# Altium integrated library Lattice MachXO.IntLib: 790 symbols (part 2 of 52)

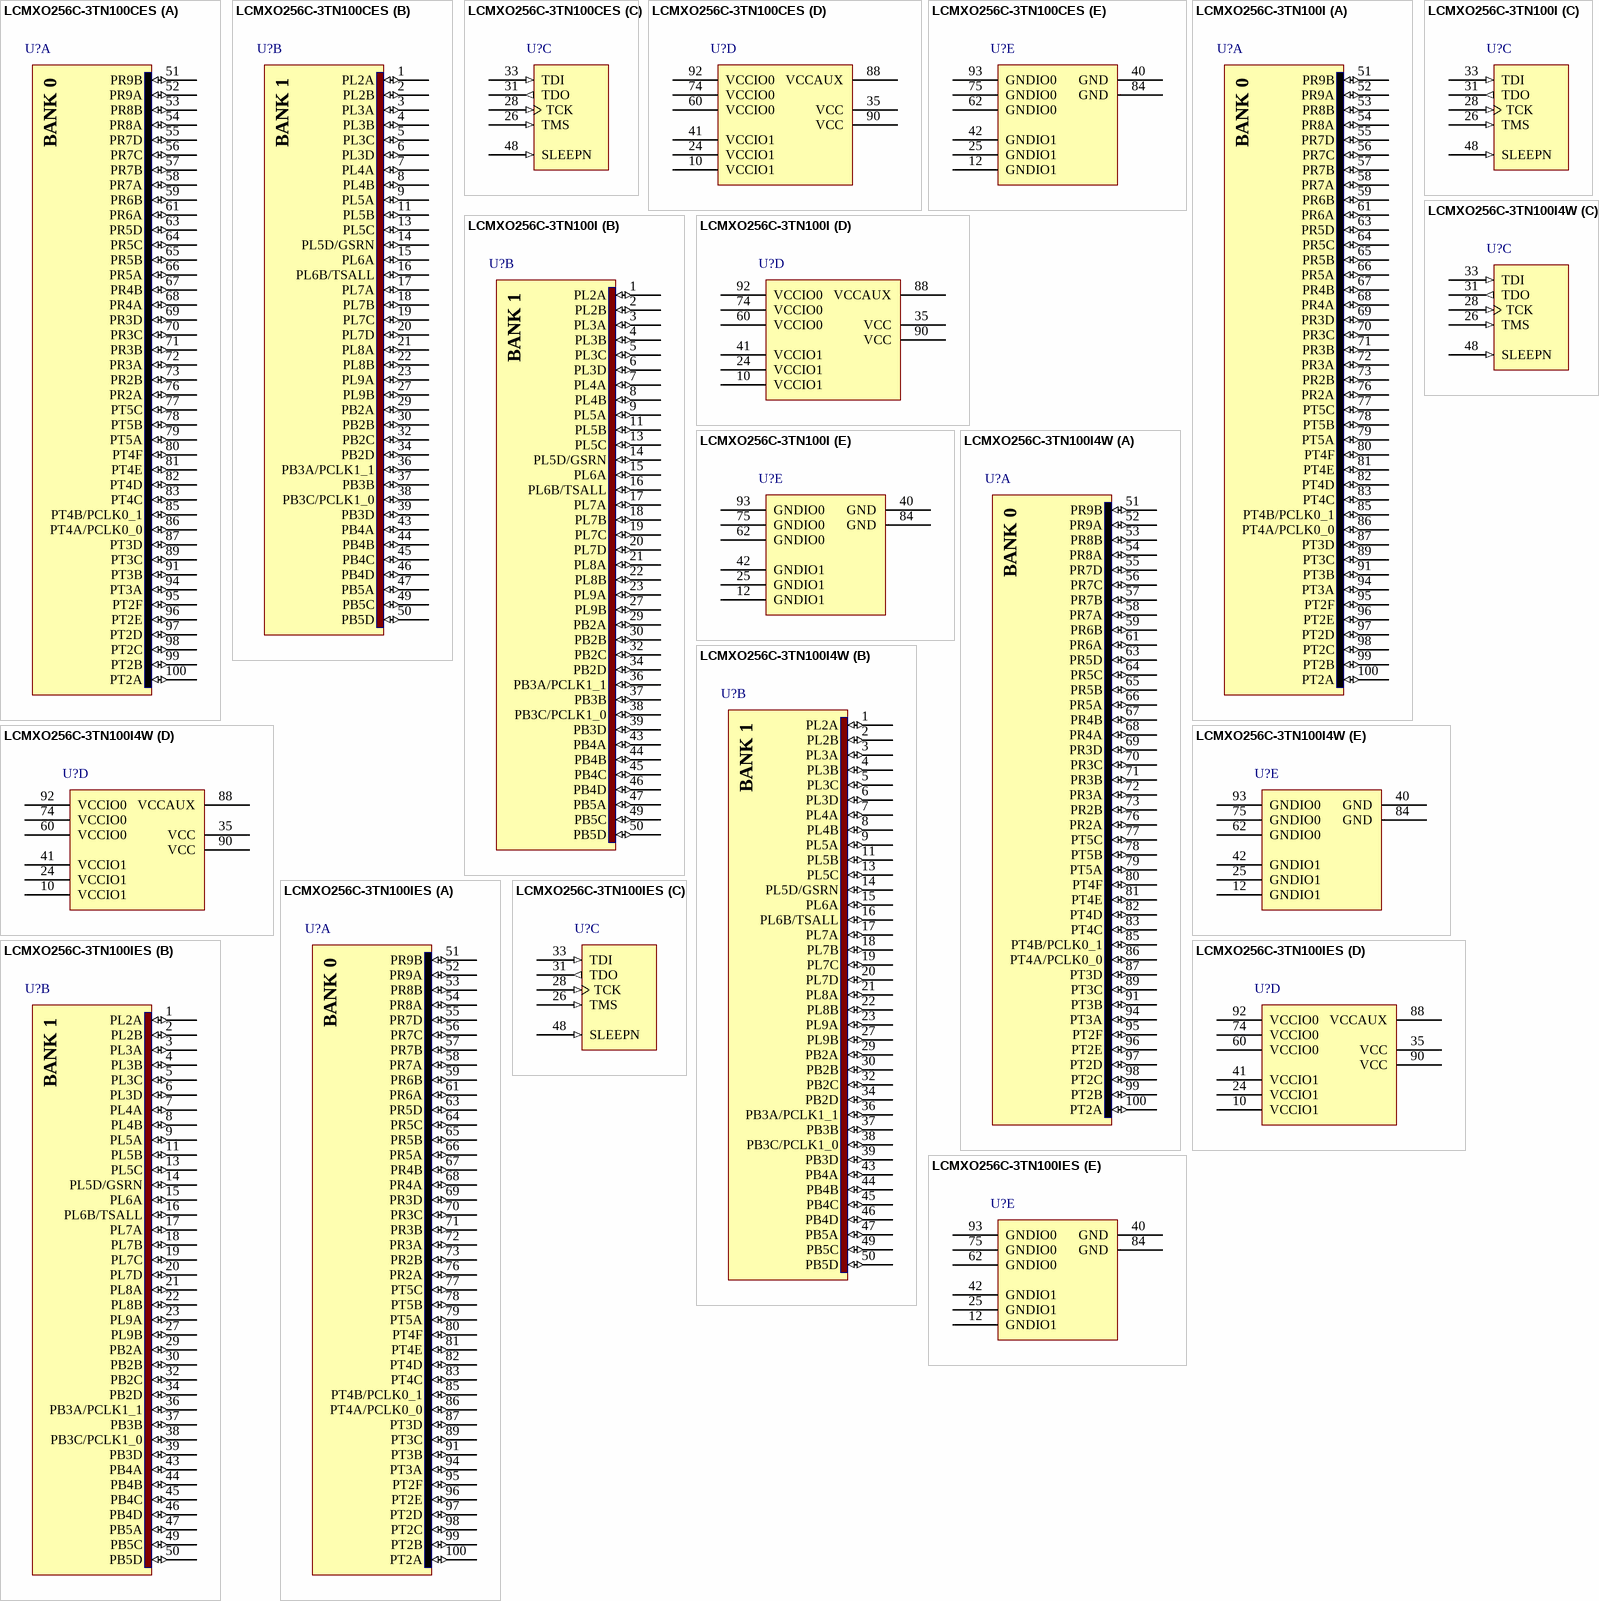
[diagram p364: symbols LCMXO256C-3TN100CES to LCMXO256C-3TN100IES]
## LCMXO256C-3TN100IES
designator U?
MachXO 256 Crossover PLD, 1.8V/2.5V/3.3V, 78 User I/Os, 100-Pins TQFP, Speed Grade-3, Industrial Grade, Pb-Free, Engineering Sample
footprint TQFP100_N (Thin QFP, 100-Leads, Body 14x14mm, Pitch 0.5mm, IPC Medium Density)
footprint TQFP100_L (Thin QFP, 100-Leads, Body 14x14mm, Pitch 0.5mm, IPC High Density)
footprint TQFP100_M (Thin QFP, 100-Leads, Body 14x14mm, Pitch 0.5mm, IPC Low Density)
3D model MachXO256-TQFP100 (100-Pin Thin Quad Flat Pack (TQFP100))
signal-integrity model LCMXO256C_T100 (MachXO)
part A pins: 51 PR9B (io), 52 PR9A (io), 53 PR8B (io), 54 PR8A (io), 55 PR7D (io), 56 PR7C (io), 57 PR7B (io), 58 PR7A (io), 59 PR6B (io), 61 PR6A (io), 63 PR5D (io), 64 PR5C (io), 65 PR5B (io), 66 PR5A (io), 67 PR4B (io), 68 PR4A (io), 69 PR3D (io), 70 PR3C (io), 71 PR3B (io), 72 PR3A (io), 73 PR2B (io), 76 PR2A (io), 77 PT5C (io), 78 PT5B (io), 79 PT5A (io), 80 PT4F (io), 81 PT4E (io), 82 PT4D (io), 83 PT4C (io), 85 PT4B/PCLK0_1 (io), 86 PT4A/PCLK0_0 (io), 87 PT3D (io), 89 PT3C (io), 91 PT3B (io), 94 PT3A (io), 95 PT2F (io), 96 PT2E (io), 97 PT2D (io), 98 PT2C (io), 99 PT2B (io), 100 PT2A (io)
part B pins: 1 PL2A (io), 2 PL2B (io), 3 PL3A (io), 4 PL3B (io), 5 PL3C (io), 6 PL3D (io), 7 PL4A (io), 8 PL4B (io), 9 PL5A (io), 11 PL5B (io), 13 PL5C (io), 14 PL5D/GSRN (io), 15 PL6A (io), 16 PL6B/TSALL (io), 17 PL7A (io), 18 PL7B (io), 19 PL7C (io), 20 PL7D (io), 21 PL8A (io), 22 PL8B (io), 23 PL9A (io), 27 PL9B (io), 29 PB2A (io), 30 PB2B (io), 32 PB2C (io), 34 PB2D (io), 36 PB3A/PCLK1_1 (io), 37 PB3B (io), 38 PB3C/PCLK1_0 (io), 39 PB3D (io), 43 PB4A (io), 44 PB4B (io), 45 PB4C (io), 46 PB4D (io), 47 PB5A (io), 49 PB5C (io), 50 PB5D (io)
part C pins: 26 TMS (in) "Powered by VCCIO1", 28 TCK (in) "Powered by VCCIO1", 31 TDO (out) "Powered by VCCIO1", 33 TDI (in) "Powered by VCCIO1", 48 SLEEPN (in) "Powered by VCCIO1"
part D pins: 10 VCCIO1 (power), 24 VCCIO1 (power), 35 VCC (power), 41 VCCIO1 (power), 60 VCCIO0 (power), 74 VCCIO0 (power), 88 VCCAUX (power), 90 VCC (power), 92 VCCIO0 (power)
part E pins: 12 GNDIO1 (power), 25 GNDIO1 (power), 40 GND (power), 42 GNDIO1 (power), 62 GNDIO0 (power), 75 GNDIO0 (power), 84 GND (power), 93 GNDIO0 (power)


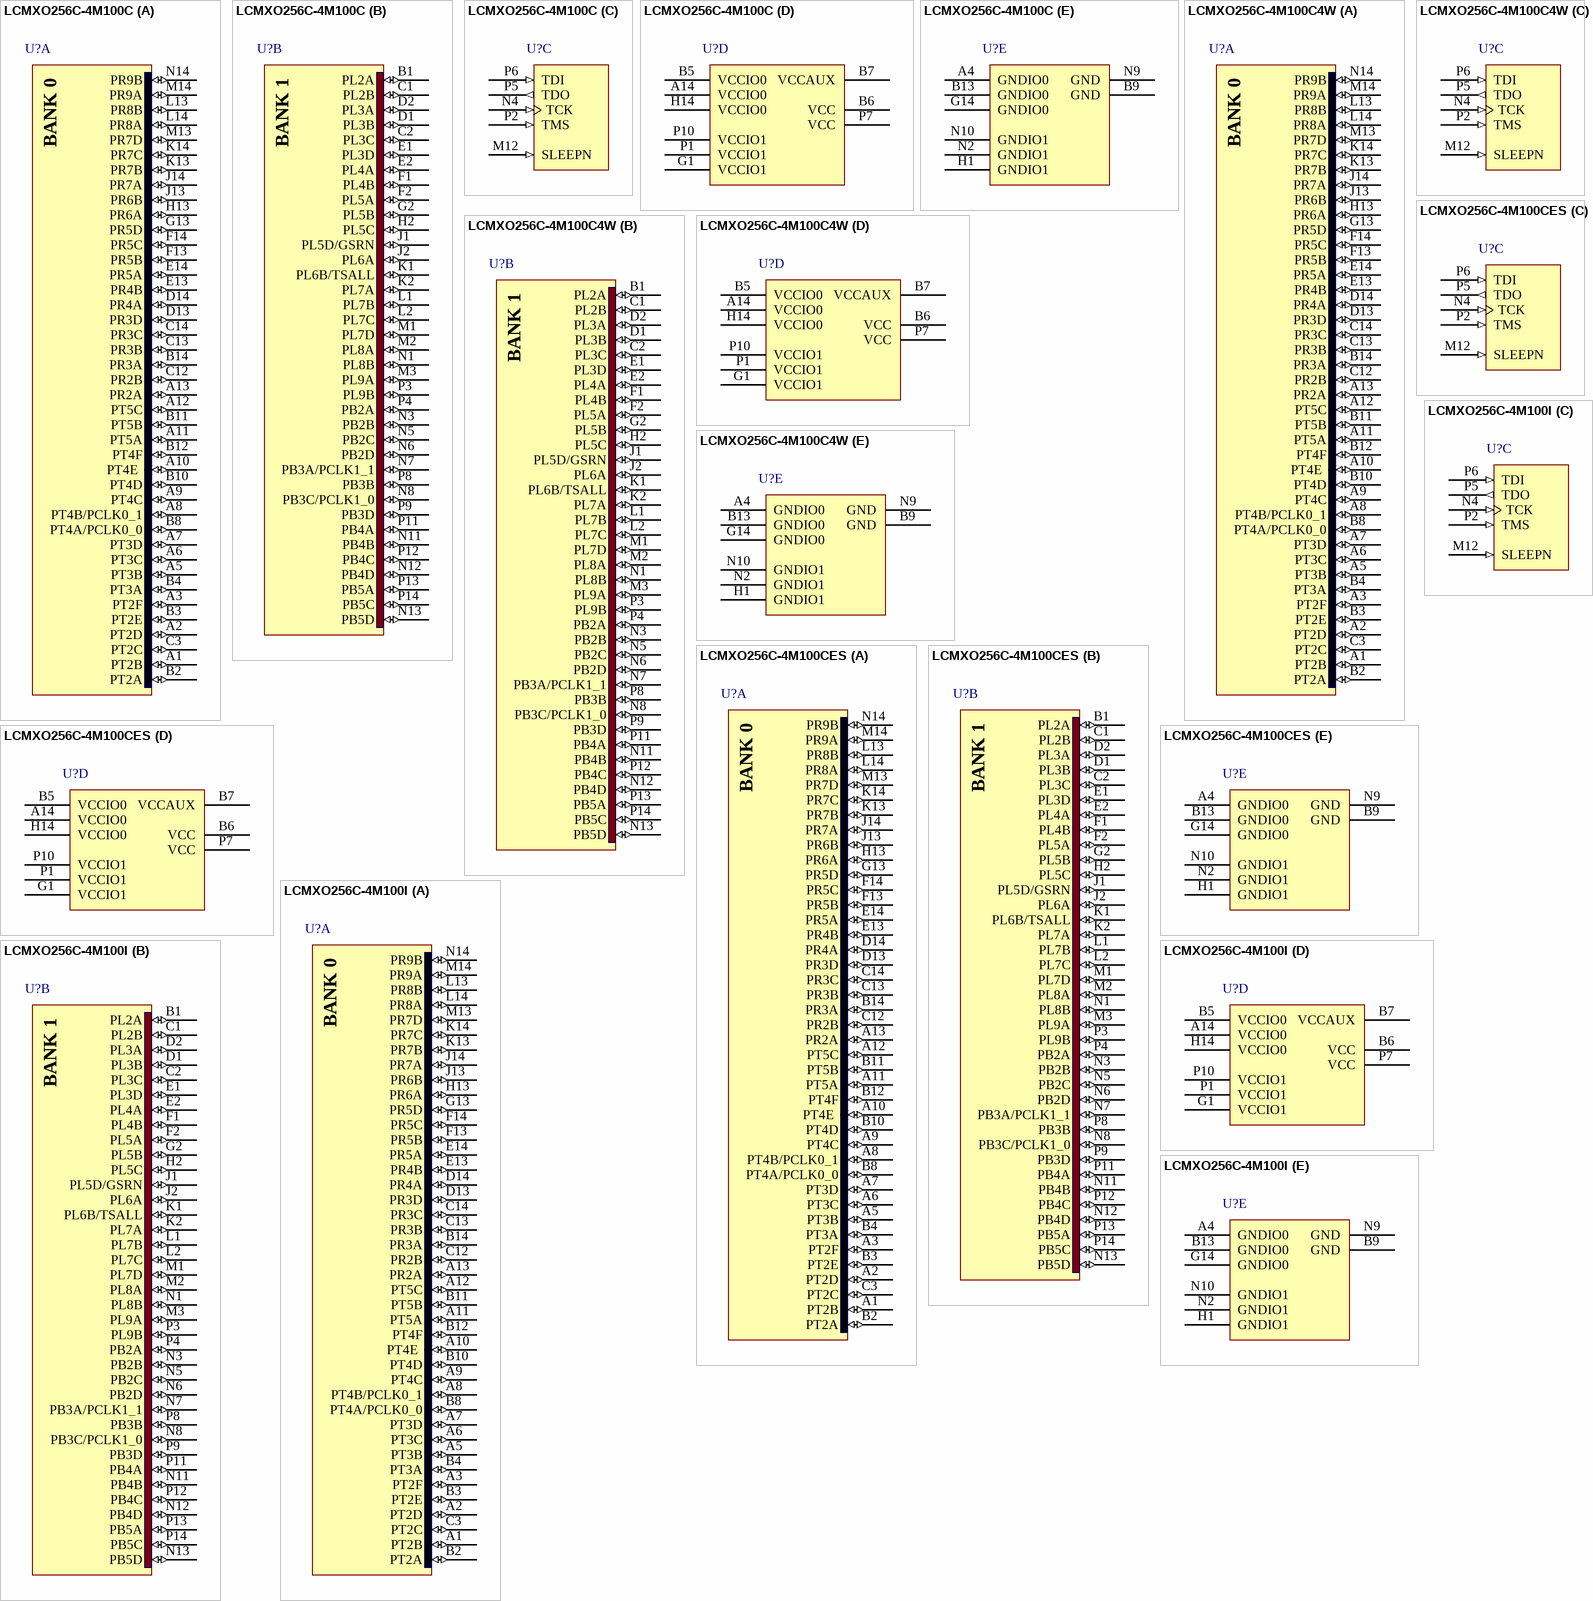
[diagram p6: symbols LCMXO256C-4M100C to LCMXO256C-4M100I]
## LCMXO256C-4M100C
designator U?
MachXO 256 Crossover PLD, 1.8V/2.5V/3.3V, 78 User I/Os, 100-Pins csBGA, Speed Grade-4, Commercial Grade
footprint csBGA100 (BGA, 100-Leads, Body 8x8mm, Pitch 0.5mm)
3D model MachXO256-csBGA100 (100-Ball Chip Scale Ball Grid Array (csBGA100))
signal-integrity model LCMXO256C_M100 (MachXO)
part A pins: A1 PT2B (io), A2 PT2D (io), A3 PT2F (io), A5 PT3B (io), A6 PT3C (io), A7 PT3D (io), A8 PT4B/PCLK0_1 (io), A9 PT4C (io), A10 PT4E (io), A11 PT5A (io), A12 PT5C (io), A13 PR2A (io), B2 PT2A (io), B3 PT2E (io), B4 PT3A (io), B8 PT4A/PCLK0_0 (io), B10 PT4D (io), B11 PT5B (io), B12 PT4F (io), B14 PR3A (io), C3 PT2C (io), C12 PR2B (io), C13 PR3B (io), C14 PR3C (io), D13 PR3D (io), D14 PR4A (io), E13 PR4B (io), E14 PR5A (io), F13 PR5B (io), F14 PR5C (io), G13 PR5D (io), H13 PR6A (io), J13 PR6B (io), J14 PR7A (io), K13 PR7B (io), K14 PR7C (io), L13 PR8B (io), L14 PR8A (io), M13 PR7D (io), M14 PR9A (io), N14 PR9B (io)
part B pins: B1 PL2A (io), C1 PL2B (io), C2 PL3C (io), D1 PL3B (io), D2 PL3A (io), E1 PL3D (io), E2 PL4A (io), F1 PL4B (io), F2 PL5A (io), G2 PL5B (io), H2 PL5C (io), J1 PL5D/GSRN (io), J2 PL6A (io), K1 PL6B/TSALL (io), K2 PL7A (io), L1 PL7B (io), L2 PL7C (io), M1 PL7D (io), M2 PL8A (io), M3 PL9A (io), N1 PL8B (io), N3 PB2B (io), N5 PB2C (io), N6 PB2D (io), N7 PB3A/PCLK1_1 (io), N8 PB3C/PCLK1_0 (io), N11 PB4B (io), N12 PB4D (io), N13 PB5D (io), P3 PL9B (io), P4 PB2A (io), P8 PB3B (io), P9 PB3D (io), P11 PB4A (io), P12 PB4C (io), P13 PB5A (io), P14 PB5C (io)
part C pins: M12 SLEEPN (in) "Powered by VCCIO1", N4 TCK (in) "Powered by VCCIO1", P2 TMS (in) "Powered by VCCIO1", P5 TDO (out) "Powered by VCCIO1", P6 TDI (in) "Powered by VCCIO1"
part D pins: A14 VCCIO0 (power), B5 VCCIO0 (power), B6 VCC (power), B7 VCCAUX (power), G1 VCCIO1 (power), H14 VCCIO0 (power), P1 VCCIO1 (power), P7 VCC (power), P10 VCCIO1 (power)
part E pins: A4 GNDIO0 (power), B9 GND (power), B13 GNDIO0 (power), G14 GNDIO0 (power), H1 GNDIO1 (power), N2 GNDIO1 (power), N9 GND (power), N10 GNDIO1 (power)

## LCMXO256C-4M100C4W
designator U?
MachXO 256 Crossover PLD, 1.8V/2.5V/3.3V, 78 User I/Os, 100-Pins csBGA, Speed Grade-4, Commercial Grade
footprint csBGA100 (BGA, 100-Leads, Body 8x8mm, Pitch 0.5mm)
3D model MachXO256-csBGA100 (100-Ball Chip Scale Ball Grid Array (csBGA100))
signal-integrity model LCMXO256C_M100 (MachXO)
part A pins: A1 PT2B (io), A2 PT2D (io), A3 PT2F (io), A5 PT3B (io), A6 PT3C (io), A7 PT3D (io), A8 PT4B/PCLK0_1 (io), A9 PT4C (io), A10 PT4E (io), A11 PT5A (io), A12 PT5C (io), A13 PR2A (io), B2 PT2A (io), B3 PT2E (io), B4 PT3A (io), B8 PT4A/PCLK0_0 (io), B10 PT4D (io), B11 PT5B (io), B12 PT4F (io), B14 PR3A (io), C3 PT2C (io), C12 PR2B (io), C13 PR3B (io), C14 PR3C (io), D13 PR3D (io), D14 PR4A (io), E13 PR4B (io), E14 PR5A (io), F13 PR5B (io), F14 PR5C (io), G13 PR5D (io), H13 PR6A (io), J13 PR6B (io), J14 PR7A (io), K13 PR7B (io), K14 PR7C (io), L13 PR8B (io), L14 PR8A (io), M13 PR7D (io), M14 PR9A (io), N14 PR9B (io)
part B pins: B1 PL2A (io), C1 PL2B (io), C2 PL3C (io), D1 PL3B (io), D2 PL3A (io), E1 PL3D (io), E2 PL4A (io), F1 PL4B (io), F2 PL5A (io), G2 PL5B (io), H2 PL5C (io), J1 PL5D/GSRN (io), J2 PL6A (io), K1 PL6B/TSALL (io), K2 PL7A (io), L1 PL7B (io), L2 PL7C (io), M1 PL7D (io), M2 PL8A (io), M3 PL9A (io), N1 PL8B (io), N3 PB2B (io), N5 PB2C (io), N6 PB2D (io), N7 PB3A/PCLK1_1 (io), N8 PB3C/PCLK1_0 (io), N11 PB4B (io), N12 PB4D (io), N13 PB5D (io), P3 PL9B (io), P4 PB2A (io), P8 PB3B (io), P9 PB3D (io), P11 PB4A (io), P12 PB4C (io), P13 PB5A (io), P14 PB5C (io)
part C pins: M12 SLEEPN (in) "Powered by VCCIO1", N4 TCK (in) "Powered by VCCIO1", P2 TMS (in) "Powered by VCCIO1", P5 TDO (out) "Powered by VCCIO1", P6 TDI (in) "Powered by VCCIO1"
part D pins: A14 VCCIO0 (power), B5 VCCIO0 (power), B6 VCC (power), B7 VCCAUX (power), G1 VCCIO1 (power), H14 VCCIO0 (power), P1 VCCIO1 (power), P7 VCC (power), P10 VCCIO1 (power)
part E pins: A4 GNDIO0 (power), B9 GND (power), B13 GNDIO0 (power), G14 GNDIO0 (power), H1 GNDIO1 (power), N2 GNDIO1 (power), N9 GND (power), N10 GNDIO1 (power)

## LCMXO256C-4M100CES
designator U?
MachXO 256 Crossover PLD, 1.8V/2.5V/3.3V, 78 User I/Os, 100-Pins csBGA, Speed Grade-4, Commercial Grade, Engineering Sample
footprint csBGA100 (BGA, 100-Leads, Body 8x8mm, Pitch 0.5mm)
3D model MachXO256-csBGA100 (100-Ball Chip Scale Ball Grid Array (csBGA100))
signal-integrity model LCMXO256C_M100 (MachXO)
part A pins: A1 PT2B (io), A2 PT2D (io), A3 PT2F (io), A5 PT3B (io), A6 PT3C (io), A7 PT3D (io), A8 PT4B/PCLK0_1 (io), A9 PT4C (io), A10 PT4E (io), A11 PT5A (io), A12 PT5C (io), A13 PR2A (io), B2 PT2A (io), B3 PT2E (io), B4 PT3A (io), B8 PT4A/PCLK0_0 (io), B10 PT4D (io), B11 PT5B (io), B12 PT4F (io), B14 PR3A (io), C3 PT2C (io), C12 PR2B (io), C13 PR3B (io), C14 PR3C (io), D13 PR3D (io), D14 PR4A (io), E13 PR4B (io), E14 PR5A (io), F13 PR5B (io), F14 PR5C (io), G13 PR5D (io), H13 PR6A (io), J13 PR6B (io), J14 PR7A (io), K13 PR7B (io), K14 PR7C (io), L13 PR8B (io), L14 PR8A (io), M13 PR7D (io), M14 PR9A (io), N14 PR9B (io)
part B pins: B1 PL2A (io), C1 PL2B (io), C2 PL3C (io), D1 PL3B (io), D2 PL3A (io), E1 PL3D (io), E2 PL4A (io), F1 PL4B (io), F2 PL5A (io), G2 PL5B (io), H2 PL5C (io), J1 PL5D/GSRN (io), J2 PL6A (io), K1 PL6B/TSALL (io), K2 PL7A (io), L1 PL7B (io), L2 PL7C (io), M1 PL7D (io), M2 PL8A (io), M3 PL9A (io), N1 PL8B (io), N3 PB2B (io), N5 PB2C (io), N6 PB2D (io), N7 PB3A/PCLK1_1 (io), N8 PB3C/PCLK1_0 (io), N11 PB4B (io), N12 PB4D (io), N13 PB5D (io), P3 PL9B (io), P4 PB2A (io), P8 PB3B (io), P9 PB3D (io), P11 PB4A (io), P12 PB4C (io), P13 PB5A (io), P14 PB5C (io)
part C pins: M12 SLEEPN (in) "Powered by VCCIO1", N4 TCK (in) "Powered by VCCIO1", P2 TMS (in) "Powered by VCCIO1", P5 TDO (out) "Powered by VCCIO1", P6 TDI (in) "Powered by VCCIO1"
part D pins: A14 VCCIO0 (power), B5 VCCIO0 (power), B6 VCC (power), B7 VCCAUX (power), G1 VCCIO1 (power), H14 VCCIO0 (power), P1 VCCIO1 (power), P7 VCC (power), P10 VCCIO1 (power)
part E pins: A4 GNDIO0 (power), B9 GND (power), B13 GNDIO0 (power), G14 GNDIO0 (power), H1 GNDIO1 (power), N2 GNDIO1 (power), N9 GND (power), N10 GNDIO1 (power)

## LCMXO256C-4M100I
designator U?
MachXO 256 Crossover PLD, 1.8V/2.5V/3.3V, 78 User I/Os, 100-Pins csBGA, Speed Grade-4, Industrial Grade
footprint csBGA100 (BGA, 100-Leads, Body 8x8mm, Pitch 0.5mm)
3D model MachXO256-csBGA100 (100-Ball Chip Scale Ball Grid Array (csBGA100))
signal-integrity model LCMXO256C_M100 (MachXO)
part A pins: A1 PT2B (io), A2 PT2D (io), A3 PT2F (io), A5 PT3B (io), A6 PT3C (io), A7 PT3D (io), A8 PT4B/PCLK0_1 (io), A9 PT4C (io), A10 PT4E (io), A11 PT5A (io), A12 PT5C (io), A13 PR2A (io), B2 PT2A (io), B3 PT2E (io), B4 PT3A (io), B8 PT4A/PCLK0_0 (io), B10 PT4D (io), B11 PT5B (io), B12 PT4F (io), B14 PR3A (io), C3 PT2C (io), C12 PR2B (io), C13 PR3B (io), C14 PR3C (io), D13 PR3D (io), D14 PR4A (io), E13 PR4B (io), E14 PR5A (io), F13 PR5B (io), F14 PR5C (io), G13 PR5D (io), H13 PR6A (io), J13 PR6B (io), J14 PR7A (io), K13 PR7B (io), K14 PR7C (io), L13 PR8B (io), L14 PR8A (io), M13 PR7D (io), M14 PR9A (io), N14 PR9B (io)
part B pins: B1 PL2A (io), C1 PL2B (io), C2 PL3C (io), D1 PL3B (io), D2 PL3A (io), E1 PL3D (io), E2 PL4A (io), F1 PL4B (io), F2 PL5A (io), G2 PL5B (io), H2 PL5C (io), J1 PL5D/GSRN (io), J2 PL6A (io), K1 PL6B/TSALL (io), K2 PL7A (io), L1 PL7B (io), L2 PL7C (io), M1 PL7D (io), M2 PL8A (io), M3 PL9A (io), N1 PL8B (io), N3 PB2B (io), N5 PB2C (io), N6 PB2D (io), N7 PB3A/PCLK1_1 (io), N8 PB3C/PCLK1_0 (io), N11 PB4B (io), N12 PB4D (io), N13 PB5D (io), P3 PL9B (io), P4 PB2A (io), P8 PB3B (io), P9 PB3D (io), P11 PB4A (io), P12 PB4C (io), P13 PB5A (io), P14 PB5C (io)
part C pins: M12 SLEEPN (in) "Powered by VCCIO1", N4 TCK (in) "Powered by VCCIO1", P2 TMS (in) "Powered by VCCIO1", P5 TDO (out) "Powered by VCCIO1", P6 TDI (in) "Powered by VCCIO1"
part D pins: A14 VCCIO0 (power), B5 VCCIO0 (power), B6 VCC (power), B7 VCCAUX (power), G1 VCCIO1 (power), H14 VCCIO0 (power), P1 VCCIO1 (power), P7 VCC (power), P10 VCCIO1 (power)
part E pins: A4 GNDIO0 (power), B9 GND (power), B13 GNDIO0 (power), G14 GNDIO0 (power), H1 GNDIO1 (power), N2 GNDIO1 (power), N9 GND (power), N10 GNDIO1 (power)


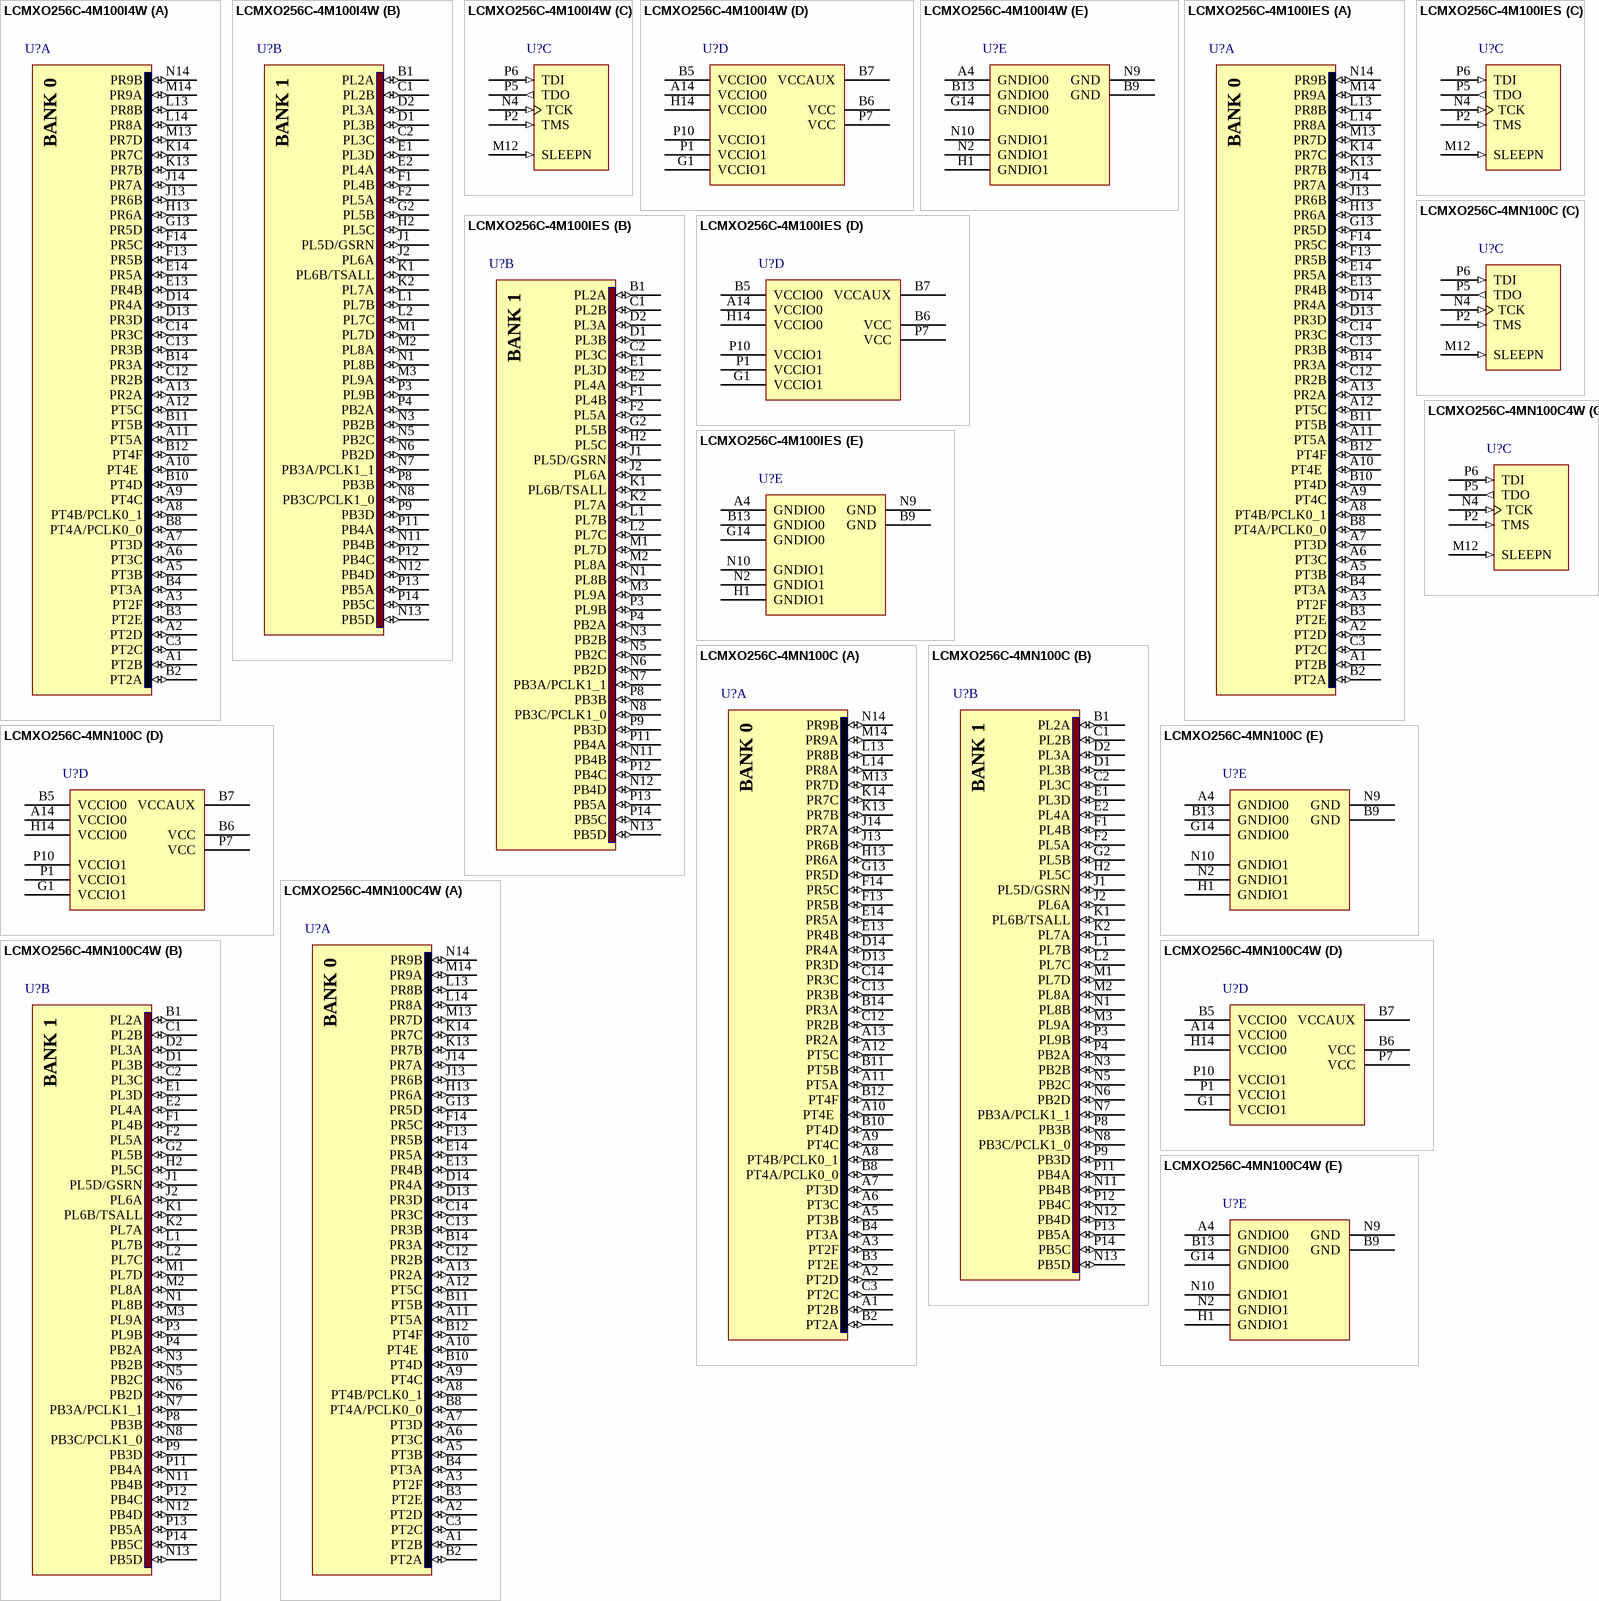
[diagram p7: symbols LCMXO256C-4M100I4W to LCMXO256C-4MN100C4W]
## LCMXO256C-4M100I4W
designator U?
MachXO 256 Crossover PLD, 1.8V/2.5V/3.3V, 78 User I/Os, 100-Pins csBGA, Speed Grade-4, Industrial Grade
footprint csBGA100 (BGA, 100-Leads, Body 8x8mm, Pitch 0.5mm)
3D model MachXO256-csBGA100 (100-Ball Chip Scale Ball Grid Array (csBGA100))
signal-integrity model LCMXO256C_M100 (MachXO)
part A pins: A1 PT2B (io), A2 PT2D (io), A3 PT2F (io), A5 PT3B (io), A6 PT3C (io), A7 PT3D (io), A8 PT4B/PCLK0_1 (io), A9 PT4C (io), A10 PT4E (io), A11 PT5A (io), A12 PT5C (io), A13 PR2A (io), B2 PT2A (io), B3 PT2E (io), B4 PT3A (io), B8 PT4A/PCLK0_0 (io), B10 PT4D (io), B11 PT5B (io), B12 PT4F (io), B14 PR3A (io), C3 PT2C (io), C12 PR2B (io), C13 PR3B (io), C14 PR3C (io), D13 PR3D (io), D14 PR4A (io), E13 PR4B (io), E14 PR5A (io), F13 PR5B (io), F14 PR5C (io), G13 PR5D (io), H13 PR6A (io), J13 PR6B (io), J14 PR7A (io), K13 PR7B (io), K14 PR7C (io), L13 PR8B (io), L14 PR8A (io), M13 PR7D (io), M14 PR9A (io), N14 PR9B (io)
part B pins: B1 PL2A (io), C1 PL2B (io), C2 PL3C (io), D1 PL3B (io), D2 PL3A (io), E1 PL3D (io), E2 PL4A (io), F1 PL4B (io), F2 PL5A (io), G2 PL5B (io), H2 PL5C (io), J1 PL5D/GSRN (io), J2 PL6A (io), K1 PL6B/TSALL (io), K2 PL7A (io), L1 PL7B (io), L2 PL7C (io), M1 PL7D (io), M2 PL8A (io), M3 PL9A (io), N1 PL8B (io), N3 PB2B (io), N5 PB2C (io), N6 PB2D (io), N7 PB3A/PCLK1_1 (io), N8 PB3C/PCLK1_0 (io), N11 PB4B (io), N12 PB4D (io), N13 PB5D (io), P3 PL9B (io), P4 PB2A (io), P8 PB3B (io), P9 PB3D (io), P11 PB4A (io), P12 PB4C (io), P13 PB5A (io), P14 PB5C (io)
part C pins: M12 SLEEPN (in) "Powered by VCCIO1", N4 TCK (in) "Powered by VCCIO1", P2 TMS (in) "Powered by VCCIO1", P5 TDO (out) "Powered by VCCIO1", P6 TDI (in) "Powered by VCCIO1"
part D pins: A14 VCCIO0 (power), B5 VCCIO0 (power), B6 VCC (power), B7 VCCAUX (power), G1 VCCIO1 (power), H14 VCCIO0 (power), P1 VCCIO1 (power), P7 VCC (power), P10 VCCIO1 (power)
part E pins: A4 GNDIO0 (power), B9 GND (power), B13 GNDIO0 (power), G14 GNDIO0 (power), H1 GNDIO1 (power), N2 GNDIO1 (power), N9 GND (power), N10 GNDIO1 (power)

## LCMXO256C-4M100IES
designator U?
MachXO 256 Crossover PLD, 1.8V/2.5V/3.3V, 78 User I/Os, 100-Pins csBGA, Speed Grade-4, Industrial Grade, Engineering Sample
footprint csBGA100 (BGA, 100-Leads, Body 8x8mm, Pitch 0.5mm)
3D model MachXO256-csBGA100 (100-Ball Chip Scale Ball Grid Array (csBGA100))
signal-integrity model LCMXO256C_M100 (MachXO)
part A pins: A1 PT2B (io), A2 PT2D (io), A3 PT2F (io), A5 PT3B (io), A6 PT3C (io), A7 PT3D (io), A8 PT4B/PCLK0_1 (io), A9 PT4C (io), A10 PT4E (io), A11 PT5A (io), A12 PT5C (io), A13 PR2A (io), B2 PT2A (io), B3 PT2E (io), B4 PT3A (io), B8 PT4A/PCLK0_0 (io), B10 PT4D (io), B11 PT5B (io), B12 PT4F (io), B14 PR3A (io), C3 PT2C (io), C12 PR2B (io), C13 PR3B (io), C14 PR3C (io), D13 PR3D (io), D14 PR4A (io), E13 PR4B (io), E14 PR5A (io), F13 PR5B (io), F14 PR5C (io), G13 PR5D (io), H13 PR6A (io), J13 PR6B (io), J14 PR7A (io), K13 PR7B (io), K14 PR7C (io), L13 PR8B (io), L14 PR8A (io), M13 PR7D (io), M14 PR9A (io), N14 PR9B (io)
part B pins: B1 PL2A (io), C1 PL2B (io), C2 PL3C (io), D1 PL3B (io), D2 PL3A (io), E1 PL3D (io), E2 PL4A (io), F1 PL4B (io), F2 PL5A (io), G2 PL5B (io), H2 PL5C (io), J1 PL5D/GSRN (io), J2 PL6A (io), K1 PL6B/TSALL (io), K2 PL7A (io), L1 PL7B (io), L2 PL7C (io), M1 PL7D (io), M2 PL8A (io), M3 PL9A (io), N1 PL8B (io), N3 PB2B (io), N5 PB2C (io), N6 PB2D (io), N7 PB3A/PCLK1_1 (io), N8 PB3C/PCLK1_0 (io), N11 PB4B (io), N12 PB4D (io), N13 PB5D (io), P3 PL9B (io), P4 PB2A (io), P8 PB3B (io), P9 PB3D (io), P11 PB4A (io), P12 PB4C (io), P13 PB5A (io), P14 PB5C (io)
part C pins: M12 SLEEPN (in) "Powered by VCCIO1", N4 TCK (in) "Powered by VCCIO1", P2 TMS (in) "Powered by VCCIO1", P5 TDO (out) "Powered by VCCIO1", P6 TDI (in) "Powered by VCCIO1"
part D pins: A14 VCCIO0 (power), B5 VCCIO0 (power), B6 VCC (power), B7 VCCAUX (power), G1 VCCIO1 (power), H14 VCCIO0 (power), P1 VCCIO1 (power), P7 VCC (power), P10 VCCIO1 (power)
part E pins: A4 GNDIO0 (power), B9 GND (power), B13 GNDIO0 (power), G14 GNDIO0 (power), H1 GNDIO1 (power), N2 GNDIO1 (power), N9 GND (power), N10 GNDIO1 (power)

## LCMXO256C-4MN100C
designator U?
MachXO 256 Crossover PLD, 1.8V/2.5V/3.3V, 78 User I/Os, 100-Pins csBGA, Speed Grade-4, Commercial Grade, Pb-Free
footprint csBGA100 (BGA, 100-Leads, Body 8x8mm, Pitch 0.5mm)
3D model MachXO256-csBGA100 (100-Ball Chip Scale Ball Grid Array (csBGA100))
signal-integrity model LCMXO256C_M100 (MachXO)
part A pins: A1 PT2B (io), A2 PT2D (io), A3 PT2F (io), A5 PT3B (io), A6 PT3C (io), A7 PT3D (io), A8 PT4B/PCLK0_1 (io), A9 PT4C (io), A10 PT4E (io), A11 PT5A (io), A12 PT5C (io), A13 PR2A (io), B2 PT2A (io), B3 PT2E (io), B4 PT3A (io), B8 PT4A/PCLK0_0 (io), B10 PT4D (io), B11 PT5B (io), B12 PT4F (io), B14 PR3A (io), C3 PT2C (io), C12 PR2B (io), C13 PR3B (io), C14 PR3C (io), D13 PR3D (io), D14 PR4A (io), E13 PR4B (io), E14 PR5A (io), F13 PR5B (io), F14 PR5C (io), G13 PR5D (io), H13 PR6A (io), J13 PR6B (io), J14 PR7A (io), K13 PR7B (io), K14 PR7C (io), L13 PR8B (io), L14 PR8A (io), M13 PR7D (io), M14 PR9A (io), N14 PR9B (io)
part B pins: B1 PL2A (io), C1 PL2B (io), C2 PL3C (io), D1 PL3B (io), D2 PL3A (io), E1 PL3D (io), E2 PL4A (io), F1 PL4B (io), F2 PL5A (io), G2 PL5B (io), H2 PL5C (io), J1 PL5D/GSRN (io), J2 PL6A (io), K1 PL6B/TSALL (io), K2 PL7A (io), L1 PL7B (io), L2 PL7C (io), M1 PL7D (io), M2 PL8A (io), M3 PL9A (io), N1 PL8B (io), N3 PB2B (io), N5 PB2C (io), N6 PB2D (io), N7 PB3A/PCLK1_1 (io), N8 PB3C/PCLK1_0 (io), N11 PB4B (io), N12 PB4D (io), N13 PB5D (io), P3 PL9B (io), P4 PB2A (io), P8 PB3B (io), P9 PB3D (io), P11 PB4A (io), P12 PB4C (io), P13 PB5A (io), P14 PB5C (io)
part C pins: M12 SLEEPN (in) "Powered by VCCIO1", N4 TCK (in) "Powered by VCCIO1", P2 TMS (in) "Powered by VCCIO1", P5 TDO (out) "Powered by VCCIO1", P6 TDI (in) "Powered by VCCIO1"
part D pins: A14 VCCIO0 (power), B5 VCCIO0 (power), B6 VCC (power), B7 VCCAUX (power), G1 VCCIO1 (power), H14 VCCIO0 (power), P1 VCCIO1 (power), P7 VCC (power), P10 VCCIO1 (power)
part E pins: A4 GNDIO0 (power), B9 GND (power), B13 GNDIO0 (power), G14 GNDIO0 (power), H1 GNDIO1 (power), N2 GNDIO1 (power), N9 GND (power), N10 GNDIO1 (power)

## LCMXO256C-4MN100C4W
designator U?
MachXO 256 Crossover PLD, 1.8V/2.5V/3.3V, 78 User I/Os, 100-Pins csBGA, Speed Grade-4, Commercial Grade, Pb-Free
footprint csBGA100 (BGA, 100-Leads, Body 8x8mm, Pitch 0.5mm)
3D model MachXO256-csBGA100 (100-Ball Chip Scale Ball Grid Array (csBGA100))
signal-integrity model LCMXO256C_M100 (MachXO)
part A pins: A1 PT2B (io), A2 PT2D (io), A3 PT2F (io), A5 PT3B (io), A6 PT3C (io), A7 PT3D (io), A8 PT4B/PCLK0_1 (io), A9 PT4C (io), A10 PT4E (io), A11 PT5A (io), A12 PT5C (io), A13 PR2A (io), B2 PT2A (io), B3 PT2E (io), B4 PT3A (io), B8 PT4A/PCLK0_0 (io), B10 PT4D (io), B11 PT5B (io), B12 PT4F (io), B14 PR3A (io), C3 PT2C (io), C12 PR2B (io), C13 PR3B (io), C14 PR3C (io), D13 PR3D (io), D14 PR4A (io), E13 PR4B (io), E14 PR5A (io), F13 PR5B (io), F14 PR5C (io), G13 PR5D (io), H13 PR6A (io), J13 PR6B (io), J14 PR7A (io), K13 PR7B (io), K14 PR7C (io), L13 PR8B (io), L14 PR8A (io), M13 PR7D (io), M14 PR9A (io), N14 PR9B (io)
part B pins: B1 PL2A (io), C1 PL2B (io), C2 PL3C (io), D1 PL3B (io), D2 PL3A (io), E1 PL3D (io), E2 PL4A (io), F1 PL4B (io), F2 PL5A (io), G2 PL5B (io), H2 PL5C (io), J1 PL5D/GSRN (io), J2 PL6A (io), K1 PL6B/TSALL (io), K2 PL7A (io), L1 PL7B (io), L2 PL7C (io), M1 PL7D (io), M2 PL8A (io), M3 PL9A (io), N1 PL8B (io), N3 PB2B (io), N5 PB2C (io), N6 PB2D (io), N7 PB3A/PCLK1_1 (io), N8 PB3C/PCLK1_0 (io), N11 PB4B (io), N12 PB4D (io), N13 PB5D (io), P3 PL9B (io), P4 PB2A (io), P8 PB3B (io), P9 PB3D (io), P11 PB4A (io), P12 PB4C (io), P13 PB5A (io), P14 PB5C (io)
part C pins: M12 SLEEPN (in) "Powered by VCCIO1", N4 TCK (in) "Powered by VCCIO1", P2 TMS (in) "Powered by VCCIO1", P5 TDO (out) "Powered by VCCIO1", P6 TDI (in) "Powered by VCCIO1"
part D pins: A14 VCCIO0 (power), B5 VCCIO0 (power), B6 VCC (power), B7 VCCAUX (power), G1 VCCIO1 (power), H14 VCCIO0 (power), P1 VCCIO1 (power), P7 VCC (power), P10 VCCIO1 (power)
part E pins: A4 GNDIO0 (power), B9 GND (power), B13 GNDIO0 (power), G14 GNDIO0 (power), H1 GNDIO1 (power), N2 GNDIO1 (power), N9 GND (power), N10 GNDIO1 (power)


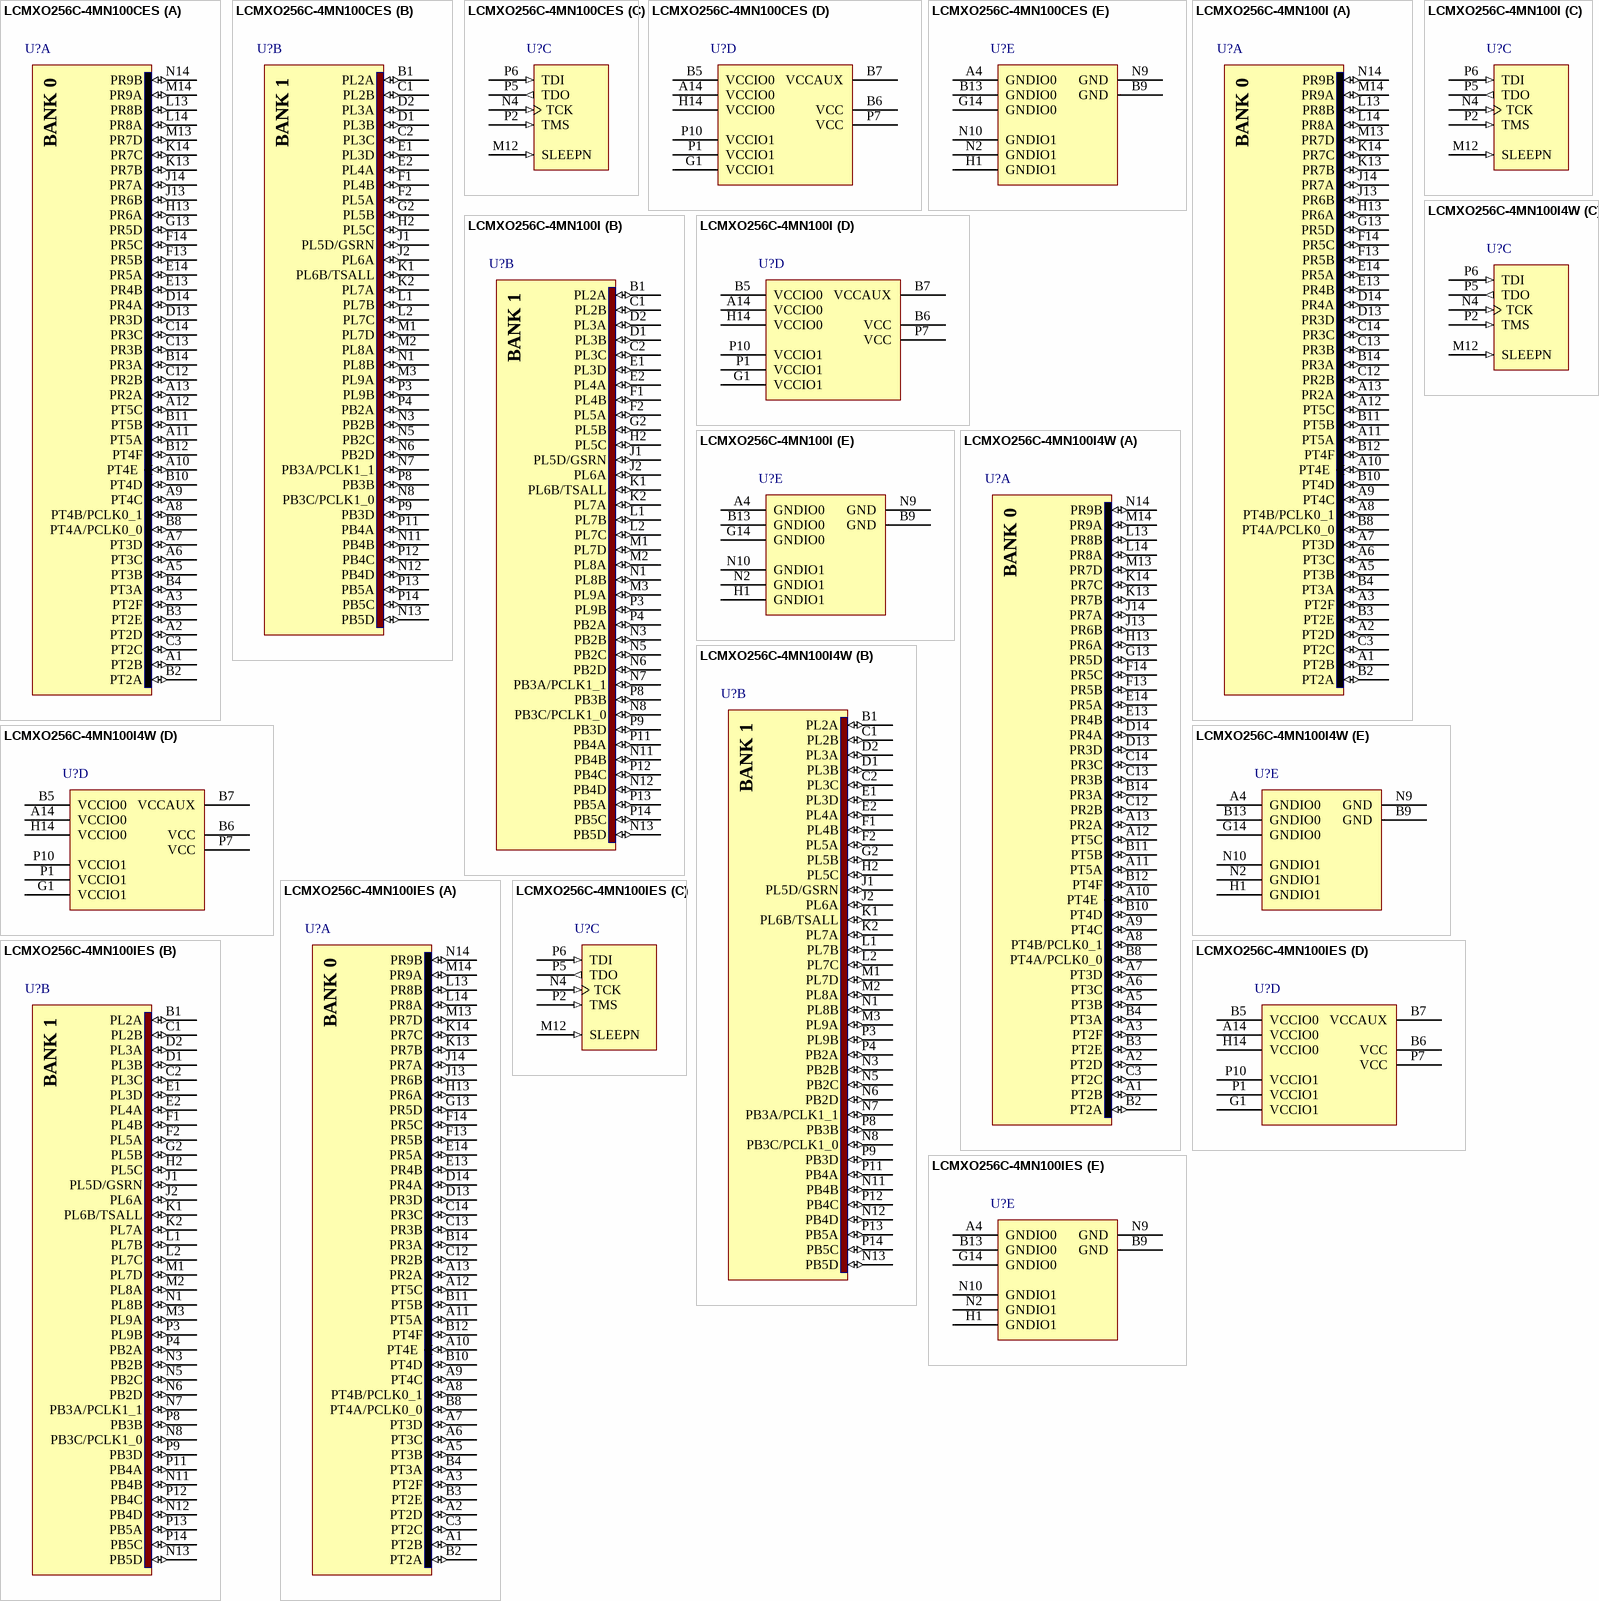
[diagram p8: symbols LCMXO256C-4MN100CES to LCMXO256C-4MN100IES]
## LCMXO256C-4MN100CES
designator U?
MachXO 256 Crossover PLD, 1.8V/2.5V/3.3V, 78 User I/Os, 100-Pins csBGA, Speed Grade-4, Commercial Grade, Pb-Free, Engineering Sample
footprint csBGA100 (BGA, 100-Leads, Body 8x8mm, Pitch 0.5mm)
3D model MachXO256-csBGA100 (100-Ball Chip Scale Ball Grid Array (csBGA100))
signal-integrity model LCMXO256C_M100 (MachXO)
part A pins: A1 PT2B (io), A2 PT2D (io), A3 PT2F (io), A5 PT3B (io), A6 PT3C (io), A7 PT3D (io), A8 PT4B/PCLK0_1 (io), A9 PT4C (io), A10 PT4E (io), A11 PT5A (io), A12 PT5C (io), A13 PR2A (io), B2 PT2A (io), B3 PT2E (io), B4 PT3A (io), B8 PT4A/PCLK0_0 (io), B10 PT4D (io), B11 PT5B (io), B12 PT4F (io), B14 PR3A (io), C3 PT2C (io), C12 PR2B (io), C13 PR3B (io), C14 PR3C (io), D13 PR3D (io), D14 PR4A (io), E13 PR4B (io), E14 PR5A (io), F13 PR5B (io), F14 PR5C (io), G13 PR5D (io), H13 PR6A (io), J13 PR6B (io), J14 PR7A (io), K13 PR7B (io), K14 PR7C (io), L13 PR8B (io), L14 PR8A (io), M13 PR7D (io), M14 PR9A (io), N14 PR9B (io)
part B pins: B1 PL2A (io), C1 PL2B (io), C2 PL3C (io), D1 PL3B (io), D2 PL3A (io), E1 PL3D (io), E2 PL4A (io), F1 PL4B (io), F2 PL5A (io), G2 PL5B (io), H2 PL5C (io), J1 PL5D/GSRN (io), J2 PL6A (io), K1 PL6B/TSALL (io), K2 PL7A (io), L1 PL7B (io), L2 PL7C (io), M1 PL7D (io), M2 PL8A (io), M3 PL9A (io), N1 PL8B (io), N3 PB2B (io), N5 PB2C (io), N6 PB2D (io), N7 PB3A/PCLK1_1 (io), N8 PB3C/PCLK1_0 (io), N11 PB4B (io), N12 PB4D (io), N13 PB5D (io), P3 PL9B (io), P4 PB2A (io), P8 PB3B (io), P9 PB3D (io), P11 PB4A (io), P12 PB4C (io), P13 PB5A (io), P14 PB5C (io)
part C pins: M12 SLEEPN (in) "Powered by VCCIO1", N4 TCK (in) "Powered by VCCIO1", P2 TMS (in) "Powered by VCCIO1", P5 TDO (out) "Powered by VCCIO1", P6 TDI (in) "Powered by VCCIO1"
part D pins: A14 VCCIO0 (power), B5 VCCIO0 (power), B6 VCC (power), B7 VCCAUX (power), G1 VCCIO1 (power), H14 VCCIO0 (power), P1 VCCIO1 (power), P7 VCC (power), P10 VCCIO1 (power)
part E pins: A4 GNDIO0 (power), B9 GND (power), B13 GNDIO0 (power), G14 GNDIO0 (power), H1 GNDIO1 (power), N2 GNDIO1 (power), N9 GND (power), N10 GNDIO1 (power)

## LCMXO256C-4MN100I
designator U?
MachXO 256 Crossover PLD, 1.8V/2.5V/3.3V, 78 User I/Os, 100-Pins csBGA, Speed Grade-4, Industrial Grade, Pb-Free
footprint csBGA100 (BGA, 100-Leads, Body 8x8mm, Pitch 0.5mm)
3D model MachXO256-csBGA100 (100-Ball Chip Scale Ball Grid Array (csBGA100))
signal-integrity model LCMXO256C_M100 (MachXO)
part A pins: A1 PT2B (io), A2 PT2D (io), A3 PT2F (io), A5 PT3B (io), A6 PT3C (io), A7 PT3D (io), A8 PT4B/PCLK0_1 (io), A9 PT4C (io), A10 PT4E (io), A11 PT5A (io), A12 PT5C (io), A13 PR2A (io), B2 PT2A (io), B3 PT2E (io), B4 PT3A (io), B8 PT4A/PCLK0_0 (io), B10 PT4D (io), B11 PT5B (io), B12 PT4F (io), B14 PR3A (io), C3 PT2C (io), C12 PR2B (io), C13 PR3B (io), C14 PR3C (io), D13 PR3D (io), D14 PR4A (io), E13 PR4B (io), E14 PR5A (io), F13 PR5B (io), F14 PR5C (io), G13 PR5D (io), H13 PR6A (io), J13 PR6B (io), J14 PR7A (io), K13 PR7B (io), K14 PR7C (io), L13 PR8B (io), L14 PR8A (io), M13 PR7D (io), M14 PR9A (io), N14 PR9B (io)
part B pins: B1 PL2A (io), C1 PL2B (io), C2 PL3C (io), D1 PL3B (io), D2 PL3A (io), E1 PL3D (io), E2 PL4A (io), F1 PL4B (io), F2 PL5A (io), G2 PL5B (io), H2 PL5C (io), J1 PL5D/GSRN (io), J2 PL6A (io), K1 PL6B/TSALL (io), K2 PL7A (io), L1 PL7B (io), L2 PL7C (io), M1 PL7D (io), M2 PL8A (io), M3 PL9A (io), N1 PL8B (io), N3 PB2B (io), N5 PB2C (io), N6 PB2D (io), N7 PB3A/PCLK1_1 (io), N8 PB3C/PCLK1_0 (io), N11 PB4B (io), N12 PB4D (io), N13 PB5D (io), P3 PL9B (io), P4 PB2A (io), P8 PB3B (io), P9 PB3D (io), P11 PB4A (io), P12 PB4C (io), P13 PB5A (io), P14 PB5C (io)
part C pins: M12 SLEEPN (in) "Powered by VCCIO1", N4 TCK (in) "Powered by VCCIO1", P2 TMS (in) "Powered by VCCIO1", P5 TDO (out) "Powered by VCCIO1", P6 TDI (in) "Powered by VCCIO1"
part D pins: A14 VCCIO0 (power), B5 VCCIO0 (power), B6 VCC (power), B7 VCCAUX (power), G1 VCCIO1 (power), H14 VCCIO0 (power), P1 VCCIO1 (power), P7 VCC (power), P10 VCCIO1 (power)
part E pins: A4 GNDIO0 (power), B9 GND (power), B13 GNDIO0 (power), G14 GNDIO0 (power), H1 GNDIO1 (power), N2 GNDIO1 (power), N9 GND (power), N10 GNDIO1 (power)

## LCMXO256C-4MN100I4W
designator U?
MachXO 256 Crossover PLD, 1.8V/2.5V/3.3V, 78 User I/Os, 100-Pins csBGA, Speed Grade-4, Industrial Grade, Pb-Free
footprint csBGA100 (BGA, 100-Leads, Body 8x8mm, Pitch 0.5mm)
3D model MachXO256-csBGA100 (100-Ball Chip Scale Ball Grid Array (csBGA100))
signal-integrity model LCMXO256C_M100 (MachXO)
part A pins: A1 PT2B (io), A2 PT2D (io), A3 PT2F (io), A5 PT3B (io), A6 PT3C (io), A7 PT3D (io), A8 PT4B/PCLK0_1 (io), A9 PT4C (io), A10 PT4E (io), A11 PT5A (io), A12 PT5C (io), A13 PR2A (io), B2 PT2A (io), B3 PT2E (io), B4 PT3A (io), B8 PT4A/PCLK0_0 (io), B10 PT4D (io), B11 PT5B (io), B12 PT4F (io), B14 PR3A (io), C3 PT2C (io), C12 PR2B (io), C13 PR3B (io), C14 PR3C (io), D13 PR3D (io), D14 PR4A (io), E13 PR4B (io), E14 PR5A (io), F13 PR5B (io), F14 PR5C (io), G13 PR5D (io), H13 PR6A (io), J13 PR6B (io), J14 PR7A (io), K13 PR7B (io), K14 PR7C (io), L13 PR8B (io), L14 PR8A (io), M13 PR7D (io), M14 PR9A (io), N14 PR9B (io)
part B pins: B1 PL2A (io), C1 PL2B (io), C2 PL3C (io), D1 PL3B (io), D2 PL3A (io), E1 PL3D (io), E2 PL4A (io), F1 PL4B (io), F2 PL5A (io), G2 PL5B (io), H2 PL5C (io), J1 PL5D/GSRN (io), J2 PL6A (io), K1 PL6B/TSALL (io), K2 PL7A (io), L1 PL7B (io), L2 PL7C (io), M1 PL7D (io), M2 PL8A (io), M3 PL9A (io), N1 PL8B (io), N3 PB2B (io), N5 PB2C (io), N6 PB2D (io), N7 PB3A/PCLK1_1 (io), N8 PB3C/PCLK1_0 (io), N11 PB4B (io), N12 PB4D (io), N13 PB5D (io), P3 PL9B (io), P4 PB2A (io), P8 PB3B (io), P9 PB3D (io), P11 PB4A (io), P12 PB4C (io), P13 PB5A (io), P14 PB5C (io)
part C pins: M12 SLEEPN (in) "Powered by VCCIO1", N4 TCK (in) "Powered by VCCIO1", P2 TMS (in) "Powered by VCCIO1", P5 TDO (out) "Powered by VCCIO1", P6 TDI (in) "Powered by VCCIO1"
part D pins: A14 VCCIO0 (power), B5 VCCIO0 (power), B6 VCC (power), B7 VCCAUX (power), G1 VCCIO1 (power), H14 VCCIO0 (power), P1 VCCIO1 (power), P7 VCC (power), P10 VCCIO1 (power)
part E pins: A4 GNDIO0 (power), B9 GND (power), B13 GNDIO0 (power), G14 GNDIO0 (power), H1 GNDIO1 (power), N2 GNDIO1 (power), N9 GND (power), N10 GNDIO1 (power)

## LCMXO256C-4MN100IES
designator U?
MachXO 256 Crossover PLD, 1.8V/2.5V/3.3V, 78 User I/Os, 100-Pins csBGA, Speed Grade-4, Industrial Grade, Pb-Free, Engineering Sample
footprint csBGA100 (BGA, 100-Leads, Body 8x8mm, Pitch 0.5mm)
3D model MachXO256-csBGA100 (100-Ball Chip Scale Ball Grid Array (csBGA100))
signal-integrity model LCMXO256C_M100 (MachXO)
part A pins: A1 PT2B (io), A2 PT2D (io), A3 PT2F (io), A5 PT3B (io), A6 PT3C (io), A7 PT3D (io), A8 PT4B/PCLK0_1 (io), A9 PT4C (io), A10 PT4E (io), A11 PT5A (io), A12 PT5C (io), A13 PR2A (io), B2 PT2A (io), B3 PT2E (io), B4 PT3A (io), B8 PT4A/PCLK0_0 (io), B10 PT4D (io), B11 PT5B (io), B12 PT4F (io), B14 PR3A (io), C3 PT2C (io), C12 PR2B (io), C13 PR3B (io), C14 PR3C (io), D13 PR3D (io), D14 PR4A (io), E13 PR4B (io), E14 PR5A (io), F13 PR5B (io), F14 PR5C (io), G13 PR5D (io), H13 PR6A (io), J13 PR6B (io), J14 PR7A (io), K13 PR7B (io), K14 PR7C (io), L13 PR8B (io), L14 PR8A (io), M13 PR7D (io), M14 PR9A (io), N14 PR9B (io)
part B pins: B1 PL2A (io), C1 PL2B (io), C2 PL3C (io), D1 PL3B (io), D2 PL3A (io), E1 PL3D (io), E2 PL4A (io), F1 PL4B (io), F2 PL5A (io), G2 PL5B (io), H2 PL5C (io), J1 PL5D/GSRN (io), J2 PL6A (io), K1 PL6B/TSALL (io), K2 PL7A (io), L1 PL7B (io), L2 PL7C (io), M1 PL7D (io), M2 PL8A (io), M3 PL9A (io), N1 PL8B (io), N3 PB2B (io), N5 PB2C (io), N6 PB2D (io), N7 PB3A/PCLK1_1 (io), N8 PB3C/PCLK1_0 (io), N11 PB4B (io), N12 PB4D (io), N13 PB5D (io), P3 PL9B (io), P4 PB2A (io), P8 PB3B (io), P9 PB3D (io), P11 PB4A (io), P12 PB4C (io), P13 PB5A (io), P14 PB5C (io)
part C pins: M12 SLEEPN (in) "Powered by VCCIO1", N4 TCK (in) "Powered by VCCIO1", P2 TMS (in) "Powered by VCCIO1", P5 TDO (out) "Powered by VCCIO1", P6 TDI (in) "Powered by VCCIO1"
part D pins: A14 VCCIO0 (power), B5 VCCIO0 (power), B6 VCC (power), B7 VCCAUX (power), G1 VCCIO1 (power), H14 VCCIO0 (power), P1 VCCIO1 (power), P7 VCC (power), P10 VCCIO1 (power)
part E pins: A4 GNDIO0 (power), B9 GND (power), B13 GNDIO0 (power), G14 GNDIO0 (power), H1 GNDIO1 (power), N2 GNDIO1 (power), N9 GND (power), N10 GNDIO1 (power)


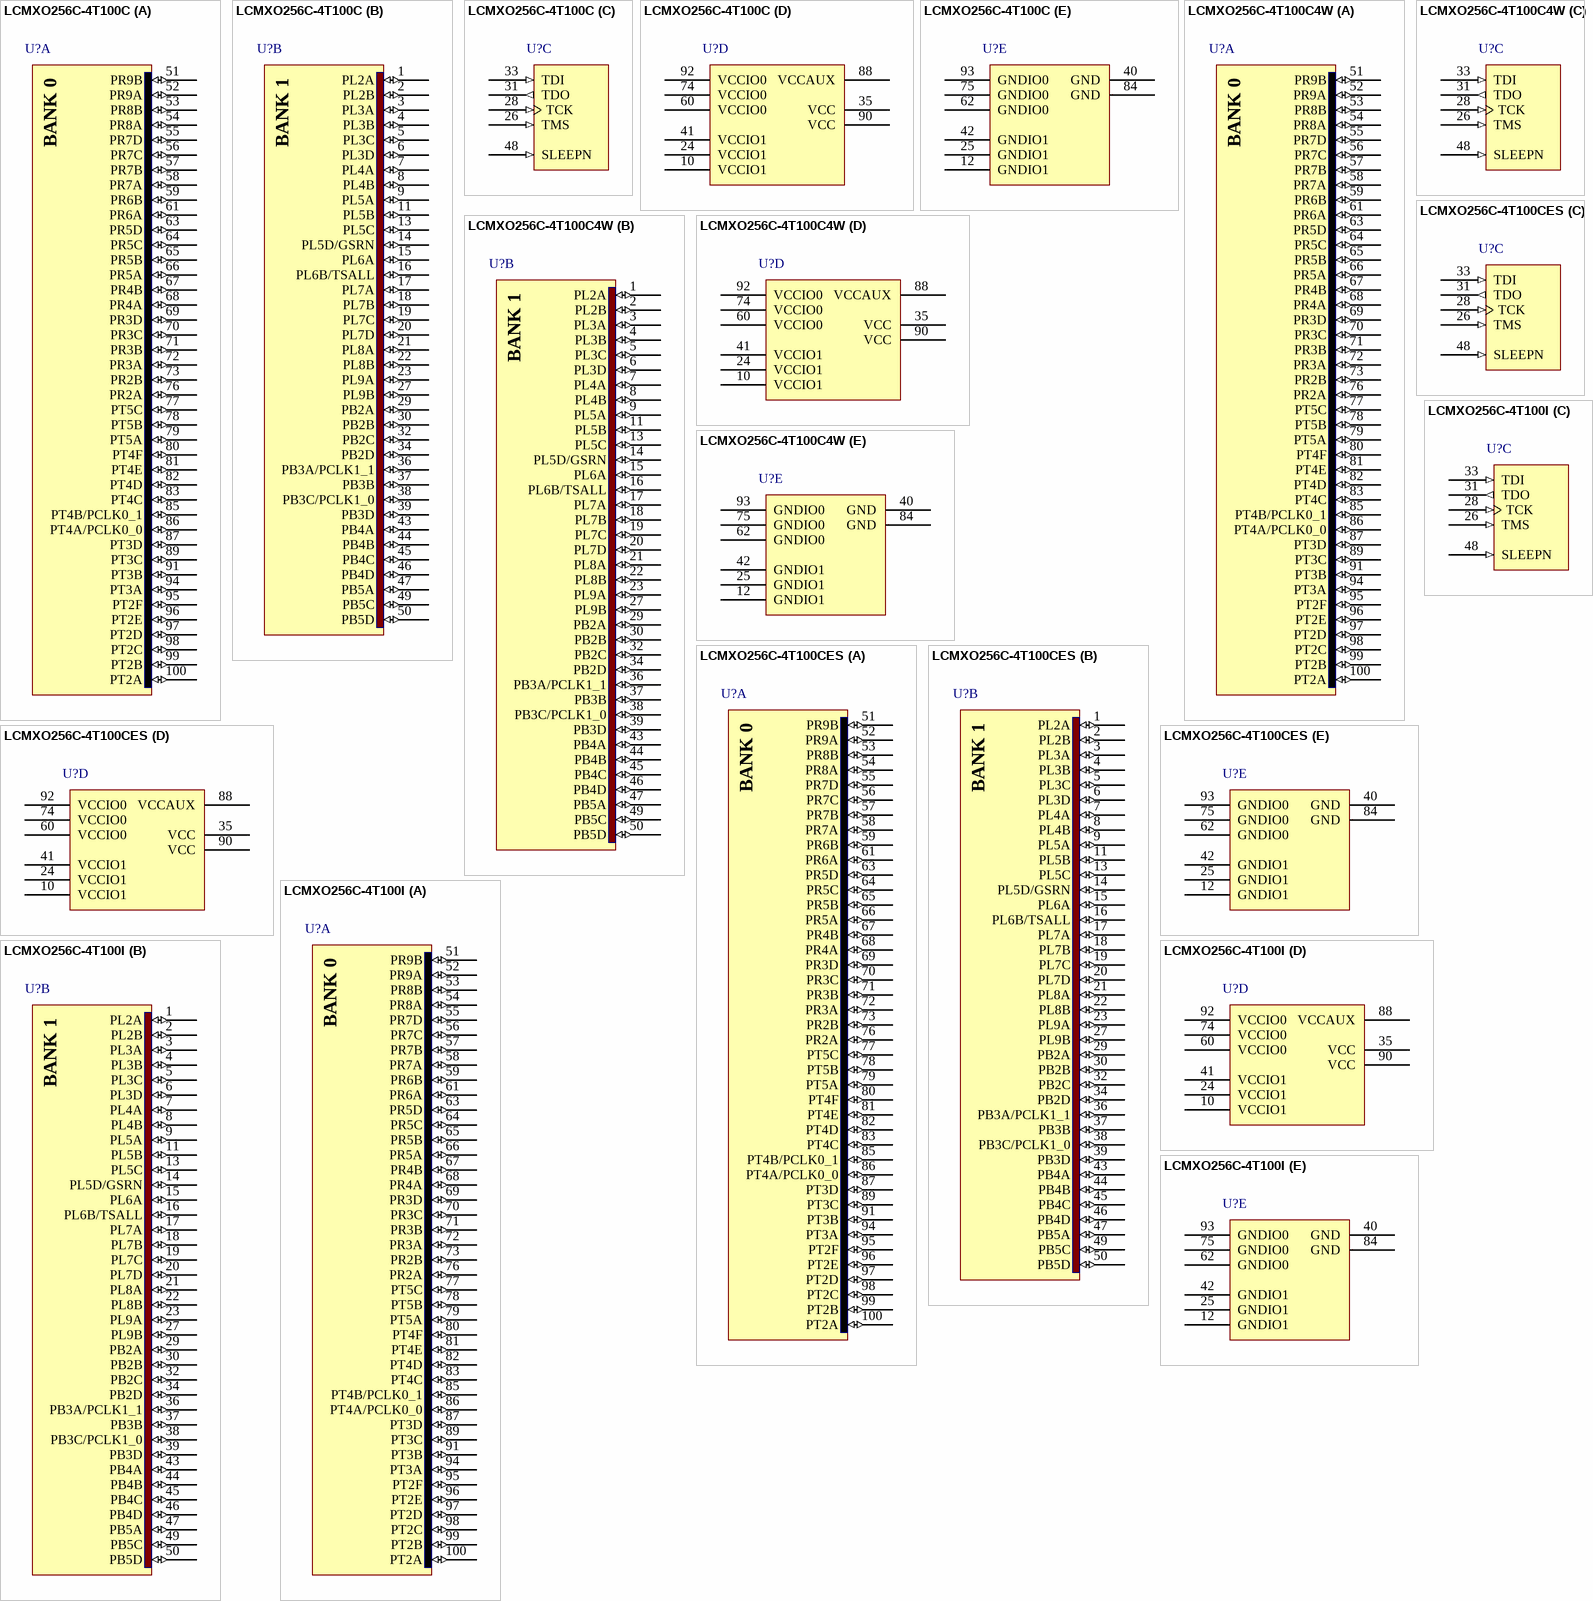
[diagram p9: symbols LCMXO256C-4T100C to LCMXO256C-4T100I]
## LCMXO256C-4T100C
designator U?
MachXO 256 Crossover PLD, 1.8V/2.5V/3.3V, 78 User I/Os, 100-Pins TQFP, Speed Grade-4, Commercial Grade
footprint TQFP100_N (Thin QFP, 100-Leads, Body 14x14mm, Pitch 0.5mm, IPC Medium Density)
footprint TQFP100_L (Thin QFP, 100-Leads, Body 14x14mm, Pitch 0.5mm, IPC High Density)
footprint TQFP100_M (Thin QFP, 100-Leads, Body 14x14mm, Pitch 0.5mm, IPC Low Density)
3D model MachXO256-TQFP100 (100-Pin Thin Quad Flat Pack (TQFP100))
signal-integrity model LCMXO256C_T100 (MachXO)
part A pins: 51 PR9B (io), 52 PR9A (io), 53 PR8B (io), 54 PR8A (io), 55 PR7D (io), 56 PR7C (io), 57 PR7B (io), 58 PR7A (io), 59 PR6B (io), 61 PR6A (io), 63 PR5D (io), 64 PR5C (io), 65 PR5B (io), 66 PR5A (io), 67 PR4B (io), 68 PR4A (io), 69 PR3D (io), 70 PR3C (io), 71 PR3B (io), 72 PR3A (io), 73 PR2B (io), 76 PR2A (io), 77 PT5C (io), 78 PT5B (io), 79 PT5A (io), 80 PT4F (io), 81 PT4E (io), 82 PT4D (io), 83 PT4C (io), 85 PT4B/PCLK0_1 (io), 86 PT4A/PCLK0_0 (io), 87 PT3D (io), 89 PT3C (io), 91 PT3B (io), 94 PT3A (io), 95 PT2F (io), 96 PT2E (io), 97 PT2D (io), 98 PT2C (io), 99 PT2B (io), 100 PT2A (io)
part B pins: 1 PL2A (io), 2 PL2B (io), 3 PL3A (io), 4 PL3B (io), 5 PL3C (io), 6 PL3D (io), 7 PL4A (io), 8 PL4B (io), 9 PL5A (io), 11 PL5B (io), 13 PL5C (io), 14 PL5D/GSRN (io), 15 PL6A (io), 16 PL6B/TSALL (io), 17 PL7A (io), 18 PL7B (io), 19 PL7C (io), 20 PL7D (io), 21 PL8A (io), 22 PL8B (io), 23 PL9A (io), 27 PL9B (io), 29 PB2A (io), 30 PB2B (io), 32 PB2C (io), 34 PB2D (io), 36 PB3A/PCLK1_1 (io), 37 PB3B (io), 38 PB3C/PCLK1_0 (io), 39 PB3D (io), 43 PB4A (io), 44 PB4B (io), 45 PB4C (io), 46 PB4D (io), 47 PB5A (io), 49 PB5C (io), 50 PB5D (io)
part C pins: 26 TMS (in) "Powered by VCCIO1", 28 TCK (in) "Powered by VCCIO1", 31 TDO (out) "Powered by VCCIO1", 33 TDI (in) "Powered by VCCIO1", 48 SLEEPN (in) "Powered by VCCIO1"
part D pins: 10 VCCIO1 (power), 24 VCCIO1 (power), 35 VCC (power), 41 VCCIO1 (power), 60 VCCIO0 (power), 74 VCCIO0 (power), 88 VCCAUX (power), 90 VCC (power), 92 VCCIO0 (power)
part E pins: 12 GNDIO1 (power), 25 GNDIO1 (power), 40 GND (power), 42 GNDIO1 (power), 62 GNDIO0 (power), 75 GNDIO0 (power), 84 GND (power), 93 GNDIO0 (power)

## LCMXO256C-4T100C4W
designator U?
MachXO 256 Crossover PLD, 1.8V/2.5V/3.3V, 78 User I/Os, 100-Pins TQFP, Speed Grade-4, Commercial Grade
footprint TQFP100_N (Thin QFP, 100-Leads, Body 14x14mm, Pitch 0.5mm, IPC Medium Density)
footprint TQFP100_L (Thin QFP, 100-Leads, Body 14x14mm, Pitch 0.5mm, IPC High Density)
footprint TQFP100_M (Thin QFP, 100-Leads, Body 14x14mm, Pitch 0.5mm, IPC Low Density)
3D model MachXO256-TQFP100 (100-Pin Thin Quad Flat Pack (TQFP100))
signal-integrity model LCMXO256C_T100 (MachXO)
part A pins: 51 PR9B (io), 52 PR9A (io), 53 PR8B (io), 54 PR8A (io), 55 PR7D (io), 56 PR7C (io), 57 PR7B (io), 58 PR7A (io), 59 PR6B (io), 61 PR6A (io), 63 PR5D (io), 64 PR5C (io), 65 PR5B (io), 66 PR5A (io), 67 PR4B (io), 68 PR4A (io), 69 PR3D (io), 70 PR3C (io), 71 PR3B (io), 72 PR3A (io), 73 PR2B (io), 76 PR2A (io), 77 PT5C (io), 78 PT5B (io), 79 PT5A (io), 80 PT4F (io), 81 PT4E (io), 82 PT4D (io), 83 PT4C (io), 85 PT4B/PCLK0_1 (io), 86 PT4A/PCLK0_0 (io), 87 PT3D (io), 89 PT3C (io), 91 PT3B (io), 94 PT3A (io), 95 PT2F (io), 96 PT2E (io), 97 PT2D (io), 98 PT2C (io), 99 PT2B (io), 100 PT2A (io)
part B pins: 1 PL2A (io), 2 PL2B (io), 3 PL3A (io), 4 PL3B (io), 5 PL3C (io), 6 PL3D (io), 7 PL4A (io), 8 PL4B (io), 9 PL5A (io), 11 PL5B (io), 13 PL5C (io), 14 PL5D/GSRN (io), 15 PL6A (io), 16 PL6B/TSALL (io), 17 PL7A (io), 18 PL7B (io), 19 PL7C (io), 20 PL7D (io), 21 PL8A (io), 22 PL8B (io), 23 PL9A (io), 27 PL9B (io), 29 PB2A (io), 30 PB2B (io), 32 PB2C (io), 34 PB2D (io), 36 PB3A/PCLK1_1 (io), 37 PB3B (io), 38 PB3C/PCLK1_0 (io), 39 PB3D (io), 43 PB4A (io), 44 PB4B (io), 45 PB4C (io), 46 PB4D (io), 47 PB5A (io), 49 PB5C (io), 50 PB5D (io)
part C pins: 26 TMS (in) "Powered by VCCIO1", 28 TCK (in) "Powered by VCCIO1", 31 TDO (out) "Powered by VCCIO1", 33 TDI (in) "Powered by VCCIO1", 48 SLEEPN (in) "Powered by VCCIO1"
part D pins: 10 VCCIO1 (power), 24 VCCIO1 (power), 35 VCC (power), 41 VCCIO1 (power), 60 VCCIO0 (power), 74 VCCIO0 (power), 88 VCCAUX (power), 90 VCC (power), 92 VCCIO0 (power)
part E pins: 12 GNDIO1 (power), 25 GNDIO1 (power), 40 GND (power), 42 GNDIO1 (power), 62 GNDIO0 (power), 75 GNDIO0 (power), 84 GND (power), 93 GNDIO0 (power)

## LCMXO256C-4T100CES
designator U?
MachXO 256 Crossover PLD, 1.8V/2.5V/3.3V, 78 User I/Os, 100-Pins TQFP, Speed Grade-4, Commercial Grade, Engineering Sample
footprint TQFP100_N (Thin QFP, 100-Leads, Body 14x14mm, Pitch 0.5mm, IPC Medium Density)
footprint TQFP100_L (Thin QFP, 100-Leads, Body 14x14mm, Pitch 0.5mm, IPC High Density)
footprint TQFP100_M (Thin QFP, 100-Leads, Body 14x14mm, Pitch 0.5mm, IPC Low Density)
3D model MachXO256-TQFP100 (100-Pin Thin Quad Flat Pack (TQFP100))
signal-integrity model LCMXO256C_T100 (MachXO)
part A pins: 51 PR9B (io), 52 PR9A (io), 53 PR8B (io), 54 PR8A (io), 55 PR7D (io), 56 PR7C (io), 57 PR7B (io), 58 PR7A (io), 59 PR6B (io), 61 PR6A (io), 63 PR5D (io), 64 PR5C (io), 65 PR5B (io), 66 PR5A (io), 67 PR4B (io), 68 PR4A (io), 69 PR3D (io), 70 PR3C (io), 71 PR3B (io), 72 PR3A (io), 73 PR2B (io), 76 PR2A (io), 77 PT5C (io), 78 PT5B (io), 79 PT5A (io), 80 PT4F (io), 81 PT4E (io), 82 PT4D (io), 83 PT4C (io), 85 PT4B/PCLK0_1 (io), 86 PT4A/PCLK0_0 (io), 87 PT3D (io), 89 PT3C (io), 91 PT3B (io), 94 PT3A (io), 95 PT2F (io), 96 PT2E (io), 97 PT2D (io), 98 PT2C (io), 99 PT2B (io), 100 PT2A (io)
part B pins: 1 PL2A (io), 2 PL2B (io), 3 PL3A (io), 4 PL3B (io), 5 PL3C (io), 6 PL3D (io), 7 PL4A (io), 8 PL4B (io), 9 PL5A (io), 11 PL5B (io), 13 PL5C (io), 14 PL5D/GSRN (io), 15 PL6A (io), 16 PL6B/TSALL (io), 17 PL7A (io), 18 PL7B (io), 19 PL7C (io), 20 PL7D (io), 21 PL8A (io), 22 PL8B (io), 23 PL9A (io), 27 PL9B (io), 29 PB2A (io), 30 PB2B (io), 32 PB2C (io), 34 PB2D (io), 36 PB3A/PCLK1_1 (io), 37 PB3B (io), 38 PB3C/PCLK1_0 (io), 39 PB3D (io), 43 PB4A (io), 44 PB4B (io), 45 PB4C (io), 46 PB4D (io), 47 PB5A (io), 49 PB5C (io), 50 PB5D (io)
part C pins: 26 TMS (in) "Powered by VCCIO1", 28 TCK (in) "Powered by VCCIO1", 31 TDO (out) "Powered by VCCIO1", 33 TDI (in) "Powered by VCCIO1", 48 SLEEPN (in) "Powered by VCCIO1"
part D pins: 10 VCCIO1 (power), 24 VCCIO1 (power), 35 VCC (power), 41 VCCIO1 (power), 60 VCCIO0 (power), 74 VCCIO0 (power), 88 VCCAUX (power), 90 VCC (power), 92 VCCIO0 (power)
part E pins: 12 GNDIO1 (power), 25 GNDIO1 (power), 40 GND (power), 42 GNDIO1 (power), 62 GNDIO0 (power), 75 GNDIO0 (power), 84 GND (power), 93 GNDIO0 (power)

## LCMXO256C-4T100I
designator U?
MachXO 256 Crossover PLD, 1.8V/2.5V/3.3V, 78 User I/Os, 100-Pins TQFP, Speed Grade-4, Industrial Grade
footprint TQFP100_N (Thin QFP, 100-Leads, Body 14x14mm, Pitch 0.5mm, IPC Medium Density)
footprint TQFP100_L (Thin QFP, 100-Leads, Body 14x14mm, Pitch 0.5mm, IPC High Density)
footprint TQFP100_M (Thin QFP, 100-Leads, Body 14x14mm, Pitch 0.5mm, IPC Low Density)
3D model MachXO256-TQFP100 (100-Pin Thin Quad Flat Pack (TQFP100))
signal-integrity model LCMXO256C_T100 (MachXO)
part A pins: 51 PR9B (io), 52 PR9A (io), 53 PR8B (io), 54 PR8A (io), 55 PR7D (io), 56 PR7C (io), 57 PR7B (io), 58 PR7A (io), 59 PR6B (io), 61 PR6A (io), 63 PR5D (io), 64 PR5C (io), 65 PR5B (io), 66 PR5A (io), 67 PR4B (io), 68 PR4A (io), 69 PR3D (io), 70 PR3C (io), 71 PR3B (io), 72 PR3A (io), 73 PR2B (io), 76 PR2A (io), 77 PT5C (io), 78 PT5B (io), 79 PT5A (io), 80 PT4F (io), 81 PT4E (io), 82 PT4D (io), 83 PT4C (io), 85 PT4B/PCLK0_1 (io), 86 PT4A/PCLK0_0 (io), 87 PT3D (io), 89 PT3C (io), 91 PT3B (io), 94 PT3A (io), 95 PT2F (io), 96 PT2E (io), 97 PT2D (io), 98 PT2C (io), 99 PT2B (io), 100 PT2A (io)
part B pins: 1 PL2A (io), 2 PL2B (io), 3 PL3A (io), 4 PL3B (io), 5 PL3C (io), 6 PL3D (io), 7 PL4A (io), 8 PL4B (io), 9 PL5A (io), 11 PL5B (io), 13 PL5C (io), 14 PL5D/GSRN (io), 15 PL6A (io), 16 PL6B/TSALL (io), 17 PL7A (io), 18 PL7B (io), 19 PL7C (io), 20 PL7D (io), 21 PL8A (io), 22 PL8B (io), 23 PL9A (io), 27 PL9B (io), 29 PB2A (io), 30 PB2B (io), 32 PB2C (io), 34 PB2D (io), 36 PB3A/PCLK1_1 (io), 37 PB3B (io), 38 PB3C/PCLK1_0 (io), 39 PB3D (io), 43 PB4A (io), 44 PB4B (io), 45 PB4C (io), 46 PB4D (io), 47 PB5A (io), 49 PB5C (io), 50 PB5D (io)
part C pins: 26 TMS (in) "Powered by VCCIO1", 28 TCK (in) "Powered by VCCIO1", 31 TDO (out) "Powered by VCCIO1", 33 TDI (in) "Powered by VCCIO1", 48 SLEEPN (in) "Powered by VCCIO1"
part D pins: 10 VCCIO1 (power), 24 VCCIO1 (power), 35 VCC (power), 41 VCCIO1 (power), 60 VCCIO0 (power), 74 VCCIO0 (power), 88 VCCAUX (power), 90 VCC (power), 92 VCCIO0 (power)
part E pins: 12 GNDIO1 (power), 25 GNDIO1 (power), 40 GND (power), 42 GNDIO1 (power), 62 GNDIO0 (power), 75 GNDIO0 (power), 84 GND (power), 93 GNDIO0 (power)


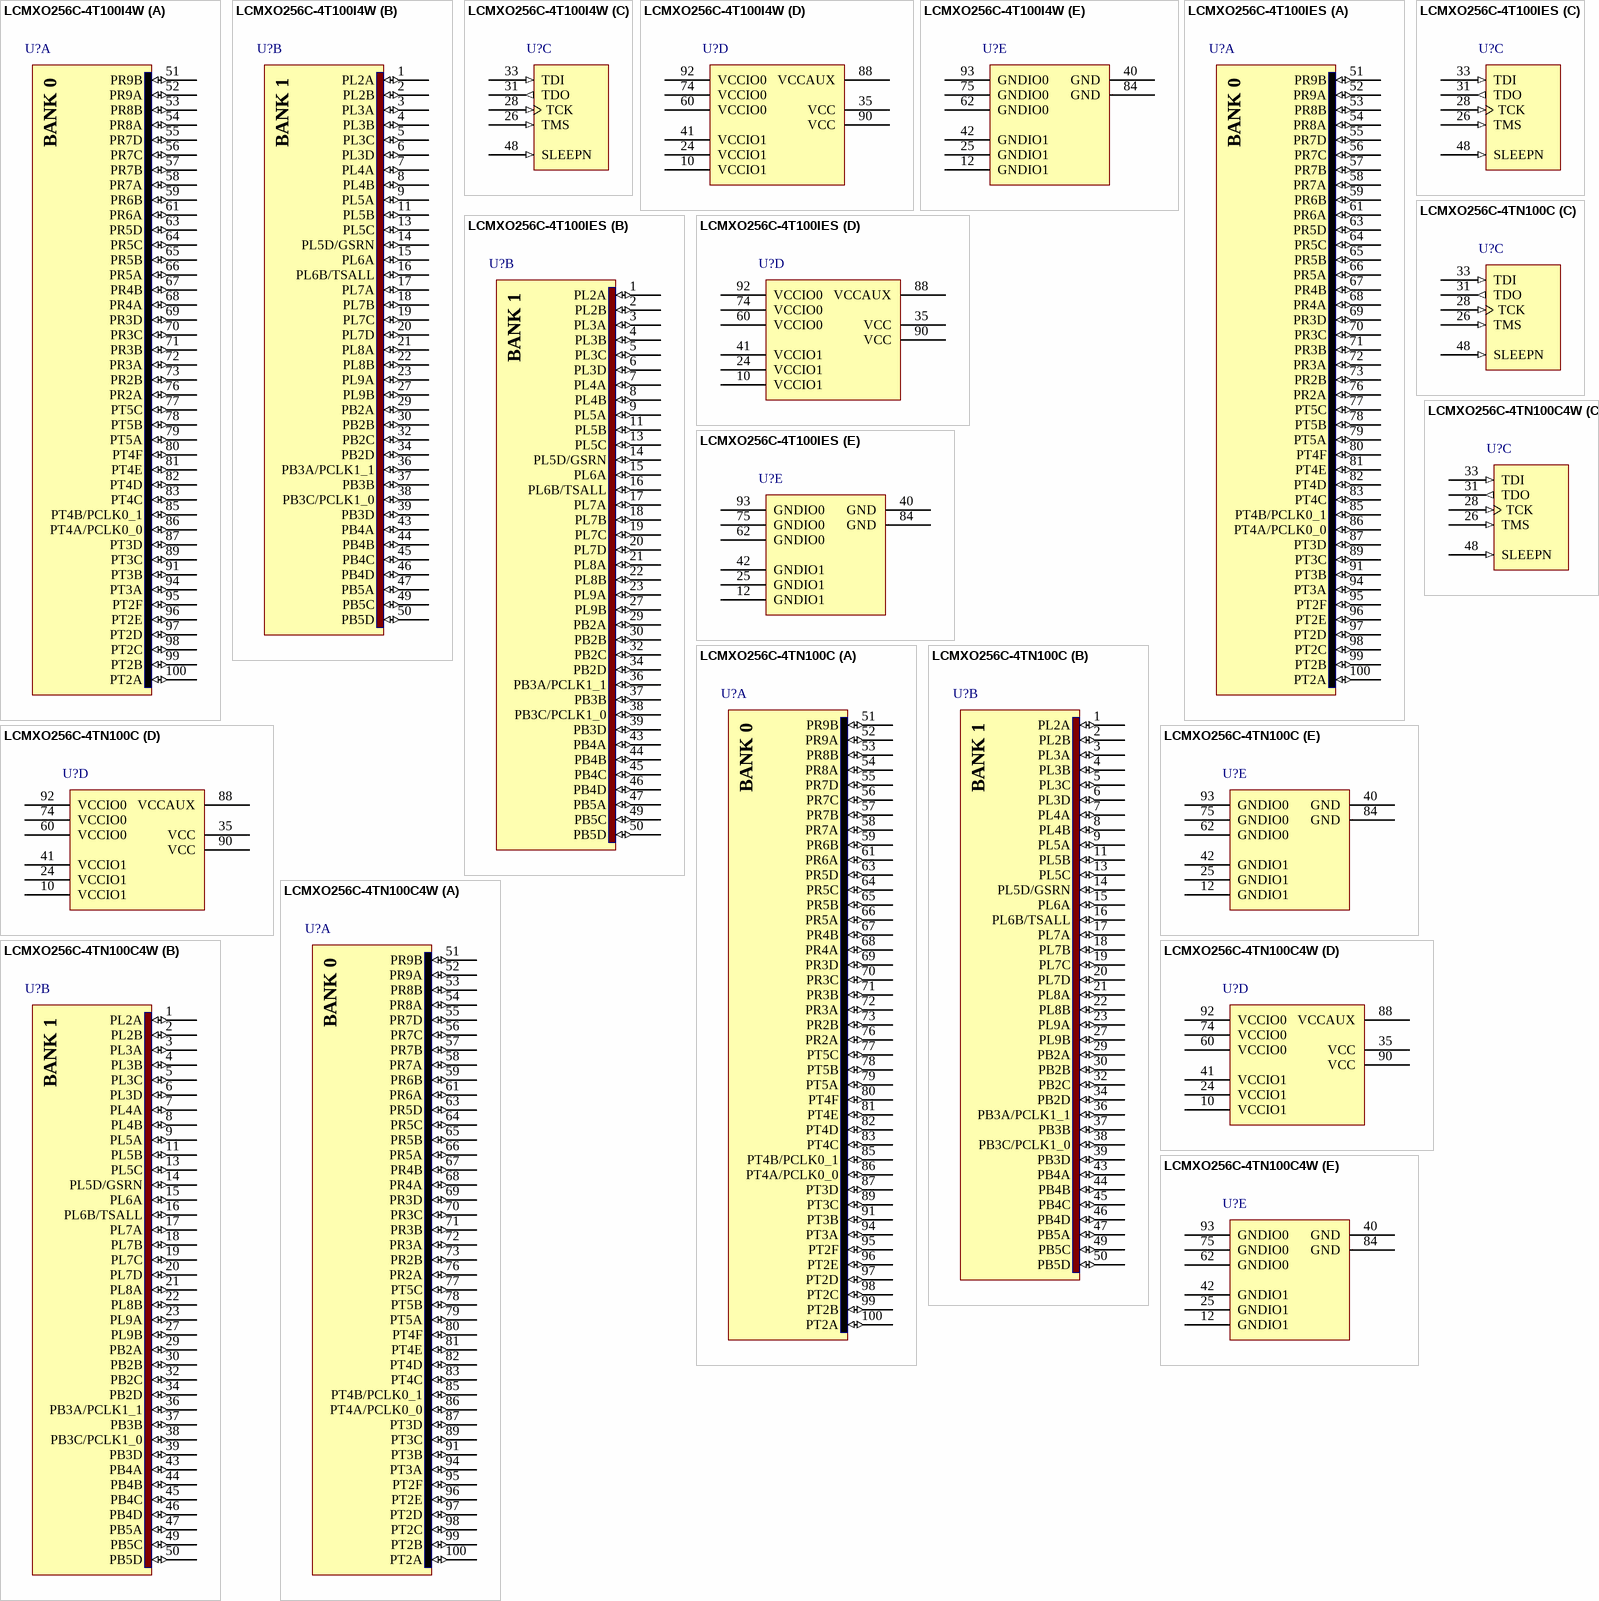
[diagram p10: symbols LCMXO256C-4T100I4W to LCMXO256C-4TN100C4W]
## LCMXO256C-4T100I4W
designator U?
MachXO 256 Crossover PLD, 1.8V/2.5V/3.3V, 78 User I/Os, 100-Pins TQFP, Speed Grade-4, Industrial Grade
footprint TQFP100_N (Thin QFP, 100-Leads, Body 14x14mm, Pitch 0.5mm, IPC Medium Density)
footprint TQFP100_L (Thin QFP, 100-Leads, Body 14x14mm, Pitch 0.5mm, IPC High Density)
footprint TQFP100_M (Thin QFP, 100-Leads, Body 14x14mm, Pitch 0.5mm, IPC Low Density)
3D model MachXO256-TQFP100 (100-Pin Thin Quad Flat Pack (TQFP100))
signal-integrity model LCMXO256C_T100 (MachXO)
part A pins: 51 PR9B (io), 52 PR9A (io), 53 PR8B (io), 54 PR8A (io), 55 PR7D (io), 56 PR7C (io), 57 PR7B (io), 58 PR7A (io), 59 PR6B (io), 61 PR6A (io), 63 PR5D (io), 64 PR5C (io), 65 PR5B (io), 66 PR5A (io), 67 PR4B (io), 68 PR4A (io), 69 PR3D (io), 70 PR3C (io), 71 PR3B (io), 72 PR3A (io), 73 PR2B (io), 76 PR2A (io), 77 PT5C (io), 78 PT5B (io), 79 PT5A (io), 80 PT4F (io), 81 PT4E (io), 82 PT4D (io), 83 PT4C (io), 85 PT4B/PCLK0_1 (io), 86 PT4A/PCLK0_0 (io), 87 PT3D (io), 89 PT3C (io), 91 PT3B (io), 94 PT3A (io), 95 PT2F (io), 96 PT2E (io), 97 PT2D (io), 98 PT2C (io), 99 PT2B (io), 100 PT2A (io)
part B pins: 1 PL2A (io), 2 PL2B (io), 3 PL3A (io), 4 PL3B (io), 5 PL3C (io), 6 PL3D (io), 7 PL4A (io), 8 PL4B (io), 9 PL5A (io), 11 PL5B (io), 13 PL5C (io), 14 PL5D/GSRN (io), 15 PL6A (io), 16 PL6B/TSALL (io), 17 PL7A (io), 18 PL7B (io), 19 PL7C (io), 20 PL7D (io), 21 PL8A (io), 22 PL8B (io), 23 PL9A (io), 27 PL9B (io), 29 PB2A (io), 30 PB2B (io), 32 PB2C (io), 34 PB2D (io), 36 PB3A/PCLK1_1 (io), 37 PB3B (io), 38 PB3C/PCLK1_0 (io), 39 PB3D (io), 43 PB4A (io), 44 PB4B (io), 45 PB4C (io), 46 PB4D (io), 47 PB5A (io), 49 PB5C (io), 50 PB5D (io)
part C pins: 26 TMS (in) "Powered by VCCIO1", 28 TCK (in) "Powered by VCCIO1", 31 TDO (out) "Powered by VCCIO1", 33 TDI (in) "Powered by VCCIO1", 48 SLEEPN (in) "Powered by VCCIO1"
part D pins: 10 VCCIO1 (power), 24 VCCIO1 (power), 35 VCC (power), 41 VCCIO1 (power), 60 VCCIO0 (power), 74 VCCIO0 (power), 88 VCCAUX (power), 90 VCC (power), 92 VCCIO0 (power)
part E pins: 12 GNDIO1 (power), 25 GNDIO1 (power), 40 GND (power), 42 GNDIO1 (power), 62 GNDIO0 (power), 75 GNDIO0 (power), 84 GND (power), 93 GNDIO0 (power)

## LCMXO256C-4T100IES
designator U?
MachXO 256 Crossover PLD, 1.8V/2.5V/3.3V, 78 User I/Os, 100-Pins TQFP, Speed Grade-4, Industrial Grade, Engineering Sample
footprint TQFP100_N (Thin QFP, 100-Leads, Body 14x14mm, Pitch 0.5mm, IPC Medium Density)
footprint TQFP100_L (Thin QFP, 100-Leads, Body 14x14mm, Pitch 0.5mm, IPC High Density)
footprint TQFP100_M (Thin QFP, 100-Leads, Body 14x14mm, Pitch 0.5mm, IPC Low Density)
3D model MachXO256-TQFP100 (100-Pin Thin Quad Flat Pack (TQFP100))
signal-integrity model LCMXO256C_T100 (MachXO)
part A pins: 51 PR9B (io), 52 PR9A (io), 53 PR8B (io), 54 PR8A (io), 55 PR7D (io), 56 PR7C (io), 57 PR7B (io), 58 PR7A (io), 59 PR6B (io), 61 PR6A (io), 63 PR5D (io), 64 PR5C (io), 65 PR5B (io), 66 PR5A (io), 67 PR4B (io), 68 PR4A (io), 69 PR3D (io), 70 PR3C (io), 71 PR3B (io), 72 PR3A (io), 73 PR2B (io), 76 PR2A (io), 77 PT5C (io), 78 PT5B (io), 79 PT5A (io), 80 PT4F (io), 81 PT4E (io), 82 PT4D (io), 83 PT4C (io), 85 PT4B/PCLK0_1 (io), 86 PT4A/PCLK0_0 (io), 87 PT3D (io), 89 PT3C (io), 91 PT3B (io), 94 PT3A (io), 95 PT2F (io), 96 PT2E (io), 97 PT2D (io), 98 PT2C (io), 99 PT2B (io), 100 PT2A (io)
part B pins: 1 PL2A (io), 2 PL2B (io), 3 PL3A (io), 4 PL3B (io), 5 PL3C (io), 6 PL3D (io), 7 PL4A (io), 8 PL4B (io), 9 PL5A (io), 11 PL5B (io), 13 PL5C (io), 14 PL5D/GSRN (io), 15 PL6A (io), 16 PL6B/TSALL (io), 17 PL7A (io), 18 PL7B (io), 19 PL7C (io), 20 PL7D (io), 21 PL8A (io), 22 PL8B (io), 23 PL9A (io), 27 PL9B (io), 29 PB2A (io), 30 PB2B (io), 32 PB2C (io), 34 PB2D (io), 36 PB3A/PCLK1_1 (io), 37 PB3B (io), 38 PB3C/PCLK1_0 (io), 39 PB3D (io), 43 PB4A (io), 44 PB4B (io), 45 PB4C (io), 46 PB4D (io), 47 PB5A (io), 49 PB5C (io), 50 PB5D (io)
part C pins: 26 TMS (in) "Powered by VCCIO1", 28 TCK (in) "Powered by VCCIO1", 31 TDO (out) "Powered by VCCIO1", 33 TDI (in) "Powered by VCCIO1", 48 SLEEPN (in) "Powered by VCCIO1"
part D pins: 10 VCCIO1 (power), 24 VCCIO1 (power), 35 VCC (power), 41 VCCIO1 (power), 60 VCCIO0 (power), 74 VCCIO0 (power), 88 VCCAUX (power), 90 VCC (power), 92 VCCIO0 (power)
part E pins: 12 GNDIO1 (power), 25 GNDIO1 (power), 40 GND (power), 42 GNDIO1 (power), 62 GNDIO0 (power), 75 GNDIO0 (power), 84 GND (power), 93 GNDIO0 (power)

## LCMXO256C-4TN100C
designator U?
MachXO 256 Crossover PLD, 1.8V/2.5V/3.3V, 78 User I/Os, 100-Pins TQFP, Speed Grade-4, Commercial Grade, Pb-Free
footprint TQFP100_N (Thin QFP, 100-Leads, Body 14x14mm, Pitch 0.5mm, IPC Medium Density)
footprint TQFP100_L (Thin QFP, 100-Leads, Body 14x14mm, Pitch 0.5mm, IPC High Density)
footprint TQFP100_M (Thin QFP, 100-Leads, Body 14x14mm, Pitch 0.5mm, IPC Low Density)
3D model MachXO256-TQFP100 (100-Pin Thin Quad Flat Pack (TQFP100))
signal-integrity model LCMXO256C_T100 (MachXO)
part A pins: 51 PR9B (io), 52 PR9A (io), 53 PR8B (io), 54 PR8A (io), 55 PR7D (io), 56 PR7C (io), 57 PR7B (io), 58 PR7A (io), 59 PR6B (io), 61 PR6A (io), 63 PR5D (io), 64 PR5C (io), 65 PR5B (io), 66 PR5A (io), 67 PR4B (io), 68 PR4A (io), 69 PR3D (io), 70 PR3C (io), 71 PR3B (io), 72 PR3A (io), 73 PR2B (io), 76 PR2A (io), 77 PT5C (io), 78 PT5B (io), 79 PT5A (io), 80 PT4F (io), 81 PT4E (io), 82 PT4D (io), 83 PT4C (io), 85 PT4B/PCLK0_1 (io), 86 PT4A/PCLK0_0 (io), 87 PT3D (io), 89 PT3C (io), 91 PT3B (io), 94 PT3A (io), 95 PT2F (io), 96 PT2E (io), 97 PT2D (io), 98 PT2C (io), 99 PT2B (io), 100 PT2A (io)
part B pins: 1 PL2A (io), 2 PL2B (io), 3 PL3A (io), 4 PL3B (io), 5 PL3C (io), 6 PL3D (io), 7 PL4A (io), 8 PL4B (io), 9 PL5A (io), 11 PL5B (io), 13 PL5C (io), 14 PL5D/GSRN (io), 15 PL6A (io), 16 PL6B/TSALL (io), 17 PL7A (io), 18 PL7B (io), 19 PL7C (io), 20 PL7D (io), 21 PL8A (io), 22 PL8B (io), 23 PL9A (io), 27 PL9B (io), 29 PB2A (io), 30 PB2B (io), 32 PB2C (io), 34 PB2D (io), 36 PB3A/PCLK1_1 (io), 37 PB3B (io), 38 PB3C/PCLK1_0 (io), 39 PB3D (io), 43 PB4A (io), 44 PB4B (io), 45 PB4C (io), 46 PB4D (io), 47 PB5A (io), 49 PB5C (io), 50 PB5D (io)
part C pins: 26 TMS (in) "Powered by VCCIO1", 28 TCK (in) "Powered by VCCIO1", 31 TDO (out) "Powered by VCCIO1", 33 TDI (in) "Powered by VCCIO1", 48 SLEEPN (in) "Powered by VCCIO1"
part D pins: 10 VCCIO1 (power), 24 VCCIO1 (power), 35 VCC (power), 41 VCCIO1 (power), 60 VCCIO0 (power), 74 VCCIO0 (power), 88 VCCAUX (power), 90 VCC (power), 92 VCCIO0 (power)
part E pins: 12 GNDIO1 (power), 25 GNDIO1 (power), 40 GND (power), 42 GNDIO1 (power), 62 GNDIO0 (power), 75 GNDIO0 (power), 84 GND (power), 93 GNDIO0 (power)

## LCMXO256C-4TN100C4W
designator U?
MachXO 256 Crossover PLD, 1.8V/2.5V/3.3V, 78 User I/Os, 100-Pins TQFP, Speed Grade-4, Commercial Grade, Pb-Free
footprint TQFP100_N (Thin QFP, 100-Leads, Body 14x14mm, Pitch 0.5mm, IPC Medium Density)
footprint TQFP100_L (Thin QFP, 100-Leads, Body 14x14mm, Pitch 0.5mm, IPC High Density)
footprint TQFP100_M (Thin QFP, 100-Leads, Body 14x14mm, Pitch 0.5mm, IPC Low Density)
3D model MachXO256-TQFP100 (100-Pin Thin Quad Flat Pack (TQFP100))
signal-integrity model LCMXO256C_T100 (MachXO)
part A pins: 51 PR9B (io), 52 PR9A (io), 53 PR8B (io), 54 PR8A (io), 55 PR7D (io), 56 PR7C (io), 57 PR7B (io), 58 PR7A (io), 59 PR6B (io), 61 PR6A (io), 63 PR5D (io), 64 PR5C (io), 65 PR5B (io), 66 PR5A (io), 67 PR4B (io), 68 PR4A (io), 69 PR3D (io), 70 PR3C (io), 71 PR3B (io), 72 PR3A (io), 73 PR2B (io), 76 PR2A (io), 77 PT5C (io), 78 PT5B (io), 79 PT5A (io), 80 PT4F (io), 81 PT4E (io), 82 PT4D (io), 83 PT4C (io), 85 PT4B/PCLK0_1 (io), 86 PT4A/PCLK0_0 (io), 87 PT3D (io), 89 PT3C (io), 91 PT3B (io), 94 PT3A (io), 95 PT2F (io), 96 PT2E (io), 97 PT2D (io), 98 PT2C (io), 99 PT2B (io), 100 PT2A (io)
part B pins: 1 PL2A (io), 2 PL2B (io), 3 PL3A (io), 4 PL3B (io), 5 PL3C (io), 6 PL3D (io), 7 PL4A (io), 8 PL4B (io), 9 PL5A (io), 11 PL5B (io), 13 PL5C (io), 14 PL5D/GSRN (io), 15 PL6A (io), 16 PL6B/TSALL (io), 17 PL7A (io), 18 PL7B (io), 19 PL7C (io), 20 PL7D (io), 21 PL8A (io), 22 PL8B (io), 23 PL9A (io), 27 PL9B (io), 29 PB2A (io), 30 PB2B (io), 32 PB2C (io), 34 PB2D (io), 36 PB3A/PCLK1_1 (io), 37 PB3B (io), 38 PB3C/PCLK1_0 (io), 39 PB3D (io), 43 PB4A (io), 44 PB4B (io), 45 PB4C (io), 46 PB4D (io), 47 PB5A (io), 49 PB5C (io), 50 PB5D (io)
part C pins: 26 TMS (in) "Powered by VCCIO1", 28 TCK (in) "Powered by VCCIO1", 31 TDO (out) "Powered by VCCIO1", 33 TDI (in) "Powered by VCCIO1", 48 SLEEPN (in) "Powered by VCCIO1"
part D pins: 10 VCCIO1 (power), 24 VCCIO1 (power), 35 VCC (power), 41 VCCIO1 (power), 60 VCCIO0 (power), 74 VCCIO0 (power), 88 VCCAUX (power), 90 VCC (power), 92 VCCIO0 (power)
part E pins: 12 GNDIO1 (power), 25 GNDIO1 (power), 40 GND (power), 42 GNDIO1 (power), 62 GNDIO0 (power), 75 GNDIO0 (power), 84 GND (power), 93 GNDIO0 (power)


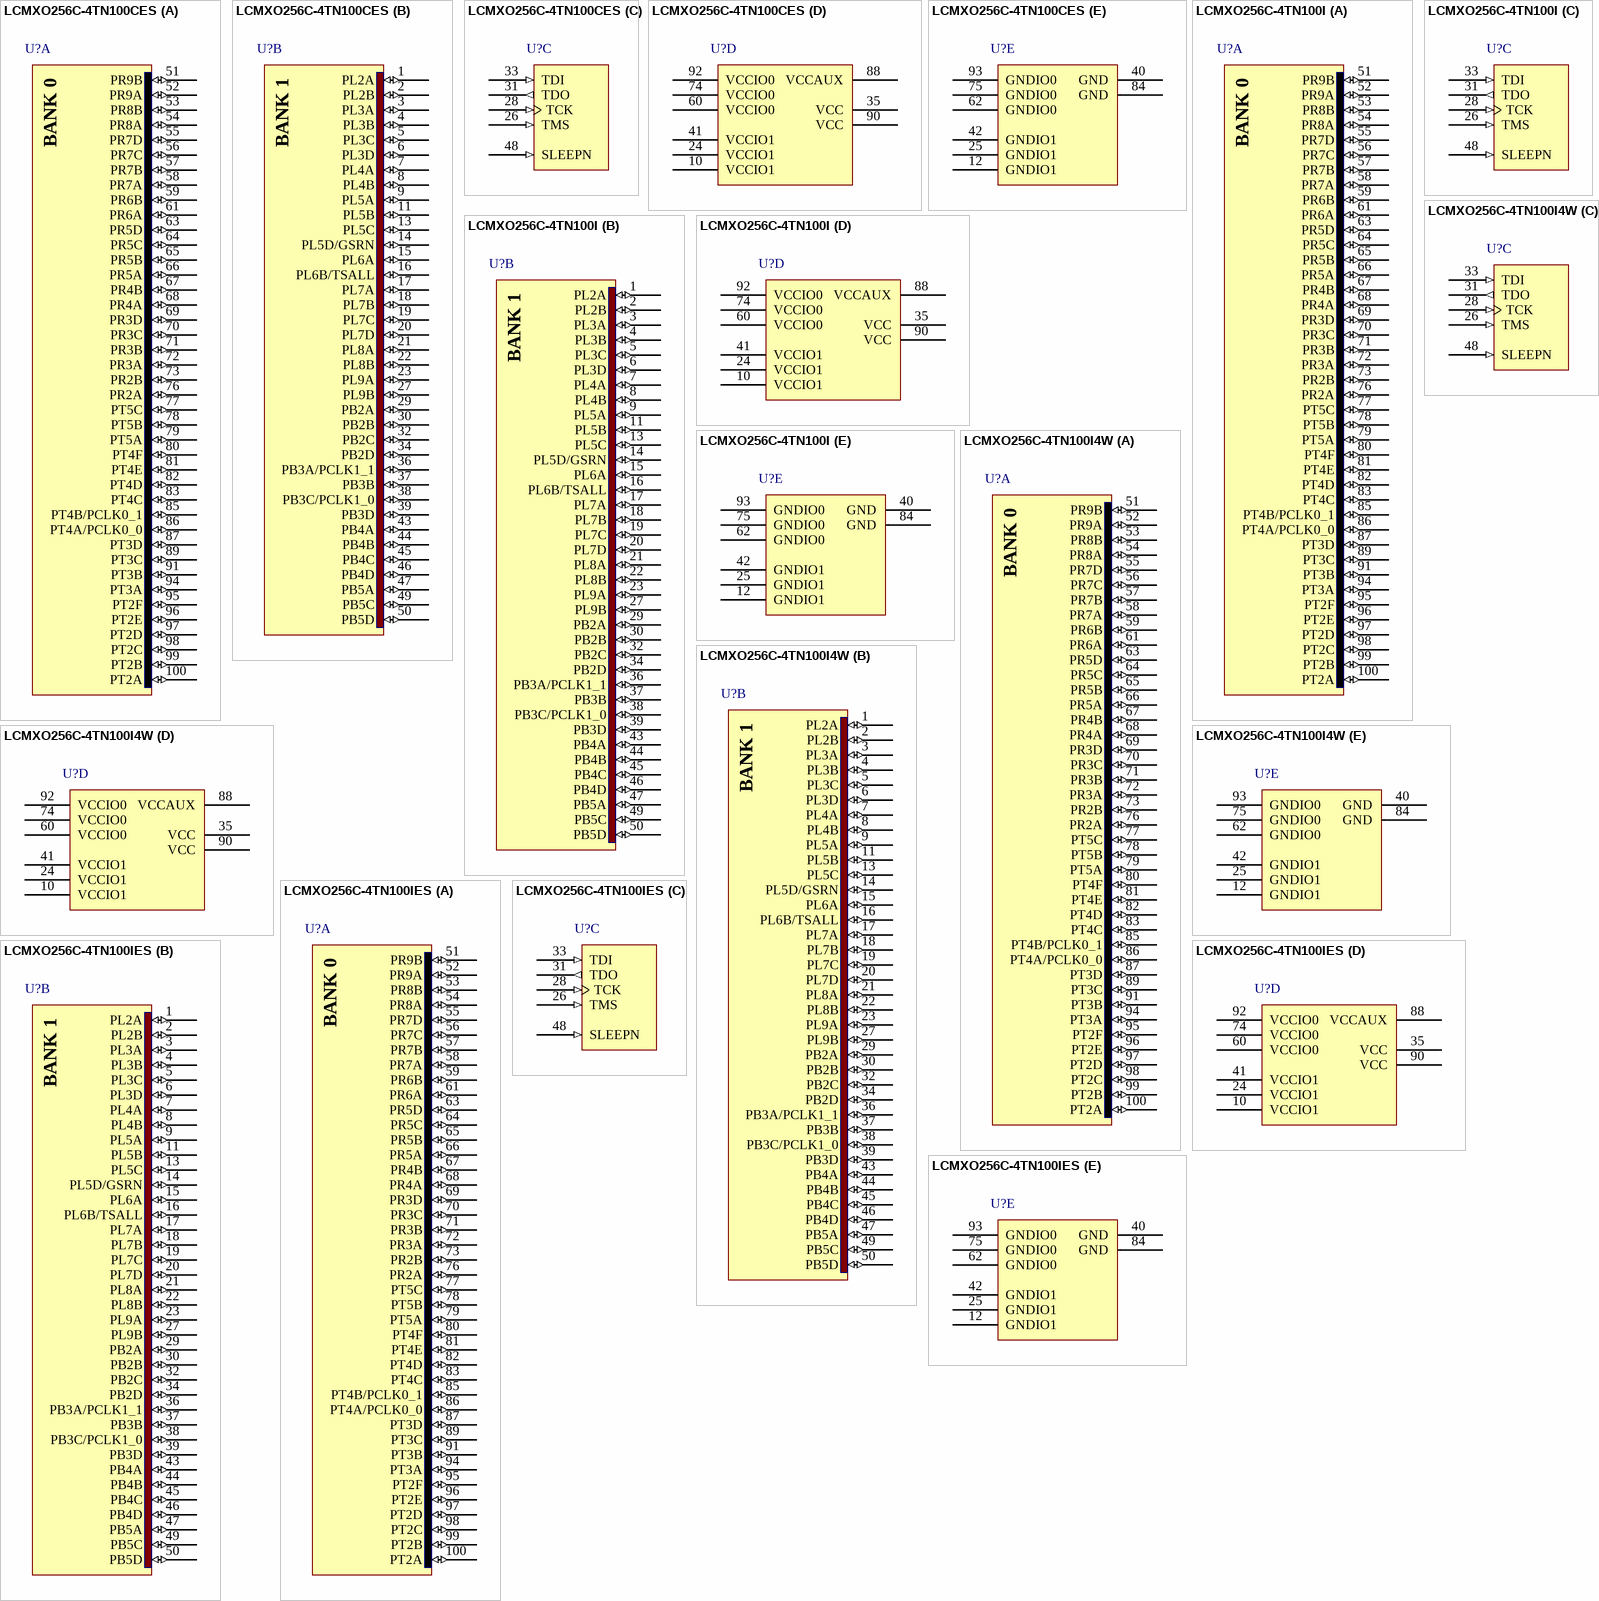
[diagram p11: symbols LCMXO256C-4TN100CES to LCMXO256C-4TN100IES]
## LCMXO256C-4TN100CES
designator U?
MachXO 256 Crossover PLD, 1.8V/2.5V/3.3V, 78 User I/Os, 100-Pins TQFP, Speed Grade-4, Commercial Grade, Pb-Free, Engineering Sample
footprint TQFP100_N (Thin QFP, 100-Leads, Body 14x14mm, Pitch 0.5mm, IPC Medium Density)
footprint TQFP100_L (Thin QFP, 100-Leads, Body 14x14mm, Pitch 0.5mm, IPC High Density)
footprint TQFP100_M (Thin QFP, 100-Leads, Body 14x14mm, Pitch 0.5mm, IPC Low Density)
3D model MachXO256-TQFP100 (100-Pin Thin Quad Flat Pack (TQFP100))
signal-integrity model LCMXO256C_T100 (MachXO)
part A pins: 51 PR9B (io), 52 PR9A (io), 53 PR8B (io), 54 PR8A (io), 55 PR7D (io), 56 PR7C (io), 57 PR7B (io), 58 PR7A (io), 59 PR6B (io), 61 PR6A (io), 63 PR5D (io), 64 PR5C (io), 65 PR5B (io), 66 PR5A (io), 67 PR4B (io), 68 PR4A (io), 69 PR3D (io), 70 PR3C (io), 71 PR3B (io), 72 PR3A (io), 73 PR2B (io), 76 PR2A (io), 77 PT5C (io), 78 PT5B (io), 79 PT5A (io), 80 PT4F (io), 81 PT4E (io), 82 PT4D (io), 83 PT4C (io), 85 PT4B/PCLK0_1 (io), 86 PT4A/PCLK0_0 (io), 87 PT3D (io), 89 PT3C (io), 91 PT3B (io), 94 PT3A (io), 95 PT2F (io), 96 PT2E (io), 97 PT2D (io), 98 PT2C (io), 99 PT2B (io), 100 PT2A (io)
part B pins: 1 PL2A (io), 2 PL2B (io), 3 PL3A (io), 4 PL3B (io), 5 PL3C (io), 6 PL3D (io), 7 PL4A (io), 8 PL4B (io), 9 PL5A (io), 11 PL5B (io), 13 PL5C (io), 14 PL5D/GSRN (io), 15 PL6A (io), 16 PL6B/TSALL (io), 17 PL7A (io), 18 PL7B (io), 19 PL7C (io), 20 PL7D (io), 21 PL8A (io), 22 PL8B (io), 23 PL9A (io), 27 PL9B (io), 29 PB2A (io), 30 PB2B (io), 32 PB2C (io), 34 PB2D (io), 36 PB3A/PCLK1_1 (io), 37 PB3B (io), 38 PB3C/PCLK1_0 (io), 39 PB3D (io), 43 PB4A (io), 44 PB4B (io), 45 PB4C (io), 46 PB4D (io), 47 PB5A (io), 49 PB5C (io), 50 PB5D (io)
part C pins: 26 TMS (in) "Powered by VCCIO1", 28 TCK (in) "Powered by VCCIO1", 31 TDO (out) "Powered by VCCIO1", 33 TDI (in) "Powered by VCCIO1", 48 SLEEPN (in) "Powered by VCCIO1"
part D pins: 10 VCCIO1 (power), 24 VCCIO1 (power), 35 VCC (power), 41 VCCIO1 (power), 60 VCCIO0 (power), 74 VCCIO0 (power), 88 VCCAUX (power), 90 VCC (power), 92 VCCIO0 (power)
part E pins: 12 GNDIO1 (power), 25 GNDIO1 (power), 40 GND (power), 42 GNDIO1 (power), 62 GNDIO0 (power), 75 GNDIO0 (power), 84 GND (power), 93 GNDIO0 (power)

## LCMXO256C-4TN100I
designator U?
MachXO 256 Crossover PLD, 1.8V/2.5V/3.3V, 78 User I/Os, 100-Pins TQFP, Speed Grade-4, Industrial Grade, Pb-Free
footprint TQFP100_N (Thin QFP, 100-Leads, Body 14x14mm, Pitch 0.5mm, IPC Medium Density)
footprint TQFP100_L (Thin QFP, 100-Leads, Body 14x14mm, Pitch 0.5mm, IPC High Density)
footprint TQFP100_M (Thin QFP, 100-Leads, Body 14x14mm, Pitch 0.5mm, IPC Low Density)
3D model MachXO256-TQFP100 (100-Pin Thin Quad Flat Pack (TQFP100))
signal-integrity model LCMXO256C_T100 (MachXO)
part A pins: 51 PR9B (io), 52 PR9A (io), 53 PR8B (io), 54 PR8A (io), 55 PR7D (io), 56 PR7C (io), 57 PR7B (io), 58 PR7A (io), 59 PR6B (io), 61 PR6A (io), 63 PR5D (io), 64 PR5C (io), 65 PR5B (io), 66 PR5A (io), 67 PR4B (io), 68 PR4A (io), 69 PR3D (io), 70 PR3C (io), 71 PR3B (io), 72 PR3A (io), 73 PR2B (io), 76 PR2A (io), 77 PT5C (io), 78 PT5B (io), 79 PT5A (io), 80 PT4F (io), 81 PT4E (io), 82 PT4D (io), 83 PT4C (io), 85 PT4B/PCLK0_1 (io), 86 PT4A/PCLK0_0 (io), 87 PT3D (io), 89 PT3C (io), 91 PT3B (io), 94 PT3A (io), 95 PT2F (io), 96 PT2E (io), 97 PT2D (io), 98 PT2C (io), 99 PT2B (io), 100 PT2A (io)
part B pins: 1 PL2A (io), 2 PL2B (io), 3 PL3A (io), 4 PL3B (io), 5 PL3C (io), 6 PL3D (io), 7 PL4A (io), 8 PL4B (io), 9 PL5A (io), 11 PL5B (io), 13 PL5C (io), 14 PL5D/GSRN (io), 15 PL6A (io), 16 PL6B/TSALL (io), 17 PL7A (io), 18 PL7B (io), 19 PL7C (io), 20 PL7D (io), 21 PL8A (io), 22 PL8B (io), 23 PL9A (io), 27 PL9B (io), 29 PB2A (io), 30 PB2B (io), 32 PB2C (io), 34 PB2D (io), 36 PB3A/PCLK1_1 (io), 37 PB3B (io), 38 PB3C/PCLK1_0 (io), 39 PB3D (io), 43 PB4A (io), 44 PB4B (io), 45 PB4C (io), 46 PB4D (io), 47 PB5A (io), 49 PB5C (io), 50 PB5D (io)
part C pins: 26 TMS (in) "Powered by VCCIO1", 28 TCK (in) "Powered by VCCIO1", 31 TDO (out) "Powered by VCCIO1", 33 TDI (in) "Powered by VCCIO1", 48 SLEEPN (in) "Powered by VCCIO1"
part D pins: 10 VCCIO1 (power), 24 VCCIO1 (power), 35 VCC (power), 41 VCCIO1 (power), 60 VCCIO0 (power), 74 VCCIO0 (power), 88 VCCAUX (power), 90 VCC (power), 92 VCCIO0 (power)
part E pins: 12 GNDIO1 (power), 25 GNDIO1 (power), 40 GND (power), 42 GNDIO1 (power), 62 GNDIO0 (power), 75 GNDIO0 (power), 84 GND (power), 93 GNDIO0 (power)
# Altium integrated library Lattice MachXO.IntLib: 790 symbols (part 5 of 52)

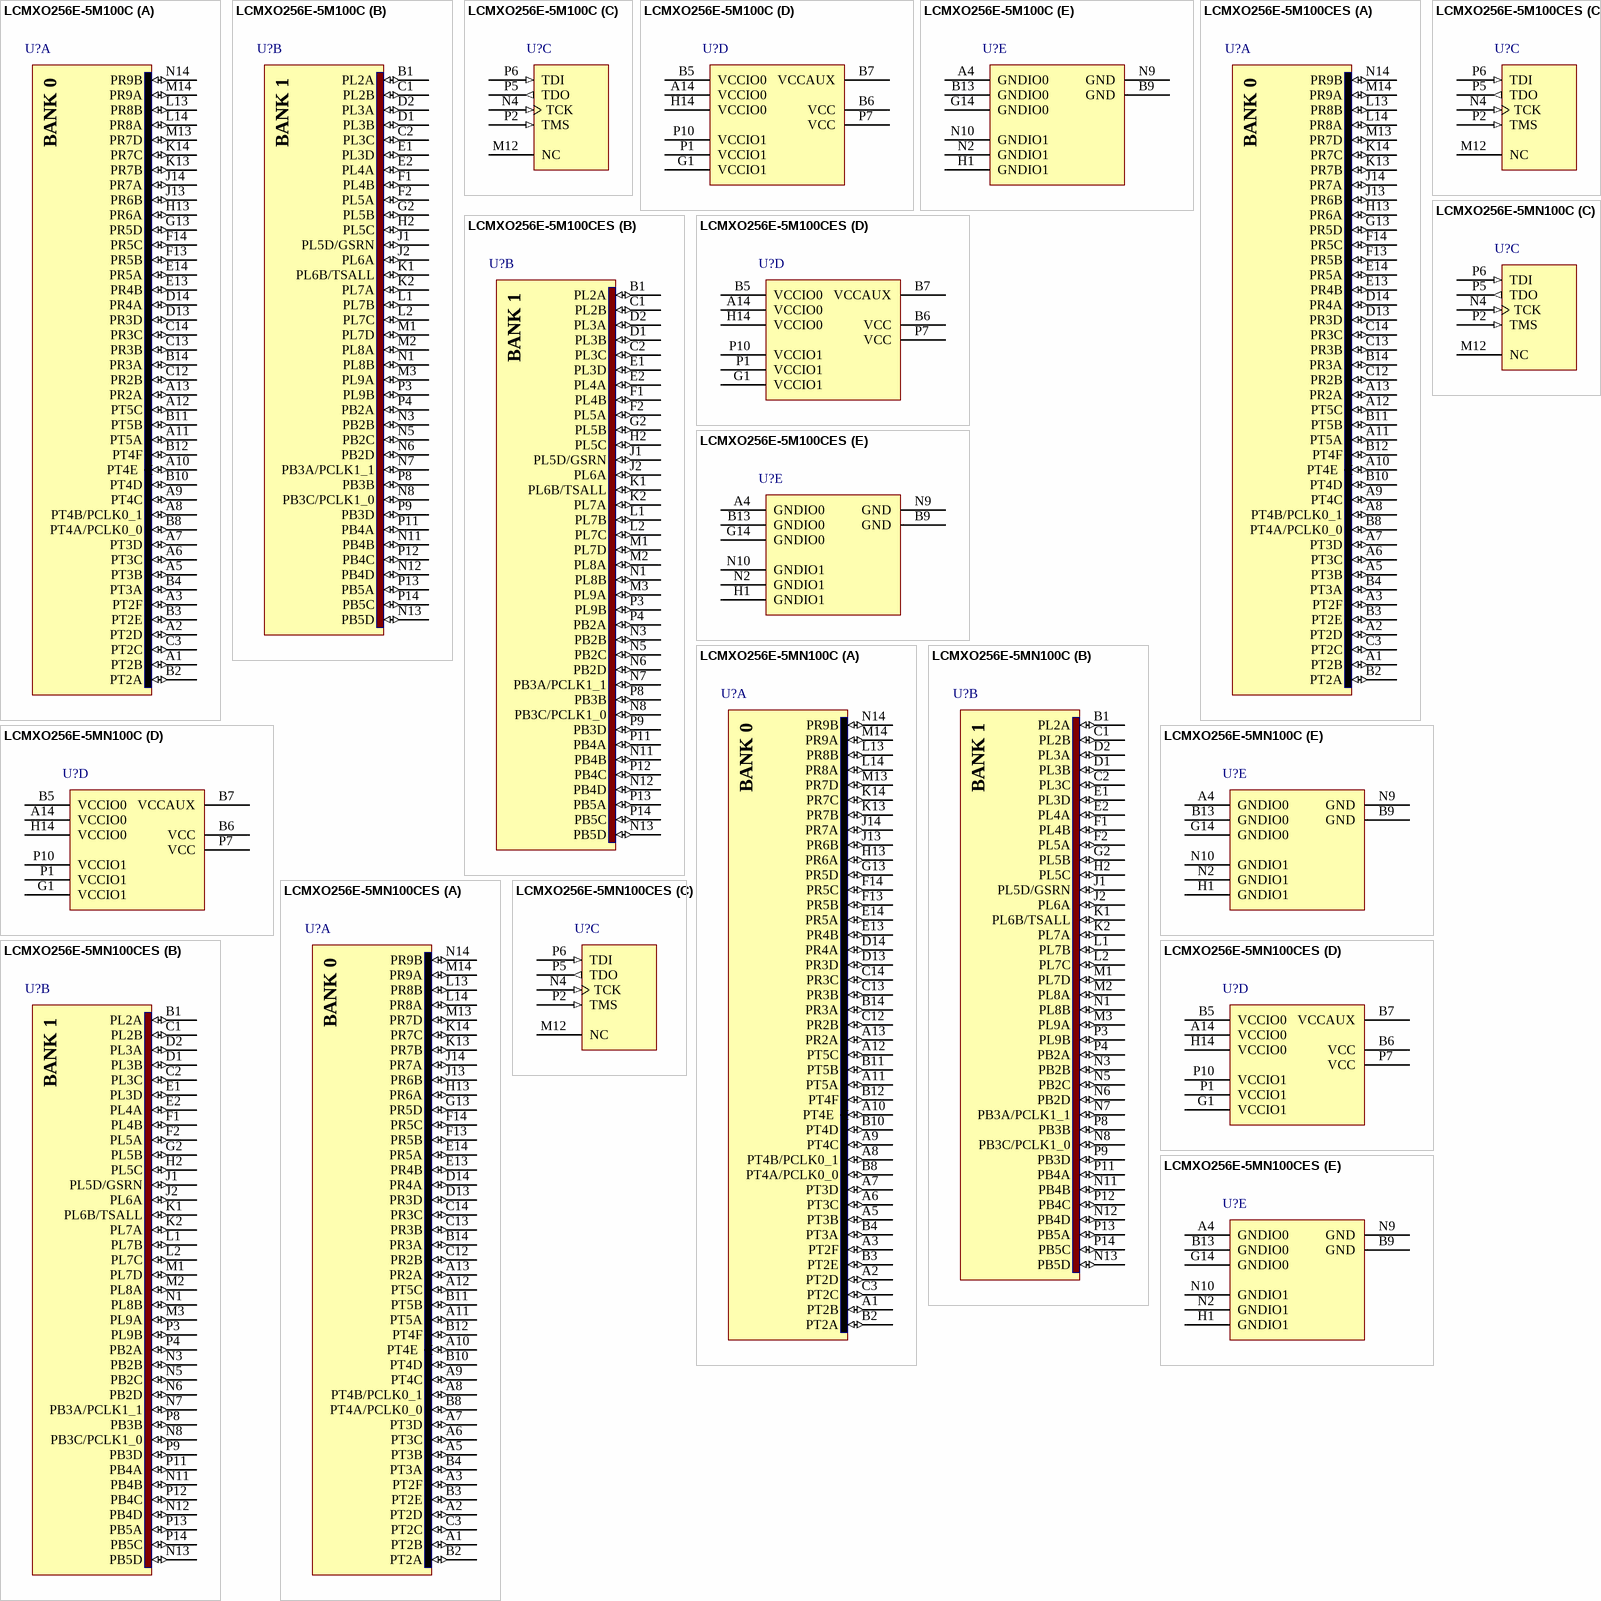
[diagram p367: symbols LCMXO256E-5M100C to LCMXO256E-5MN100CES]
## LCMXO256E-5M100C
designator U?
MachXO 256 Crossover PLD, 1.2V, 78 User I/Os, 100-Pins csBGA, Speed Grade-5, Commercial Grade
footprint csBGA100 (BGA, 100-Leads, Body 8x8mm, Pitch 0.5mm)
3D model MachXO256-csBGA100 (100-Ball Chip Scale Ball Grid Array (csBGA100))
signal-integrity model LCMXO256E_M100 (MachXO)
part A pins: A1 PT2B (io), A2 PT2D (io), A3 PT2F (io), A5 PT3B (io), A6 PT3C (io), A7 PT3D (io), A8 PT4B/PCLK0_1 (io), A9 PT4C (io), A10 PT4E (io), A11 PT5A (io), A12 PT5C (io), A13 PR2A (io), B2 PT2A (io), B3 PT2E (io), B4 PT3A (io), B8 PT4A/PCLK0_0 (io), B10 PT4D (io), B11 PT5B (io), B12 PT4F (io), B14 PR3A (io), C3 PT2C (io), C12 PR2B (io), C13 PR3B (io), C14 PR3C (io), D13 PR3D (io), D14 PR4A (io), E13 PR4B (io), E14 PR5A (io), F13 PR5B (io), F14 PR5C (io), G13 PR5D (io), H13 PR6A (io), J13 PR6B (io), J14 PR7A (io), K13 PR7B (io), K14 PR7C (io), L13 PR8B (io), L14 PR8A (io), M13 PR7D (io), M14 PR9A (io), N14 PR9B (io)
part B pins: B1 PL2A (io), C1 PL2B (io), C2 PL3C (io), D1 PL3B (io), D2 PL3A (io), E1 PL3D (io), E2 PL4A (io), F1 PL4B (io), F2 PL5A (io), G2 PL5B (io), H2 PL5C (io), J1 PL5D/GSRN (io), J2 PL6A (io), K1 PL6B/TSALL (io), K2 PL7A (io), L1 PL7B (io), L2 PL7C (io), M1 PL7D (io), M2 PL8A (io), M3 PL9A (io), N1 PL8B (io), N3 PB2B (io), N5 PB2C (io), N6 PB2D (io), N7 PB3A/PCLK1_1 (io), N8 PB3C/PCLK1_0 (io), N11 PB4B (io), N12 PB4D (io), N13 PB5D (io), P3 PL9B (io), P4 PB2A (io), P8 PB3B (io), P9 PB3D (io), P11 PB4A (io), P12 PB4C (io), P13 PB5A (io), P14 PB5C (io)
part C pins: M12 NC, N4 TCK (in) "Powered by VCCIO1", P2 TMS (in) "Powered by VCCIO1", P5 TDO (out) "Powered by VCCIO1", P6 TDI (in) "Powered by VCCIO1"
part D pins: A14 VCCIO0 (power), B5 VCCIO0 (power), B6 VCC (power), B7 VCCAUX (power), G1 VCCIO1 (power), H14 VCCIO0 (power), P1 VCCIO1 (power), P7 VCC (power), P10 VCCIO1 (power)
part E pins: A4 GNDIO0 (power), B9 GND (power), B13 GNDIO0 (power), G14 GNDIO0 (power), H1 GNDIO1 (power), N2 GNDIO1 (power), N9 GND (power), N10 GNDIO1 (power)

## LCMXO256E-5M100CES
designator U?
MachXO 256 Crossover PLD, 1.2V, 78 User I/Os, 100-Pins csBGA, Speed Grade-5, Commercial Grade, Engineering Sample
footprint csBGA100 (BGA, 100-Leads, Body 8x8mm, Pitch 0.5mm)
3D model MachXO256-csBGA100 (100-Ball Chip Scale Ball Grid Array (csBGA100))
signal-integrity model LCMXO256E_M100 (MachXO)
part A pins: A1 PT2B (io), A2 PT2D (io), A3 PT2F (io), A5 PT3B (io), A6 PT3C (io), A7 PT3D (io), A8 PT4B/PCLK0_1 (io), A9 PT4C (io), A10 PT4E (io), A11 PT5A (io), A12 PT5C (io), A13 PR2A (io), B2 PT2A (io), B3 PT2E (io), B4 PT3A (io), B8 PT4A/PCLK0_0 (io), B10 PT4D (io), B11 PT5B (io), B12 PT4F (io), B14 PR3A (io), C3 PT2C (io), C12 PR2B (io), C13 PR3B (io), C14 PR3C (io), D13 PR3D (io), D14 PR4A (io), E13 PR4B (io), E14 PR5A (io), F13 PR5B (io), F14 PR5C (io), G13 PR5D (io), H13 PR6A (io), J13 PR6B (io), J14 PR7A (io), K13 PR7B (io), K14 PR7C (io), L13 PR8B (io), L14 PR8A (io), M13 PR7D (io), M14 PR9A (io), N14 PR9B (io)
part B pins: B1 PL2A (io), C1 PL2B (io), C2 PL3C (io), D1 PL3B (io), D2 PL3A (io), E1 PL3D (io), E2 PL4A (io), F1 PL4B (io), F2 PL5A (io), G2 PL5B (io), H2 PL5C (io), J1 PL5D/GSRN (io), J2 PL6A (io), K1 PL6B/TSALL (io), K2 PL7A (io), L1 PL7B (io), L2 PL7C (io), M1 PL7D (io), M2 PL8A (io), M3 PL9A (io), N1 PL8B (io), N3 PB2B (io), N5 PB2C (io), N6 PB2D (io), N7 PB3A/PCLK1_1 (io), N8 PB3C/PCLK1_0 (io), N11 PB4B (io), N12 PB4D (io), N13 PB5D (io), P3 PL9B (io), P4 PB2A (io), P8 PB3B (io), P9 PB3D (io), P11 PB4A (io), P12 PB4C (io), P13 PB5A (io), P14 PB5C (io)
part C pins: M12 NC, N4 TCK (in) "Powered by VCCIO1", P2 TMS (in) "Powered by VCCIO1", P5 TDO (out) "Powered by VCCIO1", P6 TDI (in) "Powered by VCCIO1"
part D pins: A14 VCCIO0 (power), B5 VCCIO0 (power), B6 VCC (power), B7 VCCAUX (power), G1 VCCIO1 (power), H14 VCCIO0 (power), P1 VCCIO1 (power), P7 VCC (power), P10 VCCIO1 (power)
part E pins: A4 GNDIO0 (power), B9 GND (power), B13 GNDIO0 (power), G14 GNDIO0 (power), H1 GNDIO1 (power), N2 GNDIO1 (power), N9 GND (power), N10 GNDIO1 (power)

## LCMXO256E-5MN100C
designator U?
MachXO 256 Crossover PLD, 1.2V, 78 User I/Os, 100-Pins csBGA, Speed Grade-5, Commercial Grade, Pb-Free
footprint csBGA100 (BGA, 100-Leads, Body 8x8mm, Pitch 0.5mm)
3D model MachXO256-csBGA100 (100-Ball Chip Scale Ball Grid Array (csBGA100))
signal-integrity model LCMXO256E_M100 (MachXO)
part A pins: A1 PT2B (io), A2 PT2D (io), A3 PT2F (io), A5 PT3B (io), A6 PT3C (io), A7 PT3D (io), A8 PT4B/PCLK0_1 (io), A9 PT4C (io), A10 PT4E (io), A11 PT5A (io), A12 PT5C (io), A13 PR2A (io), B2 PT2A (io), B3 PT2E (io), B4 PT3A (io), B8 PT4A/PCLK0_0 (io), B10 PT4D (io), B11 PT5B (io), B12 PT4F (io), B14 PR3A (io), C3 PT2C (io), C12 PR2B (io), C13 PR3B (io), C14 PR3C (io), D13 PR3D (io), D14 PR4A (io), E13 PR4B (io), E14 PR5A (io), F13 PR5B (io), F14 PR5C (io), G13 PR5D (io), H13 PR6A (io), J13 PR6B (io), J14 PR7A (io), K13 PR7B (io), K14 PR7C (io), L13 PR8B (io), L14 PR8A (io), M13 PR7D (io), M14 PR9A (io), N14 PR9B (io)
part B pins: B1 PL2A (io), C1 PL2B (io), C2 PL3C (io), D1 PL3B (io), D2 PL3A (io), E1 PL3D (io), E2 PL4A (io), F1 PL4B (io), F2 PL5A (io), G2 PL5B (io), H2 PL5C (io), J1 PL5D/GSRN (io), J2 PL6A (io), K1 PL6B/TSALL (io), K2 PL7A (io), L1 PL7B (io), L2 PL7C (io), M1 PL7D (io), M2 PL8A (io), M3 PL9A (io), N1 PL8B (io), N3 PB2B (io), N5 PB2C (io), N6 PB2D (io), N7 PB3A/PCLK1_1 (io), N8 PB3C/PCLK1_0 (io), N11 PB4B (io), N12 PB4D (io), N13 PB5D (io), P3 PL9B (io), P4 PB2A (io), P8 PB3B (io), P9 PB3D (io), P11 PB4A (io), P12 PB4C (io), P13 PB5A (io), P14 PB5C (io)
part C pins: M12 NC, N4 TCK (in) "Powered by VCCIO1", P2 TMS (in) "Powered by VCCIO1", P5 TDO (out) "Powered by VCCIO1", P6 TDI (in) "Powered by VCCIO1"
part D pins: A14 VCCIO0 (power), B5 VCCIO0 (power), B6 VCC (power), B7 VCCAUX (power), G1 VCCIO1 (power), H14 VCCIO0 (power), P1 VCCIO1 (power), P7 VCC (power), P10 VCCIO1 (power)
part E pins: A4 GNDIO0 (power), B9 GND (power), B13 GNDIO0 (power), G14 GNDIO0 (power), H1 GNDIO1 (power), N2 GNDIO1 (power), N9 GND (power), N10 GNDIO1 (power)

## LCMXO256E-5MN100CES
designator U?
MachXO 256 Crossover PLD, 1.2V, 78 User I/Os, 100-Pins csBGA, Speed Grade-5, Commercial Grade, Pb-Free, Engineering Sample
footprint csBGA100 (BGA, 100-Leads, Body 8x8mm, Pitch 0.5mm)
3D model MachXO256-csBGA100 (100-Ball Chip Scale Ball Grid Array (csBGA100))
signal-integrity model LCMXO256E_M100 (MachXO)
part A pins: A1 PT2B (io), A2 PT2D (io), A3 PT2F (io), A5 PT3B (io), A6 PT3C (io), A7 PT3D (io), A8 PT4B/PCLK0_1 (io), A9 PT4C (io), A10 PT4E (io), A11 PT5A (io), A12 PT5C (io), A13 PR2A (io), B2 PT2A (io), B3 PT2E (io), B4 PT3A (io), B8 PT4A/PCLK0_0 (io), B10 PT4D (io), B11 PT5B (io), B12 PT4F (io), B14 PR3A (io), C3 PT2C (io), C12 PR2B (io), C13 PR3B (io), C14 PR3C (io), D13 PR3D (io), D14 PR4A (io), E13 PR4B (io), E14 PR5A (io), F13 PR5B (io), F14 PR5C (io), G13 PR5D (io), H13 PR6A (io), J13 PR6B (io), J14 PR7A (io), K13 PR7B (io), K14 PR7C (io), L13 PR8B (io), L14 PR8A (io), M13 PR7D (io), M14 PR9A (io), N14 PR9B (io)
part B pins: B1 PL2A (io), C1 PL2B (io), C2 PL3C (io), D1 PL3B (io), D2 PL3A (io), E1 PL3D (io), E2 PL4A (io), F1 PL4B (io), F2 PL5A (io), G2 PL5B (io), H2 PL5C (io), J1 PL5D/GSRN (io), J2 PL6A (io), K1 PL6B/TSALL (io), K2 PL7A (io), L1 PL7B (io), L2 PL7C (io), M1 PL7D (io), M2 PL8A (io), M3 PL9A (io), N1 PL8B (io), N3 PB2B (io), N5 PB2C (io), N6 PB2D (io), N7 PB3A/PCLK1_1 (io), N8 PB3C/PCLK1_0 (io), N11 PB4B (io), N12 PB4D (io), N13 PB5D (io), P3 PL9B (io), P4 PB2A (io), P8 PB3B (io), P9 PB3D (io), P11 PB4A (io), P12 PB4C (io), P13 PB5A (io), P14 PB5C (io)
part C pins: M12 NC, N4 TCK (in) "Powered by VCCIO1", P2 TMS (in) "Powered by VCCIO1", P5 TDO (out) "Powered by VCCIO1", P6 TDI (in) "Powered by VCCIO1"
part D pins: A14 VCCIO0 (power), B5 VCCIO0 (power), B6 VCC (power), B7 VCCAUX (power), G1 VCCIO1 (power), H14 VCCIO0 (power), P1 VCCIO1 (power), P7 VCC (power), P10 VCCIO1 (power)
part E pins: A4 GNDIO0 (power), B9 GND (power), B13 GNDIO0 (power), G14 GNDIO0 (power), H1 GNDIO1 (power), N2 GNDIO1 (power), N9 GND (power), N10 GNDIO1 (power)


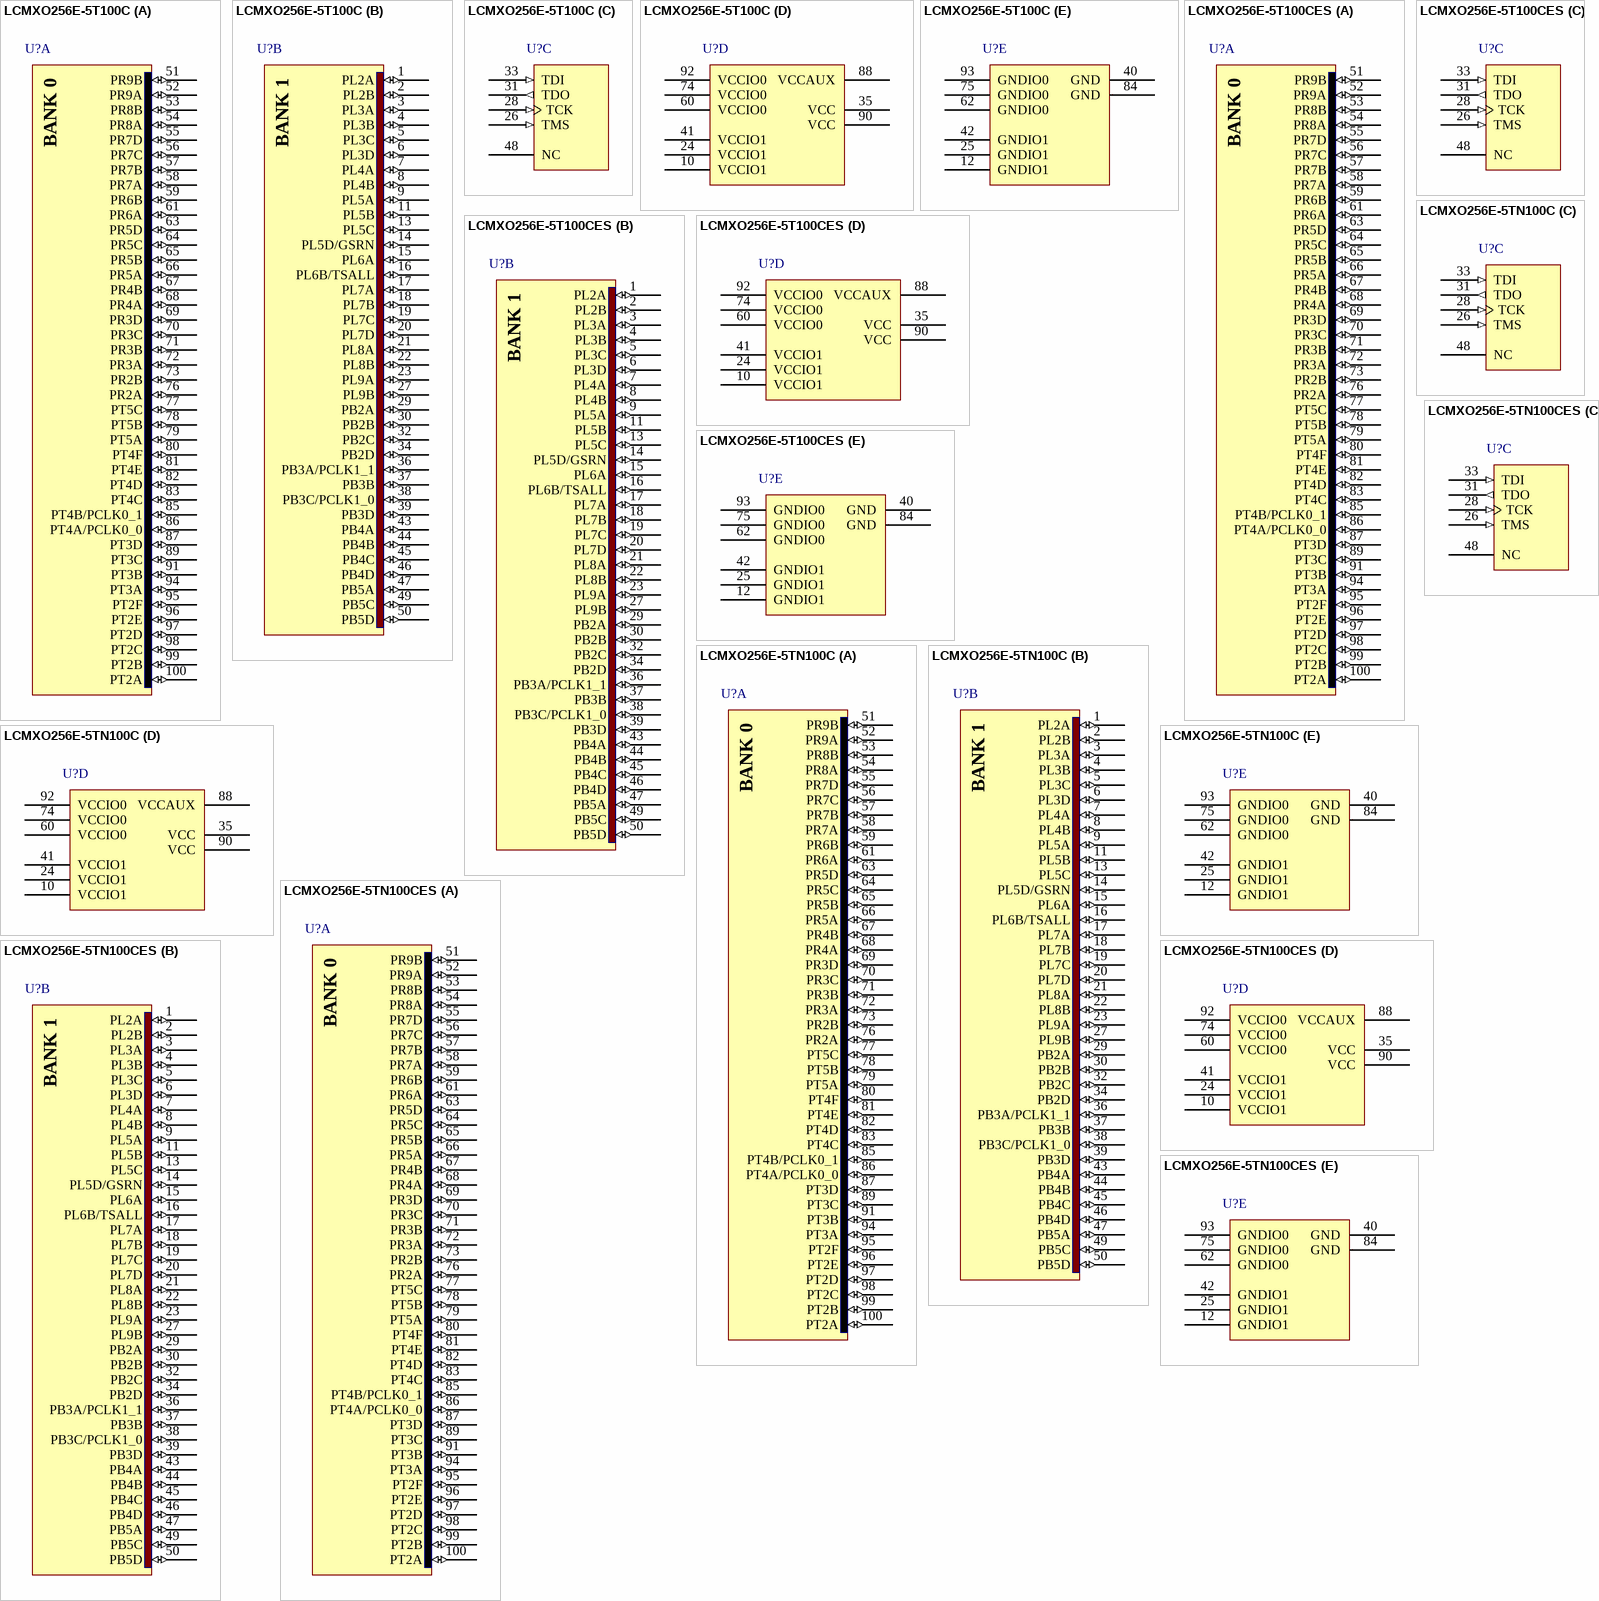
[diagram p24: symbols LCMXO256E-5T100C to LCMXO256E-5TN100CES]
## LCMXO256E-5T100C
designator U?
MachXO 256 Crossover PLD, 1.2V, 78 User I/Os, 100-Pins TQFP, Speed Grade-5, Commercial Grade
footprint TQFP100_N (Thin QFP, 100-Leads, Body 14x14mm, Pitch 0.5mm, IPC Medium Density)
footprint TQFP100_L (Thin QFP, 100-Leads, Body 14x14mm, Pitch 0.5mm, IPC High Density)
footprint TQFP100_M (Thin QFP, 100-Leads, Body 14x14mm, Pitch 0.5mm, IPC Low Density)
3D model MachXO256-TQFP100 (100-Pin Thin Quad Flat Pack (TQFP100))
signal-integrity model LCMXO256E_T100 (MachXO)
part A pins: 51 PR9B (io), 52 PR9A (io), 53 PR8B (io), 54 PR8A (io), 55 PR7D (io), 56 PR7C (io), 57 PR7B (io), 58 PR7A (io), 59 PR6B (io), 61 PR6A (io), 63 PR5D (io), 64 PR5C (io), 65 PR5B (io), 66 PR5A (io), 67 PR4B (io), 68 PR4A (io), 69 PR3D (io), 70 PR3C (io), 71 PR3B (io), 72 PR3A (io), 73 PR2B (io), 76 PR2A (io), 77 PT5C (io), 78 PT5B (io), 79 PT5A (io), 80 PT4F (io), 81 PT4E (io), 82 PT4D (io), 83 PT4C (io), 85 PT4B/PCLK0_1 (io), 86 PT4A/PCLK0_0 (io), 87 PT3D (io), 89 PT3C (io), 91 PT3B (io), 94 PT3A (io), 95 PT2F (io), 96 PT2E (io), 97 PT2D (io), 98 PT2C (io), 99 PT2B (io), 100 PT2A (io)
part B pins: 1 PL2A (io), 2 PL2B (io), 3 PL3A (io), 4 PL3B (io), 5 PL3C (io), 6 PL3D (io), 7 PL4A (io), 8 PL4B (io), 9 PL5A (io), 11 PL5B (io), 13 PL5C (io), 14 PL5D/GSRN (io), 15 PL6A (io), 16 PL6B/TSALL (io), 17 PL7A (io), 18 PL7B (io), 19 PL7C (io), 20 PL7D (io), 21 PL8A (io), 22 PL8B (io), 23 PL9A (io), 27 PL9B (io), 29 PB2A (io), 30 PB2B (io), 32 PB2C (io), 34 PB2D (io), 36 PB3A/PCLK1_1 (io), 37 PB3B (io), 38 PB3C/PCLK1_0 (io), 39 PB3D (io), 43 PB4A (io), 44 PB4B (io), 45 PB4C (io), 46 PB4D (io), 47 PB5A (io), 49 PB5C (io), 50 PB5D (io)
part C pins: 26 TMS (in) "Powered by VCCIO1", 28 TCK (in) "Powered by VCCIO1", 31 TDO (out) "Powered by VCCIO1", 33 TDI (in) "Powered by VCCIO1", 48 NC
part D pins: 10 VCCIO1 (power), 24 VCCIO1 (power), 35 VCC (power), 41 VCCIO1 (power), 60 VCCIO0 (power), 74 VCCIO0 (power), 88 VCCAUX (power), 90 VCC (power), 92 VCCIO0 (power)
part E pins: 12 GNDIO1 (power), 25 GNDIO1 (power), 40 GND (power), 42 GNDIO1 (power), 62 GNDIO0 (power), 75 GNDIO0 (power), 84 GND (power), 93 GNDIO0 (power)

## LCMXO256E-5T100CES
designator U?
MachXO 256 Crossover PLD, 1.2V, 78 User I/Os, 100-Pins TQFP, Speed Grade-5, Commercial Grade, Engineering Sample
footprint TQFP100_N (Thin QFP, 100-Leads, Body 14x14mm, Pitch 0.5mm, IPC Medium Density)
footprint TQFP100_L (Thin QFP, 100-Leads, Body 14x14mm, Pitch 0.5mm, IPC High Density)
footprint TQFP100_M (Thin QFP, 100-Leads, Body 14x14mm, Pitch 0.5mm, IPC Low Density)
3D model MachXO256-TQFP100 (100-Pin Thin Quad Flat Pack (TQFP100))
signal-integrity model LCMXO256E_T100 (MachXO)
part A pins: 51 PR9B (io), 52 PR9A (io), 53 PR8B (io), 54 PR8A (io), 55 PR7D (io), 56 PR7C (io), 57 PR7B (io), 58 PR7A (io), 59 PR6B (io), 61 PR6A (io), 63 PR5D (io), 64 PR5C (io), 65 PR5B (io), 66 PR5A (io), 67 PR4B (io), 68 PR4A (io), 69 PR3D (io), 70 PR3C (io), 71 PR3B (io), 72 PR3A (io), 73 PR2B (io), 76 PR2A (io), 77 PT5C (io), 78 PT5B (io), 79 PT5A (io), 80 PT4F (io), 81 PT4E (io), 82 PT4D (io), 83 PT4C (io), 85 PT4B/PCLK0_1 (io), 86 PT4A/PCLK0_0 (io), 87 PT3D (io), 89 PT3C (io), 91 PT3B (io), 94 PT3A (io), 95 PT2F (io), 96 PT2E (io), 97 PT2D (io), 98 PT2C (io), 99 PT2B (io), 100 PT2A (io)
part B pins: 1 PL2A (io), 2 PL2B (io), 3 PL3A (io), 4 PL3B (io), 5 PL3C (io), 6 PL3D (io), 7 PL4A (io), 8 PL4B (io), 9 PL5A (io), 11 PL5B (io), 13 PL5C (io), 14 PL5D/GSRN (io), 15 PL6A (io), 16 PL6B/TSALL (io), 17 PL7A (io), 18 PL7B (io), 19 PL7C (io), 20 PL7D (io), 21 PL8A (io), 22 PL8B (io), 23 PL9A (io), 27 PL9B (io), 29 PB2A (io), 30 PB2B (io), 32 PB2C (io), 34 PB2D (io), 36 PB3A/PCLK1_1 (io), 37 PB3B (io), 38 PB3C/PCLK1_0 (io), 39 PB3D (io), 43 PB4A (io), 44 PB4B (io), 45 PB4C (io), 46 PB4D (io), 47 PB5A (io), 49 PB5C (io), 50 PB5D (io)
part C pins: 26 TMS (in) "Powered by VCCIO1", 28 TCK (in) "Powered by VCCIO1", 31 TDO (out) "Powered by VCCIO1", 33 TDI (in) "Powered by VCCIO1", 48 NC
part D pins: 10 VCCIO1 (power), 24 VCCIO1 (power), 35 VCC (power), 41 VCCIO1 (power), 60 VCCIO0 (power), 74 VCCIO0 (power), 88 VCCAUX (power), 90 VCC (power), 92 VCCIO0 (power)
part E pins: 12 GNDIO1 (power), 25 GNDIO1 (power), 40 GND (power), 42 GNDIO1 (power), 62 GNDIO0 (power), 75 GNDIO0 (power), 84 GND (power), 93 GNDIO0 (power)

## LCMXO256E-5TN100C
designator U?
MachXO 256 Crossover PLD, 1.2V, 78 User I/Os, 100-Pins TQFP, Speed Grade-5, Commercial Grade, Pb-Free
footprint TQFP100_N (Thin QFP, 100-Leads, Body 14x14mm, Pitch 0.5mm, IPC Medium Density)
footprint TQFP100_L (Thin QFP, 100-Leads, Body 14x14mm, Pitch 0.5mm, IPC High Density)
footprint TQFP100_M (Thin QFP, 100-Leads, Body 14x14mm, Pitch 0.5mm, IPC Low Density)
3D model MachXO256-TQFP100 (100-Pin Thin Quad Flat Pack (TQFP100))
signal-integrity model LCMXO256E_T100 (MachXO)
part A pins: 51 PR9B (io), 52 PR9A (io), 53 PR8B (io), 54 PR8A (io), 55 PR7D (io), 56 PR7C (io), 57 PR7B (io), 58 PR7A (io), 59 PR6B (io), 61 PR6A (io), 63 PR5D (io), 64 PR5C (io), 65 PR5B (io), 66 PR5A (io), 67 PR4B (io), 68 PR4A (io), 69 PR3D (io), 70 PR3C (io), 71 PR3B (io), 72 PR3A (io), 73 PR2B (io), 76 PR2A (io), 77 PT5C (io), 78 PT5B (io), 79 PT5A (io), 80 PT4F (io), 81 PT4E (io), 82 PT4D (io), 83 PT4C (io), 85 PT4B/PCLK0_1 (io), 86 PT4A/PCLK0_0 (io), 87 PT3D (io), 89 PT3C (io), 91 PT3B (io), 94 PT3A (io), 95 PT2F (io), 96 PT2E (io), 97 PT2D (io), 98 PT2C (io), 99 PT2B (io), 100 PT2A (io)
part B pins: 1 PL2A (io), 2 PL2B (io), 3 PL3A (io), 4 PL3B (io), 5 PL3C (io), 6 PL3D (io), 7 PL4A (io), 8 PL4B (io), 9 PL5A (io), 11 PL5B (io), 13 PL5C (io), 14 PL5D/GSRN (io), 15 PL6A (io), 16 PL6B/TSALL (io), 17 PL7A (io), 18 PL7B (io), 19 PL7C (io), 20 PL7D (io), 21 PL8A (io), 22 PL8B (io), 23 PL9A (io), 27 PL9B (io), 29 PB2A (io), 30 PB2B (io), 32 PB2C (io), 34 PB2D (io), 36 PB3A/PCLK1_1 (io), 37 PB3B (io), 38 PB3C/PCLK1_0 (io), 39 PB3D (io), 43 PB4A (io), 44 PB4B (io), 45 PB4C (io), 46 PB4D (io), 47 PB5A (io), 49 PB5C (io), 50 PB5D (io)
part C pins: 26 TMS (in) "Powered by VCCIO1", 28 TCK (in) "Powered by VCCIO1", 31 TDO (out) "Powered by VCCIO1", 33 TDI (in) "Powered by VCCIO1", 48 NC
part D pins: 10 VCCIO1 (power), 24 VCCIO1 (power), 35 VCC (power), 41 VCCIO1 (power), 60 VCCIO0 (power), 74 VCCIO0 (power), 88 VCCAUX (power), 90 VCC (power), 92 VCCIO0 (power)
part E pins: 12 GNDIO1 (power), 25 GNDIO1 (power), 40 GND (power), 42 GNDIO1 (power), 62 GNDIO0 (power), 75 GNDIO0 (power), 84 GND (power), 93 GNDIO0 (power)

## LCMXO256E-5TN100CES
designator U?
MachXO 256 Crossover PLD, 1.2V, 78 User I/Os, 100-Pins TQFP, Speed Grade-5, Commercial Grade, Pb-Free, Engineering Sample
footprint TQFP100_N (Thin QFP, 100-Leads, Body 14x14mm, Pitch 0.5mm, IPC Medium Density)
footprint TQFP100_L (Thin QFP, 100-Leads, Body 14x14mm, Pitch 0.5mm, IPC High Density)
footprint TQFP100_M (Thin QFP, 100-Leads, Body 14x14mm, Pitch 0.5mm, IPC Low Density)
3D model MachXO256-TQFP100 (100-Pin Thin Quad Flat Pack (TQFP100))
signal-integrity model LCMXO256E_T100 (MachXO)
part A pins: 51 PR9B (io), 52 PR9A (io), 53 PR8B (io), 54 PR8A (io), 55 PR7D (io), 56 PR7C (io), 57 PR7B (io), 58 PR7A (io), 59 PR6B (io), 61 PR6A (io), 63 PR5D (io), 64 PR5C (io), 65 PR5B (io), 66 PR5A (io), 67 PR4B (io), 68 PR4A (io), 69 PR3D (io), 70 PR3C (io), 71 PR3B (io), 72 PR3A (io), 73 PR2B (io), 76 PR2A (io), 77 PT5C (io), 78 PT5B (io), 79 PT5A (io), 80 PT4F (io), 81 PT4E (io), 82 PT4D (io), 83 PT4C (io), 85 PT4B/PCLK0_1 (io), 86 PT4A/PCLK0_0 (io), 87 PT3D (io), 89 PT3C (io), 91 PT3B (io), 94 PT3A (io), 95 PT2F (io), 96 PT2E (io), 97 PT2D (io), 98 PT2C (io), 99 PT2B (io), 100 PT2A (io)
part B pins: 1 PL2A (io), 2 PL2B (io), 3 PL3A (io), 4 PL3B (io), 5 PL3C (io), 6 PL3D (io), 7 PL4A (io), 8 PL4B (io), 9 PL5A (io), 11 PL5B (io), 13 PL5C (io), 14 PL5D/GSRN (io), 15 PL6A (io), 16 PL6B/TSALL (io), 17 PL7A (io), 18 PL7B (io), 19 PL7C (io), 20 PL7D (io), 21 PL8A (io), 22 PL8B (io), 23 PL9A (io), 27 PL9B (io), 29 PB2A (io), 30 PB2B (io), 32 PB2C (io), 34 PB2D (io), 36 PB3A/PCLK1_1 (io), 37 PB3B (io), 38 PB3C/PCLK1_0 (io), 39 PB3D (io), 43 PB4A (io), 44 PB4B (io), 45 PB4C (io), 46 PB4D (io), 47 PB5A (io), 49 PB5C (io), 50 PB5D (io)
part C pins: 26 TMS (in) "Powered by VCCIO1", 28 TCK (in) "Powered by VCCIO1", 31 TDO (out) "Powered by VCCIO1", 33 TDI (in) "Powered by VCCIO1", 48 NC
part D pins: 10 VCCIO1 (power), 24 VCCIO1 (power), 35 VCC (power), 41 VCCIO1 (power), 60 VCCIO0 (power), 74 VCCIO0 (power), 88 VCCAUX (power), 90 VCC (power), 92 VCCIO0 (power)
part E pins: 12 GNDIO1 (power), 25 GNDIO1 (power), 40 GND (power), 42 GNDIO1 (power), 62 GNDIO0 (power), 75 GNDIO0 (power), 84 GND (power), 93 GNDIO0 (power)


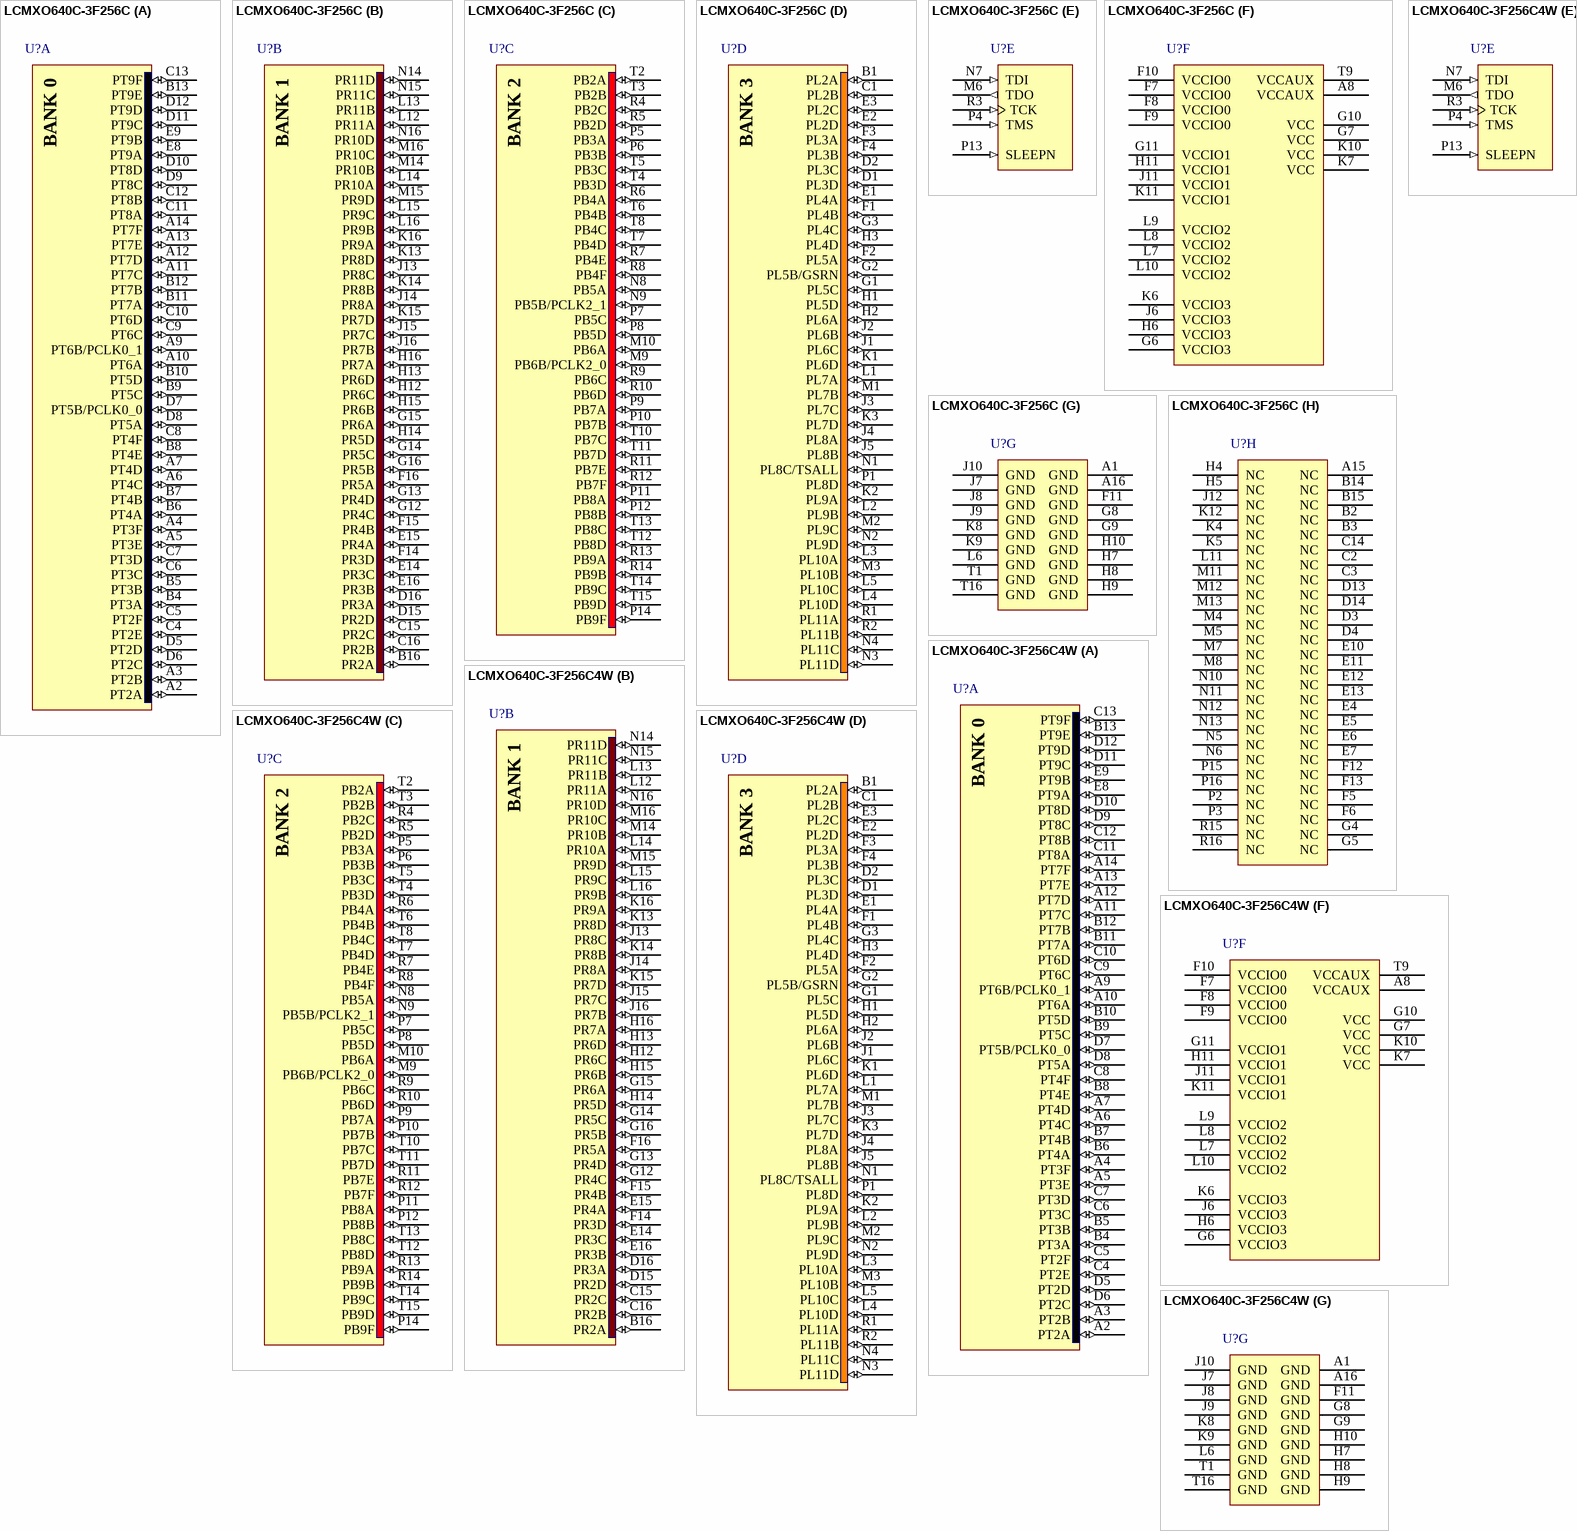
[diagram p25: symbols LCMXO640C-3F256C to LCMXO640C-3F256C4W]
## LCMXO640C-3F256C
designator U?
MachXO 640 Crossover PLD, 1.8V/2.5V/3.3V, 159 User I/Os, 256-Pins fpBGA, Speed Grade-3, Commercial Grade; ComponentAvailability: Not recommended for new designs. Use ftBGA package device.
footprint fpBGA256 (BGA, 256-Leads, Body 17x17mm, Pitch 1mm)
3D model MachXO640-fpBGA256 (256-Ball Fine Pitch Ball Grid Array (fpBGA256))
signal-integrity model LCMXO640C_F256 (MachXO)
part A pins: A2 PT2A (io), A3 PT2B (io), A4 PT3F (io), A5 PT3E (io), A6 PT4C (io), A7 PT4D (io), A9 PT6B/PCLK0_1 (io), A10 PT6A (io), A11 PT7C (io), A12 PT7D (io), A13 PT7E (io), A14 PT7F (io), B4 PT3A (io), B5 PT3B (io), B6 PT4A (io), B7 PT4B (io), B8 PT4E (io), B9 PT5C (io), B10 PT5D (io), B11 PT7A (io), B12 PT7B (io), B13 PT9E (io), C4 PT2E (io), C5 PT2F (io), C6 PT3C (io), C7 PT3D (io), C8 PT4F (io), C9 PT6C (io), C10 PT6D (io), C11 PT8A (io), C12 PT8B (io), C13 PT9F (io), D5 PT2D (io), D6 PT2C (io), D7 PT5B/PCLK0_0 (io), D8 PT5A (io), D9 PT8C (io), D10 PT8D (io), D11 PT9C (io), D12 PT9D (io), E8 PT9A (io), E9 PT9B (io)
part B pins: B16 PR2A (io), C15 PR2C (io), C16 PR2B (io), D15 PR2D (io), D16 PR3A (io), E14 PR3C (io), E15 PR4A (io), E16 PR3B (io), F14 PR3D (io), F15 PR4B (io), F16 PR5A (io), G12 PR4C (io), G13 PR4D (io), G14 PR5C (io), G15 PR6A (io), G16 PR5B (io), H12 PR6C (io), H13 PR6D (io), H14 PR5D (io), H15 PR6B (io), H16 PR7A (io), J13 PR8C (io), J14 PR8A (io), J15 PR7C (io), J16 PR7B (io), K13 PR8D (io), K14 PR8B (io), K15 PR7D (io), K16 PR9A (io), L12 PR11A (io), L13 PR11B (io), L14 PR10A (io), L15 PR9C (io), L16 PR9B (io), M14 PR10B (io), M15 PR9D (io), M16 PR10C (io), N14 PR11D (io), N15 PR11C (io), N16 PR10D (io)
part C pins: M9 PB6B/PCLK2_0 (io), M10 PB6A (io), N8 PB5A (io), N9 PB5B/PCLK2_1 (io), P5 PB3A (io), P6 PB3B (io), P7 PB5C (io), P8 PB5D (io), P9 PB7A (io), P10 PB7B (io), P11 PB8A (io), P12 PB8B (io), P14 PB9F (io), R4 PB2C (io), R5 PB2D (io), R6 PB4A (io), R7 PB4E (io), R8 PB4F (io), R9 PB6C (io), R10 PB6D (io), R11 PB7E (io), R12 PB7F (io), R13 PB9A (io), R14 PB9B (io), T2 PB2A (io), T3 PB2B (io), T4 PB3D (io), T5 PB3C (io), T6 PB4B (io), T7 PB4D (io), T8 PB4C (io), T10 PB7C (io), T11 PB7D (io), T12 PB8D (io), T13 PB8C (io), T14 PB9C (io), T15 PB9D (io)
part D pins: B1 PL2A (io), C1 PL2B (io), D1 PL3D (io), D2 PL3C (io), E1 PL4A (io), E2 PL2D (io), E3 PL2C (io), F1 PL4B (io), F2 PL5A (io), F3 PL3A (io), F4 PL3B (io), G1 PL5C (io), G2 PL5B/GSRN (io), G3 PL4C (io), H1 PL5D (io), H2 PL6A (io), H3 PL4D (io), J1 PL6C (io), J2 PL6B (io), J3 PL7C (io), J4 PL8A (io), J5 PL8B (io), K1 PL6D (io), K2 PL9A (io), K3 PL7D (io), L1 PL7A (io), L2 PL9B (io), L3 PL10A (io), L4 PL10D (io), L5 PL10C (io), M1 PL7B (io), M2 PL9C (io), M3 PL10B (io), N1 PL8C/TSALL (io), N2 PL9D (io), N3 PL11D (io), N4 PL11C (io), P1 PL8D (io), R1 PL11A (io), R2 PL11B (io)
part E pins: M6 TDO (out) "Powered by VCCIO2", N7 TDI (in) "Powered by VCCIO2", P4 TMS (in) "Powered by VCCIO2", P13 SLEEPN (in) "Powered by VCCIO2", R3 TCK (in) "Powered by VCCIO2"
part F pins: A8 VCCAUX (power), F7 VCCIO0 (power), F8 VCCIO0 (power), F9 VCCIO0 (power), F10 VCCIO0 (power), G6 VCCIO3 (power), G7 VCC (power), G10 VCC (power), G11 VCCIO1 (power), H6 VCCIO3 (power), H11 VCCIO1 (power), J6 VCCIO3 (power), J11 VCCIO1 (power), K6 VCCIO3 (power), K7 VCC (power), K10 VCC (power), K11 VCCIO1 (power), L7 VCCIO2 (power), L8 VCCIO2 (power), L9 VCCIO2 (power), L10 VCCIO2 (power), T9 VCCAUX (power)
part G pins: A1 GND (power), A16 GND (power), F11 GND (power), G8 GND (power), G9 GND (power), H7 GND (power), H8 GND (power), H9 GND (power), H10 GND (power), J7 GND (power), J8 GND (power), J9 GND (power), J10 GND (power), K8 GND (power), K9 GND (power), L6 GND (power), T1 GND (power), T16 GND (power)
part H pins: A15 NC, B2 NC, B3 NC, B14 NC, B15 NC, C2 NC, C3 NC, C14 NC, D3 NC, D4 NC, D13 NC, D14 NC, E4 NC, E5 NC, E6 NC, E7 NC, E10 NC, E11 NC, E12 NC, E13 NC, F5 NC, F6 NC, F12 NC, F13 NC, G4 NC, G5 NC, H4 NC, H5 NC, J12 NC, K4 NC, K5 NC, K12 NC, L11 NC, M4 NC, M5 NC, M7 NC, M8 NC, M11 NC, M12 NC, M13 NC, N5 NC, N6 NC, N10 NC, N11 NC, N12 NC, N13 NC, P2 NC, P3 NC, P15 NC, P16 NC, R15 NC, R16 NC


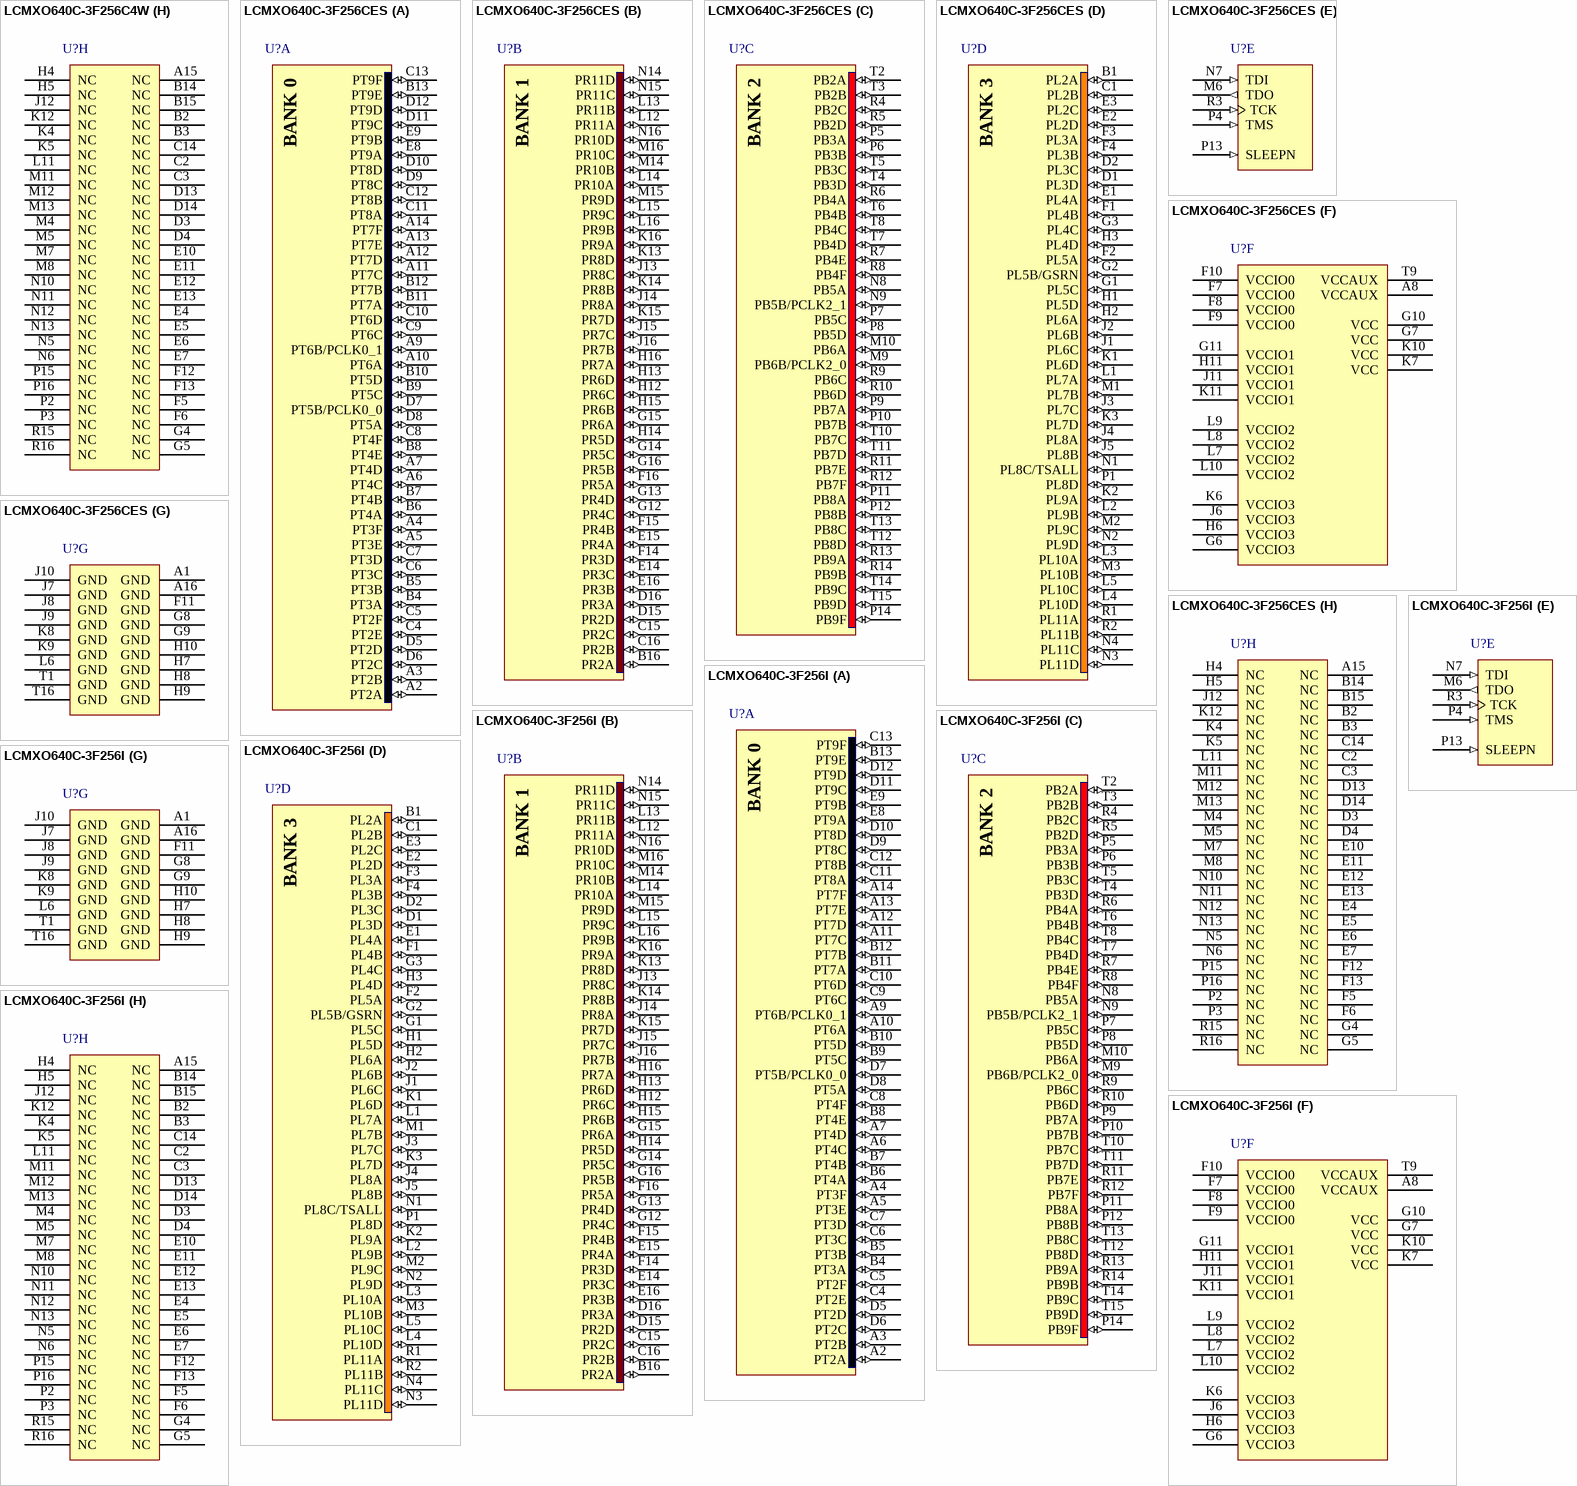
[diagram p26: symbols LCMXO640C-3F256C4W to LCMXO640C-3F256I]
## LCMXO640C-3F256C4W
designator U?
MachXO 640 Crossover PLD, 1.8V/2.5V/3.3V, 159 User I/Os, 256-Pins fpBGA, Speed Grade-3, Commercial Grade; ComponentAvailability: Not recommended for new designs. Use ftBGA package device.
footprint fpBGA256 (BGA, 256-Leads, Body 17x17mm, Pitch 1mm)
3D model MachXO640-fpBGA256 (256-Ball Fine Pitch Ball Grid Array (fpBGA256))
signal-integrity model LCMXO640C_F256 (MachXO)
part A pins: A2 PT2A (io), A3 PT2B (io), A4 PT3F (io), A5 PT3E (io), A6 PT4C (io), A7 PT4D (io), A9 PT6B/PCLK0_1 (io), A10 PT6A (io), A11 PT7C (io), A12 PT7D (io), A13 PT7E (io), A14 PT7F (io), B4 PT3A (io), B5 PT3B (io), B6 PT4A (io), B7 PT4B (io), B8 PT4E (io), B9 PT5C (io), B10 PT5D (io), B11 PT7A (io), B12 PT7B (io), B13 PT9E (io), C4 PT2E (io), C5 PT2F (io), C6 PT3C (io), C7 PT3D (io), C8 PT4F (io), C9 PT6C (io), C10 PT6D (io), C11 PT8A (io), C12 PT8B (io), C13 PT9F (io), D5 PT2D (io), D6 PT2C (io), D7 PT5B/PCLK0_0 (io), D8 PT5A (io), D9 PT8C (io), D10 PT8D (io), D11 PT9C (io), D12 PT9D (io), E8 PT9A (io), E9 PT9B (io)
part B pins: B16 PR2A (io), C15 PR2C (io), C16 PR2B (io), D15 PR2D (io), D16 PR3A (io), E14 PR3C (io), E15 PR4A (io), E16 PR3B (io), F14 PR3D (io), F15 PR4B (io), F16 PR5A (io), G12 PR4C (io), G13 PR4D (io), G14 PR5C (io), G15 PR6A (io), G16 PR5B (io), H12 PR6C (io), H13 PR6D (io), H14 PR5D (io), H15 PR6B (io), H16 PR7A (io), J13 PR8C (io), J14 PR8A (io), J15 PR7C (io), J16 PR7B (io), K13 PR8D (io), K14 PR8B (io), K15 PR7D (io), K16 PR9A (io), L12 PR11A (io), L13 PR11B (io), L14 PR10A (io), L15 PR9C (io), L16 PR9B (io), M14 PR10B (io), M15 PR9D (io), M16 PR10C (io), N14 PR11D (io), N15 PR11C (io), N16 PR10D (io)
part C pins: M9 PB6B/PCLK2_0 (io), M10 PB6A (io), N8 PB5A (io), N9 PB5B/PCLK2_1 (io), P5 PB3A (io), P6 PB3B (io), P7 PB5C (io), P8 PB5D (io), P9 PB7A (io), P10 PB7B (io), P11 PB8A (io), P12 PB8B (io), P14 PB9F (io), R4 PB2C (io), R5 PB2D (io), R6 PB4A (io), R7 PB4E (io), R8 PB4F (io), R9 PB6C (io), R10 PB6D (io), R11 PB7E (io), R12 PB7F (io), R13 PB9A (io), R14 PB9B (io), T2 PB2A (io), T3 PB2B (io), T4 PB3D (io), T5 PB3C (io), T6 PB4B (io), T7 PB4D (io), T8 PB4C (io), T10 PB7C (io), T11 PB7D (io), T12 PB8D (io), T13 PB8C (io), T14 PB9C (io), T15 PB9D (io)
part D pins: B1 PL2A (io), C1 PL2B (io), D1 PL3D (io), D2 PL3C (io), E1 PL4A (io), E2 PL2D (io), E3 PL2C (io), F1 PL4B (io), F2 PL5A (io), F3 PL3A (io), F4 PL3B (io), G1 PL5C (io), G2 PL5B/GSRN (io), G3 PL4C (io), H1 PL5D (io), H2 PL6A (io), H3 PL4D (io), J1 PL6C (io), J2 PL6B (io), J3 PL7C (io), J4 PL8A (io), J5 PL8B (io), K1 PL6D (io), K2 PL9A (io), K3 PL7D (io), L1 PL7A (io), L2 PL9B (io), L3 PL10A (io), L4 PL10D (io), L5 PL10C (io), M1 PL7B (io), M2 PL9C (io), M3 PL10B (io), N1 PL8C/TSALL (io), N2 PL9D (io), N3 PL11D (io), N4 PL11C (io), P1 PL8D (io), R1 PL11A (io), R2 PL11B (io)
part E pins: M6 TDO (out) "Powered by VCCIO2", N7 TDI (in) "Powered by VCCIO2", P4 TMS (in) "Powered by VCCIO2", P13 SLEEPN (in) "Powered by VCCIO2", R3 TCK (in) "Powered by VCCIO2"
part F pins: A8 VCCAUX (power), F7 VCCIO0 (power), F8 VCCIO0 (power), F9 VCCIO0 (power), F10 VCCIO0 (power), G6 VCCIO3 (power), G7 VCC (power), G10 VCC (power), G11 VCCIO1 (power), H6 VCCIO3 (power), H11 VCCIO1 (power), J6 VCCIO3 (power), J11 VCCIO1 (power), K6 VCCIO3 (power), K7 VCC (power), K10 VCC (power), K11 VCCIO1 (power), L7 VCCIO2 (power), L8 VCCIO2 (power), L9 VCCIO2 (power), L10 VCCIO2 (power), T9 VCCAUX (power)
part G pins: A1 GND (power), A16 GND (power), F11 GND (power), G8 GND (power), G9 GND (power), H7 GND (power), H8 GND (power), H9 GND (power), H10 GND (power), J7 GND (power), J8 GND (power), J9 GND (power), J10 GND (power), K8 GND (power), K9 GND (power), L6 GND (power), T1 GND (power), T16 GND (power)
part H pins: A15 NC, B2 NC, B3 NC, B14 NC, B15 NC, C2 NC, C3 NC, C14 NC, D3 NC, D4 NC, D13 NC, D14 NC, E4 NC, E5 NC, E6 NC, E7 NC, E10 NC, E11 NC, E12 NC, E13 NC, F5 NC, F6 NC, F12 NC, F13 NC, G4 NC, G5 NC, H4 NC, H5 NC, J12 NC, K4 NC, K5 NC, K12 NC, L11 NC, M4 NC, M5 NC, M7 NC, M8 NC, M11 NC, M12 NC, M13 NC, N5 NC, N6 NC, N10 NC, N11 NC, N12 NC, N13 NC, P2 NC, P3 NC, P15 NC, P16 NC, R15 NC, R16 NC

## LCMXO640C-3F256CES
designator U?
MachXO 640 Crossover PLD, 1.8V/2.5V/3.3V, 159 User I/Os, 256-Pins fpBGA, Speed Grade-3, Commercial Grade, Engineering Sample; ComponentAvailability: Not recommended for new designs. Use ftBGA package device.
footprint fpBGA256 (BGA, 256-Leads, Body 17x17mm, Pitch 1mm)
3D model MachXO640-fpBGA256 (256-Ball Fine Pitch Ball Grid Array (fpBGA256))
signal-integrity model LCMXO640C_F256 (MachXO)
part A pins: A2 PT2A (io), A3 PT2B (io), A4 PT3F (io), A5 PT3E (io), A6 PT4C (io), A7 PT4D (io), A9 PT6B/PCLK0_1 (io), A10 PT6A (io), A11 PT7C (io), A12 PT7D (io), A13 PT7E (io), A14 PT7F (io), B4 PT3A (io), B5 PT3B (io), B6 PT4A (io), B7 PT4B (io), B8 PT4E (io), B9 PT5C (io), B10 PT5D (io), B11 PT7A (io), B12 PT7B (io), B13 PT9E (io), C4 PT2E (io), C5 PT2F (io), C6 PT3C (io), C7 PT3D (io), C8 PT4F (io), C9 PT6C (io), C10 PT6D (io), C11 PT8A (io), C12 PT8B (io), C13 PT9F (io), D5 PT2D (io), D6 PT2C (io), D7 PT5B/PCLK0_0 (io), D8 PT5A (io), D9 PT8C (io), D10 PT8D (io), D11 PT9C (io), D12 PT9D (io), E8 PT9A (io), E9 PT9B (io)
part B pins: B16 PR2A (io), C15 PR2C (io), C16 PR2B (io), D15 PR2D (io), D16 PR3A (io), E14 PR3C (io), E15 PR4A (io), E16 PR3B (io), F14 PR3D (io), F15 PR4B (io), F16 PR5A (io), G12 PR4C (io), G13 PR4D (io), G14 PR5C (io), G15 PR6A (io), G16 PR5B (io), H12 PR6C (io), H13 PR6D (io), H14 PR5D (io), H15 PR6B (io), H16 PR7A (io), J13 PR8C (io), J14 PR8A (io), J15 PR7C (io), J16 PR7B (io), K13 PR8D (io), K14 PR8B (io), K15 PR7D (io), K16 PR9A (io), L12 PR11A (io), L13 PR11B (io), L14 PR10A (io), L15 PR9C (io), L16 PR9B (io), M14 PR10B (io), M15 PR9D (io), M16 PR10C (io), N14 PR11D (io), N15 PR11C (io), N16 PR10D (io)
part C pins: M9 PB6B/PCLK2_0 (io), M10 PB6A (io), N8 PB5A (io), N9 PB5B/PCLK2_1 (io), P5 PB3A (io), P6 PB3B (io), P7 PB5C (io), P8 PB5D (io), P9 PB7A (io), P10 PB7B (io), P11 PB8A (io), P12 PB8B (io), P14 PB9F (io), R4 PB2C (io), R5 PB2D (io), R6 PB4A (io), R7 PB4E (io), R8 PB4F (io), R9 PB6C (io), R10 PB6D (io), R11 PB7E (io), R12 PB7F (io), R13 PB9A (io), R14 PB9B (io), T2 PB2A (io), T3 PB2B (io), T4 PB3D (io), T5 PB3C (io), T6 PB4B (io), T7 PB4D (io), T8 PB4C (io), T10 PB7C (io), T11 PB7D (io), T12 PB8D (io), T13 PB8C (io), T14 PB9C (io), T15 PB9D (io)
part D pins: B1 PL2A (io), C1 PL2B (io), D1 PL3D (io), D2 PL3C (io), E1 PL4A (io), E2 PL2D (io), E3 PL2C (io), F1 PL4B (io), F2 PL5A (io), F3 PL3A (io), F4 PL3B (io), G1 PL5C (io), G2 PL5B/GSRN (io), G3 PL4C (io), H1 PL5D (io), H2 PL6A (io), H3 PL4D (io), J1 PL6C (io), J2 PL6B (io), J3 PL7C (io), J4 PL8A (io), J5 PL8B (io), K1 PL6D (io), K2 PL9A (io), K3 PL7D (io), L1 PL7A (io), L2 PL9B (io), L3 PL10A (io), L4 PL10D (io), L5 PL10C (io), M1 PL7B (io), M2 PL9C (io), M3 PL10B (io), N1 PL8C/TSALL (io), N2 PL9D (io), N3 PL11D (io), N4 PL11C (io), P1 PL8D (io), R1 PL11A (io), R2 PL11B (io)
part E pins: M6 TDO (out) "Powered by VCCIO2", N7 TDI (in) "Powered by VCCIO2", P4 TMS (in) "Powered by VCCIO2", P13 SLEEPN (in) "Powered by VCCIO2", R3 TCK (in) "Powered by VCCIO2"
part F pins: A8 VCCAUX (power), F7 VCCIO0 (power), F8 VCCIO0 (power), F9 VCCIO0 (power), F10 VCCIO0 (power), G6 VCCIO3 (power), G7 VCC (power), G10 VCC (power), G11 VCCIO1 (power), H6 VCCIO3 (power), H11 VCCIO1 (power), J6 VCCIO3 (power), J11 VCCIO1 (power), K6 VCCIO3 (power), K7 VCC (power), K10 VCC (power), K11 VCCIO1 (power), L7 VCCIO2 (power), L8 VCCIO2 (power), L9 VCCIO2 (power), L10 VCCIO2 (power), T9 VCCAUX (power)
part G pins: A1 GND (power), A16 GND (power), F11 GND (power), G8 GND (power), G9 GND (power), H7 GND (power), H8 GND (power), H9 GND (power), H10 GND (power), J7 GND (power), J8 GND (power), J9 GND (power), J10 GND (power), K8 GND (power), K9 GND (power), L6 GND (power), T1 GND (power), T16 GND (power)
part H pins: A15 NC, B2 NC, B3 NC, B14 NC, B15 NC, C2 NC, C3 NC, C14 NC, D3 NC, D4 NC, D13 NC, D14 NC, E4 NC, E5 NC, E6 NC, E7 NC, E10 NC, E11 NC, E12 NC, E13 NC, F5 NC, F6 NC, F12 NC, F13 NC, G4 NC, G5 NC, H4 NC, H5 NC, J12 NC, K4 NC, K5 NC, K12 NC, L11 NC, M4 NC, M5 NC, M7 NC, M8 NC, M11 NC, M12 NC, M13 NC, N5 NC, N6 NC, N10 NC, N11 NC, N12 NC, N13 NC, P2 NC, P3 NC, P15 NC, P16 NC, R15 NC, R16 NC

## LCMXO640C-3F256I
designator U?
MachXO 640 Crossover PLD, 1.8V/2.5V/3.3V, 159 User I/Os, 256-Pins fpBGA, Speed Grade-3, Industrial Grade; ComponentAvailability: Not recommended for new designs. Use ftBGA package device.
footprint fpBGA256 (BGA, 256-Leads, Body 17x17mm, Pitch 1mm)
3D model MachXO640-fpBGA256 (256-Ball Fine Pitch Ball Grid Array (fpBGA256))
signal-integrity model LCMXO640C_F256 (MachXO)
part A pins: A2 PT2A (io), A3 PT2B (io), A4 PT3F (io), A5 PT3E (io), A6 PT4C (io), A7 PT4D (io), A9 PT6B/PCLK0_1 (io), A10 PT6A (io), A11 PT7C (io), A12 PT7D (io), A13 PT7E (io), A14 PT7F (io), B4 PT3A (io), B5 PT3B (io), B6 PT4A (io), B7 PT4B (io), B8 PT4E (io), B9 PT5C (io), B10 PT5D (io), B11 PT7A (io), B12 PT7B (io), B13 PT9E (io), C4 PT2E (io), C5 PT2F (io), C6 PT3C (io), C7 PT3D (io), C8 PT4F (io), C9 PT6C (io), C10 PT6D (io), C11 PT8A (io), C12 PT8B (io), C13 PT9F (io), D5 PT2D (io), D6 PT2C (io), D7 PT5B/PCLK0_0 (io), D8 PT5A (io), D9 PT8C (io), D10 PT8D (io), D11 PT9C (io), D12 PT9D (io), E8 PT9A (io), E9 PT9B (io)
part B pins: B16 PR2A (io), C15 PR2C (io), C16 PR2B (io), D15 PR2D (io), D16 PR3A (io), E14 PR3C (io), E15 PR4A (io), E16 PR3B (io), F14 PR3D (io), F15 PR4B (io), F16 PR5A (io), G12 PR4C (io), G13 PR4D (io), G14 PR5C (io), G15 PR6A (io), G16 PR5B (io), H12 PR6C (io), H13 PR6D (io), H14 PR5D (io), H15 PR6B (io), H16 PR7A (io), J13 PR8C (io), J14 PR8A (io), J15 PR7C (io), J16 PR7B (io), K13 PR8D (io), K14 PR8B (io), K15 PR7D (io), K16 PR9A (io), L12 PR11A (io), L13 PR11B (io), L14 PR10A (io), L15 PR9C (io), L16 PR9B (io), M14 PR10B (io), M15 PR9D (io), M16 PR10C (io), N14 PR11D (io), N15 PR11C (io), N16 PR10D (io)
part C pins: M9 PB6B/PCLK2_0 (io), M10 PB6A (io), N8 PB5A (io), N9 PB5B/PCLK2_1 (io), P5 PB3A (io), P6 PB3B (io), P7 PB5C (io), P8 PB5D (io), P9 PB7A (io), P10 PB7B (io), P11 PB8A (io), P12 PB8B (io), P14 PB9F (io), R4 PB2C (io), R5 PB2D (io), R6 PB4A (io), R7 PB4E (io), R8 PB4F (io), R9 PB6C (io), R10 PB6D (io), R11 PB7E (io), R12 PB7F (io), R13 PB9A (io), R14 PB9B (io), T2 PB2A (io), T3 PB2B (io), T4 PB3D (io), T5 PB3C (io), T6 PB4B (io), T7 PB4D (io), T8 PB4C (io), T10 PB7C (io), T11 PB7D (io), T12 PB8D (io), T13 PB8C (io), T14 PB9C (io), T15 PB9D (io)
part D pins: B1 PL2A (io), C1 PL2B (io), D1 PL3D (io), D2 PL3C (io), E1 PL4A (io), E2 PL2D (io), E3 PL2C (io), F1 PL4B (io), F2 PL5A (io), F3 PL3A (io), F4 PL3B (io), G1 PL5C (io), G2 PL5B/GSRN (io), G3 PL4C (io), H1 PL5D (io), H2 PL6A (io), H3 PL4D (io), J1 PL6C (io), J2 PL6B (io), J3 PL7C (io), J4 PL8A (io), J5 PL8B (io), K1 PL6D (io), K2 PL9A (io), K3 PL7D (io), L1 PL7A (io), L2 PL9B (io), L3 PL10A (io), L4 PL10D (io), L5 PL10C (io), M1 PL7B (io), M2 PL9C (io), M3 PL10B (io), N1 PL8C/TSALL (io), N2 PL9D (io), N3 PL11D (io), N4 PL11C (io), P1 PL8D (io), R1 PL11A (io), R2 PL11B (io)
part E pins: M6 TDO (out) "Powered by VCCIO2", N7 TDI (in) "Powered by VCCIO2", P4 TMS (in) "Powered by VCCIO2", P13 SLEEPN (in) "Powered by VCCIO2", R3 TCK (in) "Powered by VCCIO2"
part F pins: A8 VCCAUX (power), F7 VCCIO0 (power), F8 VCCIO0 (power), F9 VCCIO0 (power), F10 VCCIO0 (power), G6 VCCIO3 (power), G7 VCC (power), G10 VCC (power), G11 VCCIO1 (power), H6 VCCIO3 (power), H11 VCCIO1 (power), J6 VCCIO3 (power), J11 VCCIO1 (power), K6 VCCIO3 (power), K7 VCC (power), K10 VCC (power), K11 VCCIO1 (power), L7 VCCIO2 (power), L8 VCCIO2 (power), L9 VCCIO2 (power), L10 VCCIO2 (power), T9 VCCAUX (power)
part G pins: A1 GND (power), A16 GND (power), F11 GND (power), G8 GND (power), G9 GND (power), H7 GND (power), H8 GND (power), H9 GND (power), H10 GND (power), J7 GND (power), J8 GND (power), J9 GND (power), J10 GND (power), K8 GND (power), K9 GND (power), L6 GND (power), T1 GND (power), T16 GND (power)
part H pins: A15 NC, B2 NC, B3 NC, B14 NC, B15 NC, C2 NC, C3 NC, C14 NC, D3 NC, D4 NC, D13 NC, D14 NC, E4 NC, E5 NC, E6 NC, E7 NC, E10 NC, E11 NC, E12 NC, E13 NC, F5 NC, F6 NC, F12 NC, F13 NC, G4 NC, G5 NC, H4 NC, H5 NC, J12 NC, K4 NC, K5 NC, K12 NC, L11 NC, M4 NC, M5 NC, M7 NC, M8 NC, M11 NC, M12 NC, M13 NC, N5 NC, N6 NC, N10 NC, N11 NC, N12 NC, N13 NC, P2 NC, P3 NC, P15 NC, P16 NC, R15 NC, R16 NC


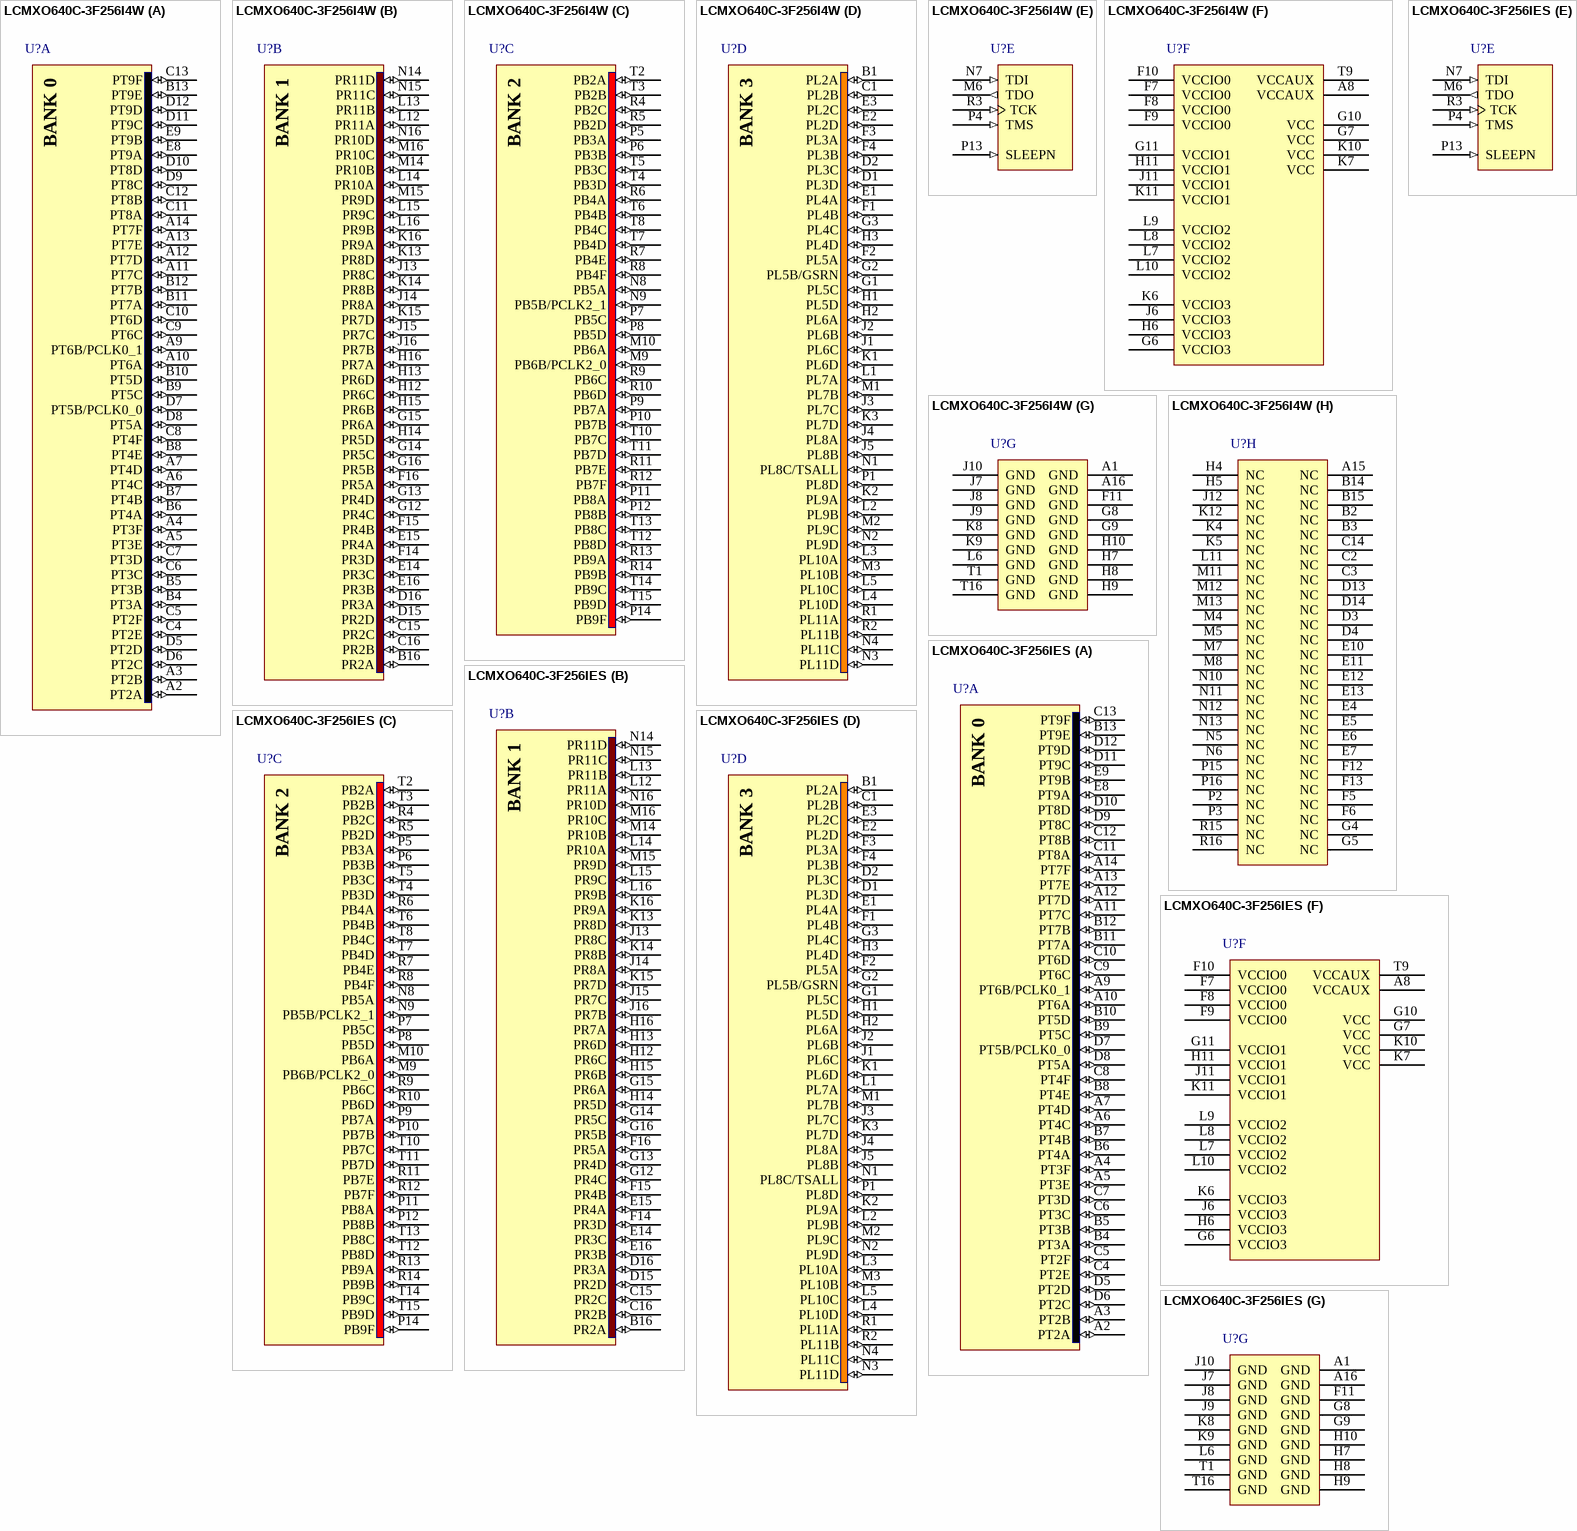
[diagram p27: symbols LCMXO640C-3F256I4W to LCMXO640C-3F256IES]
## LCMXO640C-3F256I4W
designator U?
MachXO 640 Crossover PLD, 1.8V/2.5V/3.3V, 159 User I/Os, 256-Pins fpBGA, Speed Grade-3, Industrial Grade; ComponentAvailability: Not recommended for new designs. Use ftBGA package device.
footprint fpBGA256 (BGA, 256-Leads, Body 17x17mm, Pitch 1mm)
3D model MachXO640-fpBGA256 (256-Ball Fine Pitch Ball Grid Array (fpBGA256))
signal-integrity model LCMXO640C_F256 (MachXO)
part A pins: A2 PT2A (io), A3 PT2B (io), A4 PT3F (io), A5 PT3E (io), A6 PT4C (io), A7 PT4D (io), A9 PT6B/PCLK0_1 (io), A10 PT6A (io), A11 PT7C (io), A12 PT7D (io), A13 PT7E (io), A14 PT7F (io), B4 PT3A (io), B5 PT3B (io), B6 PT4A (io), B7 PT4B (io), B8 PT4E (io), B9 PT5C (io), B10 PT5D (io), B11 PT7A (io), B12 PT7B (io), B13 PT9E (io), C4 PT2E (io), C5 PT2F (io), C6 PT3C (io), C7 PT3D (io), C8 PT4F (io), C9 PT6C (io), C10 PT6D (io), C11 PT8A (io), C12 PT8B (io), C13 PT9F (io), D5 PT2D (io), D6 PT2C (io), D7 PT5B/PCLK0_0 (io), D8 PT5A (io), D9 PT8C (io), D10 PT8D (io), D11 PT9C (io), D12 PT9D (io), E8 PT9A (io), E9 PT9B (io)
part B pins: B16 PR2A (io), C15 PR2C (io), C16 PR2B (io), D15 PR2D (io), D16 PR3A (io), E14 PR3C (io), E15 PR4A (io), E16 PR3B (io), F14 PR3D (io), F15 PR4B (io), F16 PR5A (io), G12 PR4C (io), G13 PR4D (io), G14 PR5C (io), G15 PR6A (io), G16 PR5B (io), H12 PR6C (io), H13 PR6D (io), H14 PR5D (io), H15 PR6B (io), H16 PR7A (io), J13 PR8C (io), J14 PR8A (io), J15 PR7C (io), J16 PR7B (io), K13 PR8D (io), K14 PR8B (io), K15 PR7D (io), K16 PR9A (io), L12 PR11A (io), L13 PR11B (io), L14 PR10A (io), L15 PR9C (io), L16 PR9B (io), M14 PR10B (io), M15 PR9D (io), M16 PR10C (io), N14 PR11D (io), N15 PR11C (io), N16 PR10D (io)
part C pins: M9 PB6B/PCLK2_0 (io), M10 PB6A (io), N8 PB5A (io), N9 PB5B/PCLK2_1 (io), P5 PB3A (io), P6 PB3B (io), P7 PB5C (io), P8 PB5D (io), P9 PB7A (io), P10 PB7B (io), P11 PB8A (io), P12 PB8B (io), P14 PB9F (io), R4 PB2C (io), R5 PB2D (io), R6 PB4A (io), R7 PB4E (io), R8 PB4F (io), R9 PB6C (io), R10 PB6D (io), R11 PB7E (io), R12 PB7F (io), R13 PB9A (io), R14 PB9B (io), T2 PB2A (io), T3 PB2B (io), T4 PB3D (io), T5 PB3C (io), T6 PB4B (io), T7 PB4D (io), T8 PB4C (io), T10 PB7C (io), T11 PB7D (io), T12 PB8D (io), T13 PB8C (io), T14 PB9C (io), T15 PB9D (io)
part D pins: B1 PL2A (io), C1 PL2B (io), D1 PL3D (io), D2 PL3C (io), E1 PL4A (io), E2 PL2D (io), E3 PL2C (io), F1 PL4B (io), F2 PL5A (io), F3 PL3A (io), F4 PL3B (io), G1 PL5C (io), G2 PL5B/GSRN (io), G3 PL4C (io), H1 PL5D (io), H2 PL6A (io), H3 PL4D (io), J1 PL6C (io), J2 PL6B (io), J3 PL7C (io), J4 PL8A (io), J5 PL8B (io), K1 PL6D (io), K2 PL9A (io), K3 PL7D (io), L1 PL7A (io), L2 PL9B (io), L3 PL10A (io), L4 PL10D (io), L5 PL10C (io), M1 PL7B (io), M2 PL9C (io), M3 PL10B (io), N1 PL8C/TSALL (io), N2 PL9D (io), N3 PL11D (io), N4 PL11C (io), P1 PL8D (io), R1 PL11A (io), R2 PL11B (io)
part E pins: M6 TDO (out) "Powered by VCCIO2", N7 TDI (in) "Powered by VCCIO2", P4 TMS (in) "Powered by VCCIO2", P13 SLEEPN (in) "Powered by VCCIO2", R3 TCK (in) "Powered by VCCIO2"
part F pins: A8 VCCAUX (power), F7 VCCIO0 (power), F8 VCCIO0 (power), F9 VCCIO0 (power), F10 VCCIO0 (power), G6 VCCIO3 (power), G7 VCC (power), G10 VCC (power), G11 VCCIO1 (power), H6 VCCIO3 (power), H11 VCCIO1 (power), J6 VCCIO3 (power), J11 VCCIO1 (power), K6 VCCIO3 (power), K7 VCC (power), K10 VCC (power), K11 VCCIO1 (power), L7 VCCIO2 (power), L8 VCCIO2 (power), L9 VCCIO2 (power), L10 VCCIO2 (power), T9 VCCAUX (power)
part G pins: A1 GND (power), A16 GND (power), F11 GND (power), G8 GND (power), G9 GND (power), H7 GND (power), H8 GND (power), H9 GND (power), H10 GND (power), J7 GND (power), J8 GND (power), J9 GND (power), J10 GND (power), K8 GND (power), K9 GND (power), L6 GND (power), T1 GND (power), T16 GND (power)
part H pins: A15 NC, B2 NC, B3 NC, B14 NC, B15 NC, C2 NC, C3 NC, C14 NC, D3 NC, D4 NC, D13 NC, D14 NC, E4 NC, E5 NC, E6 NC, E7 NC, E10 NC, E11 NC, E12 NC, E13 NC, F5 NC, F6 NC, F12 NC, F13 NC, G4 NC, G5 NC, H4 NC, H5 NC, J12 NC, K4 NC, K5 NC, K12 NC, L11 NC, M4 NC, M5 NC, M7 NC, M8 NC, M11 NC, M12 NC, M13 NC, N5 NC, N6 NC, N10 NC, N11 NC, N12 NC, N13 NC, P2 NC, P3 NC, P15 NC, P16 NC, R15 NC, R16 NC


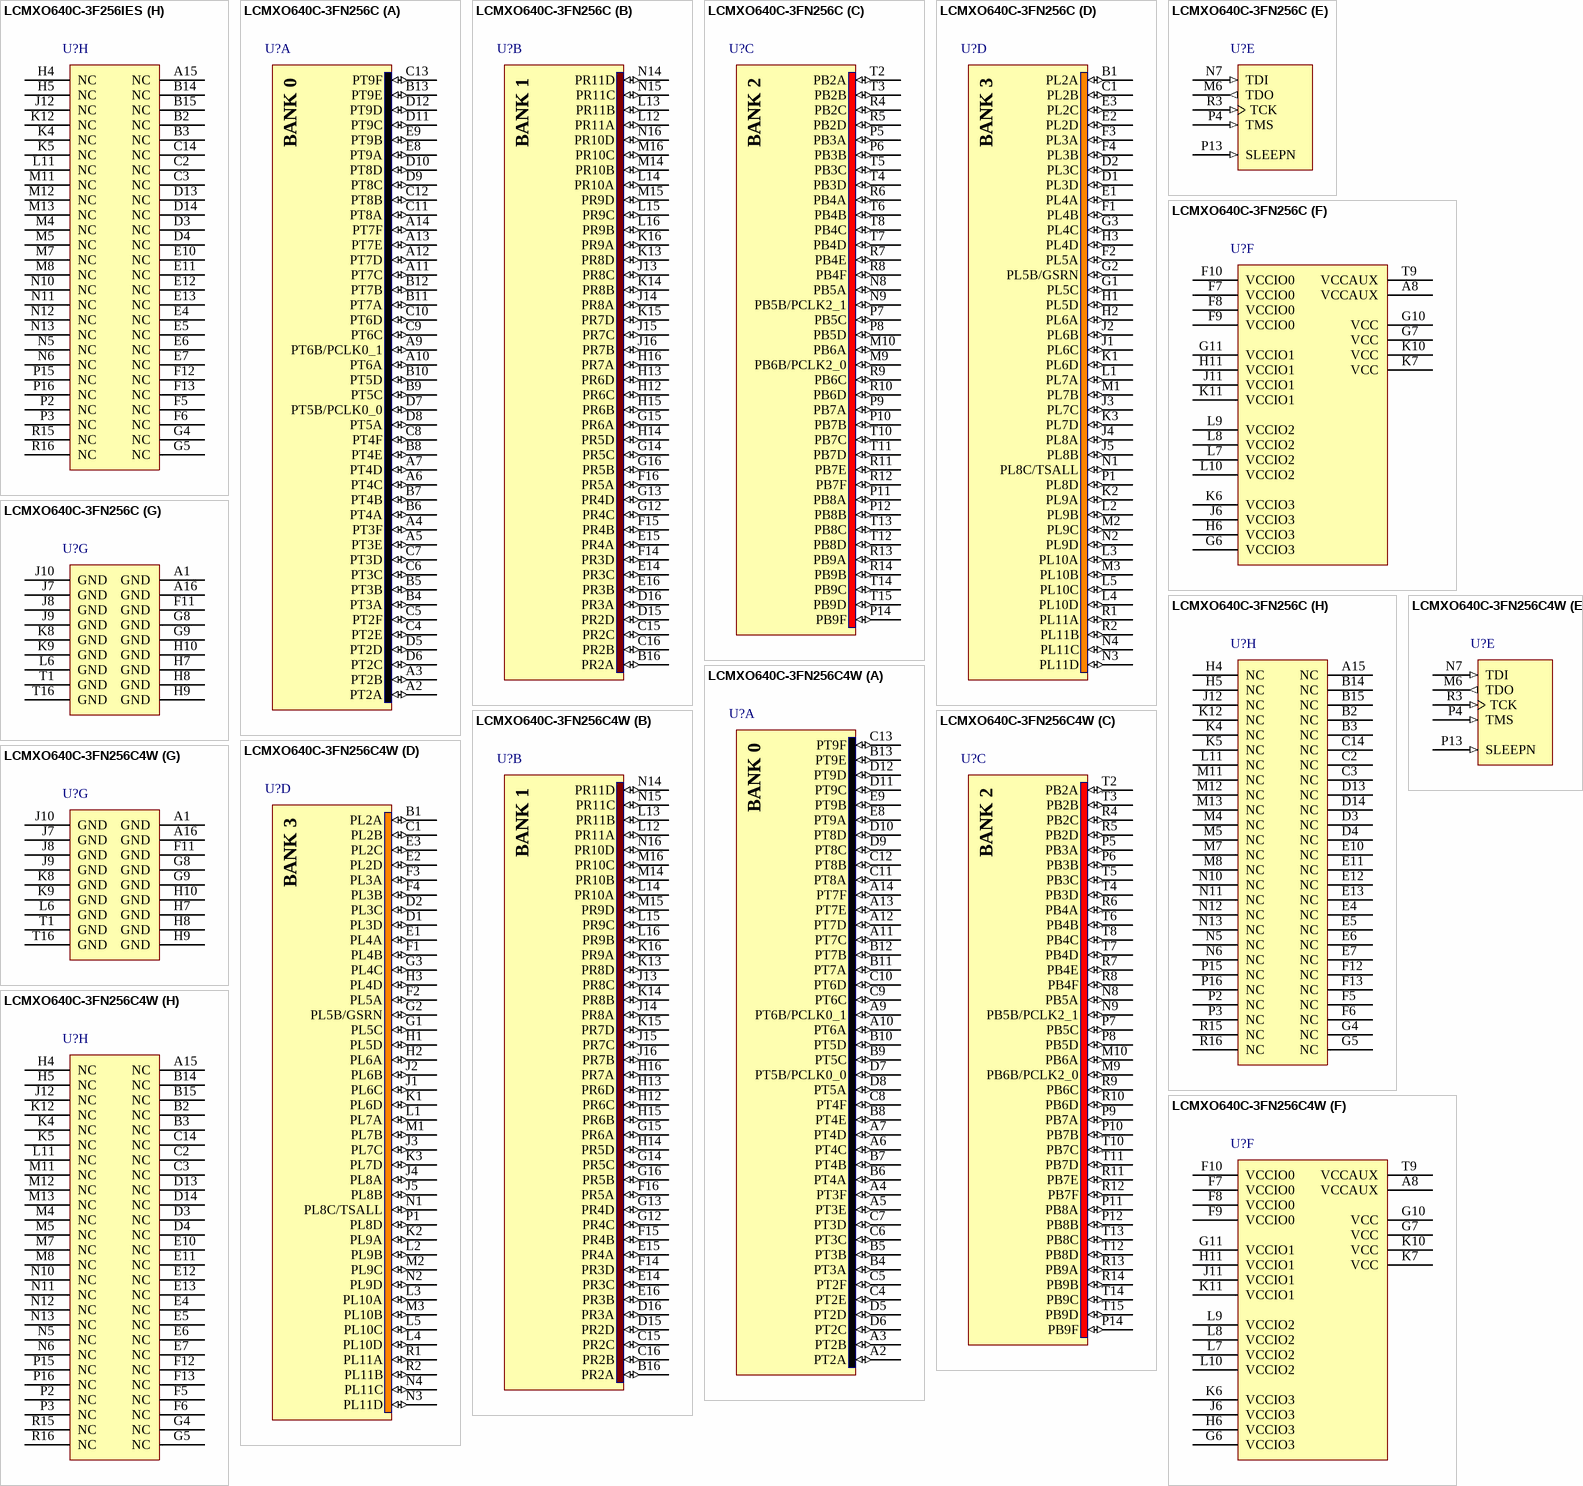
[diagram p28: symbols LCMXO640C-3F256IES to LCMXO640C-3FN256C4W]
## LCMXO640C-3F256IES
designator U?
MachXO 640 Crossover PLD, 1.8V/2.5V/3.3V, 159 User I/Os, 256-Pins fpBGA, Speed Grade-3, Industrial Grade, Engineering Sample; ComponentAvailability: Not recommended for new designs. Use ftBGA package device.
footprint fpBGA256 (BGA, 256-Leads, Body 17x17mm, Pitch 1mm)
3D model MachXO640-fpBGA256 (256-Ball Fine Pitch Ball Grid Array (fpBGA256))
signal-integrity model LCMXO640C_F256 (MachXO)
part A pins: A2 PT2A (io), A3 PT2B (io), A4 PT3F (io), A5 PT3E (io), A6 PT4C (io), A7 PT4D (io), A9 PT6B/PCLK0_1 (io), A10 PT6A (io), A11 PT7C (io), A12 PT7D (io), A13 PT7E (io), A14 PT7F (io), B4 PT3A (io), B5 PT3B (io), B6 PT4A (io), B7 PT4B (io), B8 PT4E (io), B9 PT5C (io), B10 PT5D (io), B11 PT7A (io), B12 PT7B (io), B13 PT9E (io), C4 PT2E (io), C5 PT2F (io), C6 PT3C (io), C7 PT3D (io), C8 PT4F (io), C9 PT6C (io), C10 PT6D (io), C11 PT8A (io), C12 PT8B (io), C13 PT9F (io), D5 PT2D (io), D6 PT2C (io), D7 PT5B/PCLK0_0 (io), D8 PT5A (io), D9 PT8C (io), D10 PT8D (io), D11 PT9C (io), D12 PT9D (io), E8 PT9A (io), E9 PT9B (io)
part B pins: B16 PR2A (io), C15 PR2C (io), C16 PR2B (io), D15 PR2D (io), D16 PR3A (io), E14 PR3C (io), E15 PR4A (io), E16 PR3B (io), F14 PR3D (io), F15 PR4B (io), F16 PR5A (io), G12 PR4C (io), G13 PR4D (io), G14 PR5C (io), G15 PR6A (io), G16 PR5B (io), H12 PR6C (io), H13 PR6D (io), H14 PR5D (io), H15 PR6B (io), H16 PR7A (io), J13 PR8C (io), J14 PR8A (io), J15 PR7C (io), J16 PR7B (io), K13 PR8D (io), K14 PR8B (io), K15 PR7D (io), K16 PR9A (io), L12 PR11A (io), L13 PR11B (io), L14 PR10A (io), L15 PR9C (io), L16 PR9B (io), M14 PR10B (io), M15 PR9D (io), M16 PR10C (io), N14 PR11D (io), N15 PR11C (io), N16 PR10D (io)
part C pins: M9 PB6B/PCLK2_0 (io), M10 PB6A (io), N8 PB5A (io), N9 PB5B/PCLK2_1 (io), P5 PB3A (io), P6 PB3B (io), P7 PB5C (io), P8 PB5D (io), P9 PB7A (io), P10 PB7B (io), P11 PB8A (io), P12 PB8B (io), P14 PB9F (io), R4 PB2C (io), R5 PB2D (io), R6 PB4A (io), R7 PB4E (io), R8 PB4F (io), R9 PB6C (io), R10 PB6D (io), R11 PB7E (io), R12 PB7F (io), R13 PB9A (io), R14 PB9B (io), T2 PB2A (io), T3 PB2B (io), T4 PB3D (io), T5 PB3C (io), T6 PB4B (io), T7 PB4D (io), T8 PB4C (io), T10 PB7C (io), T11 PB7D (io), T12 PB8D (io), T13 PB8C (io), T14 PB9C (io), T15 PB9D (io)
part D pins: B1 PL2A (io), C1 PL2B (io), D1 PL3D (io), D2 PL3C (io), E1 PL4A (io), E2 PL2D (io), E3 PL2C (io), F1 PL4B (io), F2 PL5A (io), F3 PL3A (io), F4 PL3B (io), G1 PL5C (io), G2 PL5B/GSRN (io), G3 PL4C (io), H1 PL5D (io), H2 PL6A (io), H3 PL4D (io), J1 PL6C (io), J2 PL6B (io), J3 PL7C (io), J4 PL8A (io), J5 PL8B (io), K1 PL6D (io), K2 PL9A (io), K3 PL7D (io), L1 PL7A (io), L2 PL9B (io), L3 PL10A (io), L4 PL10D (io), L5 PL10C (io), M1 PL7B (io), M2 PL9C (io), M3 PL10B (io), N1 PL8C/TSALL (io), N2 PL9D (io), N3 PL11D (io), N4 PL11C (io), P1 PL8D (io), R1 PL11A (io), R2 PL11B (io)
part E pins: M6 TDO (out) "Powered by VCCIO2", N7 TDI (in) "Powered by VCCIO2", P4 TMS (in) "Powered by VCCIO2", P13 SLEEPN (in) "Powered by VCCIO2", R3 TCK (in) "Powered by VCCIO2"
part F pins: A8 VCCAUX (power), F7 VCCIO0 (power), F8 VCCIO0 (power), F9 VCCIO0 (power), F10 VCCIO0 (power), G6 VCCIO3 (power), G7 VCC (power), G10 VCC (power), G11 VCCIO1 (power), H6 VCCIO3 (power), H11 VCCIO1 (power), J6 VCCIO3 (power), J11 VCCIO1 (power), K6 VCCIO3 (power), K7 VCC (power), K10 VCC (power), K11 VCCIO1 (power), L7 VCCIO2 (power), L8 VCCIO2 (power), L9 VCCIO2 (power), L10 VCCIO2 (power), T9 VCCAUX (power)
part G pins: A1 GND (power), A16 GND (power), F11 GND (power), G8 GND (power), G9 GND (power), H7 GND (power), H8 GND (power), H9 GND (power), H10 GND (power), J7 GND (power), J8 GND (power), J9 GND (power), J10 GND (power), K8 GND (power), K9 GND (power), L6 GND (power), T1 GND (power), T16 GND (power)
part H pins: A15 NC, B2 NC, B3 NC, B14 NC, B15 NC, C2 NC, C3 NC, C14 NC, D3 NC, D4 NC, D13 NC, D14 NC, E4 NC, E5 NC, E6 NC, E7 NC, E10 NC, E11 NC, E12 NC, E13 NC, F5 NC, F6 NC, F12 NC, F13 NC, G4 NC, G5 NC, H4 NC, H5 NC, J12 NC, K4 NC, K5 NC, K12 NC, L11 NC, M4 NC, M5 NC, M7 NC, M8 NC, M11 NC, M12 NC, M13 NC, N5 NC, N6 NC, N10 NC, N11 NC, N12 NC, N13 NC, P2 NC, P3 NC, P15 NC, P16 NC, R15 NC, R16 NC

## LCMXO640C-3FN256C
designator U?
MachXO 640 Crossover PLD, 1.8V/2.5V/3.3V, 159 User I/Os, 256-Pins fpBGA, Speed Grade-3, Commercial Grade, Pb-Free; ComponentAvailability: Not recommended for new designs. Use ftBGA package device.
footprint fpBGA256 (BGA, 256-Leads, Body 17x17mm, Pitch 1mm)
3D model MachXO640-fpBGA256 (256-Ball Fine Pitch Ball Grid Array (fpBGA256))
signal-integrity model LCMXO640C_F256 (MachXO)
part A pins: A2 PT2A (io), A3 PT2B (io), A4 PT3F (io), A5 PT3E (io), A6 PT4C (io), A7 PT4D (io), A9 PT6B/PCLK0_1 (io), A10 PT6A (io), A11 PT7C (io), A12 PT7D (io), A13 PT7E (io), A14 PT7F (io), B4 PT3A (io), B5 PT3B (io), B6 PT4A (io), B7 PT4B (io), B8 PT4E (io), B9 PT5C (io), B10 PT5D (io), B11 PT7A (io), B12 PT7B (io), B13 PT9E (io), C4 PT2E (io), C5 PT2F (io), C6 PT3C (io), C7 PT3D (io), C8 PT4F (io), C9 PT6C (io), C10 PT6D (io), C11 PT8A (io), C12 PT8B (io), C13 PT9F (io), D5 PT2D (io), D6 PT2C (io), D7 PT5B/PCLK0_0 (io), D8 PT5A (io), D9 PT8C (io), D10 PT8D (io), D11 PT9C (io), D12 PT9D (io), E8 PT9A (io), E9 PT9B (io)
part B pins: B16 PR2A (io), C15 PR2C (io), C16 PR2B (io), D15 PR2D (io), D16 PR3A (io), E14 PR3C (io), E15 PR4A (io), E16 PR3B (io), F14 PR3D (io), F15 PR4B (io), F16 PR5A (io), G12 PR4C (io), G13 PR4D (io), G14 PR5C (io), G15 PR6A (io), G16 PR5B (io), H12 PR6C (io), H13 PR6D (io), H14 PR5D (io), H15 PR6B (io), H16 PR7A (io), J13 PR8C (io), J14 PR8A (io), J15 PR7C (io), J16 PR7B (io), K13 PR8D (io), K14 PR8B (io), K15 PR7D (io), K16 PR9A (io), L12 PR11A (io), L13 PR11B (io), L14 PR10A (io), L15 PR9C (io), L16 PR9B (io), M14 PR10B (io), M15 PR9D (io), M16 PR10C (io), N14 PR11D (io), N15 PR11C (io), N16 PR10D (io)
part C pins: M9 PB6B/PCLK2_0 (io), M10 PB6A (io), N8 PB5A (io), N9 PB5B/PCLK2_1 (io), P5 PB3A (io), P6 PB3B (io), P7 PB5C (io), P8 PB5D (io), P9 PB7A (io), P10 PB7B (io), P11 PB8A (io), P12 PB8B (io), P14 PB9F (io), R4 PB2C (io), R5 PB2D (io), R6 PB4A (io), R7 PB4E (io), R8 PB4F (io), R9 PB6C (io), R10 PB6D (io), R11 PB7E (io), R12 PB7F (io), R13 PB9A (io), R14 PB9B (io), T2 PB2A (io), T3 PB2B (io), T4 PB3D (io), T5 PB3C (io), T6 PB4B (io), T7 PB4D (io), T8 PB4C (io), T10 PB7C (io), T11 PB7D (io), T12 PB8D (io), T13 PB8C (io), T14 PB9C (io), T15 PB9D (io)
part D pins: B1 PL2A (io), C1 PL2B (io), D1 PL3D (io), D2 PL3C (io), E1 PL4A (io), E2 PL2D (io), E3 PL2C (io), F1 PL4B (io), F2 PL5A (io), F3 PL3A (io), F4 PL3B (io), G1 PL5C (io), G2 PL5B/GSRN (io), G3 PL4C (io), H1 PL5D (io), H2 PL6A (io), H3 PL4D (io), J1 PL6C (io), J2 PL6B (io), J3 PL7C (io), J4 PL8A (io), J5 PL8B (io), K1 PL6D (io), K2 PL9A (io), K3 PL7D (io), L1 PL7A (io), L2 PL9B (io), L3 PL10A (io), L4 PL10D (io), L5 PL10C (io), M1 PL7B (io), M2 PL9C (io), M3 PL10B (io), N1 PL8C/TSALL (io), N2 PL9D (io), N3 PL11D (io), N4 PL11C (io), P1 PL8D (io), R1 PL11A (io), R2 PL11B (io)
part E pins: M6 TDO (out) "Powered by VCCIO2", N7 TDI (in) "Powered by VCCIO2", P4 TMS (in) "Powered by VCCIO2", P13 SLEEPN (in) "Powered by VCCIO2", R3 TCK (in) "Powered by VCCIO2"
part F pins: A8 VCCAUX (power), F7 VCCIO0 (power), F8 VCCIO0 (power), F9 VCCIO0 (power), F10 VCCIO0 (power), G6 VCCIO3 (power), G7 VCC (power), G10 VCC (power), G11 VCCIO1 (power), H6 VCCIO3 (power), H11 VCCIO1 (power), J6 VCCIO3 (power), J11 VCCIO1 (power), K6 VCCIO3 (power), K7 VCC (power), K10 VCC (power), K11 VCCIO1 (power), L7 VCCIO2 (power), L8 VCCIO2 (power), L9 VCCIO2 (power), L10 VCCIO2 (power), T9 VCCAUX (power)
part G pins: A1 GND (power), A16 GND (power), F11 GND (power), G8 GND (power), G9 GND (power), H7 GND (power), H8 GND (power), H9 GND (power), H10 GND (power), J7 GND (power), J8 GND (power), J9 GND (power), J10 GND (power), K8 GND (power), K9 GND (power), L6 GND (power), T1 GND (power), T16 GND (power)
part H pins: A15 NC, B2 NC, B3 NC, B14 NC, B15 NC, C2 NC, C3 NC, C14 NC, D3 NC, D4 NC, D13 NC, D14 NC, E4 NC, E5 NC, E6 NC, E7 NC, E10 NC, E11 NC, E12 NC, E13 NC, F5 NC, F6 NC, F12 NC, F13 NC, G4 NC, G5 NC, H4 NC, H5 NC, J12 NC, K4 NC, K5 NC, K12 NC, L11 NC, M4 NC, M5 NC, M7 NC, M8 NC, M11 NC, M12 NC, M13 NC, N5 NC, N6 NC, N10 NC, N11 NC, N12 NC, N13 NC, P2 NC, P3 NC, P15 NC, P16 NC, R15 NC, R16 NC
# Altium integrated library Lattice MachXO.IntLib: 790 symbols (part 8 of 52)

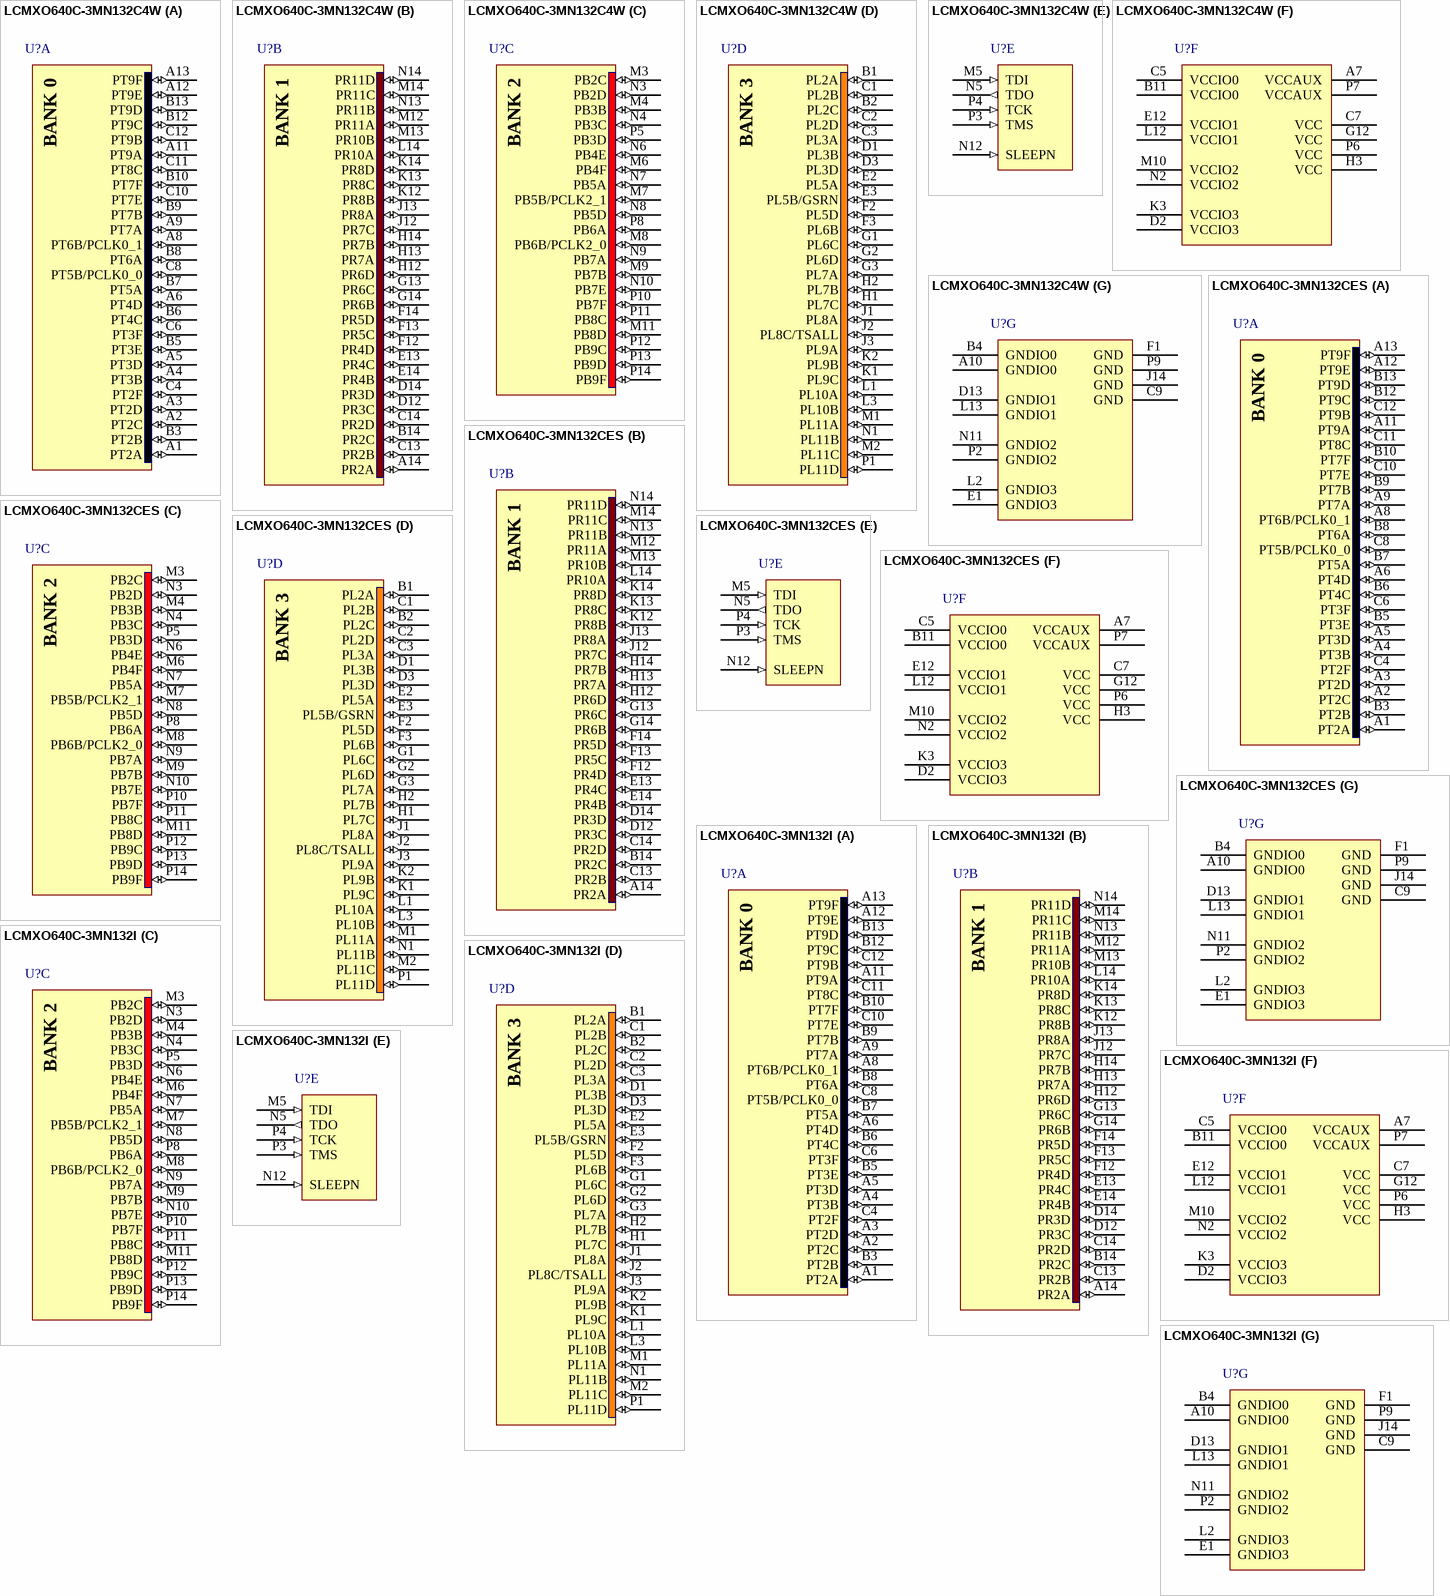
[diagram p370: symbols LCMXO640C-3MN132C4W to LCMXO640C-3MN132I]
## LCMXO640C-3MN132C4W
designator U?
MachXO 640 Crossover PLD, 1.8V/2.5V/3.3V, 101 User I/Os, 132-Pins csBGA, Speed Grade-3, Commercial Grade, Pb-Free
footprint csBGA132 (BGA, 132-Leads, Body 8x8mm, Pitch 0.5mm)
3D model MachXO640-csBGA132 (132-Ball Chip Scale Ball Grid Array (csBGA132))
signal-integrity model LCMXO640C_M132 (MachXO)
part A pins: A1 PT2A (io), A2 PT2C (io), A3 PT2D (io), A4 PT3B (io), A5 PT3D (io), A6 PT4D (io), A8 PT6B/PCLK0_1 (io), A9 PT7A (io), A11 PT9A (io), A12 PT9E (io), A13 PT9F (io), B3 PT2B (io), B5 PT3E (io), B6 PT4C (io), B7 PT5A (io), B8 PT6A (io), B9 PT7B (io), B10 PT7F (io), B12 PT9C (io), B13 PT9D (io), C4 PT2F (io), C6 PT3F (io), C8 PT5B/PCLK0_0 (io), C10 PT7E (io), C11 PT8C (io), C12 PT9B (io)
part B pins: A14 PR2A (io), B14 PR2C (io), C13 PR2B (io), C14 PR2D (io), D12 PR3C (io), D14 PR3D (io), E13 PR4C (io), E14 PR4B (io), F12 PR4D (io), F13 PR5C (io), F14 PR5D (io), G13 PR6C (io), G14 PR6B (io), H12 PR6D (io), H13 PR7A (io), H14 PR7B (io), J12 PR7C (io), J13 PR8A (io), K12 PR8B (io), K13 PR8C (io), K14 PR8D (io), L14 PR10A (io), M12 PR11A (io), M13 PR10B (io), M14 PR11C (io), N13 PR11B (io), N14 PR11D (io)
part C pins: M3 PB2C (io), M4 PB3B (io), M6 PB4F (io), M7 PB5B/PCLK2_1 (io), M8 PB6B/PCLK2_0 (io), M9 PB7B (io), M11 PB8D (io), N3 PB2D (io), N4 PB3C (io), N6 PB4E (io), N7 PB5A (io), N8 PB5D (io), N9 PB7A (io), N10 PB7E (io), P5 PB3D (io), P8 PB6A (io), P10 PB7F (io), P11 PB8C (io), P12 PB9C (io), P13 PB9D (io), P14 PB9F (io)
part D pins: B1 PL2A (io), B2 PL2C (io), C1 PL2B (io), C2 PL2D (io), C3 PL3A (io), D1 PL3B (io), D3 PL3D (io), E2 PL5A (io), E3 PL5B/GSRN (io), F2 PL5D (io), F3 PL6B (io), G1 PL6C (io), G2 PL6D (io), G3 PL7A (io), H1 PL7C (io), H2 PL7B (io), J1 PL8A (io), J2 PL8C/TSALL (io), J3 PL9A (io), K1 PL9C (io), K2 PL9B (io), L1 PL10A (io), L3 PL10B (io), M1 PL11A (io), M2 PL11C (io), N1 PL11B (io), P1 PL11D (io)
part E pins: M5 TDI (in) "Powered by VCCIO2", N5 TDO (out) "Powered by VCCIO2", N12 SLEEPN (in) "Powered by VCCIO2", P3 TMS (in) "Powered by VCCIO2", P4 TCK (in) "Powered by VCCIO2"
part F pins: A7 VCCAUX (power), B11 VCCIO0 (power), C5 VCCIO0 (power), C7 VCC (power), D2 VCCIO3 (power), E12 VCCIO1 (power), G12 VCC (power), H3 VCC (power), K3 VCCIO3 (power), L12 VCCIO1 (power), M10 VCCIO2 (power), N2 VCCIO2 (power), P6 VCC (power), P7 VCCAUX (power)
part G pins: A10 GNDIO0 (power), B4 GNDIO0 (power), C9 GND (power), D13 GNDIO1 (power), E1 GNDIO3 (power), F1 GND (power), J14 GND (power), L2 GNDIO3 (power), L13 GNDIO1 (power), N11 GNDIO2 (power), P2 GNDIO2 (power), P9 GND (power)

## LCMXO640C-3MN132CES
designator U?
MachXO 640 Crossover PLD, 1.8V/2.5V/3.3V, 101 User I/Os, 132-Pins csBGA, Speed Grade-3, Commercial Grade, Pb-Free, Engineering Sample
footprint csBGA132 (BGA, 132-Leads, Body 8x8mm, Pitch 0.5mm)
3D model MachXO640-csBGA132 (132-Ball Chip Scale Ball Grid Array (csBGA132))
signal-integrity model LCMXO640C_M132 (MachXO)
part A pins: A1 PT2A (io), A2 PT2C (io), A3 PT2D (io), A4 PT3B (io), A5 PT3D (io), A6 PT4D (io), A8 PT6B/PCLK0_1 (io), A9 PT7A (io), A11 PT9A (io), A12 PT9E (io), A13 PT9F (io), B3 PT2B (io), B5 PT3E (io), B6 PT4C (io), B7 PT5A (io), B8 PT6A (io), B9 PT7B (io), B10 PT7F (io), B12 PT9C (io), B13 PT9D (io), C4 PT2F (io), C6 PT3F (io), C8 PT5B/PCLK0_0 (io), C10 PT7E (io), C11 PT8C (io), C12 PT9B (io)
part B pins: A14 PR2A (io), B14 PR2C (io), C13 PR2B (io), C14 PR2D (io), D12 PR3C (io), D14 PR3D (io), E13 PR4C (io), E14 PR4B (io), F12 PR4D (io), F13 PR5C (io), F14 PR5D (io), G13 PR6C (io), G14 PR6B (io), H12 PR6D (io), H13 PR7A (io), H14 PR7B (io), J12 PR7C (io), J13 PR8A (io), K12 PR8B (io), K13 PR8C (io), K14 PR8D (io), L14 PR10A (io), M12 PR11A (io), M13 PR10B (io), M14 PR11C (io), N13 PR11B (io), N14 PR11D (io)
part C pins: M3 PB2C (io), M4 PB3B (io), M6 PB4F (io), M7 PB5B/PCLK2_1 (io), M8 PB6B/PCLK2_0 (io), M9 PB7B (io), M11 PB8D (io), N3 PB2D (io), N4 PB3C (io), N6 PB4E (io), N7 PB5A (io), N8 PB5D (io), N9 PB7A (io), N10 PB7E (io), P5 PB3D (io), P8 PB6A (io), P10 PB7F (io), P11 PB8C (io), P12 PB9C (io), P13 PB9D (io), P14 PB9F (io)
part D pins: B1 PL2A (io), B2 PL2C (io), C1 PL2B (io), C2 PL2D (io), C3 PL3A (io), D1 PL3B (io), D3 PL3D (io), E2 PL5A (io), E3 PL5B/GSRN (io), F2 PL5D (io), F3 PL6B (io), G1 PL6C (io), G2 PL6D (io), G3 PL7A (io), H1 PL7C (io), H2 PL7B (io), J1 PL8A (io), J2 PL8C/TSALL (io), J3 PL9A (io), K1 PL9C (io), K2 PL9B (io), L1 PL10A (io), L3 PL10B (io), M1 PL11A (io), M2 PL11C (io), N1 PL11B (io), P1 PL11D (io)
part E pins: M5 TDI (in) "Powered by VCCIO2", N5 TDO (out) "Powered by VCCIO2", N12 SLEEPN (in) "Powered by VCCIO2", P3 TMS (in) "Powered by VCCIO2", P4 TCK (in) "Powered by VCCIO2"
part F pins: A7 VCCAUX (power), B11 VCCIO0 (power), C5 VCCIO0 (power), C7 VCC (power), D2 VCCIO3 (power), E12 VCCIO1 (power), G12 VCC (power), H3 VCC (power), K3 VCCIO3 (power), L12 VCCIO1 (power), M10 VCCIO2 (power), N2 VCCIO2 (power), P6 VCC (power), P7 VCCAUX (power)
part G pins: A10 GNDIO0 (power), B4 GNDIO0 (power), C9 GND (power), D13 GNDIO1 (power), E1 GNDIO3 (power), F1 GND (power), J14 GND (power), L2 GNDIO3 (power), L13 GNDIO1 (power), N11 GNDIO2 (power), P2 GNDIO2 (power), P9 GND (power)

## LCMXO640C-3MN132I
designator U?
MachXO 640 Crossover PLD, 1.8V/2.5V/3.3V, 101 User I/Os, 132-Pins csBGA, Speed Grade-3, Industrial Grade, Pb-Free
footprint csBGA132 (BGA, 132-Leads, Body 8x8mm, Pitch 0.5mm)
3D model MachXO640-csBGA132 (132-Ball Chip Scale Ball Grid Array (csBGA132))
signal-integrity model LCMXO640C_M132 (MachXO)
part A pins: A1 PT2A (io), A2 PT2C (io), A3 PT2D (io), A4 PT3B (io), A5 PT3D (io), A6 PT4D (io), A8 PT6B/PCLK0_1 (io), A9 PT7A (io), A11 PT9A (io), A12 PT9E (io), A13 PT9F (io), B3 PT2B (io), B5 PT3E (io), B6 PT4C (io), B7 PT5A (io), B8 PT6A (io), B9 PT7B (io), B10 PT7F (io), B12 PT9C (io), B13 PT9D (io), C4 PT2F (io), C6 PT3F (io), C8 PT5B/PCLK0_0 (io), C10 PT7E (io), C11 PT8C (io), C12 PT9B (io)
part B pins: A14 PR2A (io), B14 PR2C (io), C13 PR2B (io), C14 PR2D (io), D12 PR3C (io), D14 PR3D (io), E13 PR4C (io), E14 PR4B (io), F12 PR4D (io), F13 PR5C (io), F14 PR5D (io), G13 PR6C (io), G14 PR6B (io), H12 PR6D (io), H13 PR7A (io), H14 PR7B (io), J12 PR7C (io), J13 PR8A (io), K12 PR8B (io), K13 PR8C (io), K14 PR8D (io), L14 PR10A (io), M12 PR11A (io), M13 PR10B (io), M14 PR11C (io), N13 PR11B (io), N14 PR11D (io)
part C pins: M3 PB2C (io), M4 PB3B (io), M6 PB4F (io), M7 PB5B/PCLK2_1 (io), M8 PB6B/PCLK2_0 (io), M9 PB7B (io), M11 PB8D (io), N3 PB2D (io), N4 PB3C (io), N6 PB4E (io), N7 PB5A (io), N8 PB5D (io), N9 PB7A (io), N10 PB7E (io), P5 PB3D (io), P8 PB6A (io), P10 PB7F (io), P11 PB8C (io), P12 PB9C (io), P13 PB9D (io), P14 PB9F (io)
part D pins: B1 PL2A (io), B2 PL2C (io), C1 PL2B (io), C2 PL2D (io), C3 PL3A (io), D1 PL3B (io), D3 PL3D (io), E2 PL5A (io), E3 PL5B/GSRN (io), F2 PL5D (io), F3 PL6B (io), G1 PL6C (io), G2 PL6D (io), G3 PL7A (io), H1 PL7C (io), H2 PL7B (io), J1 PL8A (io), J2 PL8C/TSALL (io), J3 PL9A (io), K1 PL9C (io), K2 PL9B (io), L1 PL10A (io), L3 PL10B (io), M1 PL11A (io), M2 PL11C (io), N1 PL11B (io), P1 PL11D (io)
part E pins: M5 TDI (in) "Powered by VCCIO2", N5 TDO (out) "Powered by VCCIO2", N12 SLEEPN (in) "Powered by VCCIO2", P3 TMS (in) "Powered by VCCIO2", P4 TCK (in) "Powered by VCCIO2"
part F pins: A7 VCCAUX (power), B11 VCCIO0 (power), C5 VCCIO0 (power), C7 VCC (power), D2 VCCIO3 (power), E12 VCCIO1 (power), G12 VCC (power), H3 VCC (power), K3 VCCIO3 (power), L12 VCCIO1 (power), M10 VCCIO2 (power), N2 VCCIO2 (power), P6 VCC (power), P7 VCCAUX (power)
part G pins: A10 GNDIO0 (power), B4 GNDIO0 (power), C9 GND (power), D13 GNDIO1 (power), E1 GNDIO3 (power), F1 GND (power), J14 GND (power), L2 GNDIO3 (power), L13 GNDIO1 (power), N11 GNDIO2 (power), P2 GNDIO2 (power), P9 GND (power)


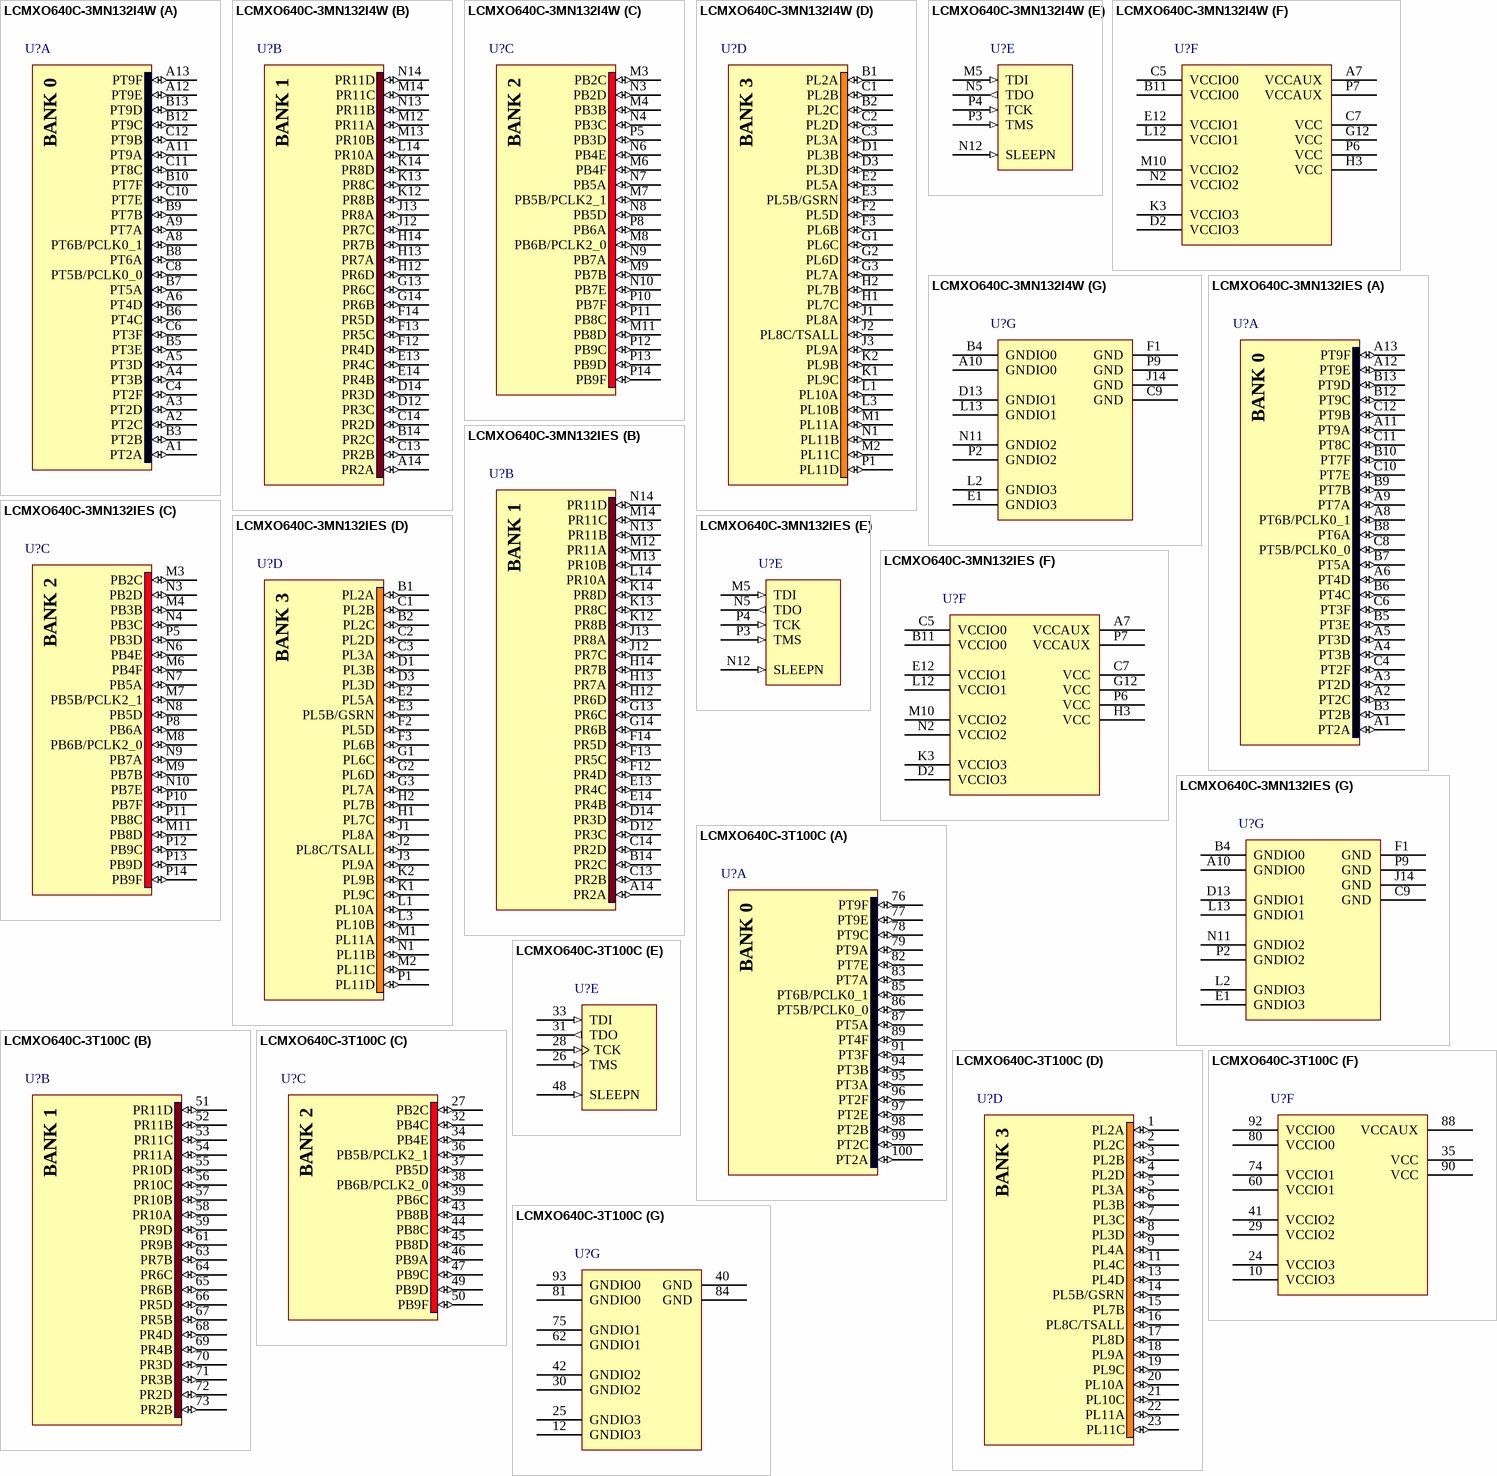
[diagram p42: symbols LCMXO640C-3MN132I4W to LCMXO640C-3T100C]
## LCMXO640C-3MN132I4W
designator U?
MachXO 640 Crossover PLD, 1.8V/2.5V/3.3V, 101 User I/Os, 132-Pins csBGA, Speed Grade-3, Industrial Grade, Pb-Free
footprint csBGA132 (BGA, 132-Leads, Body 8x8mm, Pitch 0.5mm)
3D model MachXO640-csBGA132 (132-Ball Chip Scale Ball Grid Array (csBGA132))
signal-integrity model LCMXO640C_M132 (MachXO)
part A pins: A1 PT2A (io), A2 PT2C (io), A3 PT2D (io), A4 PT3B (io), A5 PT3D (io), A6 PT4D (io), A8 PT6B/PCLK0_1 (io), A9 PT7A (io), A11 PT9A (io), A12 PT9E (io), A13 PT9F (io), B3 PT2B (io), B5 PT3E (io), B6 PT4C (io), B7 PT5A (io), B8 PT6A (io), B9 PT7B (io), B10 PT7F (io), B12 PT9C (io), B13 PT9D (io), C4 PT2F (io), C6 PT3F (io), C8 PT5B/PCLK0_0 (io), C10 PT7E (io), C11 PT8C (io), C12 PT9B (io)
part B pins: A14 PR2A (io), B14 PR2C (io), C13 PR2B (io), C14 PR2D (io), D12 PR3C (io), D14 PR3D (io), E13 PR4C (io), E14 PR4B (io), F12 PR4D (io), F13 PR5C (io), F14 PR5D (io), G13 PR6C (io), G14 PR6B (io), H12 PR6D (io), H13 PR7A (io), H14 PR7B (io), J12 PR7C (io), J13 PR8A (io), K12 PR8B (io), K13 PR8C (io), K14 PR8D (io), L14 PR10A (io), M12 PR11A (io), M13 PR10B (io), M14 PR11C (io), N13 PR11B (io), N14 PR11D (io)
part C pins: M3 PB2C (io), M4 PB3B (io), M6 PB4F (io), M7 PB5B/PCLK2_1 (io), M8 PB6B/PCLK2_0 (io), M9 PB7B (io), M11 PB8D (io), N3 PB2D (io), N4 PB3C (io), N6 PB4E (io), N7 PB5A (io), N8 PB5D (io), N9 PB7A (io), N10 PB7E (io), P5 PB3D (io), P8 PB6A (io), P10 PB7F (io), P11 PB8C (io), P12 PB9C (io), P13 PB9D (io), P14 PB9F (io)
part D pins: B1 PL2A (io), B2 PL2C (io), C1 PL2B (io), C2 PL2D (io), C3 PL3A (io), D1 PL3B (io), D3 PL3D (io), E2 PL5A (io), E3 PL5B/GSRN (io), F2 PL5D (io), F3 PL6B (io), G1 PL6C (io), G2 PL6D (io), G3 PL7A (io), H1 PL7C (io), H2 PL7B (io), J1 PL8A (io), J2 PL8C/TSALL (io), J3 PL9A (io), K1 PL9C (io), K2 PL9B (io), L1 PL10A (io), L3 PL10B (io), M1 PL11A (io), M2 PL11C (io), N1 PL11B (io), P1 PL11D (io)
part E pins: M5 TDI (in) "Powered by VCCIO2", N5 TDO (out) "Powered by VCCIO2", N12 SLEEPN (in) "Powered by VCCIO2", P3 TMS (in) "Powered by VCCIO2", P4 TCK (in) "Powered by VCCIO2"
part F pins: A7 VCCAUX (power), B11 VCCIO0 (power), C5 VCCIO0 (power), C7 VCC (power), D2 VCCIO3 (power), E12 VCCIO1 (power), G12 VCC (power), H3 VCC (power), K3 VCCIO3 (power), L12 VCCIO1 (power), M10 VCCIO2 (power), N2 VCCIO2 (power), P6 VCC (power), P7 VCCAUX (power)
part G pins: A10 GNDIO0 (power), B4 GNDIO0 (power), C9 GND (power), D13 GNDIO1 (power), E1 GNDIO3 (power), F1 GND (power), J14 GND (power), L2 GNDIO3 (power), L13 GNDIO1 (power), N11 GNDIO2 (power), P2 GNDIO2 (power), P9 GND (power)

## LCMXO640C-3MN132IES
designator U?
MachXO 640 Crossover PLD, 1.8V/2.5V/3.3V, 101 User I/Os, 132-Pins csBGA, Speed Grade-3, Industrial Grade, Pb-Free, Engineering Sample
footprint csBGA132 (BGA, 132-Leads, Body 8x8mm, Pitch 0.5mm)
3D model MachXO640-csBGA132 (132-Ball Chip Scale Ball Grid Array (csBGA132))
signal-integrity model LCMXO640C_M132 (MachXO)
part A pins: A1 PT2A (io), A2 PT2C (io), A3 PT2D (io), A4 PT3B (io), A5 PT3D (io), A6 PT4D (io), A8 PT6B/PCLK0_1 (io), A9 PT7A (io), A11 PT9A (io), A12 PT9E (io), A13 PT9F (io), B3 PT2B (io), B5 PT3E (io), B6 PT4C (io), B7 PT5A (io), B8 PT6A (io), B9 PT7B (io), B10 PT7F (io), B12 PT9C (io), B13 PT9D (io), C4 PT2F (io), C6 PT3F (io), C8 PT5B/PCLK0_0 (io), C10 PT7E (io), C11 PT8C (io), C12 PT9B (io)
part B pins: A14 PR2A (io), B14 PR2C (io), C13 PR2B (io), C14 PR2D (io), D12 PR3C (io), D14 PR3D (io), E13 PR4C (io), E14 PR4B (io), F12 PR4D (io), F13 PR5C (io), F14 PR5D (io), G13 PR6C (io), G14 PR6B (io), H12 PR6D (io), H13 PR7A (io), H14 PR7B (io), J12 PR7C (io), J13 PR8A (io), K12 PR8B (io), K13 PR8C (io), K14 PR8D (io), L14 PR10A (io), M12 PR11A (io), M13 PR10B (io), M14 PR11C (io), N13 PR11B (io), N14 PR11D (io)
part C pins: M3 PB2C (io), M4 PB3B (io), M6 PB4F (io), M7 PB5B/PCLK2_1 (io), M8 PB6B/PCLK2_0 (io), M9 PB7B (io), M11 PB8D (io), N3 PB2D (io), N4 PB3C (io), N6 PB4E (io), N7 PB5A (io), N8 PB5D (io), N9 PB7A (io), N10 PB7E (io), P5 PB3D (io), P8 PB6A (io), P10 PB7F (io), P11 PB8C (io), P12 PB9C (io), P13 PB9D (io), P14 PB9F (io)
part D pins: B1 PL2A (io), B2 PL2C (io), C1 PL2B (io), C2 PL2D (io), C3 PL3A (io), D1 PL3B (io), D3 PL3D (io), E2 PL5A (io), E3 PL5B/GSRN (io), F2 PL5D (io), F3 PL6B (io), G1 PL6C (io), G2 PL6D (io), G3 PL7A (io), H1 PL7C (io), H2 PL7B (io), J1 PL8A (io), J2 PL8C/TSALL (io), J3 PL9A (io), K1 PL9C (io), K2 PL9B (io), L1 PL10A (io), L3 PL10B (io), M1 PL11A (io), M2 PL11C (io), N1 PL11B (io), P1 PL11D (io)
part E pins: M5 TDI (in) "Powered by VCCIO2", N5 TDO (out) "Powered by VCCIO2", N12 SLEEPN (in) "Powered by VCCIO2", P3 TMS (in) "Powered by VCCIO2", P4 TCK (in) "Powered by VCCIO2"
part F pins: A7 VCCAUX (power), B11 VCCIO0 (power), C5 VCCIO0 (power), C7 VCC (power), D2 VCCIO3 (power), E12 VCCIO1 (power), G12 VCC (power), H3 VCC (power), K3 VCCIO3 (power), L12 VCCIO1 (power), M10 VCCIO2 (power), N2 VCCIO2 (power), P6 VCC (power), P7 VCCAUX (power)
part G pins: A10 GNDIO0 (power), B4 GNDIO0 (power), C9 GND (power), D13 GNDIO1 (power), E1 GNDIO3 (power), F1 GND (power), J14 GND (power), L2 GNDIO3 (power), L13 GNDIO1 (power), N11 GNDIO2 (power), P2 GNDIO2 (power), P9 GND (power)

## LCMXO640C-3T100C
designator U?
MachXO 640 Crossover PLD, 1.8V/2.5V/3.3V, 74 User I/Os, 100-Pins TQFP, Speed Grade-3, Commercial Grade
footprint TQFP100_N (Thin QFP, 100-Leads, Body 14x14mm, Pitch 0.5mm, IPC Medium Density)
footprint TQFP100_L (Thin QFP, 100-Leads, Body 14x14mm, Pitch 0.5mm, IPC High Density)
footprint TQFP100_M (Thin QFP, 100-Leads, Body 14x14mm, Pitch 0.5mm, IPC Low Density)
3D model MachXO640-TQFP100 (100-Pin Thin Quad Flat Pack (TQFP100))
signal-integrity model LCMXO640C_T100 (MachXO)
part A pins: 76 PT9F (io), 77 PT9E (io), 78 PT9C (io), 79 PT9A (io), 82 PT7E (io), 83 PT7A (io), 85 PT6B/PCLK0_1 (io), 86 PT5B/PCLK0_0 (io), 87 PT5A (io), 89 PT4F (io), 91 PT3F (io), 94 PT3B (io), 95 PT3A (io), 96 PT2F (io), 97 PT2E (io), 98 PT2B (io), 99 PT2C (io), 100 PT2A (io)
part B pins: 51 PR11D (io), 52 PR11B (io), 53 PR11C (io), 54 PR11A (io), 55 PR10D (io), 56 PR10C (io), 57 PR10B (io), 58 PR10A (io), 59 PR9D (io), 61 PR9B (io), 63 PR7B (io), 64 PR6C (io), 65 PR6B (io), 66 PR5D (io), 67 PR5B (io), 68 PR4D (io), 69 PR4B (io), 70 PR3D (io), 71 PR3B (io), 72 PR2D (io), 73 PR2B (io)
part C pins: 27 PB2C (io), 32 PB4C (io), 34 PB4E (io), 36 PB5B/PCLK2_1 (io), 37 PB5D (io), 38 PB6B/PCLK2_0 (io), 39 PB6C (io), 43 PB8B (io), 44 PB8C (io), 45 PB8D (io), 46 PB9A (io), 47 PB9C (io), 49 PB9D (io), 50 PB9F (io)
part D pins: 1 PL2A (io), 2 PL2C (io), 3 PL2B (io), 4 PL2D (io), 5 PL3A (io), 6 PL3B (io), 7 PL3C (io), 8 PL3D (io), 9 PL4A (io), 11 PL4C (io), 13 PL4D (io), 14 PL5B/GSRN (io), 15 PL7B (io), 16 PL8C/TSALL (io), 17 PL8D (io), 18 PL9A (io), 19 PL9C (io), 20 PL10A (io), 21 PL10C (io), 22 PL11A (io), 23 PL11C (io)
part E pins: 26 TMS (in) "Powered by VCCIO2", 28 TCK (in) "Powered by VCCIO2", 31 TDO (out) "Powered by VCCIO2", 33 TDI (in) "Powered by VCCIO2", 48 SLEEPN (in) "Powered by VCCIO2"
part F pins: 10 VCCIO3 (power), 24 VCCIO3 (power), 29 VCCIO2 (power), 35 VCC (power), 41 VCCIO2 (power), 60 VCCIO1 (power), 74 VCCIO1 (power), 80 VCCIO0 (power), 88 VCCAUX (power), 90 VCC (power), 92 VCCIO0 (power)
part G pins: 12 GNDIO3 (power), 25 GNDIO3 (power), 30 GNDIO2 (power), 40 GND (power), 42 GNDIO2 (power), 62 GNDIO1 (power), 75 GNDIO1 (power), 81 GNDIO0 (power), 84 GND (power), 93 GNDIO0 (power)


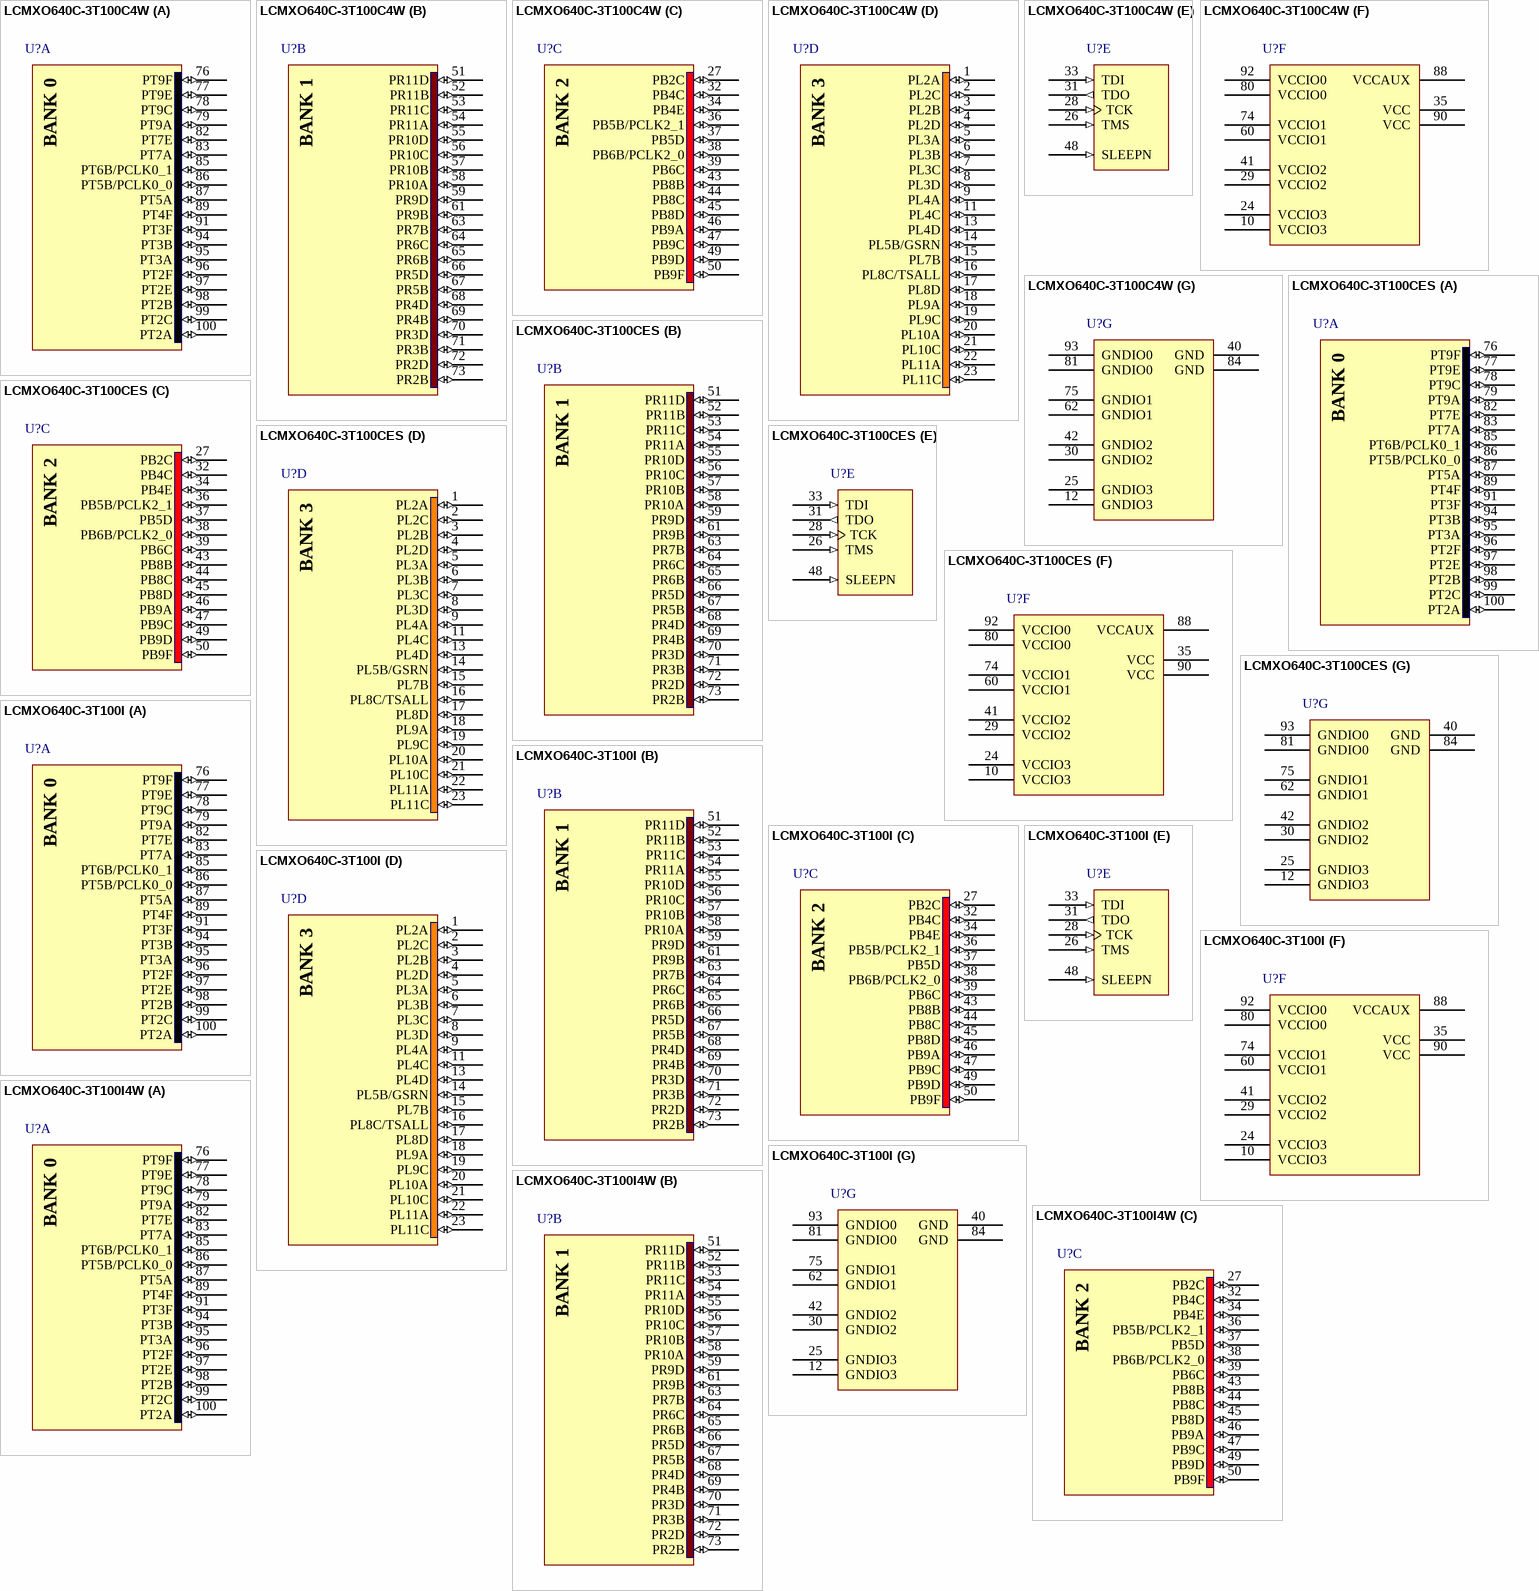
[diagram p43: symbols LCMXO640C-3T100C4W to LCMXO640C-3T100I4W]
## LCMXO640C-3T100C4W
designator U?
MachXO 640 Crossover PLD, 1.8V/2.5V/3.3V, 74 User I/Os, 100-Pins TQFP, Speed Grade-3, Commercial Grade
footprint TQFP100_N (Thin QFP, 100-Leads, Body 14x14mm, Pitch 0.5mm, IPC Medium Density)
footprint TQFP100_L (Thin QFP, 100-Leads, Body 14x14mm, Pitch 0.5mm, IPC High Density)
footprint TQFP100_M (Thin QFP, 100-Leads, Body 14x14mm, Pitch 0.5mm, IPC Low Density)
3D model MachXO640-TQFP100 (100-Pin Thin Quad Flat Pack (TQFP100))
signal-integrity model LCMXO640C_T100 (MachXO)
part A pins: 76 PT9F (io), 77 PT9E (io), 78 PT9C (io), 79 PT9A (io), 82 PT7E (io), 83 PT7A (io), 85 PT6B/PCLK0_1 (io), 86 PT5B/PCLK0_0 (io), 87 PT5A (io), 89 PT4F (io), 91 PT3F (io), 94 PT3B (io), 95 PT3A (io), 96 PT2F (io), 97 PT2E (io), 98 PT2B (io), 99 PT2C (io), 100 PT2A (io)
part B pins: 51 PR11D (io), 52 PR11B (io), 53 PR11C (io), 54 PR11A (io), 55 PR10D (io), 56 PR10C (io), 57 PR10B (io), 58 PR10A (io), 59 PR9D (io), 61 PR9B (io), 63 PR7B (io), 64 PR6C (io), 65 PR6B (io), 66 PR5D (io), 67 PR5B (io), 68 PR4D (io), 69 PR4B (io), 70 PR3D (io), 71 PR3B (io), 72 PR2D (io), 73 PR2B (io)
part C pins: 27 PB2C (io), 32 PB4C (io), 34 PB4E (io), 36 PB5B/PCLK2_1 (io), 37 PB5D (io), 38 PB6B/PCLK2_0 (io), 39 PB6C (io), 43 PB8B (io), 44 PB8C (io), 45 PB8D (io), 46 PB9A (io), 47 PB9C (io), 49 PB9D (io), 50 PB9F (io)
part D pins: 1 PL2A (io), 2 PL2C (io), 3 PL2B (io), 4 PL2D (io), 5 PL3A (io), 6 PL3B (io), 7 PL3C (io), 8 PL3D (io), 9 PL4A (io), 11 PL4C (io), 13 PL4D (io), 14 PL5B/GSRN (io), 15 PL7B (io), 16 PL8C/TSALL (io), 17 PL8D (io), 18 PL9A (io), 19 PL9C (io), 20 PL10A (io), 21 PL10C (io), 22 PL11A (io), 23 PL11C (io)
part E pins: 26 TMS (in) "Powered by VCCIO2", 28 TCK (in) "Powered by VCCIO2", 31 TDO (out) "Powered by VCCIO2", 33 TDI (in) "Powered by VCCIO2", 48 SLEEPN (in) "Powered by VCCIO2"
part F pins: 10 VCCIO3 (power), 24 VCCIO3 (power), 29 VCCIO2 (power), 35 VCC (power), 41 VCCIO2 (power), 60 VCCIO1 (power), 74 VCCIO1 (power), 80 VCCIO0 (power), 88 VCCAUX (power), 90 VCC (power), 92 VCCIO0 (power)
part G pins: 12 GNDIO3 (power), 25 GNDIO3 (power), 30 GNDIO2 (power), 40 GND (power), 42 GNDIO2 (power), 62 GNDIO1 (power), 75 GNDIO1 (power), 81 GNDIO0 (power), 84 GND (power), 93 GNDIO0 (power)

## LCMXO640C-3T100CES
designator U?
MachXO 640 Crossover PLD, 1.8V/2.5V/3.3V, 74 User I/Os, 100-Pins TQFP, Speed Grade-3, Commercial Grade, Engineering Sample
footprint TQFP100_N (Thin QFP, 100-Leads, Body 14x14mm, Pitch 0.5mm, IPC Medium Density)
footprint TQFP100_L (Thin QFP, 100-Leads, Body 14x14mm, Pitch 0.5mm, IPC High Density)
footprint TQFP100_M (Thin QFP, 100-Leads, Body 14x14mm, Pitch 0.5mm, IPC Low Density)
3D model MachXO640-TQFP100 (100-Pin Thin Quad Flat Pack (TQFP100))
signal-integrity model LCMXO640C_T100 (MachXO)
part A pins: 76 PT9F (io), 77 PT9E (io), 78 PT9C (io), 79 PT9A (io), 82 PT7E (io), 83 PT7A (io), 85 PT6B/PCLK0_1 (io), 86 PT5B/PCLK0_0 (io), 87 PT5A (io), 89 PT4F (io), 91 PT3F (io), 94 PT3B (io), 95 PT3A (io), 96 PT2F (io), 97 PT2E (io), 98 PT2B (io), 99 PT2C (io), 100 PT2A (io)
part B pins: 51 PR11D (io), 52 PR11B (io), 53 PR11C (io), 54 PR11A (io), 55 PR10D (io), 56 PR10C (io), 57 PR10B (io), 58 PR10A (io), 59 PR9D (io), 61 PR9B (io), 63 PR7B (io), 64 PR6C (io), 65 PR6B (io), 66 PR5D (io), 67 PR5B (io), 68 PR4D (io), 69 PR4B (io), 70 PR3D (io), 71 PR3B (io), 72 PR2D (io), 73 PR2B (io)
part C pins: 27 PB2C (io), 32 PB4C (io), 34 PB4E (io), 36 PB5B/PCLK2_1 (io), 37 PB5D (io), 38 PB6B/PCLK2_0 (io), 39 PB6C (io), 43 PB8B (io), 44 PB8C (io), 45 PB8D (io), 46 PB9A (io), 47 PB9C (io), 49 PB9D (io), 50 PB9F (io)
part D pins: 1 PL2A (io), 2 PL2C (io), 3 PL2B (io), 4 PL2D (io), 5 PL3A (io), 6 PL3B (io), 7 PL3C (io), 8 PL3D (io), 9 PL4A (io), 11 PL4C (io), 13 PL4D (io), 14 PL5B/GSRN (io), 15 PL7B (io), 16 PL8C/TSALL (io), 17 PL8D (io), 18 PL9A (io), 19 PL9C (io), 20 PL10A (io), 21 PL10C (io), 22 PL11A (io), 23 PL11C (io)
part E pins: 26 TMS (in) "Powered by VCCIO2", 28 TCK (in) "Powered by VCCIO2", 31 TDO (out) "Powered by VCCIO2", 33 TDI (in) "Powered by VCCIO2", 48 SLEEPN (in) "Powered by VCCIO2"
part F pins: 10 VCCIO3 (power), 24 VCCIO3 (power), 29 VCCIO2 (power), 35 VCC (power), 41 VCCIO2 (power), 60 VCCIO1 (power), 74 VCCIO1 (power), 80 VCCIO0 (power), 88 VCCAUX (power), 90 VCC (power), 92 VCCIO0 (power)
part G pins: 12 GNDIO3 (power), 25 GNDIO3 (power), 30 GNDIO2 (power), 40 GND (power), 42 GNDIO2 (power), 62 GNDIO1 (power), 75 GNDIO1 (power), 81 GNDIO0 (power), 84 GND (power), 93 GNDIO0 (power)

## LCMXO640C-3T100I
designator U?
MachXO 640 Crossover PLD, 1.8V/2.5V/3.3V, 74 User I/Os, 100-Pins TQFP, Speed Grade-3, Industrial Grade
footprint TQFP100_N (Thin QFP, 100-Leads, Body 14x14mm, Pitch 0.5mm, IPC Medium Density)
footprint TQFP100_L (Thin QFP, 100-Leads, Body 14x14mm, Pitch 0.5mm, IPC High Density)
footprint TQFP100_M (Thin QFP, 100-Leads, Body 14x14mm, Pitch 0.5mm, IPC Low Density)
3D model MachXO640-TQFP100 (100-Pin Thin Quad Flat Pack (TQFP100))
signal-integrity model LCMXO640C_T100 (MachXO)
part A pins: 76 PT9F (io), 77 PT9E (io), 78 PT9C (io), 79 PT9A (io), 82 PT7E (io), 83 PT7A (io), 85 PT6B/PCLK0_1 (io), 86 PT5B/PCLK0_0 (io), 87 PT5A (io), 89 PT4F (io), 91 PT3F (io), 94 PT3B (io), 95 PT3A (io), 96 PT2F (io), 97 PT2E (io), 98 PT2B (io), 99 PT2C (io), 100 PT2A (io)
part B pins: 51 PR11D (io), 52 PR11B (io), 53 PR11C (io), 54 PR11A (io), 55 PR10D (io), 56 PR10C (io), 57 PR10B (io), 58 PR10A (io), 59 PR9D (io), 61 PR9B (io), 63 PR7B (io), 64 PR6C (io), 65 PR6B (io), 66 PR5D (io), 67 PR5B (io), 68 PR4D (io), 69 PR4B (io), 70 PR3D (io), 71 PR3B (io), 72 PR2D (io), 73 PR2B (io)
part C pins: 27 PB2C (io), 32 PB4C (io), 34 PB4E (io), 36 PB5B/PCLK2_1 (io), 37 PB5D (io), 38 PB6B/PCLK2_0 (io), 39 PB6C (io), 43 PB8B (io), 44 PB8C (io), 45 PB8D (io), 46 PB9A (io), 47 PB9C (io), 49 PB9D (io), 50 PB9F (io)
part D pins: 1 PL2A (io), 2 PL2C (io), 3 PL2B (io), 4 PL2D (io), 5 PL3A (io), 6 PL3B (io), 7 PL3C (io), 8 PL3D (io), 9 PL4A (io), 11 PL4C (io), 13 PL4D (io), 14 PL5B/GSRN (io), 15 PL7B (io), 16 PL8C/TSALL (io), 17 PL8D (io), 18 PL9A (io), 19 PL9C (io), 20 PL10A (io), 21 PL10C (io), 22 PL11A (io), 23 PL11C (io)
part E pins: 26 TMS (in) "Powered by VCCIO2", 28 TCK (in) "Powered by VCCIO2", 31 TDO (out) "Powered by VCCIO2", 33 TDI (in) "Powered by VCCIO2", 48 SLEEPN (in) "Powered by VCCIO2"
part F pins: 10 VCCIO3 (power), 24 VCCIO3 (power), 29 VCCIO2 (power), 35 VCC (power), 41 VCCIO2 (power), 60 VCCIO1 (power), 74 VCCIO1 (power), 80 VCCIO0 (power), 88 VCCAUX (power), 90 VCC (power), 92 VCCIO0 (power)
part G pins: 12 GNDIO3 (power), 25 GNDIO3 (power), 30 GNDIO2 (power), 40 GND (power), 42 GNDIO2 (power), 62 GNDIO1 (power), 75 GNDIO1 (power), 81 GNDIO0 (power), 84 GND (power), 93 GNDIO0 (power)


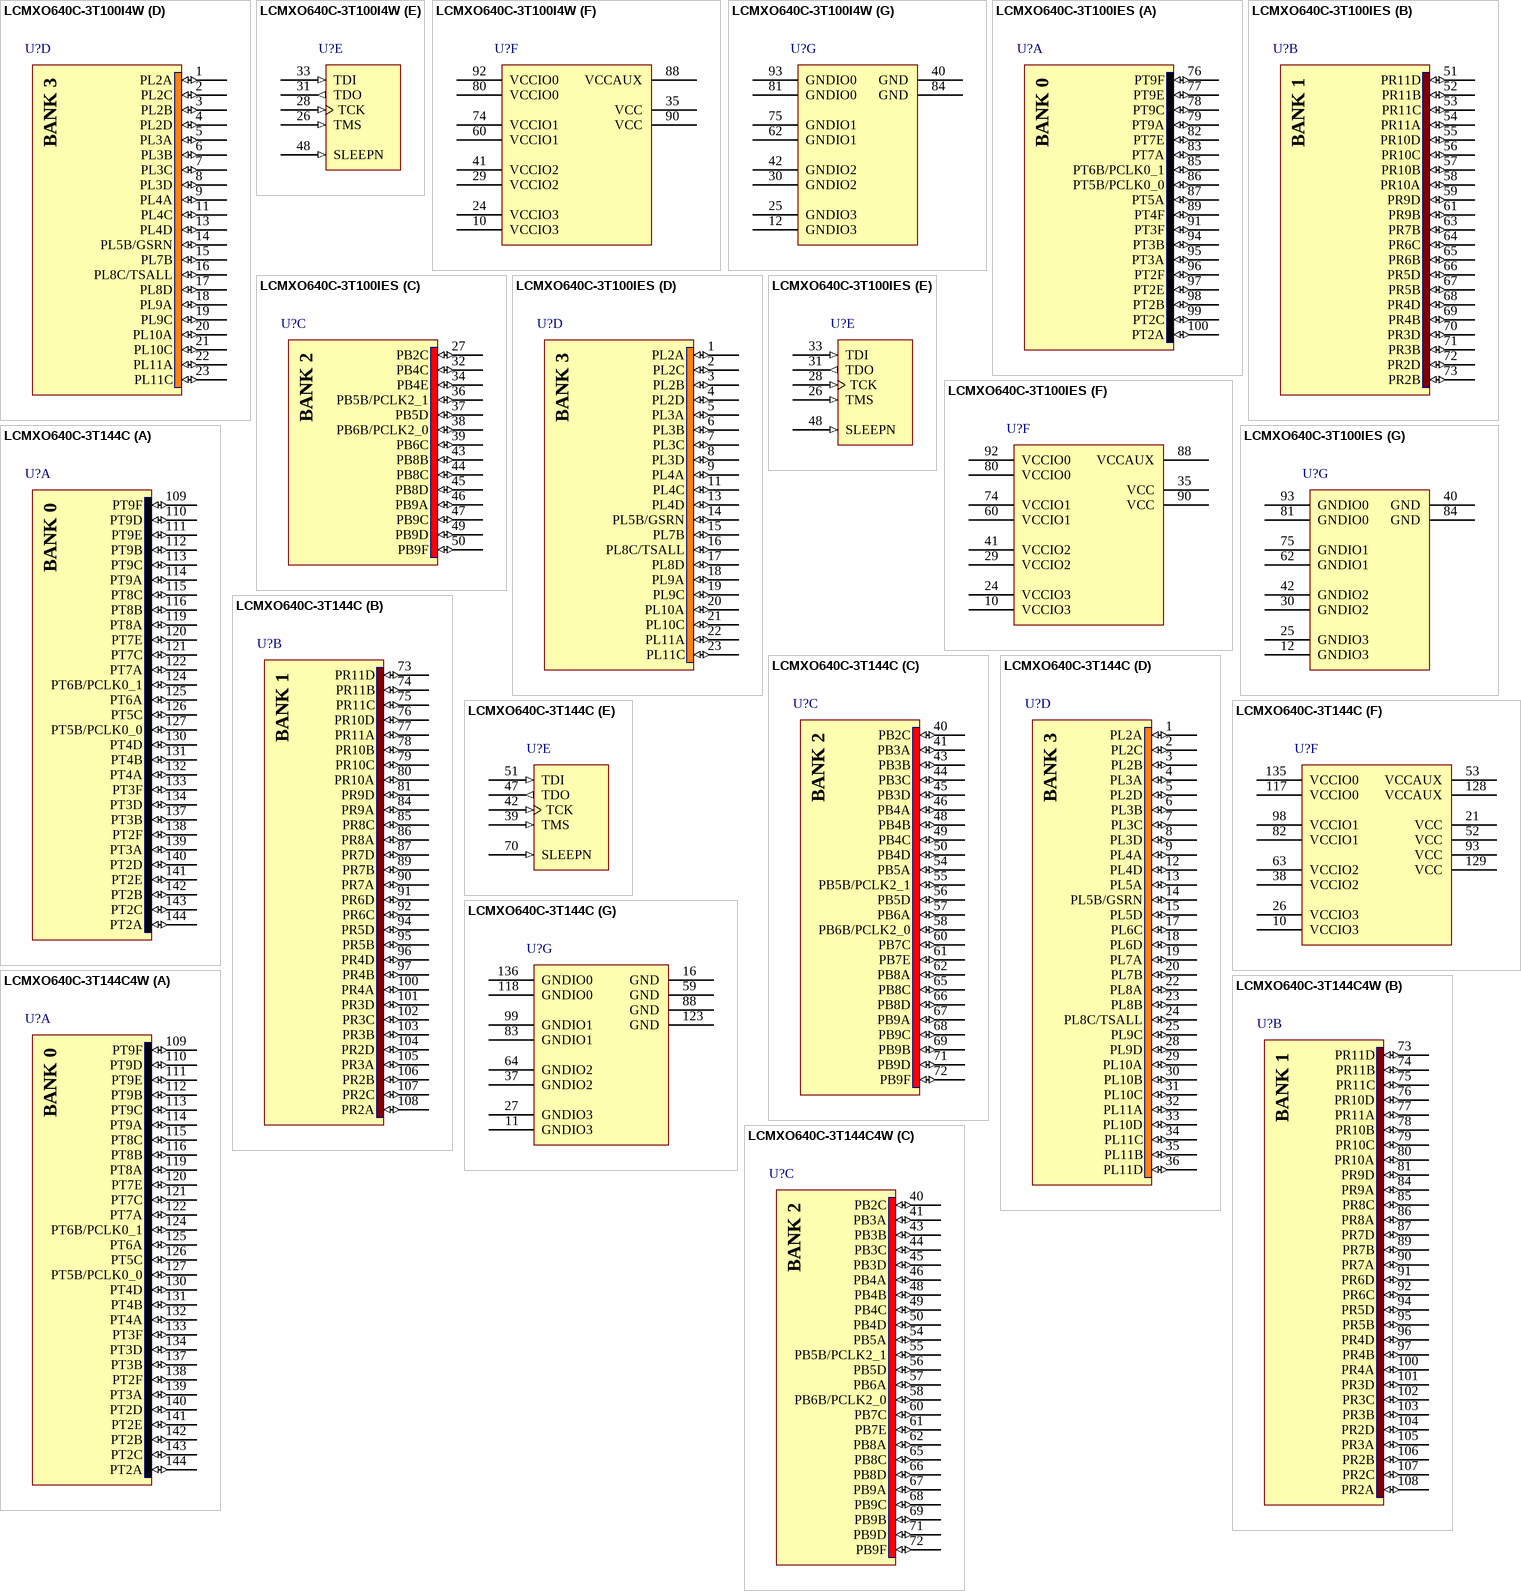
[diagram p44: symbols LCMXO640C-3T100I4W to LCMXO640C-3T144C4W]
## LCMXO640C-3T100I4W
designator U?
MachXO 640 Crossover PLD, 1.8V/2.5V/3.3V, 74 User I/Os, 100-Pins TQFP, Speed Grade-3, Industrial Grade
footprint TQFP100_N (Thin QFP, 100-Leads, Body 14x14mm, Pitch 0.5mm, IPC Medium Density)
footprint TQFP100_L (Thin QFP, 100-Leads, Body 14x14mm, Pitch 0.5mm, IPC High Density)
footprint TQFP100_M (Thin QFP, 100-Leads, Body 14x14mm, Pitch 0.5mm, IPC Low Density)
3D model MachXO640-TQFP100 (100-Pin Thin Quad Flat Pack (TQFP100))
signal-integrity model LCMXO640C_T100 (MachXO)
part A pins: 76 PT9F (io), 77 PT9E (io), 78 PT9C (io), 79 PT9A (io), 82 PT7E (io), 83 PT7A (io), 85 PT6B/PCLK0_1 (io), 86 PT5B/PCLK0_0 (io), 87 PT5A (io), 89 PT4F (io), 91 PT3F (io), 94 PT3B (io), 95 PT3A (io), 96 PT2F (io), 97 PT2E (io), 98 PT2B (io), 99 PT2C (io), 100 PT2A (io)
part B pins: 51 PR11D (io), 52 PR11B (io), 53 PR11C (io), 54 PR11A (io), 55 PR10D (io), 56 PR10C (io), 57 PR10B (io), 58 PR10A (io), 59 PR9D (io), 61 PR9B (io), 63 PR7B (io), 64 PR6C (io), 65 PR6B (io), 66 PR5D (io), 67 PR5B (io), 68 PR4D (io), 69 PR4B (io), 70 PR3D (io), 71 PR3B (io), 72 PR2D (io), 73 PR2B (io)
part C pins: 27 PB2C (io), 32 PB4C (io), 34 PB4E (io), 36 PB5B/PCLK2_1 (io), 37 PB5D (io), 38 PB6B/PCLK2_0 (io), 39 PB6C (io), 43 PB8B (io), 44 PB8C (io), 45 PB8D (io), 46 PB9A (io), 47 PB9C (io), 49 PB9D (io), 50 PB9F (io)
part D pins: 1 PL2A (io), 2 PL2C (io), 3 PL2B (io), 4 PL2D (io), 5 PL3A (io), 6 PL3B (io), 7 PL3C (io), 8 PL3D (io), 9 PL4A (io), 11 PL4C (io), 13 PL4D (io), 14 PL5B/GSRN (io), 15 PL7B (io), 16 PL8C/TSALL (io), 17 PL8D (io), 18 PL9A (io), 19 PL9C (io), 20 PL10A (io), 21 PL10C (io), 22 PL11A (io), 23 PL11C (io)
part E pins: 26 TMS (in) "Powered by VCCIO2", 28 TCK (in) "Powered by VCCIO2", 31 TDO (out) "Powered by VCCIO2", 33 TDI (in) "Powered by VCCIO2", 48 SLEEPN (in) "Powered by VCCIO2"
part F pins: 10 VCCIO3 (power), 24 VCCIO3 (power), 29 VCCIO2 (power), 35 VCC (power), 41 VCCIO2 (power), 60 VCCIO1 (power), 74 VCCIO1 (power), 80 VCCIO0 (power), 88 VCCAUX (power), 90 VCC (power), 92 VCCIO0 (power)
part G pins: 12 GNDIO3 (power), 25 GNDIO3 (power), 30 GNDIO2 (power), 40 GND (power), 42 GNDIO2 (power), 62 GNDIO1 (power), 75 GNDIO1 (power), 81 GNDIO0 (power), 84 GND (power), 93 GNDIO0 (power)

## LCMXO640C-3T100IES
designator U?
MachXO 640 Crossover PLD, 1.8V/2.5V/3.3V, 74 User I/Os, 100-Pins TQFP, Speed Grade-3, Industrial Grade, Engineering Sample
footprint TQFP100_N (Thin QFP, 100-Leads, Body 14x14mm, Pitch 0.5mm, IPC Medium Density)
footprint TQFP100_L (Thin QFP, 100-Leads, Body 14x14mm, Pitch 0.5mm, IPC High Density)
footprint TQFP100_M (Thin QFP, 100-Leads, Body 14x14mm, Pitch 0.5mm, IPC Low Density)
3D model MachXO640-TQFP100 (100-Pin Thin Quad Flat Pack (TQFP100))
signal-integrity model LCMXO640C_T100 (MachXO)
part A pins: 76 PT9F (io), 77 PT9E (io), 78 PT9C (io), 79 PT9A (io), 82 PT7E (io), 83 PT7A (io), 85 PT6B/PCLK0_1 (io), 86 PT5B/PCLK0_0 (io), 87 PT5A (io), 89 PT4F (io), 91 PT3F (io), 94 PT3B (io), 95 PT3A (io), 96 PT2F (io), 97 PT2E (io), 98 PT2B (io), 99 PT2C (io), 100 PT2A (io)
part B pins: 51 PR11D (io), 52 PR11B (io), 53 PR11C (io), 54 PR11A (io), 55 PR10D (io), 56 PR10C (io), 57 PR10B (io), 58 PR10A (io), 59 PR9D (io), 61 PR9B (io), 63 PR7B (io), 64 PR6C (io), 65 PR6B (io), 66 PR5D (io), 67 PR5B (io), 68 PR4D (io), 69 PR4B (io), 70 PR3D (io), 71 PR3B (io), 72 PR2D (io), 73 PR2B (io)
part C pins: 27 PB2C (io), 32 PB4C (io), 34 PB4E (io), 36 PB5B/PCLK2_1 (io), 37 PB5D (io), 38 PB6B/PCLK2_0 (io), 39 PB6C (io), 43 PB8B (io), 44 PB8C (io), 45 PB8D (io), 46 PB9A (io), 47 PB9C (io), 49 PB9D (io), 50 PB9F (io)
part D pins: 1 PL2A (io), 2 PL2C (io), 3 PL2B (io), 4 PL2D (io), 5 PL3A (io), 6 PL3B (io), 7 PL3C (io), 8 PL3D (io), 9 PL4A (io), 11 PL4C (io), 13 PL4D (io), 14 PL5B/GSRN (io), 15 PL7B (io), 16 PL8C/TSALL (io), 17 PL8D (io), 18 PL9A (io), 19 PL9C (io), 20 PL10A (io), 21 PL10C (io), 22 PL11A (io), 23 PL11C (io)
part E pins: 26 TMS (in) "Powered by VCCIO2", 28 TCK (in) "Powered by VCCIO2", 31 TDO (out) "Powered by VCCIO2", 33 TDI (in) "Powered by VCCIO2", 48 SLEEPN (in) "Powered by VCCIO2"
part F pins: 10 VCCIO3 (power), 24 VCCIO3 (power), 29 VCCIO2 (power), 35 VCC (power), 41 VCCIO2 (power), 60 VCCIO1 (power), 74 VCCIO1 (power), 80 VCCIO0 (power), 88 VCCAUX (power), 90 VCC (power), 92 VCCIO0 (power)
part G pins: 12 GNDIO3 (power), 25 GNDIO3 (power), 30 GNDIO2 (power), 40 GND (power), 42 GNDIO2 (power), 62 GNDIO1 (power), 75 GNDIO1 (power), 81 GNDIO0 (power), 84 GND (power), 93 GNDIO0 (power)

## LCMXO640C-3T144C
designator U?
MachXO 640 Crossover PLD, 1.8V/2.5V/3.3V, 113 User I/Os, 144-Pins TQFP, Speed Grade-3, Commercial Grade
footprint TQFP144_N (Thin QFP, 144-Leads, Body 20x20mm, Pitch 0.5mm, IPC Medium Density)
footprint TQFP144_L (Thin QFP, 144-Leads, Body 20x20mm, Pitch 0.5mm, IPC High Density)
footprint TQFP144_M (Thin QFP, 144-Leads, Body 20x20mm, Pitch 0.5mm, IPC Low Density)
3D model MachXO640-TQFP144 (144-Pin Thin Quad Flat Pack (TQFP144))
signal-integrity model LCMXO640C_T144 (MachXO)
part A pins: 109 PT9F (io), 110 PT9D (io), 111 PT9E (io), 112 PT9B (io), 113 PT9C (io), 114 PT9A (io), 115 PT8C (io), 116 PT8B (io), 119 PT8A (io), 120 PT7E (io), 121 PT7C (io), 122 PT7A (io), 124 PT6B/PCLK0_1 (io), 125 PT6A (io), 126 PT5C (io), 127 PT5B/PCLK0_0 (io), 130 PT4D (io), 131 PT4B (io), 132 PT4A (io), 133 PT3F (io), 134 PT3D (io), 137 PT3B (io), 138 PT2F (io), 139 PT3A (io), 140 PT2D (io), 141 PT2E (io), 142 PT2B (io), 143 PT2C (io), 144 PT2A (io)
part B pins: 73 PR11D (io), 74 PR11B (io), 75 PR11C (io), 76 PR10D (io), 77 PR11A (io), 78 PR10B (io), 79 PR10C (io), 80 PR10A (io), 81 PR9D (io), 84 PR9A (io), 85 PR8C (io), 86 PR8A (io), 87 PR7D (io), 89 PR7B (io), 90 PR7A (io), 91 PR6D (io), 92 PR6C (io), 94 PR5D (io), 95 PR5B (io), 96 PR4D (io), 97 PR4B (io), 100 PR4A (io), 101 PR3D (io), 102 PR3C (io), 103 PR3B (io), 104 PR2D (io), 105 PR3A (io), 106 PR2B (io), 107 PR2C (io), 108 PR2A (io)
part C pins: 40 PB2C (io), 41 PB3A (io), 43 PB3B (io), 44 PB3C (io), 45 PB3D (io), 46 PB4A (io), 48 PB4B (io), 49 PB4C (io), 50 PB4D (io), 54 PB5A (io), 55 PB5B/PCLK2_1 (io), 56 PB5D (io), 57 PB6A (io), 58 PB6B/PCLK2_0 (io), 60 PB7C (io), 61 PB7E (io), 62 PB8A (io), 65 PB8C (io), 66 PB8D (io), 67 PB9A (io), 68 PB9C (io), 69 PB9B (io), 71 PB9D (io), 72 PB9F (io)
part D pins: 1 PL2A (io), 2 PL2C (io), 3 PL2B (io), 4 PL3A (io), 5 PL2D (io), 6 PL3B (io), 7 PL3C (io), 8 PL3D (io), 9 PL4A (io), 12 PL4D (io), 13 PL5A (io), 14 PL5B/GSRN (io), 15 PL5D (io), 17 PL6C (io), 18 PL6D (io), 19 PL7A (io), 20 PL7B (io), 22 PL8A (io), 23 PL8B (io), 24 PL8C/TSALL (io), 25 PL9C (io), 28 PL9D (io), 29 PL10A (io), 30 PL10B (io), 31 PL10C (io), 32 PL11A (io), 33 PL10D (io), 34 PL11C (io), 35 PL11B (io), 36 PL11D (io)
part E pins: 39 TMS (in) "Powered by VCCIO2", 42 TCK (in) "Powered by VCCIO2", 47 TDO (out) "Powered by VCCIO2", 51 TDI (in) "Powered by VCCIO2", 70 SLEEPN (in) "Powered by VCCIO2"
part F pins: 10 VCCIO3 (power), 21 VCC (power), 26 VCCIO3 (power), 38 VCCIO2 (power), 52 VCC (power), 53 VCCAUX (power), 63 VCCIO2 (power), 82 VCCIO1 (power), 93 VCC (power), 98 VCCIO1 (power), 117 VCCIO0 (power), 128 VCCAUX (power), 129 VCC (power), 135 VCCIO0 (power)
part G pins: 11 GNDIO3 (power), 16 GND (power), 27 GNDIO3 (power), 37 GNDIO2 (power), 59 GND (power), 64 GNDIO2 (power), 83 GNDIO1 (power), 88 GND (power), 99 GNDIO1 (power), 118 GNDIO0 (power), 123 GND (power), 136 GNDIO0 (power)


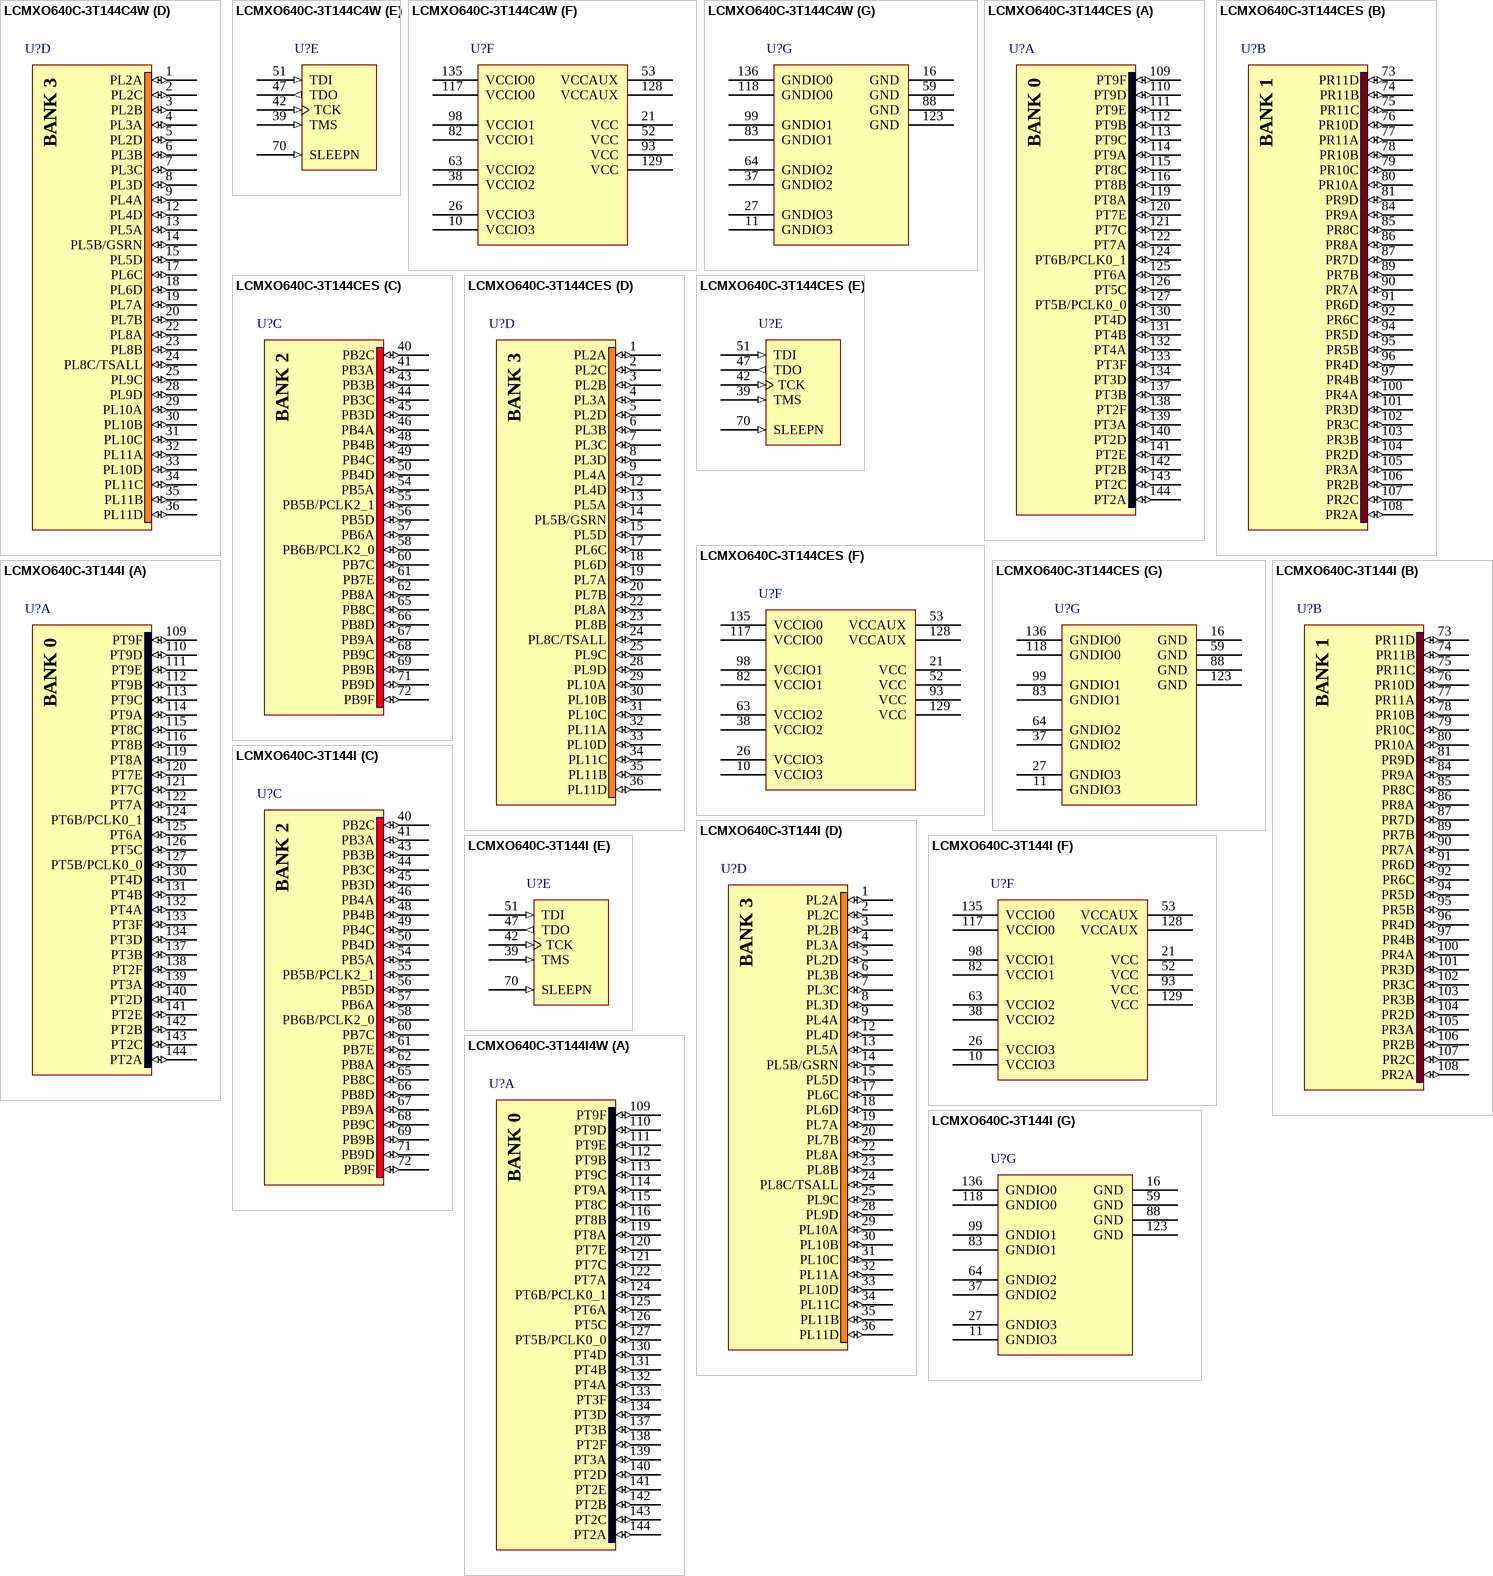
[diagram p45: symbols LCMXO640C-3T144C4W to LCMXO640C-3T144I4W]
## LCMXO640C-3T144C4W
designator U?
MachXO 640 Crossover PLD, 1.8V/2.5V/3.3V, 113 User I/Os, 144-Pins TQFP, Speed Grade-3, Commercial Grade
footprint TQFP144_N (Thin QFP, 144-Leads, Body 20x20mm, Pitch 0.5mm, IPC Medium Density)
footprint TQFP144_L (Thin QFP, 144-Leads, Body 20x20mm, Pitch 0.5mm, IPC High Density)
footprint TQFP144_M (Thin QFP, 144-Leads, Body 20x20mm, Pitch 0.5mm, IPC Low Density)
3D model MachXO640-TQFP144 (144-Pin Thin Quad Flat Pack (TQFP144))
signal-integrity model LCMXO640C_T144 (MachXO)
part A pins: 109 PT9F (io), 110 PT9D (io), 111 PT9E (io), 112 PT9B (io), 113 PT9C (io), 114 PT9A (io), 115 PT8C (io), 116 PT8B (io), 119 PT8A (io), 120 PT7E (io), 121 PT7C (io), 122 PT7A (io), 124 PT6B/PCLK0_1 (io), 125 PT6A (io), 126 PT5C (io), 127 PT5B/PCLK0_0 (io), 130 PT4D (io), 131 PT4B (io), 132 PT4A (io), 133 PT3F (io), 134 PT3D (io), 137 PT3B (io), 138 PT2F (io), 139 PT3A (io), 140 PT2D (io), 141 PT2E (io), 142 PT2B (io), 143 PT2C (io), 144 PT2A (io)
part B pins: 73 PR11D (io), 74 PR11B (io), 75 PR11C (io), 76 PR10D (io), 77 PR11A (io), 78 PR10B (io), 79 PR10C (io), 80 PR10A (io), 81 PR9D (io), 84 PR9A (io), 85 PR8C (io), 86 PR8A (io), 87 PR7D (io), 89 PR7B (io), 90 PR7A (io), 91 PR6D (io), 92 PR6C (io), 94 PR5D (io), 95 PR5B (io), 96 PR4D (io), 97 PR4B (io), 100 PR4A (io), 101 PR3D (io), 102 PR3C (io), 103 PR3B (io), 104 PR2D (io), 105 PR3A (io), 106 PR2B (io), 107 PR2C (io), 108 PR2A (io)
part C pins: 40 PB2C (io), 41 PB3A (io), 43 PB3B (io), 44 PB3C (io), 45 PB3D (io), 46 PB4A (io), 48 PB4B (io), 49 PB4C (io), 50 PB4D (io), 54 PB5A (io), 55 PB5B/PCLK2_1 (io), 56 PB5D (io), 57 PB6A (io), 58 PB6B/PCLK2_0 (io), 60 PB7C (io), 61 PB7E (io), 62 PB8A (io), 65 PB8C (io), 66 PB8D (io), 67 PB9A (io), 68 PB9C (io), 69 PB9B (io), 71 PB9D (io), 72 PB9F (io)
part D pins: 1 PL2A (io), 2 PL2C (io), 3 PL2B (io), 4 PL3A (io), 5 PL2D (io), 6 PL3B (io), 7 PL3C (io), 8 PL3D (io), 9 PL4A (io), 12 PL4D (io), 13 PL5A (io), 14 PL5B/GSRN (io), 15 PL5D (io), 17 PL6C (io), 18 PL6D (io), 19 PL7A (io), 20 PL7B (io), 22 PL8A (io), 23 PL8B (io), 24 PL8C/TSALL (io), 25 PL9C (io), 28 PL9D (io), 29 PL10A (io), 30 PL10B (io), 31 PL10C (io), 32 PL11A (io), 33 PL10D (io), 34 PL11C (io), 35 PL11B (io), 36 PL11D (io)
part E pins: 39 TMS (in) "Powered by VCCIO2", 42 TCK (in) "Powered by VCCIO2", 47 TDO (out) "Powered by VCCIO2", 51 TDI (in) "Powered by VCCIO2", 70 SLEEPN (in) "Powered by VCCIO2"
part F pins: 10 VCCIO3 (power), 21 VCC (power), 26 VCCIO3 (power), 38 VCCIO2 (power), 52 VCC (power), 53 VCCAUX (power), 63 VCCIO2 (power), 82 VCCIO1 (power), 93 VCC (power), 98 VCCIO1 (power), 117 VCCIO0 (power), 128 VCCAUX (power), 129 VCC (power), 135 VCCIO0 (power)
part G pins: 11 GNDIO3 (power), 16 GND (power), 27 GNDIO3 (power), 37 GNDIO2 (power), 59 GND (power), 64 GNDIO2 (power), 83 GNDIO1 (power), 88 GND (power), 99 GNDIO1 (power), 118 GNDIO0 (power), 123 GND (power), 136 GNDIO0 (power)

## LCMXO640C-3T144CES
designator U?
MachXO 640 Crossover PLD, 1.8V/2.5V/3.3V, 113 User I/Os, 144-Pins TQFP, Speed Grade-3, Commercial Grade, Engineering Sample
footprint TQFP144_N (Thin QFP, 144-Leads, Body 20x20mm, Pitch 0.5mm, IPC Medium Density)
footprint TQFP144_L (Thin QFP, 144-Leads, Body 20x20mm, Pitch 0.5mm, IPC High Density)
footprint TQFP144_M (Thin QFP, 144-Leads, Body 20x20mm, Pitch 0.5mm, IPC Low Density)
3D model MachXO640-TQFP144 (144-Pin Thin Quad Flat Pack (TQFP144))
signal-integrity model LCMXO640C_T144 (MachXO)
part A pins: 109 PT9F (io), 110 PT9D (io), 111 PT9E (io), 112 PT9B (io), 113 PT9C (io), 114 PT9A (io), 115 PT8C (io), 116 PT8B (io), 119 PT8A (io), 120 PT7E (io), 121 PT7C (io), 122 PT7A (io), 124 PT6B/PCLK0_1 (io), 125 PT6A (io), 126 PT5C (io), 127 PT5B/PCLK0_0 (io), 130 PT4D (io), 131 PT4B (io), 132 PT4A (io), 133 PT3F (io), 134 PT3D (io), 137 PT3B (io), 138 PT2F (io), 139 PT3A (io), 140 PT2D (io), 141 PT2E (io), 142 PT2B (io), 143 PT2C (io), 144 PT2A (io)
part B pins: 73 PR11D (io), 74 PR11B (io), 75 PR11C (io), 76 PR10D (io), 77 PR11A (io), 78 PR10B (io), 79 PR10C (io), 80 PR10A (io), 81 PR9D (io), 84 PR9A (io), 85 PR8C (io), 86 PR8A (io), 87 PR7D (io), 89 PR7B (io), 90 PR7A (io), 91 PR6D (io), 92 PR6C (io), 94 PR5D (io), 95 PR5B (io), 96 PR4D (io), 97 PR4B (io), 100 PR4A (io), 101 PR3D (io), 102 PR3C (io), 103 PR3B (io), 104 PR2D (io), 105 PR3A (io), 106 PR2B (io), 107 PR2C (io), 108 PR2A (io)
part C pins: 40 PB2C (io), 41 PB3A (io), 43 PB3B (io), 44 PB3C (io), 45 PB3D (io), 46 PB4A (io), 48 PB4B (io), 49 PB4C (io), 50 PB4D (io), 54 PB5A (io), 55 PB5B/PCLK2_1 (io), 56 PB5D (io), 57 PB6A (io), 58 PB6B/PCLK2_0 (io), 60 PB7C (io), 61 PB7E (io), 62 PB8A (io), 65 PB8C (io), 66 PB8D (io), 67 PB9A (io), 68 PB9C (io), 69 PB9B (io), 71 PB9D (io), 72 PB9F (io)
part D pins: 1 PL2A (io), 2 PL2C (io), 3 PL2B (io), 4 PL3A (io), 5 PL2D (io), 6 PL3B (io), 7 PL3C (io), 8 PL3D (io), 9 PL4A (io), 12 PL4D (io), 13 PL5A (io), 14 PL5B/GSRN (io), 15 PL5D (io), 17 PL6C (io), 18 PL6D (io), 19 PL7A (io), 20 PL7B (io), 22 PL8A (io), 23 PL8B (io), 24 PL8C/TSALL (io), 25 PL9C (io), 28 PL9D (io), 29 PL10A (io), 30 PL10B (io), 31 PL10C (io), 32 PL11A (io), 33 PL10D (io), 34 PL11C (io), 35 PL11B (io), 36 PL11D (io)
part E pins: 39 TMS (in) "Powered by VCCIO2", 42 TCK (in) "Powered by VCCIO2", 47 TDO (out) "Powered by VCCIO2", 51 TDI (in) "Powered by VCCIO2", 70 SLEEPN (in) "Powered by VCCIO2"
part F pins: 10 VCCIO3 (power), 21 VCC (power), 26 VCCIO3 (power), 38 VCCIO2 (power), 52 VCC (power), 53 VCCAUX (power), 63 VCCIO2 (power), 82 VCCIO1 (power), 93 VCC (power), 98 VCCIO1 (power), 117 VCCIO0 (power), 128 VCCAUX (power), 129 VCC (power), 135 VCCIO0 (power)
part G pins: 11 GNDIO3 (power), 16 GND (power), 27 GNDIO3 (power), 37 GNDIO2 (power), 59 GND (power), 64 GNDIO2 (power), 83 GNDIO1 (power), 88 GND (power), 99 GNDIO1 (power), 118 GNDIO0 (power), 123 GND (power), 136 GNDIO0 (power)

## LCMXO640C-3T144I
designator U?
MachXO 640 Crossover PLD, 1.8V/2.5V/3.3V, 113 User I/Os, 144-Pins TQFP, Speed Grade-3, Industrial Grade
footprint TQFP144_N (Thin QFP, 144-Leads, Body 20x20mm, Pitch 0.5mm, IPC Medium Density)
footprint TQFP144_L (Thin QFP, 144-Leads, Body 20x20mm, Pitch 0.5mm, IPC High Density)
footprint TQFP144_M (Thin QFP, 144-Leads, Body 20x20mm, Pitch 0.5mm, IPC Low Density)
3D model MachXO640-TQFP144 (144-Pin Thin Quad Flat Pack (TQFP144))
signal-integrity model LCMXO640C_T144 (MachXO)
part A pins: 109 PT9F (io), 110 PT9D (io), 111 PT9E (io), 112 PT9B (io), 113 PT9C (io), 114 PT9A (io), 115 PT8C (io), 116 PT8B (io), 119 PT8A (io), 120 PT7E (io), 121 PT7C (io), 122 PT7A (io), 124 PT6B/PCLK0_1 (io), 125 PT6A (io), 126 PT5C (io), 127 PT5B/PCLK0_0 (io), 130 PT4D (io), 131 PT4B (io), 132 PT4A (io), 133 PT3F (io), 134 PT3D (io), 137 PT3B (io), 138 PT2F (io), 139 PT3A (io), 140 PT2D (io), 141 PT2E (io), 142 PT2B (io), 143 PT2C (io), 144 PT2A (io)
part B pins: 73 PR11D (io), 74 PR11B (io), 75 PR11C (io), 76 PR10D (io), 77 PR11A (io), 78 PR10B (io), 79 PR10C (io), 80 PR10A (io), 81 PR9D (io), 84 PR9A (io), 85 PR8C (io), 86 PR8A (io), 87 PR7D (io), 89 PR7B (io), 90 PR7A (io), 91 PR6D (io), 92 PR6C (io), 94 PR5D (io), 95 PR5B (io), 96 PR4D (io), 97 PR4B (io), 100 PR4A (io), 101 PR3D (io), 102 PR3C (io), 103 PR3B (io), 104 PR2D (io), 105 PR3A (io), 106 PR2B (io), 107 PR2C (io), 108 PR2A (io)
part C pins: 40 PB2C (io), 41 PB3A (io), 43 PB3B (io), 44 PB3C (io), 45 PB3D (io), 46 PB4A (io), 48 PB4B (io), 49 PB4C (io), 50 PB4D (io), 54 PB5A (io), 55 PB5B/PCLK2_1 (io), 56 PB5D (io), 57 PB6A (io), 58 PB6B/PCLK2_0 (io), 60 PB7C (io), 61 PB7E (io), 62 PB8A (io), 65 PB8C (io), 66 PB8D (io), 67 PB9A (io), 68 PB9C (io), 69 PB9B (io), 71 PB9D (io), 72 PB9F (io)
part D pins: 1 PL2A (io), 2 PL2C (io), 3 PL2B (io), 4 PL3A (io), 5 PL2D (io), 6 PL3B (io), 7 PL3C (io), 8 PL3D (io), 9 PL4A (io), 12 PL4D (io), 13 PL5A (io), 14 PL5B/GSRN (io), 15 PL5D (io), 17 PL6C (io), 18 PL6D (io), 19 PL7A (io), 20 PL7B (io), 22 PL8A (io), 23 PL8B (io), 24 PL8C/TSALL (io), 25 PL9C (io), 28 PL9D (io), 29 PL10A (io), 30 PL10B (io), 31 PL10C (io), 32 PL11A (io), 33 PL10D (io), 34 PL11C (io), 35 PL11B (io), 36 PL11D (io)
part E pins: 39 TMS (in) "Powered by VCCIO2", 42 TCK (in) "Powered by VCCIO2", 47 TDO (out) "Powered by VCCIO2", 51 TDI (in) "Powered by VCCIO2", 70 SLEEPN (in) "Powered by VCCIO2"
part F pins: 10 VCCIO3 (power), 21 VCC (power), 26 VCCIO3 (power), 38 VCCIO2 (power), 52 VCC (power), 53 VCCAUX (power), 63 VCCIO2 (power), 82 VCCIO1 (power), 93 VCC (power), 98 VCCIO1 (power), 117 VCCIO0 (power), 128 VCCAUX (power), 129 VCC (power), 135 VCCIO0 (power)
part G pins: 11 GNDIO3 (power), 16 GND (power), 27 GNDIO3 (power), 37 GNDIO2 (power), 59 GND (power), 64 GNDIO2 (power), 83 GNDIO1 (power), 88 GND (power), 99 GNDIO1 (power), 118 GNDIO0 (power), 123 GND (power), 136 GNDIO0 (power)


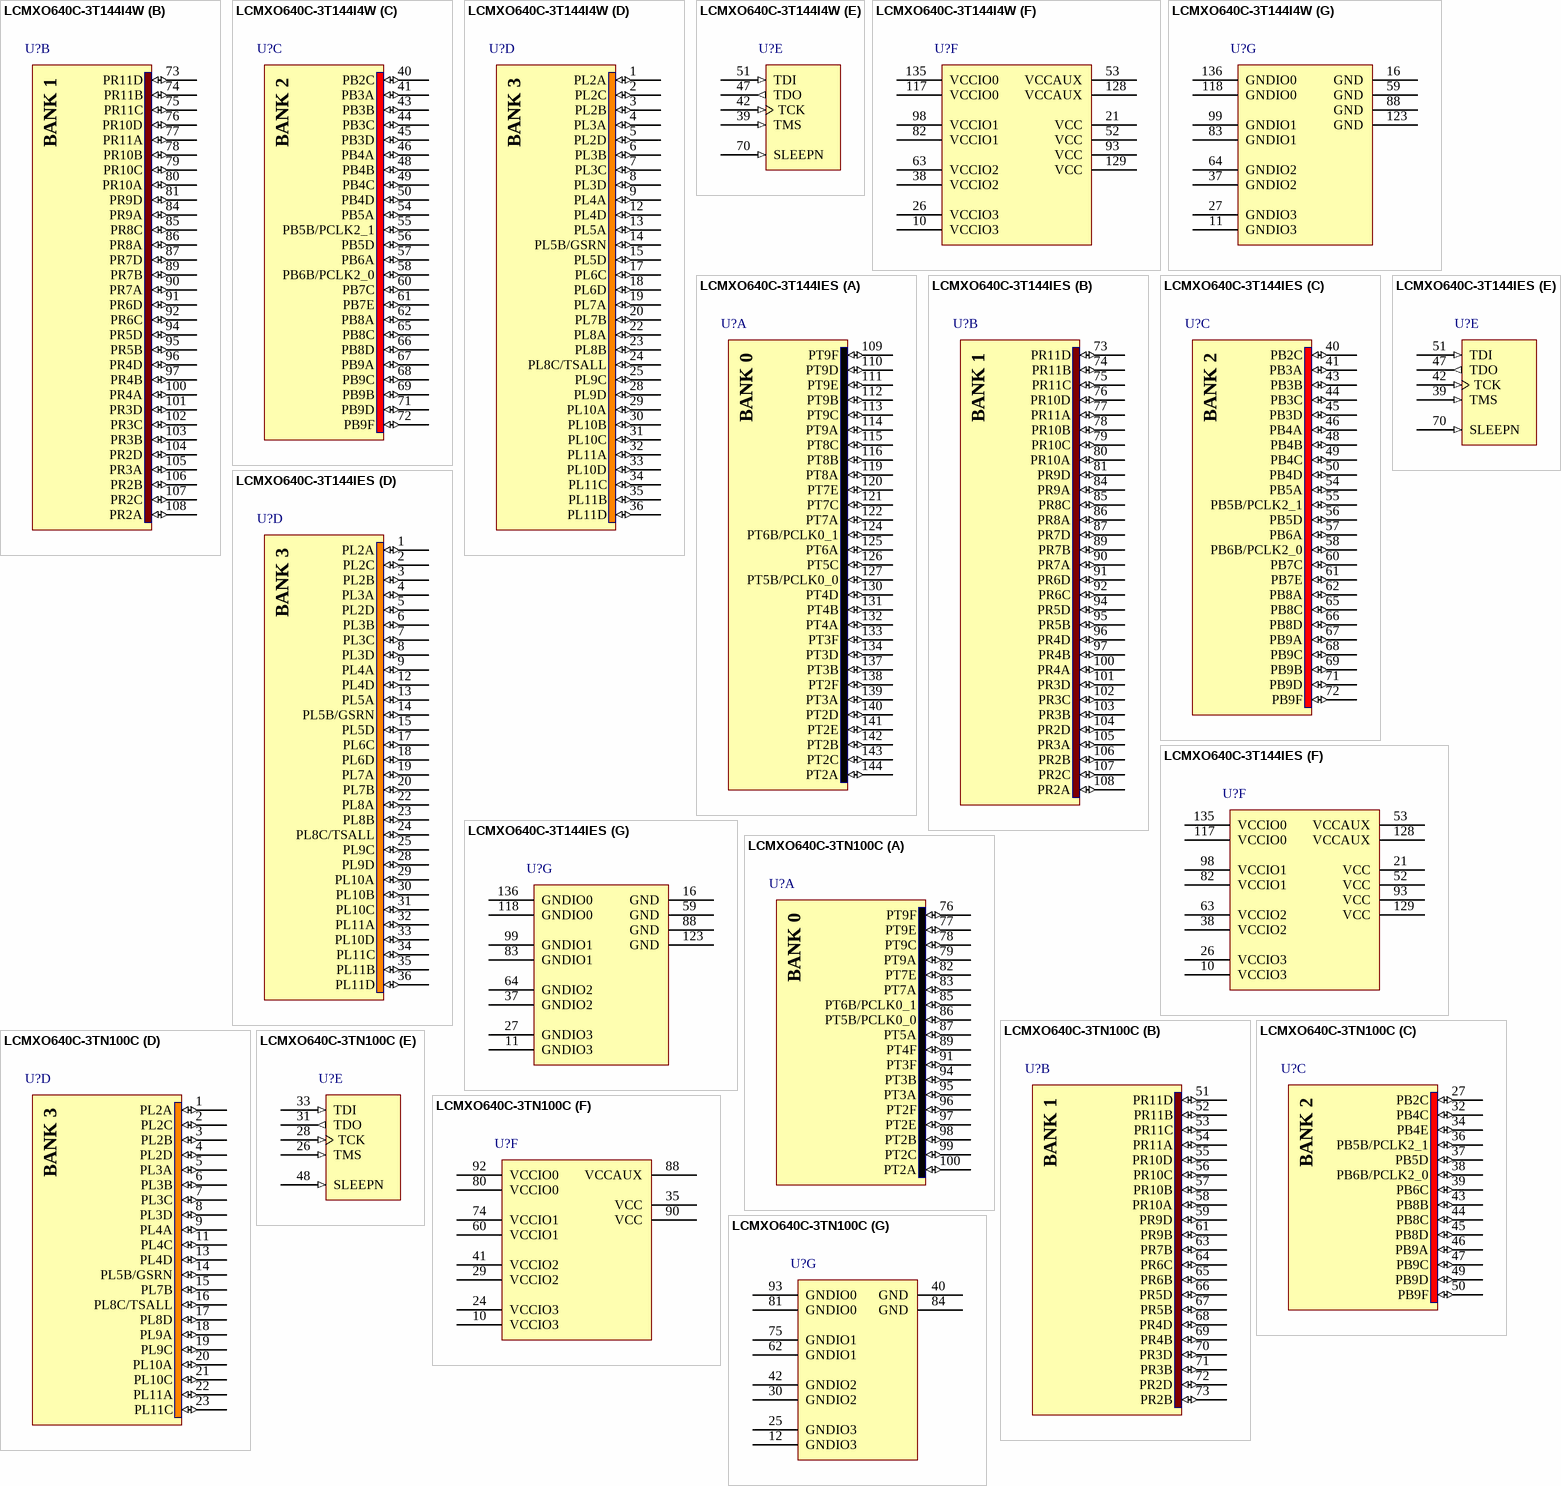
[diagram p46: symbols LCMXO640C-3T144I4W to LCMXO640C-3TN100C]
## LCMXO640C-3T144I4W
designator U?
MachXO 640 Crossover PLD, 1.8V/2.5V/3.3V, 113 User I/Os, 144-Pins TQFP, Speed Grade-3, Industrial Grade
footprint TQFP144_N (Thin QFP, 144-Leads, Body 20x20mm, Pitch 0.5mm, IPC Medium Density)
footprint TQFP144_L (Thin QFP, 144-Leads, Body 20x20mm, Pitch 0.5mm, IPC High Density)
footprint TQFP144_M (Thin QFP, 144-Leads, Body 20x20mm, Pitch 0.5mm, IPC Low Density)
3D model MachXO640-TQFP144 (144-Pin Thin Quad Flat Pack (TQFP144))
signal-integrity model LCMXO640C_T144 (MachXO)
part A pins: 109 PT9F (io), 110 PT9D (io), 111 PT9E (io), 112 PT9B (io), 113 PT9C (io), 114 PT9A (io), 115 PT8C (io), 116 PT8B (io), 119 PT8A (io), 120 PT7E (io), 121 PT7C (io), 122 PT7A (io), 124 PT6B/PCLK0_1 (io), 125 PT6A (io), 126 PT5C (io), 127 PT5B/PCLK0_0 (io), 130 PT4D (io), 131 PT4B (io), 132 PT4A (io), 133 PT3F (io), 134 PT3D (io), 137 PT3B (io), 138 PT2F (io), 139 PT3A (io), 140 PT2D (io), 141 PT2E (io), 142 PT2B (io), 143 PT2C (io), 144 PT2A (io)
part B pins: 73 PR11D (io), 74 PR11B (io), 75 PR11C (io), 76 PR10D (io), 77 PR11A (io), 78 PR10B (io), 79 PR10C (io), 80 PR10A (io), 81 PR9D (io), 84 PR9A (io), 85 PR8C (io), 86 PR8A (io), 87 PR7D (io), 89 PR7B (io), 90 PR7A (io), 91 PR6D (io), 92 PR6C (io), 94 PR5D (io), 95 PR5B (io), 96 PR4D (io), 97 PR4B (io), 100 PR4A (io), 101 PR3D (io), 102 PR3C (io), 103 PR3B (io), 104 PR2D (io), 105 PR3A (io), 106 PR2B (io), 107 PR2C (io), 108 PR2A (io)
part C pins: 40 PB2C (io), 41 PB3A (io), 43 PB3B (io), 44 PB3C (io), 45 PB3D (io), 46 PB4A (io), 48 PB4B (io), 49 PB4C (io), 50 PB4D (io), 54 PB5A (io), 55 PB5B/PCLK2_1 (io), 56 PB5D (io), 57 PB6A (io), 58 PB6B/PCLK2_0 (io), 60 PB7C (io), 61 PB7E (io), 62 PB8A (io), 65 PB8C (io), 66 PB8D (io), 67 PB9A (io), 68 PB9C (io), 69 PB9B (io), 71 PB9D (io), 72 PB9F (io)
part D pins: 1 PL2A (io), 2 PL2C (io), 3 PL2B (io), 4 PL3A (io), 5 PL2D (io), 6 PL3B (io), 7 PL3C (io), 8 PL3D (io), 9 PL4A (io), 12 PL4D (io), 13 PL5A (io), 14 PL5B/GSRN (io), 15 PL5D (io), 17 PL6C (io), 18 PL6D (io), 19 PL7A (io), 20 PL7B (io), 22 PL8A (io), 23 PL8B (io), 24 PL8C/TSALL (io), 25 PL9C (io), 28 PL9D (io), 29 PL10A (io), 30 PL10B (io), 31 PL10C (io), 32 PL11A (io), 33 PL10D (io), 34 PL11C (io), 35 PL11B (io), 36 PL11D (io)
part E pins: 39 TMS (in) "Powered by VCCIO2", 42 TCK (in) "Powered by VCCIO2", 47 TDO (out) "Powered by VCCIO2", 51 TDI (in) "Powered by VCCIO2", 70 SLEEPN (in) "Powered by VCCIO2"
part F pins: 10 VCCIO3 (power), 21 VCC (power), 26 VCCIO3 (power), 38 VCCIO2 (power), 52 VCC (power), 53 VCCAUX (power), 63 VCCIO2 (power), 82 VCCIO1 (power), 93 VCC (power), 98 VCCIO1 (power), 117 VCCIO0 (power), 128 VCCAUX (power), 129 VCC (power), 135 VCCIO0 (power)
part G pins: 11 GNDIO3 (power), 16 GND (power), 27 GNDIO3 (power), 37 GNDIO2 (power), 59 GND (power), 64 GNDIO2 (power), 83 GNDIO1 (power), 88 GND (power), 99 GNDIO1 (power), 118 GNDIO0 (power), 123 GND (power), 136 GNDIO0 (power)

## LCMXO640C-3T144IES
designator U?
MachXO 640 Crossover PLD, 1.8V/2.5V/3.3V, 113 User I/Os, 144-Pins TQFP, Speed Grade-3, Industrial Grade, Engineering Sample
footprint TQFP144_N (Thin QFP, 144-Leads, Body 20x20mm, Pitch 0.5mm, IPC Medium Density)
footprint TQFP144_L (Thin QFP, 144-Leads, Body 20x20mm, Pitch 0.5mm, IPC High Density)
footprint TQFP144_M (Thin QFP, 144-Leads, Body 20x20mm, Pitch 0.5mm, IPC Low Density)
3D model MachXO640-TQFP144 (144-Pin Thin Quad Flat Pack (TQFP144))
signal-integrity model LCMXO640C_T144 (MachXO)
part A pins: 109 PT9F (io), 110 PT9D (io), 111 PT9E (io), 112 PT9B (io), 113 PT9C (io), 114 PT9A (io), 115 PT8C (io), 116 PT8B (io), 119 PT8A (io), 120 PT7E (io), 121 PT7C (io), 122 PT7A (io), 124 PT6B/PCLK0_1 (io), 125 PT6A (io), 126 PT5C (io), 127 PT5B/PCLK0_0 (io), 130 PT4D (io), 131 PT4B (io), 132 PT4A (io), 133 PT3F (io), 134 PT3D (io), 137 PT3B (io), 138 PT2F (io), 139 PT3A (io), 140 PT2D (io), 141 PT2E (io), 142 PT2B (io), 143 PT2C (io), 144 PT2A (io)
part B pins: 73 PR11D (io), 74 PR11B (io), 75 PR11C (io), 76 PR10D (io), 77 PR11A (io), 78 PR10B (io), 79 PR10C (io), 80 PR10A (io), 81 PR9D (io), 84 PR9A (io), 85 PR8C (io), 86 PR8A (io), 87 PR7D (io), 89 PR7B (io), 90 PR7A (io), 91 PR6D (io), 92 PR6C (io), 94 PR5D (io), 95 PR5B (io), 96 PR4D (io), 97 PR4B (io), 100 PR4A (io), 101 PR3D (io), 102 PR3C (io), 103 PR3B (io), 104 PR2D (io), 105 PR3A (io), 106 PR2B (io), 107 PR2C (io), 108 PR2A (io)
part C pins: 40 PB2C (io), 41 PB3A (io), 43 PB3B (io), 44 PB3C (io), 45 PB3D (io), 46 PB4A (io), 48 PB4B (io), 49 PB4C (io), 50 PB4D (io), 54 PB5A (io), 55 PB5B/PCLK2_1 (io), 56 PB5D (io), 57 PB6A (io), 58 PB6B/PCLK2_0 (io), 60 PB7C (io), 61 PB7E (io), 62 PB8A (io), 65 PB8C (io), 66 PB8D (io), 67 PB9A (io), 68 PB9C (io), 69 PB9B (io), 71 PB9D (io), 72 PB9F (io)
part D pins: 1 PL2A (io), 2 PL2C (io), 3 PL2B (io), 4 PL3A (io), 5 PL2D (io), 6 PL3B (io), 7 PL3C (io), 8 PL3D (io), 9 PL4A (io), 12 PL4D (io), 13 PL5A (io), 14 PL5B/GSRN (io), 15 PL5D (io), 17 PL6C (io), 18 PL6D (io), 19 PL7A (io), 20 PL7B (io), 22 PL8A (io), 23 PL8B (io), 24 PL8C/TSALL (io), 25 PL9C (io), 28 PL9D (io), 29 PL10A (io), 30 PL10B (io), 31 PL10C (io), 32 PL11A (io), 33 PL10D (io), 34 PL11C (io), 35 PL11B (io), 36 PL11D (io)
part E pins: 39 TMS (in) "Powered by VCCIO2", 42 TCK (in) "Powered by VCCIO2", 47 TDO (out) "Powered by VCCIO2", 51 TDI (in) "Powered by VCCIO2", 70 SLEEPN (in) "Powered by VCCIO2"
part F pins: 10 VCCIO3 (power), 21 VCC (power), 26 VCCIO3 (power), 38 VCCIO2 (power), 52 VCC (power), 53 VCCAUX (power), 63 VCCIO2 (power), 82 VCCIO1 (power), 93 VCC (power), 98 VCCIO1 (power), 117 VCCIO0 (power), 128 VCCAUX (power), 129 VCC (power), 135 VCCIO0 (power)
part G pins: 11 GNDIO3 (power), 16 GND (power), 27 GNDIO3 (power), 37 GNDIO2 (power), 59 GND (power), 64 GNDIO2 (power), 83 GNDIO1 (power), 88 GND (power), 99 GNDIO1 (power), 118 GNDIO0 (power), 123 GND (power), 136 GNDIO0 (power)

## LCMXO640C-3TN100C
designator U?
MachXO 640 Crossover PLD, 1.8V/2.5V/3.3V, 74 User I/Os, 100-Pins TQFP, Speed Grade-3, Commercial Grade, Pb-Free
footprint TQFP100_N (Thin QFP, 100-Leads, Body 14x14mm, Pitch 0.5mm, IPC Medium Density)
footprint TQFP100_L (Thin QFP, 100-Leads, Body 14x14mm, Pitch 0.5mm, IPC High Density)
footprint TQFP100_M (Thin QFP, 100-Leads, Body 14x14mm, Pitch 0.5mm, IPC Low Density)
3D model MachXO640-TQFP100 (100-Pin Thin Quad Flat Pack (TQFP100))
signal-integrity model LCMXO640C_T100 (MachXO)
part A pins: 76 PT9F (io), 77 PT9E (io), 78 PT9C (io), 79 PT9A (io), 82 PT7E (io), 83 PT7A (io), 85 PT6B/PCLK0_1 (io), 86 PT5B/PCLK0_0 (io), 87 PT5A (io), 89 PT4F (io), 91 PT3F (io), 94 PT3B (io), 95 PT3A (io), 96 PT2F (io), 97 PT2E (io), 98 PT2B (io), 99 PT2C (io), 100 PT2A (io)
part B pins: 51 PR11D (io), 52 PR11B (io), 53 PR11C (io), 54 PR11A (io), 55 PR10D (io), 56 PR10C (io), 57 PR10B (io), 58 PR10A (io), 59 PR9D (io), 61 PR9B (io), 63 PR7B (io), 64 PR6C (io), 65 PR6B (io), 66 PR5D (io), 67 PR5B (io), 68 PR4D (io), 69 PR4B (io), 70 PR3D (io), 71 PR3B (io), 72 PR2D (io), 73 PR2B (io)
part C pins: 27 PB2C (io), 32 PB4C (io), 34 PB4E (io), 36 PB5B/PCLK2_1 (io), 37 PB5D (io), 38 PB6B/PCLK2_0 (io), 39 PB6C (io), 43 PB8B (io), 44 PB8C (io), 45 PB8D (io), 46 PB9A (io), 47 PB9C (io), 49 PB9D (io), 50 PB9F (io)
part D pins: 1 PL2A (io), 2 PL2C (io), 3 PL2B (io), 4 PL2D (io), 5 PL3A (io), 6 PL3B (io), 7 PL3C (io), 8 PL3D (io), 9 PL4A (io), 11 PL4C (io), 13 PL4D (io), 14 PL5B/GSRN (io), 15 PL7B (io), 16 PL8C/TSALL (io), 17 PL8D (io), 18 PL9A (io), 19 PL9C (io), 20 PL10A (io), 21 PL10C (io), 22 PL11A (io), 23 PL11C (io)
part E pins: 26 TMS (in) "Powered by VCCIO2", 28 TCK (in) "Powered by VCCIO2", 31 TDO (out) "Powered by VCCIO2", 33 TDI (in) "Powered by VCCIO2", 48 SLEEPN (in) "Powered by VCCIO2"
part F pins: 10 VCCIO3 (power), 24 VCCIO3 (power), 29 VCCIO2 (power), 35 VCC (power), 41 VCCIO2 (power), 60 VCCIO1 (power), 74 VCCIO1 (power), 80 VCCIO0 (power), 88 VCCAUX (power), 90 VCC (power), 92 VCCIO0 (power)
part G pins: 12 GNDIO3 (power), 25 GNDIO3 (power), 30 GNDIO2 (power), 40 GND (power), 42 GNDIO2 (power), 62 GNDIO1 (power), 75 GNDIO1 (power), 81 GNDIO0 (power), 84 GND (power), 93 GNDIO0 (power)


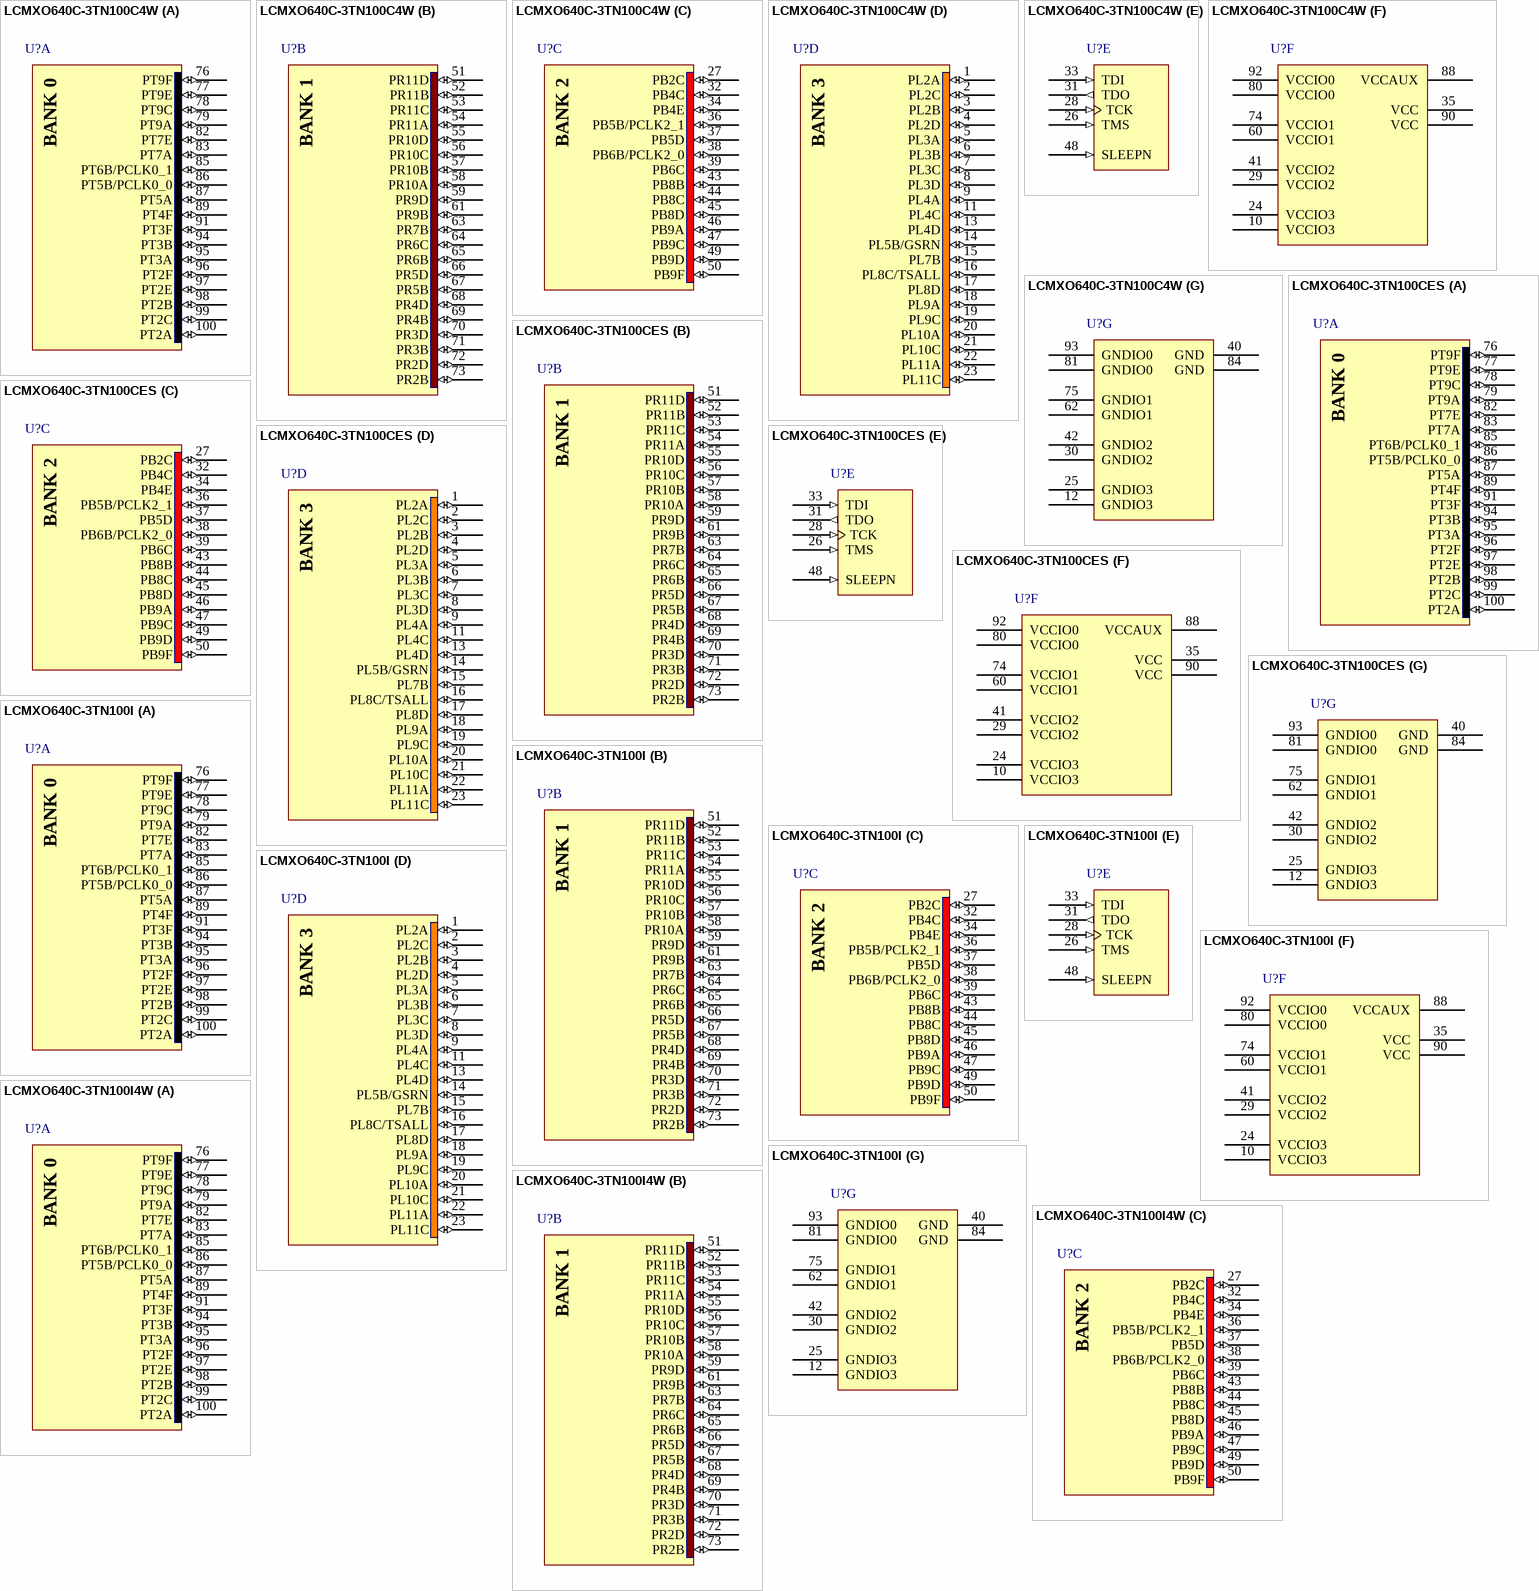
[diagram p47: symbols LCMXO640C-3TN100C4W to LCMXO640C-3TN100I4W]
## LCMXO640C-3TN100C4W
designator U?
MachXO 640 Crossover PLD, 1.8V/2.5V/3.3V, 74 User I/Os, 100-Pins TQFP, Speed Grade-3, Commercial Grade, Pb-Free
footprint TQFP100_N (Thin QFP, 100-Leads, Body 14x14mm, Pitch 0.5mm, IPC Medium Density)
footprint TQFP100_L (Thin QFP, 100-Leads, Body 14x14mm, Pitch 0.5mm, IPC High Density)
footprint TQFP100_M (Thin QFP, 100-Leads, Body 14x14mm, Pitch 0.5mm, IPC Low Density)
3D model MachXO640-TQFP100 (100-Pin Thin Quad Flat Pack (TQFP100))
signal-integrity model LCMXO640C_T100 (MachXO)
part A pins: 76 PT9F (io), 77 PT9E (io), 78 PT9C (io), 79 PT9A (io), 82 PT7E (io), 83 PT7A (io), 85 PT6B/PCLK0_1 (io), 86 PT5B/PCLK0_0 (io), 87 PT5A (io), 89 PT4F (io), 91 PT3F (io), 94 PT3B (io), 95 PT3A (io), 96 PT2F (io), 97 PT2E (io), 98 PT2B (io), 99 PT2C (io), 100 PT2A (io)
part B pins: 51 PR11D (io), 52 PR11B (io), 53 PR11C (io), 54 PR11A (io), 55 PR10D (io), 56 PR10C (io), 57 PR10B (io), 58 PR10A (io), 59 PR9D (io), 61 PR9B (io), 63 PR7B (io), 64 PR6C (io), 65 PR6B (io), 66 PR5D (io), 67 PR5B (io), 68 PR4D (io), 69 PR4B (io), 70 PR3D (io), 71 PR3B (io), 72 PR2D (io), 73 PR2B (io)
part C pins: 27 PB2C (io), 32 PB4C (io), 34 PB4E (io), 36 PB5B/PCLK2_1 (io), 37 PB5D (io), 38 PB6B/PCLK2_0 (io), 39 PB6C (io), 43 PB8B (io), 44 PB8C (io), 45 PB8D (io), 46 PB9A (io), 47 PB9C (io), 49 PB9D (io), 50 PB9F (io)
part D pins: 1 PL2A (io), 2 PL2C (io), 3 PL2B (io), 4 PL2D (io), 5 PL3A (io), 6 PL3B (io), 7 PL3C (io), 8 PL3D (io), 9 PL4A (io), 11 PL4C (io), 13 PL4D (io), 14 PL5B/GSRN (io), 15 PL7B (io), 16 PL8C/TSALL (io), 17 PL8D (io), 18 PL9A (io), 19 PL9C (io), 20 PL10A (io), 21 PL10C (io), 22 PL11A (io), 23 PL11C (io)
part E pins: 26 TMS (in) "Powered by VCCIO2", 28 TCK (in) "Powered by VCCIO2", 31 TDO (out) "Powered by VCCIO2", 33 TDI (in) "Powered by VCCIO2", 48 SLEEPN (in) "Powered by VCCIO2"
part F pins: 10 VCCIO3 (power), 24 VCCIO3 (power), 29 VCCIO2 (power), 35 VCC (power), 41 VCCIO2 (power), 60 VCCIO1 (power), 74 VCCIO1 (power), 80 VCCIO0 (power), 88 VCCAUX (power), 90 VCC (power), 92 VCCIO0 (power)
part G pins: 12 GNDIO3 (power), 25 GNDIO3 (power), 30 GNDIO2 (power), 40 GND (power), 42 GNDIO2 (power), 62 GNDIO1 (power), 75 GNDIO1 (power), 81 GNDIO0 (power), 84 GND (power), 93 GNDIO0 (power)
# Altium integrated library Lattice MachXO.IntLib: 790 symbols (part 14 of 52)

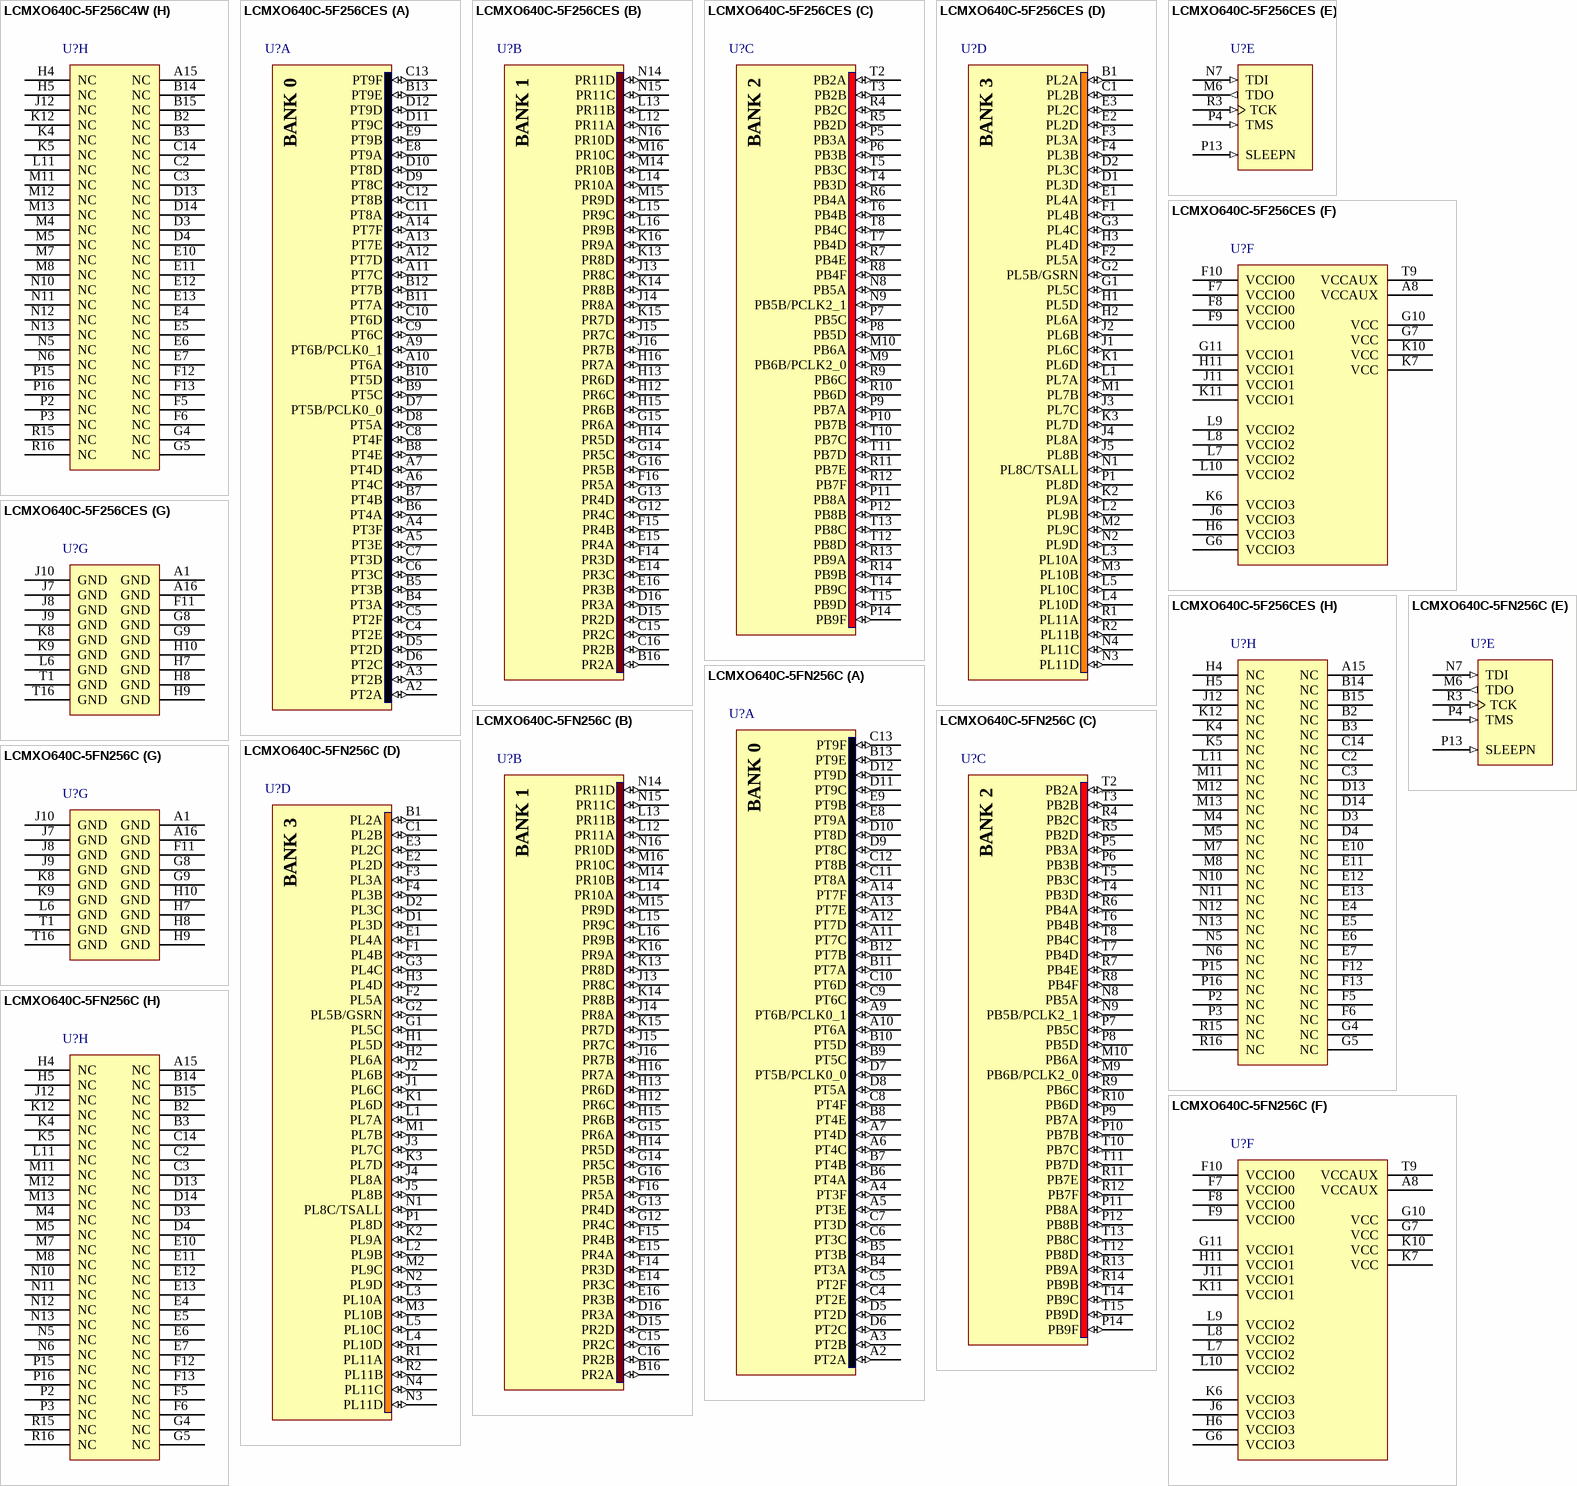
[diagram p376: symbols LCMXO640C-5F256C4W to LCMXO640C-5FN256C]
## LCMXO640C-5FN256C
designator U?
MachXO 640 Crossover PLD, 1.8V/2.5V/3.3V, 159 User I/Os, 256-Pins fpBGA, Speed Grade-5, Commercial Grade, Pb-Free; ComponentAvailability: Not recommended for new designs. Use ftBGA package device.
footprint fpBGA256 (BGA, 256-Leads, Body 17x17mm, Pitch 1mm)
3D model MachXO640-fpBGA256 (256-Ball Fine Pitch Ball Grid Array (fpBGA256))
signal-integrity model LCMXO640C_F256 (MachXO)
part A pins: A2 PT2A (io), A3 PT2B (io), A4 PT3F (io), A5 PT3E (io), A6 PT4C (io), A7 PT4D (io), A9 PT6B/PCLK0_1 (io), A10 PT6A (io), A11 PT7C (io), A12 PT7D (io), A13 PT7E (io), A14 PT7F (io), B4 PT3A (io), B5 PT3B (io), B6 PT4A (io), B7 PT4B (io), B8 PT4E (io), B9 PT5C (io), B10 PT5D (io), B11 PT7A (io), B12 PT7B (io), B13 PT9E (io), C4 PT2E (io), C5 PT2F (io), C6 PT3C (io), C7 PT3D (io), C8 PT4F (io), C9 PT6C (io), C10 PT6D (io), C11 PT8A (io), C12 PT8B (io), C13 PT9F (io), D5 PT2D (io), D6 PT2C (io), D7 PT5B/PCLK0_0 (io), D8 PT5A (io), D9 PT8C (io), D10 PT8D (io), D11 PT9C (io), D12 PT9D (io), E8 PT9A (io), E9 PT9B (io)
part B pins: B16 PR2A (io), C15 PR2C (io), C16 PR2B (io), D15 PR2D (io), D16 PR3A (io), E14 PR3C (io), E15 PR4A (io), E16 PR3B (io), F14 PR3D (io), F15 PR4B (io), F16 PR5A (io), G12 PR4C (io), G13 PR4D (io), G14 PR5C (io), G15 PR6A (io), G16 PR5B (io), H12 PR6C (io), H13 PR6D (io), H14 PR5D (io), H15 PR6B (io), H16 PR7A (io), J13 PR8C (io), J14 PR8A (io), J15 PR7C (io), J16 PR7B (io), K13 PR8D (io), K14 PR8B (io), K15 PR7D (io), K16 PR9A (io), L12 PR11A (io), L13 PR11B (io), L14 PR10A (io), L15 PR9C (io), L16 PR9B (io), M14 PR10B (io), M15 PR9D (io), M16 PR10C (io), N14 PR11D (io), N15 PR11C (io), N16 PR10D (io)
part C pins: M9 PB6B/PCLK2_0 (io), M10 PB6A (io), N8 PB5A (io), N9 PB5B/PCLK2_1 (io), P5 PB3A (io), P6 PB3B (io), P7 PB5C (io), P8 PB5D (io), P9 PB7A (io), P10 PB7B (io), P11 PB8A (io), P12 PB8B (io), P14 PB9F (io), R4 PB2C (io), R5 PB2D (io), R6 PB4A (io), R7 PB4E (io), R8 PB4F (io), R9 PB6C (io), R10 PB6D (io), R11 PB7E (io), R12 PB7F (io), R13 PB9A (io), R14 PB9B (io), T2 PB2A (io), T3 PB2B (io), T4 PB3D (io), T5 PB3C (io), T6 PB4B (io), T7 PB4D (io), T8 PB4C (io), T10 PB7C (io), T11 PB7D (io), T12 PB8D (io), T13 PB8C (io), T14 PB9C (io), T15 PB9D (io)
part D pins: B1 PL2A (io), C1 PL2B (io), D1 PL3D (io), D2 PL3C (io), E1 PL4A (io), E2 PL2D (io), E3 PL2C (io), F1 PL4B (io), F2 PL5A (io), F3 PL3A (io), F4 PL3B (io), G1 PL5C (io), G2 PL5B/GSRN (io), G3 PL4C (io), H1 PL5D (io), H2 PL6A (io), H3 PL4D (io), J1 PL6C (io), J2 PL6B (io), J3 PL7C (io), J4 PL8A (io), J5 PL8B (io), K1 PL6D (io), K2 PL9A (io), K3 PL7D (io), L1 PL7A (io), L2 PL9B (io), L3 PL10A (io), L4 PL10D (io), L5 PL10C (io), M1 PL7B (io), M2 PL9C (io), M3 PL10B (io), N1 PL8C/TSALL (io), N2 PL9D (io), N3 PL11D (io), N4 PL11C (io), P1 PL8D (io), R1 PL11A (io), R2 PL11B (io)
part E pins: M6 TDO (out) "Powered by VCCIO2", N7 TDI (in) "Powered by VCCIO2", P4 TMS (in) "Powered by VCCIO2", P13 SLEEPN (in) "Powered by VCCIO2", R3 TCK (in) "Powered by VCCIO2"
part F pins: A8 VCCAUX (power), F7 VCCIO0 (power), F8 VCCIO0 (power), F9 VCCIO0 (power), F10 VCCIO0 (power), G6 VCCIO3 (power), G7 VCC (power), G10 VCC (power), G11 VCCIO1 (power), H6 VCCIO3 (power), H11 VCCIO1 (power), J6 VCCIO3 (power), J11 VCCIO1 (power), K6 VCCIO3 (power), K7 VCC (power), K10 VCC (power), K11 VCCIO1 (power), L7 VCCIO2 (power), L8 VCCIO2 (power), L9 VCCIO2 (power), L10 VCCIO2 (power), T9 VCCAUX (power)
part G pins: A1 GND (power), A16 GND (power), F11 GND (power), G8 GND (power), G9 GND (power), H7 GND (power), H8 GND (power), H9 GND (power), H10 GND (power), J7 GND (power), J8 GND (power), J9 GND (power), J10 GND (power), K8 GND (power), K9 GND (power), L6 GND (power), T1 GND (power), T16 GND (power)
part H pins: A15 NC, B2 NC, B3 NC, B14 NC, B15 NC, C2 NC, C3 NC, C14 NC, D3 NC, D4 NC, D13 NC, D14 NC, E4 NC, E5 NC, E6 NC, E7 NC, E10 NC, E11 NC, E12 NC, E13 NC, F5 NC, F6 NC, F12 NC, F13 NC, G4 NC, G5 NC, H4 NC, H5 NC, J12 NC, K4 NC, K5 NC, K12 NC, L11 NC, M4 NC, M5 NC, M7 NC, M8 NC, M11 NC, M12 NC, M13 NC, N5 NC, N6 NC, N10 NC, N11 NC, N12 NC, N13 NC, P2 NC, P3 NC, P15 NC, P16 NC, R15 NC, R16 NC


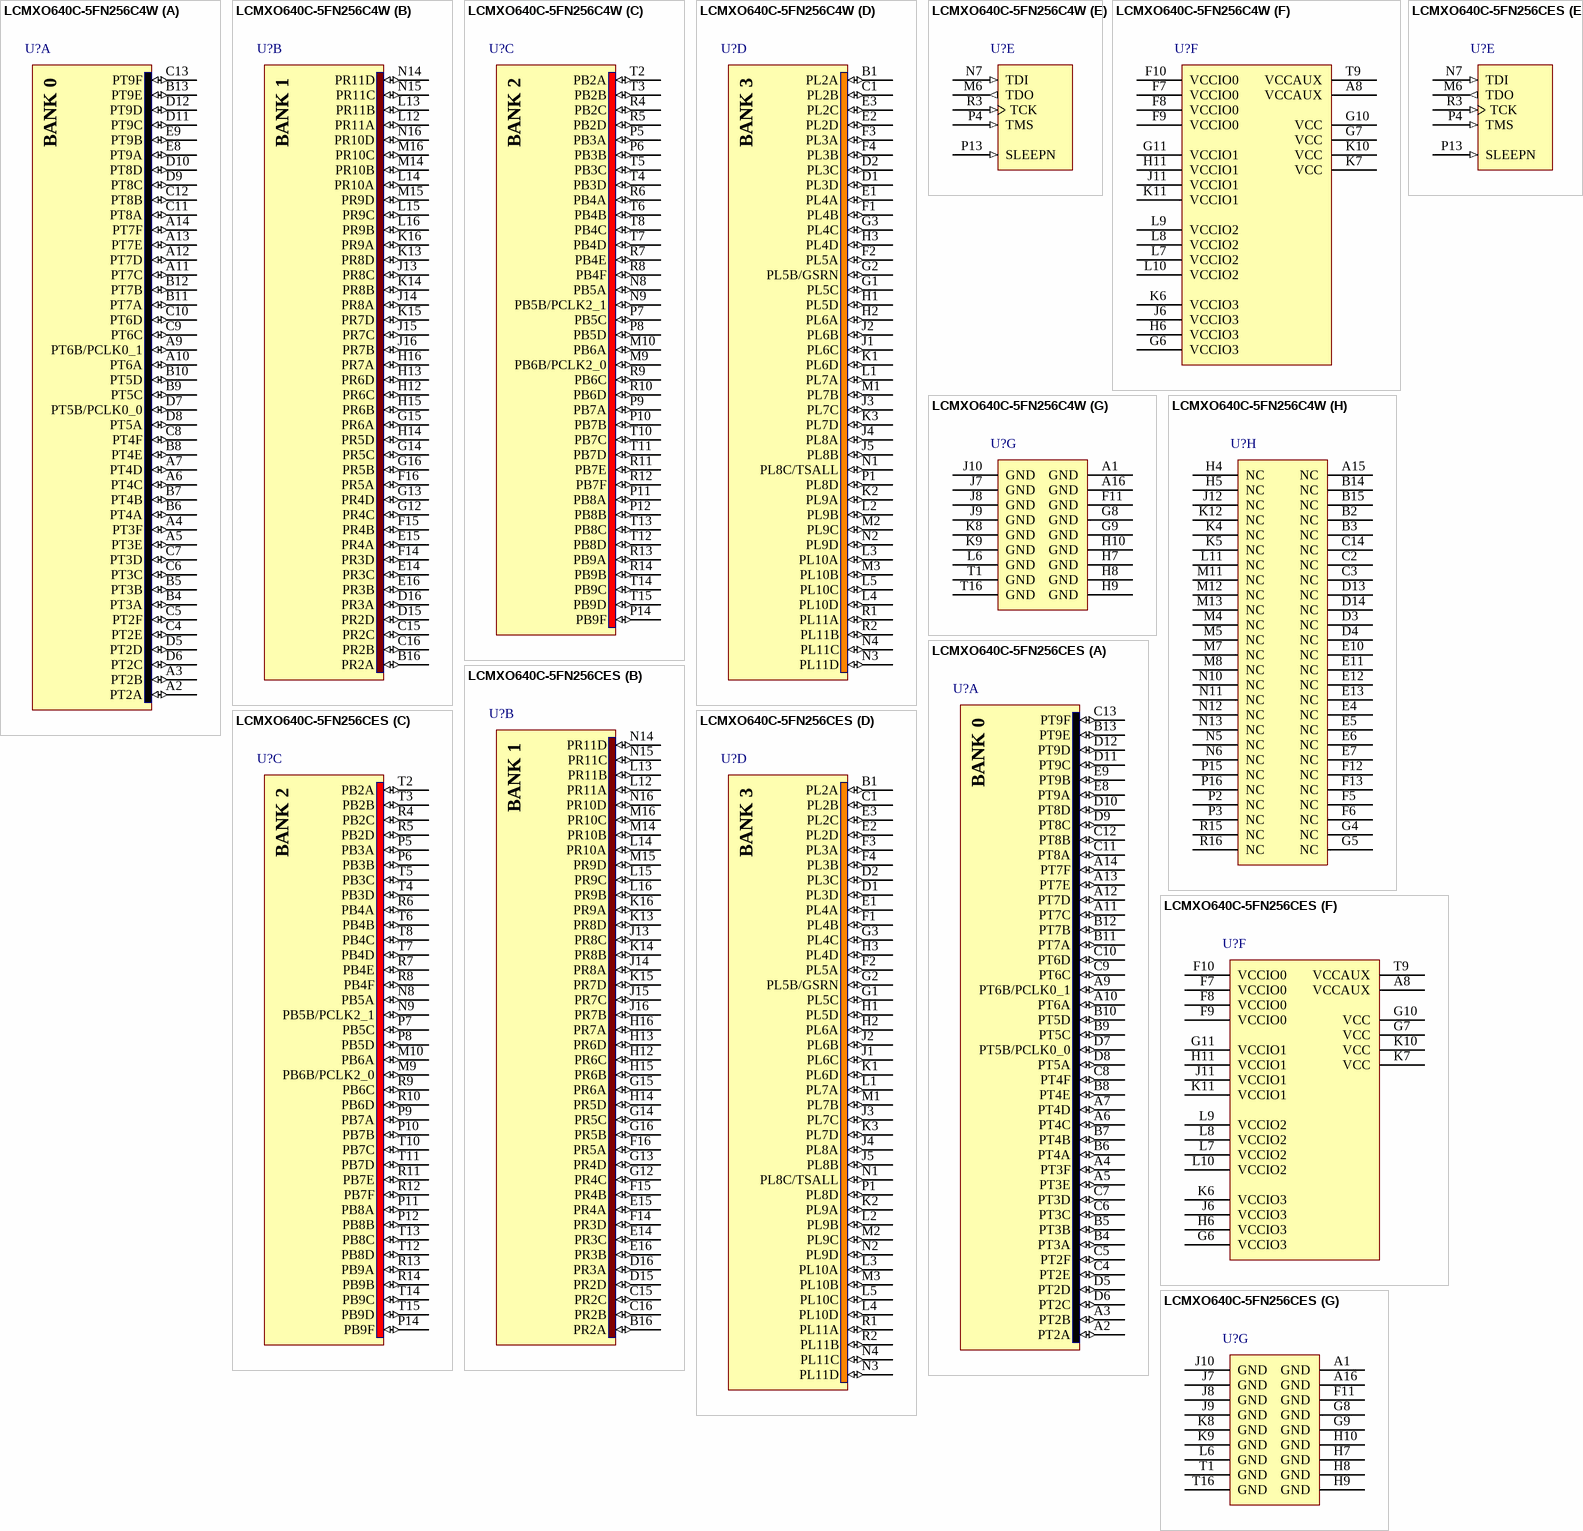
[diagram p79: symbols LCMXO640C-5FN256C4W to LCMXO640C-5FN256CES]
## LCMXO640C-5FN256C4W
designator U?
MachXO 640 Crossover PLD, 1.8V/2.5V/3.3V, 159 User I/Os, 256-Pins fpBGA, Speed Grade-5, Commercial Grade, Pb-Free; ComponentAvailability: Not recommended for new designs. Use ftBGA package device.
footprint fpBGA256 (BGA, 256-Leads, Body 17x17mm, Pitch 1mm)
3D model MachXO640-fpBGA256 (256-Ball Fine Pitch Ball Grid Array (fpBGA256))
signal-integrity model LCMXO640C_F256 (MachXO)
part A pins: A2 PT2A (io), A3 PT2B (io), A4 PT3F (io), A5 PT3E (io), A6 PT4C (io), A7 PT4D (io), A9 PT6B/PCLK0_1 (io), A10 PT6A (io), A11 PT7C (io), A12 PT7D (io), A13 PT7E (io), A14 PT7F (io), B4 PT3A (io), B5 PT3B (io), B6 PT4A (io), B7 PT4B (io), B8 PT4E (io), B9 PT5C (io), B10 PT5D (io), B11 PT7A (io), B12 PT7B (io), B13 PT9E (io), C4 PT2E (io), C5 PT2F (io), C6 PT3C (io), C7 PT3D (io), C8 PT4F (io), C9 PT6C (io), C10 PT6D (io), C11 PT8A (io), C12 PT8B (io), C13 PT9F (io), D5 PT2D (io), D6 PT2C (io), D7 PT5B/PCLK0_0 (io), D8 PT5A (io), D9 PT8C (io), D10 PT8D (io), D11 PT9C (io), D12 PT9D (io), E8 PT9A (io), E9 PT9B (io)
part B pins: B16 PR2A (io), C15 PR2C (io), C16 PR2B (io), D15 PR2D (io), D16 PR3A (io), E14 PR3C (io), E15 PR4A (io), E16 PR3B (io), F14 PR3D (io), F15 PR4B (io), F16 PR5A (io), G12 PR4C (io), G13 PR4D (io), G14 PR5C (io), G15 PR6A (io), G16 PR5B (io), H12 PR6C (io), H13 PR6D (io), H14 PR5D (io), H15 PR6B (io), H16 PR7A (io), J13 PR8C (io), J14 PR8A (io), J15 PR7C (io), J16 PR7B (io), K13 PR8D (io), K14 PR8B (io), K15 PR7D (io), K16 PR9A (io), L12 PR11A (io), L13 PR11B (io), L14 PR10A (io), L15 PR9C (io), L16 PR9B (io), M14 PR10B (io), M15 PR9D (io), M16 PR10C (io), N14 PR11D (io), N15 PR11C (io), N16 PR10D (io)
part C pins: M9 PB6B/PCLK2_0 (io), M10 PB6A (io), N8 PB5A (io), N9 PB5B/PCLK2_1 (io), P5 PB3A (io), P6 PB3B (io), P7 PB5C (io), P8 PB5D (io), P9 PB7A (io), P10 PB7B (io), P11 PB8A (io), P12 PB8B (io), P14 PB9F (io), R4 PB2C (io), R5 PB2D (io), R6 PB4A (io), R7 PB4E (io), R8 PB4F (io), R9 PB6C (io), R10 PB6D (io), R11 PB7E (io), R12 PB7F (io), R13 PB9A (io), R14 PB9B (io), T2 PB2A (io), T3 PB2B (io), T4 PB3D (io), T5 PB3C (io), T6 PB4B (io), T7 PB4D (io), T8 PB4C (io), T10 PB7C (io), T11 PB7D (io), T12 PB8D (io), T13 PB8C (io), T14 PB9C (io), T15 PB9D (io)
part D pins: B1 PL2A (io), C1 PL2B (io), D1 PL3D (io), D2 PL3C (io), E1 PL4A (io), E2 PL2D (io), E3 PL2C (io), F1 PL4B (io), F2 PL5A (io), F3 PL3A (io), F4 PL3B (io), G1 PL5C (io), G2 PL5B/GSRN (io), G3 PL4C (io), H1 PL5D (io), H2 PL6A (io), H3 PL4D (io), J1 PL6C (io), J2 PL6B (io), J3 PL7C (io), J4 PL8A (io), J5 PL8B (io), K1 PL6D (io), K2 PL9A (io), K3 PL7D (io), L1 PL7A (io), L2 PL9B (io), L3 PL10A (io), L4 PL10D (io), L5 PL10C (io), M1 PL7B (io), M2 PL9C (io), M3 PL10B (io), N1 PL8C/TSALL (io), N2 PL9D (io), N3 PL11D (io), N4 PL11C (io), P1 PL8D (io), R1 PL11A (io), R2 PL11B (io)
part E pins: M6 TDO (out) "Powered by VCCIO2", N7 TDI (in) "Powered by VCCIO2", P4 TMS (in) "Powered by VCCIO2", P13 SLEEPN (in) "Powered by VCCIO2", R3 TCK (in) "Powered by VCCIO2"
part F pins: A8 VCCAUX (power), F7 VCCIO0 (power), F8 VCCIO0 (power), F9 VCCIO0 (power), F10 VCCIO0 (power), G6 VCCIO3 (power), G7 VCC (power), G10 VCC (power), G11 VCCIO1 (power), H6 VCCIO3 (power), H11 VCCIO1 (power), J6 VCCIO3 (power), J11 VCCIO1 (power), K6 VCCIO3 (power), K7 VCC (power), K10 VCC (power), K11 VCCIO1 (power), L7 VCCIO2 (power), L8 VCCIO2 (power), L9 VCCIO2 (power), L10 VCCIO2 (power), T9 VCCAUX (power)
part G pins: A1 GND (power), A16 GND (power), F11 GND (power), G8 GND (power), G9 GND (power), H7 GND (power), H8 GND (power), H9 GND (power), H10 GND (power), J7 GND (power), J8 GND (power), J9 GND (power), J10 GND (power), K8 GND (power), K9 GND (power), L6 GND (power), T1 GND (power), T16 GND (power)
part H pins: A15 NC, B2 NC, B3 NC, B14 NC, B15 NC, C2 NC, C3 NC, C14 NC, D3 NC, D4 NC, D13 NC, D14 NC, E4 NC, E5 NC, E6 NC, E7 NC, E10 NC, E11 NC, E12 NC, E13 NC, F5 NC, F6 NC, F12 NC, F13 NC, G4 NC, G5 NC, H4 NC, H5 NC, J12 NC, K4 NC, K5 NC, K12 NC, L11 NC, M4 NC, M5 NC, M7 NC, M8 NC, M11 NC, M12 NC, M13 NC, N5 NC, N6 NC, N10 NC, N11 NC, N12 NC, N13 NC, P2 NC, P3 NC, P15 NC, P16 NC, R15 NC, R16 NC


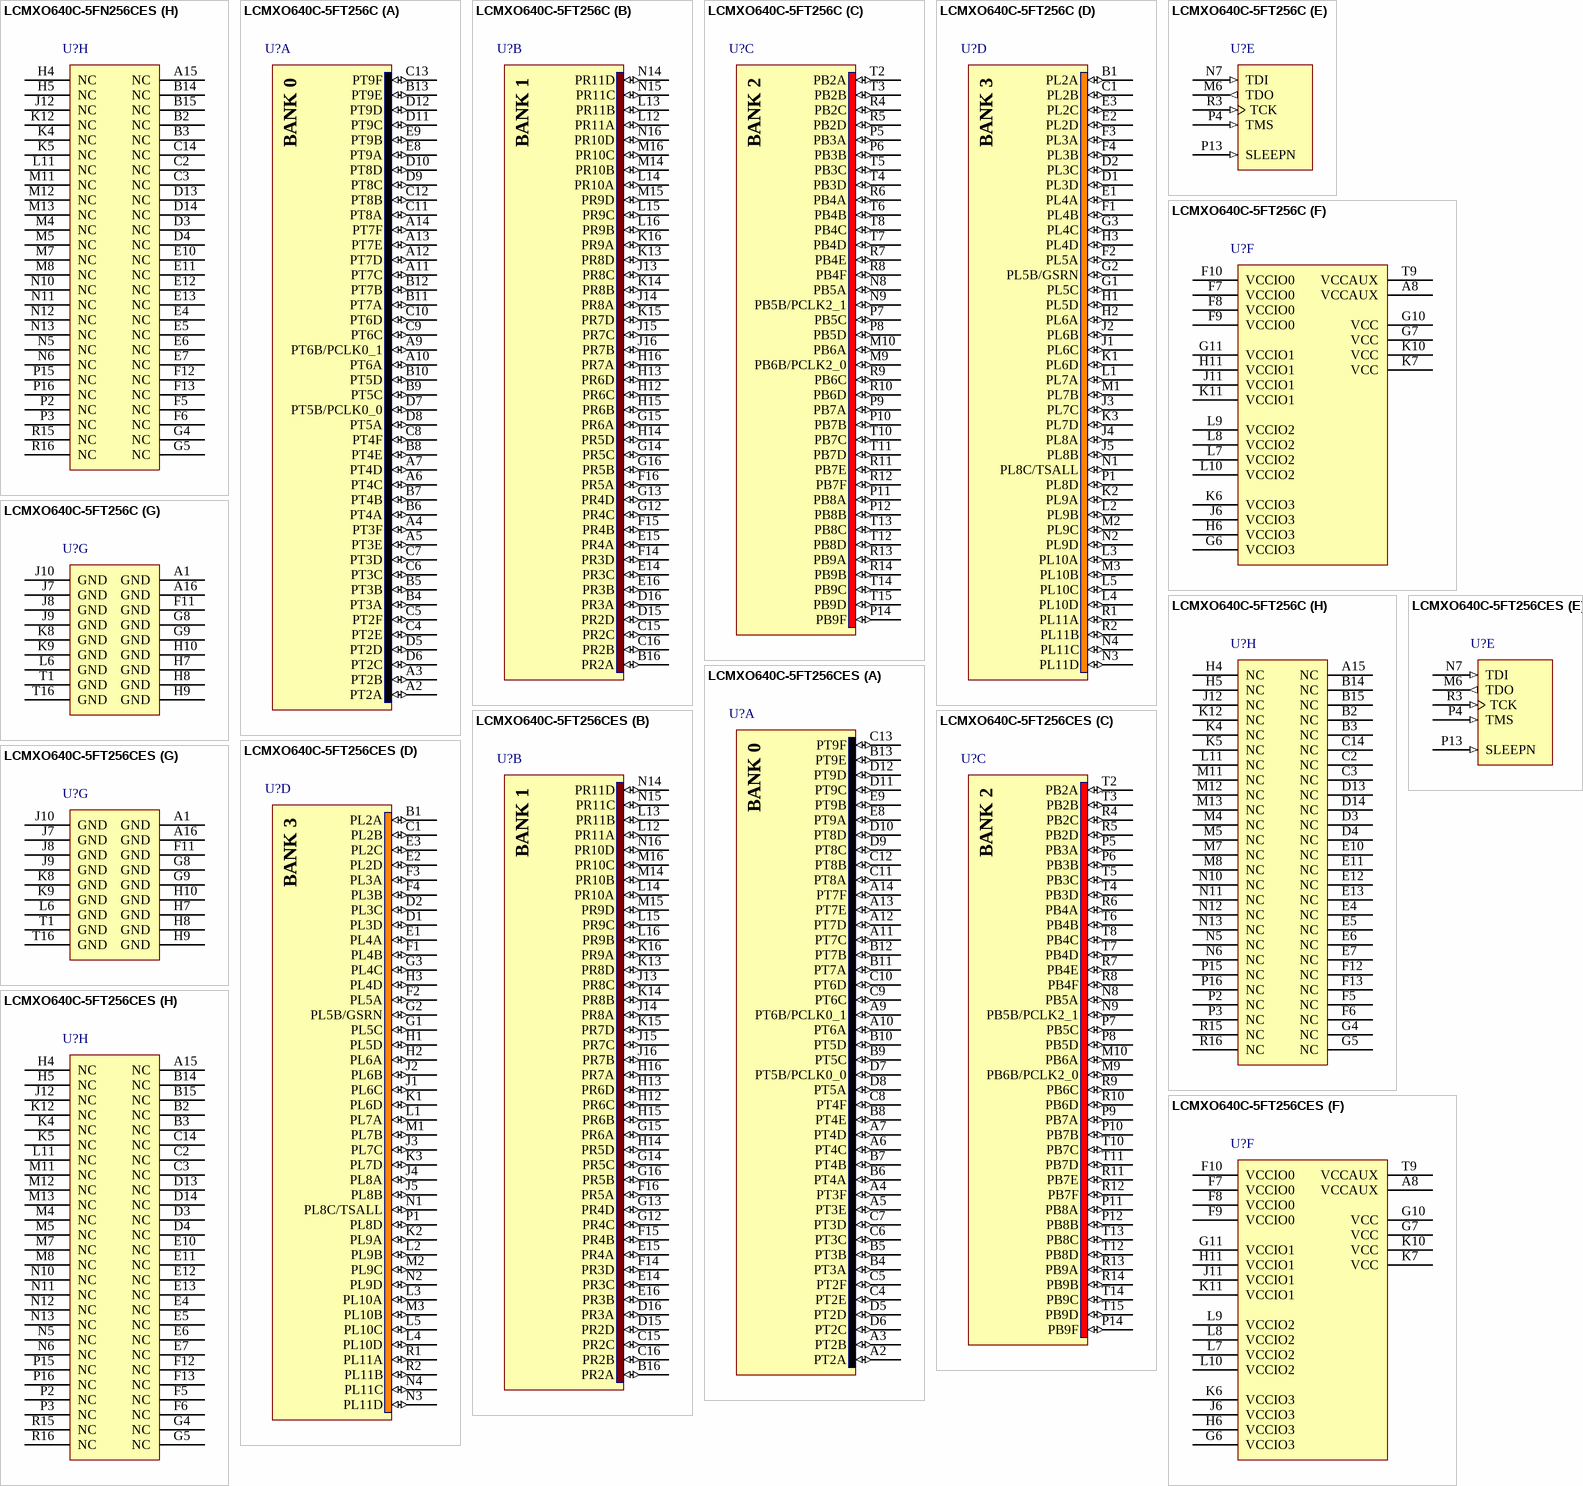
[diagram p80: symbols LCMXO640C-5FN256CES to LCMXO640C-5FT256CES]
## LCMXO640C-5FN256CES
designator U?
MachXO 640 Crossover PLD, 1.8V/2.5V/3.3V, 159 User I/Os, 256-Pins fpBGA, Speed Grade-5, Commercial Grade, Pb-Free, Engineering Sample; ComponentAvailability: Not recommended for new designs. Use ftBGA package device.
footprint fpBGA256 (BGA, 256-Leads, Body 17x17mm, Pitch 1mm)
3D model MachXO640-fpBGA256 (256-Ball Fine Pitch Ball Grid Array (fpBGA256))
signal-integrity model LCMXO640C_F256 (MachXO)
part A pins: A2 PT2A (io), A3 PT2B (io), A4 PT3F (io), A5 PT3E (io), A6 PT4C (io), A7 PT4D (io), A9 PT6B/PCLK0_1 (io), A10 PT6A (io), A11 PT7C (io), A12 PT7D (io), A13 PT7E (io), A14 PT7F (io), B4 PT3A (io), B5 PT3B (io), B6 PT4A (io), B7 PT4B (io), B8 PT4E (io), B9 PT5C (io), B10 PT5D (io), B11 PT7A (io), B12 PT7B (io), B13 PT9E (io), C4 PT2E (io), C5 PT2F (io), C6 PT3C (io), C7 PT3D (io), C8 PT4F (io), C9 PT6C (io), C10 PT6D (io), C11 PT8A (io), C12 PT8B (io), C13 PT9F (io), D5 PT2D (io), D6 PT2C (io), D7 PT5B/PCLK0_0 (io), D8 PT5A (io), D9 PT8C (io), D10 PT8D (io), D11 PT9C (io), D12 PT9D (io), E8 PT9A (io), E9 PT9B (io)
part B pins: B16 PR2A (io), C15 PR2C (io), C16 PR2B (io), D15 PR2D (io), D16 PR3A (io), E14 PR3C (io), E15 PR4A (io), E16 PR3B (io), F14 PR3D (io), F15 PR4B (io), F16 PR5A (io), G12 PR4C (io), G13 PR4D (io), G14 PR5C (io), G15 PR6A (io), G16 PR5B (io), H12 PR6C (io), H13 PR6D (io), H14 PR5D (io), H15 PR6B (io), H16 PR7A (io), J13 PR8C (io), J14 PR8A (io), J15 PR7C (io), J16 PR7B (io), K13 PR8D (io), K14 PR8B (io), K15 PR7D (io), K16 PR9A (io), L12 PR11A (io), L13 PR11B (io), L14 PR10A (io), L15 PR9C (io), L16 PR9B (io), M14 PR10B (io), M15 PR9D (io), M16 PR10C (io), N14 PR11D (io), N15 PR11C (io), N16 PR10D (io)
part C pins: M9 PB6B/PCLK2_0 (io), M10 PB6A (io), N8 PB5A (io), N9 PB5B/PCLK2_1 (io), P5 PB3A (io), P6 PB3B (io), P7 PB5C (io), P8 PB5D (io), P9 PB7A (io), P10 PB7B (io), P11 PB8A (io), P12 PB8B (io), P14 PB9F (io), R4 PB2C (io), R5 PB2D (io), R6 PB4A (io), R7 PB4E (io), R8 PB4F (io), R9 PB6C (io), R10 PB6D (io), R11 PB7E (io), R12 PB7F (io), R13 PB9A (io), R14 PB9B (io), T2 PB2A (io), T3 PB2B (io), T4 PB3D (io), T5 PB3C (io), T6 PB4B (io), T7 PB4D (io), T8 PB4C (io), T10 PB7C (io), T11 PB7D (io), T12 PB8D (io), T13 PB8C (io), T14 PB9C (io), T15 PB9D (io)
part D pins: B1 PL2A (io), C1 PL2B (io), D1 PL3D (io), D2 PL3C (io), E1 PL4A (io), E2 PL2D (io), E3 PL2C (io), F1 PL4B (io), F2 PL5A (io), F3 PL3A (io), F4 PL3B (io), G1 PL5C (io), G2 PL5B/GSRN (io), G3 PL4C (io), H1 PL5D (io), H2 PL6A (io), H3 PL4D (io), J1 PL6C (io), J2 PL6B (io), J3 PL7C (io), J4 PL8A (io), J5 PL8B (io), K1 PL6D (io), K2 PL9A (io), K3 PL7D (io), L1 PL7A (io), L2 PL9B (io), L3 PL10A (io), L4 PL10D (io), L5 PL10C (io), M1 PL7B (io), M2 PL9C (io), M3 PL10B (io), N1 PL8C/TSALL (io), N2 PL9D (io), N3 PL11D (io), N4 PL11C (io), P1 PL8D (io), R1 PL11A (io), R2 PL11B (io)
part E pins: M6 TDO (out) "Powered by VCCIO2", N7 TDI (in) "Powered by VCCIO2", P4 TMS (in) "Powered by VCCIO2", P13 SLEEPN (in) "Powered by VCCIO2", R3 TCK (in) "Powered by VCCIO2"
part F pins: A8 VCCAUX (power), F7 VCCIO0 (power), F8 VCCIO0 (power), F9 VCCIO0 (power), F10 VCCIO0 (power), G6 VCCIO3 (power), G7 VCC (power), G10 VCC (power), G11 VCCIO1 (power), H6 VCCIO3 (power), H11 VCCIO1 (power), J6 VCCIO3 (power), J11 VCCIO1 (power), K6 VCCIO3 (power), K7 VCC (power), K10 VCC (power), K11 VCCIO1 (power), L7 VCCIO2 (power), L8 VCCIO2 (power), L9 VCCIO2 (power), L10 VCCIO2 (power), T9 VCCAUX (power)
part G pins: A1 GND (power), A16 GND (power), F11 GND (power), G8 GND (power), G9 GND (power), H7 GND (power), H8 GND (power), H9 GND (power), H10 GND (power), J7 GND (power), J8 GND (power), J9 GND (power), J10 GND (power), K8 GND (power), K9 GND (power), L6 GND (power), T1 GND (power), T16 GND (power)
part H pins: A15 NC, B2 NC, B3 NC, B14 NC, B15 NC, C2 NC, C3 NC, C14 NC, D3 NC, D4 NC, D13 NC, D14 NC, E4 NC, E5 NC, E6 NC, E7 NC, E10 NC, E11 NC, E12 NC, E13 NC, F5 NC, F6 NC, F12 NC, F13 NC, G4 NC, G5 NC, H4 NC, H5 NC, J12 NC, K4 NC, K5 NC, K12 NC, L11 NC, M4 NC, M5 NC, M7 NC, M8 NC, M11 NC, M12 NC, M13 NC, N5 NC, N6 NC, N10 NC, N11 NC, N12 NC, N13 NC, P2 NC, P3 NC, P15 NC, P16 NC, R15 NC, R16 NC

## LCMXO640C-5FT256C
designator U?
MachXO 640 Crossover PLD, 1.8V/2.5V/3.3V, 159 User I/Os, 256-Pins ftBGA, Speed Grade-5, Commercial Grade
footprint ftBGA256 (BGA, 256-Leads, Body 17x17mm, Pitch 1mm)
3D model MachXO640-ftBGA256 (256-Ball Fine Thin Ball Grid Array (ftBGA256))
signal-integrity model LCMXO640C_FT256 (MachXO)
part A pins: A2 PT2A (io), A3 PT2B (io), A4 PT3F (io), A5 PT3E (io), A6 PT4C (io), A7 PT4D (io), A9 PT6B/PCLK0_1 (io), A10 PT6A (io), A11 PT7C (io), A12 PT7D (io), A13 PT7E (io), A14 PT7F (io), B4 PT3A (io), B5 PT3B (io), B6 PT4A (io), B7 PT4B (io), B8 PT4E (io), B9 PT5C (io), B10 PT5D (io), B11 PT7A (io), B12 PT7B (io), B13 PT9E (io), C4 PT2E (io), C5 PT2F (io), C6 PT3C (io), C7 PT3D (io), C8 PT4F (io), C9 PT6C (io), C10 PT6D (io), C11 PT8A (io), C12 PT8B (io), C13 PT9F (io), D5 PT2D (io), D6 PT2C (io), D7 PT5B/PCLK0_0 (io), D8 PT5A (io), D9 PT8C (io), D10 PT8D (io), D11 PT9C (io), D12 PT9D (io), E8 PT9A (io), E9 PT9B (io)
part B pins: B16 PR2A (io), C15 PR2C (io), C16 PR2B (io), D15 PR2D (io), D16 PR3A (io), E14 PR3C (io), E15 PR4A (io), E16 PR3B (io), F14 PR3D (io), F15 PR4B (io), F16 PR5A (io), G12 PR4C (io), G13 PR4D (io), G14 PR5C (io), G15 PR6A (io), G16 PR5B (io), H12 PR6C (io), H13 PR6D (io), H14 PR5D (io), H15 PR6B (io), H16 PR7A (io), J13 PR8C (io), J14 PR8A (io), J15 PR7C (io), J16 PR7B (io), K13 PR8D (io), K14 PR8B (io), K15 PR7D (io), K16 PR9A (io), L12 PR11A (io), L13 PR11B (io), L14 PR10A (io), L15 PR9C (io), L16 PR9B (io), M14 PR10B (io), M15 PR9D (io), M16 PR10C (io), N14 PR11D (io), N15 PR11C (io), N16 PR10D (io)
part C pins: M9 PB6B/PCLK2_0 (io), M10 PB6A (io), N8 PB5A (io), N9 PB5B/PCLK2_1 (io), P5 PB3A (io), P6 PB3B (io), P7 PB5C (io), P8 PB5D (io), P9 PB7A (io), P10 PB7B (io), P11 PB8A (io), P12 PB8B (io), P14 PB9F (io), R4 PB2C (io), R5 PB2D (io), R6 PB4A (io), R7 PB4E (io), R8 PB4F (io), R9 PB6C (io), R10 PB6D (io), R11 PB7E (io), R12 PB7F (io), R13 PB9A (io), R14 PB9B (io), T2 PB2A (io), T3 PB2B (io), T4 PB3D (io), T5 PB3C (io), T6 PB4B (io), T7 PB4D (io), T8 PB4C (io), T10 PB7C (io), T11 PB7D (io), T12 PB8D (io), T13 PB8C (io), T14 PB9C (io), T15 PB9D (io)
part D pins: B1 PL2A (io), C1 PL2B (io), D1 PL3D (io), D2 PL3C (io), E1 PL4A (io), E2 PL2D (io), E3 PL2C (io), F1 PL4B (io), F2 PL5A (io), F3 PL3A (io), F4 PL3B (io), G1 PL5C (io), G2 PL5B/GSRN (io), G3 PL4C (io), H1 PL5D (io), H2 PL6A (io), H3 PL4D (io), J1 PL6C (io), J2 PL6B (io), J3 PL7C (io), J4 PL8A (io), J5 PL8B (io), K1 PL6D (io), K2 PL9A (io), K3 PL7D (io), L1 PL7A (io), L2 PL9B (io), L3 PL10A (io), L4 PL10D (io), L5 PL10C (io), M1 PL7B (io), M2 PL9C (io), M3 PL10B (io), N1 PL8C/TSALL (io), N2 PL9D (io), N3 PL11D (io), N4 PL11C (io), P1 PL8D (io), R1 PL11A (io), R2 PL11B (io)
part E pins: M6 TDO (out) "Powered by VCCIO2", N7 TDI (in) "Powered by VCCIO2", P4 TMS (in) "Powered by VCCIO2", P13 SLEEPN (in) "Powered by VCCIO2", R3 TCK (in) "Powered by VCCIO2"
part F pins: A8 VCCAUX (power), F7 VCCIO0 (power), F8 VCCIO0 (power), F9 VCCIO0 (power), F10 VCCIO0 (power), G6 VCCIO3 (power), G7 VCC (power), G10 VCC (power), G11 VCCIO1 (power), H6 VCCIO3 (power), H11 VCCIO1 (power), J6 VCCIO3 (power), J11 VCCIO1 (power), K6 VCCIO3 (power), K7 VCC (power), K10 VCC (power), K11 VCCIO1 (power), L7 VCCIO2 (power), L8 VCCIO2 (power), L9 VCCIO2 (power), L10 VCCIO2 (power), T9 VCCAUX (power)
part G pins: A1 GND (power), A16 GND (power), F11 GND (power), G8 GND (power), G9 GND (power), H7 GND (power), H8 GND (power), H9 GND (power), H10 GND (power), J7 GND (power), J8 GND (power), J9 GND (power), J10 GND (power), K8 GND (power), K9 GND (power), L6 GND (power), T1 GND (power), T16 GND (power)
part H pins: A15 NC, B2 NC, B3 NC, B14 NC, B15 NC, C2 NC, C3 NC, C14 NC, D3 NC, D4 NC, D13 NC, D14 NC, E4 NC, E5 NC, E6 NC, E7 NC, E10 NC, E11 NC, E12 NC, E13 NC, F5 NC, F6 NC, F12 NC, F13 NC, G4 NC, G5 NC, H4 NC, H5 NC, J12 NC, K4 NC, K5 NC, K12 NC, L11 NC, M4 NC, M5 NC, M7 NC, M8 NC, M11 NC, M12 NC, M13 NC, N5 NC, N6 NC, N10 NC, N11 NC, N12 NC, N13 NC, P2 NC, P3 NC, P15 NC, P16 NC, R15 NC, R16 NC

## LCMXO640C-5FT256CES
designator U?
MachXO 640 Crossover PLD, 1.8V/2.5V/3.3V, 159 User I/Os, 256-Pins ftBGA, Speed Grade-5, Commercial Grade, Engineering Sample
footprint ftBGA256 (BGA, 256-Leads, Body 17x17mm, Pitch 1mm)
3D model MachXO640-ftBGA256 (256-Ball Fine Thin Ball Grid Array (ftBGA256))
signal-integrity model LCMXO640C_FT256 (MachXO)
part A pins: A2 PT2A (io), A3 PT2B (io), A4 PT3F (io), A5 PT3E (io), A6 PT4C (io), A7 PT4D (io), A9 PT6B/PCLK0_1 (io), A10 PT6A (io), A11 PT7C (io), A12 PT7D (io), A13 PT7E (io), A14 PT7F (io), B4 PT3A (io), B5 PT3B (io), B6 PT4A (io), B7 PT4B (io), B8 PT4E (io), B9 PT5C (io), B10 PT5D (io), B11 PT7A (io), B12 PT7B (io), B13 PT9E (io), C4 PT2E (io), C5 PT2F (io), C6 PT3C (io), C7 PT3D (io), C8 PT4F (io), C9 PT6C (io), C10 PT6D (io), C11 PT8A (io), C12 PT8B (io), C13 PT9F (io), D5 PT2D (io), D6 PT2C (io), D7 PT5B/PCLK0_0 (io), D8 PT5A (io), D9 PT8C (io), D10 PT8D (io), D11 PT9C (io), D12 PT9D (io), E8 PT9A (io), E9 PT9B (io)
part B pins: B16 PR2A (io), C15 PR2C (io), C16 PR2B (io), D15 PR2D (io), D16 PR3A (io), E14 PR3C (io), E15 PR4A (io), E16 PR3B (io), F14 PR3D (io), F15 PR4B (io), F16 PR5A (io), G12 PR4C (io), G13 PR4D (io), G14 PR5C (io), G15 PR6A (io), G16 PR5B (io), H12 PR6C (io), H13 PR6D (io), H14 PR5D (io), H15 PR6B (io), H16 PR7A (io), J13 PR8C (io), J14 PR8A (io), J15 PR7C (io), J16 PR7B (io), K13 PR8D (io), K14 PR8B (io), K15 PR7D (io), K16 PR9A (io), L12 PR11A (io), L13 PR11B (io), L14 PR10A (io), L15 PR9C (io), L16 PR9B (io), M14 PR10B (io), M15 PR9D (io), M16 PR10C (io), N14 PR11D (io), N15 PR11C (io), N16 PR10D (io)
part C pins: M9 PB6B/PCLK2_0 (io), M10 PB6A (io), N8 PB5A (io), N9 PB5B/PCLK2_1 (io), P5 PB3A (io), P6 PB3B (io), P7 PB5C (io), P8 PB5D (io), P9 PB7A (io), P10 PB7B (io), P11 PB8A (io), P12 PB8B (io), P14 PB9F (io), R4 PB2C (io), R5 PB2D (io), R6 PB4A (io), R7 PB4E (io), R8 PB4F (io), R9 PB6C (io), R10 PB6D (io), R11 PB7E (io), R12 PB7F (io), R13 PB9A (io), R14 PB9B (io), T2 PB2A (io), T3 PB2B (io), T4 PB3D (io), T5 PB3C (io), T6 PB4B (io), T7 PB4D (io), T8 PB4C (io), T10 PB7C (io), T11 PB7D (io), T12 PB8D (io), T13 PB8C (io), T14 PB9C (io), T15 PB9D (io)
part D pins: B1 PL2A (io), C1 PL2B (io), D1 PL3D (io), D2 PL3C (io), E1 PL4A (io), E2 PL2D (io), E3 PL2C (io), F1 PL4B (io), F2 PL5A (io), F3 PL3A (io), F4 PL3B (io), G1 PL5C (io), G2 PL5B/GSRN (io), G3 PL4C (io), H1 PL5D (io), H2 PL6A (io), H3 PL4D (io), J1 PL6C (io), J2 PL6B (io), J3 PL7C (io), J4 PL8A (io), J5 PL8B (io), K1 PL6D (io), K2 PL9A (io), K3 PL7D (io), L1 PL7A (io), L2 PL9B (io), L3 PL10A (io), L4 PL10D (io), L5 PL10C (io), M1 PL7B (io), M2 PL9C (io), M3 PL10B (io), N1 PL8C/TSALL (io), N2 PL9D (io), N3 PL11D (io), N4 PL11C (io), P1 PL8D (io), R1 PL11A (io), R2 PL11B (io)
part E pins: M6 TDO (out) "Powered by VCCIO2", N7 TDI (in) "Powered by VCCIO2", P4 TMS (in) "Powered by VCCIO2", P13 SLEEPN (in) "Powered by VCCIO2", R3 TCK (in) "Powered by VCCIO2"
part F pins: A8 VCCAUX (power), F7 VCCIO0 (power), F8 VCCIO0 (power), F9 VCCIO0 (power), F10 VCCIO0 (power), G6 VCCIO3 (power), G7 VCC (power), G10 VCC (power), G11 VCCIO1 (power), H6 VCCIO3 (power), H11 VCCIO1 (power), J6 VCCIO3 (power), J11 VCCIO1 (power), K6 VCCIO3 (power), K7 VCC (power), K10 VCC (power), K11 VCCIO1 (power), L7 VCCIO2 (power), L8 VCCIO2 (power), L9 VCCIO2 (power), L10 VCCIO2 (power), T9 VCCAUX (power)
part G pins: A1 GND (power), A16 GND (power), F11 GND (power), G8 GND (power), G9 GND (power), H7 GND (power), H8 GND (power), H9 GND (power), H10 GND (power), J7 GND (power), J8 GND (power), J9 GND (power), J10 GND (power), K8 GND (power), K9 GND (power), L6 GND (power), T1 GND (power), T16 GND (power)
part H pins: A15 NC, B2 NC, B3 NC, B14 NC, B15 NC, C2 NC, C3 NC, C14 NC, D3 NC, D4 NC, D13 NC, D14 NC, E4 NC, E5 NC, E6 NC, E7 NC, E10 NC, E11 NC, E12 NC, E13 NC, F5 NC, F6 NC, F12 NC, F13 NC, G4 NC, G5 NC, H4 NC, H5 NC, J12 NC, K4 NC, K5 NC, K12 NC, L11 NC, M4 NC, M5 NC, M7 NC, M8 NC, M11 NC, M12 NC, M13 NC, N5 NC, N6 NC, N10 NC, N11 NC, N12 NC, N13 NC, P2 NC, P3 NC, P15 NC, P16 NC, R15 NC, R16 NC


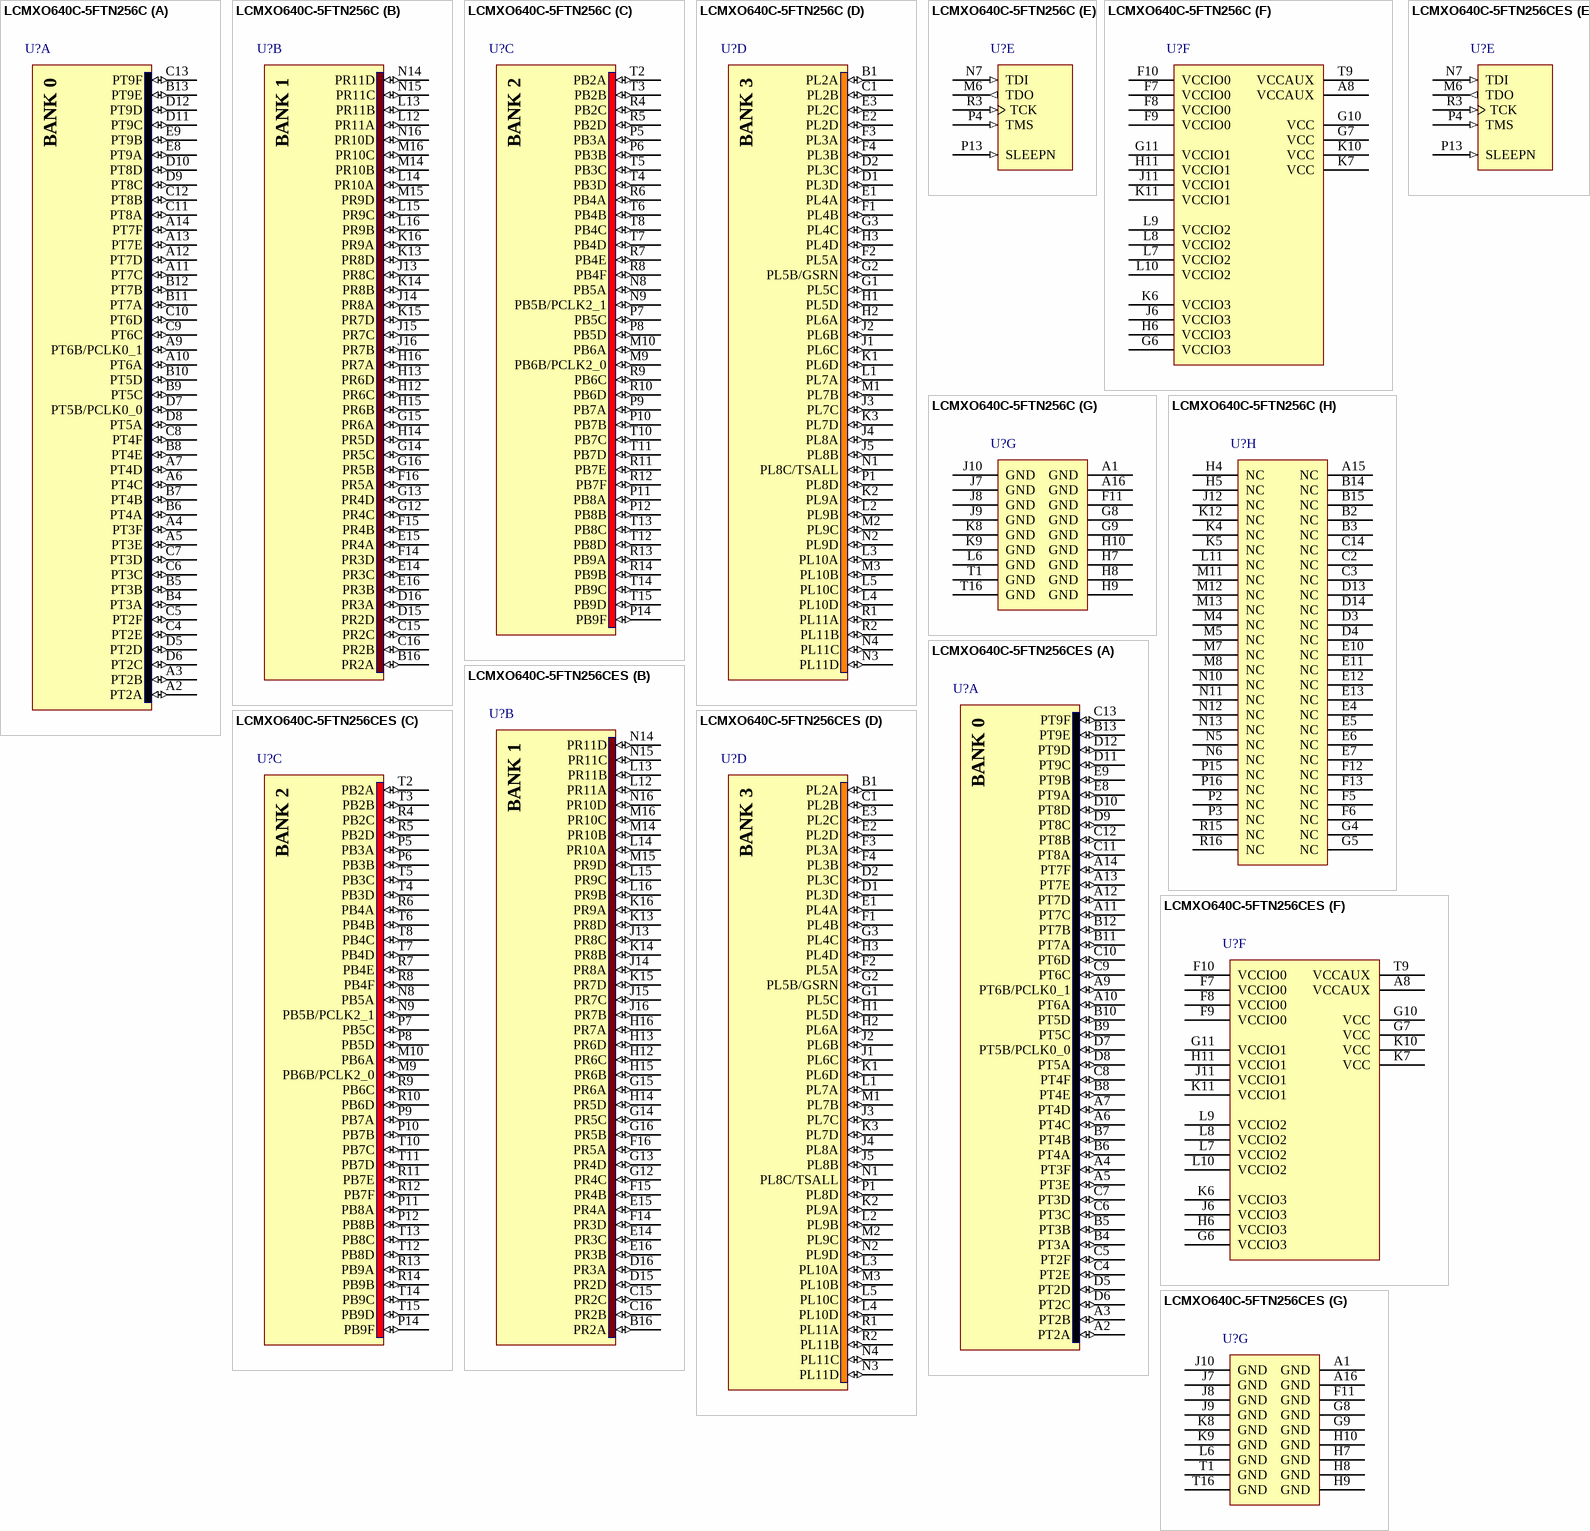
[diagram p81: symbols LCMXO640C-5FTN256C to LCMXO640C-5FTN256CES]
## LCMXO640C-5FTN256C
designator U?
MachXO 640 Crossover PLD, 1.8V/2.5V/3.3V, 159 User I/Os, 256-Pins ftBGA, Speed Grade-5, Commercial Grade, Pb-Free
footprint ftBGA256 (BGA, 256-Leads, Body 17x17mm, Pitch 1mm)
3D model MachXO640-ftBGA256 (256-Ball Fine Thin Ball Grid Array (ftBGA256))
signal-integrity model LCMXO640C_FT256 (MachXO)
part A pins: A2 PT2A (io), A3 PT2B (io), A4 PT3F (io), A5 PT3E (io), A6 PT4C (io), A7 PT4D (io), A9 PT6B/PCLK0_1 (io), A10 PT6A (io), A11 PT7C (io), A12 PT7D (io), A13 PT7E (io), A14 PT7F (io), B4 PT3A (io), B5 PT3B (io), B6 PT4A (io), B7 PT4B (io), B8 PT4E (io), B9 PT5C (io), B10 PT5D (io), B11 PT7A (io), B12 PT7B (io), B13 PT9E (io), C4 PT2E (io), C5 PT2F (io), C6 PT3C (io), C7 PT3D (io), C8 PT4F (io), C9 PT6C (io), C10 PT6D (io), C11 PT8A (io), C12 PT8B (io), C13 PT9F (io), D5 PT2D (io), D6 PT2C (io), D7 PT5B/PCLK0_0 (io), D8 PT5A (io), D9 PT8C (io), D10 PT8D (io), D11 PT9C (io), D12 PT9D (io), E8 PT9A (io), E9 PT9B (io)
part B pins: B16 PR2A (io), C15 PR2C (io), C16 PR2B (io), D15 PR2D (io), D16 PR3A (io), E14 PR3C (io), E15 PR4A (io), E16 PR3B (io), F14 PR3D (io), F15 PR4B (io), F16 PR5A (io), G12 PR4C (io), G13 PR4D (io), G14 PR5C (io), G15 PR6A (io), G16 PR5B (io), H12 PR6C (io), H13 PR6D (io), H14 PR5D (io), H15 PR6B (io), H16 PR7A (io), J13 PR8C (io), J14 PR8A (io), J15 PR7C (io), J16 PR7B (io), K13 PR8D (io), K14 PR8B (io), K15 PR7D (io), K16 PR9A (io), L12 PR11A (io), L13 PR11B (io), L14 PR10A (io), L15 PR9C (io), L16 PR9B (io), M14 PR10B (io), M15 PR9D (io), M16 PR10C (io), N14 PR11D (io), N15 PR11C (io), N16 PR10D (io)
part C pins: M9 PB6B/PCLK2_0 (io), M10 PB6A (io), N8 PB5A (io), N9 PB5B/PCLK2_1 (io), P5 PB3A (io), P6 PB3B (io), P7 PB5C (io), P8 PB5D (io), P9 PB7A (io), P10 PB7B (io), P11 PB8A (io), P12 PB8B (io), P14 PB9F (io), R4 PB2C (io), R5 PB2D (io), R6 PB4A (io), R7 PB4E (io), R8 PB4F (io), R9 PB6C (io), R10 PB6D (io), R11 PB7E (io), R12 PB7F (io), R13 PB9A (io), R14 PB9B (io), T2 PB2A (io), T3 PB2B (io), T4 PB3D (io), T5 PB3C (io), T6 PB4B (io), T7 PB4D (io), T8 PB4C (io), T10 PB7C (io), T11 PB7D (io), T12 PB8D (io), T13 PB8C (io), T14 PB9C (io), T15 PB9D (io)
part D pins: B1 PL2A (io), C1 PL2B (io), D1 PL3D (io), D2 PL3C (io), E1 PL4A (io), E2 PL2D (io), E3 PL2C (io), F1 PL4B (io), F2 PL5A (io), F3 PL3A (io), F4 PL3B (io), G1 PL5C (io), G2 PL5B/GSRN (io), G3 PL4C (io), H1 PL5D (io), H2 PL6A (io), H3 PL4D (io), J1 PL6C (io), J2 PL6B (io), J3 PL7C (io), J4 PL8A (io), J5 PL8B (io), K1 PL6D (io), K2 PL9A (io), K3 PL7D (io), L1 PL7A (io), L2 PL9B (io), L3 PL10A (io), L4 PL10D (io), L5 PL10C (io), M1 PL7B (io), M2 PL9C (io), M3 PL10B (io), N1 PL8C/TSALL (io), N2 PL9D (io), N3 PL11D (io), N4 PL11C (io), P1 PL8D (io), R1 PL11A (io), R2 PL11B (io)
part E pins: M6 TDO (out) "Powered by VCCIO2", N7 TDI (in) "Powered by VCCIO2", P4 TMS (in) "Powered by VCCIO2", P13 SLEEPN (in) "Powered by VCCIO2", R3 TCK (in) "Powered by VCCIO2"
part F pins: A8 VCCAUX (power), F7 VCCIO0 (power), F8 VCCIO0 (power), F9 VCCIO0 (power), F10 VCCIO0 (power), G6 VCCIO3 (power), G7 VCC (power), G10 VCC (power), G11 VCCIO1 (power), H6 VCCIO3 (power), H11 VCCIO1 (power), J6 VCCIO3 (power), J11 VCCIO1 (power), K6 VCCIO3 (power), K7 VCC (power), K10 VCC (power), K11 VCCIO1 (power), L7 VCCIO2 (power), L8 VCCIO2 (power), L9 VCCIO2 (power), L10 VCCIO2 (power), T9 VCCAUX (power)
part G pins: A1 GND (power), A16 GND (power), F11 GND (power), G8 GND (power), G9 GND (power), H7 GND (power), H8 GND (power), H9 GND (power), H10 GND (power), J7 GND (power), J8 GND (power), J9 GND (power), J10 GND (power), K8 GND (power), K9 GND (power), L6 GND (power), T1 GND (power), T16 GND (power)
part H pins: A15 NC, B2 NC, B3 NC, B14 NC, B15 NC, C2 NC, C3 NC, C14 NC, D3 NC, D4 NC, D13 NC, D14 NC, E4 NC, E5 NC, E6 NC, E7 NC, E10 NC, E11 NC, E12 NC, E13 NC, F5 NC, F6 NC, F12 NC, F13 NC, G4 NC, G5 NC, H4 NC, H5 NC, J12 NC, K4 NC, K5 NC, K12 NC, L11 NC, M4 NC, M5 NC, M7 NC, M8 NC, M11 NC, M12 NC, M13 NC, N5 NC, N6 NC, N10 NC, N11 NC, N12 NC, N13 NC, P2 NC, P3 NC, P15 NC, P16 NC, R15 NC, R16 NC


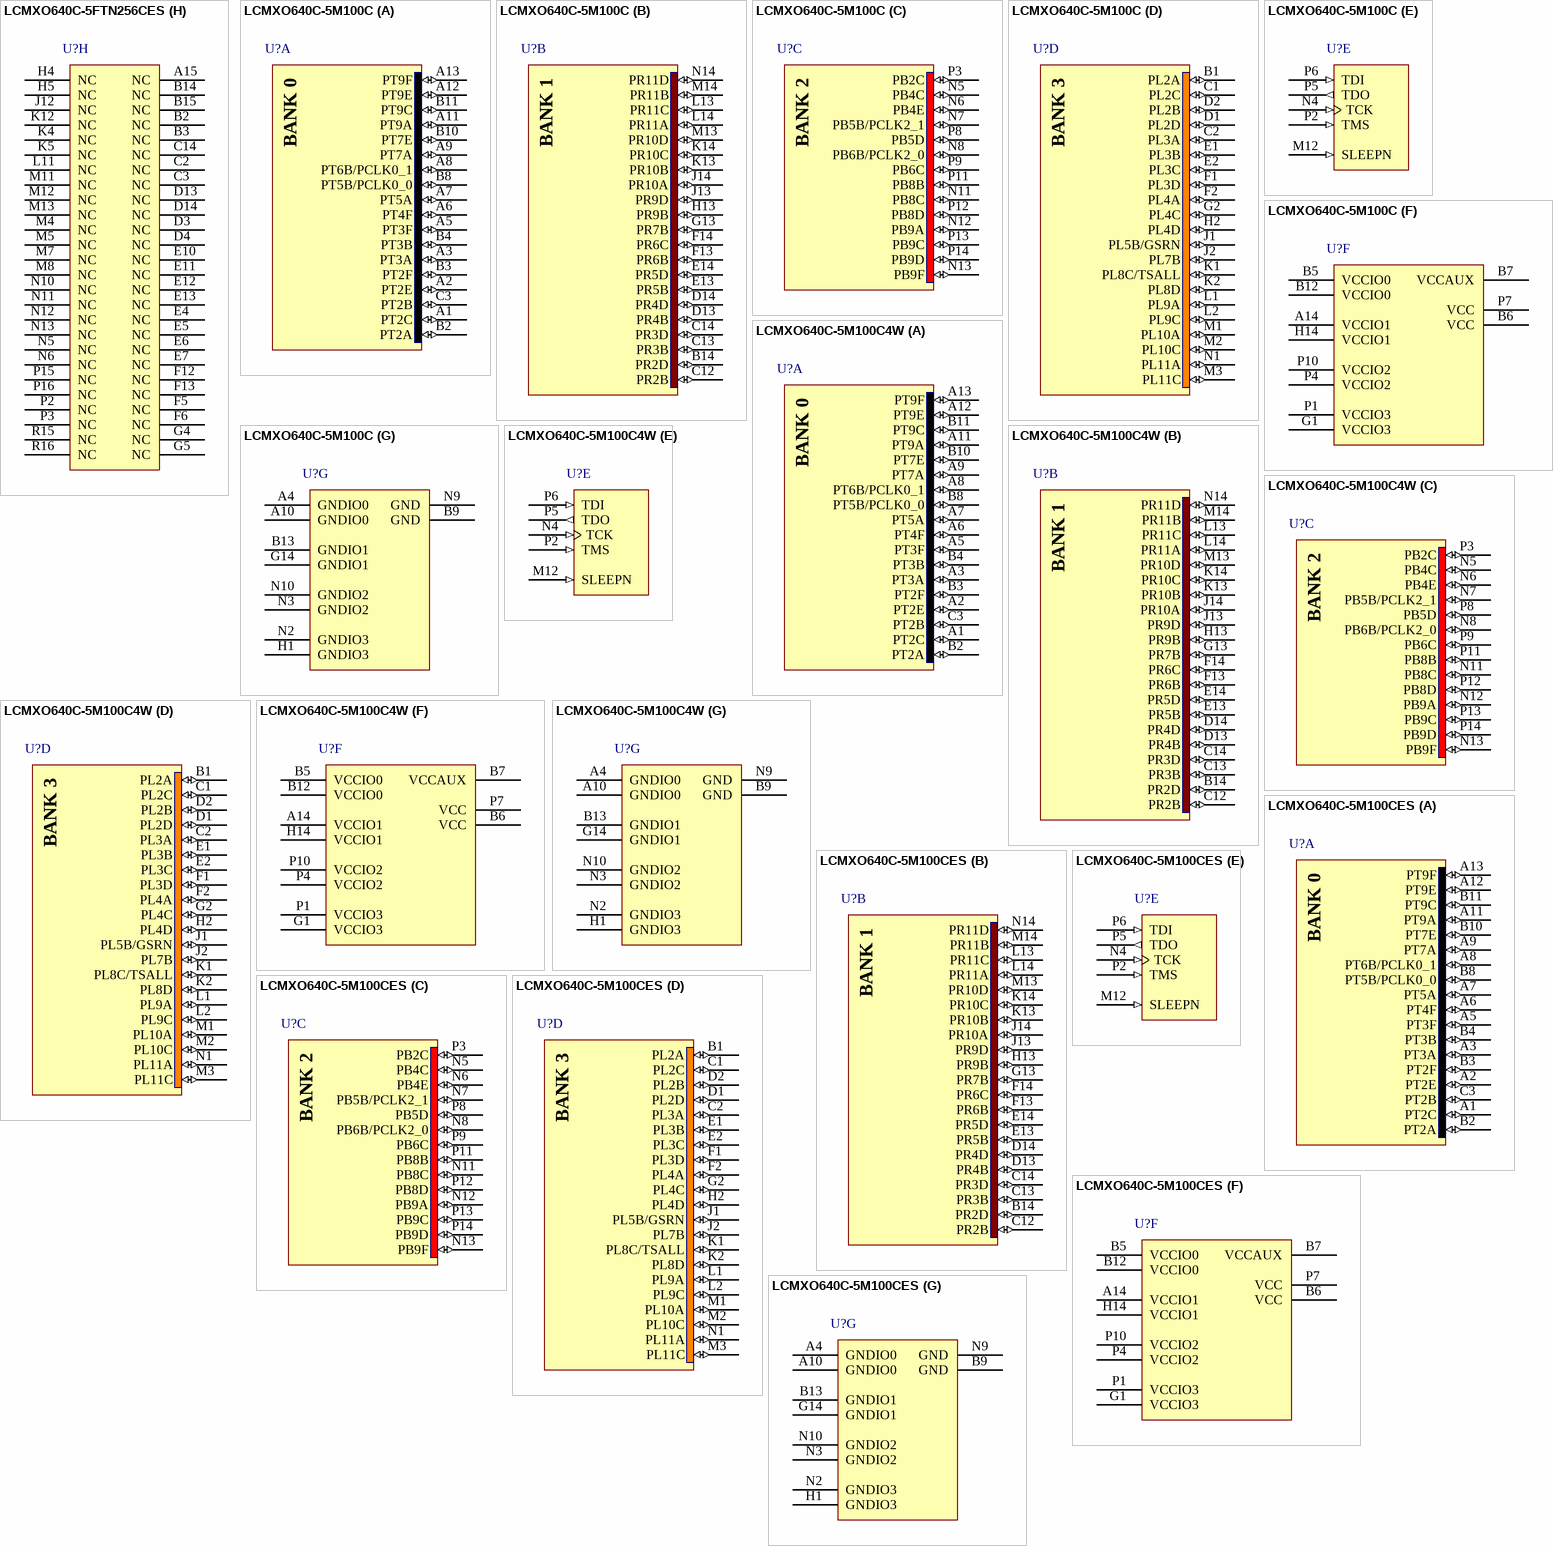
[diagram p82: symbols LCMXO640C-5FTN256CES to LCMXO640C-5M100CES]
## LCMXO640C-5FTN256CES
designator U?
MachXO 640 Crossover PLD, 1.8V/2.5V/3.3V, 159 User I/Os, 256-Pins ftBGA, Speed Grade-5, Commercial Grade, Pb-Free, Engineering Sample
footprint ftBGA256 (BGA, 256-Leads, Body 17x17mm, Pitch 1mm)
3D model MachXO640-ftBGA256 (256-Ball Fine Thin Ball Grid Array (ftBGA256))
signal-integrity model LCMXO640C_FT256 (MachXO)
part A pins: A2 PT2A (io), A3 PT2B (io), A4 PT3F (io), A5 PT3E (io), A6 PT4C (io), A7 PT4D (io), A9 PT6B/PCLK0_1 (io), A10 PT6A (io), A11 PT7C (io), A12 PT7D (io), A13 PT7E (io), A14 PT7F (io), B4 PT3A (io), B5 PT3B (io), B6 PT4A (io), B7 PT4B (io), B8 PT4E (io), B9 PT5C (io), B10 PT5D (io), B11 PT7A (io), B12 PT7B (io), B13 PT9E (io), C4 PT2E (io), C5 PT2F (io), C6 PT3C (io), C7 PT3D (io), C8 PT4F (io), C9 PT6C (io), C10 PT6D (io), C11 PT8A (io), C12 PT8B (io), C13 PT9F (io), D5 PT2D (io), D6 PT2C (io), D7 PT5B/PCLK0_0 (io), D8 PT5A (io), D9 PT8C (io), D10 PT8D (io), D11 PT9C (io), D12 PT9D (io), E8 PT9A (io), E9 PT9B (io)
part B pins: B16 PR2A (io), C15 PR2C (io), C16 PR2B (io), D15 PR2D (io), D16 PR3A (io), E14 PR3C (io), E15 PR4A (io), E16 PR3B (io), F14 PR3D (io), F15 PR4B (io), F16 PR5A (io), G12 PR4C (io), G13 PR4D (io), G14 PR5C (io), G15 PR6A (io), G16 PR5B (io), H12 PR6C (io), H13 PR6D (io), H14 PR5D (io), H15 PR6B (io), H16 PR7A (io), J13 PR8C (io), J14 PR8A (io), J15 PR7C (io), J16 PR7B (io), K13 PR8D (io), K14 PR8B (io), K15 PR7D (io), K16 PR9A (io), L12 PR11A (io), L13 PR11B (io), L14 PR10A (io), L15 PR9C (io), L16 PR9B (io), M14 PR10B (io), M15 PR9D (io), M16 PR10C (io), N14 PR11D (io), N15 PR11C (io), N16 PR10D (io)
part C pins: M9 PB6B/PCLK2_0 (io), M10 PB6A (io), N8 PB5A (io), N9 PB5B/PCLK2_1 (io), P5 PB3A (io), P6 PB3B (io), P7 PB5C (io), P8 PB5D (io), P9 PB7A (io), P10 PB7B (io), P11 PB8A (io), P12 PB8B (io), P14 PB9F (io), R4 PB2C (io), R5 PB2D (io), R6 PB4A (io), R7 PB4E (io), R8 PB4F (io), R9 PB6C (io), R10 PB6D (io), R11 PB7E (io), R12 PB7F (io), R13 PB9A (io), R14 PB9B (io), T2 PB2A (io), T3 PB2B (io), T4 PB3D (io), T5 PB3C (io), T6 PB4B (io), T7 PB4D (io), T8 PB4C (io), T10 PB7C (io), T11 PB7D (io), T12 PB8D (io), T13 PB8C (io), T14 PB9C (io), T15 PB9D (io)
part D pins: B1 PL2A (io), C1 PL2B (io), D1 PL3D (io), D2 PL3C (io), E1 PL4A (io), E2 PL2D (io), E3 PL2C (io), F1 PL4B (io), F2 PL5A (io), F3 PL3A (io), F4 PL3B (io), G1 PL5C (io), G2 PL5B/GSRN (io), G3 PL4C (io), H1 PL5D (io), H2 PL6A (io), H3 PL4D (io), J1 PL6C (io), J2 PL6B (io), J3 PL7C (io), J4 PL8A (io), J5 PL8B (io), K1 PL6D (io), K2 PL9A (io), K3 PL7D (io), L1 PL7A (io), L2 PL9B (io), L3 PL10A (io), L4 PL10D (io), L5 PL10C (io), M1 PL7B (io), M2 PL9C (io), M3 PL10B (io), N1 PL8C/TSALL (io), N2 PL9D (io), N3 PL11D (io), N4 PL11C (io), P1 PL8D (io), R1 PL11A (io), R2 PL11B (io)
part E pins: M6 TDO (out) "Powered by VCCIO2", N7 TDI (in) "Powered by VCCIO2", P4 TMS (in) "Powered by VCCIO2", P13 SLEEPN (in) "Powered by VCCIO2", R3 TCK (in) "Powered by VCCIO2"
part F pins: A8 VCCAUX (power), F7 VCCIO0 (power), F8 VCCIO0 (power), F9 VCCIO0 (power), F10 VCCIO0 (power), G6 VCCIO3 (power), G7 VCC (power), G10 VCC (power), G11 VCCIO1 (power), H6 VCCIO3 (power), H11 VCCIO1 (power), J6 VCCIO3 (power), J11 VCCIO1 (power), K6 VCCIO3 (power), K7 VCC (power), K10 VCC (power), K11 VCCIO1 (power), L7 VCCIO2 (power), L8 VCCIO2 (power), L9 VCCIO2 (power), L10 VCCIO2 (power), T9 VCCAUX (power)
part G pins: A1 GND (power), A16 GND (power), F11 GND (power), G8 GND (power), G9 GND (power), H7 GND (power), H8 GND (power), H9 GND (power), H10 GND (power), J7 GND (power), J8 GND (power), J9 GND (power), J10 GND (power), K8 GND (power), K9 GND (power), L6 GND (power), T1 GND (power), T16 GND (power)
part H pins: A15 NC, B2 NC, B3 NC, B14 NC, B15 NC, C2 NC, C3 NC, C14 NC, D3 NC, D4 NC, D13 NC, D14 NC, E4 NC, E5 NC, E6 NC, E7 NC, E10 NC, E11 NC, E12 NC, E13 NC, F5 NC, F6 NC, F12 NC, F13 NC, G4 NC, G5 NC, H4 NC, H5 NC, J12 NC, K4 NC, K5 NC, K12 NC, L11 NC, M4 NC, M5 NC, M7 NC, M8 NC, M11 NC, M12 NC, M13 NC, N5 NC, N6 NC, N10 NC, N11 NC, N12 NC, N13 NC, P2 NC, P3 NC, P15 NC, P16 NC, R15 NC, R16 NC

## LCMXO640C-5M100C
designator U?
MachXO 640 Crossover PLD, 1.8V/2.5V/3.3V, 74 User I/Os, 100-Pins csBGA, Speed Grade-5, Commercial Grade
footprint csBGA100 (BGA, 100-Leads, Body 8x8mm, Pitch 0.5mm)
3D model MachXO640-csBGA100 (100-Ball Chip Scale Ball Grid Array (csBGA100))
signal-integrity model LCMXO640C_M100 (MachXO)
part A pins: A1 PT2C (io), A2 PT2E (io), A3 PT3A (io), A5 PT3F (io), A6 PT4F (io), A7 PT5A (io), A8 PT6B/PCLK0_1 (io), A9 PT7A (io), A11 PT9A (io), A12 PT9E (io), A13 PT9F (io), B2 PT2A (io), B3 PT2F (io), B4 PT3B (io), B8 PT5B/PCLK0_0 (io), B10 PT7E (io), B11 PT9C (io), C3 PT2B (io)
part B pins: B14 PR2D (io), C12 PR2B (io), C13 PR3B (io), C14 PR3D (io), D13 PR4B (io), D14 PR4D (io), E13 PR5B (io), E14 PR5D (io), F13 PR6B (io), F14 PR6C (io), G13 PR7B (io), H13 PR9B (io), J13 PR9D (io), J14 PR10A (io), K13 PR10B (io), K14 PR10C (io), L13 PR11C (io), L14 PR11A (io), M13 PR10D (io), M14 PR11B (io), N14 PR11D (io)
part C pins: N5 PB4C (io), N6 PB4E (io), N7 PB5B/PCLK2_1 (io), N8 PB6B/PCLK2_0 (io), N11 PB8C (io), N12 PB9A (io), N13 PB9F (io), P3 PB2C (io), P8 PB5D (io), P9 PB6C (io), P11 PB8B (io), P12 PB8D (io), P13 PB9C (io), P14 PB9D (io)
part D pins: B1 PL2A (io), C1 PL2C (io), C2 PL3A (io), D1 PL2D (io), D2 PL2B (io), E1 PL3B (io), E2 PL3C (io), F1 PL3D (io), F2 PL4A (io), G2 PL4C (io), H2 PL4D (io), J1 PL5B/GSRN (io), J2 PL7B (io), K1 PL8C/TSALL (io), K2 PL8D (io), L1 PL9A (io), L2 PL9C (io), M1 PL10A (io), M2 PL10C (io), M3 PL11C (io), N1 PL11A (io)
part E pins: M12 SLEEPN (in) "Powered by VCCIO2", N4 TCK (in) "Powered by VCCIO2", P2 TMS (in) "Powered by VCCIO2", P5 TDO (out) "Powered by VCCIO2", P6 TDI (in) "Powered by VCCIO2"
part F pins: A14 VCCIO1 (power), B5 VCCIO0 (power), B6 VCC (power), B7 VCCAUX (power), B12 VCCIO0 (power), G1 VCCIO3 (power), H14 VCCIO1 (power), P1 VCCIO3 (power), P4 VCCIO2 (power), P7 VCC (power), P10 VCCIO2 (power)
part G pins: A4 GNDIO0 (power), A10 GNDIO0 (power), B9 GND (power), B13 GNDIO1 (power), G14 GNDIO1 (power), H1 GNDIO3 (power), N2 GNDIO3 (power), N3 GNDIO2 (power), N9 GND (power), N10 GNDIO2 (power)

## LCMXO640C-5M100C4W
designator U?
MachXO 640 Crossover PLD, 1.8V/2.5V/3.3V, 74 User I/Os, 100-Pins csBGA, Speed Grade-5, Commercial Grade
footprint csBGA100 (BGA, 100-Leads, Body 8x8mm, Pitch 0.5mm)
3D model MachXO640-csBGA100 (100-Ball Chip Scale Ball Grid Array (csBGA100))
signal-integrity model LCMXO640C_M100 (MachXO)
part A pins: A1 PT2C (io), A2 PT2E (io), A3 PT3A (io), A5 PT3F (io), A6 PT4F (io), A7 PT5A (io), A8 PT6B/PCLK0_1 (io), A9 PT7A (io), A11 PT9A (io), A12 PT9E (io), A13 PT9F (io), B2 PT2A (io), B3 PT2F (io), B4 PT3B (io), B8 PT5B/PCLK0_0 (io), B10 PT7E (io), B11 PT9C (io), C3 PT2B (io)
part B pins: B14 PR2D (io), C12 PR2B (io), C13 PR3B (io), C14 PR3D (io), D13 PR4B (io), D14 PR4D (io), E13 PR5B (io), E14 PR5D (io), F13 PR6B (io), F14 PR6C (io), G13 PR7B (io), H13 PR9B (io), J13 PR9D (io), J14 PR10A (io), K13 PR10B (io), K14 PR10C (io), L13 PR11C (io), L14 PR11A (io), M13 PR10D (io), M14 PR11B (io), N14 PR11D (io)
part C pins: N5 PB4C (io), N6 PB4E (io), N7 PB5B/PCLK2_1 (io), N8 PB6B/PCLK2_0 (io), N11 PB8C (io), N12 PB9A (io), N13 PB9F (io), P3 PB2C (io), P8 PB5D (io), P9 PB6C (io), P11 PB8B (io), P12 PB8D (io), P13 PB9C (io), P14 PB9D (io)
part D pins: B1 PL2A (io), C1 PL2C (io), C2 PL3A (io), D1 PL2D (io), D2 PL2B (io), E1 PL3B (io), E2 PL3C (io), F1 PL3D (io), F2 PL4A (io), G2 PL4C (io), H2 PL4D (io), J1 PL5B/GSRN (io), J2 PL7B (io), K1 PL8C/TSALL (io), K2 PL8D (io), L1 PL9A (io), L2 PL9C (io), M1 PL10A (io), M2 PL10C (io), M3 PL11C (io), N1 PL11A (io)
part E pins: M12 SLEEPN (in) "Powered by VCCIO2", N4 TCK (in) "Powered by VCCIO2", P2 TMS (in) "Powered by VCCIO2", P5 TDO (out) "Powered by VCCIO2", P6 TDI (in) "Powered by VCCIO2"
part F pins: A14 VCCIO1 (power), B5 VCCIO0 (power), B6 VCC (power), B7 VCCAUX (power), B12 VCCIO0 (power), G1 VCCIO3 (power), H14 VCCIO1 (power), P1 VCCIO3 (power), P4 VCCIO2 (power), P7 VCC (power), P10 VCCIO2 (power)
part G pins: A4 GNDIO0 (power), A10 GNDIO0 (power), B9 GND (power), B13 GNDIO1 (power), G14 GNDIO1 (power), H1 GNDIO3 (power), N2 GNDIO3 (power), N3 GNDIO2 (power), N9 GND (power), N10 GNDIO2 (power)

## LCMXO640C-5M100CES
designator U?
MachXO 640 Crossover PLD, 1.8V/2.5V/3.3V, 74 User I/Os, 100-Pins csBGA, Speed Grade-5, Commercial Grade, Engineering Sample
footprint csBGA100 (BGA, 100-Leads, Body 8x8mm, Pitch 0.5mm)
3D model MachXO640-csBGA100 (100-Ball Chip Scale Ball Grid Array (csBGA100))
signal-integrity model LCMXO640C_M100 (MachXO)
part A pins: A1 PT2C (io), A2 PT2E (io), A3 PT3A (io), A5 PT3F (io), A6 PT4F (io), A7 PT5A (io), A8 PT6B/PCLK0_1 (io), A9 PT7A (io), A11 PT9A (io), A12 PT9E (io), A13 PT9F (io), B2 PT2A (io), B3 PT2F (io), B4 PT3B (io), B8 PT5B/PCLK0_0 (io), B10 PT7E (io), B11 PT9C (io), C3 PT2B (io)
part B pins: B14 PR2D (io), C12 PR2B (io), C13 PR3B (io), C14 PR3D (io), D13 PR4B (io), D14 PR4D (io), E13 PR5B (io), E14 PR5D (io), F13 PR6B (io), F14 PR6C (io), G13 PR7B (io), H13 PR9B (io), J13 PR9D (io), J14 PR10A (io), K13 PR10B (io), K14 PR10C (io), L13 PR11C (io), L14 PR11A (io), M13 PR10D (io), M14 PR11B (io), N14 PR11D (io)
part C pins: N5 PB4C (io), N6 PB4E (io), N7 PB5B/PCLK2_1 (io), N8 PB6B/PCLK2_0 (io), N11 PB8C (io), N12 PB9A (io), N13 PB9F (io), P3 PB2C (io), P8 PB5D (io), P9 PB6C (io), P11 PB8B (io), P12 PB8D (io), P13 PB9C (io), P14 PB9D (io)
part D pins: B1 PL2A (io), C1 PL2C (io), C2 PL3A (io), D1 PL2D (io), D2 PL2B (io), E1 PL3B (io), E2 PL3C (io), F1 PL3D (io), F2 PL4A (io), G2 PL4C (io), H2 PL4D (io), J1 PL5B/GSRN (io), J2 PL7B (io), K1 PL8C/TSALL (io), K2 PL8D (io), L1 PL9A (io), L2 PL9C (io), M1 PL10A (io), M2 PL10C (io), M3 PL11C (io), N1 PL11A (io)
part E pins: M12 SLEEPN (in) "Powered by VCCIO2", N4 TCK (in) "Powered by VCCIO2", P2 TMS (in) "Powered by VCCIO2", P5 TDO (out) "Powered by VCCIO2", P6 TDI (in) "Powered by VCCIO2"
part F pins: A14 VCCIO1 (power), B5 VCCIO0 (power), B6 VCC (power), B7 VCCAUX (power), B12 VCCIO0 (power), G1 VCCIO3 (power), H14 VCCIO1 (power), P1 VCCIO3 (power), P4 VCCIO2 (power), P7 VCC (power), P10 VCCIO2 (power)
part G pins: A4 GNDIO0 (power), A10 GNDIO0 (power), B9 GND (power), B13 GNDIO1 (power), G14 GNDIO1 (power), H1 GNDIO3 (power), N2 GNDIO3 (power), N3 GNDIO2 (power), N9 GND (power), N10 GNDIO2 (power)


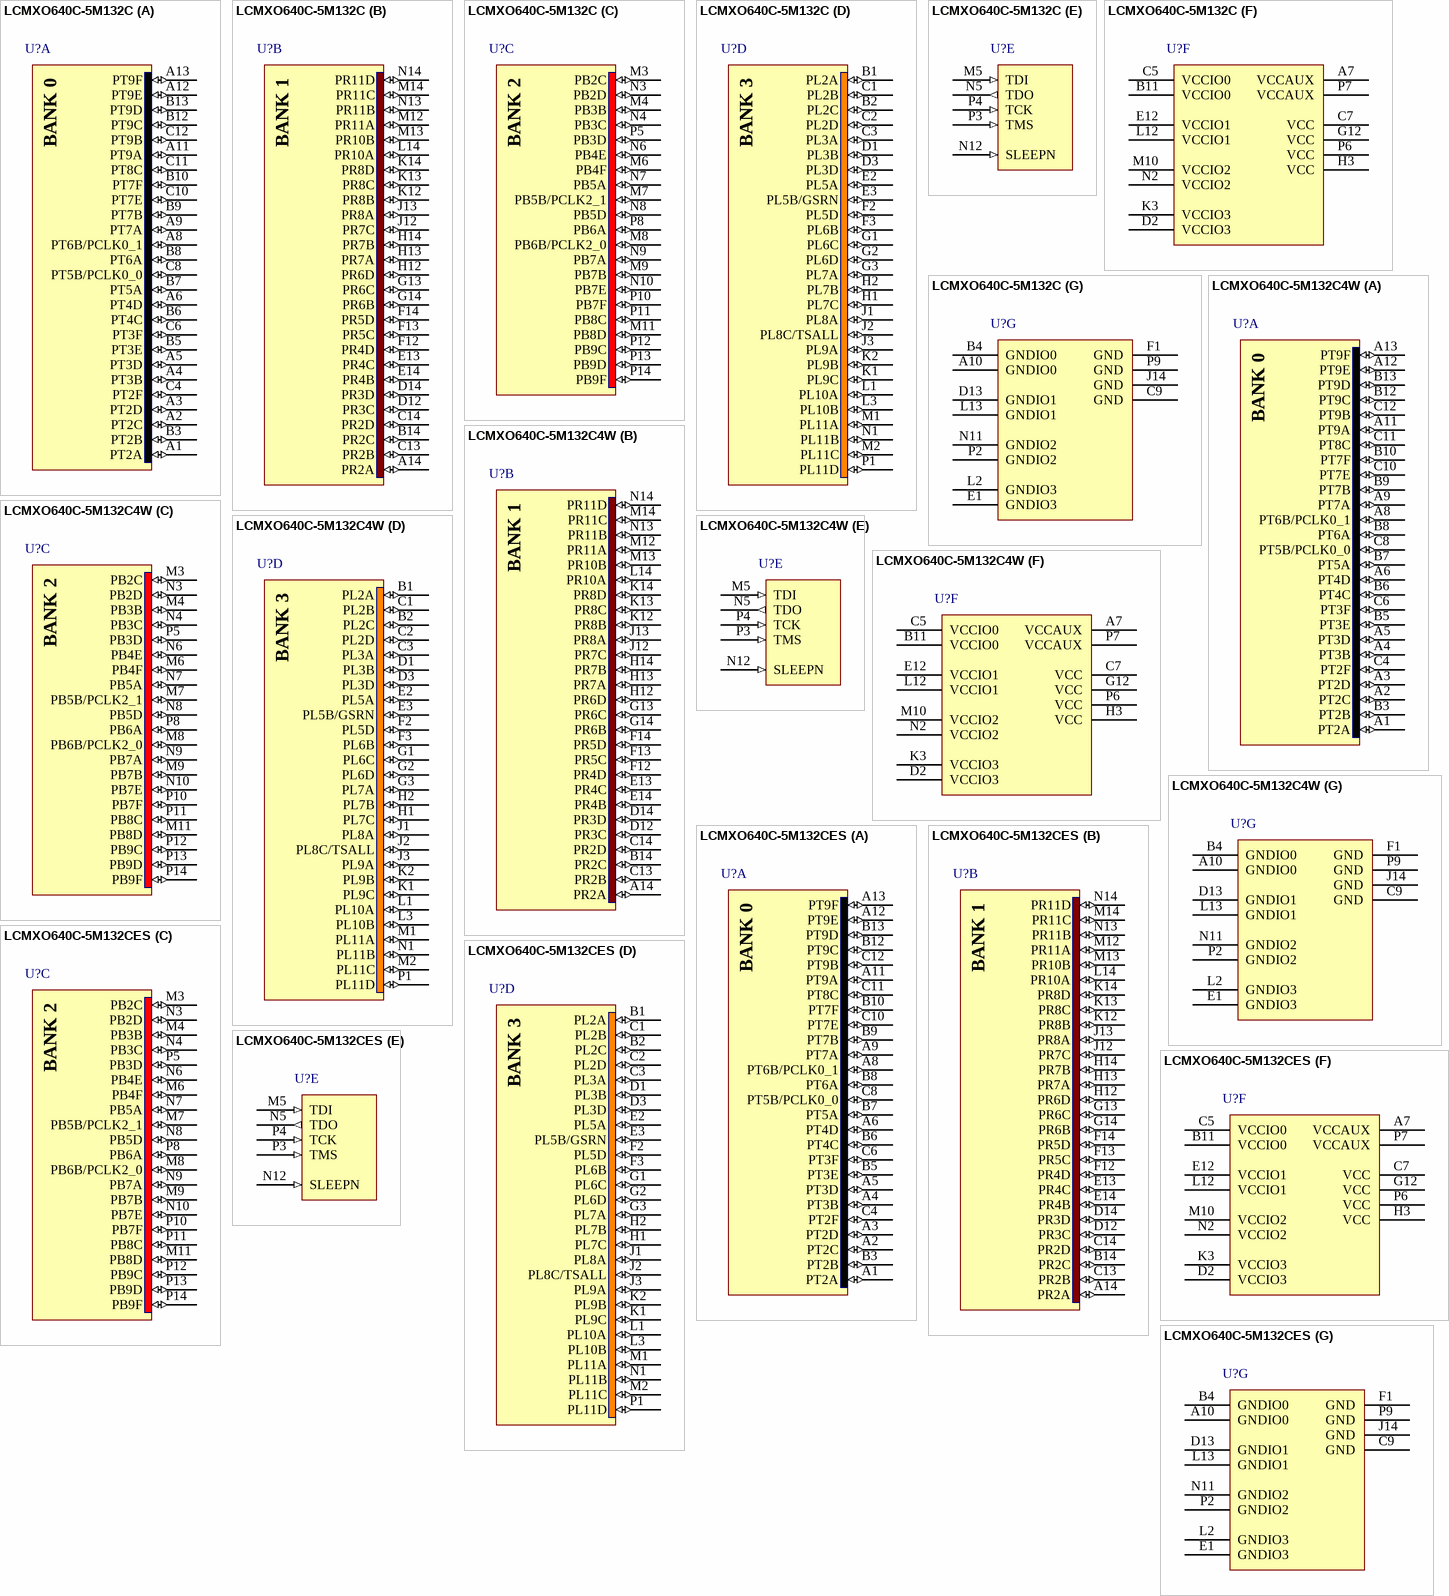
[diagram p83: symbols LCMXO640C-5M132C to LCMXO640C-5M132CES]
## LCMXO640C-5M132C
designator U?
MachXO 640 Crossover PLD, 1.8V/2.5V/3.3V, 101 User I/Os, 132-Pins csBGA, Speed Grade-5, Commercial Grade
footprint csBGA132 (BGA, 132-Leads, Body 8x8mm, Pitch 0.5mm)
3D model MachXO640-csBGA132 (132-Ball Chip Scale Ball Grid Array (csBGA132))
signal-integrity model LCMXO640C_M132 (MachXO)
part A pins: A1 PT2A (io), A2 PT2C (io), A3 PT2D (io), A4 PT3B (io), A5 PT3D (io), A6 PT4D (io), A8 PT6B/PCLK0_1 (io), A9 PT7A (io), A11 PT9A (io), A12 PT9E (io), A13 PT9F (io), B3 PT2B (io), B5 PT3E (io), B6 PT4C (io), B7 PT5A (io), B8 PT6A (io), B9 PT7B (io), B10 PT7F (io), B12 PT9C (io), B13 PT9D (io), C4 PT2F (io), C6 PT3F (io), C8 PT5B/PCLK0_0 (io), C10 PT7E (io), C11 PT8C (io), C12 PT9B (io)
part B pins: A14 PR2A (io), B14 PR2C (io), C13 PR2B (io), C14 PR2D (io), D12 PR3C (io), D14 PR3D (io), E13 PR4C (io), E14 PR4B (io), F12 PR4D (io), F13 PR5C (io), F14 PR5D (io), G13 PR6C (io), G14 PR6B (io), H12 PR6D (io), H13 PR7A (io), H14 PR7B (io), J12 PR7C (io), J13 PR8A (io), K12 PR8B (io), K13 PR8C (io), K14 PR8D (io), L14 PR10A (io), M12 PR11A (io), M13 PR10B (io), M14 PR11C (io), N13 PR11B (io), N14 PR11D (io)
part C pins: M3 PB2C (io), M4 PB3B (io), M6 PB4F (io), M7 PB5B/PCLK2_1 (io), M8 PB6B/PCLK2_0 (io), M9 PB7B (io), M11 PB8D (io), N3 PB2D (io), N4 PB3C (io), N6 PB4E (io), N7 PB5A (io), N8 PB5D (io), N9 PB7A (io), N10 PB7E (io), P5 PB3D (io), P8 PB6A (io), P10 PB7F (io), P11 PB8C (io), P12 PB9C (io), P13 PB9D (io), P14 PB9F (io)
part D pins: B1 PL2A (io), B2 PL2C (io), C1 PL2B (io), C2 PL2D (io), C3 PL3A (io), D1 PL3B (io), D3 PL3D (io), E2 PL5A (io), E3 PL5B/GSRN (io), F2 PL5D (io), F3 PL6B (io), G1 PL6C (io), G2 PL6D (io), G3 PL7A (io), H1 PL7C (io), H2 PL7B (io), J1 PL8A (io), J2 PL8C/TSALL (io), J3 PL9A (io), K1 PL9C (io), K2 PL9B (io), L1 PL10A (io), L3 PL10B (io), M1 PL11A (io), M2 PL11C (io), N1 PL11B (io), P1 PL11D (io)
part E pins: M5 TDI (in) "Powered by VCCIO2", N5 TDO (out) "Powered by VCCIO2", N12 SLEEPN (in) "Powered by VCCIO2", P3 TMS (in) "Powered by VCCIO2", P4 TCK (in) "Powered by VCCIO2"
part F pins: A7 VCCAUX (power), B11 VCCIO0 (power), C5 VCCIO0 (power), C7 VCC (power), D2 VCCIO3 (power), E12 VCCIO1 (power), G12 VCC (power), H3 VCC (power), K3 VCCIO3 (power), L12 VCCIO1 (power), M10 VCCIO2 (power), N2 VCCIO2 (power), P6 VCC (power), P7 VCCAUX (power)
part G pins: A10 GNDIO0 (power), B4 GNDIO0 (power), C9 GND (power), D13 GNDIO1 (power), E1 GNDIO3 (power), F1 GND (power), J14 GND (power), L2 GNDIO3 (power), L13 GNDIO1 (power), N11 GNDIO2 (power), P2 GNDIO2 (power), P9 GND (power)

## LCMXO640C-5M132C4W
designator U?
MachXO 640 Crossover PLD, 1.8V/2.5V/3.3V, 101 User I/Os, 132-Pins csBGA, Speed Grade-5, Commercial Grade
footprint csBGA132 (BGA, 132-Leads, Body 8x8mm, Pitch 0.5mm)
3D model MachXO640-csBGA132 (132-Ball Chip Scale Ball Grid Array (csBGA132))
signal-integrity model LCMXO640C_M132 (MachXO)
part A pins: A1 PT2A (io), A2 PT2C (io), A3 PT2D (io), A4 PT3B (io), A5 PT3D (io), A6 PT4D (io), A8 PT6B/PCLK0_1 (io), A9 PT7A (io), A11 PT9A (io), A12 PT9E (io), A13 PT9F (io), B3 PT2B (io), B5 PT3E (io), B6 PT4C (io), B7 PT5A (io), B8 PT6A (io), B9 PT7B (io), B10 PT7F (io), B12 PT9C (io), B13 PT9D (io), C4 PT2F (io), C6 PT3F (io), C8 PT5B/PCLK0_0 (io), C10 PT7E (io), C11 PT8C (io), C12 PT9B (io)
part B pins: A14 PR2A (io), B14 PR2C (io), C13 PR2B (io), C14 PR2D (io), D12 PR3C (io), D14 PR3D (io), E13 PR4C (io), E14 PR4B (io), F12 PR4D (io), F13 PR5C (io), F14 PR5D (io), G13 PR6C (io), G14 PR6B (io), H12 PR6D (io), H13 PR7A (io), H14 PR7B (io), J12 PR7C (io), J13 PR8A (io), K12 PR8B (io), K13 PR8C (io), K14 PR8D (io), L14 PR10A (io), M12 PR11A (io), M13 PR10B (io), M14 PR11C (io), N13 PR11B (io), N14 PR11D (io)
part C pins: M3 PB2C (io), M4 PB3B (io), M6 PB4F (io), M7 PB5B/PCLK2_1 (io), M8 PB6B/PCLK2_0 (io), M9 PB7B (io), M11 PB8D (io), N3 PB2D (io), N4 PB3C (io), N6 PB4E (io), N7 PB5A (io), N8 PB5D (io), N9 PB7A (io), N10 PB7E (io), P5 PB3D (io), P8 PB6A (io), P10 PB7F (io), P11 PB8C (io), P12 PB9C (io), P13 PB9D (io), P14 PB9F (io)
part D pins: B1 PL2A (io), B2 PL2C (io), C1 PL2B (io), C2 PL2D (io), C3 PL3A (io), D1 PL3B (io), D3 PL3D (io), E2 PL5A (io), E3 PL5B/GSRN (io), F2 PL5D (io), F3 PL6B (io), G1 PL6C (io), G2 PL6D (io), G3 PL7A (io), H1 PL7C (io), H2 PL7B (io), J1 PL8A (io), J2 PL8C/TSALL (io), J3 PL9A (io), K1 PL9C (io), K2 PL9B (io), L1 PL10A (io), L3 PL10B (io), M1 PL11A (io), M2 PL11C (io), N1 PL11B (io), P1 PL11D (io)
part E pins: M5 TDI (in) "Powered by VCCIO2", N5 TDO (out) "Powered by VCCIO2", N12 SLEEPN (in) "Powered by VCCIO2", P3 TMS (in) "Powered by VCCIO2", P4 TCK (in) "Powered by VCCIO2"
part F pins: A7 VCCAUX (power), B11 VCCIO0 (power), C5 VCCIO0 (power), C7 VCC (power), D2 VCCIO3 (power), E12 VCCIO1 (power), G12 VCC (power), H3 VCC (power), K3 VCCIO3 (power), L12 VCCIO1 (power), M10 VCCIO2 (power), N2 VCCIO2 (power), P6 VCC (power), P7 VCCAUX (power)
part G pins: A10 GNDIO0 (power), B4 GNDIO0 (power), C9 GND (power), D13 GNDIO1 (power), E1 GNDIO3 (power), F1 GND (power), J14 GND (power), L2 GNDIO3 (power), L13 GNDIO1 (power), N11 GNDIO2 (power), P2 GNDIO2 (power), P9 GND (power)

## LCMXO640C-5M132CES
designator U?
MachXO 640 Crossover PLD, 1.8V/2.5V/3.3V, 101 User I/Os, 132-Pins csBGA, Speed Grade-5, Commercial Grade, Engineering Sample
footprint csBGA132 (BGA, 132-Leads, Body 8x8mm, Pitch 0.5mm)
3D model MachXO640-csBGA132 (132-Ball Chip Scale Ball Grid Array (csBGA132))
signal-integrity model LCMXO640C_M132 (MachXO)
part A pins: A1 PT2A (io), A2 PT2C (io), A3 PT2D (io), A4 PT3B (io), A5 PT3D (io), A6 PT4D (io), A8 PT6B/PCLK0_1 (io), A9 PT7A (io), A11 PT9A (io), A12 PT9E (io), A13 PT9F (io), B3 PT2B (io), B5 PT3E (io), B6 PT4C (io), B7 PT5A (io), B8 PT6A (io), B9 PT7B (io), B10 PT7F (io), B12 PT9C (io), B13 PT9D (io), C4 PT2F (io), C6 PT3F (io), C8 PT5B/PCLK0_0 (io), C10 PT7E (io), C11 PT8C (io), C12 PT9B (io)
part B pins: A14 PR2A (io), B14 PR2C (io), C13 PR2B (io), C14 PR2D (io), D12 PR3C (io), D14 PR3D (io), E13 PR4C (io), E14 PR4B (io), F12 PR4D (io), F13 PR5C (io), F14 PR5D (io), G13 PR6C (io), G14 PR6B (io), H12 PR6D (io), H13 PR7A (io), H14 PR7B (io), J12 PR7C (io), J13 PR8A (io), K12 PR8B (io), K13 PR8C (io), K14 PR8D (io), L14 PR10A (io), M12 PR11A (io), M13 PR10B (io), M14 PR11C (io), N13 PR11B (io), N14 PR11D (io)
part C pins: M3 PB2C (io), M4 PB3B (io), M6 PB4F (io), M7 PB5B/PCLK2_1 (io), M8 PB6B/PCLK2_0 (io), M9 PB7B (io), M11 PB8D (io), N3 PB2D (io), N4 PB3C (io), N6 PB4E (io), N7 PB5A (io), N8 PB5D (io), N9 PB7A (io), N10 PB7E (io), P5 PB3D (io), P8 PB6A (io), P10 PB7F (io), P11 PB8C (io), P12 PB9C (io), P13 PB9D (io), P14 PB9F (io)
part D pins: B1 PL2A (io), B2 PL2C (io), C1 PL2B (io), C2 PL2D (io), C3 PL3A (io), D1 PL3B (io), D3 PL3D (io), E2 PL5A (io), E3 PL5B/GSRN (io), F2 PL5D (io), F3 PL6B (io), G1 PL6C (io), G2 PL6D (io), G3 PL7A (io), H1 PL7C (io), H2 PL7B (io), J1 PL8A (io), J2 PL8C/TSALL (io), J3 PL9A (io), K1 PL9C (io), K2 PL9B (io), L1 PL10A (io), L3 PL10B (io), M1 PL11A (io), M2 PL11C (io), N1 PL11B (io), P1 PL11D (io)
part E pins: M5 TDI (in) "Powered by VCCIO2", N5 TDO (out) "Powered by VCCIO2", N12 SLEEPN (in) "Powered by VCCIO2", P3 TMS (in) "Powered by VCCIO2", P4 TCK (in) "Powered by VCCIO2"
part F pins: A7 VCCAUX (power), B11 VCCIO0 (power), C5 VCCIO0 (power), C7 VCC (power), D2 VCCIO3 (power), E12 VCCIO1 (power), G12 VCC (power), H3 VCC (power), K3 VCCIO3 (power), L12 VCCIO1 (power), M10 VCCIO2 (power), N2 VCCIO2 (power), P6 VCC (power), P7 VCCAUX (power)
part G pins: A10 GNDIO0 (power), B4 GNDIO0 (power), C9 GND (power), D13 GNDIO1 (power), E1 GNDIO3 (power), F1 GND (power), J14 GND (power), L2 GNDIO3 (power), L13 GNDIO1 (power), N11 GNDIO2 (power), P2 GNDIO2 (power), P9 GND (power)


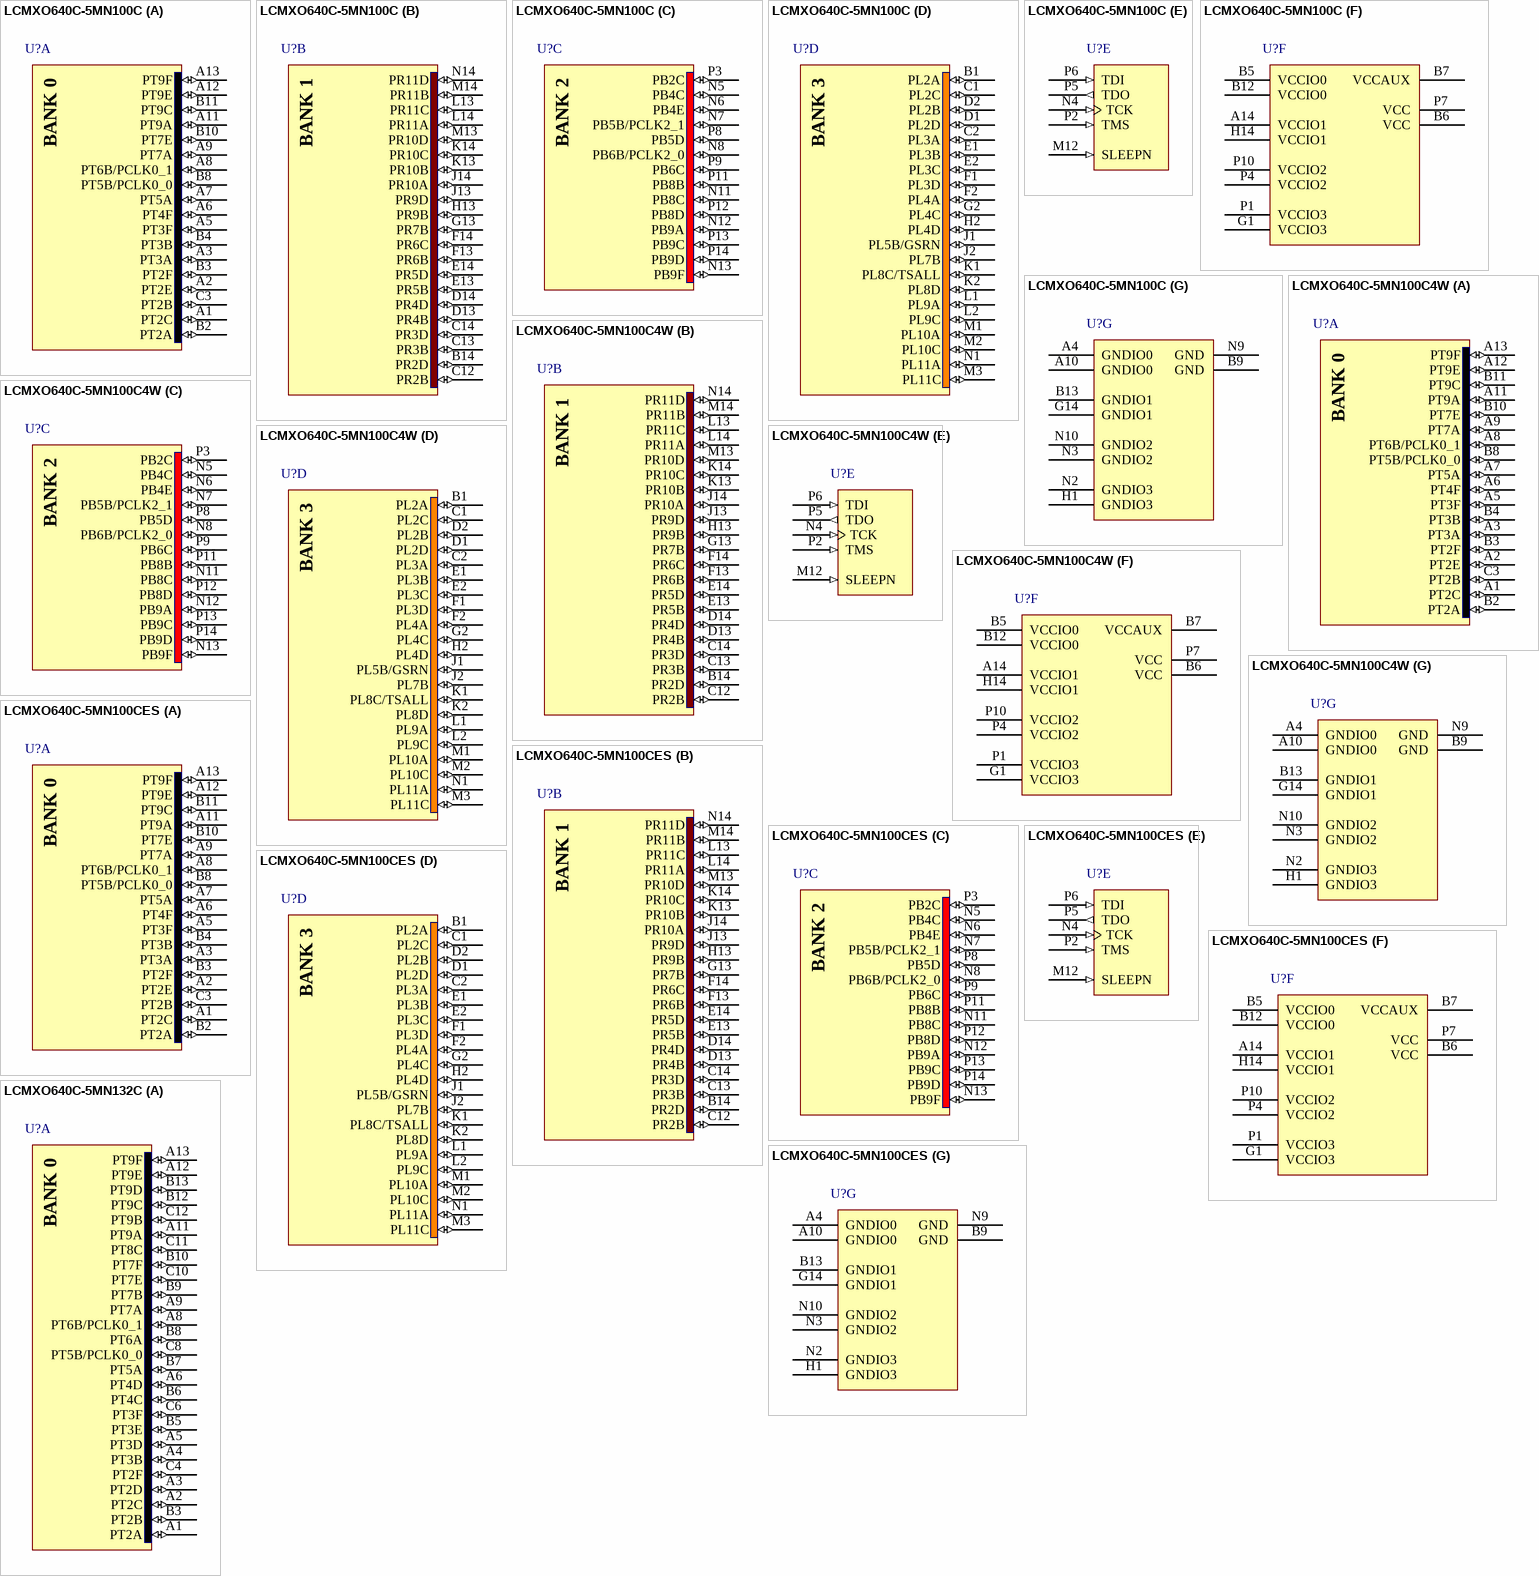
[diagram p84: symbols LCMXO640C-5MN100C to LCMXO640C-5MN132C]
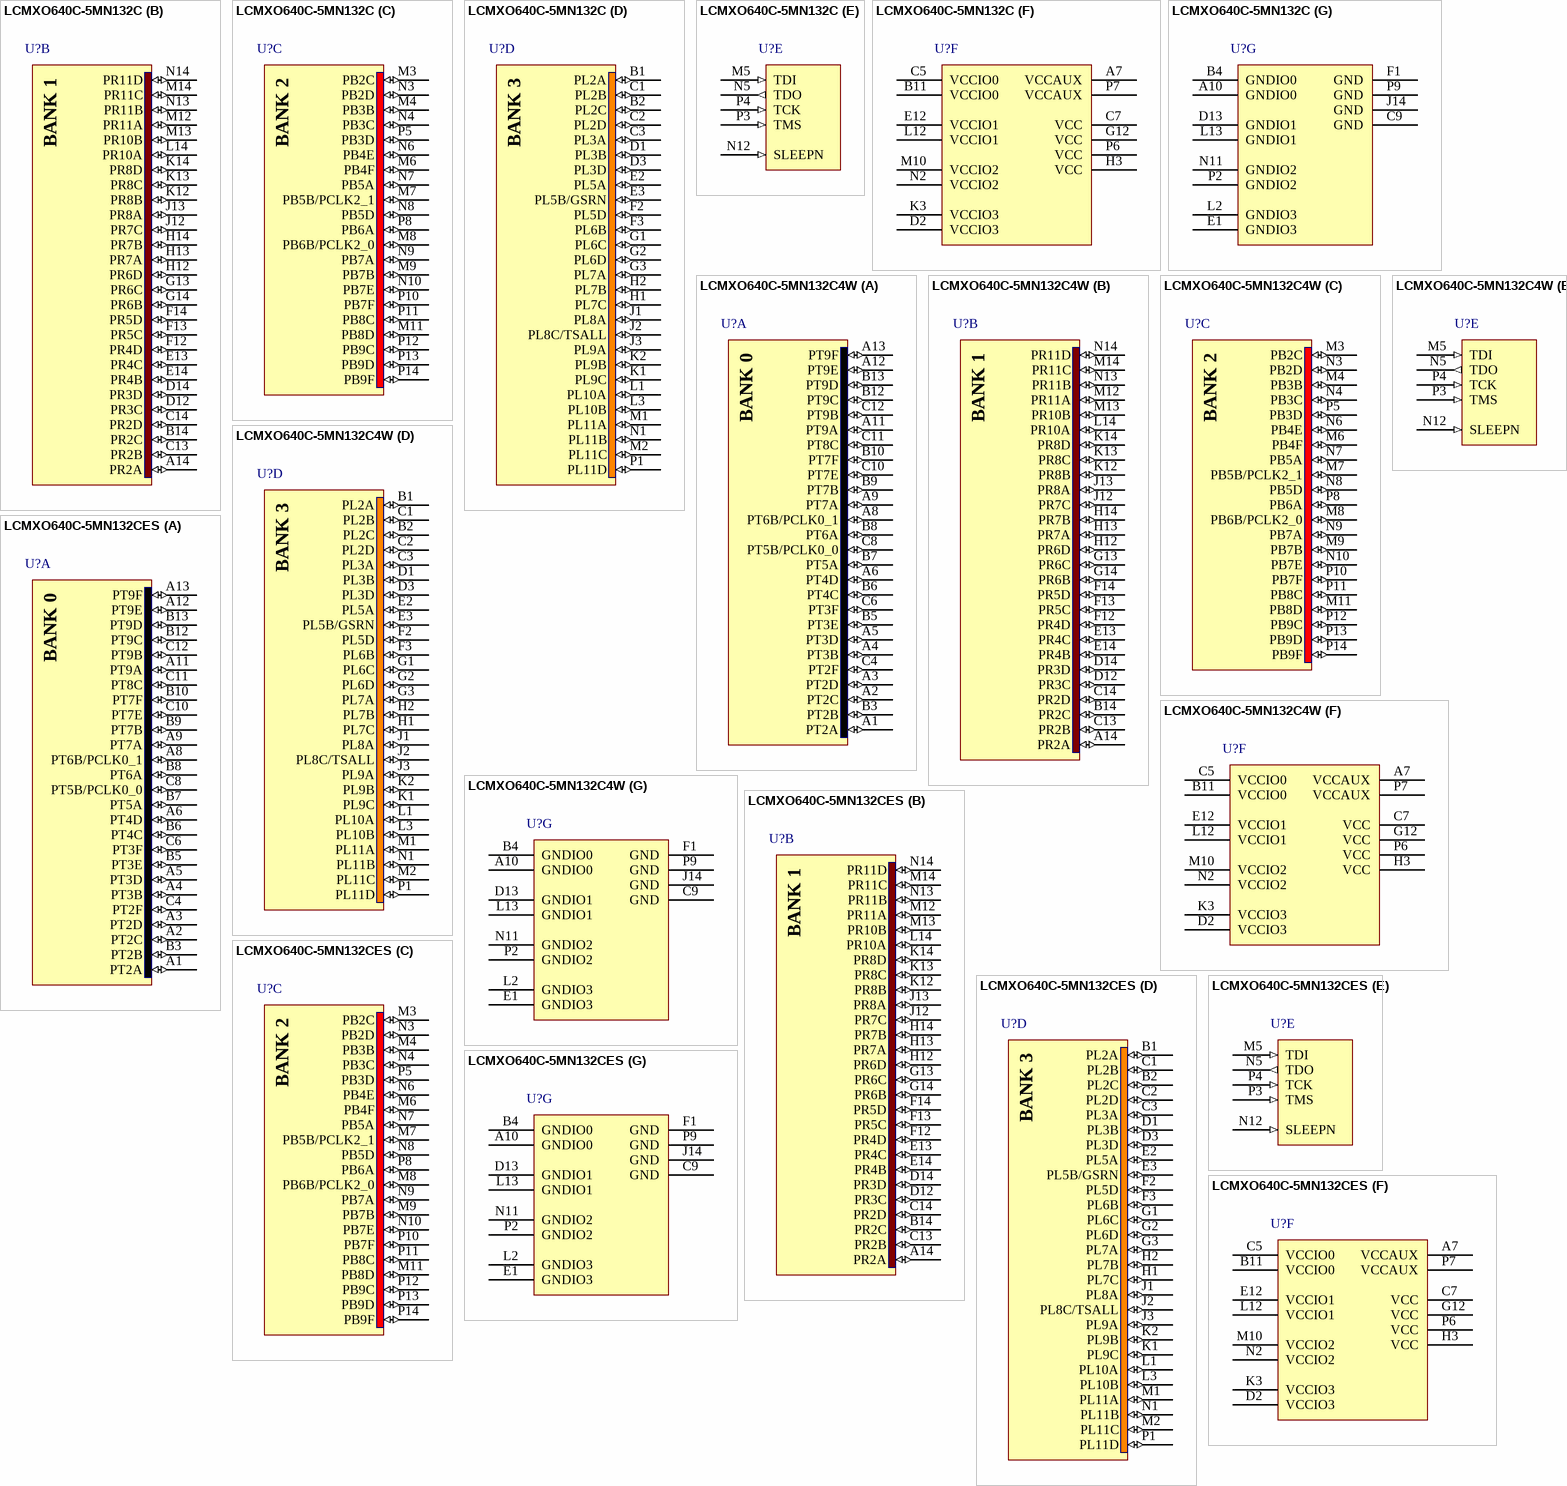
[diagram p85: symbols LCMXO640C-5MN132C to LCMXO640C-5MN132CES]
## LCMXO640C-5MN100C
designator U?
MachXO 640 Crossover PLD, 1.8V/2.5V/3.3V, 74 User I/Os, 100-Pins csBGA, Speed Grade-5, Commercial Grade, Pb-Free
footprint csBGA100 (BGA, 100-Leads, Body 8x8mm, Pitch 0.5mm)
3D model MachXO640-csBGA100 (100-Ball Chip Scale Ball Grid Array (csBGA100))
signal-integrity model LCMXO640C_M100 (MachXO)
part A pins: A1 PT2C (io), A2 PT2E (io), A3 PT3A (io), A5 PT3F (io), A6 PT4F (io), A7 PT5A (io), A8 PT6B/PCLK0_1 (io), A9 PT7A (io), A11 PT9A (io), A12 PT9E (io), A13 PT9F (io), B2 PT2A (io), B3 PT2F (io), B4 PT3B (io), B8 PT5B/PCLK0_0 (io), B10 PT7E (io), B11 PT9C (io), C3 PT2B (io)
part B pins: B14 PR2D (io), C12 PR2B (io), C13 PR3B (io), C14 PR3D (io), D13 PR4B (io), D14 PR4D (io), E13 PR5B (io), E14 PR5D (io), F13 PR6B (io), F14 PR6C (io), G13 PR7B (io), H13 PR9B (io), J13 PR9D (io), J14 PR10A (io), K13 PR10B (io), K14 PR10C (io), L13 PR11C (io), L14 PR11A (io), M13 PR10D (io), M14 PR11B (io), N14 PR11D (io)
part C pins: N5 PB4C (io), N6 PB4E (io), N7 PB5B/PCLK2_1 (io), N8 PB6B/PCLK2_0 (io), N11 PB8C (io), N12 PB9A (io), N13 PB9F (io), P3 PB2C (io), P8 PB5D (io), P9 PB6C (io), P11 PB8B (io), P12 PB8D (io), P13 PB9C (io), P14 PB9D (io)
part D pins: B1 PL2A (io), C1 PL2C (io), C2 PL3A (io), D1 PL2D (io), D2 PL2B (io), E1 PL3B (io), E2 PL3C (io), F1 PL3D (io), F2 PL4A (io), G2 PL4C (io), H2 PL4D (io), J1 PL5B/GSRN (io), J2 PL7B (io), K1 PL8C/TSALL (io), K2 PL8D (io), L1 PL9A (io), L2 PL9C (io), M1 PL10A (io), M2 PL10C (io), M3 PL11C (io), N1 PL11A (io)
part E pins: M12 SLEEPN (in) "Powered by VCCIO2", N4 TCK (in) "Powered by VCCIO2", P2 TMS (in) "Powered by VCCIO2", P5 TDO (out) "Powered by VCCIO2", P6 TDI (in) "Powered by VCCIO2"
part F pins: A14 VCCIO1 (power), B5 VCCIO0 (power), B6 VCC (power), B7 VCCAUX (power), B12 VCCIO0 (power), G1 VCCIO3 (power), H14 VCCIO1 (power), P1 VCCIO3 (power), P4 VCCIO2 (power), P7 VCC (power), P10 VCCIO2 (power)
part G pins: A4 GNDIO0 (power), A10 GNDIO0 (power), B9 GND (power), B13 GNDIO1 (power), G14 GNDIO1 (power), H1 GNDIO3 (power), N2 GNDIO3 (power), N3 GNDIO2 (power), N9 GND (power), N10 GNDIO2 (power)

## LCMXO640C-5MN100C4W
designator U?
MachXO 640 Crossover PLD, 1.8V/2.5V/3.3V, 74 User I/Os, 100-Pins csBGA, Speed Grade-5, Commercial Grade, Pb-Free
footprint csBGA100 (BGA, 100-Leads, Body 8x8mm, Pitch 0.5mm)
3D model MachXO640-csBGA100 (100-Ball Chip Scale Ball Grid Array (csBGA100))
signal-integrity model LCMXO640C_M100 (MachXO)
part A pins: A1 PT2C (io), A2 PT2E (io), A3 PT3A (io), A5 PT3F (io), A6 PT4F (io), A7 PT5A (io), A8 PT6B/PCLK0_1 (io), A9 PT7A (io), A11 PT9A (io), A12 PT9E (io), A13 PT9F (io), B2 PT2A (io), B3 PT2F (io), B4 PT3B (io), B8 PT5B/PCLK0_0 (io), B10 PT7E (io), B11 PT9C (io), C3 PT2B (io)
part B pins: B14 PR2D (io), C12 PR2B (io), C13 PR3B (io), C14 PR3D (io), D13 PR4B (io), D14 PR4D (io), E13 PR5B (io), E14 PR5D (io), F13 PR6B (io), F14 PR6C (io), G13 PR7B (io), H13 PR9B (io), J13 PR9D (io), J14 PR10A (io), K13 PR10B (io), K14 PR10C (io), L13 PR11C (io), L14 PR11A (io), M13 PR10D (io), M14 PR11B (io), N14 PR11D (io)
part C pins: N5 PB4C (io), N6 PB4E (io), N7 PB5B/PCLK2_1 (io), N8 PB6B/PCLK2_0 (io), N11 PB8C (io), N12 PB9A (io), N13 PB9F (io), P3 PB2C (io), P8 PB5D (io), P9 PB6C (io), P11 PB8B (io), P12 PB8D (io), P13 PB9C (io), P14 PB9D (io)
part D pins: B1 PL2A (io), C1 PL2C (io), C2 PL3A (io), D1 PL2D (io), D2 PL2B (io), E1 PL3B (io), E2 PL3C (io), F1 PL3D (io), F2 PL4A (io), G2 PL4C (io), H2 PL4D (io), J1 PL5B/GSRN (io), J2 PL7B (io), K1 PL8C/TSALL (io), K2 PL8D (io), L1 PL9A (io), L2 PL9C (io), M1 PL10A (io), M2 PL10C (io), M3 PL11C (io), N1 PL11A (io)
part E pins: M12 SLEEPN (in) "Powered by VCCIO2", N4 TCK (in) "Powered by VCCIO2", P2 TMS (in) "Powered by VCCIO2", P5 TDO (out) "Powered by VCCIO2", P6 TDI (in) "Powered by VCCIO2"
part F pins: A14 VCCIO1 (power), B5 VCCIO0 (power), B6 VCC (power), B7 VCCAUX (power), B12 VCCIO0 (power), G1 VCCIO3 (power), H14 VCCIO1 (power), P1 VCCIO3 (power), P4 VCCIO2 (power), P7 VCC (power), P10 VCCIO2 (power)
part G pins: A4 GNDIO0 (power), A10 GNDIO0 (power), B9 GND (power), B13 GNDIO1 (power), G14 GNDIO1 (power), H1 GNDIO3 (power), N2 GNDIO3 (power), N3 GNDIO2 (power), N9 GND (power), N10 GNDIO2 (power)

## LCMXO640C-5MN100CES
designator U?
MachXO 640 Crossover PLD, 1.8V/2.5V/3.3V, 74 User I/Os, 100-Pins csBGA, Speed Grade-5, Commercial Grade, Pb-Free, Engineering Sample
footprint csBGA100 (BGA, 100-Leads, Body 8x8mm, Pitch 0.5mm)
3D model MachXO640-csBGA100 (100-Ball Chip Scale Ball Grid Array (csBGA100))
signal-integrity model LCMXO640C_M100 (MachXO)
part A pins: A1 PT2C (io), A2 PT2E (io), A3 PT3A (io), A5 PT3F (io), A6 PT4F (io), A7 PT5A (io), A8 PT6B/PCLK0_1 (io), A9 PT7A (io), A11 PT9A (io), A12 PT9E (io), A13 PT9F (io), B2 PT2A (io), B3 PT2F (io), B4 PT3B (io), B8 PT5B/PCLK0_0 (io), B10 PT7E (io), B11 PT9C (io), C3 PT2B (io)
part B pins: B14 PR2D (io), C12 PR2B (io), C13 PR3B (io), C14 PR3D (io), D13 PR4B (io), D14 PR4D (io), E13 PR5B (io), E14 PR5D (io), F13 PR6B (io), F14 PR6C (io), G13 PR7B (io), H13 PR9B (io), J13 PR9D (io), J14 PR10A (io), K13 PR10B (io), K14 PR10C (io), L13 PR11C (io), L14 PR11A (io), M13 PR10D (io), M14 PR11B (io), N14 PR11D (io)
part C pins: N5 PB4C (io), N6 PB4E (io), N7 PB5B/PCLK2_1 (io), N8 PB6B/PCLK2_0 (io), N11 PB8C (io), N12 PB9A (io), N13 PB9F (io), P3 PB2C (io), P8 PB5D (io), P9 PB6C (io), P11 PB8B (io), P12 PB8D (io), P13 PB9C (io), P14 PB9D (io)
part D pins: B1 PL2A (io), C1 PL2C (io), C2 PL3A (io), D1 PL2D (io), D2 PL2B (io), E1 PL3B (io), E2 PL3C (io), F1 PL3D (io), F2 PL4A (io), G2 PL4C (io), H2 PL4D (io), J1 PL5B/GSRN (io), J2 PL7B (io), K1 PL8C/TSALL (io), K2 PL8D (io), L1 PL9A (io), L2 PL9C (io), M1 PL10A (io), M2 PL10C (io), M3 PL11C (io), N1 PL11A (io)
part E pins: M12 SLEEPN (in) "Powered by VCCIO2", N4 TCK (in) "Powered by VCCIO2", P2 TMS (in) "Powered by VCCIO2", P5 TDO (out) "Powered by VCCIO2", P6 TDI (in) "Powered by VCCIO2"
part F pins: A14 VCCIO1 (power), B5 VCCIO0 (power), B6 VCC (power), B7 VCCAUX (power), B12 VCCIO0 (power), G1 VCCIO3 (power), H14 VCCIO1 (power), P1 VCCIO3 (power), P4 VCCIO2 (power), P7 VCC (power), P10 VCCIO2 (power)
part G pins: A4 GNDIO0 (power), A10 GNDIO0 (power), B9 GND (power), B13 GNDIO1 (power), G14 GNDIO1 (power), H1 GNDIO3 (power), N2 GNDIO3 (power), N3 GNDIO2 (power), N9 GND (power), N10 GNDIO2 (power)

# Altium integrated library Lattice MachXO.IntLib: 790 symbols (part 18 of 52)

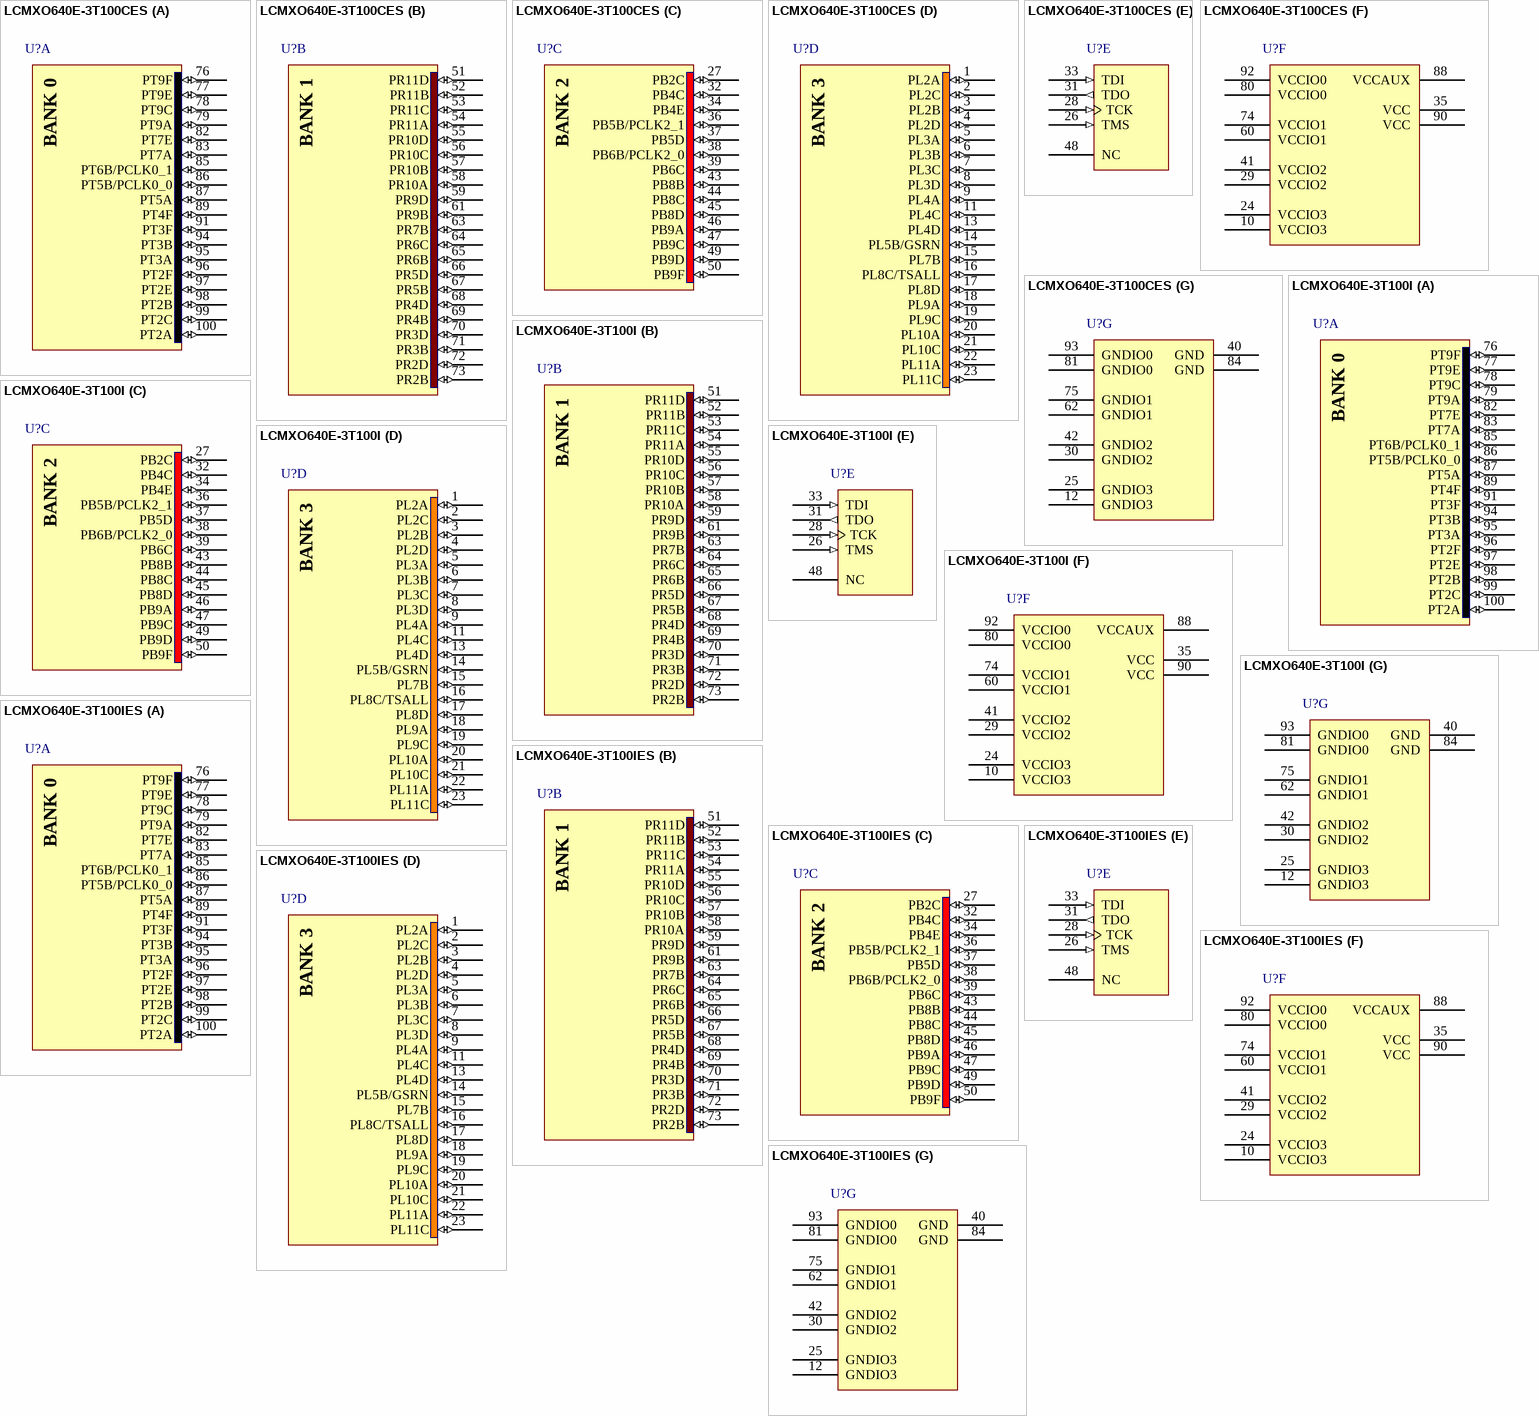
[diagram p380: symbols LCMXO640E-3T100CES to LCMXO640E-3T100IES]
## LCMXO640E-3T100I
designator U?
MachXO 640 Crossover PLD, 1.2V, 74 User I/Os, 100-Pins TQFP, Speed Grade-3, Industrial Grade
footprint TQFP100_N (Thin QFP, 100-Leads, Body 14x14mm, Pitch 0.5mm, IPC Medium Density)
footprint TQFP100_L (Thin QFP, 100-Leads, Body 14x14mm, Pitch 0.5mm, IPC High Density)
footprint TQFP100_M (Thin QFP, 100-Leads, Body 14x14mm, Pitch 0.5mm, IPC Low Density)
3D model MachXO640-TQFP100 (100-Pin Thin Quad Flat Pack (TQFP100))
signal-integrity model LCMXO640E_T100 (MachXO)
part A pins: 76 PT9F (io), 77 PT9E (io), 78 PT9C (io), 79 PT9A (io), 82 PT7E (io), 83 PT7A (io), 85 PT6B/PCLK0_1 (io), 86 PT5B/PCLK0_0 (io), 87 PT5A (io), 89 PT4F (io), 91 PT3F (io), 94 PT3B (io), 95 PT3A (io), 96 PT2F (io), 97 PT2E (io), 98 PT2B (io), 99 PT2C (io), 100 PT2A (io)
part B pins: 51 PR11D (io), 52 PR11B (io), 53 PR11C (io), 54 PR11A (io), 55 PR10D (io), 56 PR10C (io), 57 PR10B (io), 58 PR10A (io), 59 PR9D (io), 61 PR9B (io), 63 PR7B (io), 64 PR6C (io), 65 PR6B (io), 66 PR5D (io), 67 PR5B (io), 68 PR4D (io), 69 PR4B (io), 70 PR3D (io), 71 PR3B (io), 72 PR2D (io), 73 PR2B (io)
part C pins: 27 PB2C (io), 32 PB4C (io), 34 PB4E (io), 36 PB5B/PCLK2_1 (io), 37 PB5D (io), 38 PB6B/PCLK2_0 (io), 39 PB6C (io), 43 PB8B (io), 44 PB8C (io), 45 PB8D (io), 46 PB9A (io), 47 PB9C (io), 49 PB9D (io), 50 PB9F (io)
part D pins: 1 PL2A (io), 2 PL2C (io), 3 PL2B (io), 4 PL2D (io), 5 PL3A (io), 6 PL3B (io), 7 PL3C (io), 8 PL3D (io), 9 PL4A (io), 11 PL4C (io), 13 PL4D (io), 14 PL5B/GSRN (io), 15 PL7B (io), 16 PL8C/TSALL (io), 17 PL8D (io), 18 PL9A (io), 19 PL9C (io), 20 PL10A (io), 21 PL10C (io), 22 PL11A (io), 23 PL11C (io)
part E pins: 26 TMS (in) "Powered by VCCIO2", 28 TCK (in) "Powered by VCCIO2", 31 TDO (out) "Powered by VCCIO2", 33 TDI (in) "Powered by VCCIO2", 48 NC
part F pins: 10 VCCIO3 (power), 24 VCCIO3 (power), 29 VCCIO2 (power), 35 VCC (power), 41 VCCIO2 (power), 60 VCCIO1 (power), 74 VCCIO1 (power), 80 VCCIO0 (power), 88 VCCAUX (power), 90 VCC (power), 92 VCCIO0 (power)
part G pins: 12 GNDIO3 (power), 25 GNDIO3 (power), 30 GNDIO2 (power), 40 GND (power), 42 GNDIO2 (power), 62 GNDIO1 (power), 75 GNDIO1 (power), 81 GNDIO0 (power), 84 GND (power), 93 GNDIO0 (power)

## LCMXO640E-3T100IES
designator U?
MachXO 640 Crossover PLD, 1.2V, 74 User I/Os, 100-Pins TQFP, Speed Grade-3, Industrial Grade, Engineering Sample
footprint TQFP100_N (Thin QFP, 100-Leads, Body 14x14mm, Pitch 0.5mm, IPC Medium Density)
footprint TQFP100_L (Thin QFP, 100-Leads, Body 14x14mm, Pitch 0.5mm, IPC High Density)
footprint TQFP100_M (Thin QFP, 100-Leads, Body 14x14mm, Pitch 0.5mm, IPC Low Density)
3D model MachXO640-TQFP100 (100-Pin Thin Quad Flat Pack (TQFP100))
signal-integrity model LCMXO640E_T100 (MachXO)
part A pins: 76 PT9F (io), 77 PT9E (io), 78 PT9C (io), 79 PT9A (io), 82 PT7E (io), 83 PT7A (io), 85 PT6B/PCLK0_1 (io), 86 PT5B/PCLK0_0 (io), 87 PT5A (io), 89 PT4F (io), 91 PT3F (io), 94 PT3B (io), 95 PT3A (io), 96 PT2F (io), 97 PT2E (io), 98 PT2B (io), 99 PT2C (io), 100 PT2A (io)
part B pins: 51 PR11D (io), 52 PR11B (io), 53 PR11C (io), 54 PR11A (io), 55 PR10D (io), 56 PR10C (io), 57 PR10B (io), 58 PR10A (io), 59 PR9D (io), 61 PR9B (io), 63 PR7B (io), 64 PR6C (io), 65 PR6B (io), 66 PR5D (io), 67 PR5B (io), 68 PR4D (io), 69 PR4B (io), 70 PR3D (io), 71 PR3B (io), 72 PR2D (io), 73 PR2B (io)
part C pins: 27 PB2C (io), 32 PB4C (io), 34 PB4E (io), 36 PB5B/PCLK2_1 (io), 37 PB5D (io), 38 PB6B/PCLK2_0 (io), 39 PB6C (io), 43 PB8B (io), 44 PB8C (io), 45 PB8D (io), 46 PB9A (io), 47 PB9C (io), 49 PB9D (io), 50 PB9F (io)
part D pins: 1 PL2A (io), 2 PL2C (io), 3 PL2B (io), 4 PL2D (io), 5 PL3A (io), 6 PL3B (io), 7 PL3C (io), 8 PL3D (io), 9 PL4A (io), 11 PL4C (io), 13 PL4D (io), 14 PL5B/GSRN (io), 15 PL7B (io), 16 PL8C/TSALL (io), 17 PL8D (io), 18 PL9A (io), 19 PL9C (io), 20 PL10A (io), 21 PL10C (io), 22 PL11A (io), 23 PL11C (io)
part E pins: 26 TMS (in) "Powered by VCCIO2", 28 TCK (in) "Powered by VCCIO2", 31 TDO (out) "Powered by VCCIO2", 33 TDI (in) "Powered by VCCIO2", 48 NC
part F pins: 10 VCCIO3 (power), 24 VCCIO3 (power), 29 VCCIO2 (power), 35 VCC (power), 41 VCCIO2 (power), 60 VCCIO1 (power), 74 VCCIO1 (power), 80 VCCIO0 (power), 88 VCCAUX (power), 90 VCC (power), 92 VCCIO0 (power)
part G pins: 12 GNDIO3 (power), 25 GNDIO3 (power), 30 GNDIO2 (power), 40 GND (power), 42 GNDIO2 (power), 62 GNDIO1 (power), 75 GNDIO1 (power), 81 GNDIO0 (power), 84 GND (power), 93 GNDIO0 (power)


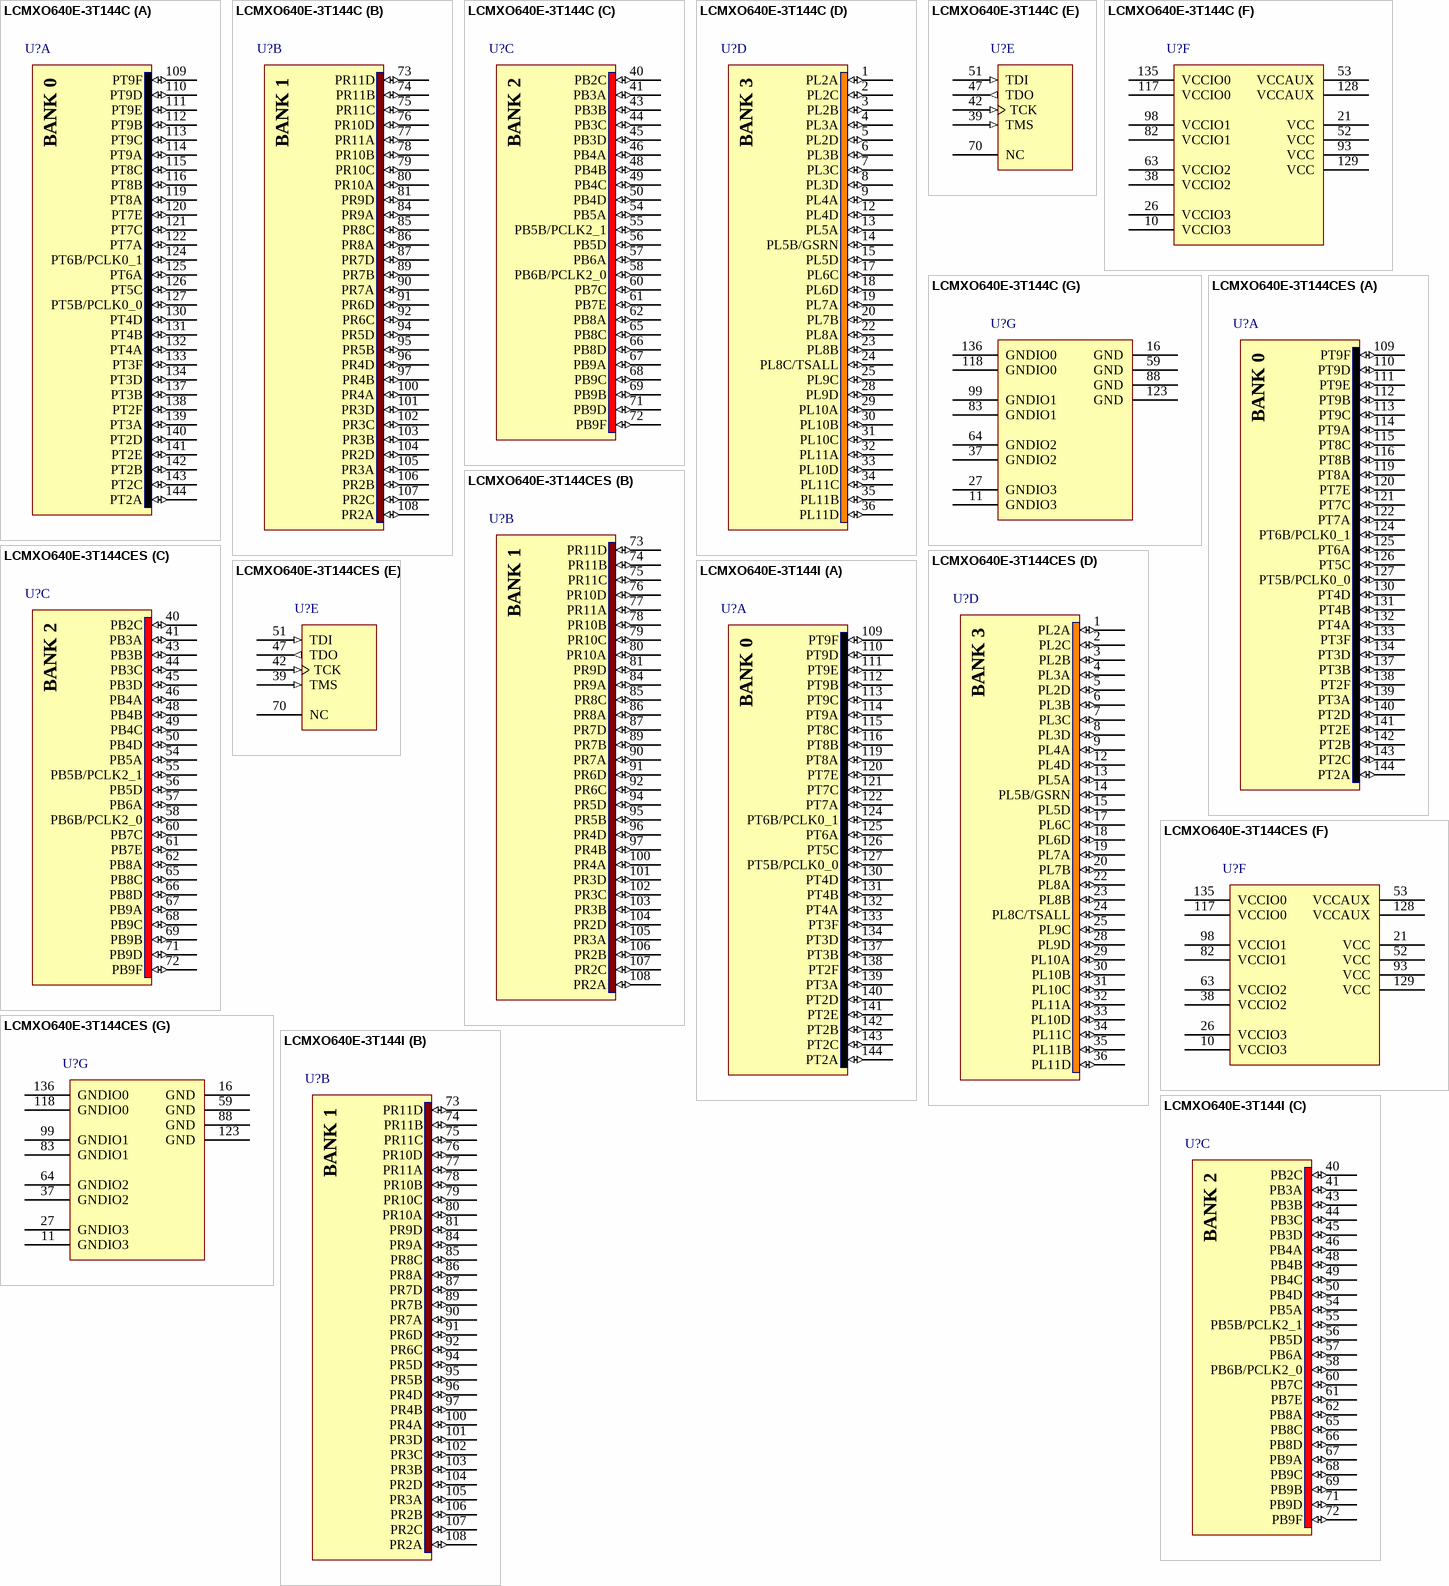
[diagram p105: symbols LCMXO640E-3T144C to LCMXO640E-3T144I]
## LCMXO640E-3T144C
designator U?
MachXO 640 Crossover PLD, 1.2V, 113 User I/Os, 144-Pins TQFP, Speed Grade-3, Commercial Grade
footprint TQFP144_N (Thin QFP, 144-Leads, Body 20x20mm, Pitch 0.5mm, IPC Medium Density)
footprint TQFP144_L (Thin QFP, 144-Leads, Body 20x20mm, Pitch 0.5mm, IPC High Density)
footprint TQFP144_M (Thin QFP, 144-Leads, Body 20x20mm, Pitch 0.5mm, IPC Low Density)
3D model MachXO640-TQFP144 (144-Pin Thin Quad Flat Pack (TQFP144))
signal-integrity model LCMXO640E_T144 (MachXO)
part A pins: 109 PT9F (io), 110 PT9D (io), 111 PT9E (io), 112 PT9B (io), 113 PT9C (io), 114 PT9A (io), 115 PT8C (io), 116 PT8B (io), 119 PT8A (io), 120 PT7E (io), 121 PT7C (io), 122 PT7A (io), 124 PT6B/PCLK0_1 (io), 125 PT6A (io), 126 PT5C (io), 127 PT5B/PCLK0_0 (io), 130 PT4D (io), 131 PT4B (io), 132 PT4A (io), 133 PT3F (io), 134 PT3D (io), 137 PT3B (io), 138 PT2F (io), 139 PT3A (io), 140 PT2D (io), 141 PT2E (io), 142 PT2B (io), 143 PT2C (io), 144 PT2A (io)
part B pins: 73 PR11D (io), 74 PR11B (io), 75 PR11C (io), 76 PR10D (io), 77 PR11A (io), 78 PR10B (io), 79 PR10C (io), 80 PR10A (io), 81 PR9D (io), 84 PR9A (io), 85 PR8C (io), 86 PR8A (io), 87 PR7D (io), 89 PR7B (io), 90 PR7A (io), 91 PR6D (io), 92 PR6C (io), 94 PR5D (io), 95 PR5B (io), 96 PR4D (io), 97 PR4B (io), 100 PR4A (io), 101 PR3D (io), 102 PR3C (io), 103 PR3B (io), 104 PR2D (io), 105 PR3A (io), 106 PR2B (io), 107 PR2C (io), 108 PR2A (io)
part C pins: 40 PB2C (io), 41 PB3A (io), 43 PB3B (io), 44 PB3C (io), 45 PB3D (io), 46 PB4A (io), 48 PB4B (io), 49 PB4C (io), 50 PB4D (io), 54 PB5A (io), 55 PB5B/PCLK2_1 (io), 56 PB5D (io), 57 PB6A (io), 58 PB6B/PCLK2_0 (io), 60 PB7C (io), 61 PB7E (io), 62 PB8A (io), 65 PB8C (io), 66 PB8D (io), 67 PB9A (io), 68 PB9C (io), 69 PB9B (io), 71 PB9D (io), 72 PB9F (io)
part D pins: 1 PL2A (io), 2 PL2C (io), 3 PL2B (io), 4 PL3A (io), 5 PL2D (io), 6 PL3B (io), 7 PL3C (io), 8 PL3D (io), 9 PL4A (io), 12 PL4D (io), 13 PL5A (io), 14 PL5B/GSRN (io), 15 PL5D (io), 17 PL6C (io), 18 PL6D (io), 19 PL7A (io), 20 PL7B (io), 22 PL8A (io), 23 PL8B (io), 24 PL8C/TSALL (io), 25 PL9C (io), 28 PL9D (io), 29 PL10A (io), 30 PL10B (io), 31 PL10C (io), 32 PL11A (io), 33 PL10D (io), 34 PL11C (io), 35 PL11B (io), 36 PL11D (io)
part E pins: 39 TMS (in) "Powered by VCCIO2", 42 TCK (in) "Powered by VCCIO2", 47 TDO (out) "Powered by VCCIO2", 51 TDI (in) "Powered by VCCIO2", 70 NC
part F pins: 10 VCCIO3 (power), 21 VCC (power), 26 VCCIO3 (power), 38 VCCIO2 (power), 52 VCC (power), 53 VCCAUX (power), 63 VCCIO2 (power), 82 VCCIO1 (power), 93 VCC (power), 98 VCCIO1 (power), 117 VCCIO0 (power), 128 VCCAUX (power), 129 VCC (power), 135 VCCIO0 (power)
part G pins: 11 GNDIO3 (power), 16 GND (power), 27 GNDIO3 (power), 37 GNDIO2 (power), 59 GND (power), 64 GNDIO2 (power), 83 GNDIO1 (power), 88 GND (power), 99 GNDIO1 (power), 118 GNDIO0 (power), 123 GND (power), 136 GNDIO0 (power)

## LCMXO640E-3T144CES
designator U?
MachXO 640 Crossover PLD, 1.2V, 113 User I/Os, 144-Pins TQFP, Speed Grade-3, Commercial Grade, Engineering Sample
footprint TQFP144_N (Thin QFP, 144-Leads, Body 20x20mm, Pitch 0.5mm, IPC Medium Density)
footprint TQFP144_L (Thin QFP, 144-Leads, Body 20x20mm, Pitch 0.5mm, IPC High Density)
footprint TQFP144_M (Thin QFP, 144-Leads, Body 20x20mm, Pitch 0.5mm, IPC Low Density)
3D model MachXO640-TQFP144 (144-Pin Thin Quad Flat Pack (TQFP144))
signal-integrity model LCMXO640E_T144 (MachXO)
part A pins: 109 PT9F (io), 110 PT9D (io), 111 PT9E (io), 112 PT9B (io), 113 PT9C (io), 114 PT9A (io), 115 PT8C (io), 116 PT8B (io), 119 PT8A (io), 120 PT7E (io), 121 PT7C (io), 122 PT7A (io), 124 PT6B/PCLK0_1 (io), 125 PT6A (io), 126 PT5C (io), 127 PT5B/PCLK0_0 (io), 130 PT4D (io), 131 PT4B (io), 132 PT4A (io), 133 PT3F (io), 134 PT3D (io), 137 PT3B (io), 138 PT2F (io), 139 PT3A (io), 140 PT2D (io), 141 PT2E (io), 142 PT2B (io), 143 PT2C (io), 144 PT2A (io)
part B pins: 73 PR11D (io), 74 PR11B (io), 75 PR11C (io), 76 PR10D (io), 77 PR11A (io), 78 PR10B (io), 79 PR10C (io), 80 PR10A (io), 81 PR9D (io), 84 PR9A (io), 85 PR8C (io), 86 PR8A (io), 87 PR7D (io), 89 PR7B (io), 90 PR7A (io), 91 PR6D (io), 92 PR6C (io), 94 PR5D (io), 95 PR5B (io), 96 PR4D (io), 97 PR4B (io), 100 PR4A (io), 101 PR3D (io), 102 PR3C (io), 103 PR3B (io), 104 PR2D (io), 105 PR3A (io), 106 PR2B (io), 107 PR2C (io), 108 PR2A (io)
part C pins: 40 PB2C (io), 41 PB3A (io), 43 PB3B (io), 44 PB3C (io), 45 PB3D (io), 46 PB4A (io), 48 PB4B (io), 49 PB4C (io), 50 PB4D (io), 54 PB5A (io), 55 PB5B/PCLK2_1 (io), 56 PB5D (io), 57 PB6A (io), 58 PB6B/PCLK2_0 (io), 60 PB7C (io), 61 PB7E (io), 62 PB8A (io), 65 PB8C (io), 66 PB8D (io), 67 PB9A (io), 68 PB9C (io), 69 PB9B (io), 71 PB9D (io), 72 PB9F (io)
part D pins: 1 PL2A (io), 2 PL2C (io), 3 PL2B (io), 4 PL3A (io), 5 PL2D (io), 6 PL3B (io), 7 PL3C (io), 8 PL3D (io), 9 PL4A (io), 12 PL4D (io), 13 PL5A (io), 14 PL5B/GSRN (io), 15 PL5D (io), 17 PL6C (io), 18 PL6D (io), 19 PL7A (io), 20 PL7B (io), 22 PL8A (io), 23 PL8B (io), 24 PL8C/TSALL (io), 25 PL9C (io), 28 PL9D (io), 29 PL10A (io), 30 PL10B (io), 31 PL10C (io), 32 PL11A (io), 33 PL10D (io), 34 PL11C (io), 35 PL11B (io), 36 PL11D (io)
part E pins: 39 TMS (in) "Powered by VCCIO2", 42 TCK (in) "Powered by VCCIO2", 47 TDO (out) "Powered by VCCIO2", 51 TDI (in) "Powered by VCCIO2", 70 NC
part F pins: 10 VCCIO3 (power), 21 VCC (power), 26 VCCIO3 (power), 38 VCCIO2 (power), 52 VCC (power), 53 VCCAUX (power), 63 VCCIO2 (power), 82 VCCIO1 (power), 93 VCC (power), 98 VCCIO1 (power), 117 VCCIO0 (power), 128 VCCAUX (power), 129 VCC (power), 135 VCCIO0 (power)
part G pins: 11 GNDIO3 (power), 16 GND (power), 27 GNDIO3 (power), 37 GNDIO2 (power), 59 GND (power), 64 GNDIO2 (power), 83 GNDIO1 (power), 88 GND (power), 99 GNDIO1 (power), 118 GNDIO0 (power), 123 GND (power), 136 GNDIO0 (power)


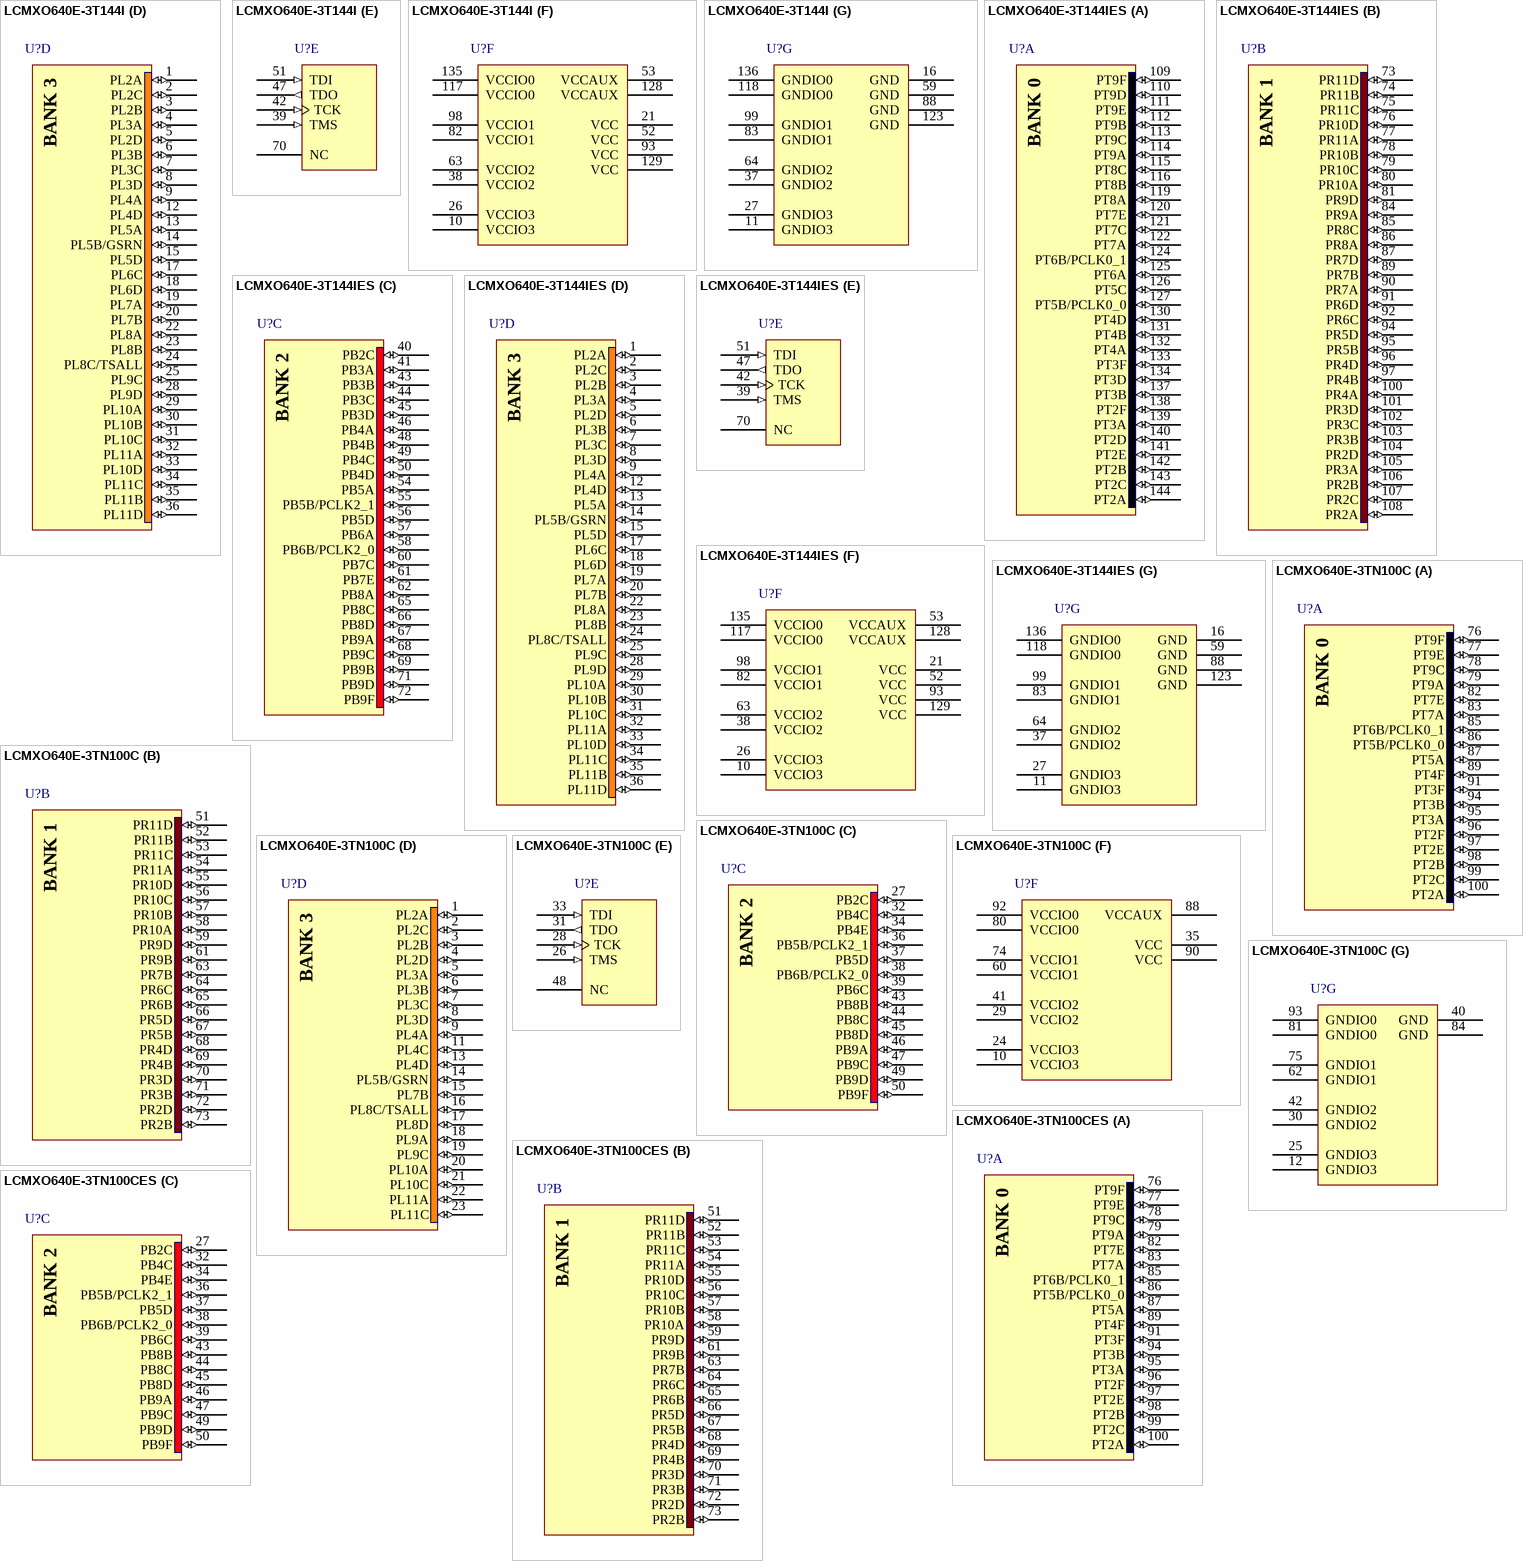
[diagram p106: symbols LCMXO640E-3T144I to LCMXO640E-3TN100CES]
## LCMXO640E-3T144I
designator U?
MachXO 640 Crossover PLD, 1.2V, 113 User I/Os, 144-Pins TQFP, Speed Grade-3, Industrial Grade
footprint TQFP144_N (Thin QFP, 144-Leads, Body 20x20mm, Pitch 0.5mm, IPC Medium Density)
footprint TQFP144_L (Thin QFP, 144-Leads, Body 20x20mm, Pitch 0.5mm, IPC High Density)
footprint TQFP144_M (Thin QFP, 144-Leads, Body 20x20mm, Pitch 0.5mm, IPC Low Density)
3D model MachXO640-TQFP144 (144-Pin Thin Quad Flat Pack (TQFP144))
signal-integrity model LCMXO640E_T144 (MachXO)
part A pins: 109 PT9F (io), 110 PT9D (io), 111 PT9E (io), 112 PT9B (io), 113 PT9C (io), 114 PT9A (io), 115 PT8C (io), 116 PT8B (io), 119 PT8A (io), 120 PT7E (io), 121 PT7C (io), 122 PT7A (io), 124 PT6B/PCLK0_1 (io), 125 PT6A (io), 126 PT5C (io), 127 PT5B/PCLK0_0 (io), 130 PT4D (io), 131 PT4B (io), 132 PT4A (io), 133 PT3F (io), 134 PT3D (io), 137 PT3B (io), 138 PT2F (io), 139 PT3A (io), 140 PT2D (io), 141 PT2E (io), 142 PT2B (io), 143 PT2C (io), 144 PT2A (io)
part B pins: 73 PR11D (io), 74 PR11B (io), 75 PR11C (io), 76 PR10D (io), 77 PR11A (io), 78 PR10B (io), 79 PR10C (io), 80 PR10A (io), 81 PR9D (io), 84 PR9A (io), 85 PR8C (io), 86 PR8A (io), 87 PR7D (io), 89 PR7B (io), 90 PR7A (io), 91 PR6D (io), 92 PR6C (io), 94 PR5D (io), 95 PR5B (io), 96 PR4D (io), 97 PR4B (io), 100 PR4A (io), 101 PR3D (io), 102 PR3C (io), 103 PR3B (io), 104 PR2D (io), 105 PR3A (io), 106 PR2B (io), 107 PR2C (io), 108 PR2A (io)
part C pins: 40 PB2C (io), 41 PB3A (io), 43 PB3B (io), 44 PB3C (io), 45 PB3D (io), 46 PB4A (io), 48 PB4B (io), 49 PB4C (io), 50 PB4D (io), 54 PB5A (io), 55 PB5B/PCLK2_1 (io), 56 PB5D (io), 57 PB6A (io), 58 PB6B/PCLK2_0 (io), 60 PB7C (io), 61 PB7E (io), 62 PB8A (io), 65 PB8C (io), 66 PB8D (io), 67 PB9A (io), 68 PB9C (io), 69 PB9B (io), 71 PB9D (io), 72 PB9F (io)
part D pins: 1 PL2A (io), 2 PL2C (io), 3 PL2B (io), 4 PL3A (io), 5 PL2D (io), 6 PL3B (io), 7 PL3C (io), 8 PL3D (io), 9 PL4A (io), 12 PL4D (io), 13 PL5A (io), 14 PL5B/GSRN (io), 15 PL5D (io), 17 PL6C (io), 18 PL6D (io), 19 PL7A (io), 20 PL7B (io), 22 PL8A (io), 23 PL8B (io), 24 PL8C/TSALL (io), 25 PL9C (io), 28 PL9D (io), 29 PL10A (io), 30 PL10B (io), 31 PL10C (io), 32 PL11A (io), 33 PL10D (io), 34 PL11C (io), 35 PL11B (io), 36 PL11D (io)
part E pins: 39 TMS (in) "Powered by VCCIO2", 42 TCK (in) "Powered by VCCIO2", 47 TDO (out) "Powered by VCCIO2", 51 TDI (in) "Powered by VCCIO2", 70 NC
part F pins: 10 VCCIO3 (power), 21 VCC (power), 26 VCCIO3 (power), 38 VCCIO2 (power), 52 VCC (power), 53 VCCAUX (power), 63 VCCIO2 (power), 82 VCCIO1 (power), 93 VCC (power), 98 VCCIO1 (power), 117 VCCIO0 (power), 128 VCCAUX (power), 129 VCC (power), 135 VCCIO0 (power)
part G pins: 11 GNDIO3 (power), 16 GND (power), 27 GNDIO3 (power), 37 GNDIO2 (power), 59 GND (power), 64 GNDIO2 (power), 83 GNDIO1 (power), 88 GND (power), 99 GNDIO1 (power), 118 GNDIO0 (power), 123 GND (power), 136 GNDIO0 (power)

## LCMXO640E-3T144IES
designator U?
MachXO 640 Crossover PLD, 1.2V, 113 User I/Os, 144-Pins TQFP, Speed Grade-3, Industrial Grade, Engineering Sample
footprint TQFP144_N (Thin QFP, 144-Leads, Body 20x20mm, Pitch 0.5mm, IPC Medium Density)
footprint TQFP144_L (Thin QFP, 144-Leads, Body 20x20mm, Pitch 0.5mm, IPC High Density)
footprint TQFP144_M (Thin QFP, 144-Leads, Body 20x20mm, Pitch 0.5mm, IPC Low Density)
3D model MachXO640-TQFP144 (144-Pin Thin Quad Flat Pack (TQFP144))
signal-integrity model LCMXO640E_T144 (MachXO)
part A pins: 109 PT9F (io), 110 PT9D (io), 111 PT9E (io), 112 PT9B (io), 113 PT9C (io), 114 PT9A (io), 115 PT8C (io), 116 PT8B (io), 119 PT8A (io), 120 PT7E (io), 121 PT7C (io), 122 PT7A (io), 124 PT6B/PCLK0_1 (io), 125 PT6A (io), 126 PT5C (io), 127 PT5B/PCLK0_0 (io), 130 PT4D (io), 131 PT4B (io), 132 PT4A (io), 133 PT3F (io), 134 PT3D (io), 137 PT3B (io), 138 PT2F (io), 139 PT3A (io), 140 PT2D (io), 141 PT2E (io), 142 PT2B (io), 143 PT2C (io), 144 PT2A (io)
part B pins: 73 PR11D (io), 74 PR11B (io), 75 PR11C (io), 76 PR10D (io), 77 PR11A (io), 78 PR10B (io), 79 PR10C (io), 80 PR10A (io), 81 PR9D (io), 84 PR9A (io), 85 PR8C (io), 86 PR8A (io), 87 PR7D (io), 89 PR7B (io), 90 PR7A (io), 91 PR6D (io), 92 PR6C (io), 94 PR5D (io), 95 PR5B (io), 96 PR4D (io), 97 PR4B (io), 100 PR4A (io), 101 PR3D (io), 102 PR3C (io), 103 PR3B (io), 104 PR2D (io), 105 PR3A (io), 106 PR2B (io), 107 PR2C (io), 108 PR2A (io)
part C pins: 40 PB2C (io), 41 PB3A (io), 43 PB3B (io), 44 PB3C (io), 45 PB3D (io), 46 PB4A (io), 48 PB4B (io), 49 PB4C (io), 50 PB4D (io), 54 PB5A (io), 55 PB5B/PCLK2_1 (io), 56 PB5D (io), 57 PB6A (io), 58 PB6B/PCLK2_0 (io), 60 PB7C (io), 61 PB7E (io), 62 PB8A (io), 65 PB8C (io), 66 PB8D (io), 67 PB9A (io), 68 PB9C (io), 69 PB9B (io), 71 PB9D (io), 72 PB9F (io)
part D pins: 1 PL2A (io), 2 PL2C (io), 3 PL2B (io), 4 PL3A (io), 5 PL2D (io), 6 PL3B (io), 7 PL3C (io), 8 PL3D (io), 9 PL4A (io), 12 PL4D (io), 13 PL5A (io), 14 PL5B/GSRN (io), 15 PL5D (io), 17 PL6C (io), 18 PL6D (io), 19 PL7A (io), 20 PL7B (io), 22 PL8A (io), 23 PL8B (io), 24 PL8C/TSALL (io), 25 PL9C (io), 28 PL9D (io), 29 PL10A (io), 30 PL10B (io), 31 PL10C (io), 32 PL11A (io), 33 PL10D (io), 34 PL11C (io), 35 PL11B (io), 36 PL11D (io)
part E pins: 39 TMS (in) "Powered by VCCIO2", 42 TCK (in) "Powered by VCCIO2", 47 TDO (out) "Powered by VCCIO2", 51 TDI (in) "Powered by VCCIO2", 70 NC
part F pins: 10 VCCIO3 (power), 21 VCC (power), 26 VCCIO3 (power), 38 VCCIO2 (power), 52 VCC (power), 53 VCCAUX (power), 63 VCCIO2 (power), 82 VCCIO1 (power), 93 VCC (power), 98 VCCIO1 (power), 117 VCCIO0 (power), 128 VCCAUX (power), 129 VCC (power), 135 VCCIO0 (power)
part G pins: 11 GNDIO3 (power), 16 GND (power), 27 GNDIO3 (power), 37 GNDIO2 (power), 59 GND (power), 64 GNDIO2 (power), 83 GNDIO1 (power), 88 GND (power), 99 GNDIO1 (power), 118 GNDIO0 (power), 123 GND (power), 136 GNDIO0 (power)

## LCMXO640E-3TN100C
designator U?
MachXO 640 Crossover PLD, 1.2V, 74 User I/Os, 100-Pins TQFP, Speed Grade-3, Commercial Grade, Pb-Free
footprint TQFP100_N (Thin QFP, 100-Leads, Body 14x14mm, Pitch 0.5mm, IPC Medium Density)
footprint TQFP100_L (Thin QFP, 100-Leads, Body 14x14mm, Pitch 0.5mm, IPC High Density)
footprint TQFP100_M (Thin QFP, 100-Leads, Body 14x14mm, Pitch 0.5mm, IPC Low Density)
3D model MachXO640-TQFP100 (100-Pin Thin Quad Flat Pack (TQFP100))
signal-integrity model LCMXO640E_T100 (MachXO)
part A pins: 76 PT9F (io), 77 PT9E (io), 78 PT9C (io), 79 PT9A (io), 82 PT7E (io), 83 PT7A (io), 85 PT6B/PCLK0_1 (io), 86 PT5B/PCLK0_0 (io), 87 PT5A (io), 89 PT4F (io), 91 PT3F (io), 94 PT3B (io), 95 PT3A (io), 96 PT2F (io), 97 PT2E (io), 98 PT2B (io), 99 PT2C (io), 100 PT2A (io)
part B pins: 51 PR11D (io), 52 PR11B (io), 53 PR11C (io), 54 PR11A (io), 55 PR10D (io), 56 PR10C (io), 57 PR10B (io), 58 PR10A (io), 59 PR9D (io), 61 PR9B (io), 63 PR7B (io), 64 PR6C (io), 65 PR6B (io), 66 PR5D (io), 67 PR5B (io), 68 PR4D (io), 69 PR4B (io), 70 PR3D (io), 71 PR3B (io), 72 PR2D (io), 73 PR2B (io)
part C pins: 27 PB2C (io), 32 PB4C (io), 34 PB4E (io), 36 PB5B/PCLK2_1 (io), 37 PB5D (io), 38 PB6B/PCLK2_0 (io), 39 PB6C (io), 43 PB8B (io), 44 PB8C (io), 45 PB8D (io), 46 PB9A (io), 47 PB9C (io), 49 PB9D (io), 50 PB9F (io)
part D pins: 1 PL2A (io), 2 PL2C (io), 3 PL2B (io), 4 PL2D (io), 5 PL3A (io), 6 PL3B (io), 7 PL3C (io), 8 PL3D (io), 9 PL4A (io), 11 PL4C (io), 13 PL4D (io), 14 PL5B/GSRN (io), 15 PL7B (io), 16 PL8C/TSALL (io), 17 PL8D (io), 18 PL9A (io), 19 PL9C (io), 20 PL10A (io), 21 PL10C (io), 22 PL11A (io), 23 PL11C (io)
part E pins: 26 TMS (in) "Powered by VCCIO2", 28 TCK (in) "Powered by VCCIO2", 31 TDO (out) "Powered by VCCIO2", 33 TDI (in) "Powered by VCCIO2", 48 NC
part F pins: 10 VCCIO3 (power), 24 VCCIO3 (power), 29 VCCIO2 (power), 35 VCC (power), 41 VCCIO2 (power), 60 VCCIO1 (power), 74 VCCIO1 (power), 80 VCCIO0 (power), 88 VCCAUX (power), 90 VCC (power), 92 VCCIO0 (power)
part G pins: 12 GNDIO3 (power), 25 GNDIO3 (power), 30 GNDIO2 (power), 40 GND (power), 42 GNDIO2 (power), 62 GNDIO1 (power), 75 GNDIO1 (power), 81 GNDIO0 (power), 84 GND (power), 93 GNDIO0 (power)


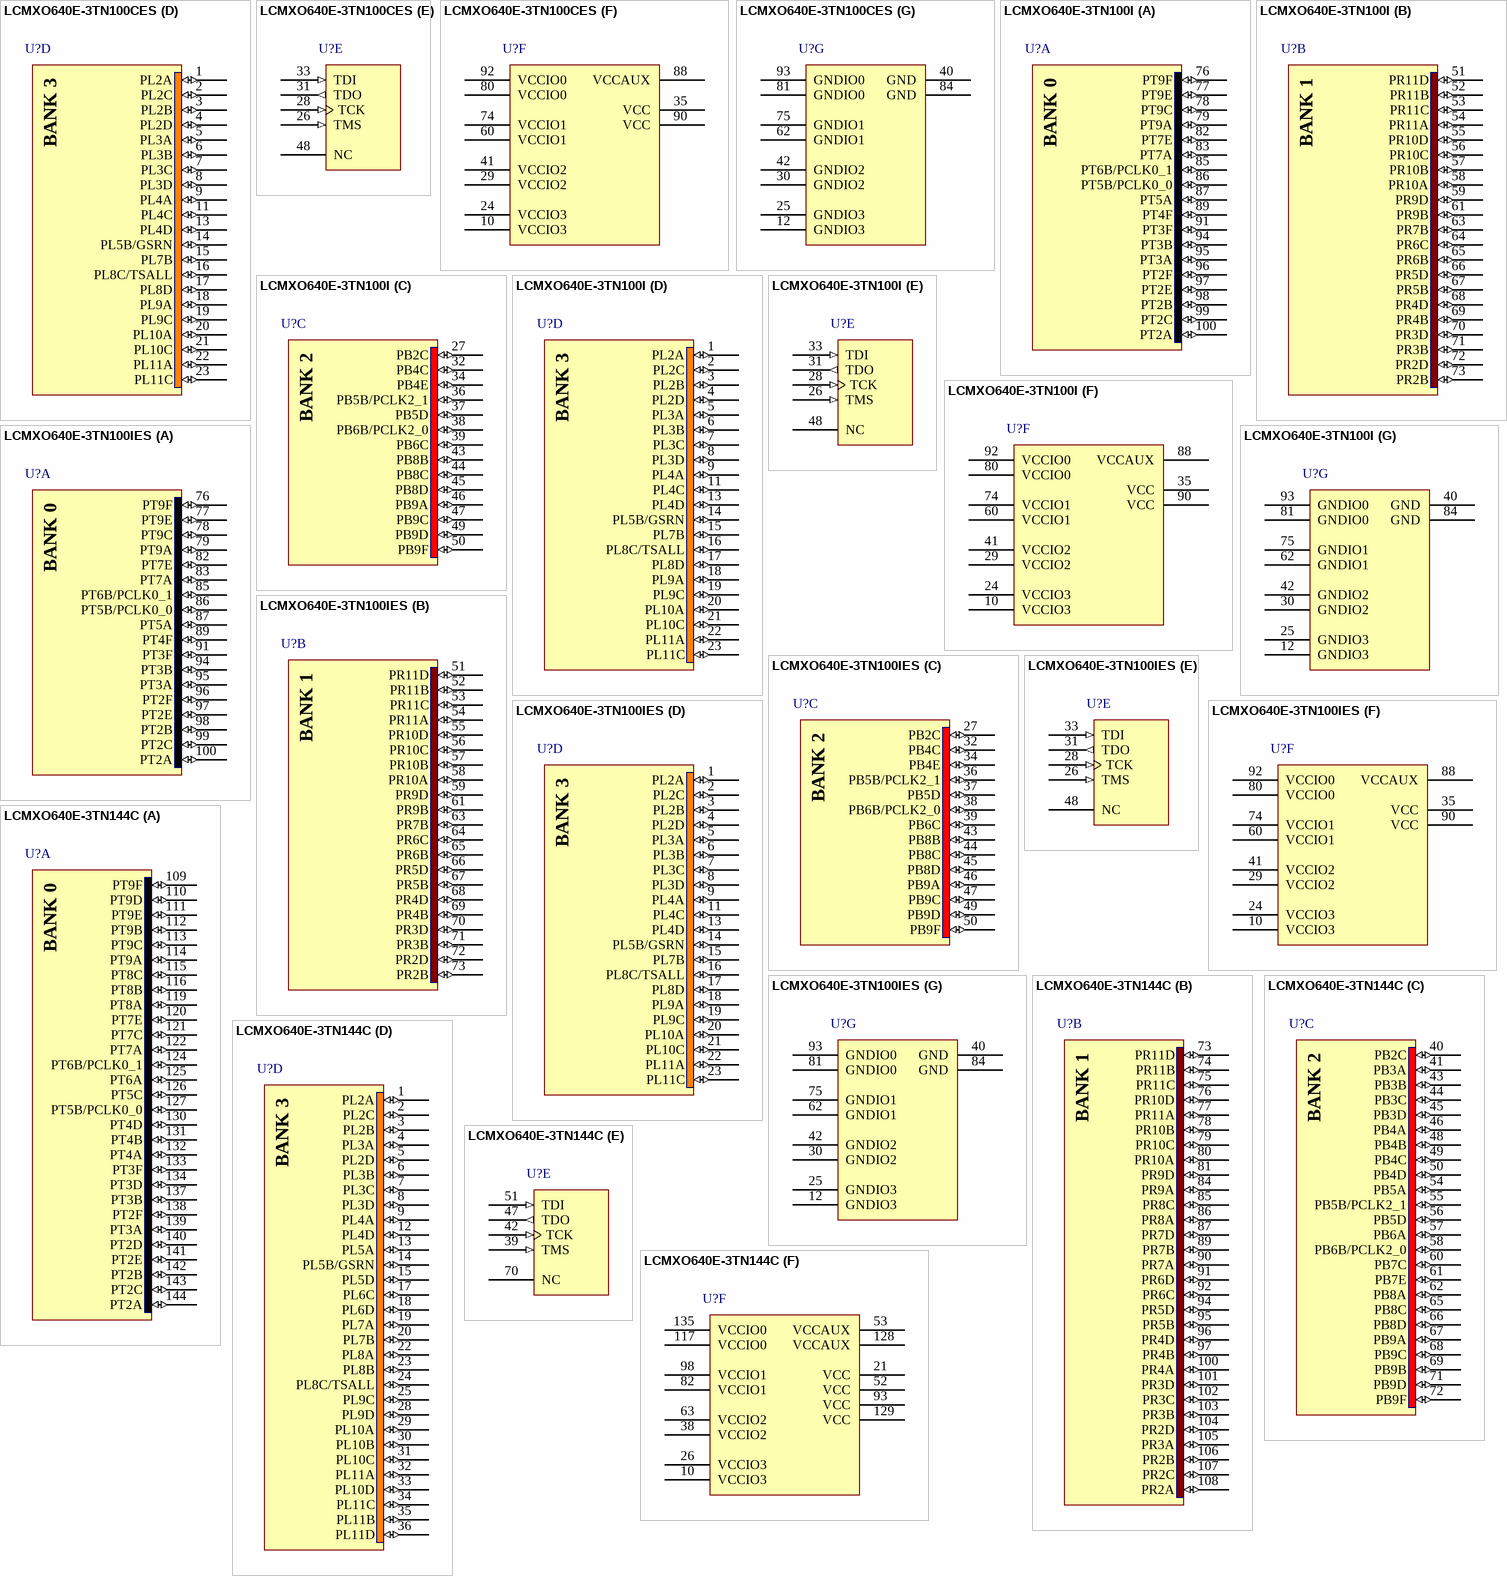
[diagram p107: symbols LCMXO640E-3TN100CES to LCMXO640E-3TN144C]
## LCMXO640E-3TN100CES
designator U?
MachXO 640 Crossover PLD, 1.2V, 74 User I/Os, 100-Pins TQFP, Speed Grade-3, Commercial Grade, Pb-Free, Engineering Sample
footprint TQFP100_N (Thin QFP, 100-Leads, Body 14x14mm, Pitch 0.5mm, IPC Medium Density)
footprint TQFP100_L (Thin QFP, 100-Leads, Body 14x14mm, Pitch 0.5mm, IPC High Density)
footprint TQFP100_M (Thin QFP, 100-Leads, Body 14x14mm, Pitch 0.5mm, IPC Low Density)
3D model MachXO640-TQFP100 (100-Pin Thin Quad Flat Pack (TQFP100))
signal-integrity model LCMXO640E_T100 (MachXO)
part A pins: 76 PT9F (io), 77 PT9E (io), 78 PT9C (io), 79 PT9A (io), 82 PT7E (io), 83 PT7A (io), 85 PT6B/PCLK0_1 (io), 86 PT5B/PCLK0_0 (io), 87 PT5A (io), 89 PT4F (io), 91 PT3F (io), 94 PT3B (io), 95 PT3A (io), 96 PT2F (io), 97 PT2E (io), 98 PT2B (io), 99 PT2C (io), 100 PT2A (io)
part B pins: 51 PR11D (io), 52 PR11B (io), 53 PR11C (io), 54 PR11A (io), 55 PR10D (io), 56 PR10C (io), 57 PR10B (io), 58 PR10A (io), 59 PR9D (io), 61 PR9B (io), 63 PR7B (io), 64 PR6C (io), 65 PR6B (io), 66 PR5D (io), 67 PR5B (io), 68 PR4D (io), 69 PR4B (io), 70 PR3D (io), 71 PR3B (io), 72 PR2D (io), 73 PR2B (io)
part C pins: 27 PB2C (io), 32 PB4C (io), 34 PB4E (io), 36 PB5B/PCLK2_1 (io), 37 PB5D (io), 38 PB6B/PCLK2_0 (io), 39 PB6C (io), 43 PB8B (io), 44 PB8C (io), 45 PB8D (io), 46 PB9A (io), 47 PB9C (io), 49 PB9D (io), 50 PB9F (io)
part D pins: 1 PL2A (io), 2 PL2C (io), 3 PL2B (io), 4 PL2D (io), 5 PL3A (io), 6 PL3B (io), 7 PL3C (io), 8 PL3D (io), 9 PL4A (io), 11 PL4C (io), 13 PL4D (io), 14 PL5B/GSRN (io), 15 PL7B (io), 16 PL8C/TSALL (io), 17 PL8D (io), 18 PL9A (io), 19 PL9C (io), 20 PL10A (io), 21 PL10C (io), 22 PL11A (io), 23 PL11C (io)
part E pins: 26 TMS (in) "Powered by VCCIO2", 28 TCK (in) "Powered by VCCIO2", 31 TDO (out) "Powered by VCCIO2", 33 TDI (in) "Powered by VCCIO2", 48 NC
part F pins: 10 VCCIO3 (power), 24 VCCIO3 (power), 29 VCCIO2 (power), 35 VCC (power), 41 VCCIO2 (power), 60 VCCIO1 (power), 74 VCCIO1 (power), 80 VCCIO0 (power), 88 VCCAUX (power), 90 VCC (power), 92 VCCIO0 (power)
part G pins: 12 GNDIO3 (power), 25 GNDIO3 (power), 30 GNDIO2 (power), 40 GND (power), 42 GNDIO2 (power), 62 GNDIO1 (power), 75 GNDIO1 (power), 81 GNDIO0 (power), 84 GND (power), 93 GNDIO0 (power)

## LCMXO640E-3TN100I
designator U?
MachXO 640 Crossover PLD, 1.2V, 74 User I/Os, 100-Pins TQFP, Speed Grade-3, Industrial Grade, Pb-Free
footprint TQFP100_N (Thin QFP, 100-Leads, Body 14x14mm, Pitch 0.5mm, IPC Medium Density)
footprint TQFP100_L (Thin QFP, 100-Leads, Body 14x14mm, Pitch 0.5mm, IPC High Density)
footprint TQFP100_M (Thin QFP, 100-Leads, Body 14x14mm, Pitch 0.5mm, IPC Low Density)
3D model MachXO640-TQFP100 (100-Pin Thin Quad Flat Pack (TQFP100))
signal-integrity model LCMXO640E_T100 (MachXO)
part A pins: 76 PT9F (io), 77 PT9E (io), 78 PT9C (io), 79 PT9A (io), 82 PT7E (io), 83 PT7A (io), 85 PT6B/PCLK0_1 (io), 86 PT5B/PCLK0_0 (io), 87 PT5A (io), 89 PT4F (io), 91 PT3F (io), 94 PT3B (io), 95 PT3A (io), 96 PT2F (io), 97 PT2E (io), 98 PT2B (io), 99 PT2C (io), 100 PT2A (io)
part B pins: 51 PR11D (io), 52 PR11B (io), 53 PR11C (io), 54 PR11A (io), 55 PR10D (io), 56 PR10C (io), 57 PR10B (io), 58 PR10A (io), 59 PR9D (io), 61 PR9B (io), 63 PR7B (io), 64 PR6C (io), 65 PR6B (io), 66 PR5D (io), 67 PR5B (io), 68 PR4D (io), 69 PR4B (io), 70 PR3D (io), 71 PR3B (io), 72 PR2D (io), 73 PR2B (io)
part C pins: 27 PB2C (io), 32 PB4C (io), 34 PB4E (io), 36 PB5B/PCLK2_1 (io), 37 PB5D (io), 38 PB6B/PCLK2_0 (io), 39 PB6C (io), 43 PB8B (io), 44 PB8C (io), 45 PB8D (io), 46 PB9A (io), 47 PB9C (io), 49 PB9D (io), 50 PB9F (io)
part D pins: 1 PL2A (io), 2 PL2C (io), 3 PL2B (io), 4 PL2D (io), 5 PL3A (io), 6 PL3B (io), 7 PL3C (io), 8 PL3D (io), 9 PL4A (io), 11 PL4C (io), 13 PL4D (io), 14 PL5B/GSRN (io), 15 PL7B (io), 16 PL8C/TSALL (io), 17 PL8D (io), 18 PL9A (io), 19 PL9C (io), 20 PL10A (io), 21 PL10C (io), 22 PL11A (io), 23 PL11C (io)
part E pins: 26 TMS (in) "Powered by VCCIO2", 28 TCK (in) "Powered by VCCIO2", 31 TDO (out) "Powered by VCCIO2", 33 TDI (in) "Powered by VCCIO2", 48 NC
part F pins: 10 VCCIO3 (power), 24 VCCIO3 (power), 29 VCCIO2 (power), 35 VCC (power), 41 VCCIO2 (power), 60 VCCIO1 (power), 74 VCCIO1 (power), 80 VCCIO0 (power), 88 VCCAUX (power), 90 VCC (power), 92 VCCIO0 (power)
part G pins: 12 GNDIO3 (power), 25 GNDIO3 (power), 30 GNDIO2 (power), 40 GND (power), 42 GNDIO2 (power), 62 GNDIO1 (power), 75 GNDIO1 (power), 81 GNDIO0 (power), 84 GND (power), 93 GNDIO0 (power)

## LCMXO640E-3TN100IES
designator U?
MachXO 640 Crossover PLD, 1.2V, 74 User I/Os, 100-Pins TQFP, Speed Grade-3, Industrial Grade, Pb-Free, Engineering Sample
footprint TQFP100_N (Thin QFP, 100-Leads, Body 14x14mm, Pitch 0.5mm, IPC Medium Density)
footprint TQFP100_L (Thin QFP, 100-Leads, Body 14x14mm, Pitch 0.5mm, IPC High Density)
footprint TQFP100_M (Thin QFP, 100-Leads, Body 14x14mm, Pitch 0.5mm, IPC Low Density)
3D model MachXO640-TQFP100 (100-Pin Thin Quad Flat Pack (TQFP100))
signal-integrity model LCMXO640E_T100 (MachXO)
part A pins: 76 PT9F (io), 77 PT9E (io), 78 PT9C (io), 79 PT9A (io), 82 PT7E (io), 83 PT7A (io), 85 PT6B/PCLK0_1 (io), 86 PT5B/PCLK0_0 (io), 87 PT5A (io), 89 PT4F (io), 91 PT3F (io), 94 PT3B (io), 95 PT3A (io), 96 PT2F (io), 97 PT2E (io), 98 PT2B (io), 99 PT2C (io), 100 PT2A (io)
part B pins: 51 PR11D (io), 52 PR11B (io), 53 PR11C (io), 54 PR11A (io), 55 PR10D (io), 56 PR10C (io), 57 PR10B (io), 58 PR10A (io), 59 PR9D (io), 61 PR9B (io), 63 PR7B (io), 64 PR6C (io), 65 PR6B (io), 66 PR5D (io), 67 PR5B (io), 68 PR4D (io), 69 PR4B (io), 70 PR3D (io), 71 PR3B (io), 72 PR2D (io), 73 PR2B (io)
part C pins: 27 PB2C (io), 32 PB4C (io), 34 PB4E (io), 36 PB5B/PCLK2_1 (io), 37 PB5D (io), 38 PB6B/PCLK2_0 (io), 39 PB6C (io), 43 PB8B (io), 44 PB8C (io), 45 PB8D (io), 46 PB9A (io), 47 PB9C (io), 49 PB9D (io), 50 PB9F (io)
part D pins: 1 PL2A (io), 2 PL2C (io), 3 PL2B (io), 4 PL2D (io), 5 PL3A (io), 6 PL3B (io), 7 PL3C (io), 8 PL3D (io), 9 PL4A (io), 11 PL4C (io), 13 PL4D (io), 14 PL5B/GSRN (io), 15 PL7B (io), 16 PL8C/TSALL (io), 17 PL8D (io), 18 PL9A (io), 19 PL9C (io), 20 PL10A (io), 21 PL10C (io), 22 PL11A (io), 23 PL11C (io)
part E pins: 26 TMS (in) "Powered by VCCIO2", 28 TCK (in) "Powered by VCCIO2", 31 TDO (out) "Powered by VCCIO2", 33 TDI (in) "Powered by VCCIO2", 48 NC
part F pins: 10 VCCIO3 (power), 24 VCCIO3 (power), 29 VCCIO2 (power), 35 VCC (power), 41 VCCIO2 (power), 60 VCCIO1 (power), 74 VCCIO1 (power), 80 VCCIO0 (power), 88 VCCAUX (power), 90 VCC (power), 92 VCCIO0 (power)
part G pins: 12 GNDIO3 (power), 25 GNDIO3 (power), 30 GNDIO2 (power), 40 GND (power), 42 GNDIO2 (power), 62 GNDIO1 (power), 75 GNDIO1 (power), 81 GNDIO0 (power), 84 GND (power), 93 GNDIO0 (power)


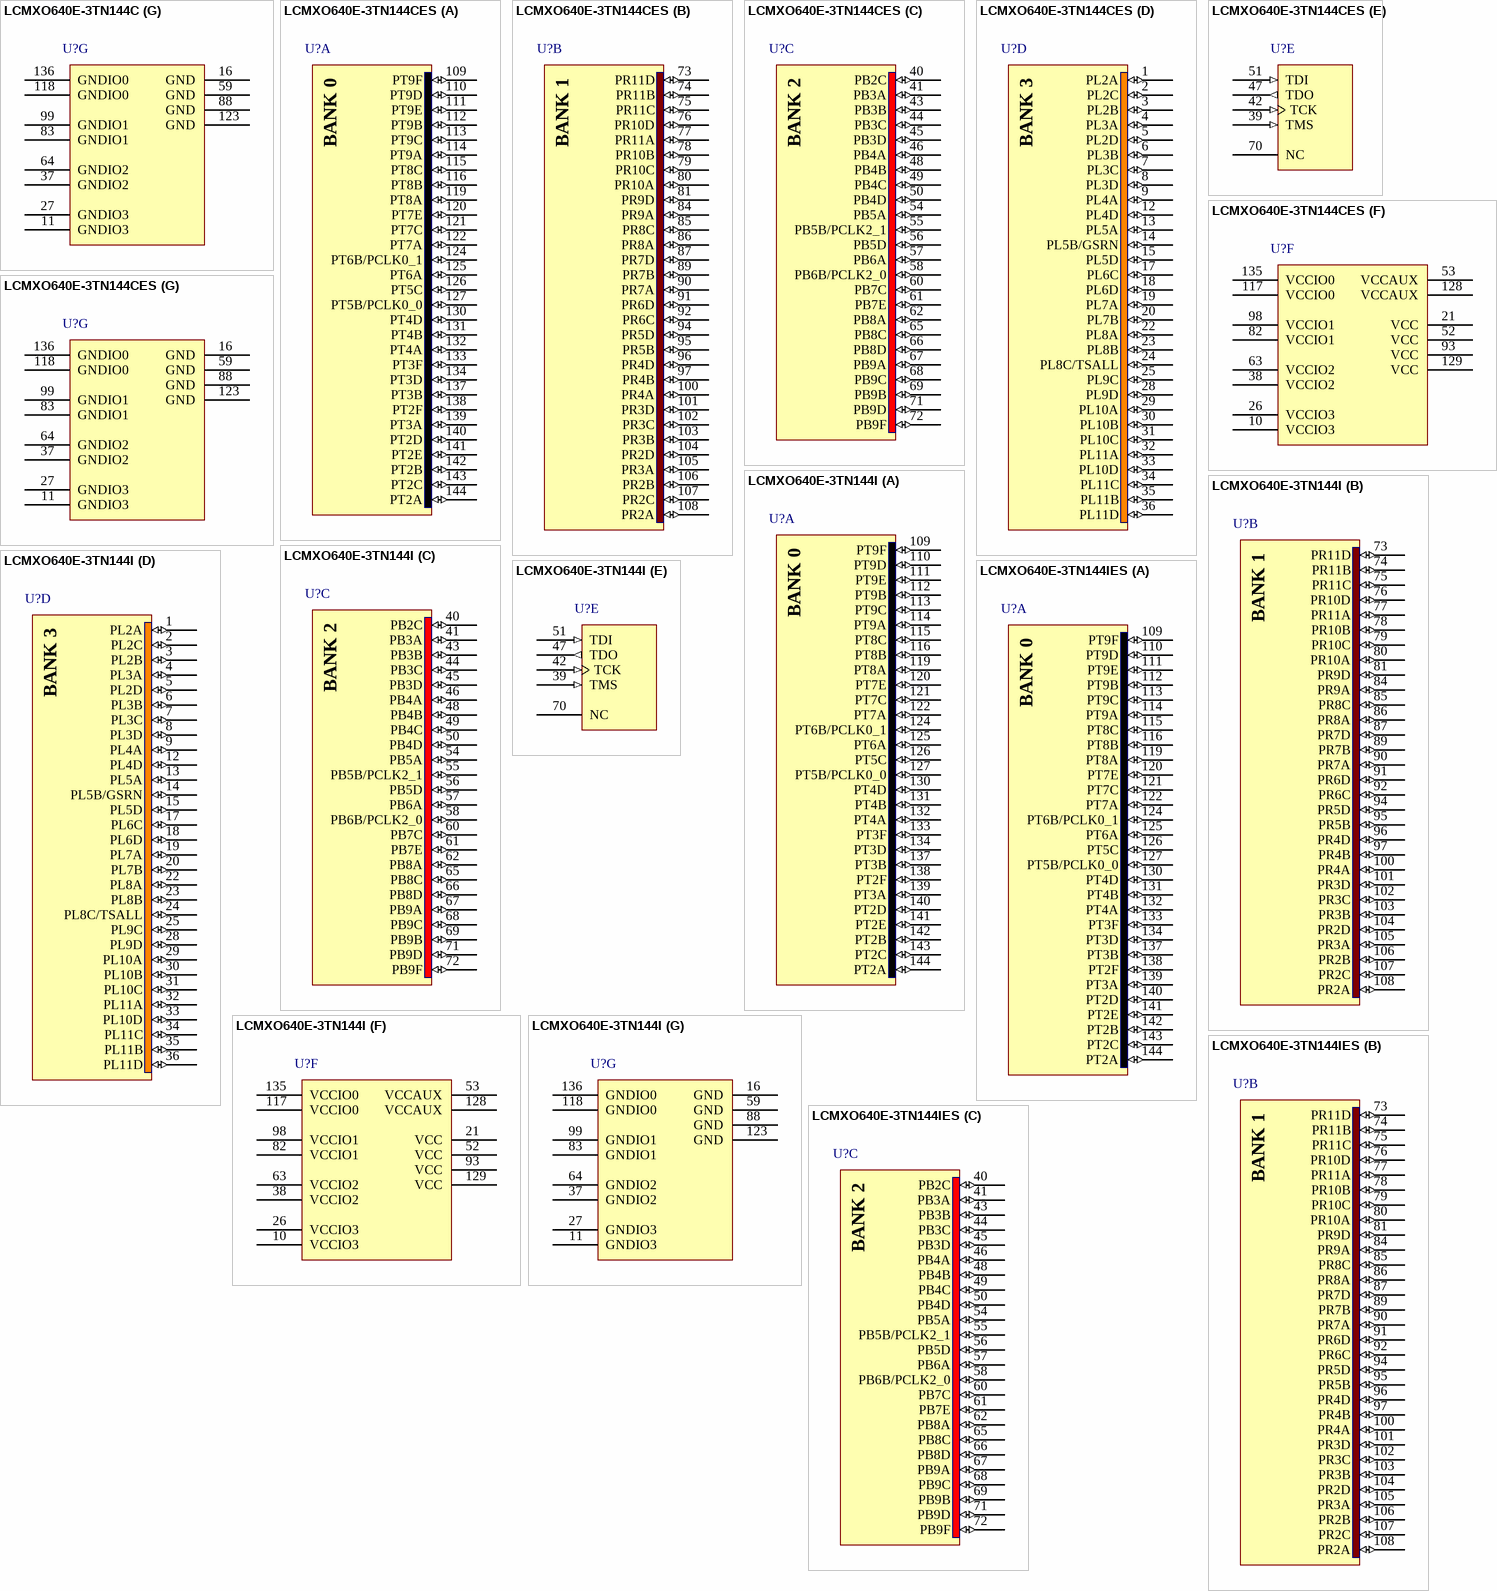
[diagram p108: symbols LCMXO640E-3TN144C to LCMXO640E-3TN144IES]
## LCMXO640E-3TN144C
designator U?
MachXO 640 Crossover PLD, 1.2V, 113 User I/Os, 144-Pins TQFP, Speed Grade-3, Commercial Grade, Pb-Free
footprint TQFP144_N (Thin QFP, 144-Leads, Body 20x20mm, Pitch 0.5mm, IPC Medium Density)
footprint TQFP144_L (Thin QFP, 144-Leads, Body 20x20mm, Pitch 0.5mm, IPC High Density)
footprint TQFP144_M (Thin QFP, 144-Leads, Body 20x20mm, Pitch 0.5mm, IPC Low Density)
3D model MachXO640-TQFP144 (144-Pin Thin Quad Flat Pack (TQFP144))
signal-integrity model LCMXO640E_T144 (MachXO)
part A pins: 109 PT9F (io), 110 PT9D (io), 111 PT9E (io), 112 PT9B (io), 113 PT9C (io), 114 PT9A (io), 115 PT8C (io), 116 PT8B (io), 119 PT8A (io), 120 PT7E (io), 121 PT7C (io), 122 PT7A (io), 124 PT6B/PCLK0_1 (io), 125 PT6A (io), 126 PT5C (io), 127 PT5B/PCLK0_0 (io), 130 PT4D (io), 131 PT4B (io), 132 PT4A (io), 133 PT3F (io), 134 PT3D (io), 137 PT3B (io), 138 PT2F (io), 139 PT3A (io), 140 PT2D (io), 141 PT2E (io), 142 PT2B (io), 143 PT2C (io), 144 PT2A (io)
part B pins: 73 PR11D (io), 74 PR11B (io), 75 PR11C (io), 76 PR10D (io), 77 PR11A (io), 78 PR10B (io), 79 PR10C (io), 80 PR10A (io), 81 PR9D (io), 84 PR9A (io), 85 PR8C (io), 86 PR8A (io), 87 PR7D (io), 89 PR7B (io), 90 PR7A (io), 91 PR6D (io), 92 PR6C (io), 94 PR5D (io), 95 PR5B (io), 96 PR4D (io), 97 PR4B (io), 100 PR4A (io), 101 PR3D (io), 102 PR3C (io), 103 PR3B (io), 104 PR2D (io), 105 PR3A (io), 106 PR2B (io), 107 PR2C (io), 108 PR2A (io)
part C pins: 40 PB2C (io), 41 PB3A (io), 43 PB3B (io), 44 PB3C (io), 45 PB3D (io), 46 PB4A (io), 48 PB4B (io), 49 PB4C (io), 50 PB4D (io), 54 PB5A (io), 55 PB5B/PCLK2_1 (io), 56 PB5D (io), 57 PB6A (io), 58 PB6B/PCLK2_0 (io), 60 PB7C (io), 61 PB7E (io), 62 PB8A (io), 65 PB8C (io), 66 PB8D (io), 67 PB9A (io), 68 PB9C (io), 69 PB9B (io), 71 PB9D (io), 72 PB9F (io)
part D pins: 1 PL2A (io), 2 PL2C (io), 3 PL2B (io), 4 PL3A (io), 5 PL2D (io), 6 PL3B (io), 7 PL3C (io), 8 PL3D (io), 9 PL4A (io), 12 PL4D (io), 13 PL5A (io), 14 PL5B/GSRN (io), 15 PL5D (io), 17 PL6C (io), 18 PL6D (io), 19 PL7A (io), 20 PL7B (io), 22 PL8A (io), 23 PL8B (io), 24 PL8C/TSALL (io), 25 PL9C (io), 28 PL9D (io), 29 PL10A (io), 30 PL10B (io), 31 PL10C (io), 32 PL11A (io), 33 PL10D (io), 34 PL11C (io), 35 PL11B (io), 36 PL11D (io)
part E pins: 39 TMS (in) "Powered by VCCIO2", 42 TCK (in) "Powered by VCCIO2", 47 TDO (out) "Powered by VCCIO2", 51 TDI (in) "Powered by VCCIO2", 70 NC
part F pins: 10 VCCIO3 (power), 21 VCC (power), 26 VCCIO3 (power), 38 VCCIO2 (power), 52 VCC (power), 53 VCCAUX (power), 63 VCCIO2 (power), 82 VCCIO1 (power), 93 VCC (power), 98 VCCIO1 (power), 117 VCCIO0 (power), 128 VCCAUX (power), 129 VCC (power), 135 VCCIO0 (power)
part G pins: 11 GNDIO3 (power), 16 GND (power), 27 GNDIO3 (power), 37 GNDIO2 (power), 59 GND (power), 64 GNDIO2 (power), 83 GNDIO1 (power), 88 GND (power), 99 GNDIO1 (power), 118 GNDIO0 (power), 123 GND (power), 136 GNDIO0 (power)

## LCMXO640E-3TN144CES
designator U?
MachXO 640 Crossover PLD, 1.2V, 113 User I/Os, 144-Pins TQFP, Speed Grade-3, Commercial Grade, Pb-Free, Engineering Sample
footprint TQFP144_N (Thin QFP, 144-Leads, Body 20x20mm, Pitch 0.5mm, IPC Medium Density)
footprint TQFP144_L (Thin QFP, 144-Leads, Body 20x20mm, Pitch 0.5mm, IPC High Density)
footprint TQFP144_M (Thin QFP, 144-Leads, Body 20x20mm, Pitch 0.5mm, IPC Low Density)
3D model MachXO640-TQFP144 (144-Pin Thin Quad Flat Pack (TQFP144))
signal-integrity model LCMXO640E_T144 (MachXO)
part A pins: 109 PT9F (io), 110 PT9D (io), 111 PT9E (io), 112 PT9B (io), 113 PT9C (io), 114 PT9A (io), 115 PT8C (io), 116 PT8B (io), 119 PT8A (io), 120 PT7E (io), 121 PT7C (io), 122 PT7A (io), 124 PT6B/PCLK0_1 (io), 125 PT6A (io), 126 PT5C (io), 127 PT5B/PCLK0_0 (io), 130 PT4D (io), 131 PT4B (io), 132 PT4A (io), 133 PT3F (io), 134 PT3D (io), 137 PT3B (io), 138 PT2F (io), 139 PT3A (io), 140 PT2D (io), 141 PT2E (io), 142 PT2B (io), 143 PT2C (io), 144 PT2A (io)
part B pins: 73 PR11D (io), 74 PR11B (io), 75 PR11C (io), 76 PR10D (io), 77 PR11A (io), 78 PR10B (io), 79 PR10C (io), 80 PR10A (io), 81 PR9D (io), 84 PR9A (io), 85 PR8C (io), 86 PR8A (io), 87 PR7D (io), 89 PR7B (io), 90 PR7A (io), 91 PR6D (io), 92 PR6C (io), 94 PR5D (io), 95 PR5B (io), 96 PR4D (io), 97 PR4B (io), 100 PR4A (io), 101 PR3D (io), 102 PR3C (io), 103 PR3B (io), 104 PR2D (io), 105 PR3A (io), 106 PR2B (io), 107 PR2C (io), 108 PR2A (io)
part C pins: 40 PB2C (io), 41 PB3A (io), 43 PB3B (io), 44 PB3C (io), 45 PB3D (io), 46 PB4A (io), 48 PB4B (io), 49 PB4C (io), 50 PB4D (io), 54 PB5A (io), 55 PB5B/PCLK2_1 (io), 56 PB5D (io), 57 PB6A (io), 58 PB6B/PCLK2_0 (io), 60 PB7C (io), 61 PB7E (io), 62 PB8A (io), 65 PB8C (io), 66 PB8D (io), 67 PB9A (io), 68 PB9C (io), 69 PB9B (io), 71 PB9D (io), 72 PB9F (io)
part D pins: 1 PL2A (io), 2 PL2C (io), 3 PL2B (io), 4 PL3A (io), 5 PL2D (io), 6 PL3B (io), 7 PL3C (io), 8 PL3D (io), 9 PL4A (io), 12 PL4D (io), 13 PL5A (io), 14 PL5B/GSRN (io), 15 PL5D (io), 17 PL6C (io), 18 PL6D (io), 19 PL7A (io), 20 PL7B (io), 22 PL8A (io), 23 PL8B (io), 24 PL8C/TSALL (io), 25 PL9C (io), 28 PL9D (io), 29 PL10A (io), 30 PL10B (io), 31 PL10C (io), 32 PL11A (io), 33 PL10D (io), 34 PL11C (io), 35 PL11B (io), 36 PL11D (io)
part E pins: 39 TMS (in) "Powered by VCCIO2", 42 TCK (in) "Powered by VCCIO2", 47 TDO (out) "Powered by VCCIO2", 51 TDI (in) "Powered by VCCIO2", 70 NC
part F pins: 10 VCCIO3 (power), 21 VCC (power), 26 VCCIO3 (power), 38 VCCIO2 (power), 52 VCC (power), 53 VCCAUX (power), 63 VCCIO2 (power), 82 VCCIO1 (power), 93 VCC (power), 98 VCCIO1 (power), 117 VCCIO0 (power), 128 VCCAUX (power), 129 VCC (power), 135 VCCIO0 (power)
part G pins: 11 GNDIO3 (power), 16 GND (power), 27 GNDIO3 (power), 37 GNDIO2 (power), 59 GND (power), 64 GNDIO2 (power), 83 GNDIO1 (power), 88 GND (power), 99 GNDIO1 (power), 118 GNDIO0 (power), 123 GND (power), 136 GNDIO0 (power)

## LCMXO640E-3TN144I
designator U?
MachXO 640 Crossover PLD, 1.2V, 113 User I/Os, 144-Pins TQFP, Speed Grade-3, Industrial Grade, Pb-Free
footprint TQFP144_N (Thin QFP, 144-Leads, Body 20x20mm, Pitch 0.5mm, IPC Medium Density)
footprint TQFP144_L (Thin QFP, 144-Leads, Body 20x20mm, Pitch 0.5mm, IPC High Density)
footprint TQFP144_M (Thin QFP, 144-Leads, Body 20x20mm, Pitch 0.5mm, IPC Low Density)
3D model MachXO640-TQFP144 (144-Pin Thin Quad Flat Pack (TQFP144))
signal-integrity model LCMXO640E_T144 (MachXO)
part A pins: 109 PT9F (io), 110 PT9D (io), 111 PT9E (io), 112 PT9B (io), 113 PT9C (io), 114 PT9A (io), 115 PT8C (io), 116 PT8B (io), 119 PT8A (io), 120 PT7E (io), 121 PT7C (io), 122 PT7A (io), 124 PT6B/PCLK0_1 (io), 125 PT6A (io), 126 PT5C (io), 127 PT5B/PCLK0_0 (io), 130 PT4D (io), 131 PT4B (io), 132 PT4A (io), 133 PT3F (io), 134 PT3D (io), 137 PT3B (io), 138 PT2F (io), 139 PT3A (io), 140 PT2D (io), 141 PT2E (io), 142 PT2B (io), 143 PT2C (io), 144 PT2A (io)
part B pins: 73 PR11D (io), 74 PR11B (io), 75 PR11C (io), 76 PR10D (io), 77 PR11A (io), 78 PR10B (io), 79 PR10C (io), 80 PR10A (io), 81 PR9D (io), 84 PR9A (io), 85 PR8C (io), 86 PR8A (io), 87 PR7D (io), 89 PR7B (io), 90 PR7A (io), 91 PR6D (io), 92 PR6C (io), 94 PR5D (io), 95 PR5B (io), 96 PR4D (io), 97 PR4B (io), 100 PR4A (io), 101 PR3D (io), 102 PR3C (io), 103 PR3B (io), 104 PR2D (io), 105 PR3A (io), 106 PR2B (io), 107 PR2C (io), 108 PR2A (io)
part C pins: 40 PB2C (io), 41 PB3A (io), 43 PB3B (io), 44 PB3C (io), 45 PB3D (io), 46 PB4A (io), 48 PB4B (io), 49 PB4C (io), 50 PB4D (io), 54 PB5A (io), 55 PB5B/PCLK2_1 (io), 56 PB5D (io), 57 PB6A (io), 58 PB6B/PCLK2_0 (io), 60 PB7C (io), 61 PB7E (io), 62 PB8A (io), 65 PB8C (io), 66 PB8D (io), 67 PB9A (io), 68 PB9C (io), 69 PB9B (io), 71 PB9D (io), 72 PB9F (io)
part D pins: 1 PL2A (io), 2 PL2C (io), 3 PL2B (io), 4 PL3A (io), 5 PL2D (io), 6 PL3B (io), 7 PL3C (io), 8 PL3D (io), 9 PL4A (io), 12 PL4D (io), 13 PL5A (io), 14 PL5B/GSRN (io), 15 PL5D (io), 17 PL6C (io), 18 PL6D (io), 19 PL7A (io), 20 PL7B (io), 22 PL8A (io), 23 PL8B (io), 24 PL8C/TSALL (io), 25 PL9C (io), 28 PL9D (io), 29 PL10A (io), 30 PL10B (io), 31 PL10C (io), 32 PL11A (io), 33 PL10D (io), 34 PL11C (io), 35 PL11B (io), 36 PL11D (io)
part E pins: 39 TMS (in) "Powered by VCCIO2", 42 TCK (in) "Powered by VCCIO2", 47 TDO (out) "Powered by VCCIO2", 51 TDI (in) "Powered by VCCIO2", 70 NC
part F pins: 10 VCCIO3 (power), 21 VCC (power), 26 VCCIO3 (power), 38 VCCIO2 (power), 52 VCC (power), 53 VCCAUX (power), 63 VCCIO2 (power), 82 VCCIO1 (power), 93 VCC (power), 98 VCCIO1 (power), 117 VCCIO0 (power), 128 VCCAUX (power), 129 VCC (power), 135 VCCIO0 (power)
part G pins: 11 GNDIO3 (power), 16 GND (power), 27 GNDIO3 (power), 37 GNDIO2 (power), 59 GND (power), 64 GNDIO2 (power), 83 GNDIO1 (power), 88 GND (power), 99 GNDIO1 (power), 118 GNDIO0 (power), 123 GND (power), 136 GNDIO0 (power)


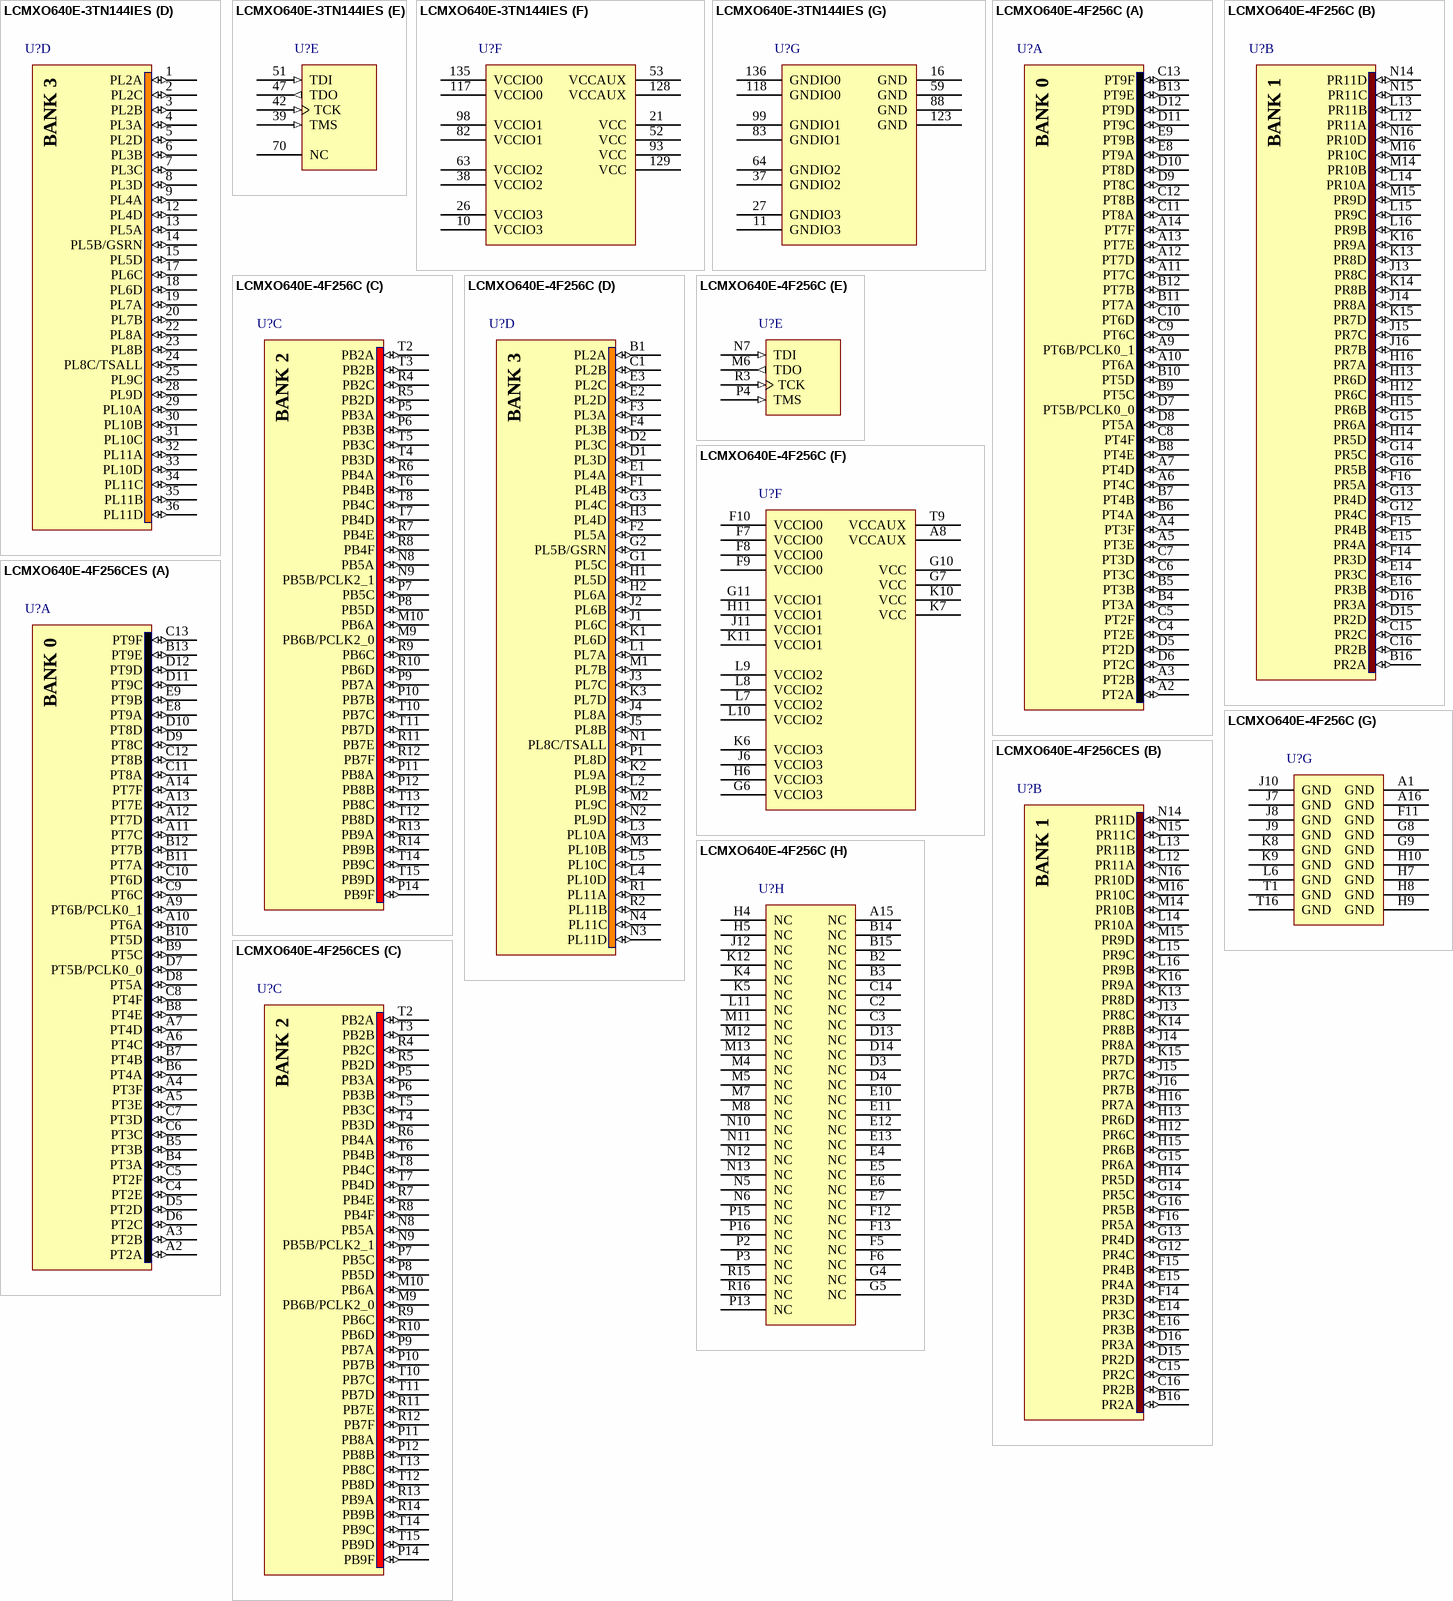
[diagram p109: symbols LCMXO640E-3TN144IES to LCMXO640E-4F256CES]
## LCMXO640E-3TN144IES
designator U?
MachXO 640 Crossover PLD, 1.2V, 113 User I/Os, 144-Pins TQFP, Speed Grade-3, Industrial Grade, Pb-Free, Engineering Sample
footprint TQFP144_N (Thin QFP, 144-Leads, Body 20x20mm, Pitch 0.5mm, IPC Medium Density)
footprint TQFP144_L (Thin QFP, 144-Leads, Body 20x20mm, Pitch 0.5mm, IPC High Density)
footprint TQFP144_M (Thin QFP, 144-Leads, Body 20x20mm, Pitch 0.5mm, IPC Low Density)
3D model MachXO640-TQFP144 (144-Pin Thin Quad Flat Pack (TQFP144))
signal-integrity model LCMXO640E_T144 (MachXO)
part A pins: 109 PT9F (io), 110 PT9D (io), 111 PT9E (io), 112 PT9B (io), 113 PT9C (io), 114 PT9A (io), 115 PT8C (io), 116 PT8B (io), 119 PT8A (io), 120 PT7E (io), 121 PT7C (io), 122 PT7A (io), 124 PT6B/PCLK0_1 (io), 125 PT6A (io), 126 PT5C (io), 127 PT5B/PCLK0_0 (io), 130 PT4D (io), 131 PT4B (io), 132 PT4A (io), 133 PT3F (io), 134 PT3D (io), 137 PT3B (io), 138 PT2F (io), 139 PT3A (io), 140 PT2D (io), 141 PT2E (io), 142 PT2B (io), 143 PT2C (io), 144 PT2A (io)
part B pins: 73 PR11D (io), 74 PR11B (io), 75 PR11C (io), 76 PR10D (io), 77 PR11A (io), 78 PR10B (io), 79 PR10C (io), 80 PR10A (io), 81 PR9D (io), 84 PR9A (io), 85 PR8C (io), 86 PR8A (io), 87 PR7D (io), 89 PR7B (io), 90 PR7A (io), 91 PR6D (io), 92 PR6C (io), 94 PR5D (io), 95 PR5B (io), 96 PR4D (io), 97 PR4B (io), 100 PR4A (io), 101 PR3D (io), 102 PR3C (io), 103 PR3B (io), 104 PR2D (io), 105 PR3A (io), 106 PR2B (io), 107 PR2C (io), 108 PR2A (io)
part C pins: 40 PB2C (io), 41 PB3A (io), 43 PB3B (io), 44 PB3C (io), 45 PB3D (io), 46 PB4A (io), 48 PB4B (io), 49 PB4C (io), 50 PB4D (io), 54 PB5A (io), 55 PB5B/PCLK2_1 (io), 56 PB5D (io), 57 PB6A (io), 58 PB6B/PCLK2_0 (io), 60 PB7C (io), 61 PB7E (io), 62 PB8A (io), 65 PB8C (io), 66 PB8D (io), 67 PB9A (io), 68 PB9C (io), 69 PB9B (io), 71 PB9D (io), 72 PB9F (io)
part D pins: 1 PL2A (io), 2 PL2C (io), 3 PL2B (io), 4 PL3A (io), 5 PL2D (io), 6 PL3B (io), 7 PL3C (io), 8 PL3D (io), 9 PL4A (io), 12 PL4D (io), 13 PL5A (io), 14 PL5B/GSRN (io), 15 PL5D (io), 17 PL6C (io), 18 PL6D (io), 19 PL7A (io), 20 PL7B (io), 22 PL8A (io), 23 PL8B (io), 24 PL8C/TSALL (io), 25 PL9C (io), 28 PL9D (io), 29 PL10A (io), 30 PL10B (io), 31 PL10C (io), 32 PL11A (io), 33 PL10D (io), 34 PL11C (io), 35 PL11B (io), 36 PL11D (io)
part E pins: 39 TMS (in) "Powered by VCCIO2", 42 TCK (in) "Powered by VCCIO2", 47 TDO (out) "Powered by VCCIO2", 51 TDI (in) "Powered by VCCIO2", 70 NC
part F pins: 10 VCCIO3 (power), 21 VCC (power), 26 VCCIO3 (power), 38 VCCIO2 (power), 52 VCC (power), 53 VCCAUX (power), 63 VCCIO2 (power), 82 VCCIO1 (power), 93 VCC (power), 98 VCCIO1 (power), 117 VCCIO0 (power), 128 VCCAUX (power), 129 VCC (power), 135 VCCIO0 (power)
part G pins: 11 GNDIO3 (power), 16 GND (power), 27 GNDIO3 (power), 37 GNDIO2 (power), 59 GND (power), 64 GNDIO2 (power), 83 GNDIO1 (power), 88 GND (power), 99 GNDIO1 (power), 118 GNDIO0 (power), 123 GND (power), 136 GNDIO0 (power)

## LCMXO640E-4F256C
designator U?
MachXO 640 Crossover PLD, 1.2V, 159 User I/Os, 256-Pins fpBGA, Speed Grade-4, Commercial Grade; ComponentAvailability: Not recommended for new designs. Use ftBGA package device.
footprint fpBGA256 (BGA, 256-Leads, Body 17x17mm, Pitch 1mm)
3D model MachXO640-fpBGA256 (256-Ball Fine Pitch Ball Grid Array (fpBGA256))
signal-integrity model LCMXO640E_F256 (MachXO)
part A pins: A2 PT2A (io), A3 PT2B (io), A4 PT3F (io), A5 PT3E (io), A6 PT4C (io), A7 PT4D (io), A9 PT6B/PCLK0_1 (io), A10 PT6A (io), A11 PT7C (io), A12 PT7D (io), A13 PT7E (io), A14 PT7F (io), B4 PT3A (io), B5 PT3B (io), B6 PT4A (io), B7 PT4B (io), B8 PT4E (io), B9 PT5C (io), B10 PT5D (io), B11 PT7A (io), B12 PT7B (io), B13 PT9E (io), C4 PT2E (io), C5 PT2F (io), C6 PT3C (io), C7 PT3D (io), C8 PT4F (io), C9 PT6C (io), C10 PT6D (io), C11 PT8A (io), C12 PT8B (io), C13 PT9F (io), D5 PT2D (io), D6 PT2C (io), D7 PT5B/PCLK0_0 (io), D8 PT5A (io), D9 PT8C (io), D10 PT8D (io), D11 PT9C (io), D12 PT9D (io), E8 PT9A (io), E9 PT9B (io)
part B pins: B16 PR2A (io), C15 PR2C (io), C16 PR2B (io), D15 PR2D (io), D16 PR3A (io), E14 PR3C (io), E15 PR4A (io), E16 PR3B (io), F14 PR3D (io), F15 PR4B (io), F16 PR5A (io), G12 PR4C (io), G13 PR4D (io), G14 PR5C (io), G15 PR6A (io), G16 PR5B (io), H12 PR6C (io), H13 PR6D (io), H14 PR5D (io), H15 PR6B (io), H16 PR7A (io), J13 PR8C (io), J14 PR8A (io), J15 PR7C (io), J16 PR7B (io), K13 PR8D (io), K14 PR8B (io), K15 PR7D (io), K16 PR9A (io), L12 PR11A (io), L13 PR11B (io), L14 PR10A (io), L15 PR9C (io), L16 PR9B (io), M14 PR10B (io), M15 PR9D (io), M16 PR10C (io), N14 PR11D (io), N15 PR11C (io), N16 PR10D (io)
part C pins: M9 PB6B/PCLK2_0 (io), M10 PB6A (io), N8 PB5A (io), N9 PB5B/PCLK2_1 (io), P5 PB3A (io), P6 PB3B (io), P7 PB5C (io), P8 PB5D (io), P9 PB7A (io), P10 PB7B (io), P11 PB8A (io), P12 PB8B (io), P14 PB9F (io), R4 PB2C (io), R5 PB2D (io), R6 PB4A (io), R7 PB4E (io), R8 PB4F (io), R9 PB6C (io), R10 PB6D (io), R11 PB7E (io), R12 PB7F (io), R13 PB9A (io), R14 PB9B (io), T2 PB2A (io), T3 PB2B (io), T4 PB3D (io), T5 PB3C (io), T6 PB4B (io), T7 PB4D (io), T8 PB4C (io), T10 PB7C (io), T11 PB7D (io), T12 PB8D (io), T13 PB8C (io), T14 PB9C (io), T15 PB9D (io)
part D pins: B1 PL2A (io), C1 PL2B (io), D1 PL3D (io), D2 PL3C (io), E1 PL4A (io), E2 PL2D (io), E3 PL2C (io), F1 PL4B (io), F2 PL5A (io), F3 PL3A (io), F4 PL3B (io), G1 PL5C (io), G2 PL5B/GSRN (io), G3 PL4C (io), H1 PL5D (io), H2 PL6A (io), H3 PL4D (io), J1 PL6C (io), J2 PL6B (io), J3 PL7C (io), J4 PL8A (io), J5 PL8B (io), K1 PL6D (io), K2 PL9A (io), K3 PL7D (io), L1 PL7A (io), L2 PL9B (io), L3 PL10A (io), L4 PL10D (io), L5 PL10C (io), M1 PL7B (io), M2 PL9C (io), M3 PL10B (io), N1 PL8C/TSALL (io), N2 PL9D (io), N3 PL11D (io), N4 PL11C (io), P1 PL8D (io), R1 PL11A (io), R2 PL11B (io)
part E pins: M6 TDO (out) "Powered by VCCIO2", N7 TDI (in) "Powered by VCCIO2", P4 TMS (in) "Powered by VCCIO2", R3 TCK (in) "Powered by VCCIO2"
part F pins: A8 VCCAUX (power), F7 VCCIO0 (power), F8 VCCIO0 (power), F9 VCCIO0 (power), F10 VCCIO0 (power), G6 VCCIO3 (power), G7 VCC (power), G10 VCC (power), G11 VCCIO1 (power), H6 VCCIO3 (power), H11 VCCIO1 (power), J6 VCCIO3 (power), J11 VCCIO1 (power), K6 VCCIO3 (power), K7 VCC (power), K10 VCC (power), K11 VCCIO1 (power), L7 VCCIO2 (power), L8 VCCIO2 (power), L9 VCCIO2 (power), L10 VCCIO2 (power), T9 VCCAUX (power)
part G pins: A1 GND (power), A16 GND (power), F11 GND (power), G8 GND (power), G9 GND (power), H7 GND (power), H8 GND (power), H9 GND (power), H10 GND (power), J7 GND (power), J8 GND (power), J9 GND (power), J10 GND (power), K8 GND (power), K9 GND (power), L6 GND (power), T1 GND (power), T16 GND (power)
part H pins: A15 NC, B2 NC, B3 NC, B14 NC, B15 NC, C2 NC, C3 NC, C14 NC, D3 NC, D4 NC, D13 NC, D14 NC, E4 NC, E5 NC, E6 NC, E7 NC, E10 NC, E11 NC, E12 NC, E13 NC, F5 NC, F6 NC, F12 NC, F13 NC, G4 NC, G5 NC, H4 NC, H5 NC, J12 NC, K4 NC, K5 NC, K12 NC, L11 NC, M4 NC, M5 NC, M7 NC, M8 NC, M11 NC, M12 NC, M13 NC, N5 NC, N6 NC, N10 NC, N11 NC, N12 NC, N13 NC, P2 NC, P3 NC, P13 NC, P15 NC, P16 NC, R15 NC, R16 NC


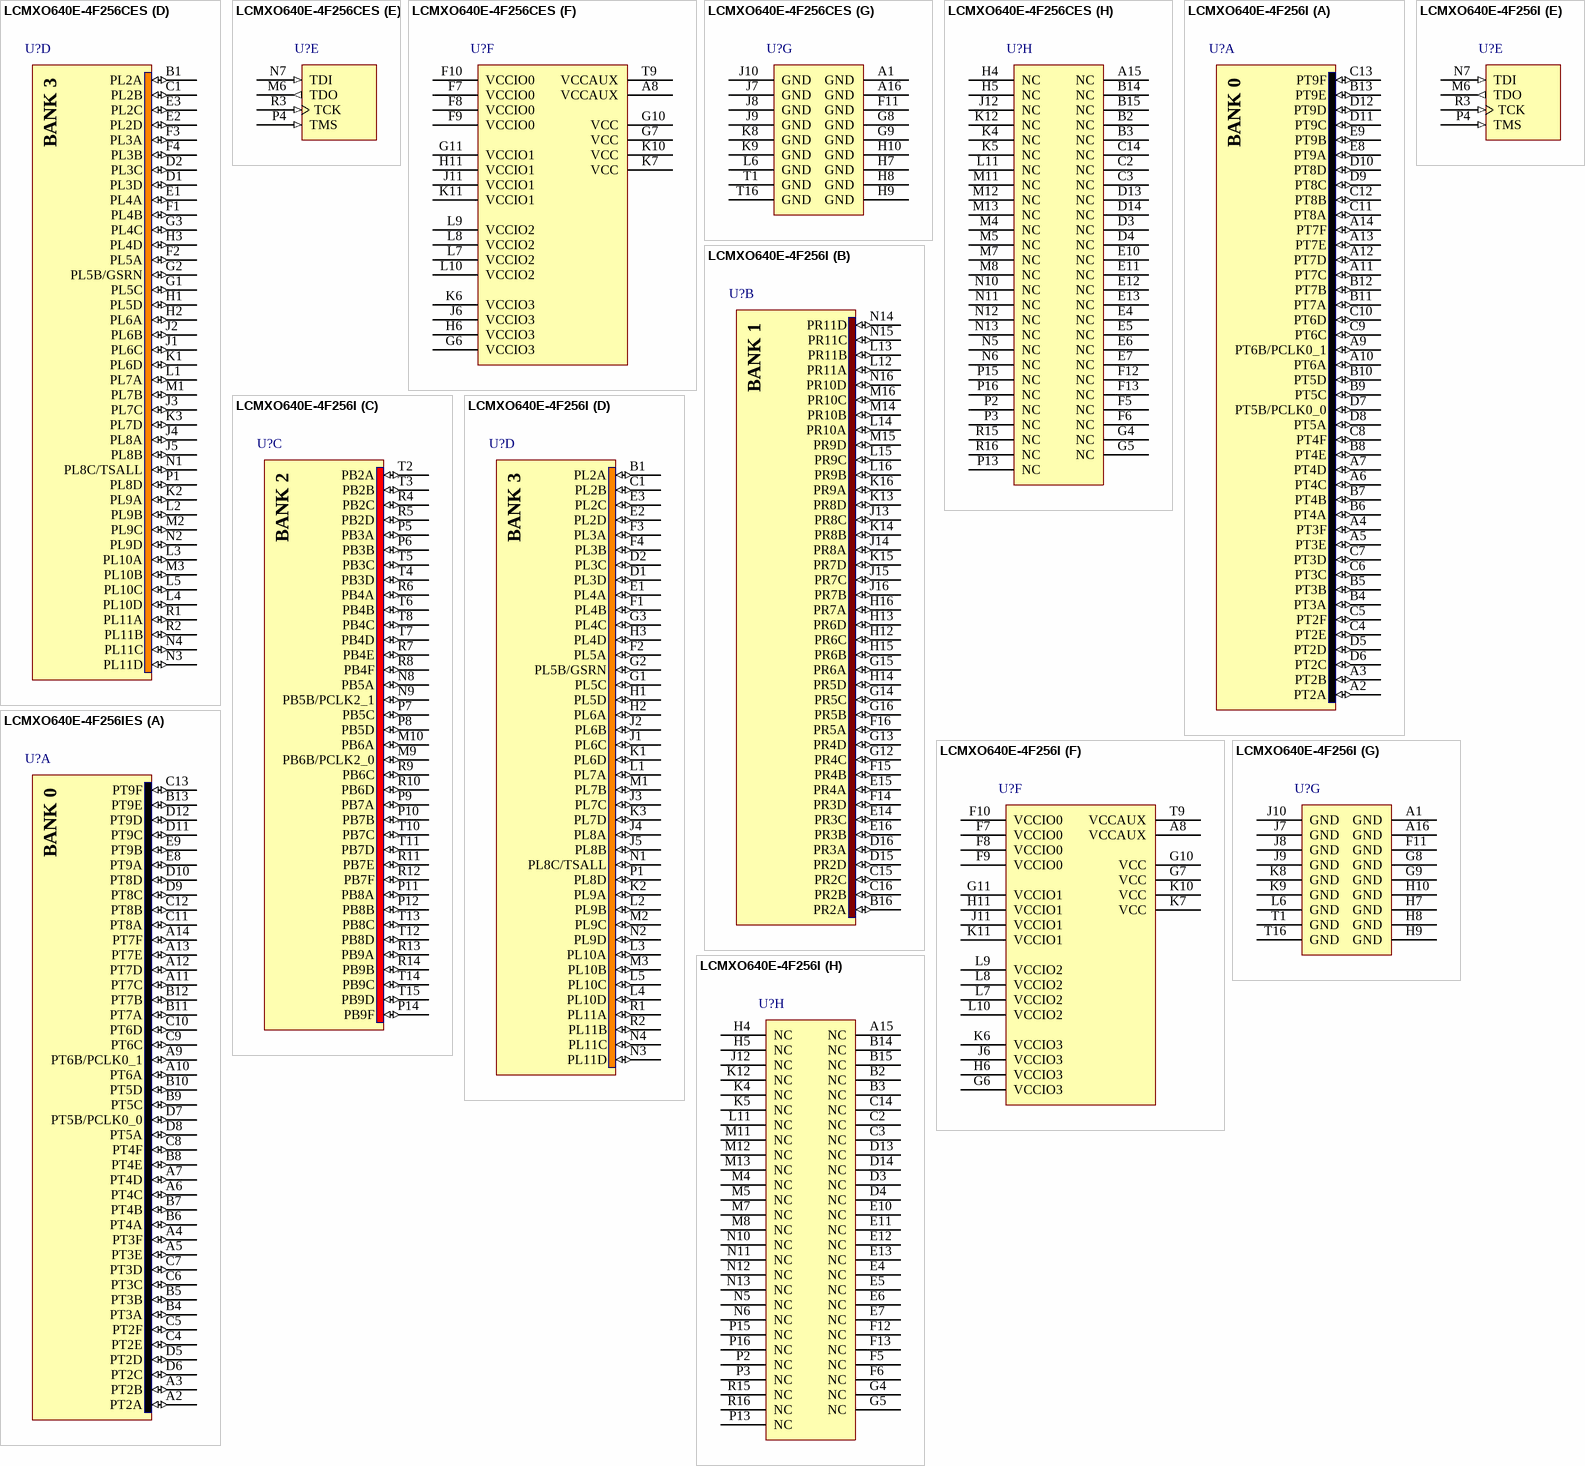
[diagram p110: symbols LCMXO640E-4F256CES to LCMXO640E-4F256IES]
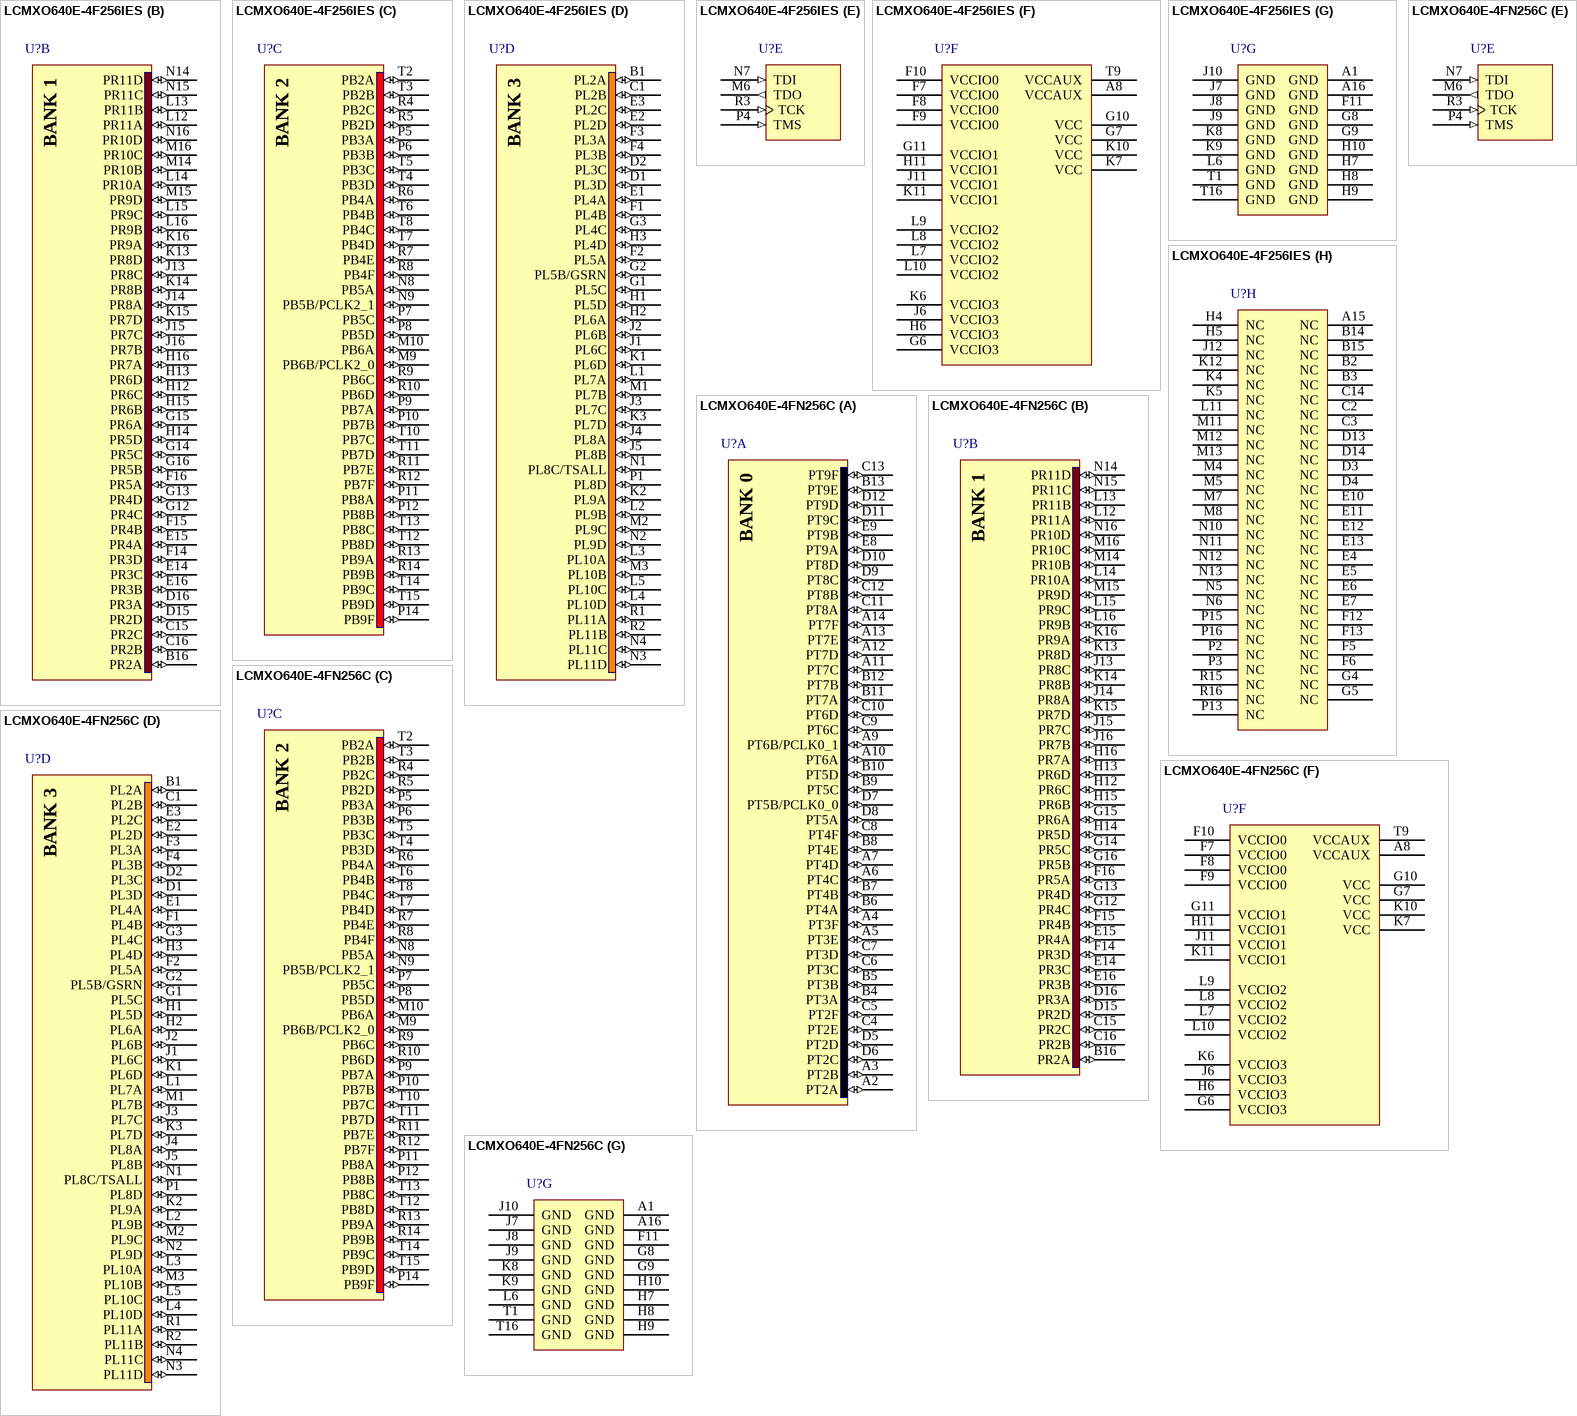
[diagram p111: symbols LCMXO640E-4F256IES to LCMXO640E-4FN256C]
## LCMXO640E-4F256CES
designator U?
MachXO 640 Crossover PLD, 1.2V, 159 User I/Os, 256-Pins fpBGA, Speed Grade-4, Commercial Grade, Engineering Sample; ComponentAvailability: Not recommended for new designs. Use ftBGA package device.
footprint fpBGA256 (BGA, 256-Leads, Body 17x17mm, Pitch 1mm)
3D model MachXO640-fpBGA256 (256-Ball Fine Pitch Ball Grid Array (fpBGA256))
signal-integrity model LCMXO640E_F256 (MachXO)
part A pins: A2 PT2A (io), A3 PT2B (io), A4 PT3F (io), A5 PT3E (io), A6 PT4C (io), A7 PT4D (io), A9 PT6B/PCLK0_1 (io), A10 PT6A (io), A11 PT7C (io), A12 PT7D (io), A13 PT7E (io), A14 PT7F (io), B4 PT3A (io), B5 PT3B (io), B6 PT4A (io), B7 PT4B (io), B8 PT4E (io), B9 PT5C (io), B10 PT5D (io), B11 PT7A (io), B12 PT7B (io), B13 PT9E (io), C4 PT2E (io), C5 PT2F (io), C6 PT3C (io), C7 PT3D (io), C8 PT4F (io), C9 PT6C (io), C10 PT6D (io), C11 PT8A (io), C12 PT8B (io), C13 PT9F (io), D5 PT2D (io), D6 PT2C (io), D7 PT5B/PCLK0_0 (io), D8 PT5A (io), D9 PT8C (io), D10 PT8D (io), D11 PT9C (io), D12 PT9D (io), E8 PT9A (io), E9 PT9B (io)
part B pins: B16 PR2A (io), C15 PR2C (io), C16 PR2B (io), D15 PR2D (io), D16 PR3A (io), E14 PR3C (io), E15 PR4A (io), E16 PR3B (io), F14 PR3D (io), F15 PR4B (io), F16 PR5A (io), G12 PR4C (io), G13 PR4D (io), G14 PR5C (io), G15 PR6A (io), G16 PR5B (io), H12 PR6C (io), H13 PR6D (io), H14 PR5D (io), H15 PR6B (io), H16 PR7A (io), J13 PR8C (io), J14 PR8A (io), J15 PR7C (io), J16 PR7B (io), K13 PR8D (io), K14 PR8B (io), K15 PR7D (io), K16 PR9A (io), L12 PR11A (io), L13 PR11B (io), L14 PR10A (io), L15 PR9C (io), L16 PR9B (io), M14 PR10B (io), M15 PR9D (io), M16 PR10C (io), N14 PR11D (io), N15 PR11C (io), N16 PR10D (io)
part C pins: M9 PB6B/PCLK2_0 (io), M10 PB6A (io), N8 PB5A (io), N9 PB5B/PCLK2_1 (io), P5 PB3A (io), P6 PB3B (io), P7 PB5C (io), P8 PB5D (io), P9 PB7A (io), P10 PB7B (io), P11 PB8A (io), P12 PB8B (io), P14 PB9F (io), R4 PB2C (io), R5 PB2D (io), R6 PB4A (io), R7 PB4E (io), R8 PB4F (io), R9 PB6C (io), R10 PB6D (io), R11 PB7E (io), R12 PB7F (io), R13 PB9A (io), R14 PB9B (io), T2 PB2A (io), T3 PB2B (io), T4 PB3D (io), T5 PB3C (io), T6 PB4B (io), T7 PB4D (io), T8 PB4C (io), T10 PB7C (io), T11 PB7D (io), T12 PB8D (io), T13 PB8C (io), T14 PB9C (io), T15 PB9D (io)
part D pins: B1 PL2A (io), C1 PL2B (io), D1 PL3D (io), D2 PL3C (io), E1 PL4A (io), E2 PL2D (io), E3 PL2C (io), F1 PL4B (io), F2 PL5A (io), F3 PL3A (io), F4 PL3B (io), G1 PL5C (io), G2 PL5B/GSRN (io), G3 PL4C (io), H1 PL5D (io), H2 PL6A (io), H3 PL4D (io), J1 PL6C (io), J2 PL6B (io), J3 PL7C (io), J4 PL8A (io), J5 PL8B (io), K1 PL6D (io), K2 PL9A (io), K3 PL7D (io), L1 PL7A (io), L2 PL9B (io), L3 PL10A (io), L4 PL10D (io), L5 PL10C (io), M1 PL7B (io), M2 PL9C (io), M3 PL10B (io), N1 PL8C/TSALL (io), N2 PL9D (io), N3 PL11D (io), N4 PL11C (io), P1 PL8D (io), R1 PL11A (io), R2 PL11B (io)
part E pins: M6 TDO (out) "Powered by VCCIO2", N7 TDI (in) "Powered by VCCIO2", P4 TMS (in) "Powered by VCCIO2", R3 TCK (in) "Powered by VCCIO2"
part F pins: A8 VCCAUX (power), F7 VCCIO0 (power), F8 VCCIO0 (power), F9 VCCIO0 (power), F10 VCCIO0 (power), G6 VCCIO3 (power), G7 VCC (power), G10 VCC (power), G11 VCCIO1 (power), H6 VCCIO3 (power), H11 VCCIO1 (power), J6 VCCIO3 (power), J11 VCCIO1 (power), K6 VCCIO3 (power), K7 VCC (power), K10 VCC (power), K11 VCCIO1 (power), L7 VCCIO2 (power), L8 VCCIO2 (power), L9 VCCIO2 (power), L10 VCCIO2 (power), T9 VCCAUX (power)
part G pins: A1 GND (power), A16 GND (power), F11 GND (power), G8 GND (power), G9 GND (power), H7 GND (power), H8 GND (power), H9 GND (power), H10 GND (power), J7 GND (power), J8 GND (power), J9 GND (power), J10 GND (power), K8 GND (power), K9 GND (power), L6 GND (power), T1 GND (power), T16 GND (power)
part H pins: A15 NC, B2 NC, B3 NC, B14 NC, B15 NC, C2 NC, C3 NC, C14 NC, D3 NC, D4 NC, D13 NC, D14 NC, E4 NC, E5 NC, E6 NC, E7 NC, E10 NC, E11 NC, E12 NC, E13 NC, F5 NC, F6 NC, F12 NC, F13 NC, G4 NC, G5 NC, H4 NC, H5 NC, J12 NC, K4 NC, K5 NC, K12 NC, L11 NC, M4 NC, M5 NC, M7 NC, M8 NC, M11 NC, M12 NC, M13 NC, N5 NC, N6 NC, N10 NC, N11 NC, N12 NC, N13 NC, P2 NC, P3 NC, P13 NC, P15 NC, P16 NC, R15 NC, R16 NC

## LCMXO640E-4F256I
designator U?
MachXO 640 Crossover PLD, 1.2V, 159 User I/Os, 256-Pins fpBGA, Speed Grade-4, Industrial Grade; ComponentAvailability: Not recommended for new designs. Use ftBGA package device.
footprint fpBGA256 (BGA, 256-Leads, Body 17x17mm, Pitch 1mm)
3D model MachXO640-fpBGA256 (256-Ball Fine Pitch Ball Grid Array (fpBGA256))
signal-integrity model LCMXO640E_F256 (MachXO)
part A pins: A2 PT2A (io), A3 PT2B (io), A4 PT3F (io), A5 PT3E (io), A6 PT4C (io), A7 PT4D (io), A9 PT6B/PCLK0_1 (io), A10 PT6A (io), A11 PT7C (io), A12 PT7D (io), A13 PT7E (io), A14 PT7F (io), B4 PT3A (io), B5 PT3B (io), B6 PT4A (io), B7 PT4B (io), B8 PT4E (io), B9 PT5C (io), B10 PT5D (io), B11 PT7A (io), B12 PT7B (io), B13 PT9E (io), C4 PT2E (io), C5 PT2F (io), C6 PT3C (io), C7 PT3D (io), C8 PT4F (io), C9 PT6C (io), C10 PT6D (io), C11 PT8A (io), C12 PT8B (io), C13 PT9F (io), D5 PT2D (io), D6 PT2C (io), D7 PT5B/PCLK0_0 (io), D8 PT5A (io), D9 PT8C (io), D10 PT8D (io), D11 PT9C (io), D12 PT9D (io), E8 PT9A (io), E9 PT9B (io)
part B pins: B16 PR2A (io), C15 PR2C (io), C16 PR2B (io), D15 PR2D (io), D16 PR3A (io), E14 PR3C (io), E15 PR4A (io), E16 PR3B (io), F14 PR3D (io), F15 PR4B (io), F16 PR5A (io), G12 PR4C (io), G13 PR4D (io), G14 PR5C (io), G15 PR6A (io), G16 PR5B (io), H12 PR6C (io), H13 PR6D (io), H14 PR5D (io), H15 PR6B (io), H16 PR7A (io), J13 PR8C (io), J14 PR8A (io), J15 PR7C (io), J16 PR7B (io), K13 PR8D (io), K14 PR8B (io), K15 PR7D (io), K16 PR9A (io), L12 PR11A (io), L13 PR11B (io), L14 PR10A (io), L15 PR9C (io), L16 PR9B (io), M14 PR10B (io), M15 PR9D (io), M16 PR10C (io), N14 PR11D (io), N15 PR11C (io), N16 PR10D (io)
part C pins: M9 PB6B/PCLK2_0 (io), M10 PB6A (io), N8 PB5A (io), N9 PB5B/PCLK2_1 (io), P5 PB3A (io), P6 PB3B (io), P7 PB5C (io), P8 PB5D (io), P9 PB7A (io), P10 PB7B (io), P11 PB8A (io), P12 PB8B (io), P14 PB9F (io), R4 PB2C (io), R5 PB2D (io), R6 PB4A (io), R7 PB4E (io), R8 PB4F (io), R9 PB6C (io), R10 PB6D (io), R11 PB7E (io), R12 PB7F (io), R13 PB9A (io), R14 PB9B (io), T2 PB2A (io), T3 PB2B (io), T4 PB3D (io), T5 PB3C (io), T6 PB4B (io), T7 PB4D (io), T8 PB4C (io), T10 PB7C (io), T11 PB7D (io), T12 PB8D (io), T13 PB8C (io), T14 PB9C (io), T15 PB9D (io)
part D pins: B1 PL2A (io), C1 PL2B (io), D1 PL3D (io), D2 PL3C (io), E1 PL4A (io), E2 PL2D (io), E3 PL2C (io), F1 PL4B (io), F2 PL5A (io), F3 PL3A (io), F4 PL3B (io), G1 PL5C (io), G2 PL5B/GSRN (io), G3 PL4C (io), H1 PL5D (io), H2 PL6A (io), H3 PL4D (io), J1 PL6C (io), J2 PL6B (io), J3 PL7C (io), J4 PL8A (io), J5 PL8B (io), K1 PL6D (io), K2 PL9A (io), K3 PL7D (io), L1 PL7A (io), L2 PL9B (io), L3 PL10A (io), L4 PL10D (io), L5 PL10C (io), M1 PL7B (io), M2 PL9C (io), M3 PL10B (io), N1 PL8C/TSALL (io), N2 PL9D (io), N3 PL11D (io), N4 PL11C (io), P1 PL8D (io), R1 PL11A (io), R2 PL11B (io)
part E pins: M6 TDO (out) "Powered by VCCIO2", N7 TDI (in) "Powered by VCCIO2", P4 TMS (in) "Powered by VCCIO2", R3 TCK (in) "Powered by VCCIO2"
part F pins: A8 VCCAUX (power), F7 VCCIO0 (power), F8 VCCIO0 (power), F9 VCCIO0 (power), F10 VCCIO0 (power), G6 VCCIO3 (power), G7 VCC (power), G10 VCC (power), G11 VCCIO1 (power), H6 VCCIO3 (power), H11 VCCIO1 (power), J6 VCCIO3 (power), J11 VCCIO1 (power), K6 VCCIO3 (power), K7 VCC (power), K10 VCC (power), K11 VCCIO1 (power), L7 VCCIO2 (power), L8 VCCIO2 (power), L9 VCCIO2 (power), L10 VCCIO2 (power), T9 VCCAUX (power)
part G pins: A1 GND (power), A16 GND (power), F11 GND (power), G8 GND (power), G9 GND (power), H7 GND (power), H8 GND (power), H9 GND (power), H10 GND (power), J7 GND (power), J8 GND (power), J9 GND (power), J10 GND (power), K8 GND (power), K9 GND (power), L6 GND (power), T1 GND (power), T16 GND (power)
part H pins: A15 NC, B2 NC, B3 NC, B14 NC, B15 NC, C2 NC, C3 NC, C14 NC, D3 NC, D4 NC, D13 NC, D14 NC, E4 NC, E5 NC, E6 NC, E7 NC, E10 NC, E11 NC, E12 NC, E13 NC, F5 NC, F6 NC, F12 NC, F13 NC, G4 NC, G5 NC, H4 NC, H5 NC, J12 NC, K4 NC, K5 NC, K12 NC, L11 NC, M4 NC, M5 NC, M7 NC, M8 NC, M11 NC, M12 NC, M13 NC, N5 NC, N6 NC, N10 NC, N11 NC, N12 NC, N13 NC, P2 NC, P3 NC, P13 NC, P15 NC, P16 NC, R15 NC, R16 NC

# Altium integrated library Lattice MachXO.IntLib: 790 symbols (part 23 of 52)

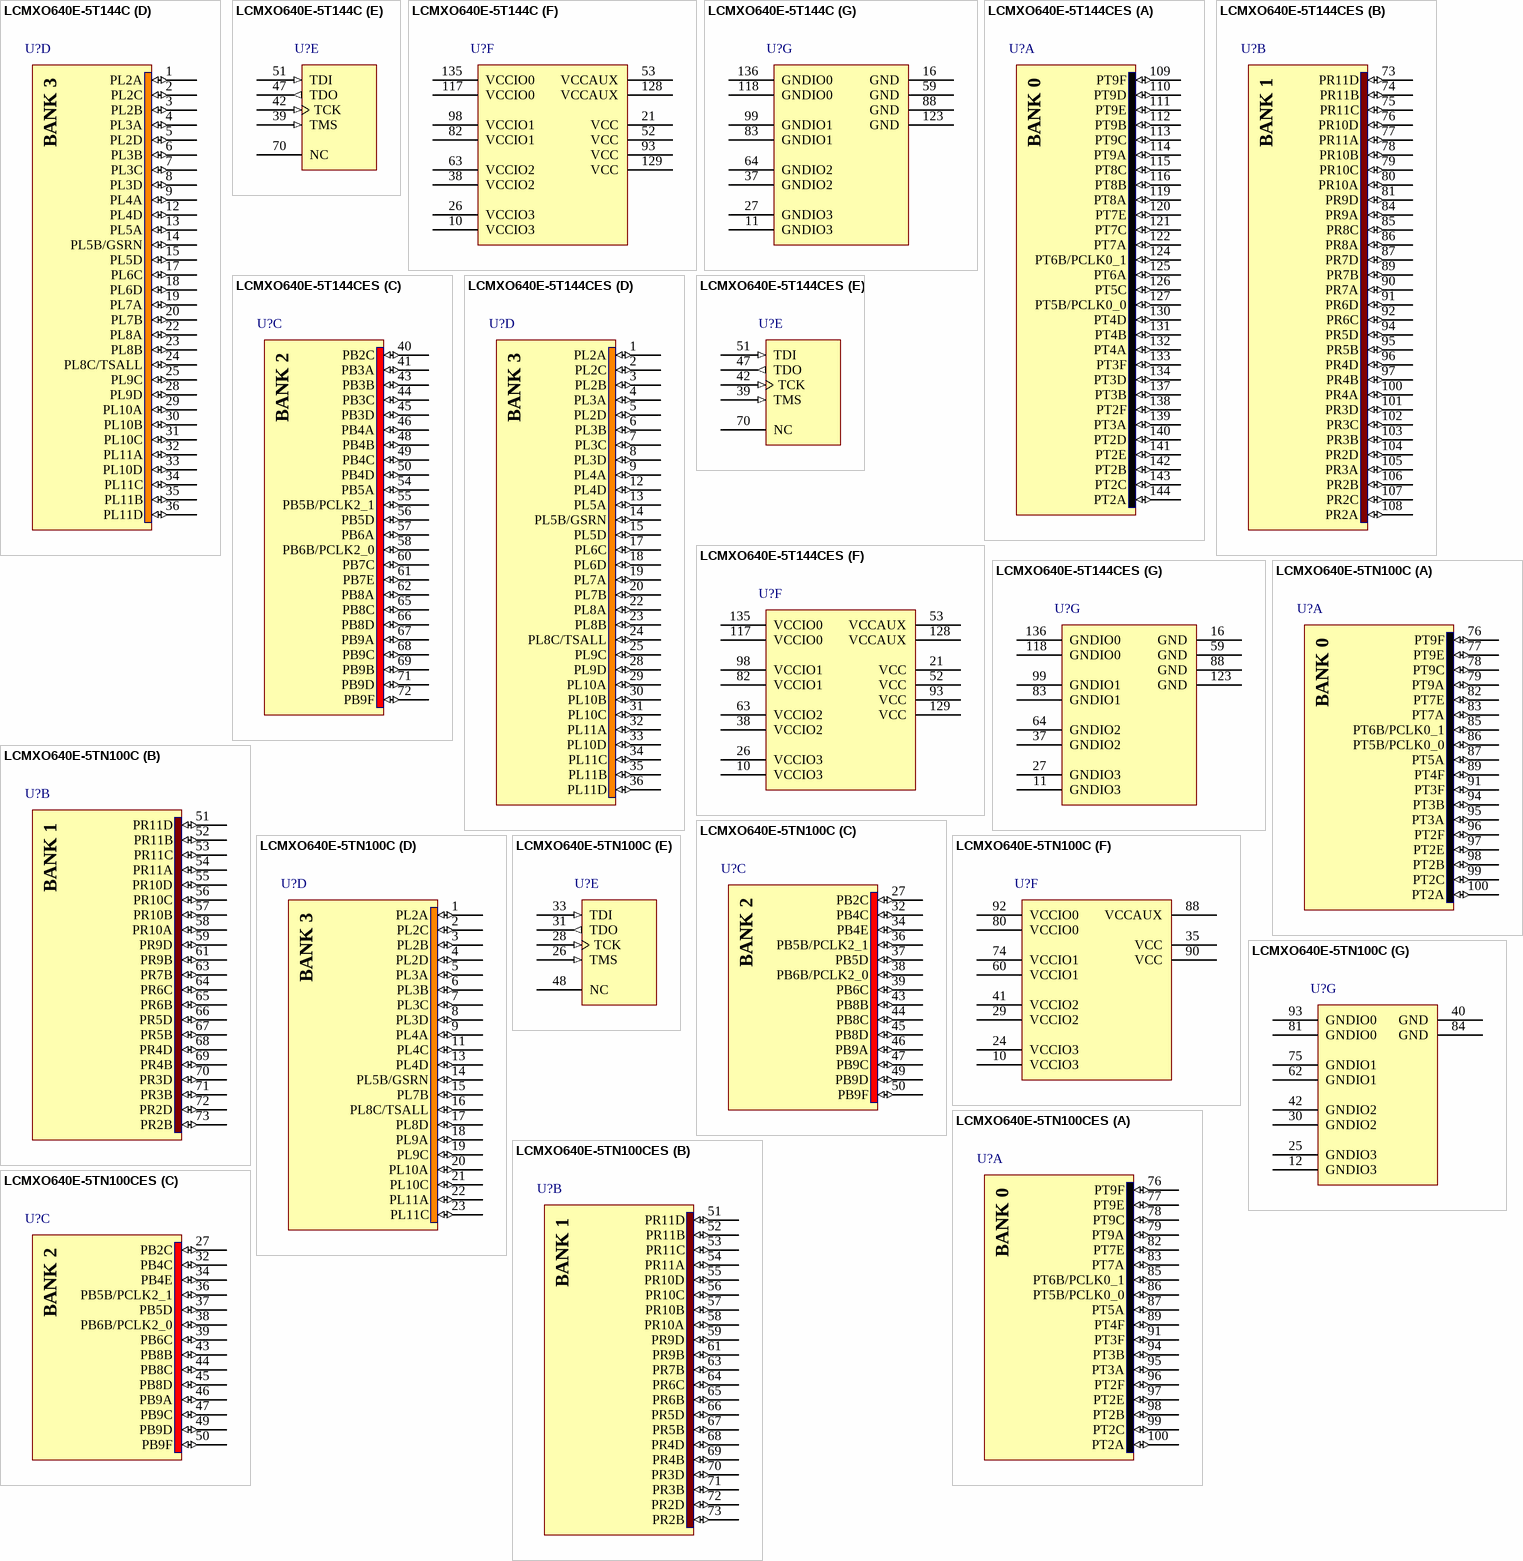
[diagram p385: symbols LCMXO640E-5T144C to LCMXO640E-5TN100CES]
## LCMXO640E-5TN100C
designator U?
MachXO 640 Crossover PLD, 1.2V, 74 User I/Os, 100-Pins TQFP, Speed Grade-5, Commercial Grade, Pb-Free
footprint TQFP100_N (Thin QFP, 100-Leads, Body 14x14mm, Pitch 0.5mm, IPC Medium Density)
footprint TQFP100_L (Thin QFP, 100-Leads, Body 14x14mm, Pitch 0.5mm, IPC High Density)
footprint TQFP100_M (Thin QFP, 100-Leads, Body 14x14mm, Pitch 0.5mm, IPC Low Density)
3D model MachXO640-TQFP100 (100-Pin Thin Quad Flat Pack (TQFP100))
signal-integrity model LCMXO640E_T100 (MachXO)
part A pins: 76 PT9F (io), 77 PT9E (io), 78 PT9C (io), 79 PT9A (io), 82 PT7E (io), 83 PT7A (io), 85 PT6B/PCLK0_1 (io), 86 PT5B/PCLK0_0 (io), 87 PT5A (io), 89 PT4F (io), 91 PT3F (io), 94 PT3B (io), 95 PT3A (io), 96 PT2F (io), 97 PT2E (io), 98 PT2B (io), 99 PT2C (io), 100 PT2A (io)
part B pins: 51 PR11D (io), 52 PR11B (io), 53 PR11C (io), 54 PR11A (io), 55 PR10D (io), 56 PR10C (io), 57 PR10B (io), 58 PR10A (io), 59 PR9D (io), 61 PR9B (io), 63 PR7B (io), 64 PR6C (io), 65 PR6B (io), 66 PR5D (io), 67 PR5B (io), 68 PR4D (io), 69 PR4B (io), 70 PR3D (io), 71 PR3B (io), 72 PR2D (io), 73 PR2B (io)
part C pins: 27 PB2C (io), 32 PB4C (io), 34 PB4E (io), 36 PB5B/PCLK2_1 (io), 37 PB5D (io), 38 PB6B/PCLK2_0 (io), 39 PB6C (io), 43 PB8B (io), 44 PB8C (io), 45 PB8D (io), 46 PB9A (io), 47 PB9C (io), 49 PB9D (io), 50 PB9F (io)
part D pins: 1 PL2A (io), 2 PL2C (io), 3 PL2B (io), 4 PL2D (io), 5 PL3A (io), 6 PL3B (io), 7 PL3C (io), 8 PL3D (io), 9 PL4A (io), 11 PL4C (io), 13 PL4D (io), 14 PL5B/GSRN (io), 15 PL7B (io), 16 PL8C/TSALL (io), 17 PL8D (io), 18 PL9A (io), 19 PL9C (io), 20 PL10A (io), 21 PL10C (io), 22 PL11A (io), 23 PL11C (io)
part E pins: 26 TMS (in) "Powered by VCCIO2", 28 TCK (in) "Powered by VCCIO2", 31 TDO (out) "Powered by VCCIO2", 33 TDI (in) "Powered by VCCIO2", 48 NC
part F pins: 10 VCCIO3 (power), 24 VCCIO3 (power), 29 VCCIO2 (power), 35 VCC (power), 41 VCCIO2 (power), 60 VCCIO1 (power), 74 VCCIO1 (power), 80 VCCIO0 (power), 88 VCCAUX (power), 90 VCC (power), 92 VCCIO0 (power)
part G pins: 12 GNDIO3 (power), 25 GNDIO3 (power), 30 GNDIO2 (power), 40 GND (power), 42 GNDIO2 (power), 62 GNDIO1 (power), 75 GNDIO1 (power), 81 GNDIO0 (power), 84 GND (power), 93 GNDIO0 (power)


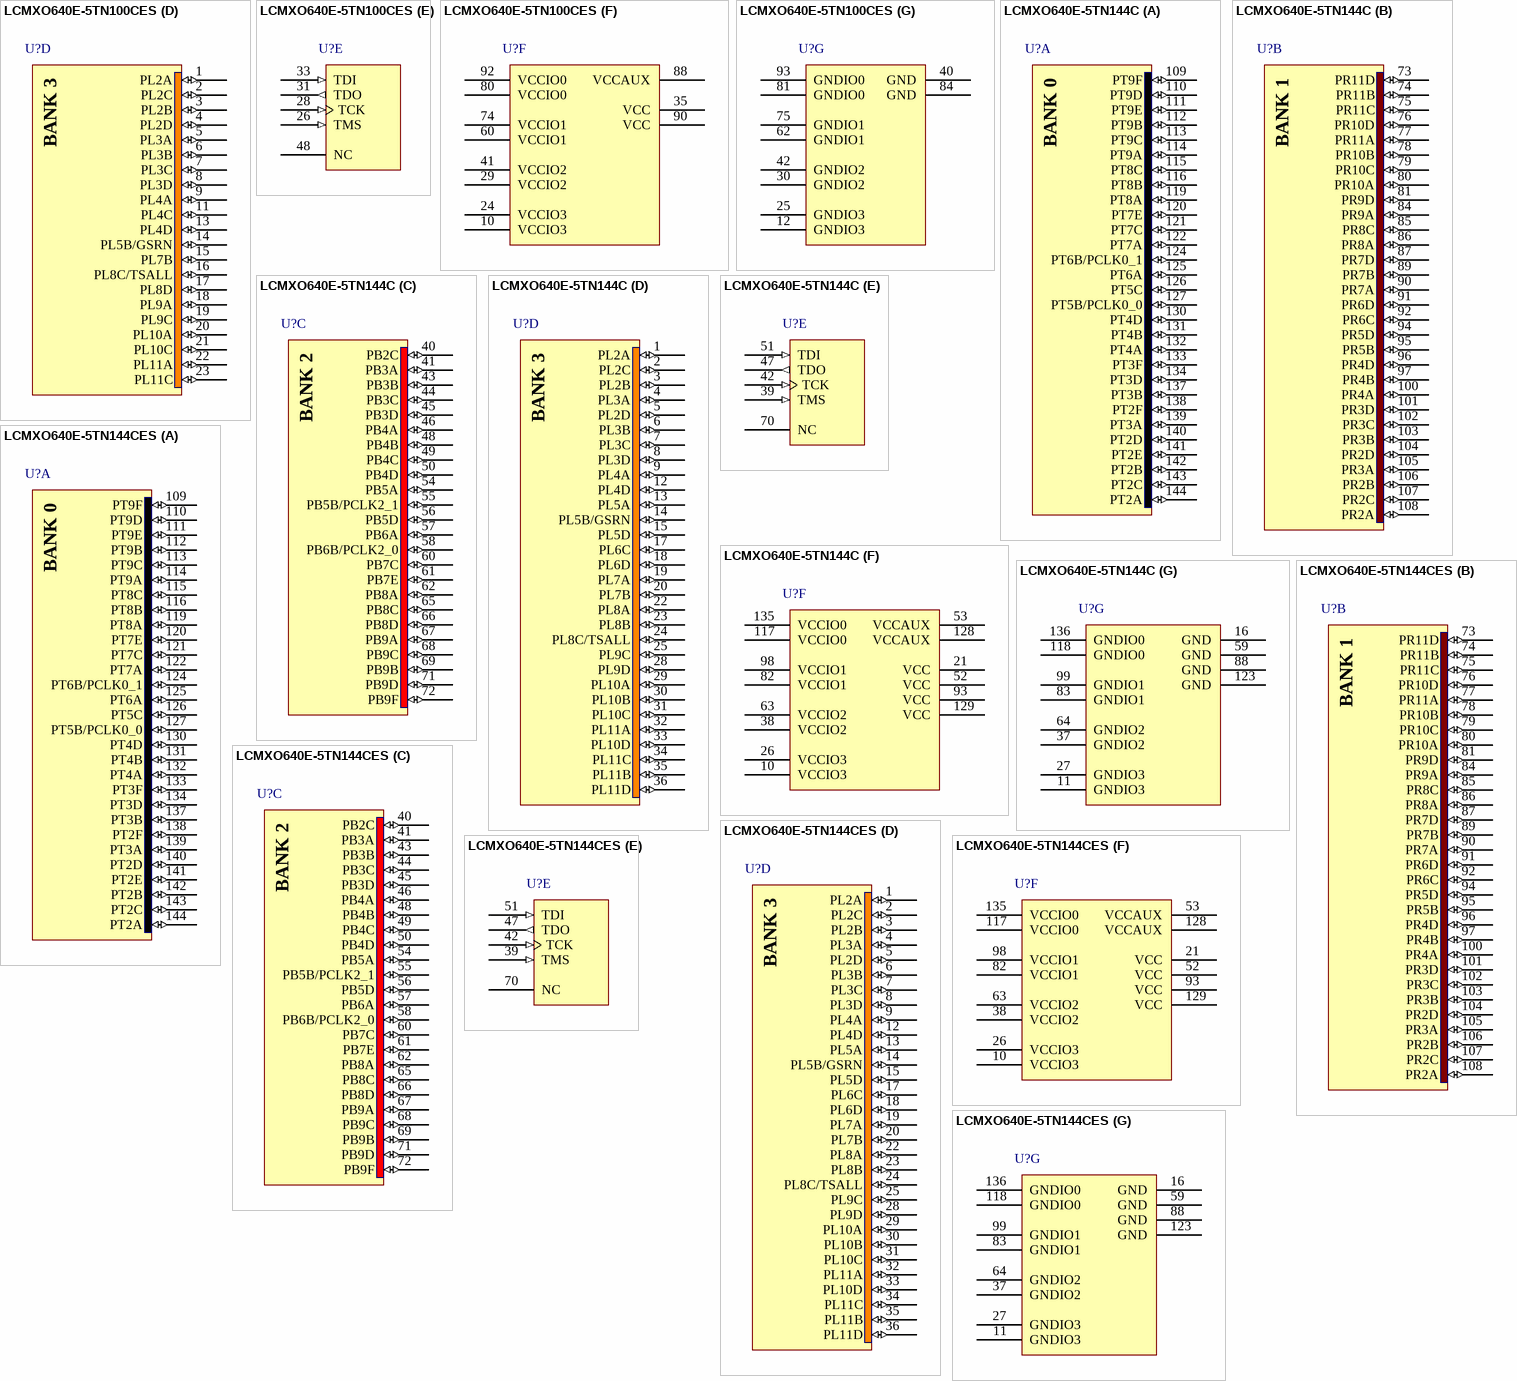
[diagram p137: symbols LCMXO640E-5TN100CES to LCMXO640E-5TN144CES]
## LCMXO640E-5TN100CES
designator U?
MachXO 640 Crossover PLD, 1.2V, 74 User I/Os, 100-Pins TQFP, Speed Grade-5, Commercial Grade, Pb-Free, Engineering Sample
footprint TQFP100_N (Thin QFP, 100-Leads, Body 14x14mm, Pitch 0.5mm, IPC Medium Density)
footprint TQFP100_L (Thin QFP, 100-Leads, Body 14x14mm, Pitch 0.5mm, IPC High Density)
footprint TQFP100_M (Thin QFP, 100-Leads, Body 14x14mm, Pitch 0.5mm, IPC Low Density)
3D model MachXO640-TQFP100 (100-Pin Thin Quad Flat Pack (TQFP100))
signal-integrity model LCMXO640E_T100 (MachXO)
part A pins: 76 PT9F (io), 77 PT9E (io), 78 PT9C (io), 79 PT9A (io), 82 PT7E (io), 83 PT7A (io), 85 PT6B/PCLK0_1 (io), 86 PT5B/PCLK0_0 (io), 87 PT5A (io), 89 PT4F (io), 91 PT3F (io), 94 PT3B (io), 95 PT3A (io), 96 PT2F (io), 97 PT2E (io), 98 PT2B (io), 99 PT2C (io), 100 PT2A (io)
part B pins: 51 PR11D (io), 52 PR11B (io), 53 PR11C (io), 54 PR11A (io), 55 PR10D (io), 56 PR10C (io), 57 PR10B (io), 58 PR10A (io), 59 PR9D (io), 61 PR9B (io), 63 PR7B (io), 64 PR6C (io), 65 PR6B (io), 66 PR5D (io), 67 PR5B (io), 68 PR4D (io), 69 PR4B (io), 70 PR3D (io), 71 PR3B (io), 72 PR2D (io), 73 PR2B (io)
part C pins: 27 PB2C (io), 32 PB4C (io), 34 PB4E (io), 36 PB5B/PCLK2_1 (io), 37 PB5D (io), 38 PB6B/PCLK2_0 (io), 39 PB6C (io), 43 PB8B (io), 44 PB8C (io), 45 PB8D (io), 46 PB9A (io), 47 PB9C (io), 49 PB9D (io), 50 PB9F (io)
part D pins: 1 PL2A (io), 2 PL2C (io), 3 PL2B (io), 4 PL2D (io), 5 PL3A (io), 6 PL3B (io), 7 PL3C (io), 8 PL3D (io), 9 PL4A (io), 11 PL4C (io), 13 PL4D (io), 14 PL5B/GSRN (io), 15 PL7B (io), 16 PL8C/TSALL (io), 17 PL8D (io), 18 PL9A (io), 19 PL9C (io), 20 PL10A (io), 21 PL10C (io), 22 PL11A (io), 23 PL11C (io)
part E pins: 26 TMS (in) "Powered by VCCIO2", 28 TCK (in) "Powered by VCCIO2", 31 TDO (out) "Powered by VCCIO2", 33 TDI (in) "Powered by VCCIO2", 48 NC
part F pins: 10 VCCIO3 (power), 24 VCCIO3 (power), 29 VCCIO2 (power), 35 VCC (power), 41 VCCIO2 (power), 60 VCCIO1 (power), 74 VCCIO1 (power), 80 VCCIO0 (power), 88 VCCAUX (power), 90 VCC (power), 92 VCCIO0 (power)
part G pins: 12 GNDIO3 (power), 25 GNDIO3 (power), 30 GNDIO2 (power), 40 GND (power), 42 GNDIO2 (power), 62 GNDIO1 (power), 75 GNDIO1 (power), 81 GNDIO0 (power), 84 GND (power), 93 GNDIO0 (power)

## LCMXO640E-5TN144C
designator U?
MachXO 640 Crossover PLD, 1.2V, 113 User I/Os, 144-Pins TQFP, Speed Grade-5, Commercial Grade, Pb-Free
footprint TQFP144_N (Thin QFP, 144-Leads, Body 20x20mm, Pitch 0.5mm, IPC Medium Density)
footprint TQFP144_L (Thin QFP, 144-Leads, Body 20x20mm, Pitch 0.5mm, IPC High Density)
footprint TQFP144_M (Thin QFP, 144-Leads, Body 20x20mm, Pitch 0.5mm, IPC Low Density)
3D model MachXO640-TQFP144 (144-Pin Thin Quad Flat Pack (TQFP144))
signal-integrity model LCMXO640E_T144 (MachXO)
part A pins: 109 PT9F (io), 110 PT9D (io), 111 PT9E (io), 112 PT9B (io), 113 PT9C (io), 114 PT9A (io), 115 PT8C (io), 116 PT8B (io), 119 PT8A (io), 120 PT7E (io), 121 PT7C (io), 122 PT7A (io), 124 PT6B/PCLK0_1 (io), 125 PT6A (io), 126 PT5C (io), 127 PT5B/PCLK0_0 (io), 130 PT4D (io), 131 PT4B (io), 132 PT4A (io), 133 PT3F (io), 134 PT3D (io), 137 PT3B (io), 138 PT2F (io), 139 PT3A (io), 140 PT2D (io), 141 PT2E (io), 142 PT2B (io), 143 PT2C (io), 144 PT2A (io)
part B pins: 73 PR11D (io), 74 PR11B (io), 75 PR11C (io), 76 PR10D (io), 77 PR11A (io), 78 PR10B (io), 79 PR10C (io), 80 PR10A (io), 81 PR9D (io), 84 PR9A (io), 85 PR8C (io), 86 PR8A (io), 87 PR7D (io), 89 PR7B (io), 90 PR7A (io), 91 PR6D (io), 92 PR6C (io), 94 PR5D (io), 95 PR5B (io), 96 PR4D (io), 97 PR4B (io), 100 PR4A (io), 101 PR3D (io), 102 PR3C (io), 103 PR3B (io), 104 PR2D (io), 105 PR3A (io), 106 PR2B (io), 107 PR2C (io), 108 PR2A (io)
part C pins: 40 PB2C (io), 41 PB3A (io), 43 PB3B (io), 44 PB3C (io), 45 PB3D (io), 46 PB4A (io), 48 PB4B (io), 49 PB4C (io), 50 PB4D (io), 54 PB5A (io), 55 PB5B/PCLK2_1 (io), 56 PB5D (io), 57 PB6A (io), 58 PB6B/PCLK2_0 (io), 60 PB7C (io), 61 PB7E (io), 62 PB8A (io), 65 PB8C (io), 66 PB8D (io), 67 PB9A (io), 68 PB9C (io), 69 PB9B (io), 71 PB9D (io), 72 PB9F (io)
part D pins: 1 PL2A (io), 2 PL2C (io), 3 PL2B (io), 4 PL3A (io), 5 PL2D (io), 6 PL3B (io), 7 PL3C (io), 8 PL3D (io), 9 PL4A (io), 12 PL4D (io), 13 PL5A (io), 14 PL5B/GSRN (io), 15 PL5D (io), 17 PL6C (io), 18 PL6D (io), 19 PL7A (io), 20 PL7B (io), 22 PL8A (io), 23 PL8B (io), 24 PL8C/TSALL (io), 25 PL9C (io), 28 PL9D (io), 29 PL10A (io), 30 PL10B (io), 31 PL10C (io), 32 PL11A (io), 33 PL10D (io), 34 PL11C (io), 35 PL11B (io), 36 PL11D (io)
part E pins: 39 TMS (in) "Powered by VCCIO2", 42 TCK (in) "Powered by VCCIO2", 47 TDO (out) "Powered by VCCIO2", 51 TDI (in) "Powered by VCCIO2", 70 NC
part F pins: 10 VCCIO3 (power), 21 VCC (power), 26 VCCIO3 (power), 38 VCCIO2 (power), 52 VCC (power), 53 VCCAUX (power), 63 VCCIO2 (power), 82 VCCIO1 (power), 93 VCC (power), 98 VCCIO1 (power), 117 VCCIO0 (power), 128 VCCAUX (power), 129 VCC (power), 135 VCCIO0 (power)
part G pins: 11 GNDIO3 (power), 16 GND (power), 27 GNDIO3 (power), 37 GNDIO2 (power), 59 GND (power), 64 GNDIO2 (power), 83 GNDIO1 (power), 88 GND (power), 99 GNDIO1 (power), 118 GNDIO0 (power), 123 GND (power), 136 GNDIO0 (power)

## LCMXO640E-5TN144CES
designator U?
MachXO 640 Crossover PLD, 1.2V, 113 User I/Os, 144-Pins TQFP, Speed Grade-5, Commercial Grade, Pb-Free, Engineering Sample
footprint TQFP144_N (Thin QFP, 144-Leads, Body 20x20mm, Pitch 0.5mm, IPC Medium Density)
footprint TQFP144_L (Thin QFP, 144-Leads, Body 20x20mm, Pitch 0.5mm, IPC High Density)
footprint TQFP144_M (Thin QFP, 144-Leads, Body 20x20mm, Pitch 0.5mm, IPC Low Density)
3D model MachXO640-TQFP144 (144-Pin Thin Quad Flat Pack (TQFP144))
signal-integrity model LCMXO640E_T144 (MachXO)
part A pins: 109 PT9F (io), 110 PT9D (io), 111 PT9E (io), 112 PT9B (io), 113 PT9C (io), 114 PT9A (io), 115 PT8C (io), 116 PT8B (io), 119 PT8A (io), 120 PT7E (io), 121 PT7C (io), 122 PT7A (io), 124 PT6B/PCLK0_1 (io), 125 PT6A (io), 126 PT5C (io), 127 PT5B/PCLK0_0 (io), 130 PT4D (io), 131 PT4B (io), 132 PT4A (io), 133 PT3F (io), 134 PT3D (io), 137 PT3B (io), 138 PT2F (io), 139 PT3A (io), 140 PT2D (io), 141 PT2E (io), 142 PT2B (io), 143 PT2C (io), 144 PT2A (io)
part B pins: 73 PR11D (io), 74 PR11B (io), 75 PR11C (io), 76 PR10D (io), 77 PR11A (io), 78 PR10B (io), 79 PR10C (io), 80 PR10A (io), 81 PR9D (io), 84 PR9A (io), 85 PR8C (io), 86 PR8A (io), 87 PR7D (io), 89 PR7B (io), 90 PR7A (io), 91 PR6D (io), 92 PR6C (io), 94 PR5D (io), 95 PR5B (io), 96 PR4D (io), 97 PR4B (io), 100 PR4A (io), 101 PR3D (io), 102 PR3C (io), 103 PR3B (io), 104 PR2D (io), 105 PR3A (io), 106 PR2B (io), 107 PR2C (io), 108 PR2A (io)
part C pins: 40 PB2C (io), 41 PB3A (io), 43 PB3B (io), 44 PB3C (io), 45 PB3D (io), 46 PB4A (io), 48 PB4B (io), 49 PB4C (io), 50 PB4D (io), 54 PB5A (io), 55 PB5B/PCLK2_1 (io), 56 PB5D (io), 57 PB6A (io), 58 PB6B/PCLK2_0 (io), 60 PB7C (io), 61 PB7E (io), 62 PB8A (io), 65 PB8C (io), 66 PB8D (io), 67 PB9A (io), 68 PB9C (io), 69 PB9B (io), 71 PB9D (io), 72 PB9F (io)
part D pins: 1 PL2A (io), 2 PL2C (io), 3 PL2B (io), 4 PL3A (io), 5 PL2D (io), 6 PL3B (io), 7 PL3C (io), 8 PL3D (io), 9 PL4A (io), 12 PL4D (io), 13 PL5A (io), 14 PL5B/GSRN (io), 15 PL5D (io), 17 PL6C (io), 18 PL6D (io), 19 PL7A (io), 20 PL7B (io), 22 PL8A (io), 23 PL8B (io), 24 PL8C/TSALL (io), 25 PL9C (io), 28 PL9D (io), 29 PL10A (io), 30 PL10B (io), 31 PL10C (io), 32 PL11A (io), 33 PL10D (io), 34 PL11C (io), 35 PL11B (io), 36 PL11D (io)
part E pins: 39 TMS (in) "Powered by VCCIO2", 42 TCK (in) "Powered by VCCIO2", 47 TDO (out) "Powered by VCCIO2", 51 TDI (in) "Powered by VCCIO2", 70 NC
part F pins: 10 VCCIO3 (power), 21 VCC (power), 26 VCCIO3 (power), 38 VCCIO2 (power), 52 VCC (power), 53 VCCAUX (power), 63 VCCIO2 (power), 82 VCCIO1 (power), 93 VCC (power), 98 VCCIO1 (power), 117 VCCIO0 (power), 128 VCCAUX (power), 129 VCC (power), 135 VCCIO0 (power)
part G pins: 11 GNDIO3 (power), 16 GND (power), 27 GNDIO3 (power), 37 GNDIO2 (power), 59 GND (power), 64 GNDIO2 (power), 83 GNDIO1 (power), 88 GND (power), 99 GNDIO1 (power), 118 GNDIO0 (power), 123 GND (power), 136 GNDIO0 (power)


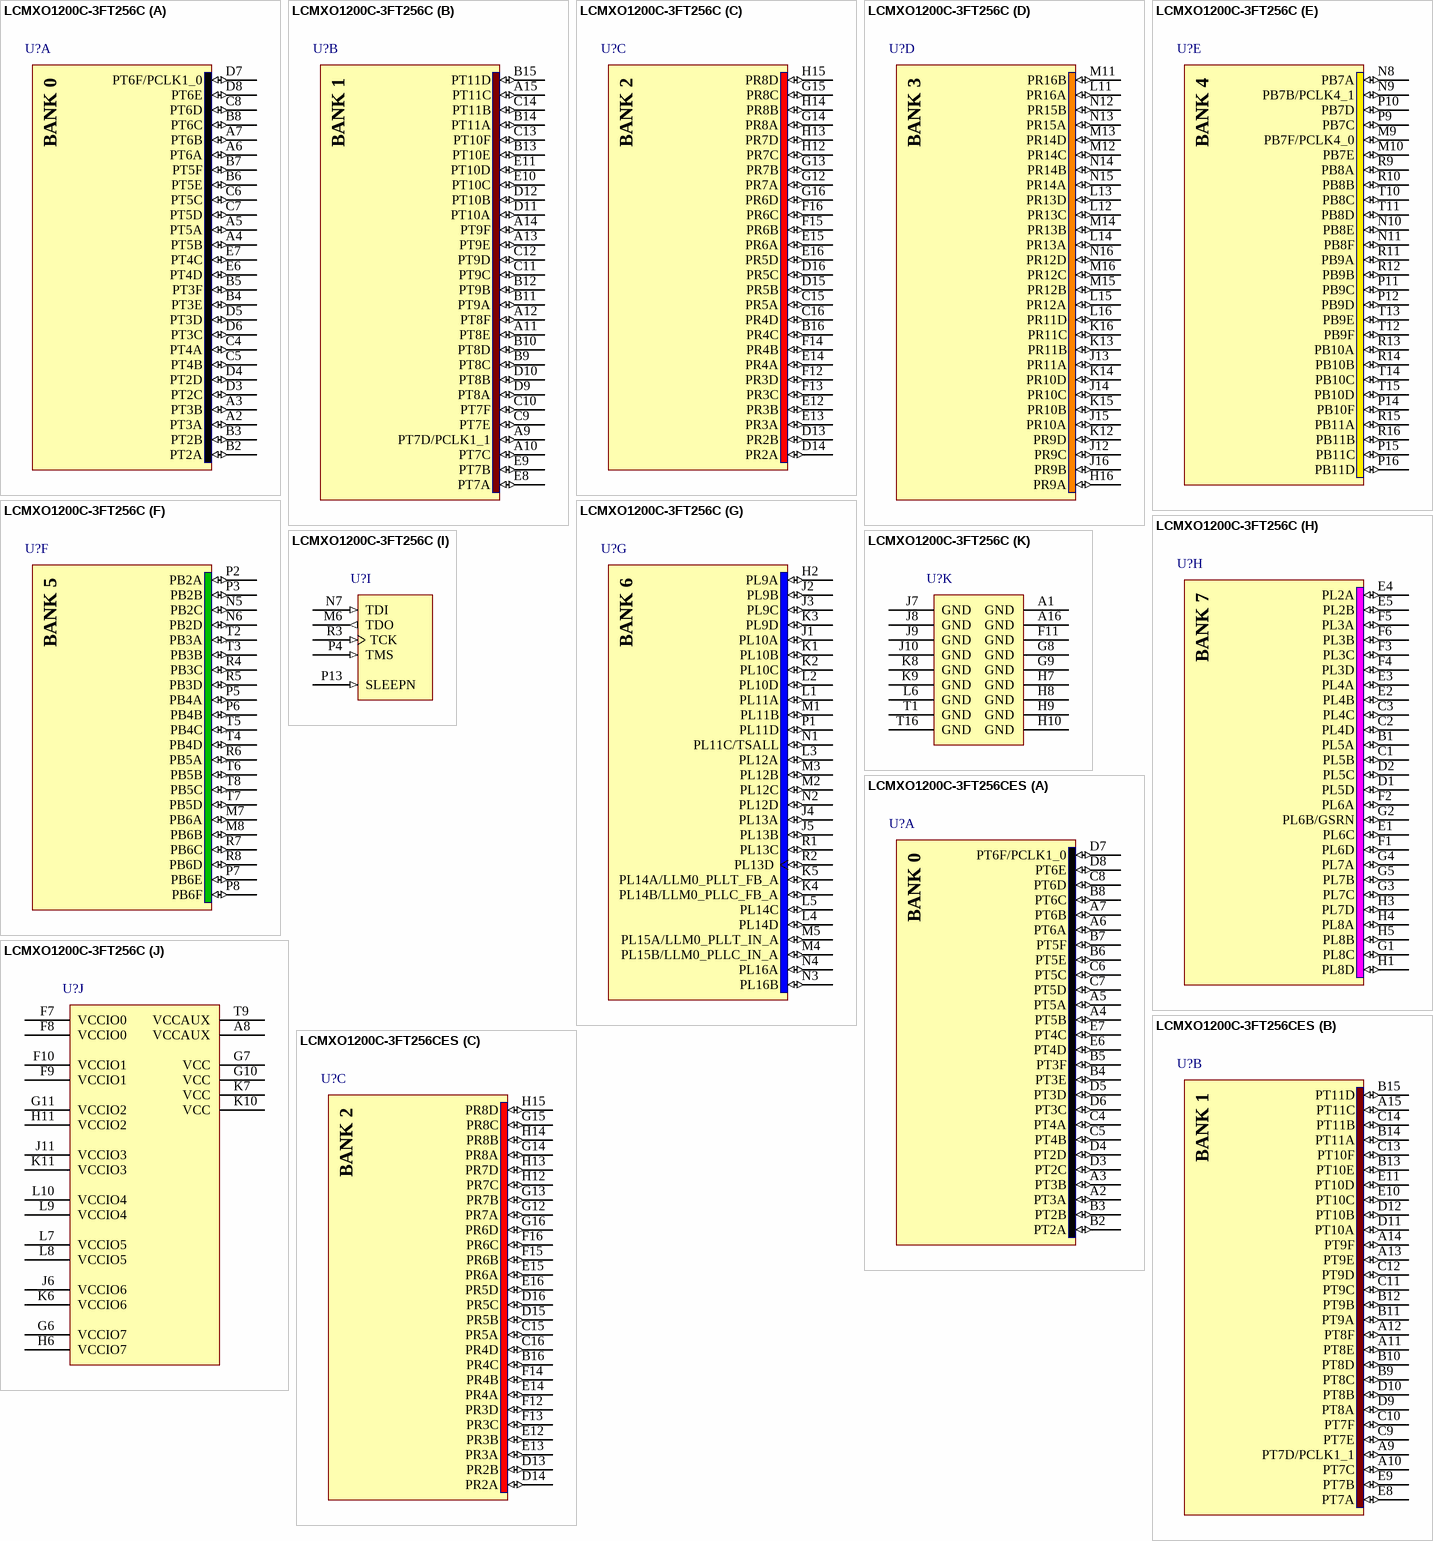
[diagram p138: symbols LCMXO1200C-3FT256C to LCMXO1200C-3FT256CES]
## LCMXO1200C-3FT256C
designator U?
MachXO 1200 Crossover PLD, 1.8V/2.5V/3.3V, 211 User I/Os, 256-Pins ftBGA, Speed Grade-3, Commercial Grade
footprint ftBGA256 (BGA, 256-Leads, Body 17x17mm, Pitch 1mm)
3D model MachXO1200-ftBGA256 (256-Ball Fine Thin Ball Grid Array (ftBGA256))
signal-integrity model LCMXO1200C_FT256 (MachXO)
part A pins: A2 PT3A (io), A3 PT3B (io), A4 PT5B (io), A5 PT5A (io), A6 PT6A (io), A7 PT6B (io), B2 PT2A (io), B3 PT2B (io), B4 PT3E (io), B5 PT3F (io), B6 PT5E (io), B7 PT5F (io), B8 PT6C (io), C4 PT4A (io), C5 PT4B (io), C6 PT5C (io), C7 PT5D (io), C8 PT6D (io), D3 PT2C (io), D4 PT2D (io), D5 PT3D (io), D6 PT3C (io), D7 PT6F/PCLK1_0 (io), D8 PT6E (io), E6 PT4D (io), E7 PT4C (io)
part B pins: A9 PT7D/PCLK1_1 (io), A10 PT7C (io), A11 PT8E (io), A12 PT8F (io), A13 PT9E (io), A14 PT9F (io), A15 PT11C (io), B9 PT8C (io), B10 PT8D (io), B11 PT9A (io), B12 PT9B (io), B13 PT10E (io), B14 PT11A (io), B15 PT11D (io), C9 PT7E (io), C10 PT7F (io), C11 PT9C (io), C12 PT9D (io), C13 PT10F (io), C14 PT11B (io), D9 PT8A (io), D10 PT8B (io), D11 PT10A (io), D12 PT10B (io), E8 PT7A (io), E9 PT7B (io), E10 PT10C (io), E11 PT10D (io)
part C pins: B16 PR4C (io), C15 PR5A (io), C16 PR4D (io), D13 PR2B (io), D14 PR2A (io), D15 PR5B (io), D16 PR5C (io), E12 PR3B (io), E13 PR3A (io), E14 PR4A (io), E15 PR6A (io), E16 PR5D (io), F12 PR3D (io), F13 PR3C (io), F14 PR4B (io), F15 PR6B (io), F16 PR6C (io), G12 PR7A (io), G13 PR7B (io), G14 PR8A (io), G15 PR8C (io), G16 PR6D (io), H12 PR7C (io), H13 PR7D (io), H14 PR8B (io), H15 PR8D (io)
part D pins: H16 PR9A (io), J12 PR9C (io), J13 PR11A (io), J14 PR10C (io), J15 PR10A (io), J16 PR9B (io), K12 PR9D (io), K13 PR11B (io), K14 PR10D (io), K15 PR10B (io), K16 PR11C (io), L11 PR16A (io), L12 PR13C (io), L13 PR13D (io), L14 PR13A (io), L15 PR12A (io), L16 PR11D (io), M11 PR16B (io), M12 PR14C (io), M13 PR14D (io), M14 PR13B (io), M15 PR12B (io), M16 PR12C (io), N12 PR15B (io), N13 PR15A (io), N14 PR14B (io), N15 PR14A (io), N16 PR12D (io)
part E pins: M9 PB7F/PCLK4_0 (io), M10 PB7E (io), N8 PB7A (io), N9 PB7B/PCLK4_1 (io), N10 PB8E (io), N11 PB8F (io), P9 PB7C (io), P10 PB7D (io), P11 PB9C (io), P12 PB9D (io), P14 PB10F (io), P15 PB11C (io), P16 PB11D (io), R9 PB8A (io), R10 PB8B (io), R11 PB9A (io), R12 PB9B (io), R13 PB10A (io), R14 PB10B (io), R15 PB11A (io), R16 PB11B (io), T10 PB8C (io), T11 PB8D (io), T12 PB9F (io), T13 PB9E (io), T14 PB10C (io), T15 PB10D (io)
part F pins: M7 PB6A (io), M8 PB6B (io), N5 PB2C (io), N6 PB2D (io), P2 PB2A (io), P3 PB2B (io), P5 PB4A (io), P6 PB4B (io), P7 PB6E (io), P8 PB6F (io), R4 PB3C (io), R5 PB3D (io), R6 PB5A (io), R7 PB6C (io), R8 PB6D (io), T2 PB3A (io), T3 PB3B (io), T4 PB4D (io), T5 PB4C (io), T6 PB5B (io), T7 PB5D (io), T8 PB5C (io)
part G pins: H2 PL9A (io), J1 PL10A (io), J2 PL9B (io), J3 PL9C (io), J4 PL13A (io), J5 PL13B (io), K1 PL10B (io), K2 PL10C (io), K3 PL9D (io), K4 PL14B/LLM0_PLLC_FB_A (io), K5 PL14A/LLM0_PLLT_FB_A (io), L1 PL11A (io), L2 PL10D (io), L3 PL12A (io), L4 PL14D (io), L5 PL14C (io), M1 PL11B (io), M2 PL12C (io), M3 PL12B (io), M4 PL15B/LLM0_PLLC_IN_A (io), M5 PL15A/LLM0_PLLT_IN_A (io), N1 PL11C/TSALL (io), N2 PL12D (io), N3 PL16B (io), N4 PL16A (io), P1 PL11D (io), R1 PL13C (io), R2 PL13D (io)
part H pins: B1 PL5A (io), C1 PL5B (io), C2 PL4D (io), C3 PL4C (io), D1 PL5D (io), D2 PL5C (io), E1 PL6C (io), E2 PL4B (io), E3 PL4A (io), E4 PL2A (io), E5 PL2B (io), F1 PL6D (io), F2 PL6A (io), F3 PL3C (io), F4 PL3D (io), F5 PL3A (io), F6 PL3B (io), G1 PL8C (io), G2 PL6B/GSRN (io), G3 PL7C (io), G4 PL7A (io), G5 PL7B (io), H1 PL8D (io), H3 PL7D (io), H4 PL8A (io), H5 PL8B (io)
part I pins: M6 TDO (out) "Powered by VCCIO5", N7 TDI (in) "Powered by VCCIO5", P4 TMS (in) "Powered by VCCIO5", P13 SLEEPN (in) "Powered by VCCIO4", R3 TCK (in) "Powered by VCCIO5"
part J pins: A8 VCCAUX (power), F7 VCCIO0 (power), F8 VCCIO0 (power), F9 VCCIO1 (power), F10 VCCIO1 (power), G6 VCCIO7 (power), G7 VCC (power), G10 VCC (power), G11 VCCIO2 (power), H6 VCCIO7 (power), H11 VCCIO2 (power), J6 VCCIO6 (power), J11 VCCIO3 (power), K6 VCCIO6 (power), K7 VCC (power), K10 VCC (power), K11 VCCIO3 (power), L7 VCCIO5 (power), L8 VCCIO5 (power), L9 VCCIO4 (power), L10 VCCIO4 (power), T9 VCCAUX (power)
part K pins: A1 GND (power), A16 GND (power), F11 GND (power), G8 GND (power), G9 GND (power), H7 GND (power), H8 GND (power), H9 GND (power), H10 GND (power), J7 GND (power), J8 GND (power), J9 GND (power), J10 GND (power), K8 GND (power), K9 GND (power), L6 GND (power), T1 GND (power), T16 GND (power)


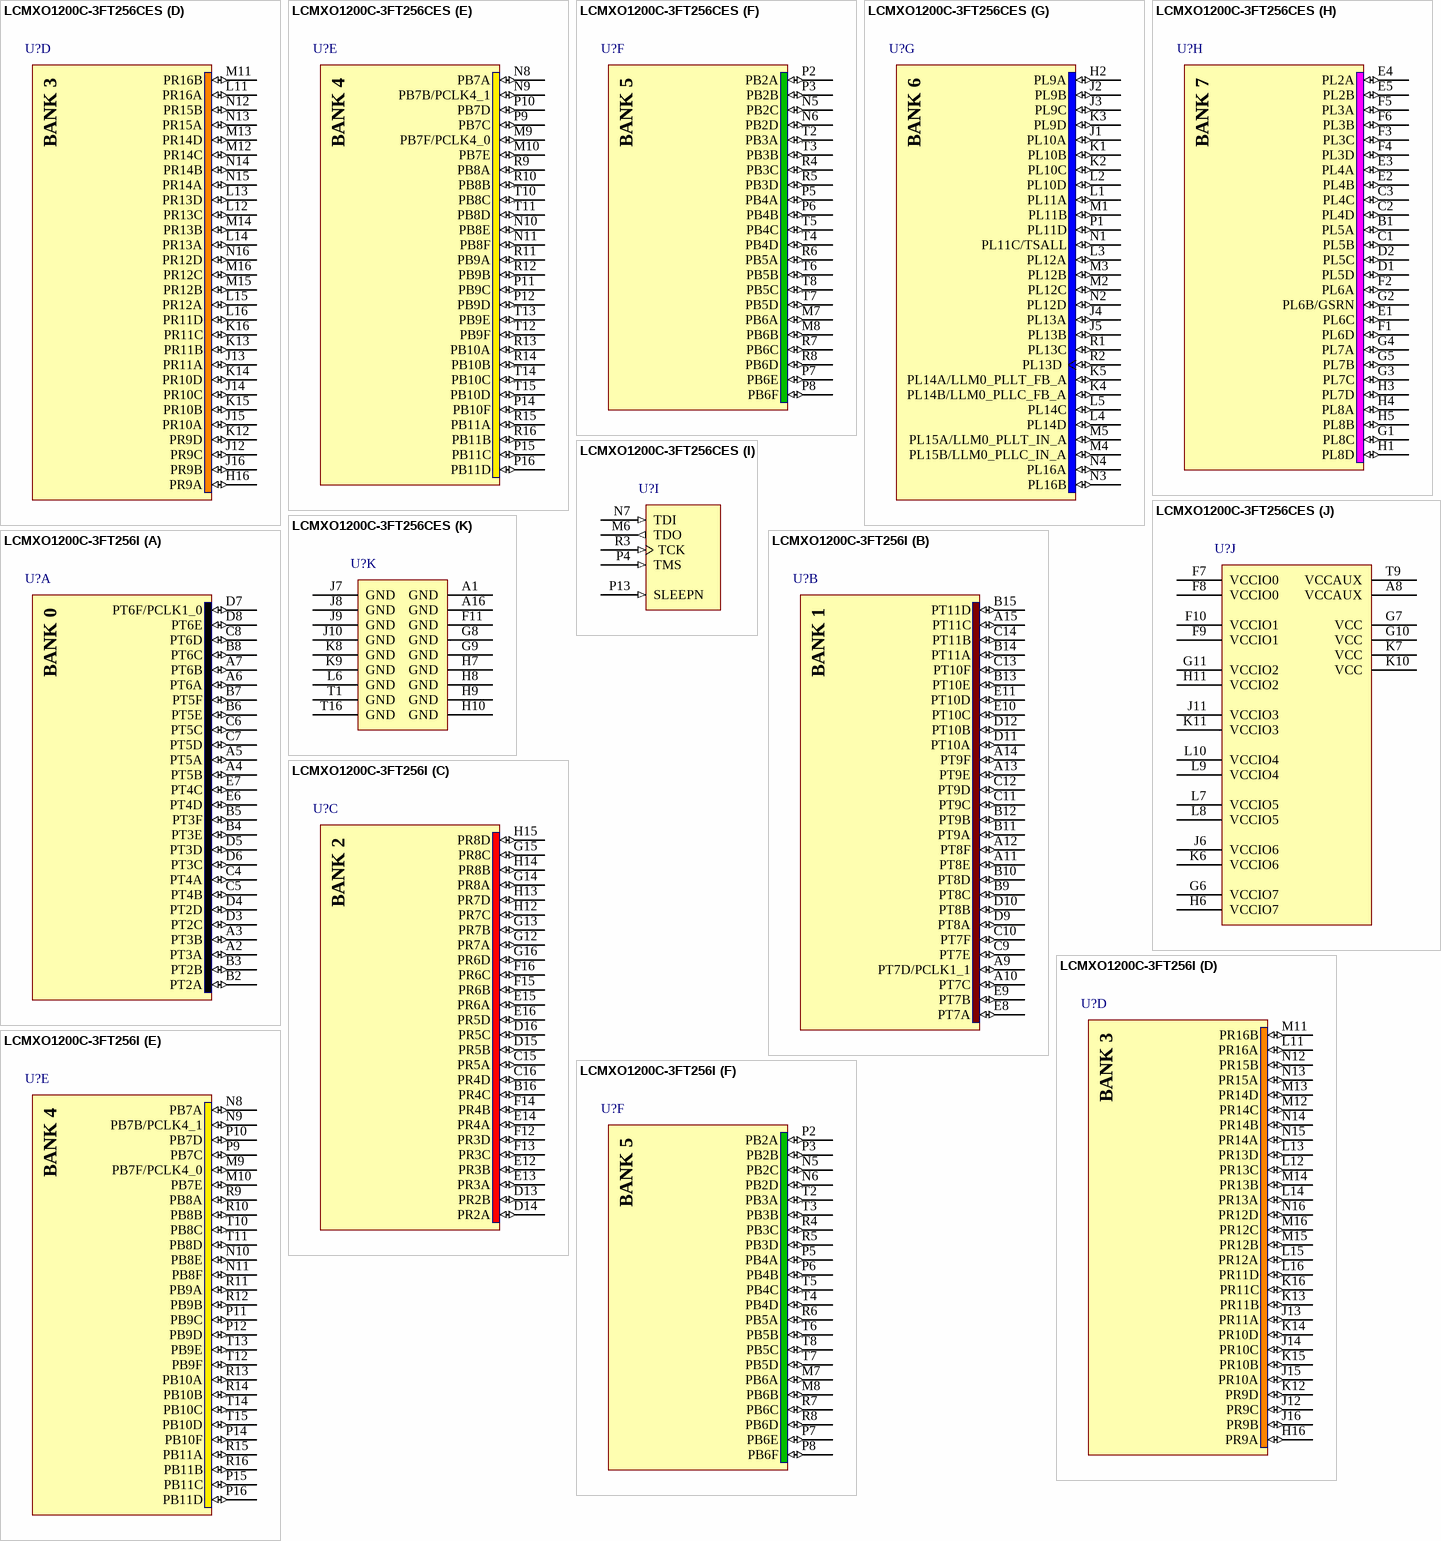
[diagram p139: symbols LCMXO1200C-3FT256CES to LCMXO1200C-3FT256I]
## LCMXO1200C-3FT256CES
designator U?
MachXO 1200 Crossover PLD, 1.8V/2.5V/3.3V, 211 User I/Os, 256-Pins ftBGA, Speed Grade-3, Commercial Grade, Engineering Sample
footprint ftBGA256 (BGA, 256-Leads, Body 17x17mm, Pitch 1mm)
3D model MachXO1200-ftBGA256 (256-Ball Fine Thin Ball Grid Array (ftBGA256))
signal-integrity model LCMXO1200C_FT256 (MachXO)
part A pins: A2 PT3A (io), A3 PT3B (io), A4 PT5B (io), A5 PT5A (io), A6 PT6A (io), A7 PT6B (io), B2 PT2A (io), B3 PT2B (io), B4 PT3E (io), B5 PT3F (io), B6 PT5E (io), B7 PT5F (io), B8 PT6C (io), C4 PT4A (io), C5 PT4B (io), C6 PT5C (io), C7 PT5D (io), C8 PT6D (io), D3 PT2C (io), D4 PT2D (io), D5 PT3D (io), D6 PT3C (io), D7 PT6F/PCLK1_0 (io), D8 PT6E (io), E6 PT4D (io), E7 PT4C (io)
part B pins: A9 PT7D/PCLK1_1 (io), A10 PT7C (io), A11 PT8E (io), A12 PT8F (io), A13 PT9E (io), A14 PT9F (io), A15 PT11C (io), B9 PT8C (io), B10 PT8D (io), B11 PT9A (io), B12 PT9B (io), B13 PT10E (io), B14 PT11A (io), B15 PT11D (io), C9 PT7E (io), C10 PT7F (io), C11 PT9C (io), C12 PT9D (io), C13 PT10F (io), C14 PT11B (io), D9 PT8A (io), D10 PT8B (io), D11 PT10A (io), D12 PT10B (io), E8 PT7A (io), E9 PT7B (io), E10 PT10C (io), E11 PT10D (io)
part C pins: B16 PR4C (io), C15 PR5A (io), C16 PR4D (io), D13 PR2B (io), D14 PR2A (io), D15 PR5B (io), D16 PR5C (io), E12 PR3B (io), E13 PR3A (io), E14 PR4A (io), E15 PR6A (io), E16 PR5D (io), F12 PR3D (io), F13 PR3C (io), F14 PR4B (io), F15 PR6B (io), F16 PR6C (io), G12 PR7A (io), G13 PR7B (io), G14 PR8A (io), G15 PR8C (io), G16 PR6D (io), H12 PR7C (io), H13 PR7D (io), H14 PR8B (io), H15 PR8D (io)
part D pins: H16 PR9A (io), J12 PR9C (io), J13 PR11A (io), J14 PR10C (io), J15 PR10A (io), J16 PR9B (io), K12 PR9D (io), K13 PR11B (io), K14 PR10D (io), K15 PR10B (io), K16 PR11C (io), L11 PR16A (io), L12 PR13C (io), L13 PR13D (io), L14 PR13A (io), L15 PR12A (io), L16 PR11D (io), M11 PR16B (io), M12 PR14C (io), M13 PR14D (io), M14 PR13B (io), M15 PR12B (io), M16 PR12C (io), N12 PR15B (io), N13 PR15A (io), N14 PR14B (io), N15 PR14A (io), N16 PR12D (io)
part E pins: M9 PB7F/PCLK4_0 (io), M10 PB7E (io), N8 PB7A (io), N9 PB7B/PCLK4_1 (io), N10 PB8E (io), N11 PB8F (io), P9 PB7C (io), P10 PB7D (io), P11 PB9C (io), P12 PB9D (io), P14 PB10F (io), P15 PB11C (io), P16 PB11D (io), R9 PB8A (io), R10 PB8B (io), R11 PB9A (io), R12 PB9B (io), R13 PB10A (io), R14 PB10B (io), R15 PB11A (io), R16 PB11B (io), T10 PB8C (io), T11 PB8D (io), T12 PB9F (io), T13 PB9E (io), T14 PB10C (io), T15 PB10D (io)
part F pins: M7 PB6A (io), M8 PB6B (io), N5 PB2C (io), N6 PB2D (io), P2 PB2A (io), P3 PB2B (io), P5 PB4A (io), P6 PB4B (io), P7 PB6E (io), P8 PB6F (io), R4 PB3C (io), R5 PB3D (io), R6 PB5A (io), R7 PB6C (io), R8 PB6D (io), T2 PB3A (io), T3 PB3B (io), T4 PB4D (io), T5 PB4C (io), T6 PB5B (io), T7 PB5D (io), T8 PB5C (io)
part G pins: H2 PL9A (io), J1 PL10A (io), J2 PL9B (io), J3 PL9C (io), J4 PL13A (io), J5 PL13B (io), K1 PL10B (io), K2 PL10C (io), K3 PL9D (io), K4 PL14B/LLM0_PLLC_FB_A (io), K5 PL14A/LLM0_PLLT_FB_A (io), L1 PL11A (io), L2 PL10D (io), L3 PL12A (io), L4 PL14D (io), L5 PL14C (io), M1 PL11B (io), M2 PL12C (io), M3 PL12B (io), M4 PL15B/LLM0_PLLC_IN_A (io), M5 PL15A/LLM0_PLLT_IN_A (io), N1 PL11C/TSALL (io), N2 PL12D (io), N3 PL16B (io), N4 PL16A (io), P1 PL11D (io), R1 PL13C (io), R2 PL13D (io)
part H pins: B1 PL5A (io), C1 PL5B (io), C2 PL4D (io), C3 PL4C (io), D1 PL5D (io), D2 PL5C (io), E1 PL6C (io), E2 PL4B (io), E3 PL4A (io), E4 PL2A (io), E5 PL2B (io), F1 PL6D (io), F2 PL6A (io), F3 PL3C (io), F4 PL3D (io), F5 PL3A (io), F6 PL3B (io), G1 PL8C (io), G2 PL6B/GSRN (io), G3 PL7C (io), G4 PL7A (io), G5 PL7B (io), H1 PL8D (io), H3 PL7D (io), H4 PL8A (io), H5 PL8B (io)
part I pins: M6 TDO (out) "Powered by VCCIO5", N7 TDI (in) "Powered by VCCIO5", P4 TMS (in) "Powered by VCCIO5", P13 SLEEPN (in) "Powered by VCCIO4", R3 TCK (in) "Powered by VCCIO5"
part J pins: A8 VCCAUX (power), F7 VCCIO0 (power), F8 VCCIO0 (power), F9 VCCIO1 (power), F10 VCCIO1 (power), G6 VCCIO7 (power), G7 VCC (power), G10 VCC (power), G11 VCCIO2 (power), H6 VCCIO7 (power), H11 VCCIO2 (power), J6 VCCIO6 (power), J11 VCCIO3 (power), K6 VCCIO6 (power), K7 VCC (power), K10 VCC (power), K11 VCCIO3 (power), L7 VCCIO5 (power), L8 VCCIO5 (power), L9 VCCIO4 (power), L10 VCCIO4 (power), T9 VCCAUX (power)
part K pins: A1 GND (power), A16 GND (power), F11 GND (power), G8 GND (power), G9 GND (power), H7 GND (power), H8 GND (power), H9 GND (power), H10 GND (power), J7 GND (power), J8 GND (power), J9 GND (power), J10 GND (power), K8 GND (power), K9 GND (power), L6 GND (power), T1 GND (power), T16 GND (power)


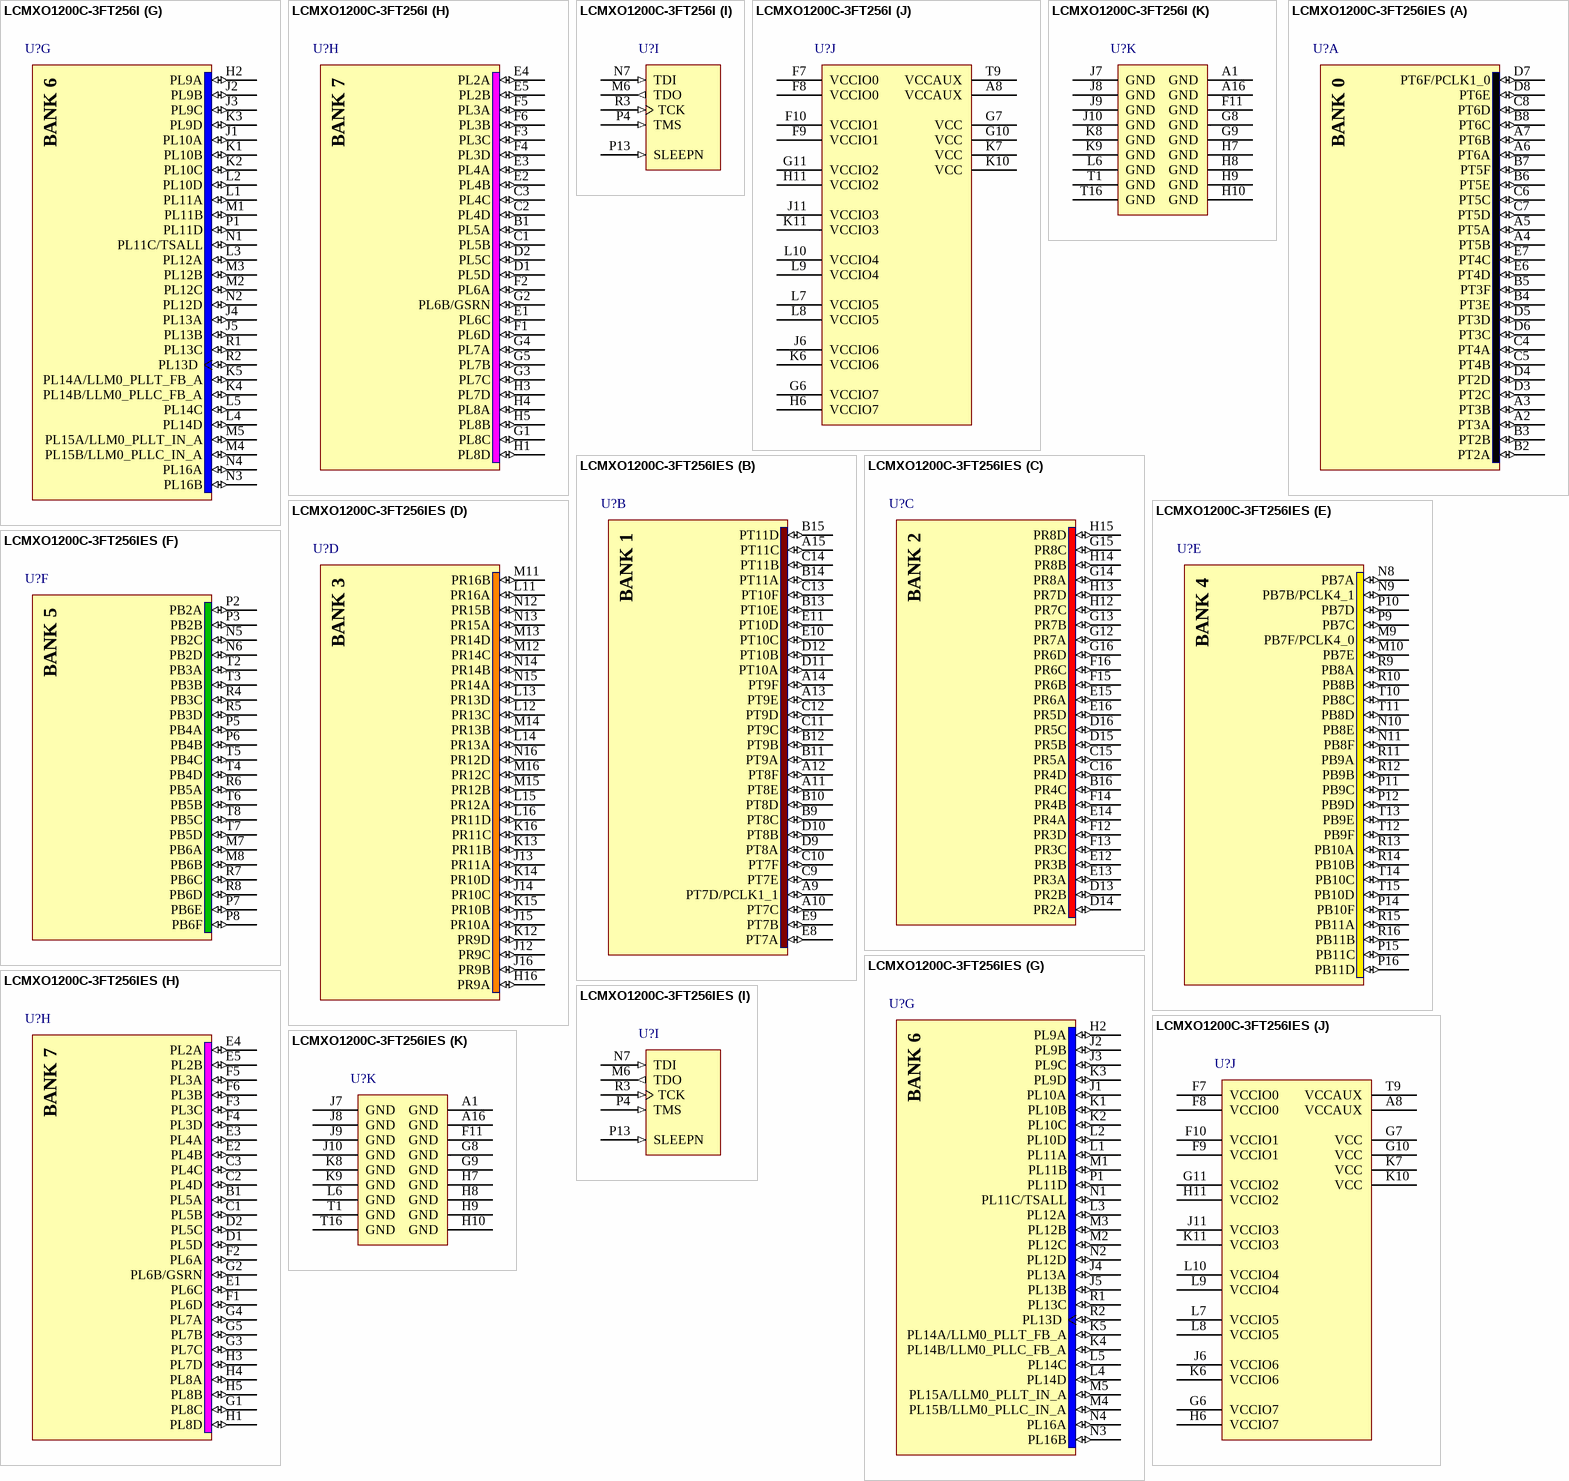
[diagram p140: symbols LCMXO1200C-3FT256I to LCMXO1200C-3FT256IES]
## LCMXO1200C-3FT256I
designator U?
MachXO 1200 Crossover PLD, 1.8V/2.5V/3.3V, 211 User I/Os, 256-Pins ftBGA, Speed Grade-3, Industrial Grade
footprint ftBGA256 (BGA, 256-Leads, Body 17x17mm, Pitch 1mm)
3D model MachXO1200-ftBGA256 (256-Ball Fine Thin Ball Grid Array (ftBGA256))
signal-integrity model LCMXO1200C_FT256 (MachXO)
part A pins: A2 PT3A (io), A3 PT3B (io), A4 PT5B (io), A5 PT5A (io), A6 PT6A (io), A7 PT6B (io), B2 PT2A (io), B3 PT2B (io), B4 PT3E (io), B5 PT3F (io), B6 PT5E (io), B7 PT5F (io), B8 PT6C (io), C4 PT4A (io), C5 PT4B (io), C6 PT5C (io), C7 PT5D (io), C8 PT6D (io), D3 PT2C (io), D4 PT2D (io), D5 PT3D (io), D6 PT3C (io), D7 PT6F/PCLK1_0 (io), D8 PT6E (io), E6 PT4D (io), E7 PT4C (io)
part B pins: A9 PT7D/PCLK1_1 (io), A10 PT7C (io), A11 PT8E (io), A12 PT8F (io), A13 PT9E (io), A14 PT9F (io), A15 PT11C (io), B9 PT8C (io), B10 PT8D (io), B11 PT9A (io), B12 PT9B (io), B13 PT10E (io), B14 PT11A (io), B15 PT11D (io), C9 PT7E (io), C10 PT7F (io), C11 PT9C (io), C12 PT9D (io), C13 PT10F (io), C14 PT11B (io), D9 PT8A (io), D10 PT8B (io), D11 PT10A (io), D12 PT10B (io), E8 PT7A (io), E9 PT7B (io), E10 PT10C (io), E11 PT10D (io)
part C pins: B16 PR4C (io), C15 PR5A (io), C16 PR4D (io), D13 PR2B (io), D14 PR2A (io), D15 PR5B (io), D16 PR5C (io), E12 PR3B (io), E13 PR3A (io), E14 PR4A (io), E15 PR6A (io), E16 PR5D (io), F12 PR3D (io), F13 PR3C (io), F14 PR4B (io), F15 PR6B (io), F16 PR6C (io), G12 PR7A (io), G13 PR7B (io), G14 PR8A (io), G15 PR8C (io), G16 PR6D (io), H12 PR7C (io), H13 PR7D (io), H14 PR8B (io), H15 PR8D (io)
part D pins: H16 PR9A (io), J12 PR9C (io), J13 PR11A (io), J14 PR10C (io), J15 PR10A (io), J16 PR9B (io), K12 PR9D (io), K13 PR11B (io), K14 PR10D (io), K15 PR10B (io), K16 PR11C (io), L11 PR16A (io), L12 PR13C (io), L13 PR13D (io), L14 PR13A (io), L15 PR12A (io), L16 PR11D (io), M11 PR16B (io), M12 PR14C (io), M13 PR14D (io), M14 PR13B (io), M15 PR12B (io), M16 PR12C (io), N12 PR15B (io), N13 PR15A (io), N14 PR14B (io), N15 PR14A (io), N16 PR12D (io)
part E pins: M9 PB7F/PCLK4_0 (io), M10 PB7E (io), N8 PB7A (io), N9 PB7B/PCLK4_1 (io), N10 PB8E (io), N11 PB8F (io), P9 PB7C (io), P10 PB7D (io), P11 PB9C (io), P12 PB9D (io), P14 PB10F (io), P15 PB11C (io), P16 PB11D (io), R9 PB8A (io), R10 PB8B (io), R11 PB9A (io), R12 PB9B (io), R13 PB10A (io), R14 PB10B (io), R15 PB11A (io), R16 PB11B (io), T10 PB8C (io), T11 PB8D (io), T12 PB9F (io), T13 PB9E (io), T14 PB10C (io), T15 PB10D (io)
part F pins: M7 PB6A (io), M8 PB6B (io), N5 PB2C (io), N6 PB2D (io), P2 PB2A (io), P3 PB2B (io), P5 PB4A (io), P6 PB4B (io), P7 PB6E (io), P8 PB6F (io), R4 PB3C (io), R5 PB3D (io), R6 PB5A (io), R7 PB6C (io), R8 PB6D (io), T2 PB3A (io), T3 PB3B (io), T4 PB4D (io), T5 PB4C (io), T6 PB5B (io), T7 PB5D (io), T8 PB5C (io)
part G pins: H2 PL9A (io), J1 PL10A (io), J2 PL9B (io), J3 PL9C (io), J4 PL13A (io), J5 PL13B (io), K1 PL10B (io), K2 PL10C (io), K3 PL9D (io), K4 PL14B/LLM0_PLLC_FB_A (io), K5 PL14A/LLM0_PLLT_FB_A (io), L1 PL11A (io), L2 PL10D (io), L3 PL12A (io), L4 PL14D (io), L5 PL14C (io), M1 PL11B (io), M2 PL12C (io), M3 PL12B (io), M4 PL15B/LLM0_PLLC_IN_A (io), M5 PL15A/LLM0_PLLT_IN_A (io), N1 PL11C/TSALL (io), N2 PL12D (io), N3 PL16B (io), N4 PL16A (io), P1 PL11D (io), R1 PL13C (io), R2 PL13D (io)
part H pins: B1 PL5A (io), C1 PL5B (io), C2 PL4D (io), C3 PL4C (io), D1 PL5D (io), D2 PL5C (io), E1 PL6C (io), E2 PL4B (io), E3 PL4A (io), E4 PL2A (io), E5 PL2B (io), F1 PL6D (io), F2 PL6A (io), F3 PL3C (io), F4 PL3D (io), F5 PL3A (io), F6 PL3B (io), G1 PL8C (io), G2 PL6B/GSRN (io), G3 PL7C (io), G4 PL7A (io), G5 PL7B (io), H1 PL8D (io), H3 PL7D (io), H4 PL8A (io), H5 PL8B (io)
part I pins: M6 TDO (out) "Powered by VCCIO5", N7 TDI (in) "Powered by VCCIO5", P4 TMS (in) "Powered by VCCIO5", P13 SLEEPN (in) "Powered by VCCIO4", R3 TCK (in) "Powered by VCCIO5"
part J pins: A8 VCCAUX (power), F7 VCCIO0 (power), F8 VCCIO0 (power), F9 VCCIO1 (power), F10 VCCIO1 (power), G6 VCCIO7 (power), G7 VCC (power), G10 VCC (power), G11 VCCIO2 (power), H6 VCCIO7 (power), H11 VCCIO2 (power), J6 VCCIO6 (power), J11 VCCIO3 (power), K6 VCCIO6 (power), K7 VCC (power), K10 VCC (power), K11 VCCIO3 (power), L7 VCCIO5 (power), L8 VCCIO5 (power), L9 VCCIO4 (power), L10 VCCIO4 (power), T9 VCCAUX (power)
part K pins: A1 GND (power), A16 GND (power), F11 GND (power), G8 GND (power), G9 GND (power), H7 GND (power), H8 GND (power), H9 GND (power), H10 GND (power), J7 GND (power), J8 GND (power), J9 GND (power), J10 GND (power), K8 GND (power), K9 GND (power), L6 GND (power), T1 GND (power), T16 GND (power)

## LCMXO1200C-3FT256IES
designator U?
MachXO 1200 Crossover PLD, 1.8V/2.5V/3.3V, 211 User I/Os, 256-Pins ftBGA, Speed Grade-3, Industrial Grade, Engineering Sample
footprint ftBGA256 (BGA, 256-Leads, Body 17x17mm, Pitch 1mm)
3D model MachXO1200-ftBGA256 (256-Ball Fine Thin Ball Grid Array (ftBGA256))
signal-integrity model LCMXO1200C_FT256 (MachXO)
part A pins: A2 PT3A (io), A3 PT3B (io), A4 PT5B (io), A5 PT5A (io), A6 PT6A (io), A7 PT6B (io), B2 PT2A (io), B3 PT2B (io), B4 PT3E (io), B5 PT3F (io), B6 PT5E (io), B7 PT5F (io), B8 PT6C (io), C4 PT4A (io), C5 PT4B (io), C6 PT5C (io), C7 PT5D (io), C8 PT6D (io), D3 PT2C (io), D4 PT2D (io), D5 PT3D (io), D6 PT3C (io), D7 PT6F/PCLK1_0 (io), D8 PT6E (io), E6 PT4D (io), E7 PT4C (io)
part B pins: A9 PT7D/PCLK1_1 (io), A10 PT7C (io), A11 PT8E (io), A12 PT8F (io), A13 PT9E (io), A14 PT9F (io), A15 PT11C (io), B9 PT8C (io), B10 PT8D (io), B11 PT9A (io), B12 PT9B (io), B13 PT10E (io), B14 PT11A (io), B15 PT11D (io), C9 PT7E (io), C10 PT7F (io), C11 PT9C (io), C12 PT9D (io), C13 PT10F (io), C14 PT11B (io), D9 PT8A (io), D10 PT8B (io), D11 PT10A (io), D12 PT10B (io), E8 PT7A (io), E9 PT7B (io), E10 PT10C (io), E11 PT10D (io)
part C pins: B16 PR4C (io), C15 PR5A (io), C16 PR4D (io), D13 PR2B (io), D14 PR2A (io), D15 PR5B (io), D16 PR5C (io), E12 PR3B (io), E13 PR3A (io), E14 PR4A (io), E15 PR6A (io), E16 PR5D (io), F12 PR3D (io), F13 PR3C (io), F14 PR4B (io), F15 PR6B (io), F16 PR6C (io), G12 PR7A (io), G13 PR7B (io), G14 PR8A (io), G15 PR8C (io), G16 PR6D (io), H12 PR7C (io), H13 PR7D (io), H14 PR8B (io), H15 PR8D (io)
part D pins: H16 PR9A (io), J12 PR9C (io), J13 PR11A (io), J14 PR10C (io), J15 PR10A (io), J16 PR9B (io), K12 PR9D (io), K13 PR11B (io), K14 PR10D (io), K15 PR10B (io), K16 PR11C (io), L11 PR16A (io), L12 PR13C (io), L13 PR13D (io), L14 PR13A (io), L15 PR12A (io), L16 PR11D (io), M11 PR16B (io), M12 PR14C (io), M13 PR14D (io), M14 PR13B (io), M15 PR12B (io), M16 PR12C (io), N12 PR15B (io), N13 PR15A (io), N14 PR14B (io), N15 PR14A (io), N16 PR12D (io)
part E pins: M9 PB7F/PCLK4_0 (io), M10 PB7E (io), N8 PB7A (io), N9 PB7B/PCLK4_1 (io), N10 PB8E (io), N11 PB8F (io), P9 PB7C (io), P10 PB7D (io), P11 PB9C (io), P12 PB9D (io), P14 PB10F (io), P15 PB11C (io), P16 PB11D (io), R9 PB8A (io), R10 PB8B (io), R11 PB9A (io), R12 PB9B (io), R13 PB10A (io), R14 PB10B (io), R15 PB11A (io), R16 PB11B (io), T10 PB8C (io), T11 PB8D (io), T12 PB9F (io), T13 PB9E (io), T14 PB10C (io), T15 PB10D (io)
part F pins: M7 PB6A (io), M8 PB6B (io), N5 PB2C (io), N6 PB2D (io), P2 PB2A (io), P3 PB2B (io), P5 PB4A (io), P6 PB4B (io), P7 PB6E (io), P8 PB6F (io), R4 PB3C (io), R5 PB3D (io), R6 PB5A (io), R7 PB6C (io), R8 PB6D (io), T2 PB3A (io), T3 PB3B (io), T4 PB4D (io), T5 PB4C (io), T6 PB5B (io), T7 PB5D (io), T8 PB5C (io)
part G pins: H2 PL9A (io), J1 PL10A (io), J2 PL9B (io), J3 PL9C (io), J4 PL13A (io), J5 PL13B (io), K1 PL10B (io), K2 PL10C (io), K3 PL9D (io), K4 PL14B/LLM0_PLLC_FB_A (io), K5 PL14A/LLM0_PLLT_FB_A (io), L1 PL11A (io), L2 PL10D (io), L3 PL12A (io), L4 PL14D (io), L5 PL14C (io), M1 PL11B (io), M2 PL12C (io), M3 PL12B (io), M4 PL15B/LLM0_PLLC_IN_A (io), M5 PL15A/LLM0_PLLT_IN_A (io), N1 PL11C/TSALL (io), N2 PL12D (io), N3 PL16B (io), N4 PL16A (io), P1 PL11D (io), R1 PL13C (io), R2 PL13D (io)
part H pins: B1 PL5A (io), C1 PL5B (io), C2 PL4D (io), C3 PL4C (io), D1 PL5D (io), D2 PL5C (io), E1 PL6C (io), E2 PL4B (io), E3 PL4A (io), E4 PL2A (io), E5 PL2B (io), F1 PL6D (io), F2 PL6A (io), F3 PL3C (io), F4 PL3D (io), F5 PL3A (io), F6 PL3B (io), G1 PL8C (io), G2 PL6B/GSRN (io), G3 PL7C (io), G4 PL7A (io), G5 PL7B (io), H1 PL8D (io), H3 PL7D (io), H4 PL8A (io), H5 PL8B (io)
part I pins: M6 TDO (out) "Powered by VCCIO5", N7 TDI (in) "Powered by VCCIO5", P4 TMS (in) "Powered by VCCIO5", P13 SLEEPN (in) "Powered by VCCIO4", R3 TCK (in) "Powered by VCCIO5"
part J pins: A8 VCCAUX (power), F7 VCCIO0 (power), F8 VCCIO0 (power), F9 VCCIO1 (power), F10 VCCIO1 (power), G6 VCCIO7 (power), G7 VCC (power), G10 VCC (power), G11 VCCIO2 (power), H6 VCCIO7 (power), H11 VCCIO2 (power), J6 VCCIO6 (power), J11 VCCIO3 (power), K6 VCCIO6 (power), K7 VCC (power), K10 VCC (power), K11 VCCIO3 (power), L7 VCCIO5 (power), L8 VCCIO5 (power), L9 VCCIO4 (power), L10 VCCIO4 (power), T9 VCCAUX (power)
part K pins: A1 GND (power), A16 GND (power), F11 GND (power), G8 GND (power), G9 GND (power), H7 GND (power), H8 GND (power), H9 GND (power), H10 GND (power), J7 GND (power), J8 GND (power), J9 GND (power), J10 GND (power), K8 GND (power), K9 GND (power), L6 GND (power), T1 GND (power), T16 GND (power)


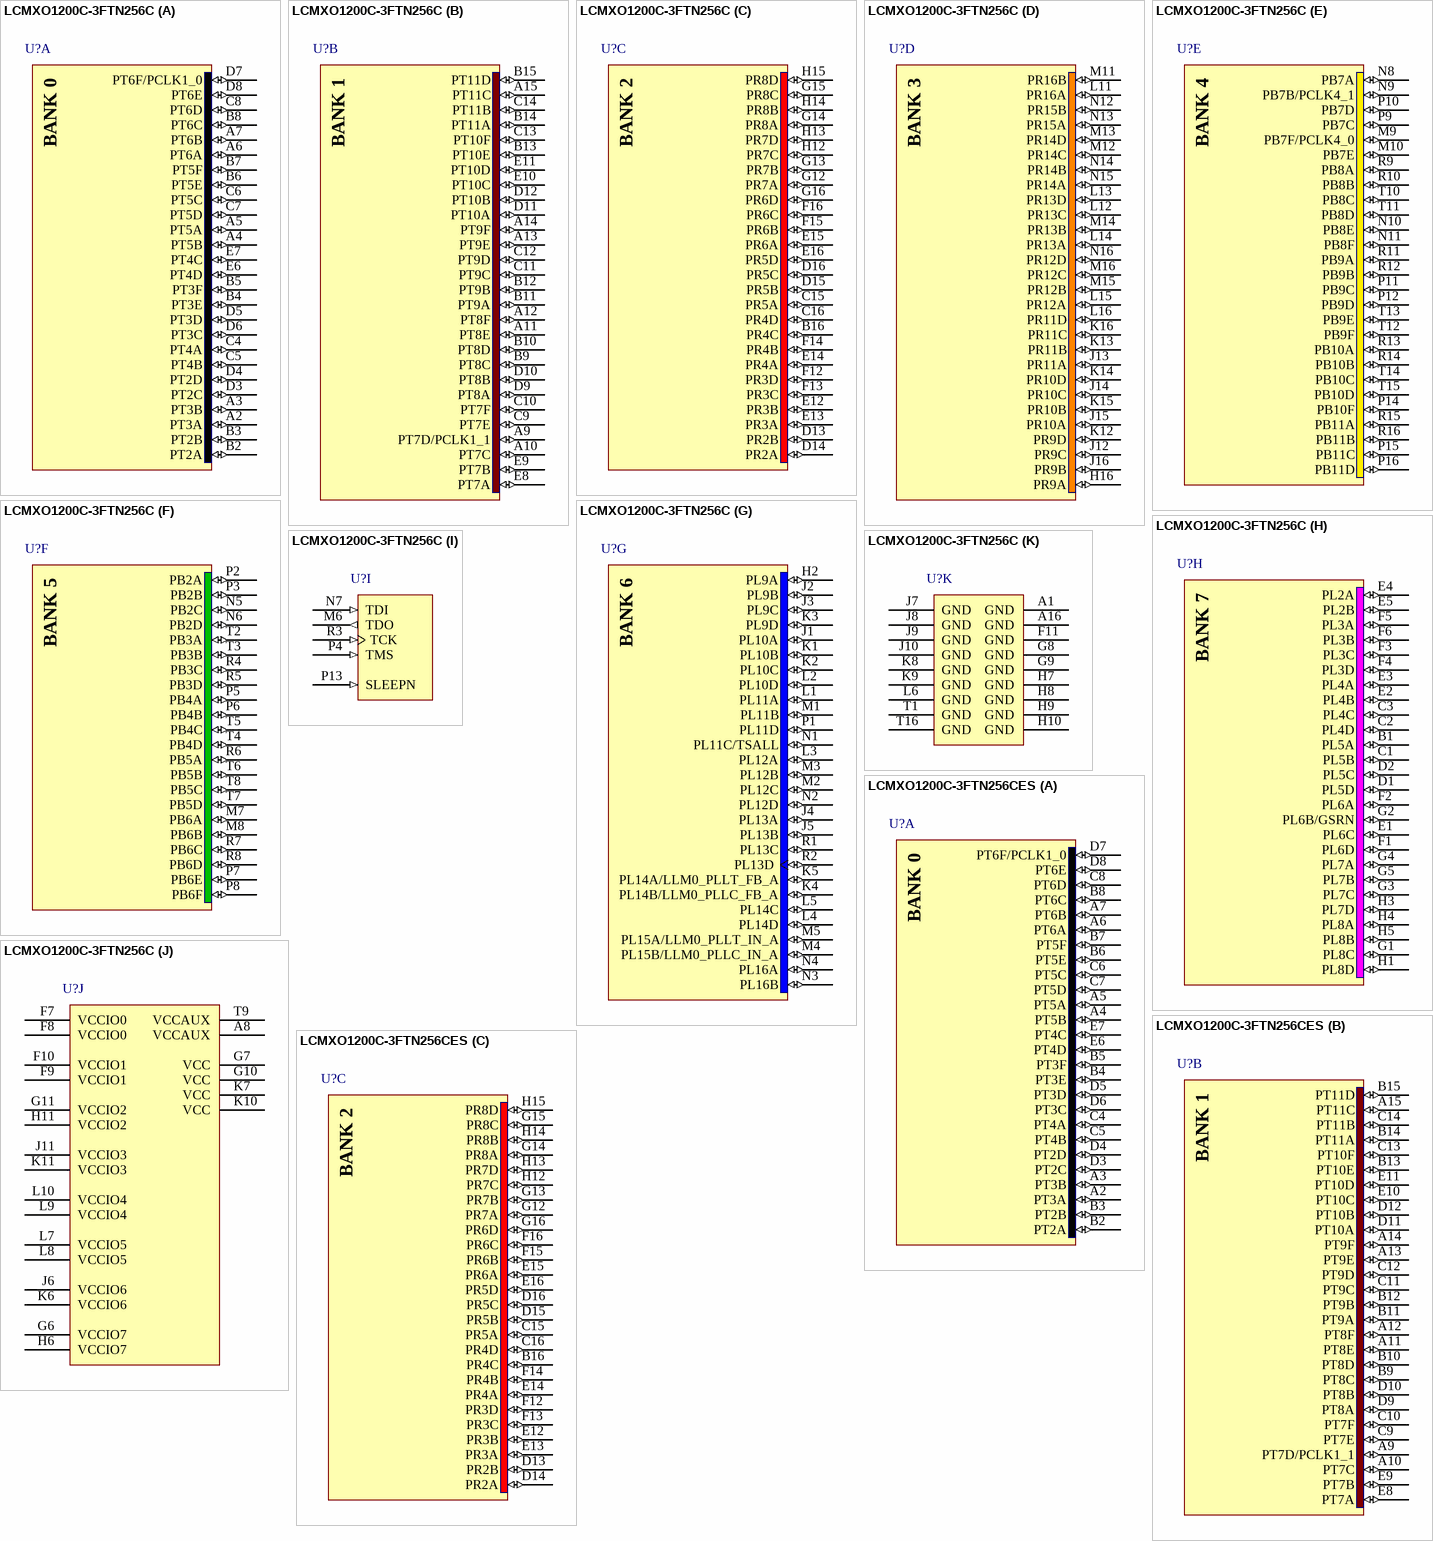
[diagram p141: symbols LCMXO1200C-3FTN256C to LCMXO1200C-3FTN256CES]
## LCMXO1200C-3FTN256C
designator U?
MachXO 1200 Crossover PLD, 1.8V/2.5V/3.3V, 211 User I/Os, 256-Pins ftBGA, Speed Grade-3, Commercial Grade, Pb-Free
footprint ftBGA256 (BGA, 256-Leads, Body 17x17mm, Pitch 1mm)
3D model MachXO1200-ftBGA256 (256-Ball Fine Thin Ball Grid Array (ftBGA256))
signal-integrity model LCMXO1200C_FT256 (MachXO)
part A pins: A2 PT3A (io), A3 PT3B (io), A4 PT5B (io), A5 PT5A (io), A6 PT6A (io), A7 PT6B (io), B2 PT2A (io), B3 PT2B (io), B4 PT3E (io), B5 PT3F (io), B6 PT5E (io), B7 PT5F (io), B8 PT6C (io), C4 PT4A (io), C5 PT4B (io), C6 PT5C (io), C7 PT5D (io), C8 PT6D (io), D3 PT2C (io), D4 PT2D (io), D5 PT3D (io), D6 PT3C (io), D7 PT6F/PCLK1_0 (io), D8 PT6E (io), E6 PT4D (io), E7 PT4C (io)
part B pins: A9 PT7D/PCLK1_1 (io), A10 PT7C (io), A11 PT8E (io), A12 PT8F (io), A13 PT9E (io), A14 PT9F (io), A15 PT11C (io), B9 PT8C (io), B10 PT8D (io), B11 PT9A (io), B12 PT9B (io), B13 PT10E (io), B14 PT11A (io), B15 PT11D (io), C9 PT7E (io), C10 PT7F (io), C11 PT9C (io), C12 PT9D (io), C13 PT10F (io), C14 PT11B (io), D9 PT8A (io), D10 PT8B (io), D11 PT10A (io), D12 PT10B (io), E8 PT7A (io), E9 PT7B (io), E10 PT10C (io), E11 PT10D (io)
part C pins: B16 PR4C (io), C15 PR5A (io), C16 PR4D (io), D13 PR2B (io), D14 PR2A (io), D15 PR5B (io), D16 PR5C (io), E12 PR3B (io), E13 PR3A (io), E14 PR4A (io), E15 PR6A (io), E16 PR5D (io), F12 PR3D (io), F13 PR3C (io), F14 PR4B (io), F15 PR6B (io), F16 PR6C (io), G12 PR7A (io), G13 PR7B (io), G14 PR8A (io), G15 PR8C (io), G16 PR6D (io), H12 PR7C (io), H13 PR7D (io), H14 PR8B (io), H15 PR8D (io)
part D pins: H16 PR9A (io), J12 PR9C (io), J13 PR11A (io), J14 PR10C (io), J15 PR10A (io), J16 PR9B (io), K12 PR9D (io), K13 PR11B (io), K14 PR10D (io), K15 PR10B (io), K16 PR11C (io), L11 PR16A (io), L12 PR13C (io), L13 PR13D (io), L14 PR13A (io), L15 PR12A (io), L16 PR11D (io), M11 PR16B (io), M12 PR14C (io), M13 PR14D (io), M14 PR13B (io), M15 PR12B (io), M16 PR12C (io), N12 PR15B (io), N13 PR15A (io), N14 PR14B (io), N15 PR14A (io), N16 PR12D (io)
part E pins: M9 PB7F/PCLK4_0 (io), M10 PB7E (io), N8 PB7A (io), N9 PB7B/PCLK4_1 (io), N10 PB8E (io), N11 PB8F (io), P9 PB7C (io), P10 PB7D (io), P11 PB9C (io), P12 PB9D (io), P14 PB10F (io), P15 PB11C (io), P16 PB11D (io), R9 PB8A (io), R10 PB8B (io), R11 PB9A (io), R12 PB9B (io), R13 PB10A (io), R14 PB10B (io), R15 PB11A (io), R16 PB11B (io), T10 PB8C (io), T11 PB8D (io), T12 PB9F (io), T13 PB9E (io), T14 PB10C (io), T15 PB10D (io)
part F pins: M7 PB6A (io), M8 PB6B (io), N5 PB2C (io), N6 PB2D (io), P2 PB2A (io), P3 PB2B (io), P5 PB4A (io), P6 PB4B (io), P7 PB6E (io), P8 PB6F (io), R4 PB3C (io), R5 PB3D (io), R6 PB5A (io), R7 PB6C (io), R8 PB6D (io), T2 PB3A (io), T3 PB3B (io), T4 PB4D (io), T5 PB4C (io), T6 PB5B (io), T7 PB5D (io), T8 PB5C (io)
part G pins: H2 PL9A (io), J1 PL10A (io), J2 PL9B (io), J3 PL9C (io), J4 PL13A (io), J5 PL13B (io), K1 PL10B (io), K2 PL10C (io), K3 PL9D (io), K4 PL14B/LLM0_PLLC_FB_A (io), K5 PL14A/LLM0_PLLT_FB_A (io), L1 PL11A (io), L2 PL10D (io), L3 PL12A (io), L4 PL14D (io), L5 PL14C (io), M1 PL11B (io), M2 PL12C (io), M3 PL12B (io), M4 PL15B/LLM0_PLLC_IN_A (io), M5 PL15A/LLM0_PLLT_IN_A (io), N1 PL11C/TSALL (io), N2 PL12D (io), N3 PL16B (io), N4 PL16A (io), P1 PL11D (io), R1 PL13C (io), R2 PL13D (io)
part H pins: B1 PL5A (io), C1 PL5B (io), C2 PL4D (io), C3 PL4C (io), D1 PL5D (io), D2 PL5C (io), E1 PL6C (io), E2 PL4B (io), E3 PL4A (io), E4 PL2A (io), E5 PL2B (io), F1 PL6D (io), F2 PL6A (io), F3 PL3C (io), F4 PL3D (io), F5 PL3A (io), F6 PL3B (io), G1 PL8C (io), G2 PL6B/GSRN (io), G3 PL7C (io), G4 PL7A (io), G5 PL7B (io), H1 PL8D (io), H3 PL7D (io), H4 PL8A (io), H5 PL8B (io)
part I pins: M6 TDO (out) "Powered by VCCIO5", N7 TDI (in) "Powered by VCCIO5", P4 TMS (in) "Powered by VCCIO5", P13 SLEEPN (in) "Powered by VCCIO4", R3 TCK (in) "Powered by VCCIO5"
part J pins: A8 VCCAUX (power), F7 VCCIO0 (power), F8 VCCIO0 (power), F9 VCCIO1 (power), F10 VCCIO1 (power), G6 VCCIO7 (power), G7 VCC (power), G10 VCC (power), G11 VCCIO2 (power), H6 VCCIO7 (power), H11 VCCIO2 (power), J6 VCCIO6 (power), J11 VCCIO3 (power), K6 VCCIO6 (power), K7 VCC (power), K10 VCC (power), K11 VCCIO3 (power), L7 VCCIO5 (power), L8 VCCIO5 (power), L9 VCCIO4 (power), L10 VCCIO4 (power), T9 VCCAUX (power)
part K pins: A1 GND (power), A16 GND (power), F11 GND (power), G8 GND (power), G9 GND (power), H7 GND (power), H8 GND (power), H9 GND (power), H10 GND (power), J7 GND (power), J8 GND (power), J9 GND (power), J10 GND (power), K8 GND (power), K9 GND (power), L6 GND (power), T1 GND (power), T16 GND (power)


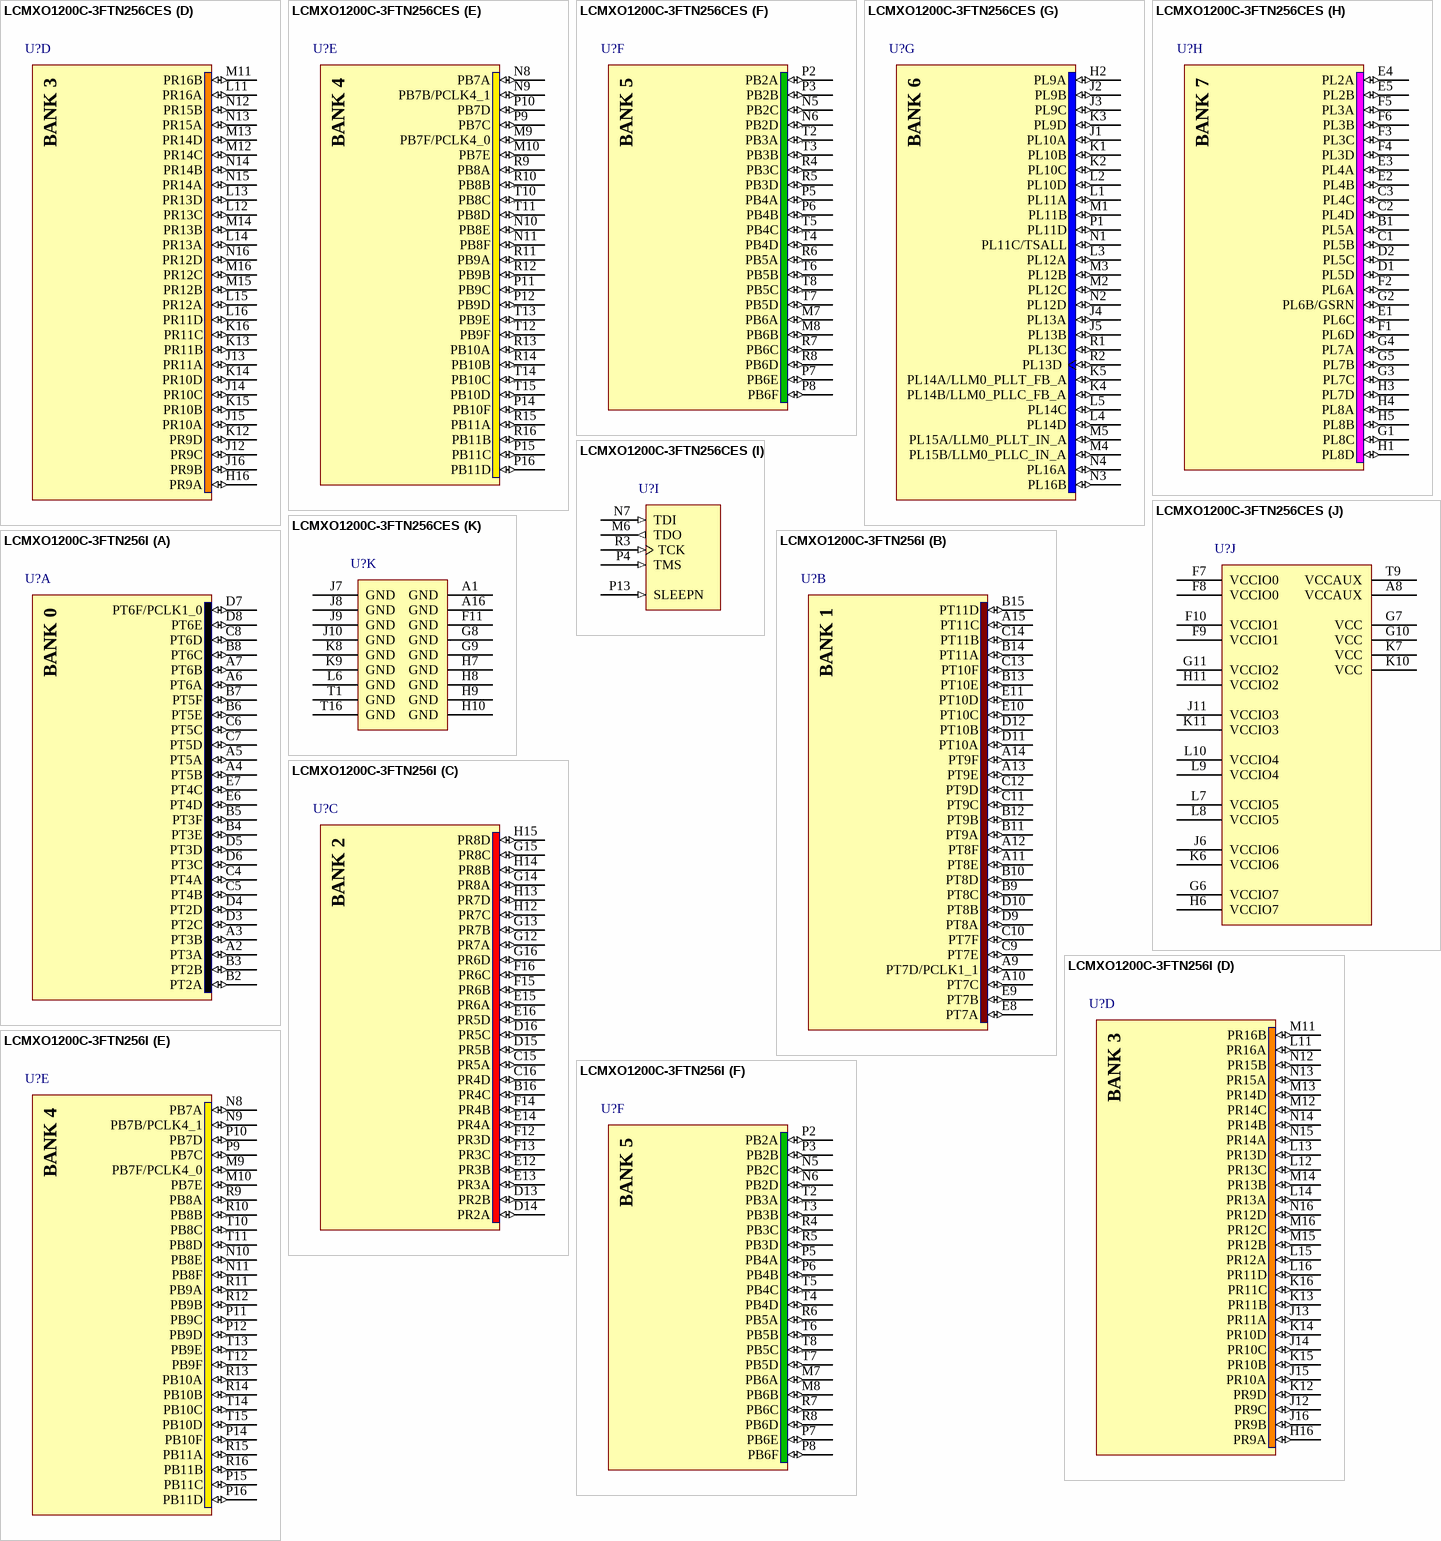
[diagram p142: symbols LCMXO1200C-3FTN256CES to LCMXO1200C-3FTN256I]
## LCMXO1200C-3FTN256CES
designator U?
MachXO 1200 Crossover PLD, 1.8V/2.5V/3.3V, 211 User I/Os, 256-Pins ftBGA, Speed Grade-3, Commercial Grade, Pb-Free, Engineering Sample
footprint ftBGA256 (BGA, 256-Leads, Body 17x17mm, Pitch 1mm)
3D model MachXO1200-ftBGA256 (256-Ball Fine Thin Ball Grid Array (ftBGA256))
signal-integrity model LCMXO1200C_FT256 (MachXO)
part A pins: A2 PT3A (io), A3 PT3B (io), A4 PT5B (io), A5 PT5A (io), A6 PT6A (io), A7 PT6B (io), B2 PT2A (io), B3 PT2B (io), B4 PT3E (io), B5 PT3F (io), B6 PT5E (io), B7 PT5F (io), B8 PT6C (io), C4 PT4A (io), C5 PT4B (io), C6 PT5C (io), C7 PT5D (io), C8 PT6D (io), D3 PT2C (io), D4 PT2D (io), D5 PT3D (io), D6 PT3C (io), D7 PT6F/PCLK1_0 (io), D8 PT6E (io), E6 PT4D (io), E7 PT4C (io)
part B pins: A9 PT7D/PCLK1_1 (io), A10 PT7C (io), A11 PT8E (io), A12 PT8F (io), A13 PT9E (io), A14 PT9F (io), A15 PT11C (io), B9 PT8C (io), B10 PT8D (io), B11 PT9A (io), B12 PT9B (io), B13 PT10E (io), B14 PT11A (io), B15 PT11D (io), C9 PT7E (io), C10 PT7F (io), C11 PT9C (io), C12 PT9D (io), C13 PT10F (io), C14 PT11B (io), D9 PT8A (io), D10 PT8B (io), D11 PT10A (io), D12 PT10B (io), E8 PT7A (io), E9 PT7B (io), E10 PT10C (io), E11 PT10D (io)
part C pins: B16 PR4C (io), C15 PR5A (io), C16 PR4D (io), D13 PR2B (io), D14 PR2A (io), D15 PR5B (io), D16 PR5C (io), E12 PR3B (io), E13 PR3A (io), E14 PR4A (io), E15 PR6A (io), E16 PR5D (io), F12 PR3D (io), F13 PR3C (io), F14 PR4B (io), F15 PR6B (io), F16 PR6C (io), G12 PR7A (io), G13 PR7B (io), G14 PR8A (io), G15 PR8C (io), G16 PR6D (io), H12 PR7C (io), H13 PR7D (io), H14 PR8B (io), H15 PR8D (io)
part D pins: H16 PR9A (io), J12 PR9C (io), J13 PR11A (io), J14 PR10C (io), J15 PR10A (io), J16 PR9B (io), K12 PR9D (io), K13 PR11B (io), K14 PR10D (io), K15 PR10B (io), K16 PR11C (io), L11 PR16A (io), L12 PR13C (io), L13 PR13D (io), L14 PR13A (io), L15 PR12A (io), L16 PR11D (io), M11 PR16B (io), M12 PR14C (io), M13 PR14D (io), M14 PR13B (io), M15 PR12B (io), M16 PR12C (io), N12 PR15B (io), N13 PR15A (io), N14 PR14B (io), N15 PR14A (io), N16 PR12D (io)
part E pins: M9 PB7F/PCLK4_0 (io), M10 PB7E (io), N8 PB7A (io), N9 PB7B/PCLK4_1 (io), N10 PB8E (io), N11 PB8F (io), P9 PB7C (io), P10 PB7D (io), P11 PB9C (io), P12 PB9D (io), P14 PB10F (io), P15 PB11C (io), P16 PB11D (io), R9 PB8A (io), R10 PB8B (io), R11 PB9A (io), R12 PB9B (io), R13 PB10A (io), R14 PB10B (io), R15 PB11A (io), R16 PB11B (io), T10 PB8C (io), T11 PB8D (io), T12 PB9F (io), T13 PB9E (io), T14 PB10C (io), T15 PB10D (io)
part F pins: M7 PB6A (io), M8 PB6B (io), N5 PB2C (io), N6 PB2D (io), P2 PB2A (io), P3 PB2B (io), P5 PB4A (io), P6 PB4B (io), P7 PB6E (io), P8 PB6F (io), R4 PB3C (io), R5 PB3D (io), R6 PB5A (io), R7 PB6C (io), R8 PB6D (io), T2 PB3A (io), T3 PB3B (io), T4 PB4D (io), T5 PB4C (io), T6 PB5B (io), T7 PB5D (io), T8 PB5C (io)
part G pins: H2 PL9A (io), J1 PL10A (io), J2 PL9B (io), J3 PL9C (io), J4 PL13A (io), J5 PL13B (io), K1 PL10B (io), K2 PL10C (io), K3 PL9D (io), K4 PL14B/LLM0_PLLC_FB_A (io), K5 PL14A/LLM0_PLLT_FB_A (io), L1 PL11A (io), L2 PL10D (io), L3 PL12A (io), L4 PL14D (io), L5 PL14C (io), M1 PL11B (io), M2 PL12C (io), M3 PL12B (io), M4 PL15B/LLM0_PLLC_IN_A (io), M5 PL15A/LLM0_PLLT_IN_A (io), N1 PL11C/TSALL (io), N2 PL12D (io), N3 PL16B (io), N4 PL16A (io), P1 PL11D (io), R1 PL13C (io), R2 PL13D (io)
part H pins: B1 PL5A (io), C1 PL5B (io), C2 PL4D (io), C3 PL4C (io), D1 PL5D (io), D2 PL5C (io), E1 PL6C (io), E2 PL4B (io), E3 PL4A (io), E4 PL2A (io), E5 PL2B (io), F1 PL6D (io), F2 PL6A (io), F3 PL3C (io), F4 PL3D (io), F5 PL3A (io), F6 PL3B (io), G1 PL8C (io), G2 PL6B/GSRN (io), G3 PL7C (io), G4 PL7A (io), G5 PL7B (io), H1 PL8D (io), H3 PL7D (io), H4 PL8A (io), H5 PL8B (io)
part I pins: M6 TDO (out) "Powered by VCCIO5", N7 TDI (in) "Powered by VCCIO5", P4 TMS (in) "Powered by VCCIO5", P13 SLEEPN (in) "Powered by VCCIO4", R3 TCK (in) "Powered by VCCIO5"
part J pins: A8 VCCAUX (power), F7 VCCIO0 (power), F8 VCCIO0 (power), F9 VCCIO1 (power), F10 VCCIO1 (power), G6 VCCIO7 (power), G7 VCC (power), G10 VCC (power), G11 VCCIO2 (power), H6 VCCIO7 (power), H11 VCCIO2 (power), J6 VCCIO6 (power), J11 VCCIO3 (power), K6 VCCIO6 (power), K7 VCC (power), K10 VCC (power), K11 VCCIO3 (power), L7 VCCIO5 (power), L8 VCCIO5 (power), L9 VCCIO4 (power), L10 VCCIO4 (power), T9 VCCAUX (power)
part K pins: A1 GND (power), A16 GND (power), F11 GND (power), G8 GND (power), G9 GND (power), H7 GND (power), H8 GND (power), H9 GND (power), H10 GND (power), J7 GND (power), J8 GND (power), J9 GND (power), J10 GND (power), K8 GND (power), K9 GND (power), L6 GND (power), T1 GND (power), T16 GND (power)


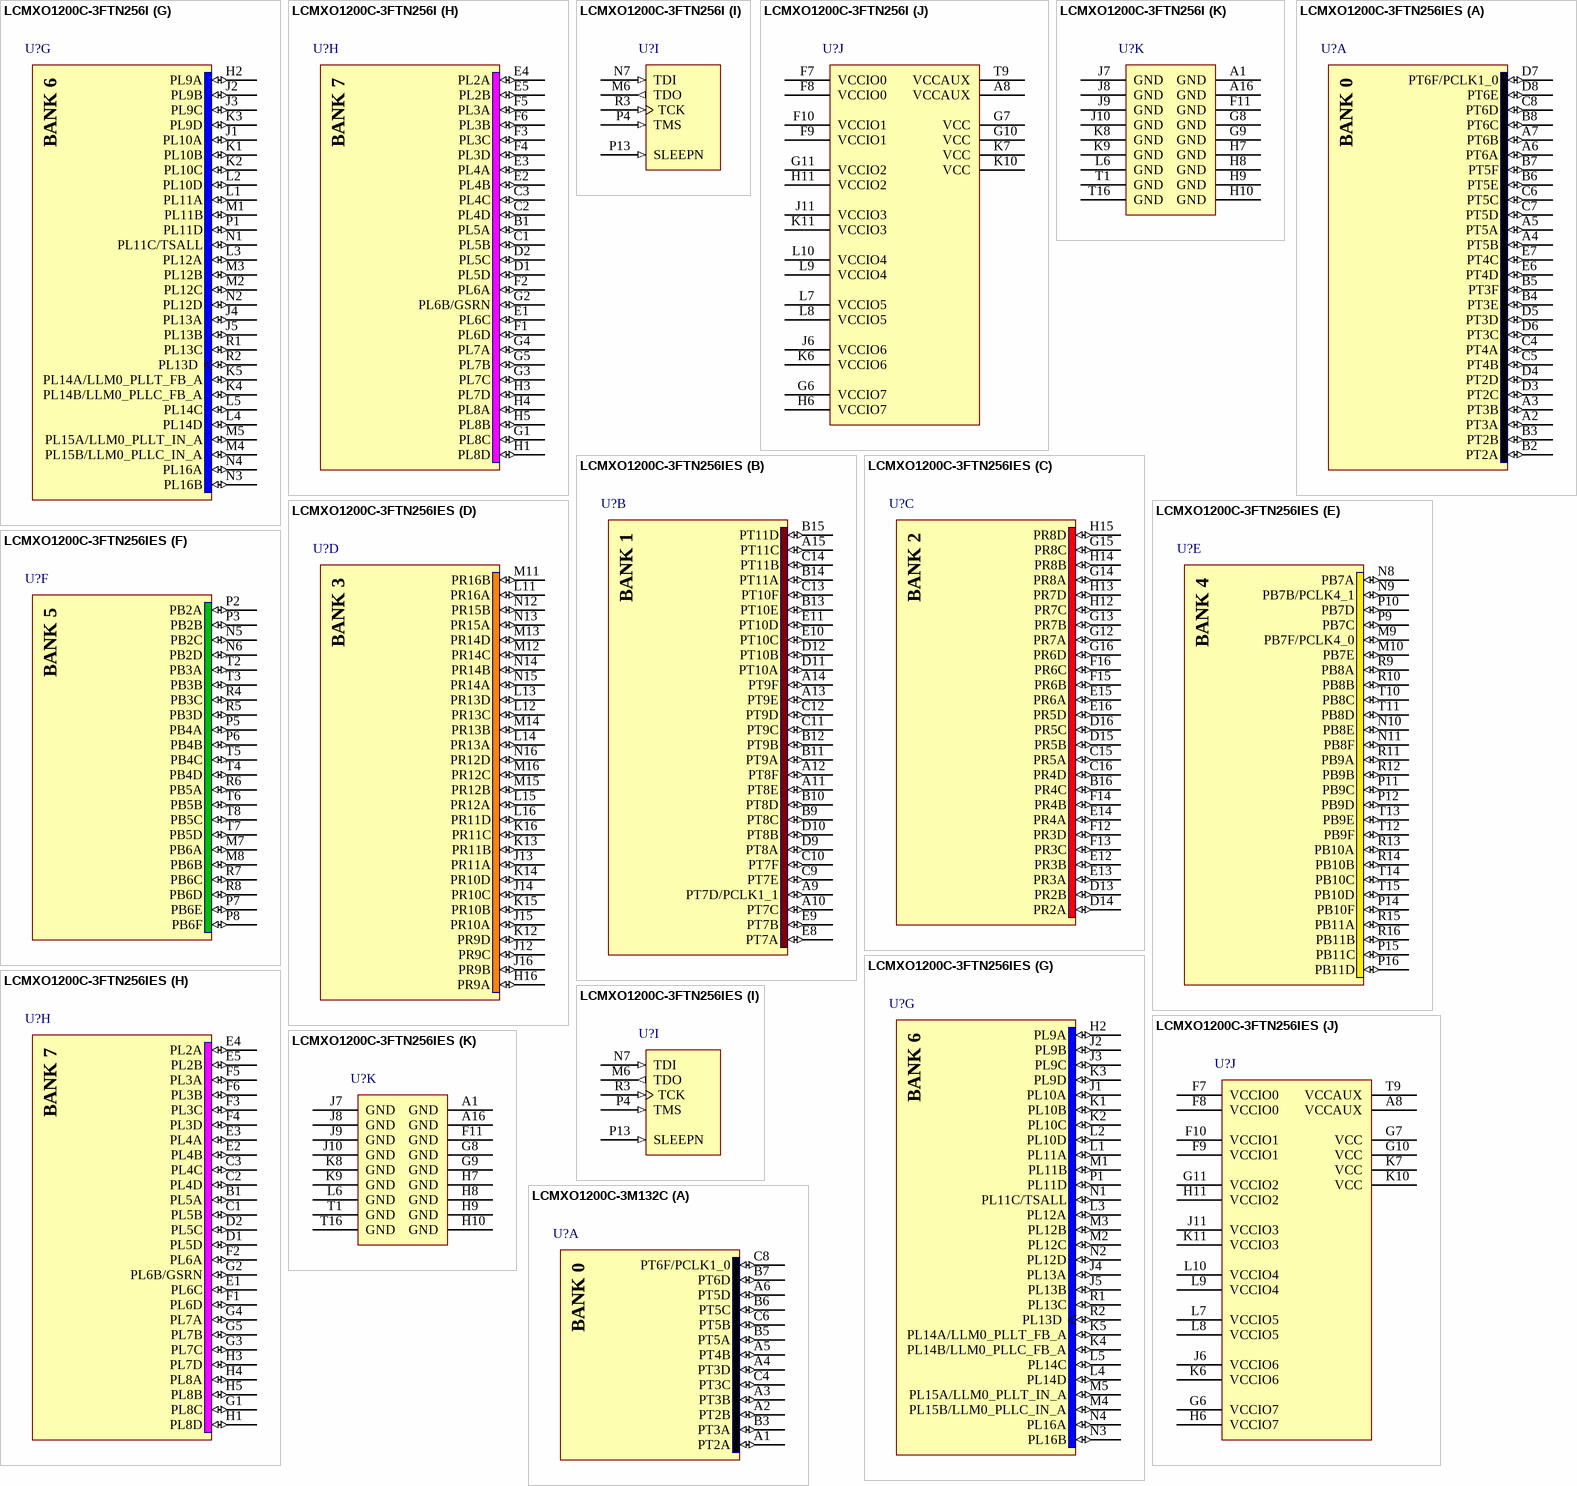
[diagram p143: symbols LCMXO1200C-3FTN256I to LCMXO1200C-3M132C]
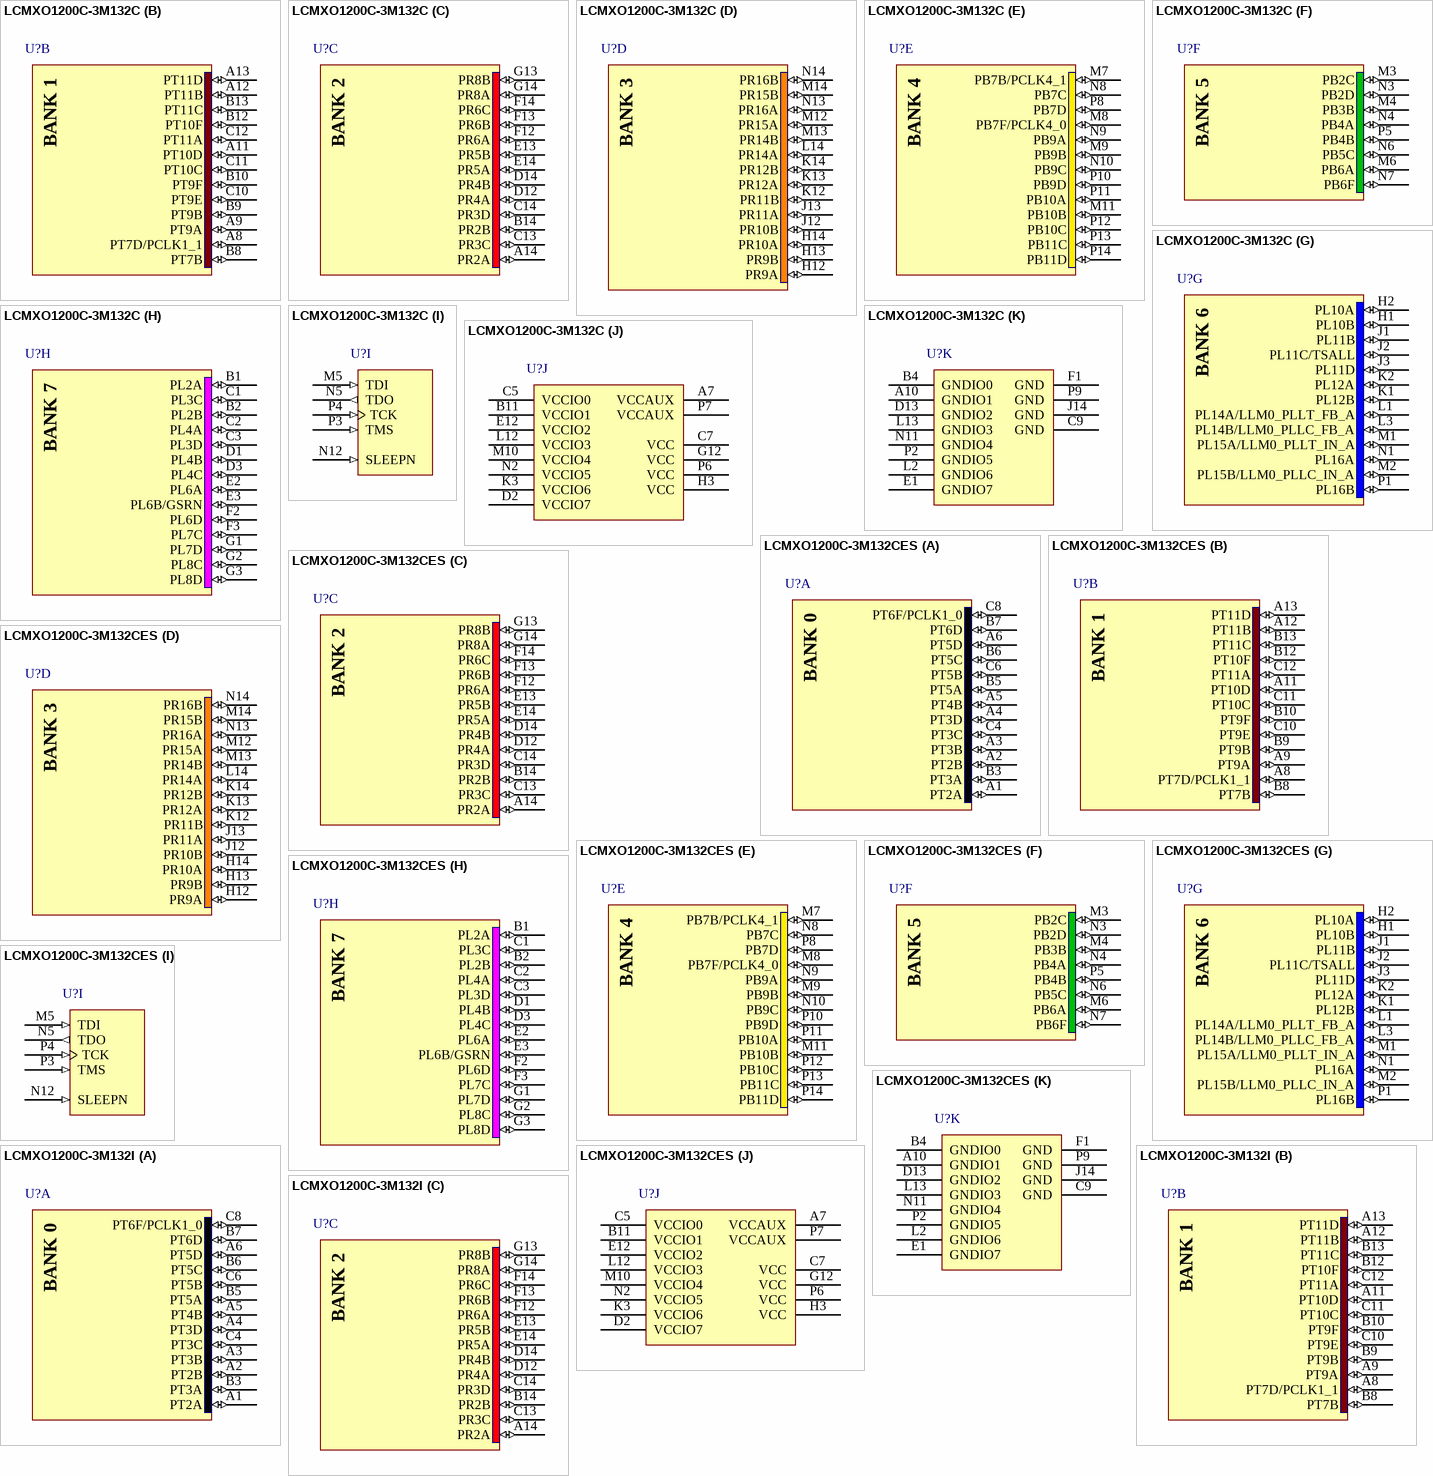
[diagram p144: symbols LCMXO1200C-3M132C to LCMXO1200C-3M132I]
## LCMXO1200C-3FTN256I
designator U?
MachXO 1200 Crossover PLD, 1.8V/2.5V/3.3V, 211 User I/Os, 256-Pins ftBGA, Speed Grade-3, Industrial Grade, Pb-Free
footprint ftBGA256 (BGA, 256-Leads, Body 17x17mm, Pitch 1mm)
3D model MachXO1200-ftBGA256 (256-Ball Fine Thin Ball Grid Array (ftBGA256))
signal-integrity model LCMXO1200C_FT256 (MachXO)
part A pins: A2 PT3A (io), A3 PT3B (io), A4 PT5B (io), A5 PT5A (io), A6 PT6A (io), A7 PT6B (io), B2 PT2A (io), B3 PT2B (io), B4 PT3E (io), B5 PT3F (io), B6 PT5E (io), B7 PT5F (io), B8 PT6C (io), C4 PT4A (io), C5 PT4B (io), C6 PT5C (io), C7 PT5D (io), C8 PT6D (io), D3 PT2C (io), D4 PT2D (io), D5 PT3D (io), D6 PT3C (io), D7 PT6F/PCLK1_0 (io), D8 PT6E (io), E6 PT4D (io), E7 PT4C (io)
part B pins: A9 PT7D/PCLK1_1 (io), A10 PT7C (io), A11 PT8E (io), A12 PT8F (io), A13 PT9E (io), A14 PT9F (io), A15 PT11C (io), B9 PT8C (io), B10 PT8D (io), B11 PT9A (io), B12 PT9B (io), B13 PT10E (io), B14 PT11A (io), B15 PT11D (io), C9 PT7E (io), C10 PT7F (io), C11 PT9C (io), C12 PT9D (io), C13 PT10F (io), C14 PT11B (io), D9 PT8A (io), D10 PT8B (io), D11 PT10A (io), D12 PT10B (io), E8 PT7A (io), E9 PT7B (io), E10 PT10C (io), E11 PT10D (io)
part C pins: B16 PR4C (io), C15 PR5A (io), C16 PR4D (io), D13 PR2B (io), D14 PR2A (io), D15 PR5B (io), D16 PR5C (io), E12 PR3B (io), E13 PR3A (io), E14 PR4A (io), E15 PR6A (io), E16 PR5D (io), F12 PR3D (io), F13 PR3C (io), F14 PR4B (io), F15 PR6B (io), F16 PR6C (io), G12 PR7A (io), G13 PR7B (io), G14 PR8A (io), G15 PR8C (io), G16 PR6D (io), H12 PR7C (io), H13 PR7D (io), H14 PR8B (io), H15 PR8D (io)
part D pins: H16 PR9A (io), J12 PR9C (io), J13 PR11A (io), J14 PR10C (io), J15 PR10A (io), J16 PR9B (io), K12 PR9D (io), K13 PR11B (io), K14 PR10D (io), K15 PR10B (io), K16 PR11C (io), L11 PR16A (io), L12 PR13C (io), L13 PR13D (io), L14 PR13A (io), L15 PR12A (io), L16 PR11D (io), M11 PR16B (io), M12 PR14C (io), M13 PR14D (io), M14 PR13B (io), M15 PR12B (io), M16 PR12C (io), N12 PR15B (io), N13 PR15A (io), N14 PR14B (io), N15 PR14A (io), N16 PR12D (io)
part E pins: M9 PB7F/PCLK4_0 (io), M10 PB7E (io), N8 PB7A (io), N9 PB7B/PCLK4_1 (io), N10 PB8E (io), N11 PB8F (io), P9 PB7C (io), P10 PB7D (io), P11 PB9C (io), P12 PB9D (io), P14 PB10F (io), P15 PB11C (io), P16 PB11D (io), R9 PB8A (io), R10 PB8B (io), R11 PB9A (io), R12 PB9B (io), R13 PB10A (io), R14 PB10B (io), R15 PB11A (io), R16 PB11B (io), T10 PB8C (io), T11 PB8D (io), T12 PB9F (io), T13 PB9E (io), T14 PB10C (io), T15 PB10D (io)
part F pins: M7 PB6A (io), M8 PB6B (io), N5 PB2C (io), N6 PB2D (io), P2 PB2A (io), P3 PB2B (io), P5 PB4A (io), P6 PB4B (io), P7 PB6E (io), P8 PB6F (io), R4 PB3C (io), R5 PB3D (io), R6 PB5A (io), R7 PB6C (io), R8 PB6D (io), T2 PB3A (io), T3 PB3B (io), T4 PB4D (io), T5 PB4C (io), T6 PB5B (io), T7 PB5D (io), T8 PB5C (io)
part G pins: H2 PL9A (io), J1 PL10A (io), J2 PL9B (io), J3 PL9C (io), J4 PL13A (io), J5 PL13B (io), K1 PL10B (io), K2 PL10C (io), K3 PL9D (io), K4 PL14B/LLM0_PLLC_FB_A (io), K5 PL14A/LLM0_PLLT_FB_A (io), L1 PL11A (io), L2 PL10D (io), L3 PL12A (io), L4 PL14D (io), L5 PL14C (io), M1 PL11B (io), M2 PL12C (io), M3 PL12B (io), M4 PL15B/LLM0_PLLC_IN_A (io), M5 PL15A/LLM0_PLLT_IN_A (io), N1 PL11C/TSALL (io), N2 PL12D (io), N3 PL16B (io), N4 PL16A (io), P1 PL11D (io), R1 PL13C (io), R2 PL13D (io)
part H pins: B1 PL5A (io), C1 PL5B (io), C2 PL4D (io), C3 PL4C (io), D1 PL5D (io), D2 PL5C (io), E1 PL6C (io), E2 PL4B (io), E3 PL4A (io), E4 PL2A (io), E5 PL2B (io), F1 PL6D (io), F2 PL6A (io), F3 PL3C (io), F4 PL3D (io), F5 PL3A (io), F6 PL3B (io), G1 PL8C (io), G2 PL6B/GSRN (io), G3 PL7C (io), G4 PL7A (io), G5 PL7B (io), H1 PL8D (io), H3 PL7D (io), H4 PL8A (io), H5 PL8B (io)
part I pins: M6 TDO (out) "Powered by VCCIO5", N7 TDI (in) "Powered by VCCIO5", P4 TMS (in) "Powered by VCCIO5", P13 SLEEPN (in) "Powered by VCCIO4", R3 TCK (in) "Powered by VCCIO5"
part J pins: A8 VCCAUX (power), F7 VCCIO0 (power), F8 VCCIO0 (power), F9 VCCIO1 (power), F10 VCCIO1 (power), G6 VCCIO7 (power), G7 VCC (power), G10 VCC (power), G11 VCCIO2 (power), H6 VCCIO7 (power), H11 VCCIO2 (power), J6 VCCIO6 (power), J11 VCCIO3 (power), K6 VCCIO6 (power), K7 VCC (power), K10 VCC (power), K11 VCCIO3 (power), L7 VCCIO5 (power), L8 VCCIO5 (power), L9 VCCIO4 (power), L10 VCCIO4 (power), T9 VCCAUX (power)
part K pins: A1 GND (power), A16 GND (power), F11 GND (power), G8 GND (power), G9 GND (power), H7 GND (power), H8 GND (power), H9 GND (power), H10 GND (power), J7 GND (power), J8 GND (power), J9 GND (power), J10 GND (power), K8 GND (power), K9 GND (power), L6 GND (power), T1 GND (power), T16 GND (power)

## LCMXO1200C-3FTN256IES
designator U?
MachXO 1200 Crossover PLD, 1.8V/2.5V/3.3V, 211 User I/Os, 256-Pins ftBGA, Speed Grade-3, Industrial Grade, Pb-Free, Engineering Sample
footprint ftBGA256 (BGA, 256-Leads, Body 17x17mm, Pitch 1mm)
3D model MachXO1200-ftBGA256 (256-Ball Fine Thin Ball Grid Array (ftBGA256))
signal-integrity model LCMXO1200C_FT256 (MachXO)
part A pins: A2 PT3A (io), A3 PT3B (io), A4 PT5B (io), A5 PT5A (io), A6 PT6A (io), A7 PT6B (io), B2 PT2A (io), B3 PT2B (io), B4 PT3E (io), B5 PT3F (io), B6 PT5E (io), B7 PT5F (io), B8 PT6C (io), C4 PT4A (io), C5 PT4B (io), C6 PT5C (io), C7 PT5D (io), C8 PT6D (io), D3 PT2C (io), D4 PT2D (io), D5 PT3D (io), D6 PT3C (io), D7 PT6F/PCLK1_0 (io), D8 PT6E (io), E6 PT4D (io), E7 PT4C (io)
part B pins: A9 PT7D/PCLK1_1 (io), A10 PT7C (io), A11 PT8E (io), A12 PT8F (io), A13 PT9E (io), A14 PT9F (io), A15 PT11C (io), B9 PT8C (io), B10 PT8D (io), B11 PT9A (io), B12 PT9B (io), B13 PT10E (io), B14 PT11A (io), B15 PT11D (io), C9 PT7E (io), C10 PT7F (io), C11 PT9C (io), C12 PT9D (io), C13 PT10F (io), C14 PT11B (io), D9 PT8A (io), D10 PT8B (io), D11 PT10A (io), D12 PT10B (io), E8 PT7A (io), E9 PT7B (io), E10 PT10C (io), E11 PT10D (io)
part C pins: B16 PR4C (io), C15 PR5A (io), C16 PR4D (io), D13 PR2B (io), D14 PR2A (io), D15 PR5B (io), D16 PR5C (io), E12 PR3B (io), E13 PR3A (io), E14 PR4A (io), E15 PR6A (io), E16 PR5D (io), F12 PR3D (io), F13 PR3C (io), F14 PR4B (io), F15 PR6B (io), F16 PR6C (io), G12 PR7A (io), G13 PR7B (io), G14 PR8A (io), G15 PR8C (io), G16 PR6D (io), H12 PR7C (io), H13 PR7D (io), H14 PR8B (io), H15 PR8D (io)
part D pins: H16 PR9A (io), J12 PR9C (io), J13 PR11A (io), J14 PR10C (io), J15 PR10A (io), J16 PR9B (io), K12 PR9D (io), K13 PR11B (io), K14 PR10D (io), K15 PR10B (io), K16 PR11C (io), L11 PR16A (io), L12 PR13C (io), L13 PR13D (io), L14 PR13A (io), L15 PR12A (io), L16 PR11D (io), M11 PR16B (io), M12 PR14C (io), M13 PR14D (io), M14 PR13B (io), M15 PR12B (io), M16 PR12C (io), N12 PR15B (io), N13 PR15A (io), N14 PR14B (io), N15 PR14A (io), N16 PR12D (io)
part E pins: M9 PB7F/PCLK4_0 (io), M10 PB7E (io), N8 PB7A (io), N9 PB7B/PCLK4_1 (io), N10 PB8E (io), N11 PB8F (io), P9 PB7C (io), P10 PB7D (io), P11 PB9C (io), P12 PB9D (io), P14 PB10F (io), P15 PB11C (io), P16 PB11D (io), R9 PB8A (io), R10 PB8B (io), R11 PB9A (io), R12 PB9B (io), R13 PB10A (io), R14 PB10B (io), R15 PB11A (io), R16 PB11B (io), T10 PB8C (io), T11 PB8D (io), T12 PB9F (io), T13 PB9E (io), T14 PB10C (io), T15 PB10D (io)
part F pins: M7 PB6A (io), M8 PB6B (io), N5 PB2C (io), N6 PB2D (io), P2 PB2A (io), P3 PB2B (io), P5 PB4A (io), P6 PB4B (io), P7 PB6E (io), P8 PB6F (io), R4 PB3C (io), R5 PB3D (io), R6 PB5A (io), R7 PB6C (io), R8 PB6D (io), T2 PB3A (io), T3 PB3B (io), T4 PB4D (io), T5 PB4C (io), T6 PB5B (io), T7 PB5D (io), T8 PB5C (io)
part G pins: H2 PL9A (io), J1 PL10A (io), J2 PL9B (io), J3 PL9C (io), J4 PL13A (io), J5 PL13B (io), K1 PL10B (io), K2 PL10C (io), K3 PL9D (io), K4 PL14B/LLM0_PLLC_FB_A (io), K5 PL14A/LLM0_PLLT_FB_A (io), L1 PL11A (io), L2 PL10D (io), L3 PL12A (io), L4 PL14D (io), L5 PL14C (io), M1 PL11B (io), M2 PL12C (io), M3 PL12B (io), M4 PL15B/LLM0_PLLC_IN_A (io), M5 PL15A/LLM0_PLLT_IN_A (io), N1 PL11C/TSALL (io), N2 PL12D (io), N3 PL16B (io), N4 PL16A (io), P1 PL11D (io), R1 PL13C (io), R2 PL13D (io)
part H pins: B1 PL5A (io), C1 PL5B (io), C2 PL4D (io), C3 PL4C (io), D1 PL5D (io), D2 PL5C (io), E1 PL6C (io), E2 PL4B (io), E3 PL4A (io), E4 PL2A (io), E5 PL2B (io), F1 PL6D (io), F2 PL6A (io), F3 PL3C (io), F4 PL3D (io), F5 PL3A (io), F6 PL3B (io), G1 PL8C (io), G2 PL6B/GSRN (io), G3 PL7C (io), G4 PL7A (io), G5 PL7B (io), H1 PL8D (io), H3 PL7D (io), H4 PL8A (io), H5 PL8B (io)
part I pins: M6 TDO (out) "Powered by VCCIO5", N7 TDI (in) "Powered by VCCIO5", P4 TMS (in) "Powered by VCCIO5", P13 SLEEPN (in) "Powered by VCCIO4", R3 TCK (in) "Powered by VCCIO5"
part J pins: A8 VCCAUX (power), F7 VCCIO0 (power), F8 VCCIO0 (power), F9 VCCIO1 (power), F10 VCCIO1 (power), G6 VCCIO7 (power), G7 VCC (power), G10 VCC (power), G11 VCCIO2 (power), H6 VCCIO7 (power), H11 VCCIO2 (power), J6 VCCIO6 (power), J11 VCCIO3 (power), K6 VCCIO6 (power), K7 VCC (power), K10 VCC (power), K11 VCCIO3 (power), L7 VCCIO5 (power), L8 VCCIO5 (power), L9 VCCIO4 (power), L10 VCCIO4 (power), T9 VCCAUX (power)
part K pins: A1 GND (power), A16 GND (power), F11 GND (power), G8 GND (power), G9 GND (power), H7 GND (power), H8 GND (power), H9 GND (power), H10 GND (power), J7 GND (power), J8 GND (power), J9 GND (power), J10 GND (power), K8 GND (power), K9 GND (power), L6 GND (power), T1 GND (power), T16 GND (power)

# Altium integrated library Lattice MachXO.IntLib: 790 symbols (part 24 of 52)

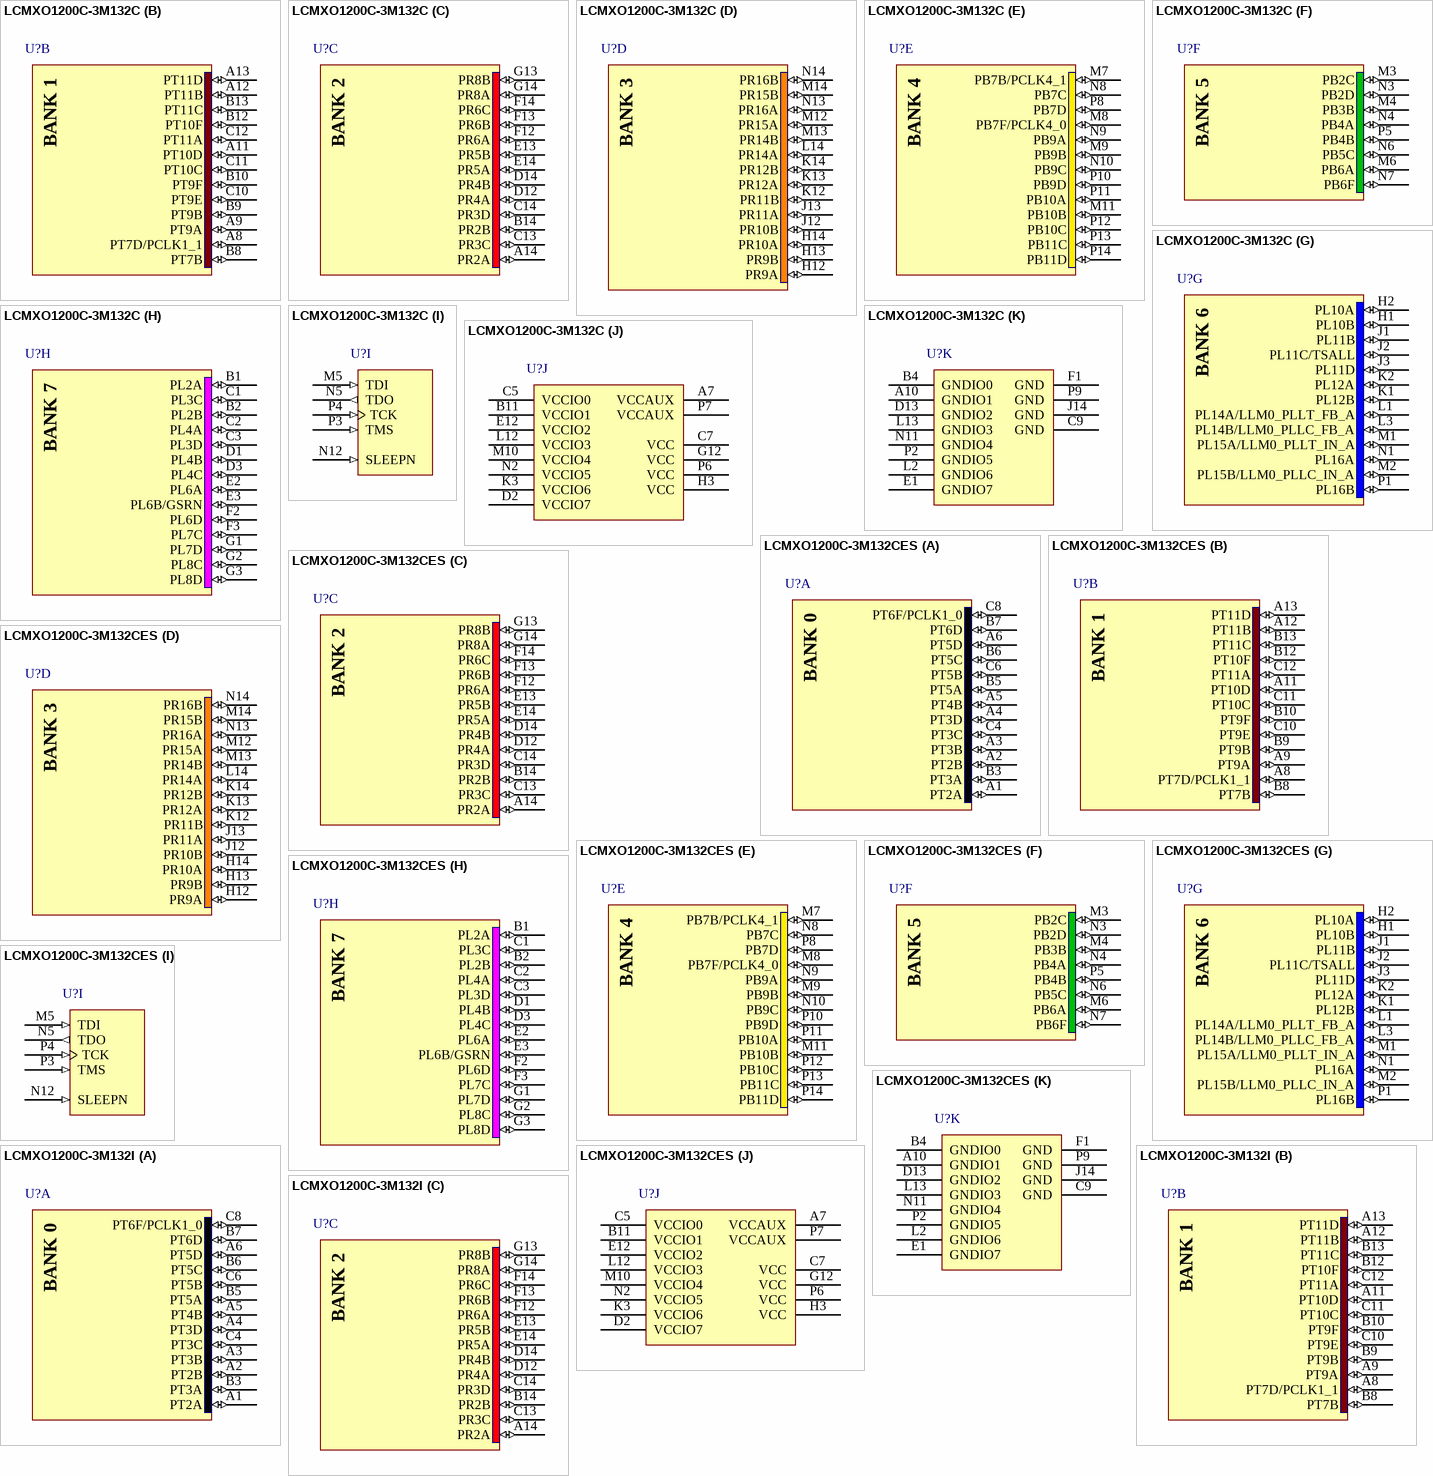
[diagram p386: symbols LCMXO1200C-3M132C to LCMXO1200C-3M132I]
## LCMXO1200C-3M132C
designator U?
MachXO 1200 Crossover PLD, 1.8V/2.5V/3.3V, 101 User I/Os, 132-Pins csBGA, Speed Grade-3, Commercial Grade
footprint csBGA132 (BGA, 132-Leads, Body 8x8mm, Pitch 0.5mm)
3D model MachXO1200-csBGA132 (132-Ball Chip Scale Ball Grid Array (csBGA132))
signal-integrity model LCMXO1200C_M132 (MachXO)
part A pins: A1 PT2A (io), A2 PT2B (io), A3 PT3B (io), A4 PT3D (io), A5 PT4B (io), A6 PT5D (io), B3 PT3A (io), B5 PT5A (io), B6 PT5C (io), B7 PT6D (io), C4 PT3C (io), C6 PT5B (io), C8 PT6F/PCLK1_0 (io)
part B pins: A8 PT7D/PCLK1_1 (io), A9 PT9A (io), A11 PT10D (io), A12 PT11B (io), A13 PT11D (io), B8 PT7B (io), B9 PT9B (io), B10 PT9F (io), B12 PT10F (io), B13 PT11C (io), C10 PT9E (io), C11 PT10C (io), C12 PT11A (io)
part C pins: A14 PR2A (io), B14 PR2B (io), C13 PR3C (io), C14 PR3D (io), D12 PR4A (io), D14 PR4B (io), E13 PR5B (io), E14 PR5A (io), F12 PR6A (io), F13 PR6B (io), F14 PR6C (io), G13 PR8B (io), G14 PR8A (io)
part D pins: H12 PR9A (io), H13 PR9B (io), H14 PR10A (io), J12 PR10B (io), J13 PR11A (io), K12 PR11B (io), K13 PR12A (io), K14 PR12B (io), L14 PR14A (io), M12 PR15A (io), M13 PR14B (io), M14 PR15B (io), N13 PR16A (io), N14 PR16B (io)
part E pins: M7 PB7B/PCLK4_1 (io), M8 PB7F/PCLK4_0 (io), M9 PB9B (io), M11 PB10B (io), N8 PB7C (io), N9 PB9A (io), N10 PB9C (io), P8 PB7D (io), P10 PB9D (io), P11 PB10A (io), P12 PB10C (io), P13 PB11C (io), P14 PB11D (io)
part F pins: M3 PB2C (io), M4 PB3B (io), M6 PB6A (io), N3 PB2D (io), N4 PB4A (io), N6 PB5C (io), N7 PB6F (io), P5 PB4B (io)
part G pins: H1 PL10B (io), H2 PL10A (io), J1 PL11B (io), J2 PL11C/TSALL (io), J3 PL11D (io), K1 PL12B (io), K2 PL12A (io), L1 PL14A/LLM0_PLLT_FB_A (io), L3 PL14B/LLM0_PLLC_FB_A (io), M1 PL15A/LLM0_PLLT_IN_A (io), M2 PL15B/LLM0_PLLC_IN_A (io), N1 PL16A (io), P1 PL16B (io)
part H pins: B1 PL2A (io), B2 PL2B (io), C1 PL3C (io), C2 PL4A (io), C3 PL3D (io), D1 PL4B (io), D3 PL4C (io), E2 PL6A (io), E3 PL6B/GSRN (io), F2 PL6D (io), F3 PL7C (io), G1 PL7D (io), G2 PL8C (io), G3 PL8D (io)
part I pins: M5 TDI (in) "Powered by VCCIO5", N5 TDO (out) "Powered by VCCIO5", N12 SLEEPN (in) "Powered by VCCIO4", P3 TMS (in) "Powered by VCCIO5", P4 TCK (in) "Powered by VCCIO5"
part J pins: A7 VCCAUX (power), B11 VCCIO1 (power), C5 VCCIO0 (power), C7 VCC (power), D2 VCCIO7 (power), E12 VCCIO2 (power), G12 VCC (power), H3 VCC (power), K3 VCCIO6 (power), L12 VCCIO3 (power), M10 VCCIO4 (power), N2 VCCIO5 (power), P6 VCC (power), P7 VCCAUX (power)
part K pins: A10 GNDIO1 (power), B4 GNDIO0 (power), C9 GND (power), D13 GNDIO2 (power), E1 GNDIO7 (power), F1 GND (power), J14 GND (power), L2 GNDIO6 (power), L13 GNDIO3 (power), N11 GNDIO4 (power), P2 GNDIO5 (power), P9 GND (power)

## LCMXO1200C-3M132CES
designator U?
MachXO 1200 Crossover PLD, 1.8V/2.5V/3.3V, 101 User I/Os, 132-Pins csBGA, Speed Grade-3, Commercial Grade, Engineering Sample
footprint csBGA132 (BGA, 132-Leads, Body 8x8mm, Pitch 0.5mm)
3D model MachXO1200-csBGA132 (132-Ball Chip Scale Ball Grid Array (csBGA132))
signal-integrity model LCMXO1200C_M132 (MachXO)
part A pins: A1 PT2A (io), A2 PT2B (io), A3 PT3B (io), A4 PT3D (io), A5 PT4B (io), A6 PT5D (io), B3 PT3A (io), B5 PT5A (io), B6 PT5C (io), B7 PT6D (io), C4 PT3C (io), C6 PT5B (io), C8 PT6F/PCLK1_0 (io)
part B pins: A8 PT7D/PCLK1_1 (io), A9 PT9A (io), A11 PT10D (io), A12 PT11B (io), A13 PT11D (io), B8 PT7B (io), B9 PT9B (io), B10 PT9F (io), B12 PT10F (io), B13 PT11C (io), C10 PT9E (io), C11 PT10C (io), C12 PT11A (io)
part C pins: A14 PR2A (io), B14 PR2B (io), C13 PR3C (io), C14 PR3D (io), D12 PR4A (io), D14 PR4B (io), E13 PR5B (io), E14 PR5A (io), F12 PR6A (io), F13 PR6B (io), F14 PR6C (io), G13 PR8B (io), G14 PR8A (io)
part D pins: H12 PR9A (io), H13 PR9B (io), H14 PR10A (io), J12 PR10B (io), J13 PR11A (io), K12 PR11B (io), K13 PR12A (io), K14 PR12B (io), L14 PR14A (io), M12 PR15A (io), M13 PR14B (io), M14 PR15B (io), N13 PR16A (io), N14 PR16B (io)
part E pins: M7 PB7B/PCLK4_1 (io), M8 PB7F/PCLK4_0 (io), M9 PB9B (io), M11 PB10B (io), N8 PB7C (io), N9 PB9A (io), N10 PB9C (io), P8 PB7D (io), P10 PB9D (io), P11 PB10A (io), P12 PB10C (io), P13 PB11C (io), P14 PB11D (io)
part F pins: M3 PB2C (io), M4 PB3B (io), M6 PB6A (io), N3 PB2D (io), N4 PB4A (io), N6 PB5C (io), N7 PB6F (io), P5 PB4B (io)
part G pins: H1 PL10B (io), H2 PL10A (io), J1 PL11B (io), J2 PL11C/TSALL (io), J3 PL11D (io), K1 PL12B (io), K2 PL12A (io), L1 PL14A/LLM0_PLLT_FB_A (io), L3 PL14B/LLM0_PLLC_FB_A (io), M1 PL15A/LLM0_PLLT_IN_A (io), M2 PL15B/LLM0_PLLC_IN_A (io), N1 PL16A (io), P1 PL16B (io)
part H pins: B1 PL2A (io), B2 PL2B (io), C1 PL3C (io), C2 PL4A (io), C3 PL3D (io), D1 PL4B (io), D3 PL4C (io), E2 PL6A (io), E3 PL6B/GSRN (io), F2 PL6D (io), F3 PL7C (io), G1 PL7D (io), G2 PL8C (io), G3 PL8D (io)
part I pins: M5 TDI (in) "Powered by VCCIO5", N5 TDO (out) "Powered by VCCIO5", N12 SLEEPN (in) "Powered by VCCIO4", P3 TMS (in) "Powered by VCCIO5", P4 TCK (in) "Powered by VCCIO5"
part J pins: A7 VCCAUX (power), B11 VCCIO1 (power), C5 VCCIO0 (power), C7 VCC (power), D2 VCCIO7 (power), E12 VCCIO2 (power), G12 VCC (power), H3 VCC (power), K3 VCCIO6 (power), L12 VCCIO3 (power), M10 VCCIO4 (power), N2 VCCIO5 (power), P6 VCC (power), P7 VCCAUX (power)
part K pins: A10 GNDIO1 (power), B4 GNDIO0 (power), C9 GND (power), D13 GNDIO2 (power), E1 GNDIO7 (power), F1 GND (power), J14 GND (power), L2 GNDIO6 (power), L13 GNDIO3 (power), N11 GNDIO4 (power), P2 GNDIO5 (power), P9 GND (power)


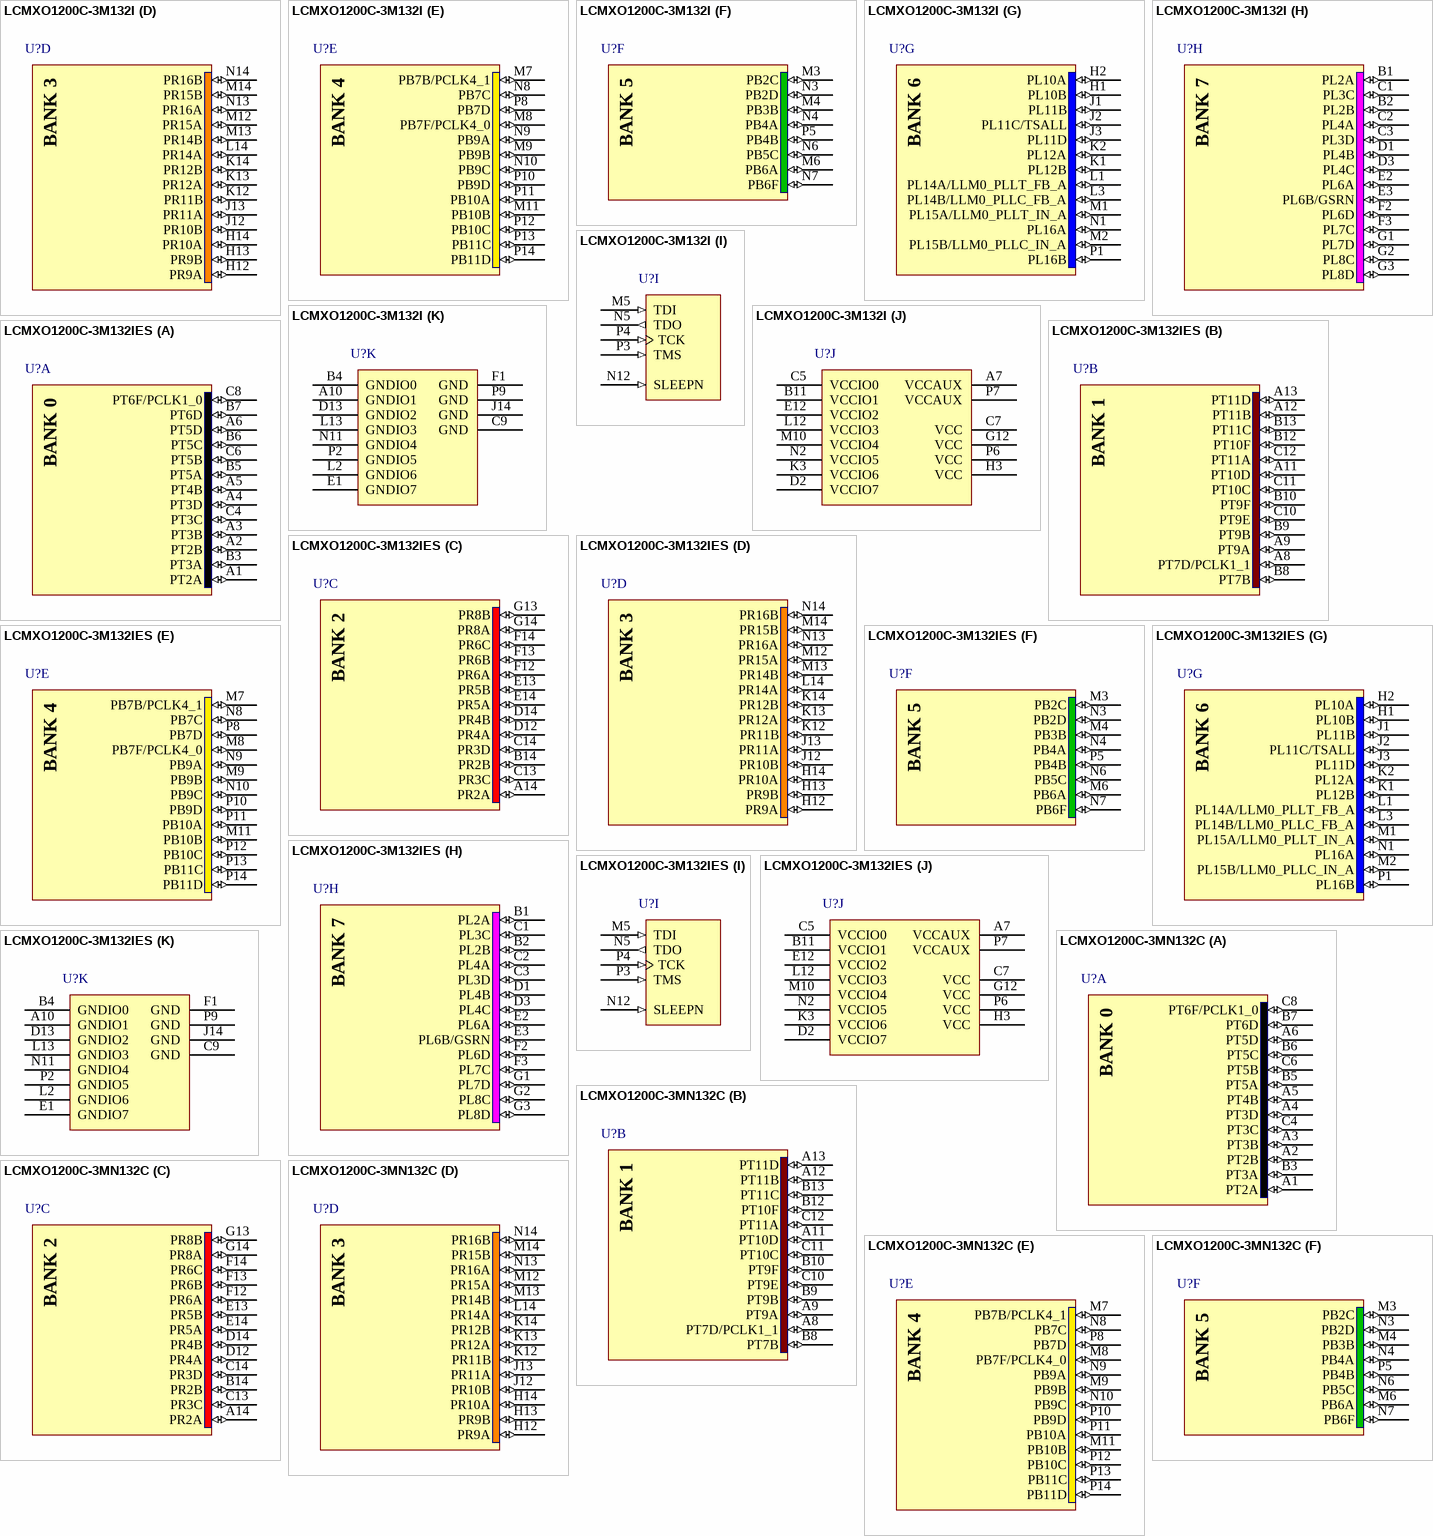
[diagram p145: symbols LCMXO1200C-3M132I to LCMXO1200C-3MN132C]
## LCMXO1200C-3M132I
designator U?
MachXO 1200 Crossover PLD, 1.8V/2.5V/3.3V, 101 User I/Os, 132-Pins csBGA, Speed Grade-3, Industrial Grade
footprint csBGA132 (BGA, 132-Leads, Body 8x8mm, Pitch 0.5mm)
3D model MachXO1200-csBGA132 (132-Ball Chip Scale Ball Grid Array (csBGA132))
signal-integrity model LCMXO1200C_M132 (MachXO)
part A pins: A1 PT2A (io), A2 PT2B (io), A3 PT3B (io), A4 PT3D (io), A5 PT4B (io), A6 PT5D (io), B3 PT3A (io), B5 PT5A (io), B6 PT5C (io), B7 PT6D (io), C4 PT3C (io), C6 PT5B (io), C8 PT6F/PCLK1_0 (io)
part B pins: A8 PT7D/PCLK1_1 (io), A9 PT9A (io), A11 PT10D (io), A12 PT11B (io), A13 PT11D (io), B8 PT7B (io), B9 PT9B (io), B10 PT9F (io), B12 PT10F (io), B13 PT11C (io), C10 PT9E (io), C11 PT10C (io), C12 PT11A (io)
part C pins: A14 PR2A (io), B14 PR2B (io), C13 PR3C (io), C14 PR3D (io), D12 PR4A (io), D14 PR4B (io), E13 PR5B (io), E14 PR5A (io), F12 PR6A (io), F13 PR6B (io), F14 PR6C (io), G13 PR8B (io), G14 PR8A (io)
part D pins: H12 PR9A (io), H13 PR9B (io), H14 PR10A (io), J12 PR10B (io), J13 PR11A (io), K12 PR11B (io), K13 PR12A (io), K14 PR12B (io), L14 PR14A (io), M12 PR15A (io), M13 PR14B (io), M14 PR15B (io), N13 PR16A (io), N14 PR16B (io)
part E pins: M7 PB7B/PCLK4_1 (io), M8 PB7F/PCLK4_0 (io), M9 PB9B (io), M11 PB10B (io), N8 PB7C (io), N9 PB9A (io), N10 PB9C (io), P8 PB7D (io), P10 PB9D (io), P11 PB10A (io), P12 PB10C (io), P13 PB11C (io), P14 PB11D (io)
part F pins: M3 PB2C (io), M4 PB3B (io), M6 PB6A (io), N3 PB2D (io), N4 PB4A (io), N6 PB5C (io), N7 PB6F (io), P5 PB4B (io)
part G pins: H1 PL10B (io), H2 PL10A (io), J1 PL11B (io), J2 PL11C/TSALL (io), J3 PL11D (io), K1 PL12B (io), K2 PL12A (io), L1 PL14A/LLM0_PLLT_FB_A (io), L3 PL14B/LLM0_PLLC_FB_A (io), M1 PL15A/LLM0_PLLT_IN_A (io), M2 PL15B/LLM0_PLLC_IN_A (io), N1 PL16A (io), P1 PL16B (io)
part H pins: B1 PL2A (io), B2 PL2B (io), C1 PL3C (io), C2 PL4A (io), C3 PL3D (io), D1 PL4B (io), D3 PL4C (io), E2 PL6A (io), E3 PL6B/GSRN (io), F2 PL6D (io), F3 PL7C (io), G1 PL7D (io), G2 PL8C (io), G3 PL8D (io)
part I pins: M5 TDI (in) "Powered by VCCIO5", N5 TDO (out) "Powered by VCCIO5", N12 SLEEPN (in) "Powered by VCCIO4", P3 TMS (in) "Powered by VCCIO5", P4 TCK (in) "Powered by VCCIO5"
part J pins: A7 VCCAUX (power), B11 VCCIO1 (power), C5 VCCIO0 (power), C7 VCC (power), D2 VCCIO7 (power), E12 VCCIO2 (power), G12 VCC (power), H3 VCC (power), K3 VCCIO6 (power), L12 VCCIO3 (power), M10 VCCIO4 (power), N2 VCCIO5 (power), P6 VCC (power), P7 VCCAUX (power)
part K pins: A10 GNDIO1 (power), B4 GNDIO0 (power), C9 GND (power), D13 GNDIO2 (power), E1 GNDIO7 (power), F1 GND (power), J14 GND (power), L2 GNDIO6 (power), L13 GNDIO3 (power), N11 GNDIO4 (power), P2 GNDIO5 (power), P9 GND (power)

## LCMXO1200C-3M132IES
designator U?
MachXO 1200 Crossover PLD, 1.8V/2.5V/3.3V, 101 User I/Os, 132-Pins csBGA, Speed Grade-3, Industrial Grade, Engineering Sample
footprint csBGA132 (BGA, 132-Leads, Body 8x8mm, Pitch 0.5mm)
3D model MachXO1200-csBGA132 (132-Ball Chip Scale Ball Grid Array (csBGA132))
signal-integrity model LCMXO1200C_M132 (MachXO)
part A pins: A1 PT2A (io), A2 PT2B (io), A3 PT3B (io), A4 PT3D (io), A5 PT4B (io), A6 PT5D (io), B3 PT3A (io), B5 PT5A (io), B6 PT5C (io), B7 PT6D (io), C4 PT3C (io), C6 PT5B (io), C8 PT6F/PCLK1_0 (io)
part B pins: A8 PT7D/PCLK1_1 (io), A9 PT9A (io), A11 PT10D (io), A12 PT11B (io), A13 PT11D (io), B8 PT7B (io), B9 PT9B (io), B10 PT9F (io), B12 PT10F (io), B13 PT11C (io), C10 PT9E (io), C11 PT10C (io), C12 PT11A (io)
part C pins: A14 PR2A (io), B14 PR2B (io), C13 PR3C (io), C14 PR3D (io), D12 PR4A (io), D14 PR4B (io), E13 PR5B (io), E14 PR5A (io), F12 PR6A (io), F13 PR6B (io), F14 PR6C (io), G13 PR8B (io), G14 PR8A (io)
part D pins: H12 PR9A (io), H13 PR9B (io), H14 PR10A (io), J12 PR10B (io), J13 PR11A (io), K12 PR11B (io), K13 PR12A (io), K14 PR12B (io), L14 PR14A (io), M12 PR15A (io), M13 PR14B (io), M14 PR15B (io), N13 PR16A (io), N14 PR16B (io)
part E pins: M7 PB7B/PCLK4_1 (io), M8 PB7F/PCLK4_0 (io), M9 PB9B (io), M11 PB10B (io), N8 PB7C (io), N9 PB9A (io), N10 PB9C (io), P8 PB7D (io), P10 PB9D (io), P11 PB10A (io), P12 PB10C (io), P13 PB11C (io), P14 PB11D (io)
part F pins: M3 PB2C (io), M4 PB3B (io), M6 PB6A (io), N3 PB2D (io), N4 PB4A (io), N6 PB5C (io), N7 PB6F (io), P5 PB4B (io)
part G pins: H1 PL10B (io), H2 PL10A (io), J1 PL11B (io), J2 PL11C/TSALL (io), J3 PL11D (io), K1 PL12B (io), K2 PL12A (io), L1 PL14A/LLM0_PLLT_FB_A (io), L3 PL14B/LLM0_PLLC_FB_A (io), M1 PL15A/LLM0_PLLT_IN_A (io), M2 PL15B/LLM0_PLLC_IN_A (io), N1 PL16A (io), P1 PL16B (io)
part H pins: B1 PL2A (io), B2 PL2B (io), C1 PL3C (io), C2 PL4A (io), C3 PL3D (io), D1 PL4B (io), D3 PL4C (io), E2 PL6A (io), E3 PL6B/GSRN (io), F2 PL6D (io), F3 PL7C (io), G1 PL7D (io), G2 PL8C (io), G3 PL8D (io)
part I pins: M5 TDI (in) "Powered by VCCIO5", N5 TDO (out) "Powered by VCCIO5", N12 SLEEPN (in) "Powered by VCCIO4", P3 TMS (in) "Powered by VCCIO5", P4 TCK (in) "Powered by VCCIO5"
part J pins: A7 VCCAUX (power), B11 VCCIO1 (power), C5 VCCIO0 (power), C7 VCC (power), D2 VCCIO7 (power), E12 VCCIO2 (power), G12 VCC (power), H3 VCC (power), K3 VCCIO6 (power), L12 VCCIO3 (power), M10 VCCIO4 (power), N2 VCCIO5 (power), P6 VCC (power), P7 VCCAUX (power)
part K pins: A10 GNDIO1 (power), B4 GNDIO0 (power), C9 GND (power), D13 GNDIO2 (power), E1 GNDIO7 (power), F1 GND (power), J14 GND (power), L2 GNDIO6 (power), L13 GNDIO3 (power), N11 GNDIO4 (power), P2 GNDIO5 (power), P9 GND (power)


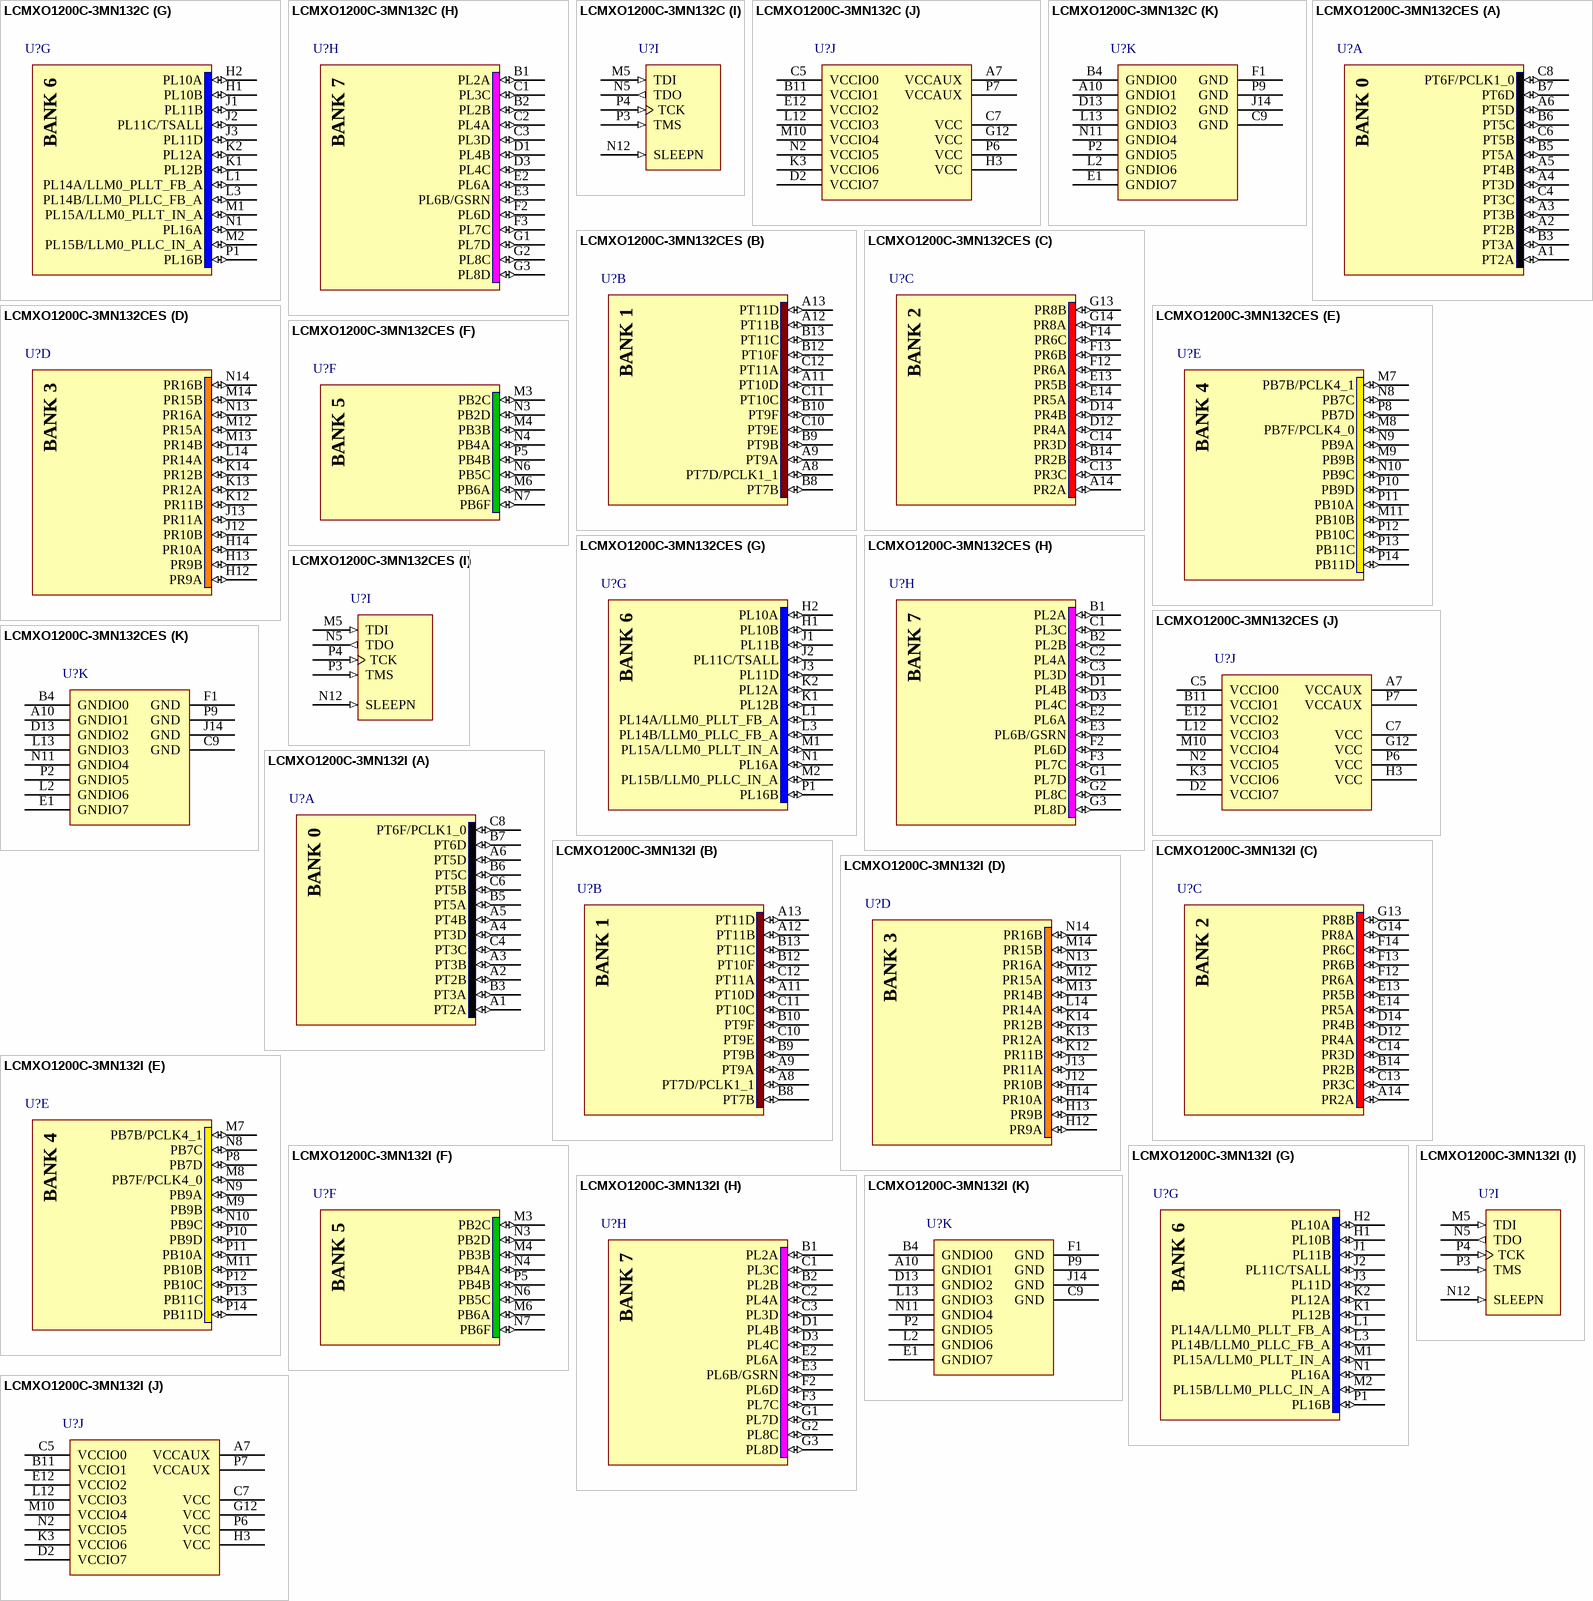
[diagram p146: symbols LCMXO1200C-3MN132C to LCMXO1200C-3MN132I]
## LCMXO1200C-3MN132C
designator U?
MachXO 1200 Crossover PLD, 1.8V/2.5V/3.3V, 101 User I/Os, 132-Pins csBGA, Speed Grade-3, Commercial Grade, Pb-Free
footprint csBGA132 (BGA, 132-Leads, Body 8x8mm, Pitch 0.5mm)
3D model MachXO1200-csBGA132 (132-Ball Chip Scale Ball Grid Array (csBGA132))
signal-integrity model LCMXO1200C_M132 (MachXO)
part A pins: A1 PT2A (io), A2 PT2B (io), A3 PT3B (io), A4 PT3D (io), A5 PT4B (io), A6 PT5D (io), B3 PT3A (io), B5 PT5A (io), B6 PT5C (io), B7 PT6D (io), C4 PT3C (io), C6 PT5B (io), C8 PT6F/PCLK1_0 (io)
part B pins: A8 PT7D/PCLK1_1 (io), A9 PT9A (io), A11 PT10D (io), A12 PT11B (io), A13 PT11D (io), B8 PT7B (io), B9 PT9B (io), B10 PT9F (io), B12 PT10F (io), B13 PT11C (io), C10 PT9E (io), C11 PT10C (io), C12 PT11A (io)
part C pins: A14 PR2A (io), B14 PR2B (io), C13 PR3C (io), C14 PR3D (io), D12 PR4A (io), D14 PR4B (io), E13 PR5B (io), E14 PR5A (io), F12 PR6A (io), F13 PR6B (io), F14 PR6C (io), G13 PR8B (io), G14 PR8A (io)
part D pins: H12 PR9A (io), H13 PR9B (io), H14 PR10A (io), J12 PR10B (io), J13 PR11A (io), K12 PR11B (io), K13 PR12A (io), K14 PR12B (io), L14 PR14A (io), M12 PR15A (io), M13 PR14B (io), M14 PR15B (io), N13 PR16A (io), N14 PR16B (io)
part E pins: M7 PB7B/PCLK4_1 (io), M8 PB7F/PCLK4_0 (io), M9 PB9B (io), M11 PB10B (io), N8 PB7C (io), N9 PB9A (io), N10 PB9C (io), P8 PB7D (io), P10 PB9D (io), P11 PB10A (io), P12 PB10C (io), P13 PB11C (io), P14 PB11D (io)
part F pins: M3 PB2C (io), M4 PB3B (io), M6 PB6A (io), N3 PB2D (io), N4 PB4A (io), N6 PB5C (io), N7 PB6F (io), P5 PB4B (io)
part G pins: H1 PL10B (io), H2 PL10A (io), J1 PL11B (io), J2 PL11C/TSALL (io), J3 PL11D (io), K1 PL12B (io), K2 PL12A (io), L1 PL14A/LLM0_PLLT_FB_A (io), L3 PL14B/LLM0_PLLC_FB_A (io), M1 PL15A/LLM0_PLLT_IN_A (io), M2 PL15B/LLM0_PLLC_IN_A (io), N1 PL16A (io), P1 PL16B (io)
part H pins: B1 PL2A (io), B2 PL2B (io), C1 PL3C (io), C2 PL4A (io), C3 PL3D (io), D1 PL4B (io), D3 PL4C (io), E2 PL6A (io), E3 PL6B/GSRN (io), F2 PL6D (io), F3 PL7C (io), G1 PL7D (io), G2 PL8C (io), G3 PL8D (io)
part I pins: M5 TDI (in) "Powered by VCCIO5", N5 TDO (out) "Powered by VCCIO5", N12 SLEEPN (in) "Powered by VCCIO4", P3 TMS (in) "Powered by VCCIO5", P4 TCK (in) "Powered by VCCIO5"
part J pins: A7 VCCAUX (power), B11 VCCIO1 (power), C5 VCCIO0 (power), C7 VCC (power), D2 VCCIO7 (power), E12 VCCIO2 (power), G12 VCC (power), H3 VCC (power), K3 VCCIO6 (power), L12 VCCIO3 (power), M10 VCCIO4 (power), N2 VCCIO5 (power), P6 VCC (power), P7 VCCAUX (power)
part K pins: A10 GNDIO1 (power), B4 GNDIO0 (power), C9 GND (power), D13 GNDIO2 (power), E1 GNDIO7 (power), F1 GND (power), J14 GND (power), L2 GNDIO6 (power), L13 GNDIO3 (power), N11 GNDIO4 (power), P2 GNDIO5 (power), P9 GND (power)

## LCMXO1200C-3MN132CES
designator U?
MachXO 1200 Crossover PLD, 1.8V/2.5V/3.3V, 101 User I/Os, 132-Pins csBGA, Speed Grade-3, Commercial Grade, Pb-Free, Engineering Sample
footprint csBGA132 (BGA, 132-Leads, Body 8x8mm, Pitch 0.5mm)
3D model MachXO1200-csBGA132 (132-Ball Chip Scale Ball Grid Array (csBGA132))
signal-integrity model LCMXO1200C_M132 (MachXO)
part A pins: A1 PT2A (io), A2 PT2B (io), A3 PT3B (io), A4 PT3D (io), A5 PT4B (io), A6 PT5D (io), B3 PT3A (io), B5 PT5A (io), B6 PT5C (io), B7 PT6D (io), C4 PT3C (io), C6 PT5B (io), C8 PT6F/PCLK1_0 (io)
part B pins: A8 PT7D/PCLK1_1 (io), A9 PT9A (io), A11 PT10D (io), A12 PT11B (io), A13 PT11D (io), B8 PT7B (io), B9 PT9B (io), B10 PT9F (io), B12 PT10F (io), B13 PT11C (io), C10 PT9E (io), C11 PT10C (io), C12 PT11A (io)
part C pins: A14 PR2A (io), B14 PR2B (io), C13 PR3C (io), C14 PR3D (io), D12 PR4A (io), D14 PR4B (io), E13 PR5B (io), E14 PR5A (io), F12 PR6A (io), F13 PR6B (io), F14 PR6C (io), G13 PR8B (io), G14 PR8A (io)
part D pins: H12 PR9A (io), H13 PR9B (io), H14 PR10A (io), J12 PR10B (io), J13 PR11A (io), K12 PR11B (io), K13 PR12A (io), K14 PR12B (io), L14 PR14A (io), M12 PR15A (io), M13 PR14B (io), M14 PR15B (io), N13 PR16A (io), N14 PR16B (io)
part E pins: M7 PB7B/PCLK4_1 (io), M8 PB7F/PCLK4_0 (io), M9 PB9B (io), M11 PB10B (io), N8 PB7C (io), N9 PB9A (io), N10 PB9C (io), P8 PB7D (io), P10 PB9D (io), P11 PB10A (io), P12 PB10C (io), P13 PB11C (io), P14 PB11D (io)
part F pins: M3 PB2C (io), M4 PB3B (io), M6 PB6A (io), N3 PB2D (io), N4 PB4A (io), N6 PB5C (io), N7 PB6F (io), P5 PB4B (io)
part G pins: H1 PL10B (io), H2 PL10A (io), J1 PL11B (io), J2 PL11C/TSALL (io), J3 PL11D (io), K1 PL12B (io), K2 PL12A (io), L1 PL14A/LLM0_PLLT_FB_A (io), L3 PL14B/LLM0_PLLC_FB_A (io), M1 PL15A/LLM0_PLLT_IN_A (io), M2 PL15B/LLM0_PLLC_IN_A (io), N1 PL16A (io), P1 PL16B (io)
part H pins: B1 PL2A (io), B2 PL2B (io), C1 PL3C (io), C2 PL4A (io), C3 PL3D (io), D1 PL4B (io), D3 PL4C (io), E2 PL6A (io), E3 PL6B/GSRN (io), F2 PL6D (io), F3 PL7C (io), G1 PL7D (io), G2 PL8C (io), G3 PL8D (io)
part I pins: M5 TDI (in) "Powered by VCCIO5", N5 TDO (out) "Powered by VCCIO5", N12 SLEEPN (in) "Powered by VCCIO4", P3 TMS (in) "Powered by VCCIO5", P4 TCK (in) "Powered by VCCIO5"
part J pins: A7 VCCAUX (power), B11 VCCIO1 (power), C5 VCCIO0 (power), C7 VCC (power), D2 VCCIO7 (power), E12 VCCIO2 (power), G12 VCC (power), H3 VCC (power), K3 VCCIO6 (power), L12 VCCIO3 (power), M10 VCCIO4 (power), N2 VCCIO5 (power), P6 VCC (power), P7 VCCAUX (power)
part K pins: A10 GNDIO1 (power), B4 GNDIO0 (power), C9 GND (power), D13 GNDIO2 (power), E1 GNDIO7 (power), F1 GND (power), J14 GND (power), L2 GNDIO6 (power), L13 GNDIO3 (power), N11 GNDIO4 (power), P2 GNDIO5 (power), P9 GND (power)

## LCMXO1200C-3MN132I
designator U?
MachXO 1200 Crossover PLD, 1.8V/2.5V/3.3V, 101 User I/Os, 132-Pins csBGA, Speed Grade-3, Industrial Grade, Pb-Free
footprint csBGA132 (BGA, 132-Leads, Body 8x8mm, Pitch 0.5mm)
3D model MachXO1200-csBGA132 (132-Ball Chip Scale Ball Grid Array (csBGA132))
signal-integrity model LCMXO1200C_M132 (MachXO)
part A pins: A1 PT2A (io), A2 PT2B (io), A3 PT3B (io), A4 PT3D (io), A5 PT4B (io), A6 PT5D (io), B3 PT3A (io), B5 PT5A (io), B6 PT5C (io), B7 PT6D (io), C4 PT3C (io), C6 PT5B (io), C8 PT6F/PCLK1_0 (io)
part B pins: A8 PT7D/PCLK1_1 (io), A9 PT9A (io), A11 PT10D (io), A12 PT11B (io), A13 PT11D (io), B8 PT7B (io), B9 PT9B (io), B10 PT9F (io), B12 PT10F (io), B13 PT11C (io), C10 PT9E (io), C11 PT10C (io), C12 PT11A (io)
part C pins: A14 PR2A (io), B14 PR2B (io), C13 PR3C (io), C14 PR3D (io), D12 PR4A (io), D14 PR4B (io), E13 PR5B (io), E14 PR5A (io), F12 PR6A (io), F13 PR6B (io), F14 PR6C (io), G13 PR8B (io), G14 PR8A (io)
part D pins: H12 PR9A (io), H13 PR9B (io), H14 PR10A (io), J12 PR10B (io), J13 PR11A (io), K12 PR11B (io), K13 PR12A (io), K14 PR12B (io), L14 PR14A (io), M12 PR15A (io), M13 PR14B (io), M14 PR15B (io), N13 PR16A (io), N14 PR16B (io)
part E pins: M7 PB7B/PCLK4_1 (io), M8 PB7F/PCLK4_0 (io), M9 PB9B (io), M11 PB10B (io), N8 PB7C (io), N9 PB9A (io), N10 PB9C (io), P8 PB7D (io), P10 PB9D (io), P11 PB10A (io), P12 PB10C (io), P13 PB11C (io), P14 PB11D (io)
part F pins: M3 PB2C (io), M4 PB3B (io), M6 PB6A (io), N3 PB2D (io), N4 PB4A (io), N6 PB5C (io), N7 PB6F (io), P5 PB4B (io)
part G pins: H1 PL10B (io), H2 PL10A (io), J1 PL11B (io), J2 PL11C/TSALL (io), J3 PL11D (io), K1 PL12B (io), K2 PL12A (io), L1 PL14A/LLM0_PLLT_FB_A (io), L3 PL14B/LLM0_PLLC_FB_A (io), M1 PL15A/LLM0_PLLT_IN_A (io), M2 PL15B/LLM0_PLLC_IN_A (io), N1 PL16A (io), P1 PL16B (io)
part H pins: B1 PL2A (io), B2 PL2B (io), C1 PL3C (io), C2 PL4A (io), C3 PL3D (io), D1 PL4B (io), D3 PL4C (io), E2 PL6A (io), E3 PL6B/GSRN (io), F2 PL6D (io), F3 PL7C (io), G1 PL7D (io), G2 PL8C (io), G3 PL8D (io)
part I pins: M5 TDI (in) "Powered by VCCIO5", N5 TDO (out) "Powered by VCCIO5", N12 SLEEPN (in) "Powered by VCCIO4", P3 TMS (in) "Powered by VCCIO5", P4 TCK (in) "Powered by VCCIO5"
part J pins: A7 VCCAUX (power), B11 VCCIO1 (power), C5 VCCIO0 (power), C7 VCC (power), D2 VCCIO7 (power), E12 VCCIO2 (power), G12 VCC (power), H3 VCC (power), K3 VCCIO6 (power), L12 VCCIO3 (power), M10 VCCIO4 (power), N2 VCCIO5 (power), P6 VCC (power), P7 VCCAUX (power)
part K pins: A10 GNDIO1 (power), B4 GNDIO0 (power), C9 GND (power), D13 GNDIO2 (power), E1 GNDIO7 (power), F1 GND (power), J14 GND (power), L2 GNDIO6 (power), L13 GNDIO3 (power), N11 GNDIO4 (power), P2 GNDIO5 (power), P9 GND (power)


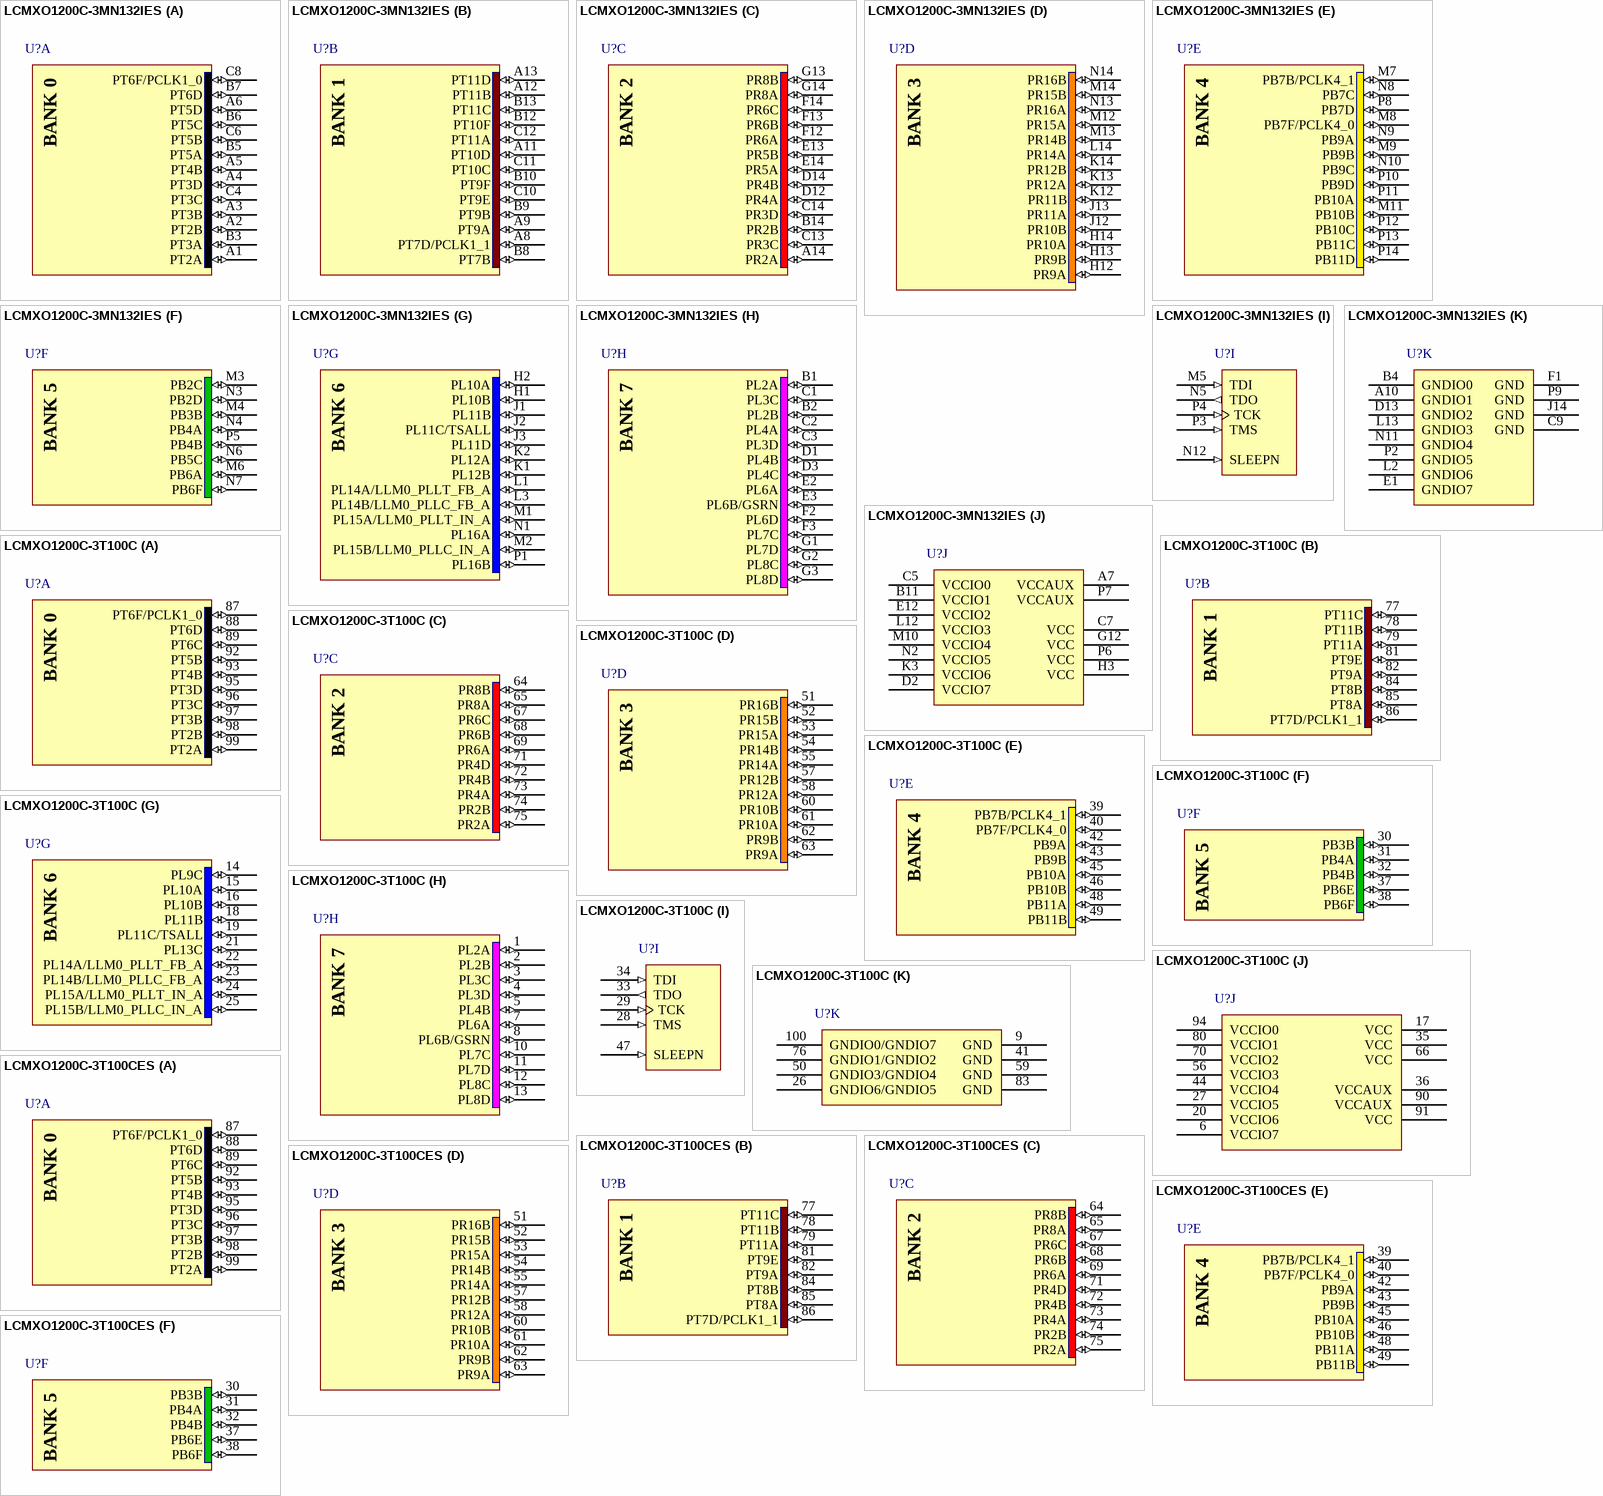
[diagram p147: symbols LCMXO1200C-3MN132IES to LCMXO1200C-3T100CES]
## LCMXO1200C-3MN132IES
designator U?
MachXO 1200 Crossover PLD, 1.8V/2.5V/3.3V, 101 User I/Os, 132-Pins csBGA, Speed Grade-3, Industrial Grade, Pb-Free, Engineering Sample
footprint csBGA132 (BGA, 132-Leads, Body 8x8mm, Pitch 0.5mm)
3D model MachXO1200-csBGA132 (132-Ball Chip Scale Ball Grid Array (csBGA132))
signal-integrity model LCMXO1200C_M132 (MachXO)
part A pins: A1 PT2A (io), A2 PT2B (io), A3 PT3B (io), A4 PT3D (io), A5 PT4B (io), A6 PT5D (io), B3 PT3A (io), B5 PT5A (io), B6 PT5C (io), B7 PT6D (io), C4 PT3C (io), C6 PT5B (io), C8 PT6F/PCLK1_0 (io)
part B pins: A8 PT7D/PCLK1_1 (io), A9 PT9A (io), A11 PT10D (io), A12 PT11B (io), A13 PT11D (io), B8 PT7B (io), B9 PT9B (io), B10 PT9F (io), B12 PT10F (io), B13 PT11C (io), C10 PT9E (io), C11 PT10C (io), C12 PT11A (io)
part C pins: A14 PR2A (io), B14 PR2B (io), C13 PR3C (io), C14 PR3D (io), D12 PR4A (io), D14 PR4B (io), E13 PR5B (io), E14 PR5A (io), F12 PR6A (io), F13 PR6B (io), F14 PR6C (io), G13 PR8B (io), G14 PR8A (io)
part D pins: H12 PR9A (io), H13 PR9B (io), H14 PR10A (io), J12 PR10B (io), J13 PR11A (io), K12 PR11B (io), K13 PR12A (io), K14 PR12B (io), L14 PR14A (io), M12 PR15A (io), M13 PR14B (io), M14 PR15B (io), N13 PR16A (io), N14 PR16B (io)
part E pins: M7 PB7B/PCLK4_1 (io), M8 PB7F/PCLK4_0 (io), M9 PB9B (io), M11 PB10B (io), N8 PB7C (io), N9 PB9A (io), N10 PB9C (io), P8 PB7D (io), P10 PB9D (io), P11 PB10A (io), P12 PB10C (io), P13 PB11C (io), P14 PB11D (io)
part F pins: M3 PB2C (io), M4 PB3B (io), M6 PB6A (io), N3 PB2D (io), N4 PB4A (io), N6 PB5C (io), N7 PB6F (io), P5 PB4B (io)
part G pins: H1 PL10B (io), H2 PL10A (io), J1 PL11B (io), J2 PL11C/TSALL (io), J3 PL11D (io), K1 PL12B (io), K2 PL12A (io), L1 PL14A/LLM0_PLLT_FB_A (io), L3 PL14B/LLM0_PLLC_FB_A (io), M1 PL15A/LLM0_PLLT_IN_A (io), M2 PL15B/LLM0_PLLC_IN_A (io), N1 PL16A (io), P1 PL16B (io)
part H pins: B1 PL2A (io), B2 PL2B (io), C1 PL3C (io), C2 PL4A (io), C3 PL3D (io), D1 PL4B (io), D3 PL4C (io), E2 PL6A (io), E3 PL6B/GSRN (io), F2 PL6D (io), F3 PL7C (io), G1 PL7D (io), G2 PL8C (io), G3 PL8D (io)
part I pins: M5 TDI (in) "Powered by VCCIO5", N5 TDO (out) "Powered by VCCIO5", N12 SLEEPN (in) "Powered by VCCIO4", P3 TMS (in) "Powered by VCCIO5", P4 TCK (in) "Powered by VCCIO5"
part J pins: A7 VCCAUX (power), B11 VCCIO1 (power), C5 VCCIO0 (power), C7 VCC (power), D2 VCCIO7 (power), E12 VCCIO2 (power), G12 VCC (power), H3 VCC (power), K3 VCCIO6 (power), L12 VCCIO3 (power), M10 VCCIO4 (power), N2 VCCIO5 (power), P6 VCC (power), P7 VCCAUX (power)
part K pins: A10 GNDIO1 (power), B4 GNDIO0 (power), C9 GND (power), D13 GNDIO2 (power), E1 GNDIO7 (power), F1 GND (power), J14 GND (power), L2 GNDIO6 (power), L13 GNDIO3 (power), N11 GNDIO4 (power), P2 GNDIO5 (power), P9 GND (power)

## LCMXO1200C-3T100C
designator U?
MachXO 1200 Crossover PLD, 1.8V/2.5V/3.3V, 73 User I/Os, 100-Pins TQFP, Speed Grade-3, Commercial Grade
footprint TQFP100_N (Thin QFP, 100-Leads, Body 14x14mm, Pitch 0.5mm, IPC Medium Density)
footprint TQFP100_L (Thin QFP, 100-Leads, Body 14x14mm, Pitch 0.5mm, IPC High Density)
footprint TQFP100_M (Thin QFP, 100-Leads, Body 14x14mm, Pitch 0.5mm, IPC Low Density)
3D model MachXO1200-TQFP100 (100-Pin Thin Quad Flat Pack (TQFP100))
signal-integrity model LCMXO1200C_T100 (MachXO)
part A pins: 87 PT6F/PCLK1_0 (io), 88 PT6D (io), 89 PT6C (io), 92 PT5B (io), 93 PT4B (io), 95 PT3D (io), 96 PT3C (io), 97 PT3B (io), 98 PT2B (io), 99 PT2A (io)
part B pins: 77 PT11C (io), 78 PT11B (io), 79 PT11A (io), 81 PT9E (io), 82 PT9A (io), 84 PT8B (io), 85 PT8A (io), 86 PT7D/PCLK1_1 (io)
part C pins: 64 PR8B (io), 65 PR8A (io), 67 PR6C (io), 68 PR6B (io), 69 PR6A (io), 71 PR4D (io), 72 PR4B (io), 73 PR4A (io), 74 PR2B (io), 75 PR2A (io)
part D pins: 51 PR16B (io), 52 PR15B (io), 53 PR15A (io), 54 PR14B (io), 55 PR14A (io), 57 PR12B (io), 58 PR12A (io), 60 PR10B (io), 61 PR10A (io), 62 PR9B (io), 63 PR9A (io)
part E pins: 39 PB7B/PCLK4_1 (io), 40 PB7F/PCLK4_0 (io), 42 PB9A (io), 43 PB9B (io), 45 PB10A (io), 46 PB10B (io), 48 PB11A (io), 49 PB11B (io)
part F pins: 30 PB3B (io), 31 PB4A (io), 32 PB4B (io), 37 PB6E (io), 38 PB6F (io)
part G pins: 14 PL9C (io), 15 PL10A (io), 16 PL10B (io), 18 PL11B (io), 19 PL11C/TSALL (io), 21 PL13C (io), 22 PL14A/LLM0_PLLT_FB_A (io), 23 PL14B/LLM0_PLLC_FB_A (io), 24 PL15A/LLM0_PLLT_IN_A (io), 25 PL15B/LLM0_PLLC_IN_A (io)
part H pins: 1 PL2A (io), 2 PL2B (io), 3 PL3C (io), 4 PL3D (io), 5 PL4B (io), 7 PL6A (io), 8 PL6B/GSRN (io), 10 PL7C (io), 11 PL7D (io), 12 PL8C (io), 13 PL8D (io)
part I pins: 28 TMS (in) "Powered by VCCIO5", 29 TCK (in) "Powered by VCCIO5", 33 TDO (out) "Powered by VCCIO5", 34 TDI (in) "Powered by VCCIO5", 47 SLEEPN (in) "Powered by VCCIO5"
part J pins: 6 VCCIO7 (power), 17 VCC (power), 20 VCCIO6 (power), 27 VCCIO5 (power), 35 VCC (power), 36 VCCAUX (power), 44 VCCIO4 (power), 56 VCCIO3 (power), 66 VCC (power), 70 VCCIO2 (power), 80 VCCIO1 (power), 90 VCCAUX (power), 91 VCC (power), 94 VCCIO0 (power)
part K pins: 9 GND (power), 26 GNDIO6/GNDIO5 (power) "Double Bonded pin", 41 GND (power), 50 GNDIO3/GNDIO4 (power) "Double Bonded pin", 59 GND (power), 76 GNDIO1/GNDIO2 (power) "Double Bonded pin", 83 GND (power), 100 GNDIO0/GNDIO7 (power) "Double Bonded pin"


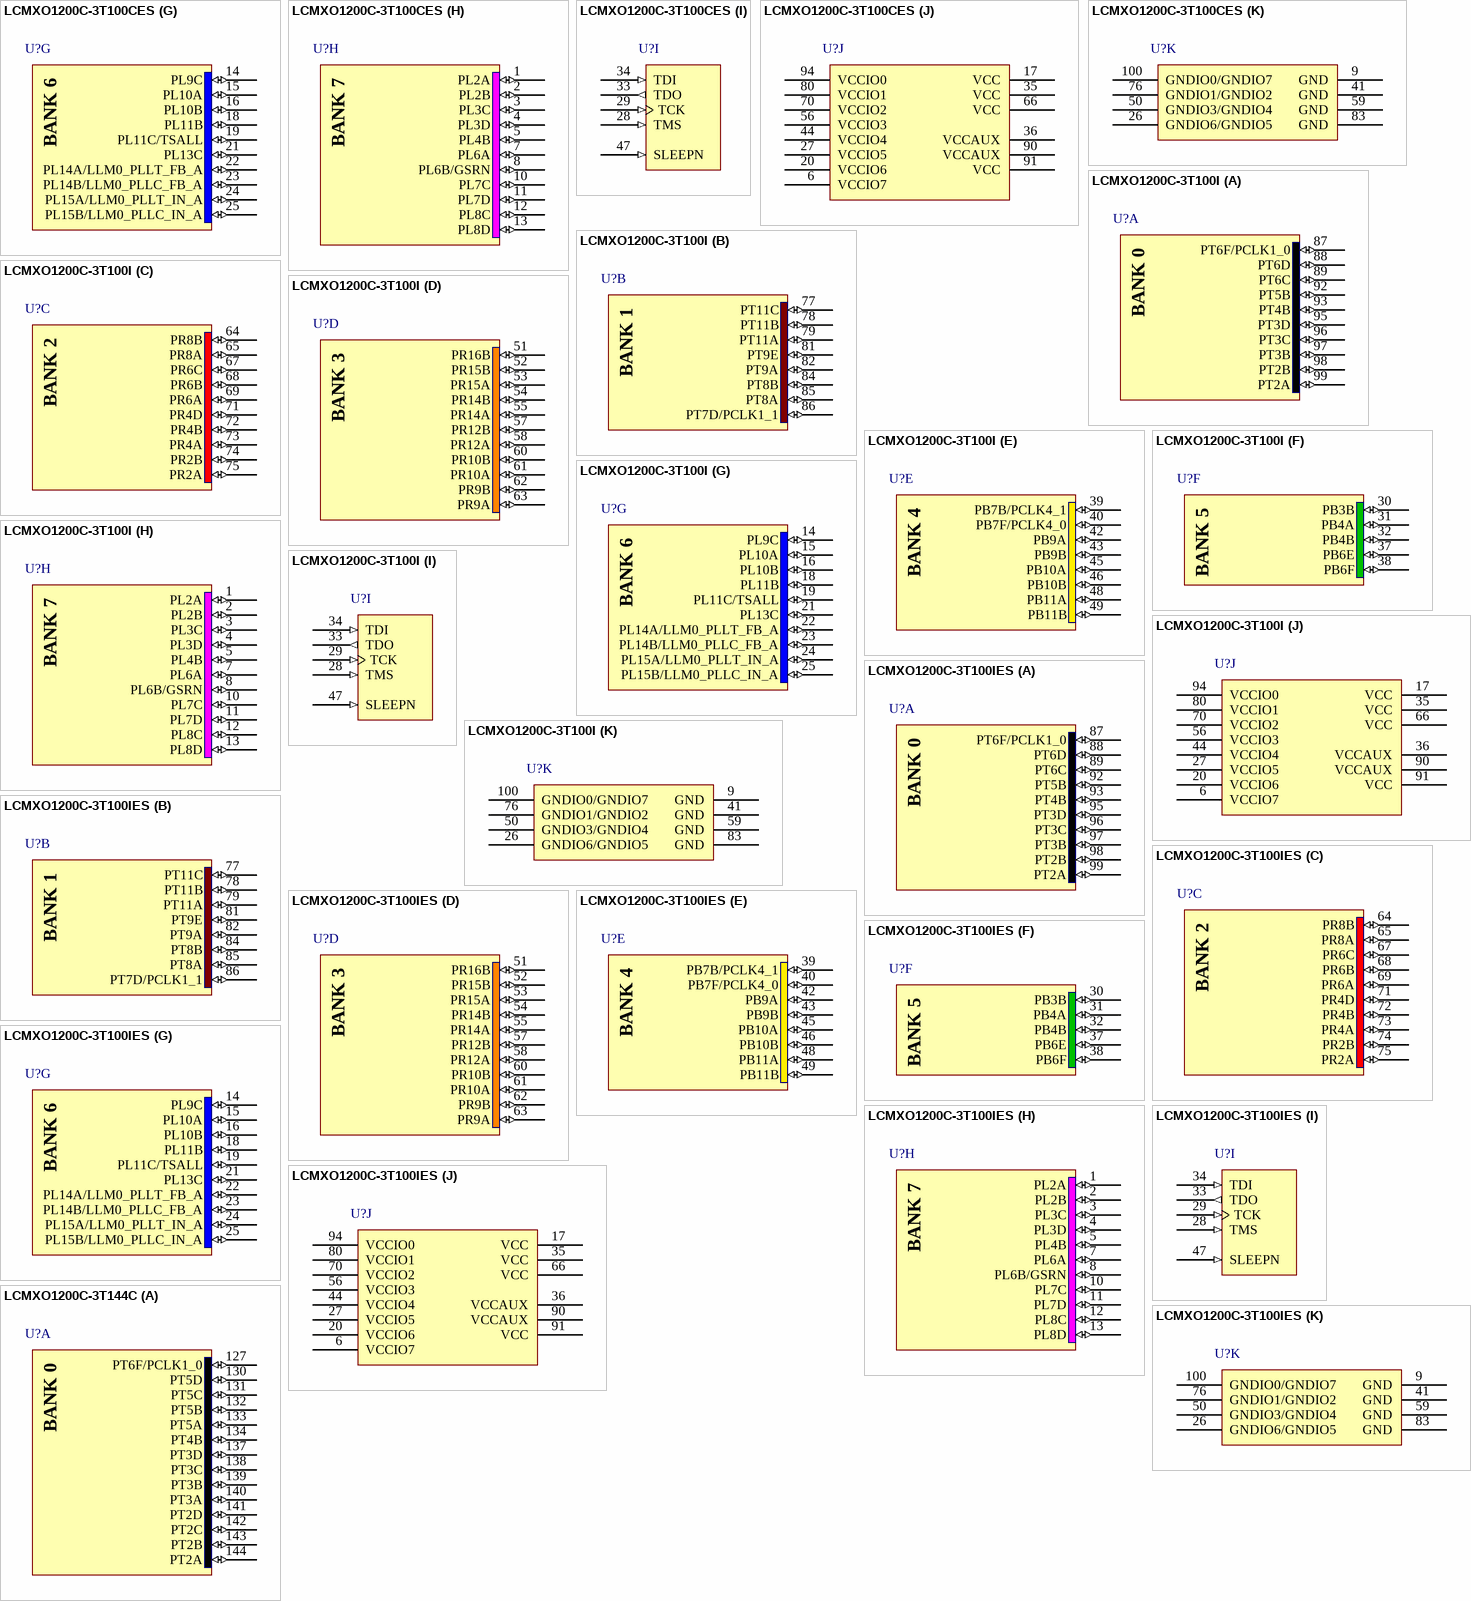
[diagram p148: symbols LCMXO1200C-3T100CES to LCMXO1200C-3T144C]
## LCMXO1200C-3T100CES
designator U?
MachXO 1200 Crossover PLD, 1.8V/2.5V/3.3V, 73 User I/Os, 100-Pins TQFP, Speed Grade-3, Commercial Grade, Engineering Sample
footprint TQFP100_N (Thin QFP, 100-Leads, Body 14x14mm, Pitch 0.5mm, IPC Medium Density)
footprint TQFP100_L (Thin QFP, 100-Leads, Body 14x14mm, Pitch 0.5mm, IPC High Density)
footprint TQFP100_M (Thin QFP, 100-Leads, Body 14x14mm, Pitch 0.5mm, IPC Low Density)
3D model MachXO1200-TQFP100 (100-Pin Thin Quad Flat Pack (TQFP100))
signal-integrity model LCMXO1200C_T100 (MachXO)
part A pins: 87 PT6F/PCLK1_0 (io), 88 PT6D (io), 89 PT6C (io), 92 PT5B (io), 93 PT4B (io), 95 PT3D (io), 96 PT3C (io), 97 PT3B (io), 98 PT2B (io), 99 PT2A (io)
part B pins: 77 PT11C (io), 78 PT11B (io), 79 PT11A (io), 81 PT9E (io), 82 PT9A (io), 84 PT8B (io), 85 PT8A (io), 86 PT7D/PCLK1_1 (io)
part C pins: 64 PR8B (io), 65 PR8A (io), 67 PR6C (io), 68 PR6B (io), 69 PR6A (io), 71 PR4D (io), 72 PR4B (io), 73 PR4A (io), 74 PR2B (io), 75 PR2A (io)
part D pins: 51 PR16B (io), 52 PR15B (io), 53 PR15A (io), 54 PR14B (io), 55 PR14A (io), 57 PR12B (io), 58 PR12A (io), 60 PR10B (io), 61 PR10A (io), 62 PR9B (io), 63 PR9A (io)
part E pins: 39 PB7B/PCLK4_1 (io), 40 PB7F/PCLK4_0 (io), 42 PB9A (io), 43 PB9B (io), 45 PB10A (io), 46 PB10B (io), 48 PB11A (io), 49 PB11B (io)
part F pins: 30 PB3B (io), 31 PB4A (io), 32 PB4B (io), 37 PB6E (io), 38 PB6F (io)
part G pins: 14 PL9C (io), 15 PL10A (io), 16 PL10B (io), 18 PL11B (io), 19 PL11C/TSALL (io), 21 PL13C (io), 22 PL14A/LLM0_PLLT_FB_A (io), 23 PL14B/LLM0_PLLC_FB_A (io), 24 PL15A/LLM0_PLLT_IN_A (io), 25 PL15B/LLM0_PLLC_IN_A (io)
part H pins: 1 PL2A (io), 2 PL2B (io), 3 PL3C (io), 4 PL3D (io), 5 PL4B (io), 7 PL6A (io), 8 PL6B/GSRN (io), 10 PL7C (io), 11 PL7D (io), 12 PL8C (io), 13 PL8D (io)
part I pins: 28 TMS (in) "Powered by VCCIO5", 29 TCK (in) "Powered by VCCIO5", 33 TDO (out) "Powered by VCCIO5", 34 TDI (in) "Powered by VCCIO5", 47 SLEEPN (in) "Powered by VCCIO5"
part J pins: 6 VCCIO7 (power), 17 VCC (power), 20 VCCIO6 (power), 27 VCCIO5 (power), 35 VCC (power), 36 VCCAUX (power), 44 VCCIO4 (power), 56 VCCIO3 (power), 66 VCC (power), 70 VCCIO2 (power), 80 VCCIO1 (power), 90 VCCAUX (power), 91 VCC (power), 94 VCCIO0 (power)
part K pins: 9 GND (power), 26 GNDIO6/GNDIO5 (power) "Double Bonded pin", 41 GND (power), 50 GNDIO3/GNDIO4 (power) "Double Bonded pin", 59 GND (power), 76 GNDIO1/GNDIO2 (power) "Double Bonded pin", 83 GND (power), 100 GNDIO0/GNDIO7 (power) "Double Bonded pin"

## LCMXO1200C-3T100I
designator U?
MachXO 1200 Crossover PLD, 1.8V/2.5V/3.3V, 73 User I/Os, 100-Pins TQFP, Speed Grade-3, Industrial Grade
footprint TQFP100_N (Thin QFP, 100-Leads, Body 14x14mm, Pitch 0.5mm, IPC Medium Density)
footprint TQFP100_L (Thin QFP, 100-Leads, Body 14x14mm, Pitch 0.5mm, IPC High Density)
footprint TQFP100_M (Thin QFP, 100-Leads, Body 14x14mm, Pitch 0.5mm, IPC Low Density)
3D model MachXO1200-TQFP100 (100-Pin Thin Quad Flat Pack (TQFP100))
signal-integrity model LCMXO1200C_T100 (MachXO)
part A pins: 87 PT6F/PCLK1_0 (io), 88 PT6D (io), 89 PT6C (io), 92 PT5B (io), 93 PT4B (io), 95 PT3D (io), 96 PT3C (io), 97 PT3B (io), 98 PT2B (io), 99 PT2A (io)
part B pins: 77 PT11C (io), 78 PT11B (io), 79 PT11A (io), 81 PT9E (io), 82 PT9A (io), 84 PT8B (io), 85 PT8A (io), 86 PT7D/PCLK1_1 (io)
part C pins: 64 PR8B (io), 65 PR8A (io), 67 PR6C (io), 68 PR6B (io), 69 PR6A (io), 71 PR4D (io), 72 PR4B (io), 73 PR4A (io), 74 PR2B (io), 75 PR2A (io)
part D pins: 51 PR16B (io), 52 PR15B (io), 53 PR15A (io), 54 PR14B (io), 55 PR14A (io), 57 PR12B (io), 58 PR12A (io), 60 PR10B (io), 61 PR10A (io), 62 PR9B (io), 63 PR9A (io)
part E pins: 39 PB7B/PCLK4_1 (io), 40 PB7F/PCLK4_0 (io), 42 PB9A (io), 43 PB9B (io), 45 PB10A (io), 46 PB10B (io), 48 PB11A (io), 49 PB11B (io)
part F pins: 30 PB3B (io), 31 PB4A (io), 32 PB4B (io), 37 PB6E (io), 38 PB6F (io)
part G pins: 14 PL9C (io), 15 PL10A (io), 16 PL10B (io), 18 PL11B (io), 19 PL11C/TSALL (io), 21 PL13C (io), 22 PL14A/LLM0_PLLT_FB_A (io), 23 PL14B/LLM0_PLLC_FB_A (io), 24 PL15A/LLM0_PLLT_IN_A (io), 25 PL15B/LLM0_PLLC_IN_A (io)
part H pins: 1 PL2A (io), 2 PL2B (io), 3 PL3C (io), 4 PL3D (io), 5 PL4B (io), 7 PL6A (io), 8 PL6B/GSRN (io), 10 PL7C (io), 11 PL7D (io), 12 PL8C (io), 13 PL8D (io)
part I pins: 28 TMS (in) "Powered by VCCIO5", 29 TCK (in) "Powered by VCCIO5", 33 TDO (out) "Powered by VCCIO5", 34 TDI (in) "Powered by VCCIO5", 47 SLEEPN (in) "Powered by VCCIO5"
part J pins: 6 VCCIO7 (power), 17 VCC (power), 20 VCCIO6 (power), 27 VCCIO5 (power), 35 VCC (power), 36 VCCAUX (power), 44 VCCIO4 (power), 56 VCCIO3 (power), 66 VCC (power), 70 VCCIO2 (power), 80 VCCIO1 (power), 90 VCCAUX (power), 91 VCC (power), 94 VCCIO0 (power)
part K pins: 9 GND (power), 26 GNDIO6/GNDIO5 (power) "Double Bonded pin", 41 GND (power), 50 GNDIO3/GNDIO4 (power) "Double Bonded pin", 59 GND (power), 76 GNDIO1/GNDIO2 (power) "Double Bonded pin", 83 GND (power), 100 GNDIO0/GNDIO7 (power) "Double Bonded pin"

## LCMXO1200C-3T100IES
designator U?
MachXO 1200 Crossover PLD, 1.8V/2.5V/3.3V, 73 User I/Os, 100-Pins TQFP, Speed Grade-3, Industrial Grade, Engineering Sample
footprint TQFP100_N (Thin QFP, 100-Leads, Body 14x14mm, Pitch 0.5mm, IPC Medium Density)
footprint TQFP100_L (Thin QFP, 100-Leads, Body 14x14mm, Pitch 0.5mm, IPC High Density)
footprint TQFP100_M (Thin QFP, 100-Leads, Body 14x14mm, Pitch 0.5mm, IPC Low Density)
3D model MachXO1200-TQFP100 (100-Pin Thin Quad Flat Pack (TQFP100))
signal-integrity model LCMXO1200C_T100 (MachXO)
part A pins: 87 PT6F/PCLK1_0 (io), 88 PT6D (io), 89 PT6C (io), 92 PT5B (io), 93 PT4B (io), 95 PT3D (io), 96 PT3C (io), 97 PT3B (io), 98 PT2B (io), 99 PT2A (io)
part B pins: 77 PT11C (io), 78 PT11B (io), 79 PT11A (io), 81 PT9E (io), 82 PT9A (io), 84 PT8B (io), 85 PT8A (io), 86 PT7D/PCLK1_1 (io)
part C pins: 64 PR8B (io), 65 PR8A (io), 67 PR6C (io), 68 PR6B (io), 69 PR6A (io), 71 PR4D (io), 72 PR4B (io), 73 PR4A (io), 74 PR2B (io), 75 PR2A (io)
part D pins: 51 PR16B (io), 52 PR15B (io), 53 PR15A (io), 54 PR14B (io), 55 PR14A (io), 57 PR12B (io), 58 PR12A (io), 60 PR10B (io), 61 PR10A (io), 62 PR9B (io), 63 PR9A (io)
part E pins: 39 PB7B/PCLK4_1 (io), 40 PB7F/PCLK4_0 (io), 42 PB9A (io), 43 PB9B (io), 45 PB10A (io), 46 PB10B (io), 48 PB11A (io), 49 PB11B (io)
part F pins: 30 PB3B (io), 31 PB4A (io), 32 PB4B (io), 37 PB6E (io), 38 PB6F (io)
part G pins: 14 PL9C (io), 15 PL10A (io), 16 PL10B (io), 18 PL11B (io), 19 PL11C/TSALL (io), 21 PL13C (io), 22 PL14A/LLM0_PLLT_FB_A (io), 23 PL14B/LLM0_PLLC_FB_A (io), 24 PL15A/LLM0_PLLT_IN_A (io), 25 PL15B/LLM0_PLLC_IN_A (io)
part H pins: 1 PL2A (io), 2 PL2B (io), 3 PL3C (io), 4 PL3D (io), 5 PL4B (io), 7 PL6A (io), 8 PL6B/GSRN (io), 10 PL7C (io), 11 PL7D (io), 12 PL8C (io), 13 PL8D (io)
part I pins: 28 TMS (in) "Powered by VCCIO5", 29 TCK (in) "Powered by VCCIO5", 33 TDO (out) "Powered by VCCIO5", 34 TDI (in) "Powered by VCCIO5", 47 SLEEPN (in) "Powered by VCCIO5"
part J pins: 6 VCCIO7 (power), 17 VCC (power), 20 VCCIO6 (power), 27 VCCIO5 (power), 35 VCC (power), 36 VCCAUX (power), 44 VCCIO4 (power), 56 VCCIO3 (power), 66 VCC (power), 70 VCCIO2 (power), 80 VCCIO1 (power), 90 VCCAUX (power), 91 VCC (power), 94 VCCIO0 (power)
part K pins: 9 GND (power), 26 GNDIO6/GNDIO5 (power) "Double Bonded pin", 41 GND (power), 50 GNDIO3/GNDIO4 (power) "Double Bonded pin", 59 GND (power), 76 GNDIO1/GNDIO2 (power) "Double Bonded pin", 83 GND (power), 100 GNDIO0/GNDIO7 (power) "Double Bonded pin"


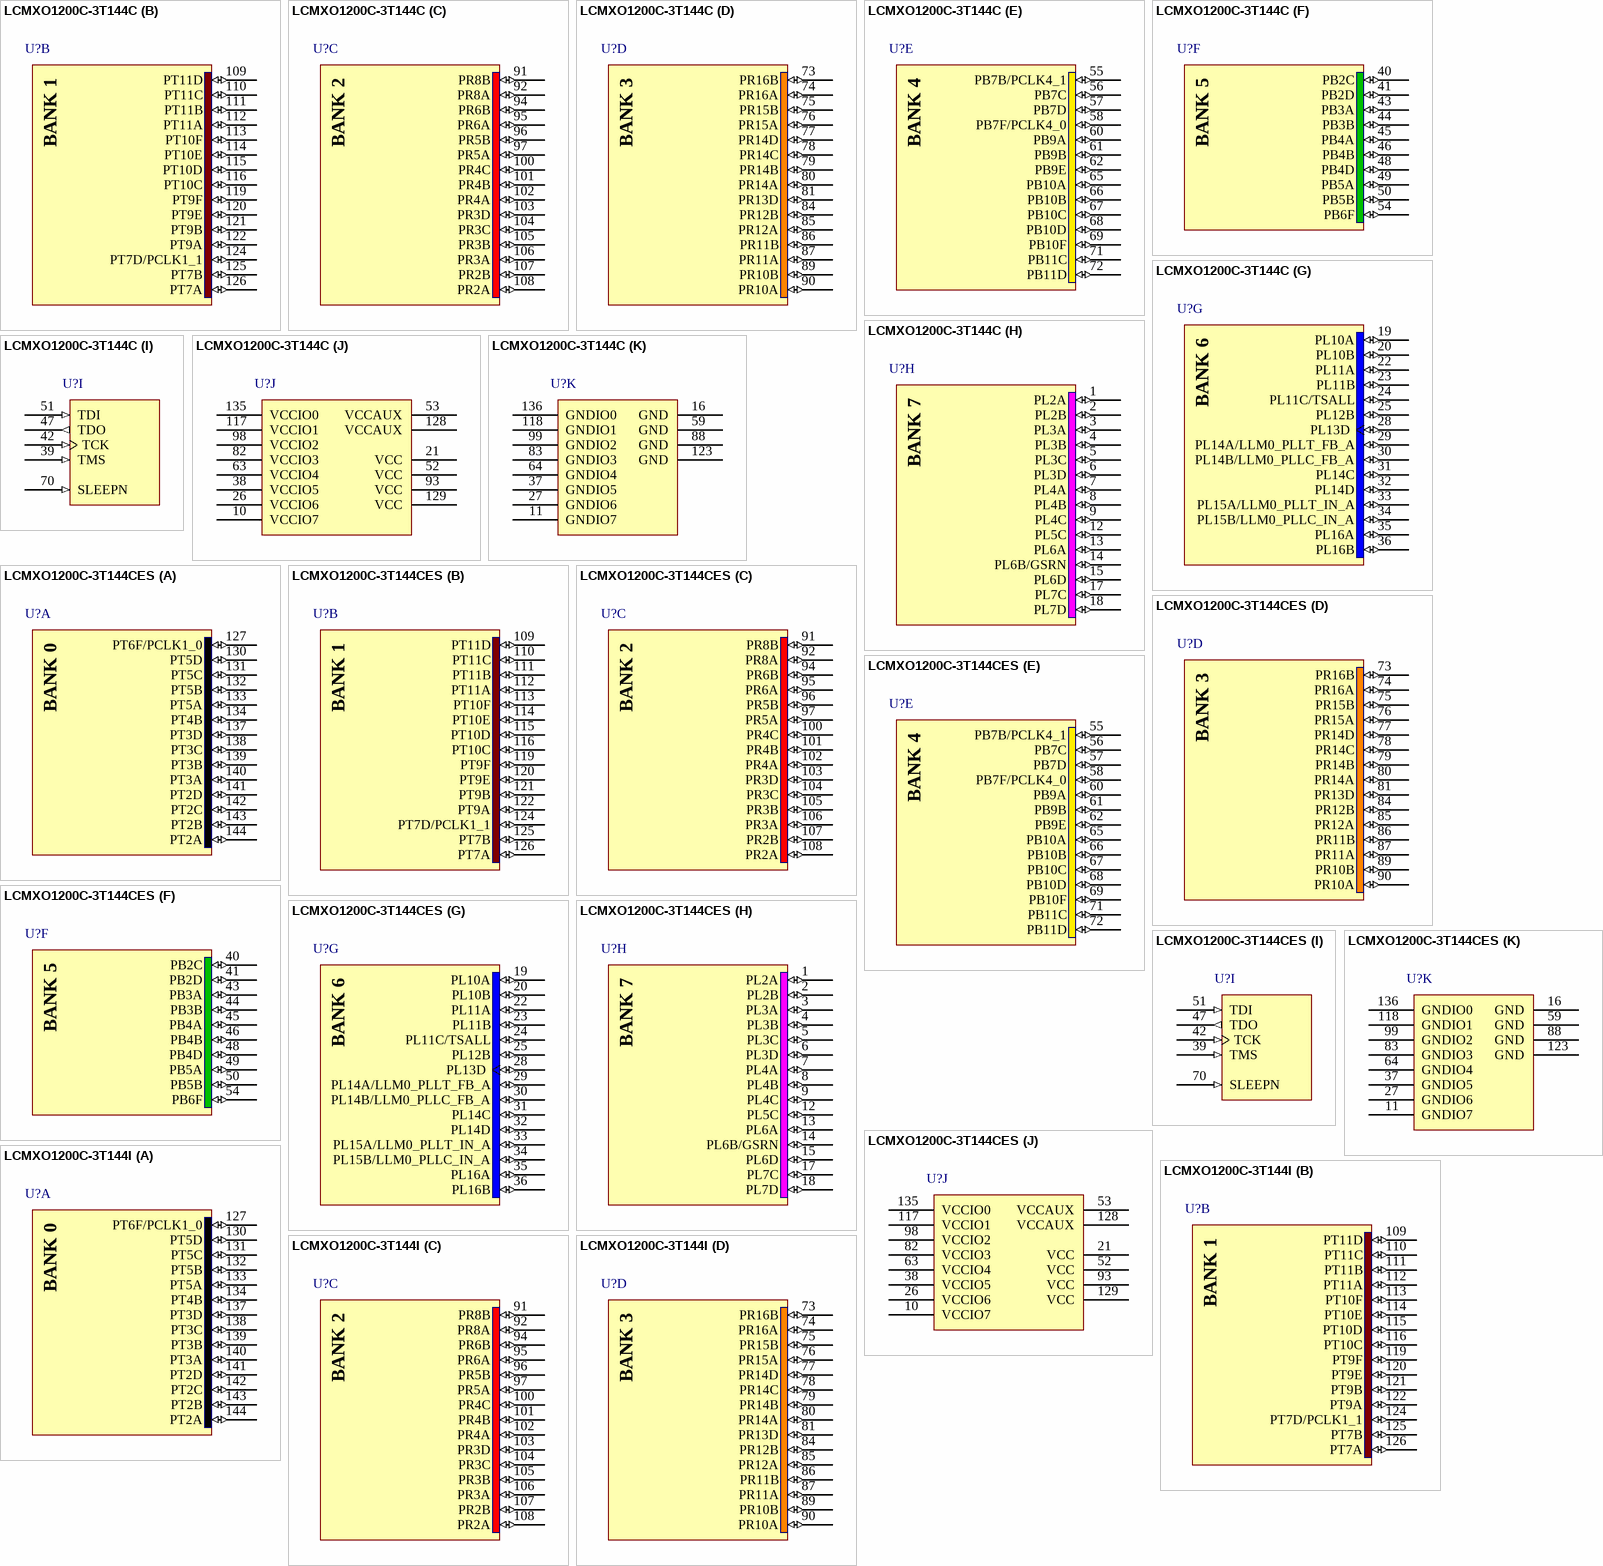
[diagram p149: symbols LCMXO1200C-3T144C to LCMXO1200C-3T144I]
## LCMXO1200C-3T144C
designator U?
MachXO 1200 Crossover PLD, 1.8V/2.5V/3.3V, 113 User I/Os, 144-Pins TQFP, Speed Grade-3, Commercial Grade
footprint TQFP144_N (Thin QFP, 144-Leads, Body 20x20mm, Pitch 0.5mm, IPC Medium Density)
footprint TQFP144_L (Thin QFP, 144-Leads, Body 20x20mm, Pitch 0.5mm, IPC High Density)
footprint TQFP144_M (Thin QFP, 144-Leads, Body 20x20mm, Pitch 0.5mm, IPC Low Density)
3D model MachXO1200-TQFP144 (144-Pin Thin Quad Flat Pack (TQFP144))
signal-integrity model LCMXO1200C_T144 (MachXO)
part A pins: 127 PT6F/PCLK1_0 (io), 130 PT5D (io), 131 PT5C (io), 132 PT5B (io), 133 PT5A (io), 134 PT4B (io), 137 PT3D (io), 138 PT3C (io), 139 PT3B (io), 140 PT3A (io), 141 PT2D (io), 142 PT2C (io), 143 PT2B (io), 144 PT2A (io)
part B pins: 109 PT11D (io), 110 PT11C (io), 111 PT11B (io), 112 PT11A (io), 113 PT10F (io), 114 PT10E (io), 115 PT10D (io), 116 PT10C (io), 119 PT9F (io), 120 PT9E (io), 121 PT9B (io), 122 PT9A (io), 124 PT7D/PCLK1_1 (io), 125 PT7B (io), 126 PT7A (io)
part C pins: 91 PR8B (io), 92 PR8A (io), 94 PR6B (io), 95 PR6A (io), 96 PR5B (io), 97 PR5A (io), 100 PR4C (io), 101 PR4B (io), 102 PR4A (io), 103 PR3D (io), 104 PR3C (io), 105 PR3B (io), 106 PR3A (io), 107 PR2B (io), 108 PR2A (io)
part D pins: 73 PR16B (io), 74 PR16A (io), 75 PR15B (io), 76 PR15A (io), 77 PR14D (io), 78 PR14C (io), 79 PR14B (io), 80 PR14A (io), 81 PR13D (io), 84 PR12B (io), 85 PR12A (io), 86 PR11B (io), 87 PR11A (io), 89 PR10B (io), 90 PR10A (io)
part E pins: 55 PB7B/PCLK4_1 (io), 56 PB7C (io), 57 PB7D (io), 58 PB7F/PCLK4_0 (io), 60 PB9A (io), 61 PB9B (io), 62 PB9E (io), 65 PB10A (io), 66 PB10B (io), 67 PB10C (io), 68 PB10D (io), 69 PB10F (io), 71 PB11C (io), 72 PB11D (io)
part F pins: 40 PB2C (io), 41 PB2D (io), 43 PB3A (io), 44 PB3B (io), 45 PB4A (io), 46 PB4B (io), 48 PB4D (io), 49 PB5A (io), 50 PB5B (io), 54 PB6F (io)
part G pins: 19 PL10A (io), 20 PL10B (io), 22 PL11A (io), 23 PL11B (io), 24 PL11C/TSALL (io), 25 PL12B (io), 28 PL13D (io), 29 PL14A/LLM0_PLLT_FB_A (io), 30 PL14B/LLM0_PLLC_FB_A (io), 31 PL14C (io), 32 PL14D (io), 33 PL15A/LLM0_PLLT_IN_A (io), 34 PL15B/LLM0_PLLC_IN_A (io), 35 PL16A (io), 36 PL16B (io)
part H pins: 1 PL2A (io), 2 PL2B (io), 3 PL3A (io), 4 PL3B (io), 5 PL3C (io), 6 PL3D (io), 7 PL4A (io), 8 PL4B (io), 9 PL4C (io), 12 PL5C (io), 13 PL6A (io), 14 PL6B/GSRN (io), 15 PL6D (io), 17 PL7C (io), 18 PL7D (io)
part I pins: 39 TMS (in) "Powered by VCCIO5", 42 TCK (in) "Powered by VCCIO5", 47 TDO (out) "Powered by VCCIO5", 51 TDI (in) "Powered by VCCIO5", 70 SLEEPN (in) "Powered by VCCIO4"
part J pins: 10 VCCIO7 (power), 21 VCC (power), 26 VCCIO6 (power), 38 VCCIO5 (power), 52 VCC (power), 53 VCCAUX (power), 63 VCCIO4 (power), 82 VCCIO3 (power), 93 VCC (power), 98 VCCIO2 (power), 117 VCCIO1 (power), 128 VCCAUX (power), 129 VCC (power), 135 VCCIO0 (power)
part K pins: 11 GNDIO7 (power), 16 GND (power), 27 GNDIO6 (power), 37 GNDIO5 (power), 59 GND (power), 64 GNDIO4 (power), 83 GNDIO3 (power), 88 GND (power), 99 GNDIO2 (power), 118 GNDIO1 (power), 123 GND (power), 136 GNDIO0 (power)

## LCMXO1200C-3T144CES
designator U?
MachXO 1200 Crossover PLD, 1.8V/2.5V/3.3V, 113 User I/Os, 144-Pins TQFP, Speed Grade-3, Commercial Grade, Engineering Sample
footprint TQFP144_N (Thin QFP, 144-Leads, Body 20x20mm, Pitch 0.5mm, IPC Medium Density)
footprint TQFP144_L (Thin QFP, 144-Leads, Body 20x20mm, Pitch 0.5mm, IPC High Density)
footprint TQFP144_M (Thin QFP, 144-Leads, Body 20x20mm, Pitch 0.5mm, IPC Low Density)
3D model MachXO1200-TQFP144 (144-Pin Thin Quad Flat Pack (TQFP144))
signal-integrity model LCMXO1200C_T144 (MachXO)
part A pins: 127 PT6F/PCLK1_0 (io), 130 PT5D (io), 131 PT5C (io), 132 PT5B (io), 133 PT5A (io), 134 PT4B (io), 137 PT3D (io), 138 PT3C (io), 139 PT3B (io), 140 PT3A (io), 141 PT2D (io), 142 PT2C (io), 143 PT2B (io), 144 PT2A (io)
part B pins: 109 PT11D (io), 110 PT11C (io), 111 PT11B (io), 112 PT11A (io), 113 PT10F (io), 114 PT10E (io), 115 PT10D (io), 116 PT10C (io), 119 PT9F (io), 120 PT9E (io), 121 PT9B (io), 122 PT9A (io), 124 PT7D/PCLK1_1 (io), 125 PT7B (io), 126 PT7A (io)
part C pins: 91 PR8B (io), 92 PR8A (io), 94 PR6B (io), 95 PR6A (io), 96 PR5B (io), 97 PR5A (io), 100 PR4C (io), 101 PR4B (io), 102 PR4A (io), 103 PR3D (io), 104 PR3C (io), 105 PR3B (io), 106 PR3A (io), 107 PR2B (io), 108 PR2A (io)
part D pins: 73 PR16B (io), 74 PR16A (io), 75 PR15B (io), 76 PR15A (io), 77 PR14D (io), 78 PR14C (io), 79 PR14B (io), 80 PR14A (io), 81 PR13D (io), 84 PR12B (io), 85 PR12A (io), 86 PR11B (io), 87 PR11A (io), 89 PR10B (io), 90 PR10A (io)
part E pins: 55 PB7B/PCLK4_1 (io), 56 PB7C (io), 57 PB7D (io), 58 PB7F/PCLK4_0 (io), 60 PB9A (io), 61 PB9B (io), 62 PB9E (io), 65 PB10A (io), 66 PB10B (io), 67 PB10C (io), 68 PB10D (io), 69 PB10F (io), 71 PB11C (io), 72 PB11D (io)
part F pins: 40 PB2C (io), 41 PB2D (io), 43 PB3A (io), 44 PB3B (io), 45 PB4A (io), 46 PB4B (io), 48 PB4D (io), 49 PB5A (io), 50 PB5B (io), 54 PB6F (io)
part G pins: 19 PL10A (io), 20 PL10B (io), 22 PL11A (io), 23 PL11B (io), 24 PL11C/TSALL (io), 25 PL12B (io), 28 PL13D (io), 29 PL14A/LLM0_PLLT_FB_A (io), 30 PL14B/LLM0_PLLC_FB_A (io), 31 PL14C (io), 32 PL14D (io), 33 PL15A/LLM0_PLLT_IN_A (io), 34 PL15B/LLM0_PLLC_IN_A (io), 35 PL16A (io), 36 PL16B (io)
part H pins: 1 PL2A (io), 2 PL2B (io), 3 PL3A (io), 4 PL3B (io), 5 PL3C (io), 6 PL3D (io), 7 PL4A (io), 8 PL4B (io), 9 PL4C (io), 12 PL5C (io), 13 PL6A (io), 14 PL6B/GSRN (io), 15 PL6D (io), 17 PL7C (io), 18 PL7D (io)
part I pins: 39 TMS (in) "Powered by VCCIO5", 42 TCK (in) "Powered by VCCIO5", 47 TDO (out) "Powered by VCCIO5", 51 TDI (in) "Powered by VCCIO5", 70 SLEEPN (in) "Powered by VCCIO4"
part J pins: 10 VCCIO7 (power), 21 VCC (power), 26 VCCIO6 (power), 38 VCCIO5 (power), 52 VCC (power), 53 VCCAUX (power), 63 VCCIO4 (power), 82 VCCIO3 (power), 93 VCC (power), 98 VCCIO2 (power), 117 VCCIO1 (power), 128 VCCAUX (power), 129 VCC (power), 135 VCCIO0 (power)
part K pins: 11 GNDIO7 (power), 16 GND (power), 27 GNDIO6 (power), 37 GNDIO5 (power), 59 GND (power), 64 GNDIO4 (power), 83 GNDIO3 (power), 88 GND (power), 99 GNDIO2 (power), 118 GNDIO1 (power), 123 GND (power), 136 GNDIO0 (power)


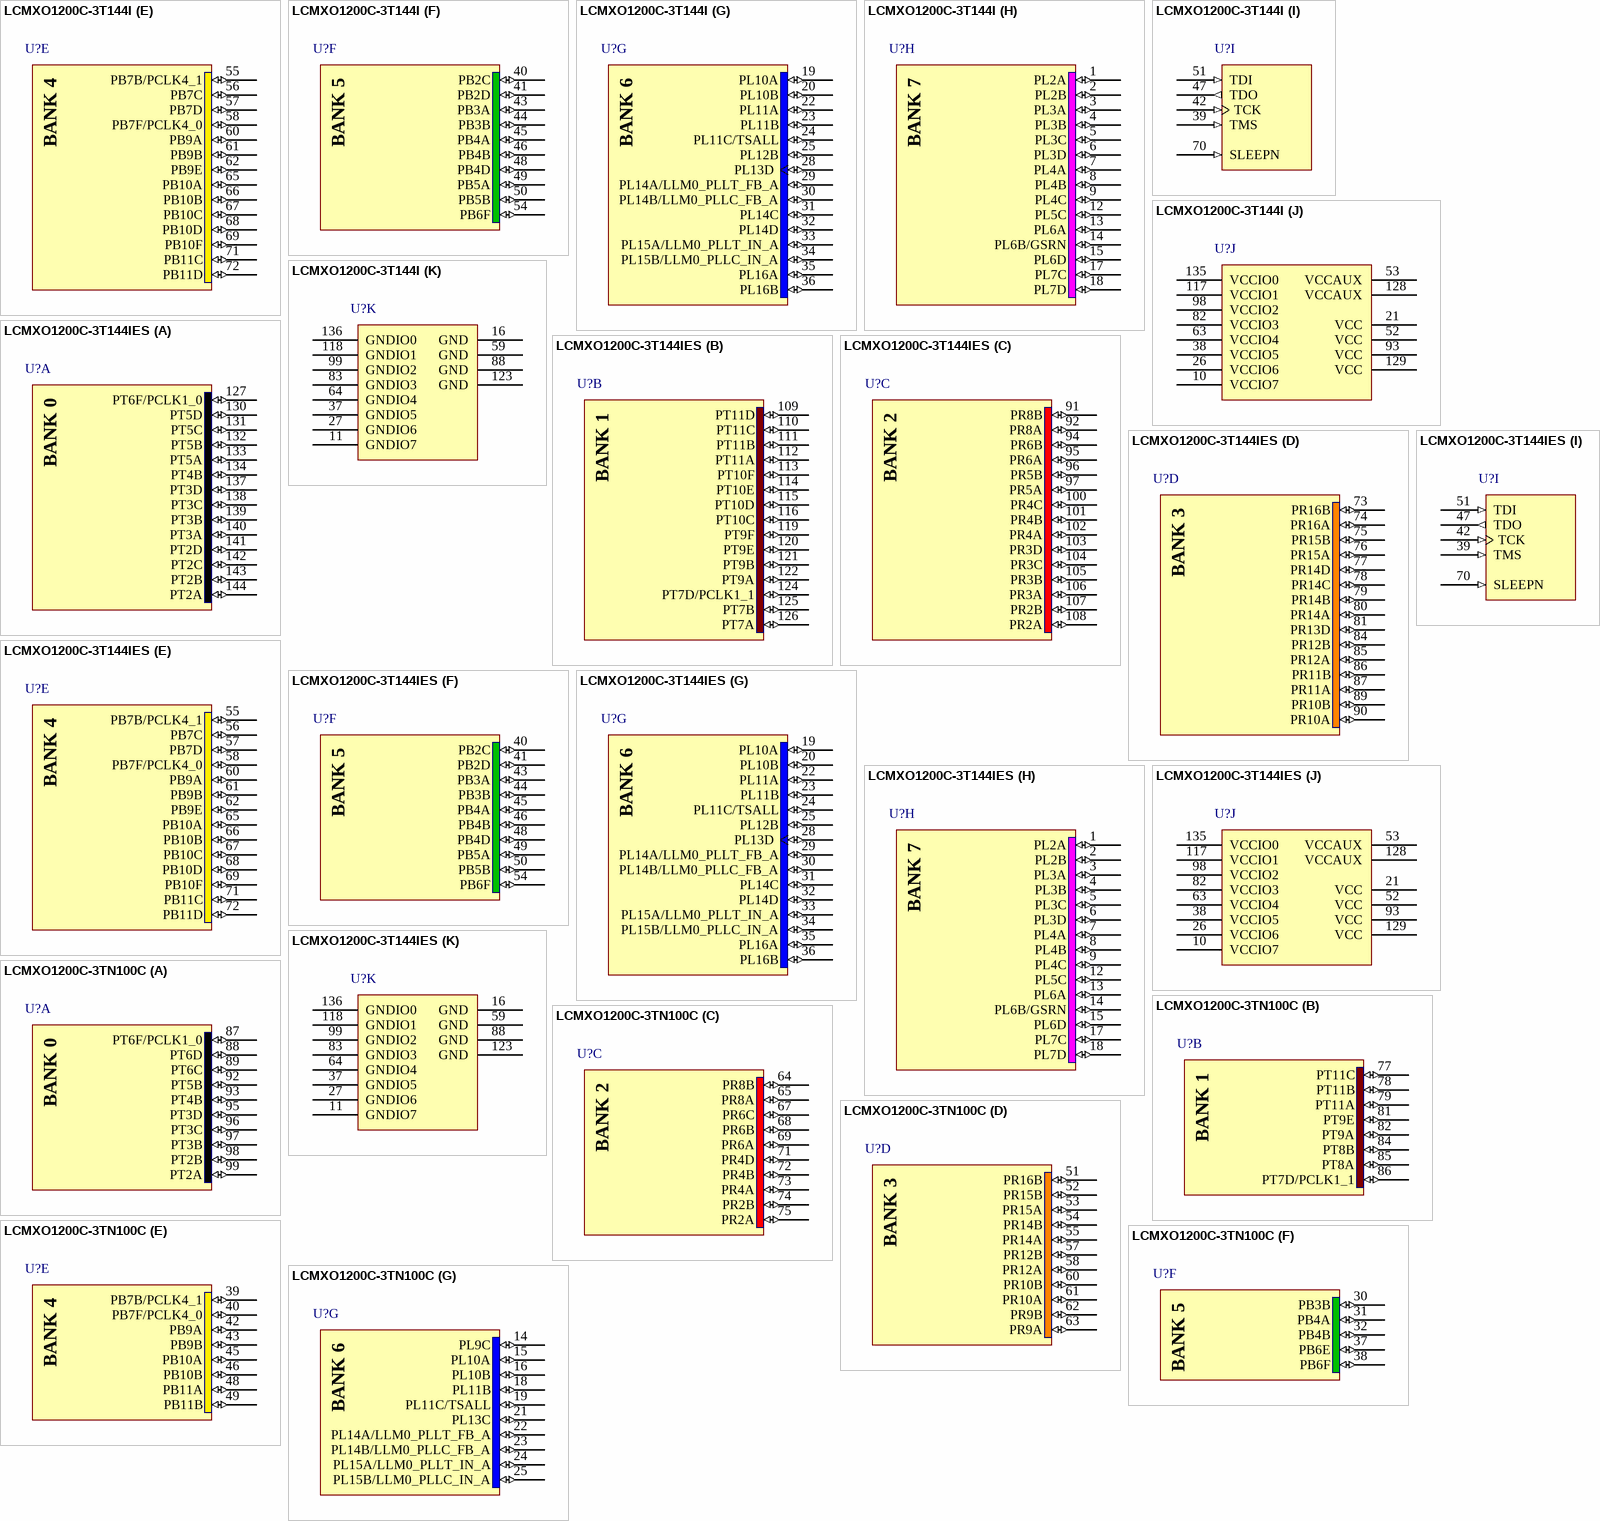
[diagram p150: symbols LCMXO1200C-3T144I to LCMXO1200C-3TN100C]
## LCMXO1200C-3T144I
designator U?
MachXO 1200 Crossover PLD, 1.8V/2.5V/3.3V, 113 User I/Os, 144-Pins TQFP, Speed Grade-3, Industrial Grade
footprint TQFP144_N (Thin QFP, 144-Leads, Body 20x20mm, Pitch 0.5mm, IPC Medium Density)
footprint TQFP144_L (Thin QFP, 144-Leads, Body 20x20mm, Pitch 0.5mm, IPC High Density)
footprint TQFP144_M (Thin QFP, 144-Leads, Body 20x20mm, Pitch 0.5mm, IPC Low Density)
3D model MachXO1200-TQFP144 (144-Pin Thin Quad Flat Pack (TQFP144))
signal-integrity model LCMXO1200C_T144 (MachXO)
part A pins: 127 PT6F/PCLK1_0 (io), 130 PT5D (io), 131 PT5C (io), 132 PT5B (io), 133 PT5A (io), 134 PT4B (io), 137 PT3D (io), 138 PT3C (io), 139 PT3B (io), 140 PT3A (io), 141 PT2D (io), 142 PT2C (io), 143 PT2B (io), 144 PT2A (io)
part B pins: 109 PT11D (io), 110 PT11C (io), 111 PT11B (io), 112 PT11A (io), 113 PT10F (io), 114 PT10E (io), 115 PT10D (io), 116 PT10C (io), 119 PT9F (io), 120 PT9E (io), 121 PT9B (io), 122 PT9A (io), 124 PT7D/PCLK1_1 (io), 125 PT7B (io), 126 PT7A (io)
part C pins: 91 PR8B (io), 92 PR8A (io), 94 PR6B (io), 95 PR6A (io), 96 PR5B (io), 97 PR5A (io), 100 PR4C (io), 101 PR4B (io), 102 PR4A (io), 103 PR3D (io), 104 PR3C (io), 105 PR3B (io), 106 PR3A (io), 107 PR2B (io), 108 PR2A (io)
part D pins: 73 PR16B (io), 74 PR16A (io), 75 PR15B (io), 76 PR15A (io), 77 PR14D (io), 78 PR14C (io), 79 PR14B (io), 80 PR14A (io), 81 PR13D (io), 84 PR12B (io), 85 PR12A (io), 86 PR11B (io), 87 PR11A (io), 89 PR10B (io), 90 PR10A (io)
part E pins: 55 PB7B/PCLK4_1 (io), 56 PB7C (io), 57 PB7D (io), 58 PB7F/PCLK4_0 (io), 60 PB9A (io), 61 PB9B (io), 62 PB9E (io), 65 PB10A (io), 66 PB10B (io), 67 PB10C (io), 68 PB10D (io), 69 PB10F (io), 71 PB11C (io), 72 PB11D (io)
part F pins: 40 PB2C (io), 41 PB2D (io), 43 PB3A (io), 44 PB3B (io), 45 PB4A (io), 46 PB4B (io), 48 PB4D (io), 49 PB5A (io), 50 PB5B (io), 54 PB6F (io)
part G pins: 19 PL10A (io), 20 PL10B (io), 22 PL11A (io), 23 PL11B (io), 24 PL11C/TSALL (io), 25 PL12B (io), 28 PL13D (io), 29 PL14A/LLM0_PLLT_FB_A (io), 30 PL14B/LLM0_PLLC_FB_A (io), 31 PL14C (io), 32 PL14D (io), 33 PL15A/LLM0_PLLT_IN_A (io), 34 PL15B/LLM0_PLLC_IN_A (io), 35 PL16A (io), 36 PL16B (io)
part H pins: 1 PL2A (io), 2 PL2B (io), 3 PL3A (io), 4 PL3B (io), 5 PL3C (io), 6 PL3D (io), 7 PL4A (io), 8 PL4B (io), 9 PL4C (io), 12 PL5C (io), 13 PL6A (io), 14 PL6B/GSRN (io), 15 PL6D (io), 17 PL7C (io), 18 PL7D (io)
part I pins: 39 TMS (in) "Powered by VCCIO5", 42 TCK (in) "Powered by VCCIO5", 47 TDO (out) "Powered by VCCIO5", 51 TDI (in) "Powered by VCCIO5", 70 SLEEPN (in) "Powered by VCCIO4"
part J pins: 10 VCCIO7 (power), 21 VCC (power), 26 VCCIO6 (power), 38 VCCIO5 (power), 52 VCC (power), 53 VCCAUX (power), 63 VCCIO4 (power), 82 VCCIO3 (power), 93 VCC (power), 98 VCCIO2 (power), 117 VCCIO1 (power), 128 VCCAUX (power), 129 VCC (power), 135 VCCIO0 (power)
part K pins: 11 GNDIO7 (power), 16 GND (power), 27 GNDIO6 (power), 37 GNDIO5 (power), 59 GND (power), 64 GNDIO4 (power), 83 GNDIO3 (power), 88 GND (power), 99 GNDIO2 (power), 118 GNDIO1 (power), 123 GND (power), 136 GNDIO0 (power)

## LCMXO1200C-3T144IES
designator U?
MachXO 1200 Crossover PLD, 1.8V/2.5V/3.3V, 113 User I/Os, 144-Pins TQFP, Speed Grade-3, Industrial Grade, Engineering Sample
footprint TQFP144_N (Thin QFP, 144-Leads, Body 20x20mm, Pitch 0.5mm, IPC Medium Density)
footprint TQFP144_L (Thin QFP, 144-Leads, Body 20x20mm, Pitch 0.5mm, IPC High Density)
footprint TQFP144_M (Thin QFP, 144-Leads, Body 20x20mm, Pitch 0.5mm, IPC Low Density)
3D model MachXO1200-TQFP144 (144-Pin Thin Quad Flat Pack (TQFP144))
signal-integrity model LCMXO1200C_T144 (MachXO)
part A pins: 127 PT6F/PCLK1_0 (io), 130 PT5D (io), 131 PT5C (io), 132 PT5B (io), 133 PT5A (io), 134 PT4B (io), 137 PT3D (io), 138 PT3C (io), 139 PT3B (io), 140 PT3A (io), 141 PT2D (io), 142 PT2C (io), 143 PT2B (io), 144 PT2A (io)
part B pins: 109 PT11D (io), 110 PT11C (io), 111 PT11B (io), 112 PT11A (io), 113 PT10F (io), 114 PT10E (io), 115 PT10D (io), 116 PT10C (io), 119 PT9F (io), 120 PT9E (io), 121 PT9B (io), 122 PT9A (io), 124 PT7D/PCLK1_1 (io), 125 PT7B (io), 126 PT7A (io)
part C pins: 91 PR8B (io), 92 PR8A (io), 94 PR6B (io), 95 PR6A (io), 96 PR5B (io), 97 PR5A (io), 100 PR4C (io), 101 PR4B (io), 102 PR4A (io), 103 PR3D (io), 104 PR3C (io), 105 PR3B (io), 106 PR3A (io), 107 PR2B (io), 108 PR2A (io)
part D pins: 73 PR16B (io), 74 PR16A (io), 75 PR15B (io), 76 PR15A (io), 77 PR14D (io), 78 PR14C (io), 79 PR14B (io), 80 PR14A (io), 81 PR13D (io), 84 PR12B (io), 85 PR12A (io), 86 PR11B (io), 87 PR11A (io), 89 PR10B (io), 90 PR10A (io)
part E pins: 55 PB7B/PCLK4_1 (io), 56 PB7C (io), 57 PB7D (io), 58 PB7F/PCLK4_0 (io), 60 PB9A (io), 61 PB9B (io), 62 PB9E (io), 65 PB10A (io), 66 PB10B (io), 67 PB10C (io), 68 PB10D (io), 69 PB10F (io), 71 PB11C (io), 72 PB11D (io)
part F pins: 40 PB2C (io), 41 PB2D (io), 43 PB3A (io), 44 PB3B (io), 45 PB4A (io), 46 PB4B (io), 48 PB4D (io), 49 PB5A (io), 50 PB5B (io), 54 PB6F (io)
part G pins: 19 PL10A (io), 20 PL10B (io), 22 PL11A (io), 23 PL11B (io), 24 PL11C/TSALL (io), 25 PL12B (io), 28 PL13D (io), 29 PL14A/LLM0_PLLT_FB_A (io), 30 PL14B/LLM0_PLLC_FB_A (io), 31 PL14C (io), 32 PL14D (io), 33 PL15A/LLM0_PLLT_IN_A (io), 34 PL15B/LLM0_PLLC_IN_A (io), 35 PL16A (io), 36 PL16B (io)
part H pins: 1 PL2A (io), 2 PL2B (io), 3 PL3A (io), 4 PL3B (io), 5 PL3C (io), 6 PL3D (io), 7 PL4A (io), 8 PL4B (io), 9 PL4C (io), 12 PL5C (io), 13 PL6A (io), 14 PL6B/GSRN (io), 15 PL6D (io), 17 PL7C (io), 18 PL7D (io)
part I pins: 39 TMS (in) "Powered by VCCIO5", 42 TCK (in) "Powered by VCCIO5", 47 TDO (out) "Powered by VCCIO5", 51 TDI (in) "Powered by VCCIO5", 70 SLEEPN (in) "Powered by VCCIO4"
part J pins: 10 VCCIO7 (power), 21 VCC (power), 26 VCCIO6 (power), 38 VCCIO5 (power), 52 VCC (power), 53 VCCAUX (power), 63 VCCIO4 (power), 82 VCCIO3 (power), 93 VCC (power), 98 VCCIO2 (power), 117 VCCIO1 (power), 128 VCCAUX (power), 129 VCC (power), 135 VCCIO0 (power)
part K pins: 11 GNDIO7 (power), 16 GND (power), 27 GNDIO6 (power), 37 GNDIO5 (power), 59 GND (power), 64 GNDIO4 (power), 83 GNDIO3 (power), 88 GND (power), 99 GNDIO2 (power), 118 GNDIO1 (power), 123 GND (power), 136 GNDIO0 (power)


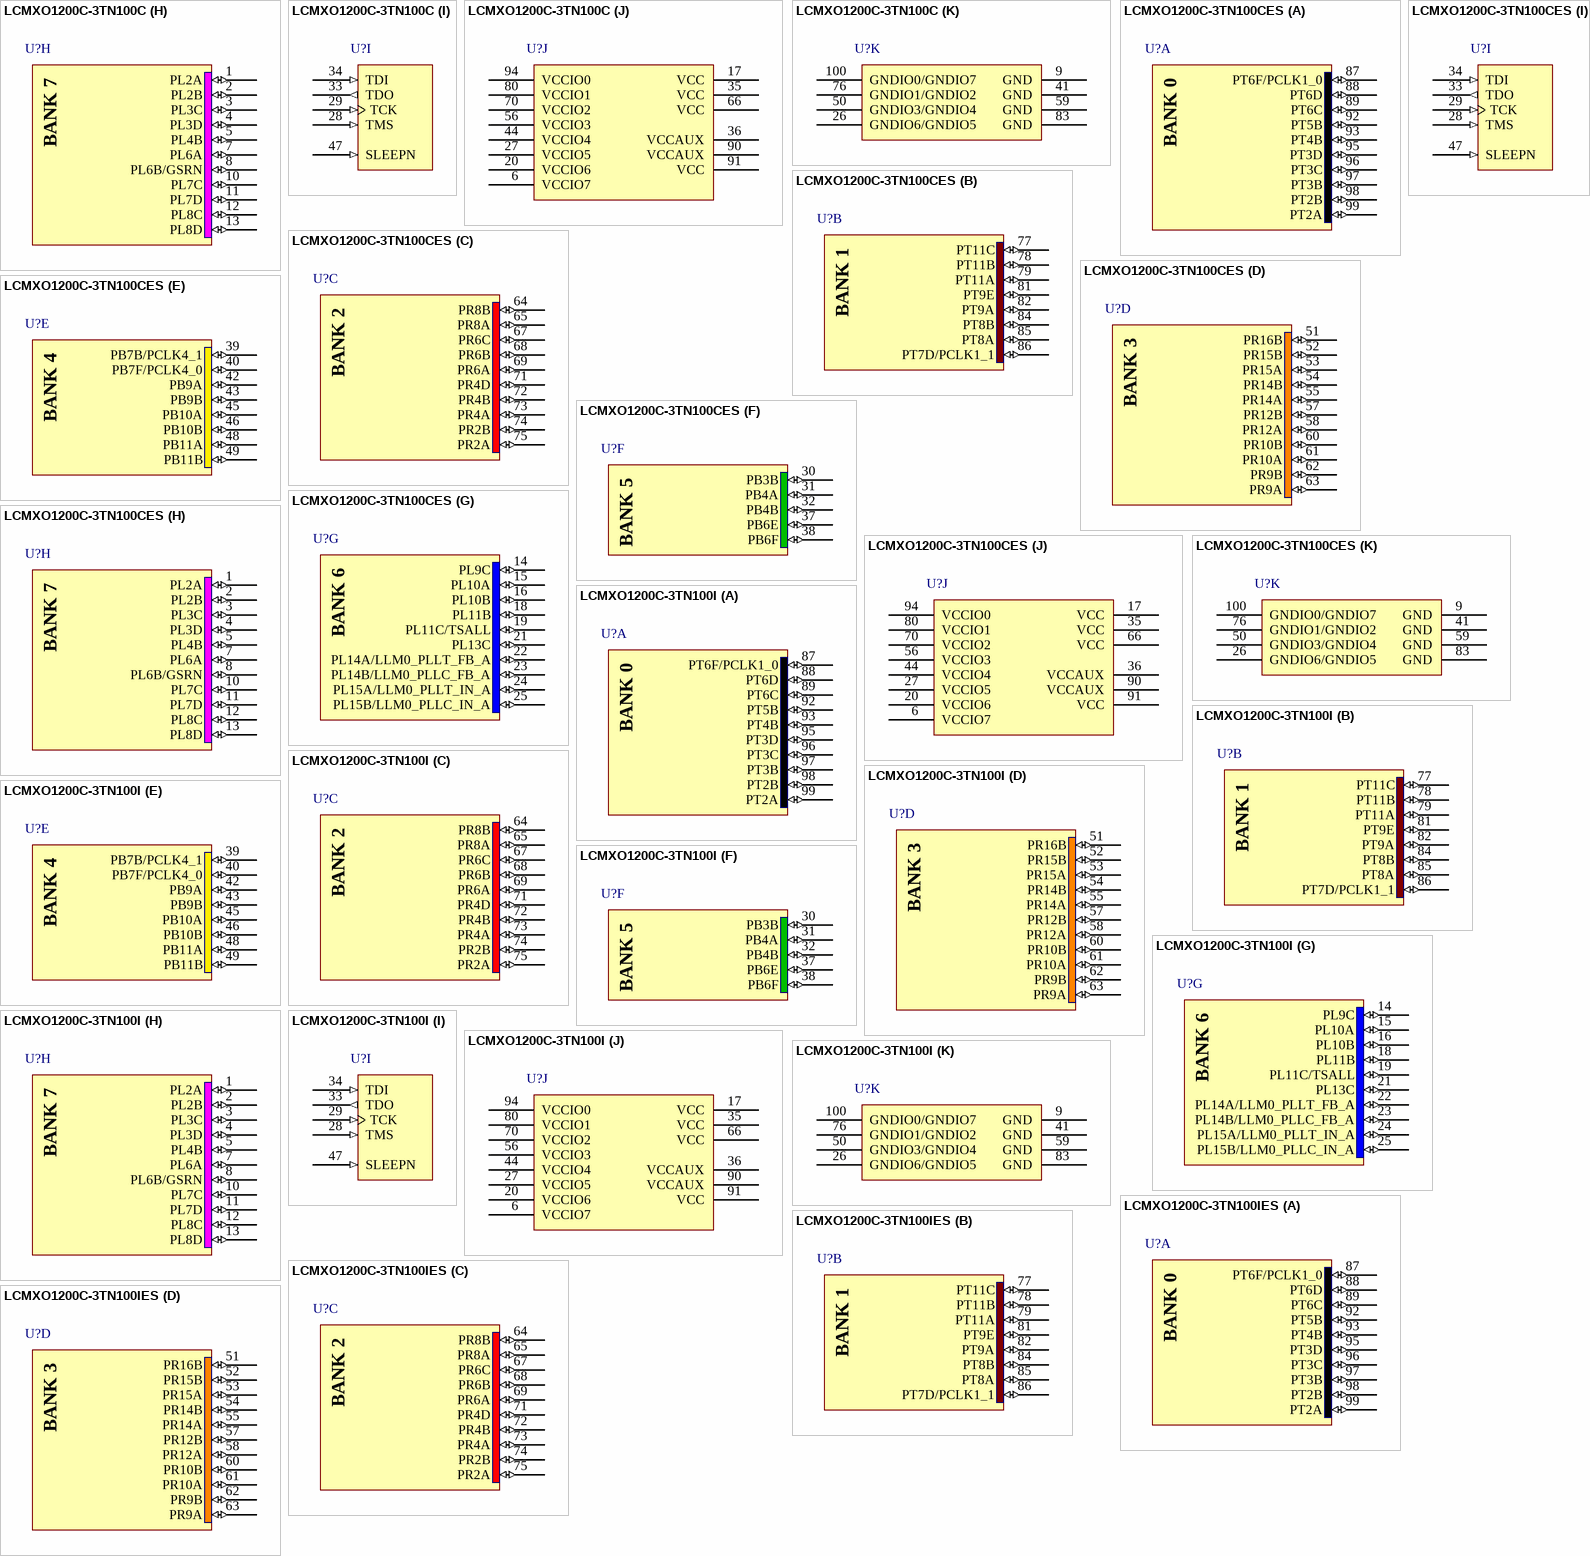
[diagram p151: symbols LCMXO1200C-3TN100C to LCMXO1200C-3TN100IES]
## LCMXO1200C-3TN100C
designator U?
MachXO 1200 Crossover PLD, 1.8V/2.5V/3.3V, 73 User I/Os, 100-Pins TQFP, Speed Grade-3, Commercial Grade, Pb-Free
footprint TQFP100_N (Thin QFP, 100-Leads, Body 14x14mm, Pitch 0.5mm, IPC Medium Density)
footprint TQFP100_L (Thin QFP, 100-Leads, Body 14x14mm, Pitch 0.5mm, IPC High Density)
footprint TQFP100_M (Thin QFP, 100-Leads, Body 14x14mm, Pitch 0.5mm, IPC Low Density)
3D model MachXO1200-TQFP100 (100-Pin Thin Quad Flat Pack (TQFP100))
signal-integrity model LCMXO1200C_T100 (MachXO)
part A pins: 87 PT6F/PCLK1_0 (io), 88 PT6D (io), 89 PT6C (io), 92 PT5B (io), 93 PT4B (io), 95 PT3D (io), 96 PT3C (io), 97 PT3B (io), 98 PT2B (io), 99 PT2A (io)
part B pins: 77 PT11C (io), 78 PT11B (io), 79 PT11A (io), 81 PT9E (io), 82 PT9A (io), 84 PT8B (io), 85 PT8A (io), 86 PT7D/PCLK1_1 (io)
part C pins: 64 PR8B (io), 65 PR8A (io), 67 PR6C (io), 68 PR6B (io), 69 PR6A (io), 71 PR4D (io), 72 PR4B (io), 73 PR4A (io), 74 PR2B (io), 75 PR2A (io)
part D pins: 51 PR16B (io), 52 PR15B (io), 53 PR15A (io), 54 PR14B (io), 55 PR14A (io), 57 PR12B (io), 58 PR12A (io), 60 PR10B (io), 61 PR10A (io), 62 PR9B (io), 63 PR9A (io)
part E pins: 39 PB7B/PCLK4_1 (io), 40 PB7F/PCLK4_0 (io), 42 PB9A (io), 43 PB9B (io), 45 PB10A (io), 46 PB10B (io), 48 PB11A (io), 49 PB11B (io)
part F pins: 30 PB3B (io), 31 PB4A (io), 32 PB4B (io), 37 PB6E (io), 38 PB6F (io)
part G pins: 14 PL9C (io), 15 PL10A (io), 16 PL10B (io), 18 PL11B (io), 19 PL11C/TSALL (io), 21 PL13C (io), 22 PL14A/LLM0_PLLT_FB_A (io), 23 PL14B/LLM0_PLLC_FB_A (io), 24 PL15A/LLM0_PLLT_IN_A (io), 25 PL15B/LLM0_PLLC_IN_A (io)
part H pins: 1 PL2A (io), 2 PL2B (io), 3 PL3C (io), 4 PL3D (io), 5 PL4B (io), 7 PL6A (io), 8 PL6B/GSRN (io), 10 PL7C (io), 11 PL7D (io), 12 PL8C (io), 13 PL8D (io)
part I pins: 28 TMS (in) "Powered by VCCIO5", 29 TCK (in) "Powered by VCCIO5", 33 TDO (out) "Powered by VCCIO5", 34 TDI (in) "Powered by VCCIO5", 47 SLEEPN (in) "Powered by VCCIO5"
part J pins: 6 VCCIO7 (power), 17 VCC (power), 20 VCCIO6 (power), 27 VCCIO5 (power), 35 VCC (power), 36 VCCAUX (power), 44 VCCIO4 (power), 56 VCCIO3 (power), 66 VCC (power), 70 VCCIO2 (power), 80 VCCIO1 (power), 90 VCCAUX (power), 91 VCC (power), 94 VCCIO0 (power)
part K pins: 9 GND (power), 26 GNDIO6/GNDIO5 (power) "Double Bonded pin", 41 GND (power), 50 GNDIO3/GNDIO4 (power) "Double Bonded pin", 59 GND (power), 76 GNDIO1/GNDIO2 (power) "Double Bonded pin", 83 GND (power), 100 GNDIO0/GNDIO7 (power) "Double Bonded pin"

## LCMXO1200C-3TN100CES
designator U?
MachXO 1200 Crossover PLD, 1.8V/2.5V/3.3V, 73 User I/Os, 100-Pins TQFP, Speed Grade-3, Commercial Grade, Pb-Free, Engineering Sample
footprint TQFP100_N (Thin QFP, 100-Leads, Body 14x14mm, Pitch 0.5mm, IPC Medium Density)
footprint TQFP100_L (Thin QFP, 100-Leads, Body 14x14mm, Pitch 0.5mm, IPC High Density)
footprint TQFP100_M (Thin QFP, 100-Leads, Body 14x14mm, Pitch 0.5mm, IPC Low Density)
3D model MachXO1200-TQFP100 (100-Pin Thin Quad Flat Pack (TQFP100))
signal-integrity model LCMXO1200C_T100 (MachXO)
part A pins: 87 PT6F/PCLK1_0 (io), 88 PT6D (io), 89 PT6C (io), 92 PT5B (io), 93 PT4B (io), 95 PT3D (io), 96 PT3C (io), 97 PT3B (io), 98 PT2B (io), 99 PT2A (io)
part B pins: 77 PT11C (io), 78 PT11B (io), 79 PT11A (io), 81 PT9E (io), 82 PT9A (io), 84 PT8B (io), 85 PT8A (io), 86 PT7D/PCLK1_1 (io)
part C pins: 64 PR8B (io), 65 PR8A (io), 67 PR6C (io), 68 PR6B (io), 69 PR6A (io), 71 PR4D (io), 72 PR4B (io), 73 PR4A (io), 74 PR2B (io), 75 PR2A (io)
part D pins: 51 PR16B (io), 52 PR15B (io), 53 PR15A (io), 54 PR14B (io), 55 PR14A (io), 57 PR12B (io), 58 PR12A (io), 60 PR10B (io), 61 PR10A (io), 62 PR9B (io), 63 PR9A (io)
part E pins: 39 PB7B/PCLK4_1 (io), 40 PB7F/PCLK4_0 (io), 42 PB9A (io), 43 PB9B (io), 45 PB10A (io), 46 PB10B (io), 48 PB11A (io), 49 PB11B (io)
part F pins: 30 PB3B (io), 31 PB4A (io), 32 PB4B (io), 37 PB6E (io), 38 PB6F (io)
part G pins: 14 PL9C (io), 15 PL10A (io), 16 PL10B (io), 18 PL11B (io), 19 PL11C/TSALL (io), 21 PL13C (io), 22 PL14A/LLM0_PLLT_FB_A (io), 23 PL14B/LLM0_PLLC_FB_A (io), 24 PL15A/LLM0_PLLT_IN_A (io), 25 PL15B/LLM0_PLLC_IN_A (io)
part H pins: 1 PL2A (io), 2 PL2B (io), 3 PL3C (io), 4 PL3D (io), 5 PL4B (io), 7 PL6A (io), 8 PL6B/GSRN (io), 10 PL7C (io), 11 PL7D (io), 12 PL8C (io), 13 PL8D (io)
part I pins: 28 TMS (in) "Powered by VCCIO5", 29 TCK (in) "Powered by VCCIO5", 33 TDO (out) "Powered by VCCIO5", 34 TDI (in) "Powered by VCCIO5", 47 SLEEPN (in) "Powered by VCCIO5"
part J pins: 6 VCCIO7 (power), 17 VCC (power), 20 VCCIO6 (power), 27 VCCIO5 (power), 35 VCC (power), 36 VCCAUX (power), 44 VCCIO4 (power), 56 VCCIO3 (power), 66 VCC (power), 70 VCCIO2 (power), 80 VCCIO1 (power), 90 VCCAUX (power), 91 VCC (power), 94 VCCIO0 (power)
part K pins: 9 GND (power), 26 GNDIO6/GNDIO5 (power) "Double Bonded pin", 41 GND (power), 50 GNDIO3/GNDIO4 (power) "Double Bonded pin", 59 GND (power), 76 GNDIO1/GNDIO2 (power) "Double Bonded pin", 83 GND (power), 100 GNDIO0/GNDIO7 (power) "Double Bonded pin"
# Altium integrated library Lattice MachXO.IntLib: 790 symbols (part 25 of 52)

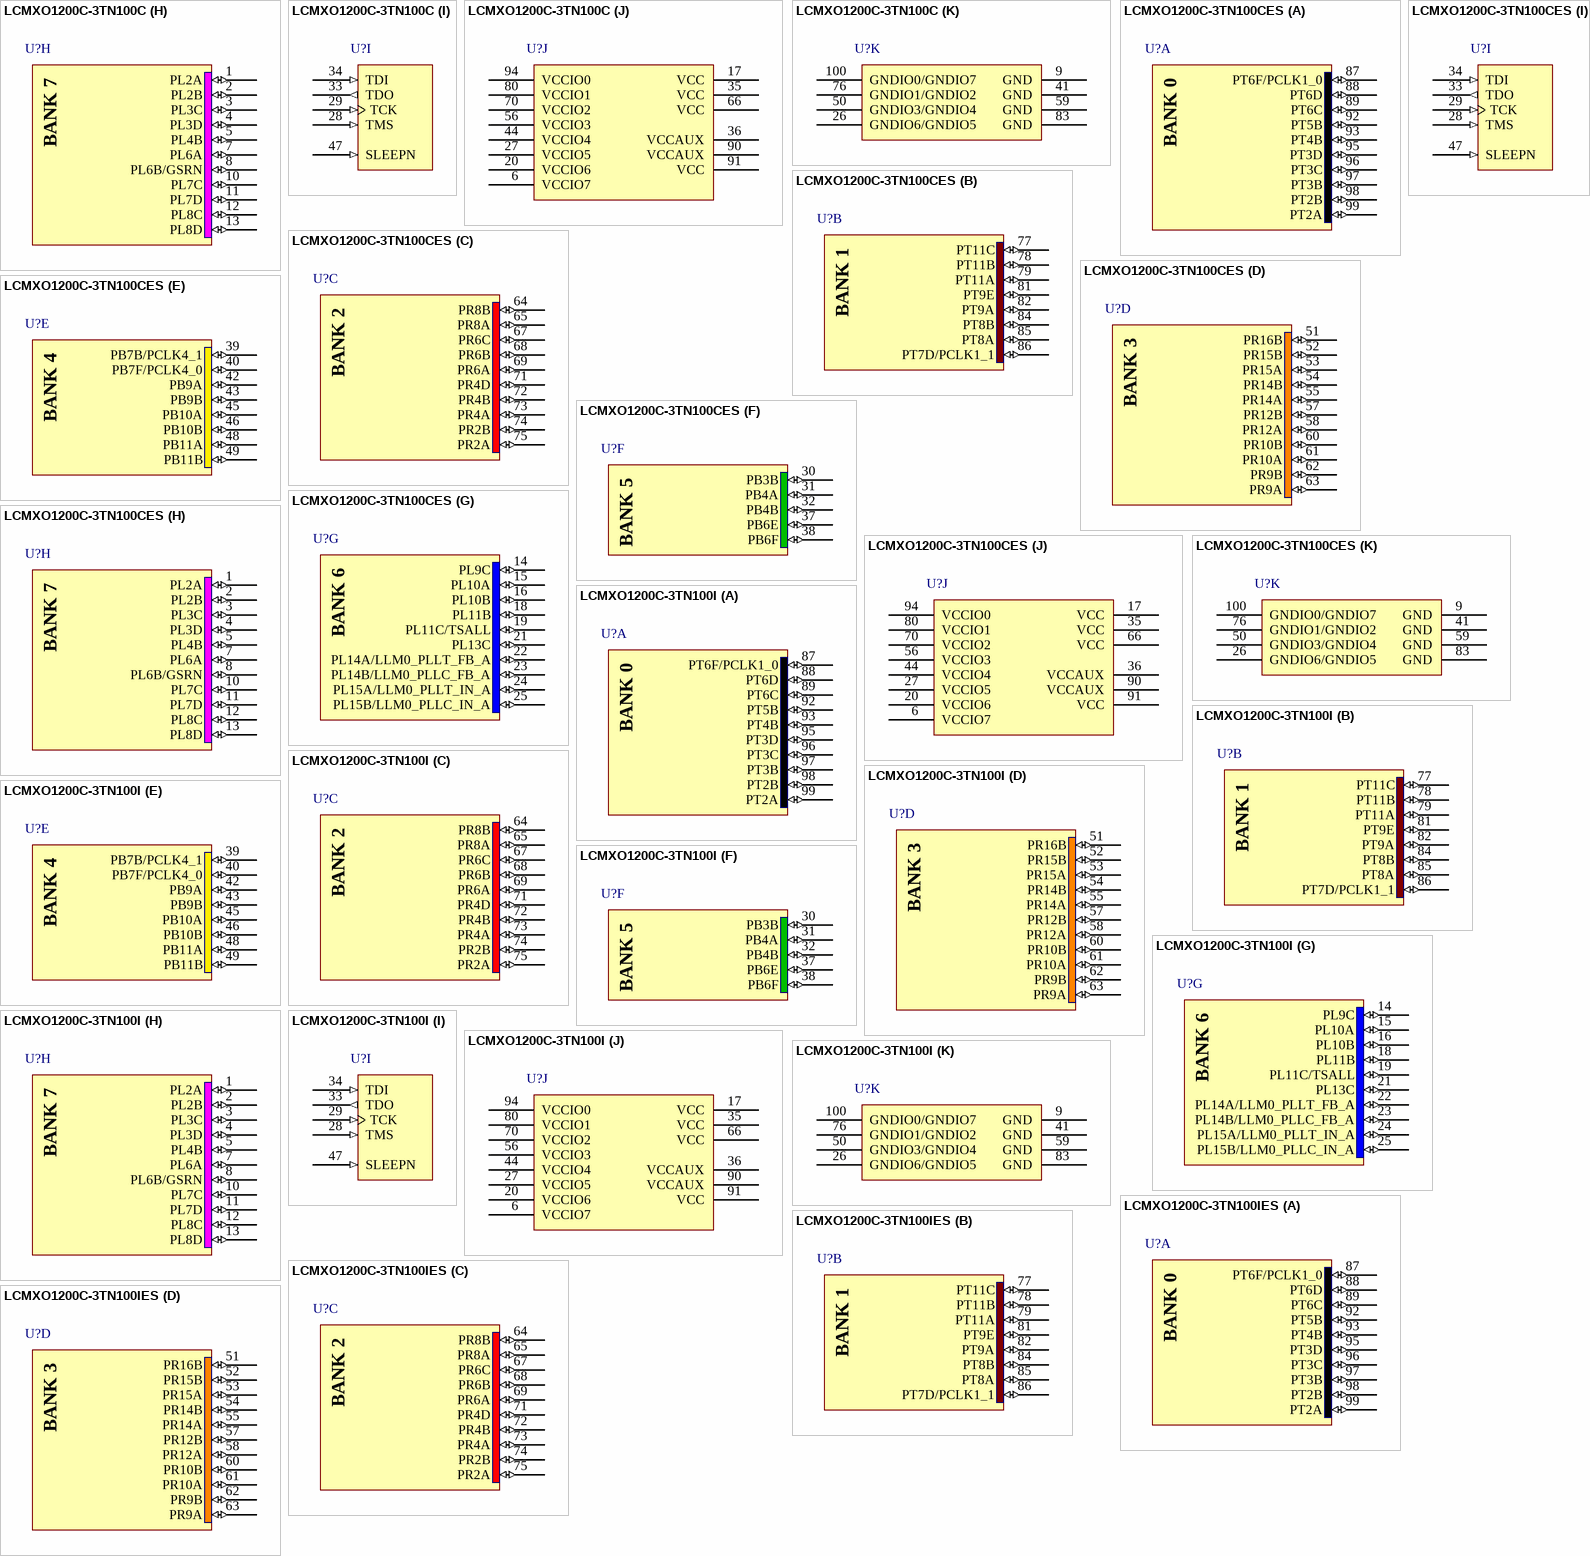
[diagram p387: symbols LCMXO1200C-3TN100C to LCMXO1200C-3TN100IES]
## LCMXO1200C-3TN100I
designator U?
MachXO 1200 Crossover PLD, 1.8V/2.5V/3.3V, 73 User I/Os, 100-Pins TQFP, Speed Grade-3, Industrial Grade, Pb-Free
footprint TQFP100_N (Thin QFP, 100-Leads, Body 14x14mm, Pitch 0.5mm, IPC Medium Density)
footprint TQFP100_L (Thin QFP, 100-Leads, Body 14x14mm, Pitch 0.5mm, IPC High Density)
footprint TQFP100_M (Thin QFP, 100-Leads, Body 14x14mm, Pitch 0.5mm, IPC Low Density)
3D model MachXO1200-TQFP100 (100-Pin Thin Quad Flat Pack (TQFP100))
signal-integrity model LCMXO1200C_T100 (MachXO)
part A pins: 87 PT6F/PCLK1_0 (io), 88 PT6D (io), 89 PT6C (io), 92 PT5B (io), 93 PT4B (io), 95 PT3D (io), 96 PT3C (io), 97 PT3B (io), 98 PT2B (io), 99 PT2A (io)
part B pins: 77 PT11C (io), 78 PT11B (io), 79 PT11A (io), 81 PT9E (io), 82 PT9A (io), 84 PT8B (io), 85 PT8A (io), 86 PT7D/PCLK1_1 (io)
part C pins: 64 PR8B (io), 65 PR8A (io), 67 PR6C (io), 68 PR6B (io), 69 PR6A (io), 71 PR4D (io), 72 PR4B (io), 73 PR4A (io), 74 PR2B (io), 75 PR2A (io)
part D pins: 51 PR16B (io), 52 PR15B (io), 53 PR15A (io), 54 PR14B (io), 55 PR14A (io), 57 PR12B (io), 58 PR12A (io), 60 PR10B (io), 61 PR10A (io), 62 PR9B (io), 63 PR9A (io)
part E pins: 39 PB7B/PCLK4_1 (io), 40 PB7F/PCLK4_0 (io), 42 PB9A (io), 43 PB9B (io), 45 PB10A (io), 46 PB10B (io), 48 PB11A (io), 49 PB11B (io)
part F pins: 30 PB3B (io), 31 PB4A (io), 32 PB4B (io), 37 PB6E (io), 38 PB6F (io)
part G pins: 14 PL9C (io), 15 PL10A (io), 16 PL10B (io), 18 PL11B (io), 19 PL11C/TSALL (io), 21 PL13C (io), 22 PL14A/LLM0_PLLT_FB_A (io), 23 PL14B/LLM0_PLLC_FB_A (io), 24 PL15A/LLM0_PLLT_IN_A (io), 25 PL15B/LLM0_PLLC_IN_A (io)
part H pins: 1 PL2A (io), 2 PL2B (io), 3 PL3C (io), 4 PL3D (io), 5 PL4B (io), 7 PL6A (io), 8 PL6B/GSRN (io), 10 PL7C (io), 11 PL7D (io), 12 PL8C (io), 13 PL8D (io)
part I pins: 28 TMS (in) "Powered by VCCIO5", 29 TCK (in) "Powered by VCCIO5", 33 TDO (out) "Powered by VCCIO5", 34 TDI (in) "Powered by VCCIO5", 47 SLEEPN (in) "Powered by VCCIO5"
part J pins: 6 VCCIO7 (power), 17 VCC (power), 20 VCCIO6 (power), 27 VCCIO5 (power), 35 VCC (power), 36 VCCAUX (power), 44 VCCIO4 (power), 56 VCCIO3 (power), 66 VCC (power), 70 VCCIO2 (power), 80 VCCIO1 (power), 90 VCCAUX (power), 91 VCC (power), 94 VCCIO0 (power)
part K pins: 9 GND (power), 26 GNDIO6/GNDIO5 (power) "Double Bonded pin", 41 GND (power), 50 GNDIO3/GNDIO4 (power) "Double Bonded pin", 59 GND (power), 76 GNDIO1/GNDIO2 (power) "Double Bonded pin", 83 GND (power), 100 GNDIO0/GNDIO7 (power) "Double Bonded pin"


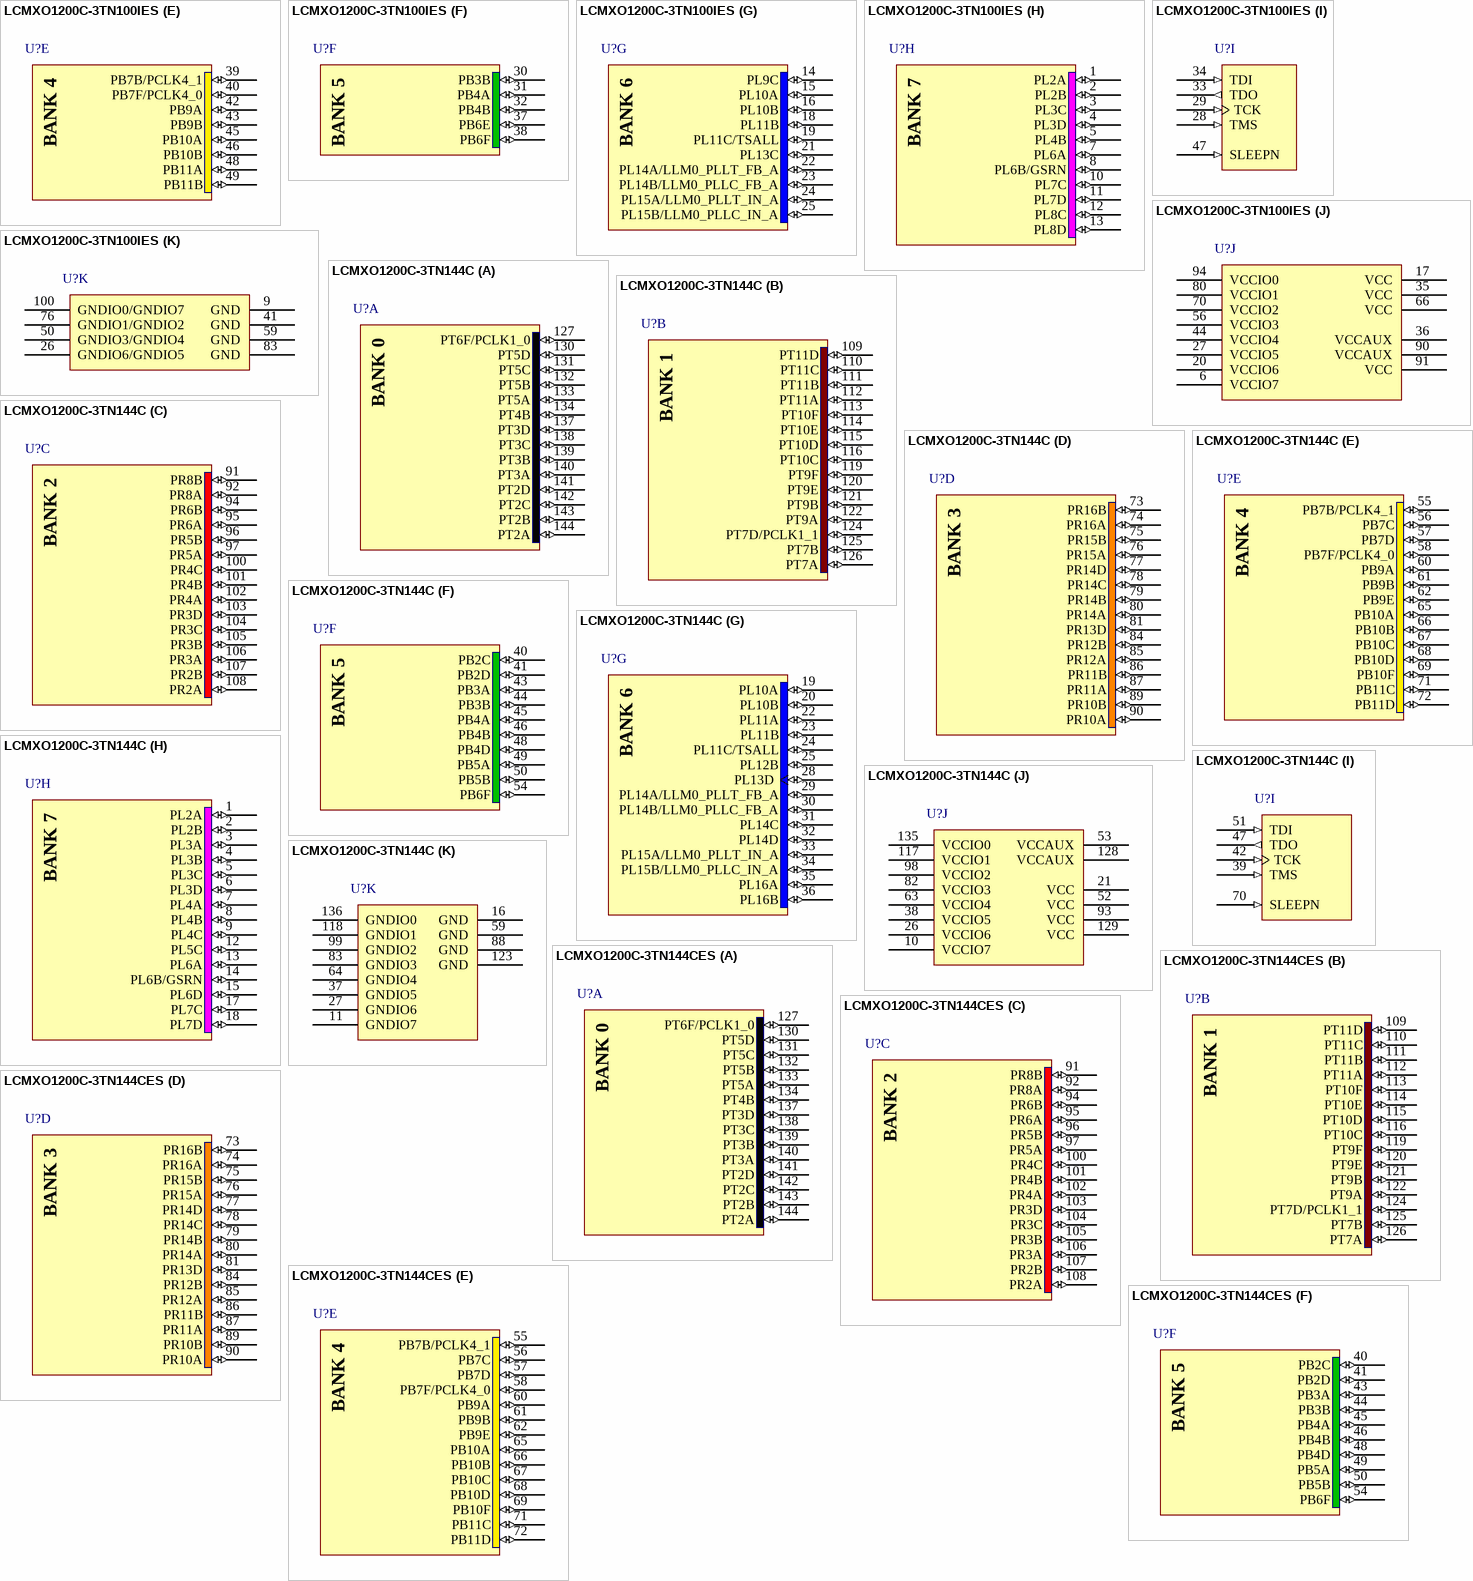
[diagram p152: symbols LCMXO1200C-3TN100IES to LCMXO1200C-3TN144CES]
## LCMXO1200C-3TN100IES
designator U?
MachXO 1200 Crossover PLD, 1.8V/2.5V/3.3V, 73 User I/Os, 100-Pins TQFP, Speed Grade-3, Industrial Grade, Pb-Free, Engineering Sample
footprint TQFP100_N (Thin QFP, 100-Leads, Body 14x14mm, Pitch 0.5mm, IPC Medium Density)
footprint TQFP100_L (Thin QFP, 100-Leads, Body 14x14mm, Pitch 0.5mm, IPC High Density)
footprint TQFP100_M (Thin QFP, 100-Leads, Body 14x14mm, Pitch 0.5mm, IPC Low Density)
3D model MachXO1200-TQFP100 (100-Pin Thin Quad Flat Pack (TQFP100))
signal-integrity model LCMXO1200C_T100 (MachXO)
part A pins: 87 PT6F/PCLK1_0 (io), 88 PT6D (io), 89 PT6C (io), 92 PT5B (io), 93 PT4B (io), 95 PT3D (io), 96 PT3C (io), 97 PT3B (io), 98 PT2B (io), 99 PT2A (io)
part B pins: 77 PT11C (io), 78 PT11B (io), 79 PT11A (io), 81 PT9E (io), 82 PT9A (io), 84 PT8B (io), 85 PT8A (io), 86 PT7D/PCLK1_1 (io)
part C pins: 64 PR8B (io), 65 PR8A (io), 67 PR6C (io), 68 PR6B (io), 69 PR6A (io), 71 PR4D (io), 72 PR4B (io), 73 PR4A (io), 74 PR2B (io), 75 PR2A (io)
part D pins: 51 PR16B (io), 52 PR15B (io), 53 PR15A (io), 54 PR14B (io), 55 PR14A (io), 57 PR12B (io), 58 PR12A (io), 60 PR10B (io), 61 PR10A (io), 62 PR9B (io), 63 PR9A (io)
part E pins: 39 PB7B/PCLK4_1 (io), 40 PB7F/PCLK4_0 (io), 42 PB9A (io), 43 PB9B (io), 45 PB10A (io), 46 PB10B (io), 48 PB11A (io), 49 PB11B (io)
part F pins: 30 PB3B (io), 31 PB4A (io), 32 PB4B (io), 37 PB6E (io), 38 PB6F (io)
part G pins: 14 PL9C (io), 15 PL10A (io), 16 PL10B (io), 18 PL11B (io), 19 PL11C/TSALL (io), 21 PL13C (io), 22 PL14A/LLM0_PLLT_FB_A (io), 23 PL14B/LLM0_PLLC_FB_A (io), 24 PL15A/LLM0_PLLT_IN_A (io), 25 PL15B/LLM0_PLLC_IN_A (io)
part H pins: 1 PL2A (io), 2 PL2B (io), 3 PL3C (io), 4 PL3D (io), 5 PL4B (io), 7 PL6A (io), 8 PL6B/GSRN (io), 10 PL7C (io), 11 PL7D (io), 12 PL8C (io), 13 PL8D (io)
part I pins: 28 TMS (in) "Powered by VCCIO5", 29 TCK (in) "Powered by VCCIO5", 33 TDO (out) "Powered by VCCIO5", 34 TDI (in) "Powered by VCCIO5", 47 SLEEPN (in) "Powered by VCCIO5"
part J pins: 6 VCCIO7 (power), 17 VCC (power), 20 VCCIO6 (power), 27 VCCIO5 (power), 35 VCC (power), 36 VCCAUX (power), 44 VCCIO4 (power), 56 VCCIO3 (power), 66 VCC (power), 70 VCCIO2 (power), 80 VCCIO1 (power), 90 VCCAUX (power), 91 VCC (power), 94 VCCIO0 (power)
part K pins: 9 GND (power), 26 GNDIO6/GNDIO5 (power) "Double Bonded pin", 41 GND (power), 50 GNDIO3/GNDIO4 (power) "Double Bonded pin", 59 GND (power), 76 GNDIO1/GNDIO2 (power) "Double Bonded pin", 83 GND (power), 100 GNDIO0/GNDIO7 (power) "Double Bonded pin"

## LCMXO1200C-3TN144C
designator U?
MachXO 1200 Crossover PLD, 1.8V/2.5V/3.3V, 113 User I/Os, 144-Pins TQFP, Speed Grade-3, Commercial Grade, Pb-Free
footprint TQFP144_N (Thin QFP, 144-Leads, Body 20x20mm, Pitch 0.5mm, IPC Medium Density)
footprint TQFP144_L (Thin QFP, 144-Leads, Body 20x20mm, Pitch 0.5mm, IPC High Density)
footprint TQFP144_M (Thin QFP, 144-Leads, Body 20x20mm, Pitch 0.5mm, IPC Low Density)
3D model MachXO1200-TQFP144 (144-Pin Thin Quad Flat Pack (TQFP144))
signal-integrity model LCMXO1200C_T144 (MachXO)
part A pins: 127 PT6F/PCLK1_0 (io), 130 PT5D (io), 131 PT5C (io), 132 PT5B (io), 133 PT5A (io), 134 PT4B (io), 137 PT3D (io), 138 PT3C (io), 139 PT3B (io), 140 PT3A (io), 141 PT2D (io), 142 PT2C (io), 143 PT2B (io), 144 PT2A (io)
part B pins: 109 PT11D (io), 110 PT11C (io), 111 PT11B (io), 112 PT11A (io), 113 PT10F (io), 114 PT10E (io), 115 PT10D (io), 116 PT10C (io), 119 PT9F (io), 120 PT9E (io), 121 PT9B (io), 122 PT9A (io), 124 PT7D/PCLK1_1 (io), 125 PT7B (io), 126 PT7A (io)
part C pins: 91 PR8B (io), 92 PR8A (io), 94 PR6B (io), 95 PR6A (io), 96 PR5B (io), 97 PR5A (io), 100 PR4C (io), 101 PR4B (io), 102 PR4A (io), 103 PR3D (io), 104 PR3C (io), 105 PR3B (io), 106 PR3A (io), 107 PR2B (io), 108 PR2A (io)
part D pins: 73 PR16B (io), 74 PR16A (io), 75 PR15B (io), 76 PR15A (io), 77 PR14D (io), 78 PR14C (io), 79 PR14B (io), 80 PR14A (io), 81 PR13D (io), 84 PR12B (io), 85 PR12A (io), 86 PR11B (io), 87 PR11A (io), 89 PR10B (io), 90 PR10A (io)
part E pins: 55 PB7B/PCLK4_1 (io), 56 PB7C (io), 57 PB7D (io), 58 PB7F/PCLK4_0 (io), 60 PB9A (io), 61 PB9B (io), 62 PB9E (io), 65 PB10A (io), 66 PB10B (io), 67 PB10C (io), 68 PB10D (io), 69 PB10F (io), 71 PB11C (io), 72 PB11D (io)
part F pins: 40 PB2C (io), 41 PB2D (io), 43 PB3A (io), 44 PB3B (io), 45 PB4A (io), 46 PB4B (io), 48 PB4D (io), 49 PB5A (io), 50 PB5B (io), 54 PB6F (io)
part G pins: 19 PL10A (io), 20 PL10B (io), 22 PL11A (io), 23 PL11B (io), 24 PL11C/TSALL (io), 25 PL12B (io), 28 PL13D (io), 29 PL14A/LLM0_PLLT_FB_A (io), 30 PL14B/LLM0_PLLC_FB_A (io), 31 PL14C (io), 32 PL14D (io), 33 PL15A/LLM0_PLLT_IN_A (io), 34 PL15B/LLM0_PLLC_IN_A (io), 35 PL16A (io), 36 PL16B (io)
part H pins: 1 PL2A (io), 2 PL2B (io), 3 PL3A (io), 4 PL3B (io), 5 PL3C (io), 6 PL3D (io), 7 PL4A (io), 8 PL4B (io), 9 PL4C (io), 12 PL5C (io), 13 PL6A (io), 14 PL6B/GSRN (io), 15 PL6D (io), 17 PL7C (io), 18 PL7D (io)
part I pins: 39 TMS (in) "Powered by VCCIO5", 42 TCK (in) "Powered by VCCIO5", 47 TDO (out) "Powered by VCCIO5", 51 TDI (in) "Powered by VCCIO5", 70 SLEEPN (in) "Powered by VCCIO4"
part J pins: 10 VCCIO7 (power), 21 VCC (power), 26 VCCIO6 (power), 38 VCCIO5 (power), 52 VCC (power), 53 VCCAUX (power), 63 VCCIO4 (power), 82 VCCIO3 (power), 93 VCC (power), 98 VCCIO2 (power), 117 VCCIO1 (power), 128 VCCAUX (power), 129 VCC (power), 135 VCCIO0 (power)
part K pins: 11 GNDIO7 (power), 16 GND (power), 27 GNDIO6 (power), 37 GNDIO5 (power), 59 GND (power), 64 GNDIO4 (power), 83 GNDIO3 (power), 88 GND (power), 99 GNDIO2 (power), 118 GNDIO1 (power), 123 GND (power), 136 GNDIO0 (power)


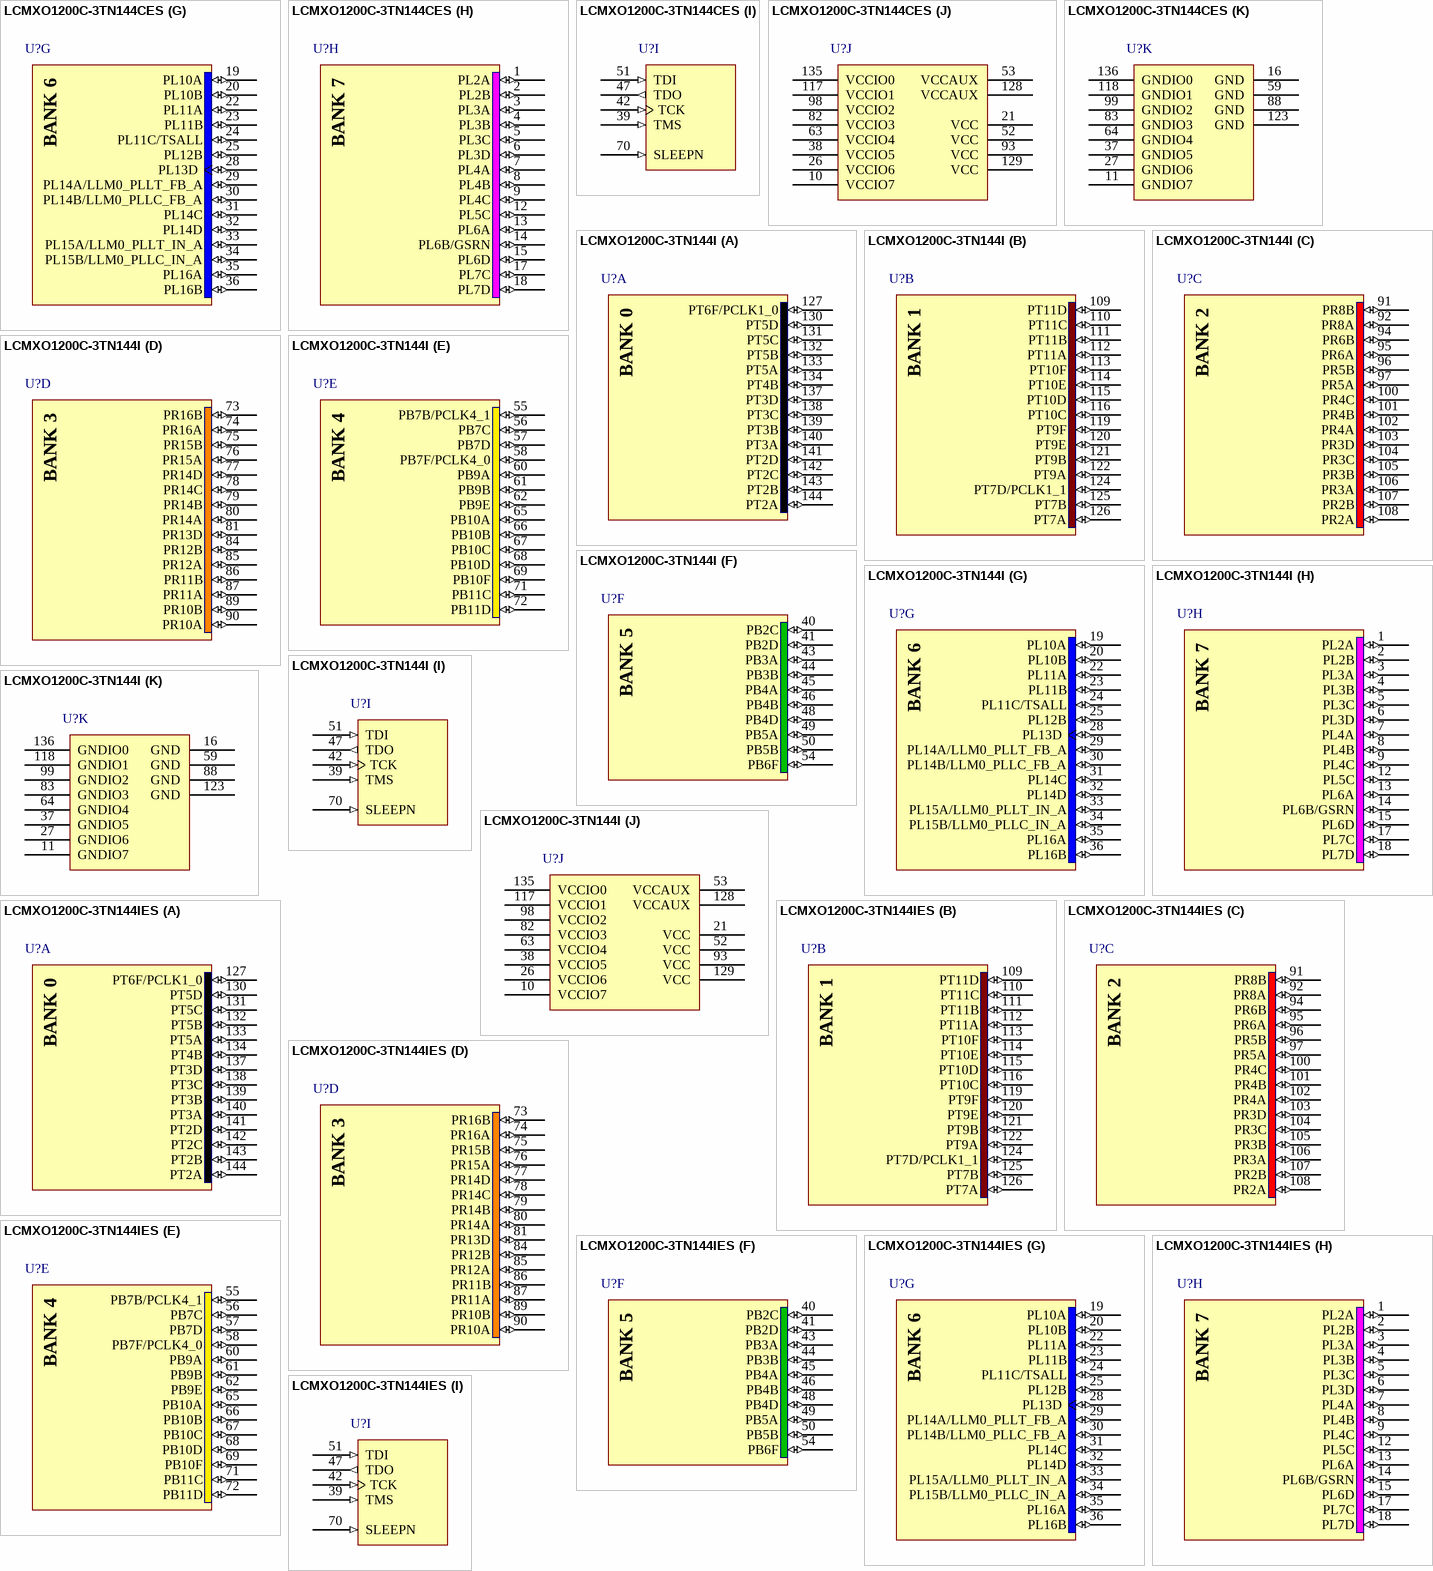
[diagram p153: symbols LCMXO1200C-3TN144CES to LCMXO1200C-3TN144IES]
## LCMXO1200C-3TN144CES
designator U?
MachXO 1200 Crossover PLD, 1.8V/2.5V/3.3V, 113 User I/Os, 144-Pins TQFP, Speed Grade-3, Commercial Grade, Pb-Free, Engineering Sample
footprint TQFP144_N (Thin QFP, 144-Leads, Body 20x20mm, Pitch 0.5mm, IPC Medium Density)
footprint TQFP144_L (Thin QFP, 144-Leads, Body 20x20mm, Pitch 0.5mm, IPC High Density)
footprint TQFP144_M (Thin QFP, 144-Leads, Body 20x20mm, Pitch 0.5mm, IPC Low Density)
3D model MachXO1200-TQFP144 (144-Pin Thin Quad Flat Pack (TQFP144))
signal-integrity model LCMXO1200C_T144 (MachXO)
part A pins: 127 PT6F/PCLK1_0 (io), 130 PT5D (io), 131 PT5C (io), 132 PT5B (io), 133 PT5A (io), 134 PT4B (io), 137 PT3D (io), 138 PT3C (io), 139 PT3B (io), 140 PT3A (io), 141 PT2D (io), 142 PT2C (io), 143 PT2B (io), 144 PT2A (io)
part B pins: 109 PT11D (io), 110 PT11C (io), 111 PT11B (io), 112 PT11A (io), 113 PT10F (io), 114 PT10E (io), 115 PT10D (io), 116 PT10C (io), 119 PT9F (io), 120 PT9E (io), 121 PT9B (io), 122 PT9A (io), 124 PT7D/PCLK1_1 (io), 125 PT7B (io), 126 PT7A (io)
part C pins: 91 PR8B (io), 92 PR8A (io), 94 PR6B (io), 95 PR6A (io), 96 PR5B (io), 97 PR5A (io), 100 PR4C (io), 101 PR4B (io), 102 PR4A (io), 103 PR3D (io), 104 PR3C (io), 105 PR3B (io), 106 PR3A (io), 107 PR2B (io), 108 PR2A (io)
part D pins: 73 PR16B (io), 74 PR16A (io), 75 PR15B (io), 76 PR15A (io), 77 PR14D (io), 78 PR14C (io), 79 PR14B (io), 80 PR14A (io), 81 PR13D (io), 84 PR12B (io), 85 PR12A (io), 86 PR11B (io), 87 PR11A (io), 89 PR10B (io), 90 PR10A (io)
part E pins: 55 PB7B/PCLK4_1 (io), 56 PB7C (io), 57 PB7D (io), 58 PB7F/PCLK4_0 (io), 60 PB9A (io), 61 PB9B (io), 62 PB9E (io), 65 PB10A (io), 66 PB10B (io), 67 PB10C (io), 68 PB10D (io), 69 PB10F (io), 71 PB11C (io), 72 PB11D (io)
part F pins: 40 PB2C (io), 41 PB2D (io), 43 PB3A (io), 44 PB3B (io), 45 PB4A (io), 46 PB4B (io), 48 PB4D (io), 49 PB5A (io), 50 PB5B (io), 54 PB6F (io)
part G pins: 19 PL10A (io), 20 PL10B (io), 22 PL11A (io), 23 PL11B (io), 24 PL11C/TSALL (io), 25 PL12B (io), 28 PL13D (io), 29 PL14A/LLM0_PLLT_FB_A (io), 30 PL14B/LLM0_PLLC_FB_A (io), 31 PL14C (io), 32 PL14D (io), 33 PL15A/LLM0_PLLT_IN_A (io), 34 PL15B/LLM0_PLLC_IN_A (io), 35 PL16A (io), 36 PL16B (io)
part H pins: 1 PL2A (io), 2 PL2B (io), 3 PL3A (io), 4 PL3B (io), 5 PL3C (io), 6 PL3D (io), 7 PL4A (io), 8 PL4B (io), 9 PL4C (io), 12 PL5C (io), 13 PL6A (io), 14 PL6B/GSRN (io), 15 PL6D (io), 17 PL7C (io), 18 PL7D (io)
part I pins: 39 TMS (in) "Powered by VCCIO5", 42 TCK (in) "Powered by VCCIO5", 47 TDO (out) "Powered by VCCIO5", 51 TDI (in) "Powered by VCCIO5", 70 SLEEPN (in) "Powered by VCCIO4"
part J pins: 10 VCCIO7 (power), 21 VCC (power), 26 VCCIO6 (power), 38 VCCIO5 (power), 52 VCC (power), 53 VCCAUX (power), 63 VCCIO4 (power), 82 VCCIO3 (power), 93 VCC (power), 98 VCCIO2 (power), 117 VCCIO1 (power), 128 VCCAUX (power), 129 VCC (power), 135 VCCIO0 (power)
part K pins: 11 GNDIO7 (power), 16 GND (power), 27 GNDIO6 (power), 37 GNDIO5 (power), 59 GND (power), 64 GNDIO4 (power), 83 GNDIO3 (power), 88 GND (power), 99 GNDIO2 (power), 118 GNDIO1 (power), 123 GND (power), 136 GNDIO0 (power)

## LCMXO1200C-3TN144I
designator U?
MachXO 1200 Crossover PLD, 1.8V/2.5V/3.3V, 113 User I/Os, 144-Pins TQFP, Speed Grade-3, Industrial Grade, Pb-Free
footprint TQFP144_N (Thin QFP, 144-Leads, Body 20x20mm, Pitch 0.5mm, IPC Medium Density)
footprint TQFP144_L (Thin QFP, 144-Leads, Body 20x20mm, Pitch 0.5mm, IPC High Density)
footprint TQFP144_M (Thin QFP, 144-Leads, Body 20x20mm, Pitch 0.5mm, IPC Low Density)
3D model MachXO1200-TQFP144 (144-Pin Thin Quad Flat Pack (TQFP144))
signal-integrity model LCMXO1200C_T144 (MachXO)
part A pins: 127 PT6F/PCLK1_0 (io), 130 PT5D (io), 131 PT5C (io), 132 PT5B (io), 133 PT5A (io), 134 PT4B (io), 137 PT3D (io), 138 PT3C (io), 139 PT3B (io), 140 PT3A (io), 141 PT2D (io), 142 PT2C (io), 143 PT2B (io), 144 PT2A (io)
part B pins: 109 PT11D (io), 110 PT11C (io), 111 PT11B (io), 112 PT11A (io), 113 PT10F (io), 114 PT10E (io), 115 PT10D (io), 116 PT10C (io), 119 PT9F (io), 120 PT9E (io), 121 PT9B (io), 122 PT9A (io), 124 PT7D/PCLK1_1 (io), 125 PT7B (io), 126 PT7A (io)
part C pins: 91 PR8B (io), 92 PR8A (io), 94 PR6B (io), 95 PR6A (io), 96 PR5B (io), 97 PR5A (io), 100 PR4C (io), 101 PR4B (io), 102 PR4A (io), 103 PR3D (io), 104 PR3C (io), 105 PR3B (io), 106 PR3A (io), 107 PR2B (io), 108 PR2A (io)
part D pins: 73 PR16B (io), 74 PR16A (io), 75 PR15B (io), 76 PR15A (io), 77 PR14D (io), 78 PR14C (io), 79 PR14B (io), 80 PR14A (io), 81 PR13D (io), 84 PR12B (io), 85 PR12A (io), 86 PR11B (io), 87 PR11A (io), 89 PR10B (io), 90 PR10A (io)
part E pins: 55 PB7B/PCLK4_1 (io), 56 PB7C (io), 57 PB7D (io), 58 PB7F/PCLK4_0 (io), 60 PB9A (io), 61 PB9B (io), 62 PB9E (io), 65 PB10A (io), 66 PB10B (io), 67 PB10C (io), 68 PB10D (io), 69 PB10F (io), 71 PB11C (io), 72 PB11D (io)
part F pins: 40 PB2C (io), 41 PB2D (io), 43 PB3A (io), 44 PB3B (io), 45 PB4A (io), 46 PB4B (io), 48 PB4D (io), 49 PB5A (io), 50 PB5B (io), 54 PB6F (io)
part G pins: 19 PL10A (io), 20 PL10B (io), 22 PL11A (io), 23 PL11B (io), 24 PL11C/TSALL (io), 25 PL12B (io), 28 PL13D (io), 29 PL14A/LLM0_PLLT_FB_A (io), 30 PL14B/LLM0_PLLC_FB_A (io), 31 PL14C (io), 32 PL14D (io), 33 PL15A/LLM0_PLLT_IN_A (io), 34 PL15B/LLM0_PLLC_IN_A (io), 35 PL16A (io), 36 PL16B (io)
part H pins: 1 PL2A (io), 2 PL2B (io), 3 PL3A (io), 4 PL3B (io), 5 PL3C (io), 6 PL3D (io), 7 PL4A (io), 8 PL4B (io), 9 PL4C (io), 12 PL5C (io), 13 PL6A (io), 14 PL6B/GSRN (io), 15 PL6D (io), 17 PL7C (io), 18 PL7D (io)
part I pins: 39 TMS (in) "Powered by VCCIO5", 42 TCK (in) "Powered by VCCIO5", 47 TDO (out) "Powered by VCCIO5", 51 TDI (in) "Powered by VCCIO5", 70 SLEEPN (in) "Powered by VCCIO4"
part J pins: 10 VCCIO7 (power), 21 VCC (power), 26 VCCIO6 (power), 38 VCCIO5 (power), 52 VCC (power), 53 VCCAUX (power), 63 VCCIO4 (power), 82 VCCIO3 (power), 93 VCC (power), 98 VCCIO2 (power), 117 VCCIO1 (power), 128 VCCAUX (power), 129 VCC (power), 135 VCCIO0 (power)
part K pins: 11 GNDIO7 (power), 16 GND (power), 27 GNDIO6 (power), 37 GNDIO5 (power), 59 GND (power), 64 GNDIO4 (power), 83 GNDIO3 (power), 88 GND (power), 99 GNDIO2 (power), 118 GNDIO1 (power), 123 GND (power), 136 GNDIO0 (power)


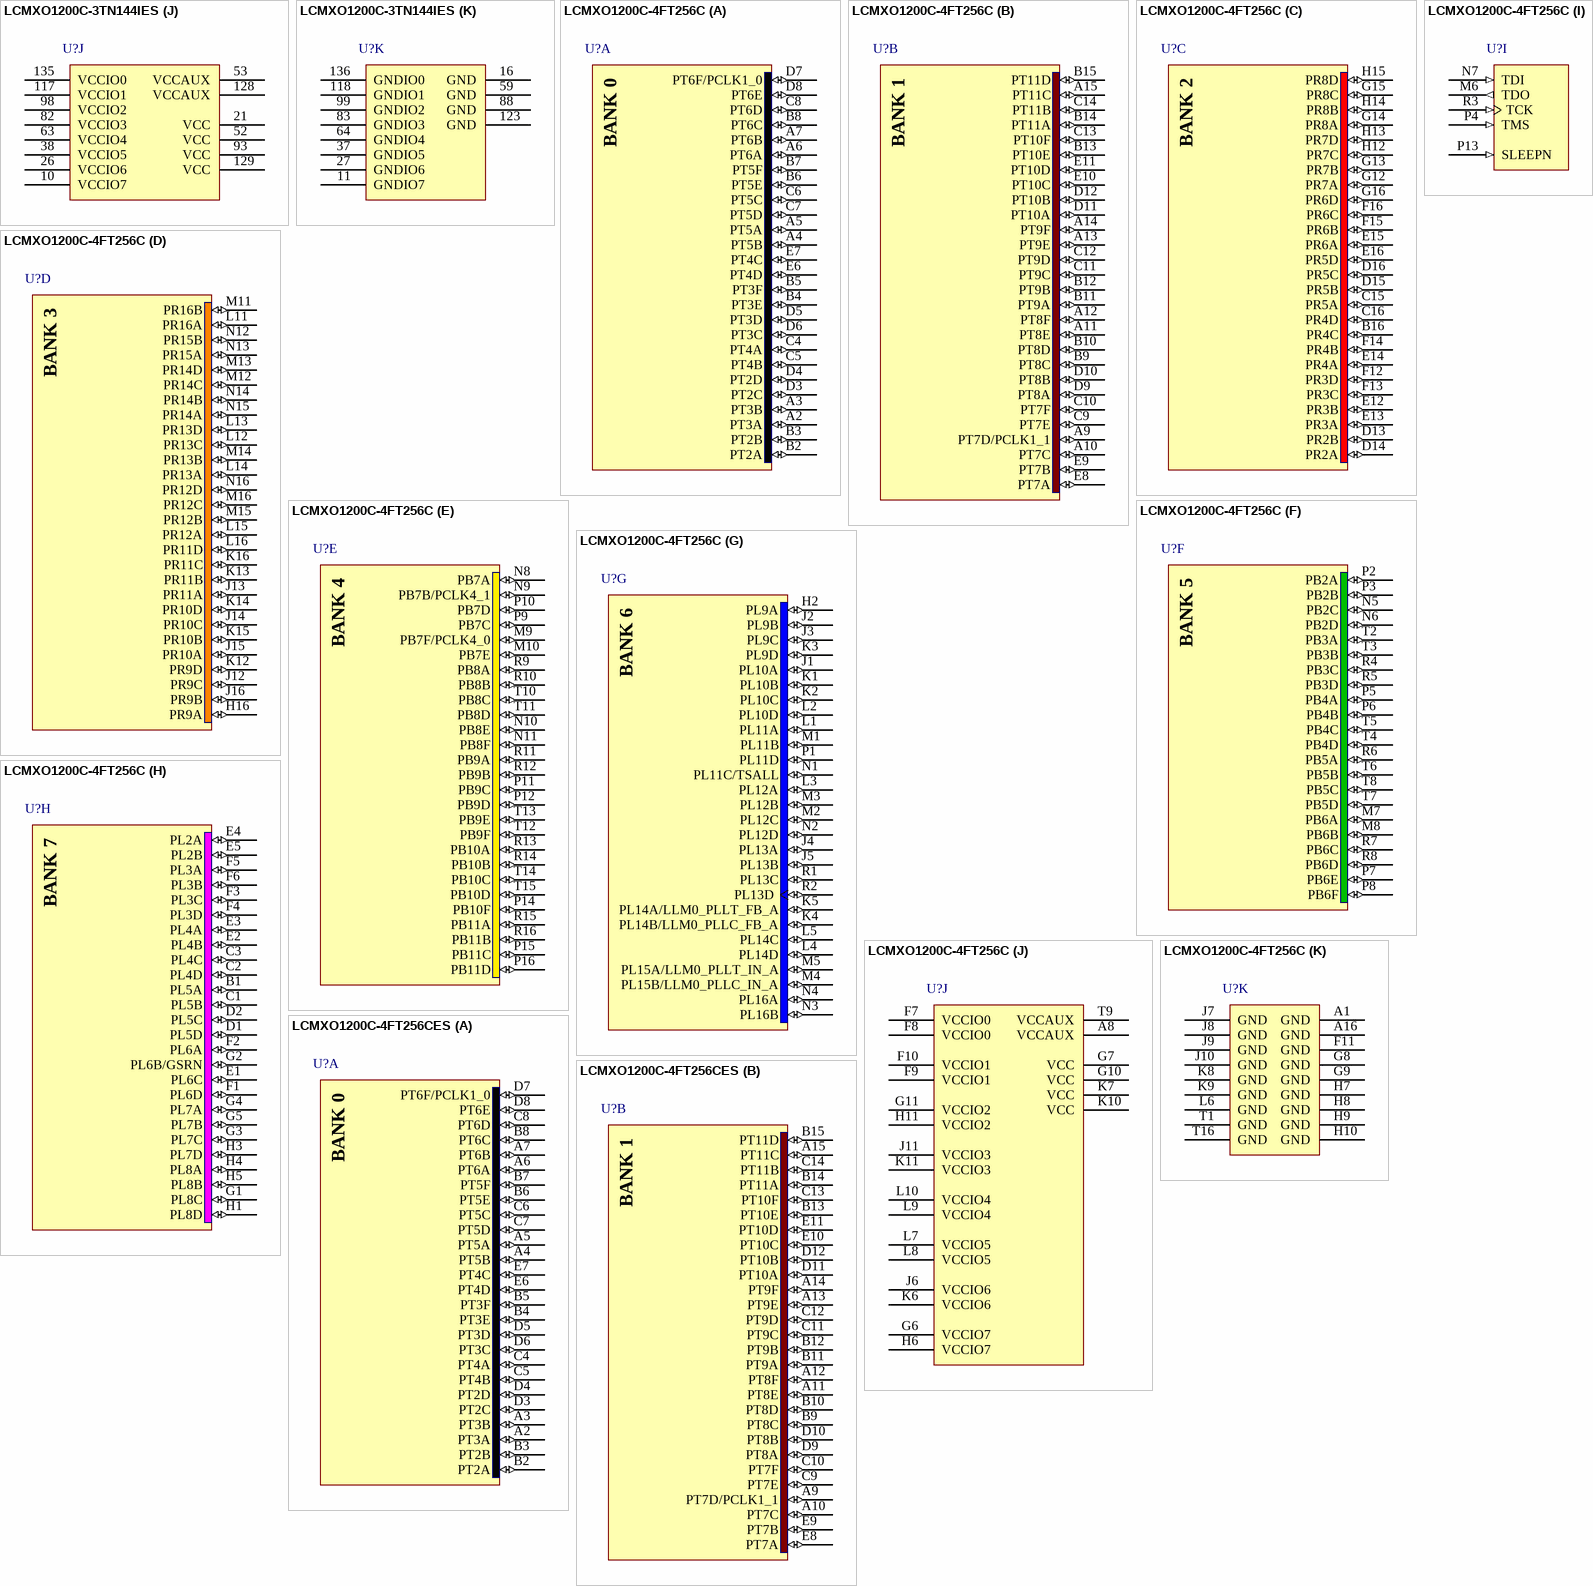
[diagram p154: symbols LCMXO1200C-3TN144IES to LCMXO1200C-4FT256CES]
## LCMXO1200C-3TN144IES
designator U?
MachXO 1200 Crossover PLD, 1.8V/2.5V/3.3V, 113 User I/Os, 144-Pins TQFP, Speed Grade-3, Industrial Grade, Pb-Free, Engineering Sample
footprint TQFP144_N (Thin QFP, 144-Leads, Body 20x20mm, Pitch 0.5mm, IPC Medium Density)
footprint TQFP144_L (Thin QFP, 144-Leads, Body 20x20mm, Pitch 0.5mm, IPC High Density)
footprint TQFP144_M (Thin QFP, 144-Leads, Body 20x20mm, Pitch 0.5mm, IPC Low Density)
3D model MachXO1200-TQFP144 (144-Pin Thin Quad Flat Pack (TQFP144))
signal-integrity model LCMXO1200C_T144 (MachXO)
part A pins: 127 PT6F/PCLK1_0 (io), 130 PT5D (io), 131 PT5C (io), 132 PT5B (io), 133 PT5A (io), 134 PT4B (io), 137 PT3D (io), 138 PT3C (io), 139 PT3B (io), 140 PT3A (io), 141 PT2D (io), 142 PT2C (io), 143 PT2B (io), 144 PT2A (io)
part B pins: 109 PT11D (io), 110 PT11C (io), 111 PT11B (io), 112 PT11A (io), 113 PT10F (io), 114 PT10E (io), 115 PT10D (io), 116 PT10C (io), 119 PT9F (io), 120 PT9E (io), 121 PT9B (io), 122 PT9A (io), 124 PT7D/PCLK1_1 (io), 125 PT7B (io), 126 PT7A (io)
part C pins: 91 PR8B (io), 92 PR8A (io), 94 PR6B (io), 95 PR6A (io), 96 PR5B (io), 97 PR5A (io), 100 PR4C (io), 101 PR4B (io), 102 PR4A (io), 103 PR3D (io), 104 PR3C (io), 105 PR3B (io), 106 PR3A (io), 107 PR2B (io), 108 PR2A (io)
part D pins: 73 PR16B (io), 74 PR16A (io), 75 PR15B (io), 76 PR15A (io), 77 PR14D (io), 78 PR14C (io), 79 PR14B (io), 80 PR14A (io), 81 PR13D (io), 84 PR12B (io), 85 PR12A (io), 86 PR11B (io), 87 PR11A (io), 89 PR10B (io), 90 PR10A (io)
part E pins: 55 PB7B/PCLK4_1 (io), 56 PB7C (io), 57 PB7D (io), 58 PB7F/PCLK4_0 (io), 60 PB9A (io), 61 PB9B (io), 62 PB9E (io), 65 PB10A (io), 66 PB10B (io), 67 PB10C (io), 68 PB10D (io), 69 PB10F (io), 71 PB11C (io), 72 PB11D (io)
part F pins: 40 PB2C (io), 41 PB2D (io), 43 PB3A (io), 44 PB3B (io), 45 PB4A (io), 46 PB4B (io), 48 PB4D (io), 49 PB5A (io), 50 PB5B (io), 54 PB6F (io)
part G pins: 19 PL10A (io), 20 PL10B (io), 22 PL11A (io), 23 PL11B (io), 24 PL11C/TSALL (io), 25 PL12B (io), 28 PL13D (io), 29 PL14A/LLM0_PLLT_FB_A (io), 30 PL14B/LLM0_PLLC_FB_A (io), 31 PL14C (io), 32 PL14D (io), 33 PL15A/LLM0_PLLT_IN_A (io), 34 PL15B/LLM0_PLLC_IN_A (io), 35 PL16A (io), 36 PL16B (io)
part H pins: 1 PL2A (io), 2 PL2B (io), 3 PL3A (io), 4 PL3B (io), 5 PL3C (io), 6 PL3D (io), 7 PL4A (io), 8 PL4B (io), 9 PL4C (io), 12 PL5C (io), 13 PL6A (io), 14 PL6B/GSRN (io), 15 PL6D (io), 17 PL7C (io), 18 PL7D (io)
part I pins: 39 TMS (in) "Powered by VCCIO5", 42 TCK (in) "Powered by VCCIO5", 47 TDO (out) "Powered by VCCIO5", 51 TDI (in) "Powered by VCCIO5", 70 SLEEPN (in) "Powered by VCCIO4"
part J pins: 10 VCCIO7 (power), 21 VCC (power), 26 VCCIO6 (power), 38 VCCIO5 (power), 52 VCC (power), 53 VCCAUX (power), 63 VCCIO4 (power), 82 VCCIO3 (power), 93 VCC (power), 98 VCCIO2 (power), 117 VCCIO1 (power), 128 VCCAUX (power), 129 VCC (power), 135 VCCIO0 (power)
part K pins: 11 GNDIO7 (power), 16 GND (power), 27 GNDIO6 (power), 37 GNDIO5 (power), 59 GND (power), 64 GNDIO4 (power), 83 GNDIO3 (power), 88 GND (power), 99 GNDIO2 (power), 118 GNDIO1 (power), 123 GND (power), 136 GNDIO0 (power)

## LCMXO1200C-4FT256C
designator U?
MachXO 1200 Crossover PLD, 1.8V/2.5V/3.3V, 211 User I/Os, 256-Pins ftBGA, Speed Grade-4, Commercial Grade
footprint ftBGA256 (BGA, 256-Leads, Body 17x17mm, Pitch 1mm)
3D model MachXO1200-ftBGA256 (256-Ball Fine Thin Ball Grid Array (ftBGA256))
signal-integrity model LCMXO1200C_FT256 (MachXO)
part A pins: A2 PT3A (io), A3 PT3B (io), A4 PT5B (io), A5 PT5A (io), A6 PT6A (io), A7 PT6B (io), B2 PT2A (io), B3 PT2B (io), B4 PT3E (io), B5 PT3F (io), B6 PT5E (io), B7 PT5F (io), B8 PT6C (io), C4 PT4A (io), C5 PT4B (io), C6 PT5C (io), C7 PT5D (io), C8 PT6D (io), D3 PT2C (io), D4 PT2D (io), D5 PT3D (io), D6 PT3C (io), D7 PT6F/PCLK1_0 (io), D8 PT6E (io), E6 PT4D (io), E7 PT4C (io)
part B pins: A9 PT7D/PCLK1_1 (io), A10 PT7C (io), A11 PT8E (io), A12 PT8F (io), A13 PT9E (io), A14 PT9F (io), A15 PT11C (io), B9 PT8C (io), B10 PT8D (io), B11 PT9A (io), B12 PT9B (io), B13 PT10E (io), B14 PT11A (io), B15 PT11D (io), C9 PT7E (io), C10 PT7F (io), C11 PT9C (io), C12 PT9D (io), C13 PT10F (io), C14 PT11B (io), D9 PT8A (io), D10 PT8B (io), D11 PT10A (io), D12 PT10B (io), E8 PT7A (io), E9 PT7B (io), E10 PT10C (io), E11 PT10D (io)
part C pins: B16 PR4C (io), C15 PR5A (io), C16 PR4D (io), D13 PR2B (io), D14 PR2A (io), D15 PR5B (io), D16 PR5C (io), E12 PR3B (io), E13 PR3A (io), E14 PR4A (io), E15 PR6A (io), E16 PR5D (io), F12 PR3D (io), F13 PR3C (io), F14 PR4B (io), F15 PR6B (io), F16 PR6C (io), G12 PR7A (io), G13 PR7B (io), G14 PR8A (io), G15 PR8C (io), G16 PR6D (io), H12 PR7C (io), H13 PR7D (io), H14 PR8B (io), H15 PR8D (io)
part D pins: H16 PR9A (io), J12 PR9C (io), J13 PR11A (io), J14 PR10C (io), J15 PR10A (io), J16 PR9B (io), K12 PR9D (io), K13 PR11B (io), K14 PR10D (io), K15 PR10B (io), K16 PR11C (io), L11 PR16A (io), L12 PR13C (io), L13 PR13D (io), L14 PR13A (io), L15 PR12A (io), L16 PR11D (io), M11 PR16B (io), M12 PR14C (io), M13 PR14D (io), M14 PR13B (io), M15 PR12B (io), M16 PR12C (io), N12 PR15B (io), N13 PR15A (io), N14 PR14B (io), N15 PR14A (io), N16 PR12D (io)
part E pins: M9 PB7F/PCLK4_0 (io), M10 PB7E (io), N8 PB7A (io), N9 PB7B/PCLK4_1 (io), N10 PB8E (io), N11 PB8F (io), P9 PB7C (io), P10 PB7D (io), P11 PB9C (io), P12 PB9D (io), P14 PB10F (io), P15 PB11C (io), P16 PB11D (io), R9 PB8A (io), R10 PB8B (io), R11 PB9A (io), R12 PB9B (io), R13 PB10A (io), R14 PB10B (io), R15 PB11A (io), R16 PB11B (io), T10 PB8C (io), T11 PB8D (io), T12 PB9F (io), T13 PB9E (io), T14 PB10C (io), T15 PB10D (io)
part F pins: M7 PB6A (io), M8 PB6B (io), N5 PB2C (io), N6 PB2D (io), P2 PB2A (io), P3 PB2B (io), P5 PB4A (io), P6 PB4B (io), P7 PB6E (io), P8 PB6F (io), R4 PB3C (io), R5 PB3D (io), R6 PB5A (io), R7 PB6C (io), R8 PB6D (io), T2 PB3A (io), T3 PB3B (io), T4 PB4D (io), T5 PB4C (io), T6 PB5B (io), T7 PB5D (io), T8 PB5C (io)
part G pins: H2 PL9A (io), J1 PL10A (io), J2 PL9B (io), J3 PL9C (io), J4 PL13A (io), J5 PL13B (io), K1 PL10B (io), K2 PL10C (io), K3 PL9D (io), K4 PL14B/LLM0_PLLC_FB_A (io), K5 PL14A/LLM0_PLLT_FB_A (io), L1 PL11A (io), L2 PL10D (io), L3 PL12A (io), L4 PL14D (io), L5 PL14C (io), M1 PL11B (io), M2 PL12C (io), M3 PL12B (io), M4 PL15B/LLM0_PLLC_IN_A (io), M5 PL15A/LLM0_PLLT_IN_A (io), N1 PL11C/TSALL (io), N2 PL12D (io), N3 PL16B (io), N4 PL16A (io), P1 PL11D (io), R1 PL13C (io), R2 PL13D (io)
part H pins: B1 PL5A (io), C1 PL5B (io), C2 PL4D (io), C3 PL4C (io), D1 PL5D (io), D2 PL5C (io), E1 PL6C (io), E2 PL4B (io), E3 PL4A (io), E4 PL2A (io), E5 PL2B (io), F1 PL6D (io), F2 PL6A (io), F3 PL3C (io), F4 PL3D (io), F5 PL3A (io), F6 PL3B (io), G1 PL8C (io), G2 PL6B/GSRN (io), G3 PL7C (io), G4 PL7A (io), G5 PL7B (io), H1 PL8D (io), H3 PL7D (io), H4 PL8A (io), H5 PL8B (io)
part I pins: M6 TDO (out) "Powered by VCCIO5", N7 TDI (in) "Powered by VCCIO5", P4 TMS (in) "Powered by VCCIO5", P13 SLEEPN (in) "Powered by VCCIO4", R3 TCK (in) "Powered by VCCIO5"
part J pins: A8 VCCAUX (power), F7 VCCIO0 (power), F8 VCCIO0 (power), F9 VCCIO1 (power), F10 VCCIO1 (power), G6 VCCIO7 (power), G7 VCC (power), G10 VCC (power), G11 VCCIO2 (power), H6 VCCIO7 (power), H11 VCCIO2 (power), J6 VCCIO6 (power), J11 VCCIO3 (power), K6 VCCIO6 (power), K7 VCC (power), K10 VCC (power), K11 VCCIO3 (power), L7 VCCIO5 (power), L8 VCCIO5 (power), L9 VCCIO4 (power), L10 VCCIO4 (power), T9 VCCAUX (power)
part K pins: A1 GND (power), A16 GND (power), F11 GND (power), G8 GND (power), G9 GND (power), H7 GND (power), H8 GND (power), H9 GND (power), H10 GND (power), J7 GND (power), J8 GND (power), J9 GND (power), J10 GND (power), K8 GND (power), K9 GND (power), L6 GND (power), T1 GND (power), T16 GND (power)


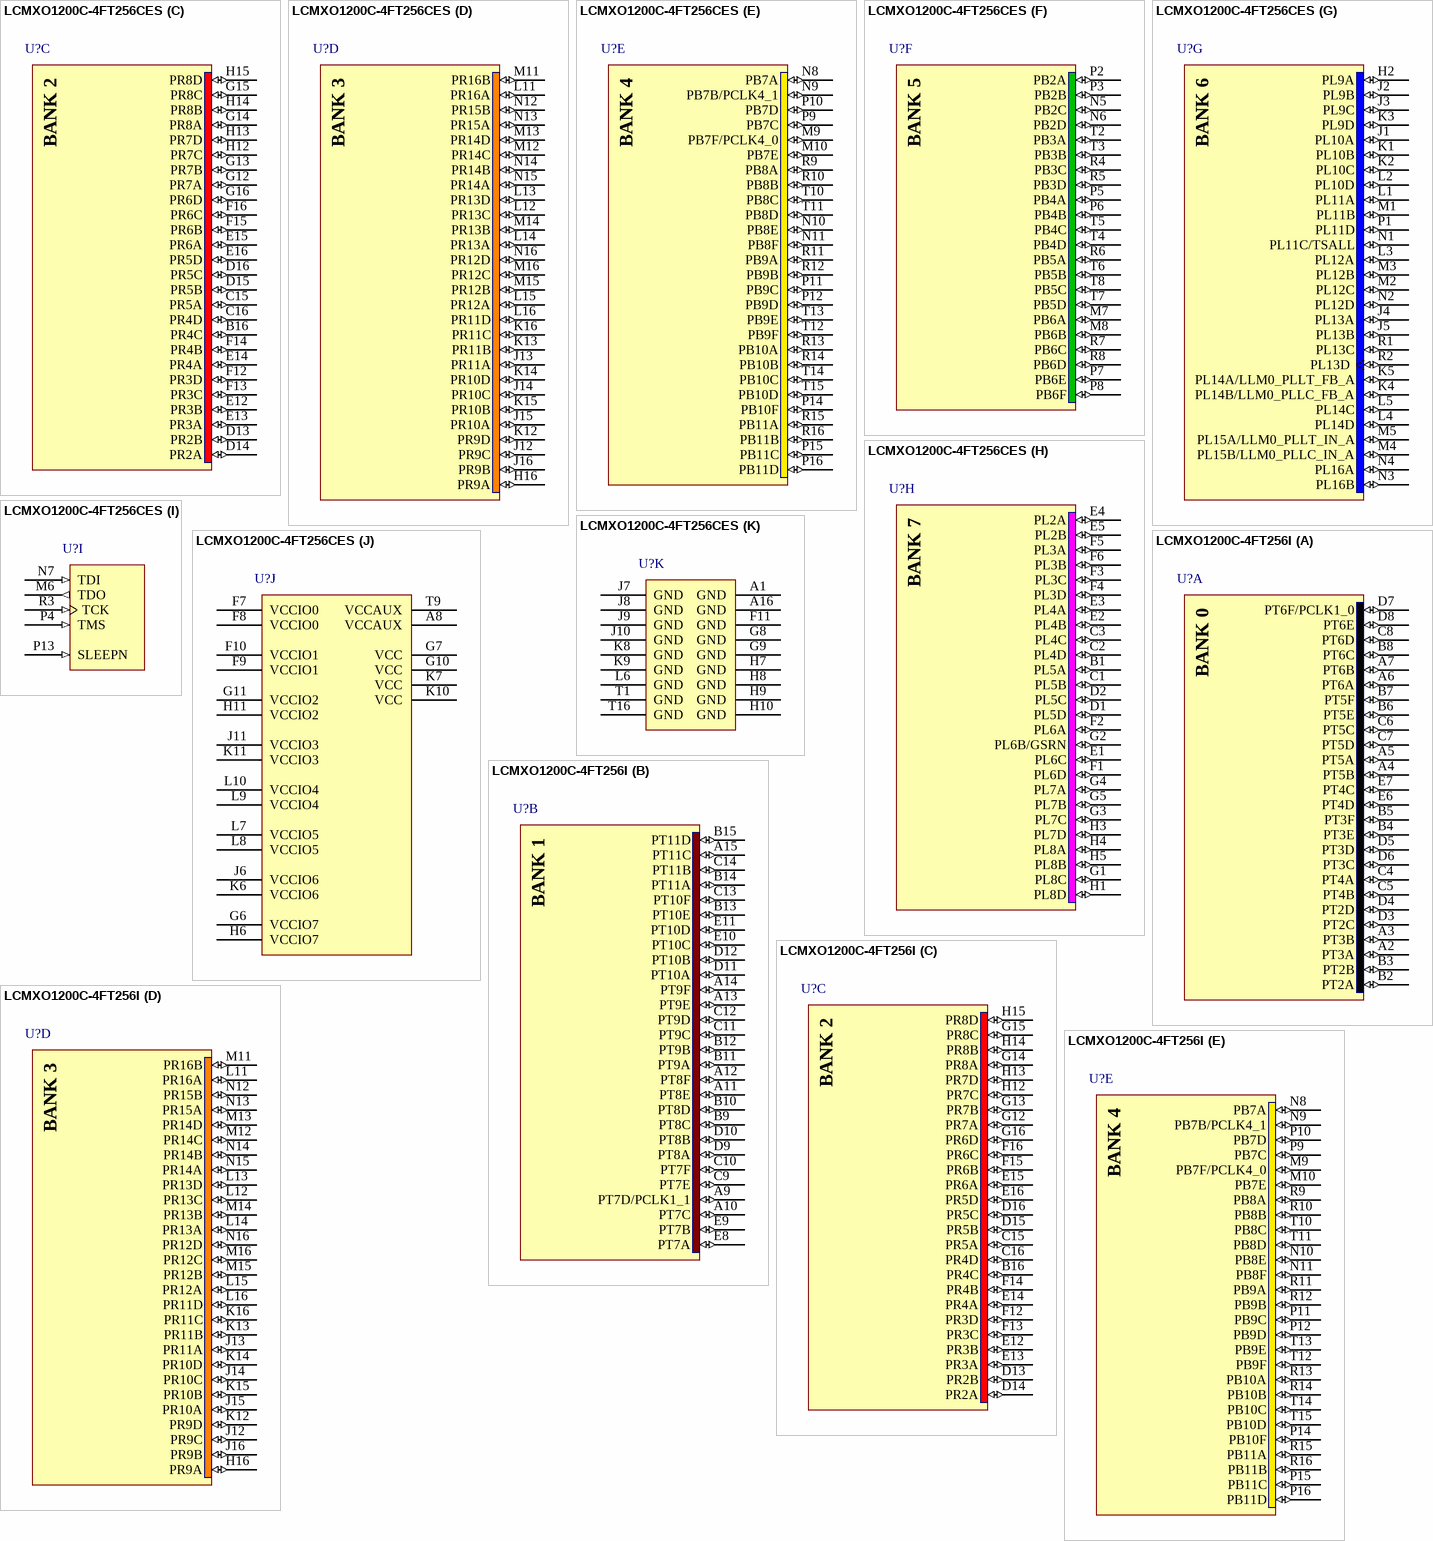
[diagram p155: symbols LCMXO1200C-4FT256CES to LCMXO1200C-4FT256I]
## LCMXO1200C-4FT256CES
designator U?
MachXO 1200 Crossover PLD, 1.8V/2.5V/3.3V, 211 User I/Os, 256-Pins ftBGA, Speed Grade-4, Commercial Grade, Engineering Sample
footprint ftBGA256 (BGA, 256-Leads, Body 17x17mm, Pitch 1mm)
3D model MachXO1200-ftBGA256 (256-Ball Fine Thin Ball Grid Array (ftBGA256))
signal-integrity model LCMXO1200C_FT256 (MachXO)
part A pins: A2 PT3A (io), A3 PT3B (io), A4 PT5B (io), A5 PT5A (io), A6 PT6A (io), A7 PT6B (io), B2 PT2A (io), B3 PT2B (io), B4 PT3E (io), B5 PT3F (io), B6 PT5E (io), B7 PT5F (io), B8 PT6C (io), C4 PT4A (io), C5 PT4B (io), C6 PT5C (io), C7 PT5D (io), C8 PT6D (io), D3 PT2C (io), D4 PT2D (io), D5 PT3D (io), D6 PT3C (io), D7 PT6F/PCLK1_0 (io), D8 PT6E (io), E6 PT4D (io), E7 PT4C (io)
part B pins: A9 PT7D/PCLK1_1 (io), A10 PT7C (io), A11 PT8E (io), A12 PT8F (io), A13 PT9E (io), A14 PT9F (io), A15 PT11C (io), B9 PT8C (io), B10 PT8D (io), B11 PT9A (io), B12 PT9B (io), B13 PT10E (io), B14 PT11A (io), B15 PT11D (io), C9 PT7E (io), C10 PT7F (io), C11 PT9C (io), C12 PT9D (io), C13 PT10F (io), C14 PT11B (io), D9 PT8A (io), D10 PT8B (io), D11 PT10A (io), D12 PT10B (io), E8 PT7A (io), E9 PT7B (io), E10 PT10C (io), E11 PT10D (io)
part C pins: B16 PR4C (io), C15 PR5A (io), C16 PR4D (io), D13 PR2B (io), D14 PR2A (io), D15 PR5B (io), D16 PR5C (io), E12 PR3B (io), E13 PR3A (io), E14 PR4A (io), E15 PR6A (io), E16 PR5D (io), F12 PR3D (io), F13 PR3C (io), F14 PR4B (io), F15 PR6B (io), F16 PR6C (io), G12 PR7A (io), G13 PR7B (io), G14 PR8A (io), G15 PR8C (io), G16 PR6D (io), H12 PR7C (io), H13 PR7D (io), H14 PR8B (io), H15 PR8D (io)
part D pins: H16 PR9A (io), J12 PR9C (io), J13 PR11A (io), J14 PR10C (io), J15 PR10A (io), J16 PR9B (io), K12 PR9D (io), K13 PR11B (io), K14 PR10D (io), K15 PR10B (io), K16 PR11C (io), L11 PR16A (io), L12 PR13C (io), L13 PR13D (io), L14 PR13A (io), L15 PR12A (io), L16 PR11D (io), M11 PR16B (io), M12 PR14C (io), M13 PR14D (io), M14 PR13B (io), M15 PR12B (io), M16 PR12C (io), N12 PR15B (io), N13 PR15A (io), N14 PR14B (io), N15 PR14A (io), N16 PR12D (io)
part E pins: M9 PB7F/PCLK4_0 (io), M10 PB7E (io), N8 PB7A (io), N9 PB7B/PCLK4_1 (io), N10 PB8E (io), N11 PB8F (io), P9 PB7C (io), P10 PB7D (io), P11 PB9C (io), P12 PB9D (io), P14 PB10F (io), P15 PB11C (io), P16 PB11D (io), R9 PB8A (io), R10 PB8B (io), R11 PB9A (io), R12 PB9B (io), R13 PB10A (io), R14 PB10B (io), R15 PB11A (io), R16 PB11B (io), T10 PB8C (io), T11 PB8D (io), T12 PB9F (io), T13 PB9E (io), T14 PB10C (io), T15 PB10D (io)
part F pins: M7 PB6A (io), M8 PB6B (io), N5 PB2C (io), N6 PB2D (io), P2 PB2A (io), P3 PB2B (io), P5 PB4A (io), P6 PB4B (io), P7 PB6E (io), P8 PB6F (io), R4 PB3C (io), R5 PB3D (io), R6 PB5A (io), R7 PB6C (io), R8 PB6D (io), T2 PB3A (io), T3 PB3B (io), T4 PB4D (io), T5 PB4C (io), T6 PB5B (io), T7 PB5D (io), T8 PB5C (io)
part G pins: H2 PL9A (io), J1 PL10A (io), J2 PL9B (io), J3 PL9C (io), J4 PL13A (io), J5 PL13B (io), K1 PL10B (io), K2 PL10C (io), K3 PL9D (io), K4 PL14B/LLM0_PLLC_FB_A (io), K5 PL14A/LLM0_PLLT_FB_A (io), L1 PL11A (io), L2 PL10D (io), L3 PL12A (io), L4 PL14D (io), L5 PL14C (io), M1 PL11B (io), M2 PL12C (io), M3 PL12B (io), M4 PL15B/LLM0_PLLC_IN_A (io), M5 PL15A/LLM0_PLLT_IN_A (io), N1 PL11C/TSALL (io), N2 PL12D (io), N3 PL16B (io), N4 PL16A (io), P1 PL11D (io), R1 PL13C (io), R2 PL13D (io)
part H pins: B1 PL5A (io), C1 PL5B (io), C2 PL4D (io), C3 PL4C (io), D1 PL5D (io), D2 PL5C (io), E1 PL6C (io), E2 PL4B (io), E3 PL4A (io), E4 PL2A (io), E5 PL2B (io), F1 PL6D (io), F2 PL6A (io), F3 PL3C (io), F4 PL3D (io), F5 PL3A (io), F6 PL3B (io), G1 PL8C (io), G2 PL6B/GSRN (io), G3 PL7C (io), G4 PL7A (io), G5 PL7B (io), H1 PL8D (io), H3 PL7D (io), H4 PL8A (io), H5 PL8B (io)
part I pins: M6 TDO (out) "Powered by VCCIO5", N7 TDI (in) "Powered by VCCIO5", P4 TMS (in) "Powered by VCCIO5", P13 SLEEPN (in) "Powered by VCCIO4", R3 TCK (in) "Powered by VCCIO5"
part J pins: A8 VCCAUX (power), F7 VCCIO0 (power), F8 VCCIO0 (power), F9 VCCIO1 (power), F10 VCCIO1 (power), G6 VCCIO7 (power), G7 VCC (power), G10 VCC (power), G11 VCCIO2 (power), H6 VCCIO7 (power), H11 VCCIO2 (power), J6 VCCIO6 (power), J11 VCCIO3 (power), K6 VCCIO6 (power), K7 VCC (power), K10 VCC (power), K11 VCCIO3 (power), L7 VCCIO5 (power), L8 VCCIO5 (power), L9 VCCIO4 (power), L10 VCCIO4 (power), T9 VCCAUX (power)
part K pins: A1 GND (power), A16 GND (power), F11 GND (power), G8 GND (power), G9 GND (power), H7 GND (power), H8 GND (power), H9 GND (power), H10 GND (power), J7 GND (power), J8 GND (power), J9 GND (power), J10 GND (power), K8 GND (power), K9 GND (power), L6 GND (power), T1 GND (power), T16 GND (power)


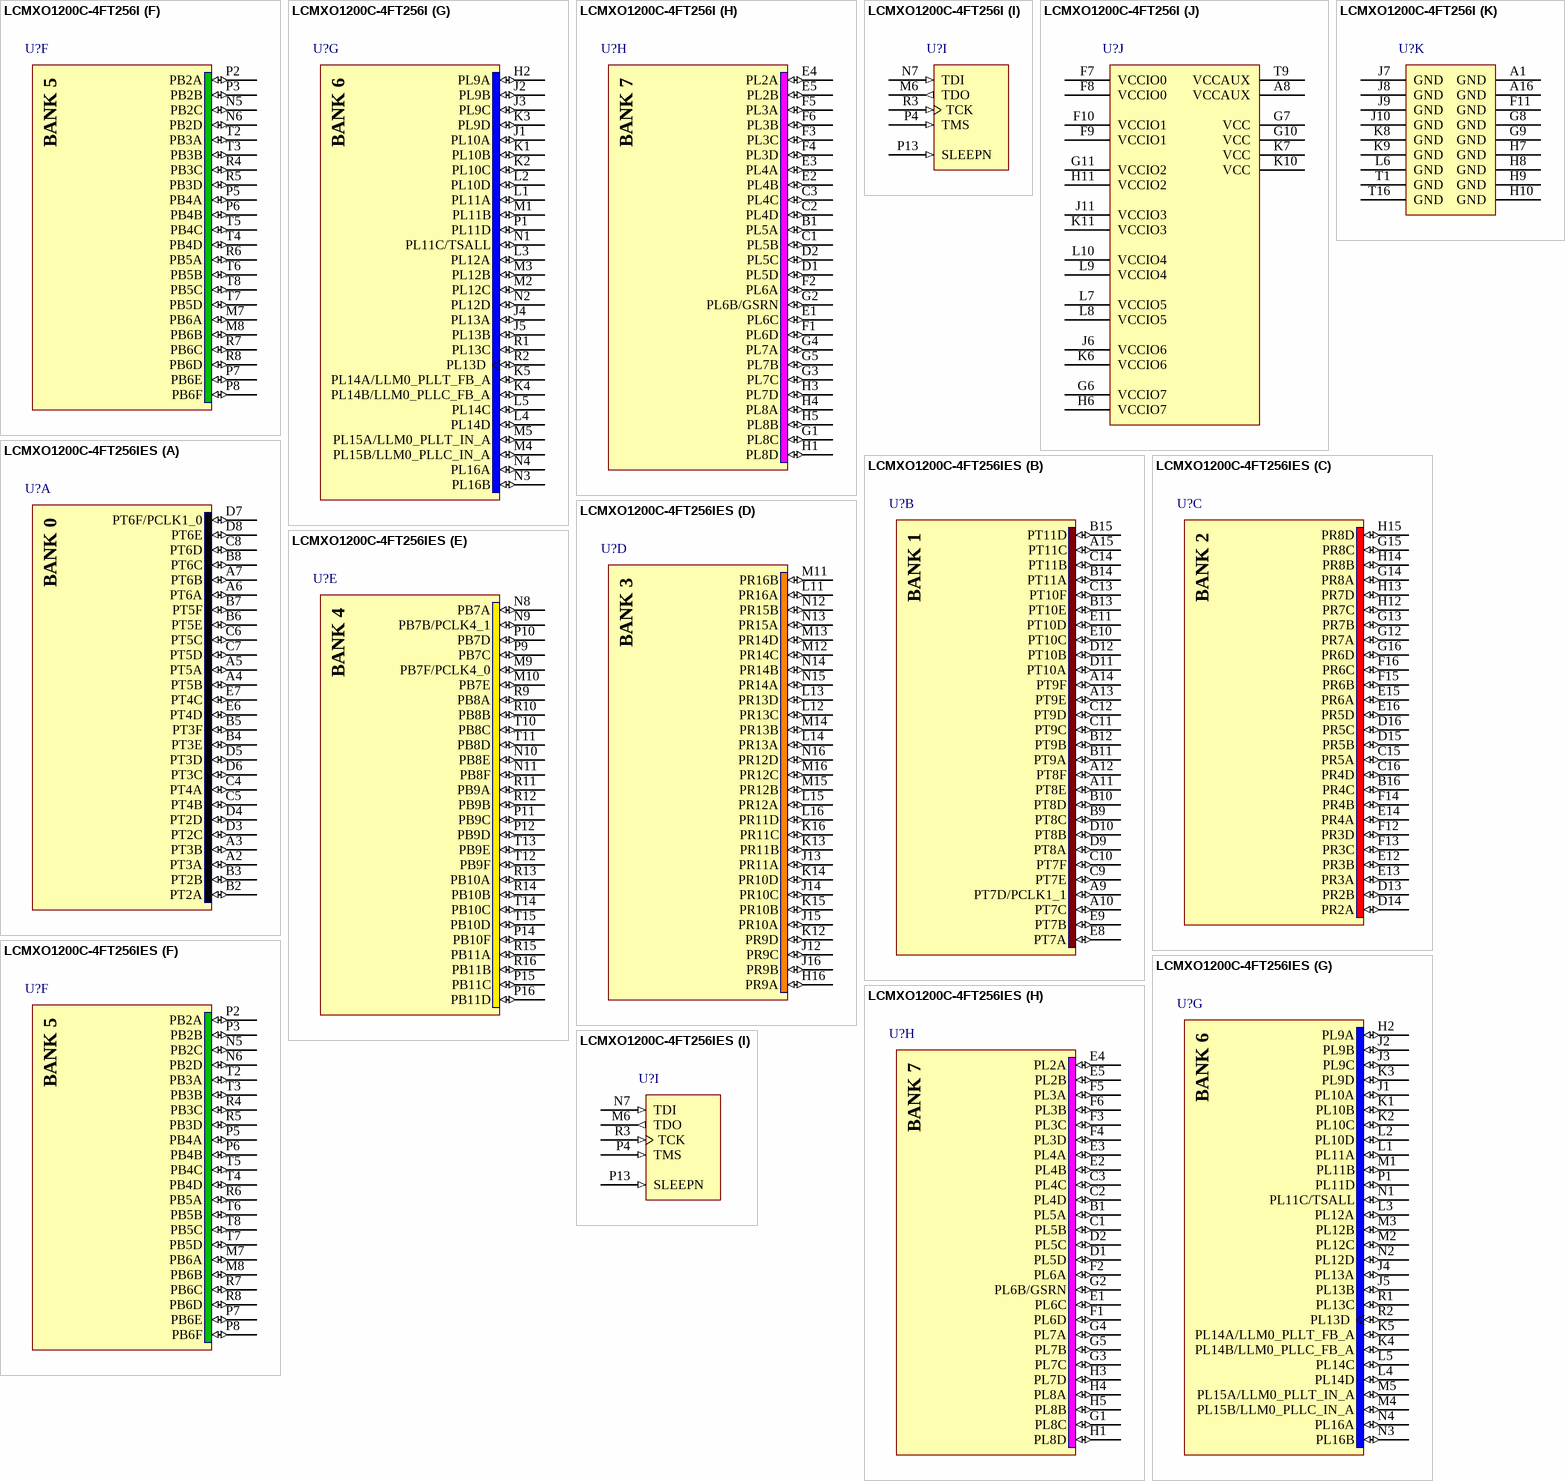
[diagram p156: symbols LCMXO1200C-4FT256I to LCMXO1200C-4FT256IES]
## LCMXO1200C-4FT256I
designator U?
MachXO 1200 Crossover PLD, 1.8V/2.5V/3.3V, 211 User I/Os, 256-Pins ftBGA, Speed Grade-4, Industrial Grade
footprint ftBGA256 (BGA, 256-Leads, Body 17x17mm, Pitch 1mm)
3D model MachXO1200-ftBGA256 (256-Ball Fine Thin Ball Grid Array (ftBGA256))
signal-integrity model LCMXO1200C_FT256 (MachXO)
part A pins: A2 PT3A (io), A3 PT3B (io), A4 PT5B (io), A5 PT5A (io), A6 PT6A (io), A7 PT6B (io), B2 PT2A (io), B3 PT2B (io), B4 PT3E (io), B5 PT3F (io), B6 PT5E (io), B7 PT5F (io), B8 PT6C (io), C4 PT4A (io), C5 PT4B (io), C6 PT5C (io), C7 PT5D (io), C8 PT6D (io), D3 PT2C (io), D4 PT2D (io), D5 PT3D (io), D6 PT3C (io), D7 PT6F/PCLK1_0 (io), D8 PT6E (io), E6 PT4D (io), E7 PT4C (io)
part B pins: A9 PT7D/PCLK1_1 (io), A10 PT7C (io), A11 PT8E (io), A12 PT8F (io), A13 PT9E (io), A14 PT9F (io), A15 PT11C (io), B9 PT8C (io), B10 PT8D (io), B11 PT9A (io), B12 PT9B (io), B13 PT10E (io), B14 PT11A (io), B15 PT11D (io), C9 PT7E (io), C10 PT7F (io), C11 PT9C (io), C12 PT9D (io), C13 PT10F (io), C14 PT11B (io), D9 PT8A (io), D10 PT8B (io), D11 PT10A (io), D12 PT10B (io), E8 PT7A (io), E9 PT7B (io), E10 PT10C (io), E11 PT10D (io)
part C pins: B16 PR4C (io), C15 PR5A (io), C16 PR4D (io), D13 PR2B (io), D14 PR2A (io), D15 PR5B (io), D16 PR5C (io), E12 PR3B (io), E13 PR3A (io), E14 PR4A (io), E15 PR6A (io), E16 PR5D (io), F12 PR3D (io), F13 PR3C (io), F14 PR4B (io), F15 PR6B (io), F16 PR6C (io), G12 PR7A (io), G13 PR7B (io), G14 PR8A (io), G15 PR8C (io), G16 PR6D (io), H12 PR7C (io), H13 PR7D (io), H14 PR8B (io), H15 PR8D (io)
part D pins: H16 PR9A (io), J12 PR9C (io), J13 PR11A (io), J14 PR10C (io), J15 PR10A (io), J16 PR9B (io), K12 PR9D (io), K13 PR11B (io), K14 PR10D (io), K15 PR10B (io), K16 PR11C (io), L11 PR16A (io), L12 PR13C (io), L13 PR13D (io), L14 PR13A (io), L15 PR12A (io), L16 PR11D (io), M11 PR16B (io), M12 PR14C (io), M13 PR14D (io), M14 PR13B (io), M15 PR12B (io), M16 PR12C (io), N12 PR15B (io), N13 PR15A (io), N14 PR14B (io), N15 PR14A (io), N16 PR12D (io)
part E pins: M9 PB7F/PCLK4_0 (io), M10 PB7E (io), N8 PB7A (io), N9 PB7B/PCLK4_1 (io), N10 PB8E (io), N11 PB8F (io), P9 PB7C (io), P10 PB7D (io), P11 PB9C (io), P12 PB9D (io), P14 PB10F (io), P15 PB11C (io), P16 PB11D (io), R9 PB8A (io), R10 PB8B (io), R11 PB9A (io), R12 PB9B (io), R13 PB10A (io), R14 PB10B (io), R15 PB11A (io), R16 PB11B (io), T10 PB8C (io), T11 PB8D (io), T12 PB9F (io), T13 PB9E (io), T14 PB10C (io), T15 PB10D (io)
part F pins: M7 PB6A (io), M8 PB6B (io), N5 PB2C (io), N6 PB2D (io), P2 PB2A (io), P3 PB2B (io), P5 PB4A (io), P6 PB4B (io), P7 PB6E (io), P8 PB6F (io), R4 PB3C (io), R5 PB3D (io), R6 PB5A (io), R7 PB6C (io), R8 PB6D (io), T2 PB3A (io), T3 PB3B (io), T4 PB4D (io), T5 PB4C (io), T6 PB5B (io), T7 PB5D (io), T8 PB5C (io)
part G pins: H2 PL9A (io), J1 PL10A (io), J2 PL9B (io), J3 PL9C (io), J4 PL13A (io), J5 PL13B (io), K1 PL10B (io), K2 PL10C (io), K3 PL9D (io), K4 PL14B/LLM0_PLLC_FB_A (io), K5 PL14A/LLM0_PLLT_FB_A (io), L1 PL11A (io), L2 PL10D (io), L3 PL12A (io), L4 PL14D (io), L5 PL14C (io), M1 PL11B (io), M2 PL12C (io), M3 PL12B (io), M4 PL15B/LLM0_PLLC_IN_A (io), M5 PL15A/LLM0_PLLT_IN_A (io), N1 PL11C/TSALL (io), N2 PL12D (io), N3 PL16B (io), N4 PL16A (io), P1 PL11D (io), R1 PL13C (io), R2 PL13D (io)
part H pins: B1 PL5A (io), C1 PL5B (io), C2 PL4D (io), C3 PL4C (io), D1 PL5D (io), D2 PL5C (io), E1 PL6C (io), E2 PL4B (io), E3 PL4A (io), E4 PL2A (io), E5 PL2B (io), F1 PL6D (io), F2 PL6A (io), F3 PL3C (io), F4 PL3D (io), F5 PL3A (io), F6 PL3B (io), G1 PL8C (io), G2 PL6B/GSRN (io), G3 PL7C (io), G4 PL7A (io), G5 PL7B (io), H1 PL8D (io), H3 PL7D (io), H4 PL8A (io), H5 PL8B (io)
part I pins: M6 TDO (out) "Powered by VCCIO5", N7 TDI (in) "Powered by VCCIO5", P4 TMS (in) "Powered by VCCIO5", P13 SLEEPN (in) "Powered by VCCIO4", R3 TCK (in) "Powered by VCCIO5"
part J pins: A8 VCCAUX (power), F7 VCCIO0 (power), F8 VCCIO0 (power), F9 VCCIO1 (power), F10 VCCIO1 (power), G6 VCCIO7 (power), G7 VCC (power), G10 VCC (power), G11 VCCIO2 (power), H6 VCCIO7 (power), H11 VCCIO2 (power), J6 VCCIO6 (power), J11 VCCIO3 (power), K6 VCCIO6 (power), K7 VCC (power), K10 VCC (power), K11 VCCIO3 (power), L7 VCCIO5 (power), L8 VCCIO5 (power), L9 VCCIO4 (power), L10 VCCIO4 (power), T9 VCCAUX (power)
part K pins: A1 GND (power), A16 GND (power), F11 GND (power), G8 GND (power), G9 GND (power), H7 GND (power), H8 GND (power), H9 GND (power), H10 GND (power), J7 GND (power), J8 GND (power), J9 GND (power), J10 GND (power), K8 GND (power), K9 GND (power), L6 GND (power), T1 GND (power), T16 GND (power)


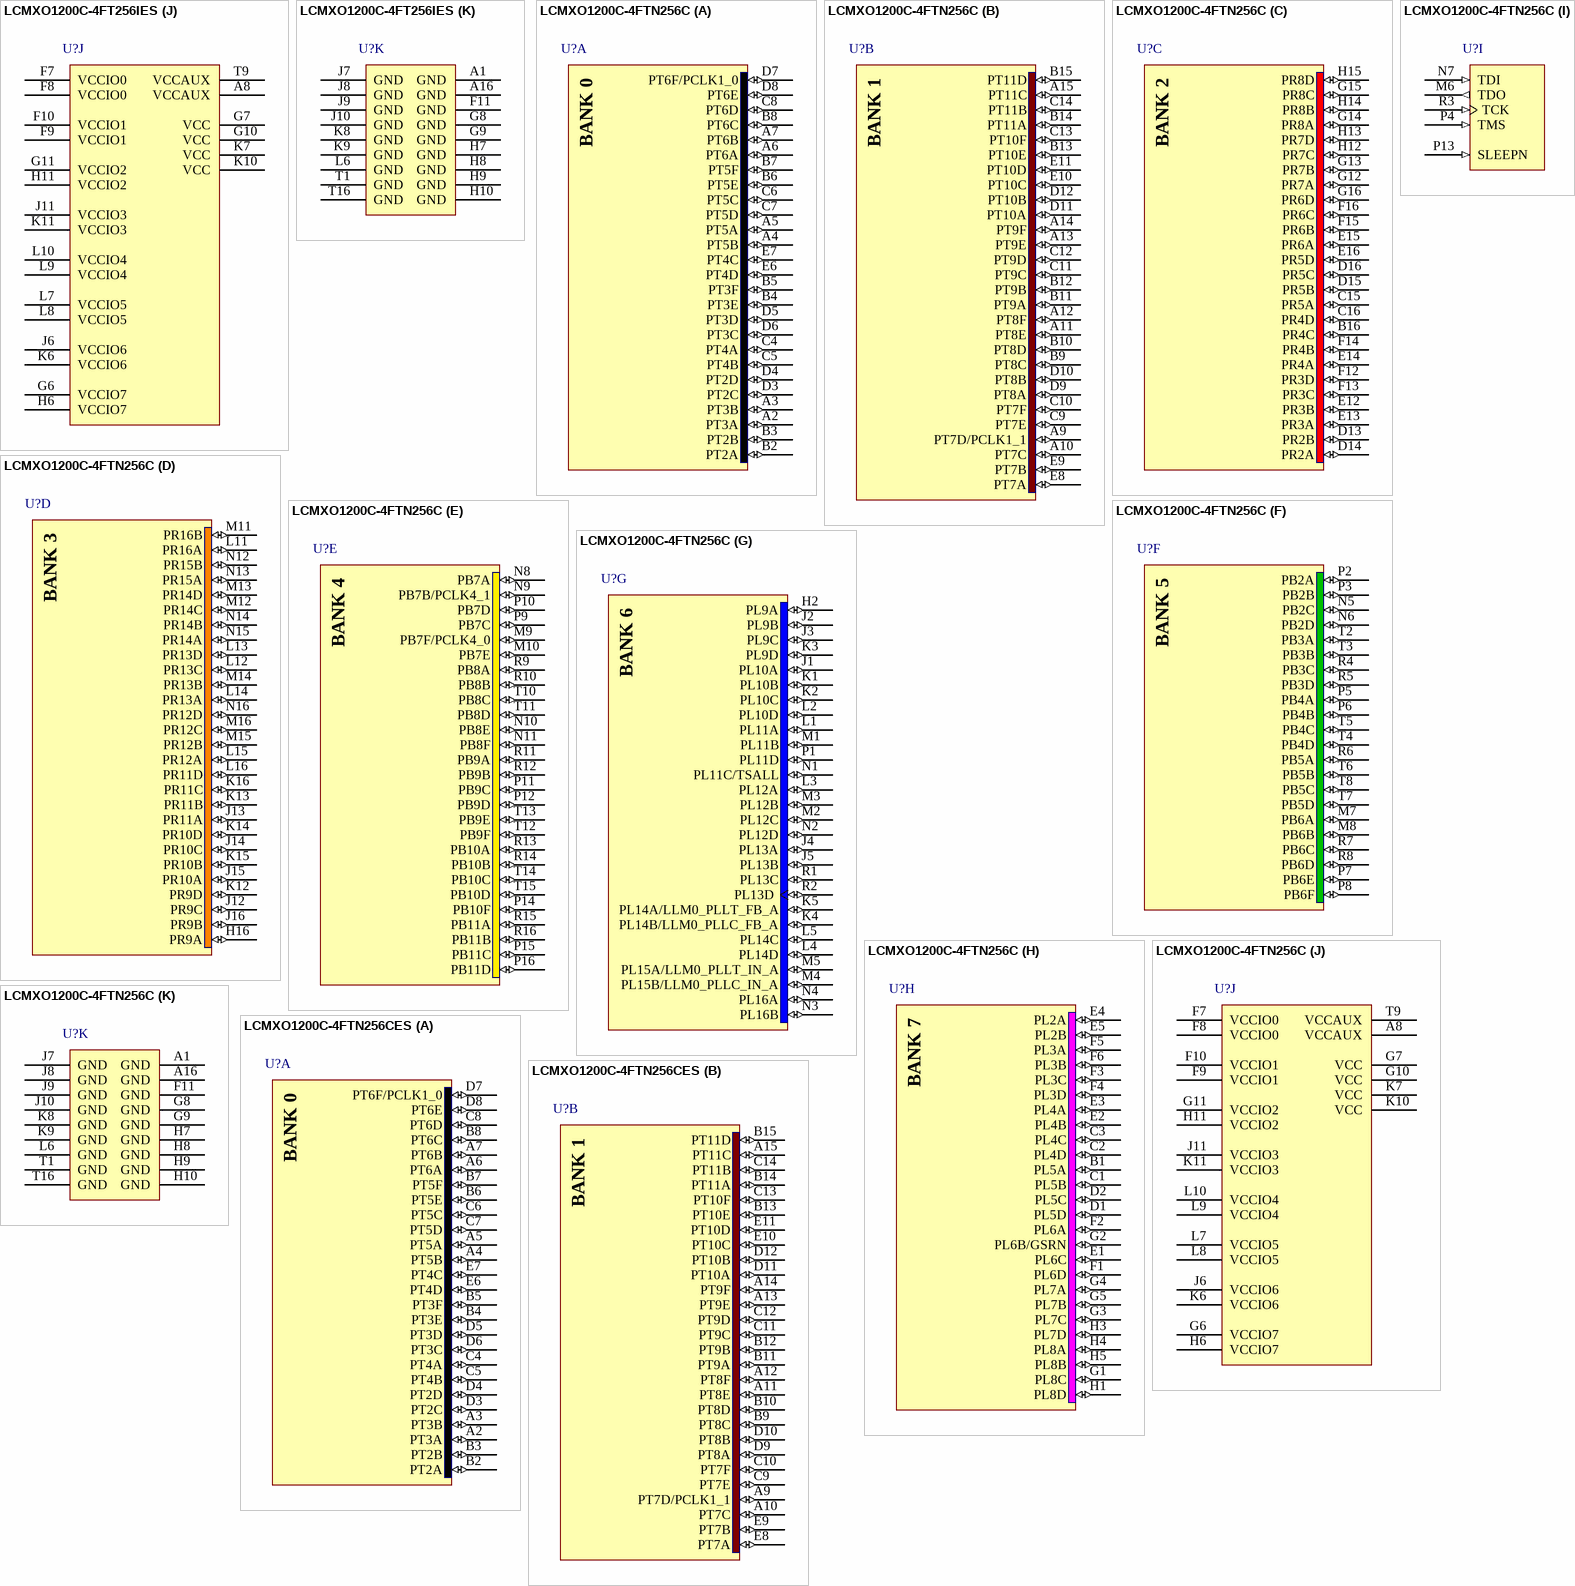
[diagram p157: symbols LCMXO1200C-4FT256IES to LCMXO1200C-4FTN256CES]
## LCMXO1200C-4FT256IES
designator U?
MachXO 1200 Crossover PLD, 1.8V/2.5V/3.3V, 211 User I/Os, 256-Pins ftBGA, Speed Grade-4, Industrial Grade, Engineering Sample
footprint ftBGA256 (BGA, 256-Leads, Body 17x17mm, Pitch 1mm)
3D model MachXO1200-ftBGA256 (256-Ball Fine Thin Ball Grid Array (ftBGA256))
signal-integrity model LCMXO1200C_FT256 (MachXO)
part A pins: A2 PT3A (io), A3 PT3B (io), A4 PT5B (io), A5 PT5A (io), A6 PT6A (io), A7 PT6B (io), B2 PT2A (io), B3 PT2B (io), B4 PT3E (io), B5 PT3F (io), B6 PT5E (io), B7 PT5F (io), B8 PT6C (io), C4 PT4A (io), C5 PT4B (io), C6 PT5C (io), C7 PT5D (io), C8 PT6D (io), D3 PT2C (io), D4 PT2D (io), D5 PT3D (io), D6 PT3C (io), D7 PT6F/PCLK1_0 (io), D8 PT6E (io), E6 PT4D (io), E7 PT4C (io)
part B pins: A9 PT7D/PCLK1_1 (io), A10 PT7C (io), A11 PT8E (io), A12 PT8F (io), A13 PT9E (io), A14 PT9F (io), A15 PT11C (io), B9 PT8C (io), B10 PT8D (io), B11 PT9A (io), B12 PT9B (io), B13 PT10E (io), B14 PT11A (io), B15 PT11D (io), C9 PT7E (io), C10 PT7F (io), C11 PT9C (io), C12 PT9D (io), C13 PT10F (io), C14 PT11B (io), D9 PT8A (io), D10 PT8B (io), D11 PT10A (io), D12 PT10B (io), E8 PT7A (io), E9 PT7B (io), E10 PT10C (io), E11 PT10D (io)
part C pins: B16 PR4C (io), C15 PR5A (io), C16 PR4D (io), D13 PR2B (io), D14 PR2A (io), D15 PR5B (io), D16 PR5C (io), E12 PR3B (io), E13 PR3A (io), E14 PR4A (io), E15 PR6A (io), E16 PR5D (io), F12 PR3D (io), F13 PR3C (io), F14 PR4B (io), F15 PR6B (io), F16 PR6C (io), G12 PR7A (io), G13 PR7B (io), G14 PR8A (io), G15 PR8C (io), G16 PR6D (io), H12 PR7C (io), H13 PR7D (io), H14 PR8B (io), H15 PR8D (io)
part D pins: H16 PR9A (io), J12 PR9C (io), J13 PR11A (io), J14 PR10C (io), J15 PR10A (io), J16 PR9B (io), K12 PR9D (io), K13 PR11B (io), K14 PR10D (io), K15 PR10B (io), K16 PR11C (io), L11 PR16A (io), L12 PR13C (io), L13 PR13D (io), L14 PR13A (io), L15 PR12A (io), L16 PR11D (io), M11 PR16B (io), M12 PR14C (io), M13 PR14D (io), M14 PR13B (io), M15 PR12B (io), M16 PR12C (io), N12 PR15B (io), N13 PR15A (io), N14 PR14B (io), N15 PR14A (io), N16 PR12D (io)
part E pins: M9 PB7F/PCLK4_0 (io), M10 PB7E (io), N8 PB7A (io), N9 PB7B/PCLK4_1 (io), N10 PB8E (io), N11 PB8F (io), P9 PB7C (io), P10 PB7D (io), P11 PB9C (io), P12 PB9D (io), P14 PB10F (io), P15 PB11C (io), P16 PB11D (io), R9 PB8A (io), R10 PB8B (io), R11 PB9A (io), R12 PB9B (io), R13 PB10A (io), R14 PB10B (io), R15 PB11A (io), R16 PB11B (io), T10 PB8C (io), T11 PB8D (io), T12 PB9F (io), T13 PB9E (io), T14 PB10C (io), T15 PB10D (io)
part F pins: M7 PB6A (io), M8 PB6B (io), N5 PB2C (io), N6 PB2D (io), P2 PB2A (io), P3 PB2B (io), P5 PB4A (io), P6 PB4B (io), P7 PB6E (io), P8 PB6F (io), R4 PB3C (io), R5 PB3D (io), R6 PB5A (io), R7 PB6C (io), R8 PB6D (io), T2 PB3A (io), T3 PB3B (io), T4 PB4D (io), T5 PB4C (io), T6 PB5B (io), T7 PB5D (io), T8 PB5C (io)
part G pins: H2 PL9A (io), J1 PL10A (io), J2 PL9B (io), J3 PL9C (io), J4 PL13A (io), J5 PL13B (io), K1 PL10B (io), K2 PL10C (io), K3 PL9D (io), K4 PL14B/LLM0_PLLC_FB_A (io), K5 PL14A/LLM0_PLLT_FB_A (io), L1 PL11A (io), L2 PL10D (io), L3 PL12A (io), L4 PL14D (io), L5 PL14C (io), M1 PL11B (io), M2 PL12C (io), M3 PL12B (io), M4 PL15B/LLM0_PLLC_IN_A (io), M5 PL15A/LLM0_PLLT_IN_A (io), N1 PL11C/TSALL (io), N2 PL12D (io), N3 PL16B (io), N4 PL16A (io), P1 PL11D (io), R1 PL13C (io), R2 PL13D (io)
part H pins: B1 PL5A (io), C1 PL5B (io), C2 PL4D (io), C3 PL4C (io), D1 PL5D (io), D2 PL5C (io), E1 PL6C (io), E2 PL4B (io), E3 PL4A (io), E4 PL2A (io), E5 PL2B (io), F1 PL6D (io), F2 PL6A (io), F3 PL3C (io), F4 PL3D (io), F5 PL3A (io), F6 PL3B (io), G1 PL8C (io), G2 PL6B/GSRN (io), G3 PL7C (io), G4 PL7A (io), G5 PL7B (io), H1 PL8D (io), H3 PL7D (io), H4 PL8A (io), H5 PL8B (io)
part I pins: M6 TDO (out) "Powered by VCCIO5", N7 TDI (in) "Powered by VCCIO5", P4 TMS (in) "Powered by VCCIO5", P13 SLEEPN (in) "Powered by VCCIO4", R3 TCK (in) "Powered by VCCIO5"
part J pins: A8 VCCAUX (power), F7 VCCIO0 (power), F8 VCCIO0 (power), F9 VCCIO1 (power), F10 VCCIO1 (power), G6 VCCIO7 (power), G7 VCC (power), G10 VCC (power), G11 VCCIO2 (power), H6 VCCIO7 (power), H11 VCCIO2 (power), J6 VCCIO6 (power), J11 VCCIO3 (power), K6 VCCIO6 (power), K7 VCC (power), K10 VCC (power), K11 VCCIO3 (power), L7 VCCIO5 (power), L8 VCCIO5 (power), L9 VCCIO4 (power), L10 VCCIO4 (power), T9 VCCAUX (power)
part K pins: A1 GND (power), A16 GND (power), F11 GND (power), G8 GND (power), G9 GND (power), H7 GND (power), H8 GND (power), H9 GND (power), H10 GND (power), J7 GND (power), J8 GND (power), J9 GND (power), J10 GND (power), K8 GND (power), K9 GND (power), L6 GND (power), T1 GND (power), T16 GND (power)

## LCMXO1200C-4FTN256C
designator U?
MachXO 1200 Crossover PLD, 1.8V/2.5V/3.3V, 211 User I/Os, 256-Pins ftBGA, Speed Grade-4, Commercial Grade, Pb-Free
footprint ftBGA256 (BGA, 256-Leads, Body 17x17mm, Pitch 1mm)
3D model MachXO1200-ftBGA256 (256-Ball Fine Thin Ball Grid Array (ftBGA256))
signal-integrity model LCMXO1200C_FT256 (MachXO)
part A pins: A2 PT3A (io), A3 PT3B (io), A4 PT5B (io), A5 PT5A (io), A6 PT6A (io), A7 PT6B (io), B2 PT2A (io), B3 PT2B (io), B4 PT3E (io), B5 PT3F (io), B6 PT5E (io), B7 PT5F (io), B8 PT6C (io), C4 PT4A (io), C5 PT4B (io), C6 PT5C (io), C7 PT5D (io), C8 PT6D (io), D3 PT2C (io), D4 PT2D (io), D5 PT3D (io), D6 PT3C (io), D7 PT6F/PCLK1_0 (io), D8 PT6E (io), E6 PT4D (io), E7 PT4C (io)
part B pins: A9 PT7D/PCLK1_1 (io), A10 PT7C (io), A11 PT8E (io), A12 PT8F (io), A13 PT9E (io), A14 PT9F (io), A15 PT11C (io), B9 PT8C (io), B10 PT8D (io), B11 PT9A (io), B12 PT9B (io), B13 PT10E (io), B14 PT11A (io), B15 PT11D (io), C9 PT7E (io), C10 PT7F (io), C11 PT9C (io), C12 PT9D (io), C13 PT10F (io), C14 PT11B (io), D9 PT8A (io), D10 PT8B (io), D11 PT10A (io), D12 PT10B (io), E8 PT7A (io), E9 PT7B (io), E10 PT10C (io), E11 PT10D (io)
part C pins: B16 PR4C (io), C15 PR5A (io), C16 PR4D (io), D13 PR2B (io), D14 PR2A (io), D15 PR5B (io), D16 PR5C (io), E12 PR3B (io), E13 PR3A (io), E14 PR4A (io), E15 PR6A (io), E16 PR5D (io), F12 PR3D (io), F13 PR3C (io), F14 PR4B (io), F15 PR6B (io), F16 PR6C (io), G12 PR7A (io), G13 PR7B (io), G14 PR8A (io), G15 PR8C (io), G16 PR6D (io), H12 PR7C (io), H13 PR7D (io), H14 PR8B (io), H15 PR8D (io)
part D pins: H16 PR9A (io), J12 PR9C (io), J13 PR11A (io), J14 PR10C (io), J15 PR10A (io), J16 PR9B (io), K12 PR9D (io), K13 PR11B (io), K14 PR10D (io), K15 PR10B (io), K16 PR11C (io), L11 PR16A (io), L12 PR13C (io), L13 PR13D (io), L14 PR13A (io), L15 PR12A (io), L16 PR11D (io), M11 PR16B (io), M12 PR14C (io), M13 PR14D (io), M14 PR13B (io), M15 PR12B (io), M16 PR12C (io), N12 PR15B (io), N13 PR15A (io), N14 PR14B (io), N15 PR14A (io), N16 PR12D (io)
part E pins: M9 PB7F/PCLK4_0 (io), M10 PB7E (io), N8 PB7A (io), N9 PB7B/PCLK4_1 (io), N10 PB8E (io), N11 PB8F (io), P9 PB7C (io), P10 PB7D (io), P11 PB9C (io), P12 PB9D (io), P14 PB10F (io), P15 PB11C (io), P16 PB11D (io), R9 PB8A (io), R10 PB8B (io), R11 PB9A (io), R12 PB9B (io), R13 PB10A (io), R14 PB10B (io), R15 PB11A (io), R16 PB11B (io), T10 PB8C (io), T11 PB8D (io), T12 PB9F (io), T13 PB9E (io), T14 PB10C (io), T15 PB10D (io)
part F pins: M7 PB6A (io), M8 PB6B (io), N5 PB2C (io), N6 PB2D (io), P2 PB2A (io), P3 PB2B (io), P5 PB4A (io), P6 PB4B (io), P7 PB6E (io), P8 PB6F (io), R4 PB3C (io), R5 PB3D (io), R6 PB5A (io), R7 PB6C (io), R8 PB6D (io), T2 PB3A (io), T3 PB3B (io), T4 PB4D (io), T5 PB4C (io), T6 PB5B (io), T7 PB5D (io), T8 PB5C (io)
part G pins: H2 PL9A (io), J1 PL10A (io), J2 PL9B (io), J3 PL9C (io), J4 PL13A (io), J5 PL13B (io), K1 PL10B (io), K2 PL10C (io), K3 PL9D (io), K4 PL14B/LLM0_PLLC_FB_A (io), K5 PL14A/LLM0_PLLT_FB_A (io), L1 PL11A (io), L2 PL10D (io), L3 PL12A (io), L4 PL14D (io), L5 PL14C (io), M1 PL11B (io), M2 PL12C (io), M3 PL12B (io), M4 PL15B/LLM0_PLLC_IN_A (io), M5 PL15A/LLM0_PLLT_IN_A (io), N1 PL11C/TSALL (io), N2 PL12D (io), N3 PL16B (io), N4 PL16A (io), P1 PL11D (io), R1 PL13C (io), R2 PL13D (io)
part H pins: B1 PL5A (io), C1 PL5B (io), C2 PL4D (io), C3 PL4C (io), D1 PL5D (io), D2 PL5C (io), E1 PL6C (io), E2 PL4B (io), E3 PL4A (io), E4 PL2A (io), E5 PL2B (io), F1 PL6D (io), F2 PL6A (io), F3 PL3C (io), F4 PL3D (io), F5 PL3A (io), F6 PL3B (io), G1 PL8C (io), G2 PL6B/GSRN (io), G3 PL7C (io), G4 PL7A (io), G5 PL7B (io), H1 PL8D (io), H3 PL7D (io), H4 PL8A (io), H5 PL8B (io)
part I pins: M6 TDO (out) "Powered by VCCIO5", N7 TDI (in) "Powered by VCCIO5", P4 TMS (in) "Powered by VCCIO5", P13 SLEEPN (in) "Powered by VCCIO4", R3 TCK (in) "Powered by VCCIO5"
part J pins: A8 VCCAUX (power), F7 VCCIO0 (power), F8 VCCIO0 (power), F9 VCCIO1 (power), F10 VCCIO1 (power), G6 VCCIO7 (power), G7 VCC (power), G10 VCC (power), G11 VCCIO2 (power), H6 VCCIO7 (power), H11 VCCIO2 (power), J6 VCCIO6 (power), J11 VCCIO3 (power), K6 VCCIO6 (power), K7 VCC (power), K10 VCC (power), K11 VCCIO3 (power), L7 VCCIO5 (power), L8 VCCIO5 (power), L9 VCCIO4 (power), L10 VCCIO4 (power), T9 VCCAUX (power)
part K pins: A1 GND (power), A16 GND (power), F11 GND (power), G8 GND (power), G9 GND (power), H7 GND (power), H8 GND (power), H9 GND (power), H10 GND (power), J7 GND (power), J8 GND (power), J9 GND (power), J10 GND (power), K8 GND (power), K9 GND (power), L6 GND (power), T1 GND (power), T16 GND (power)


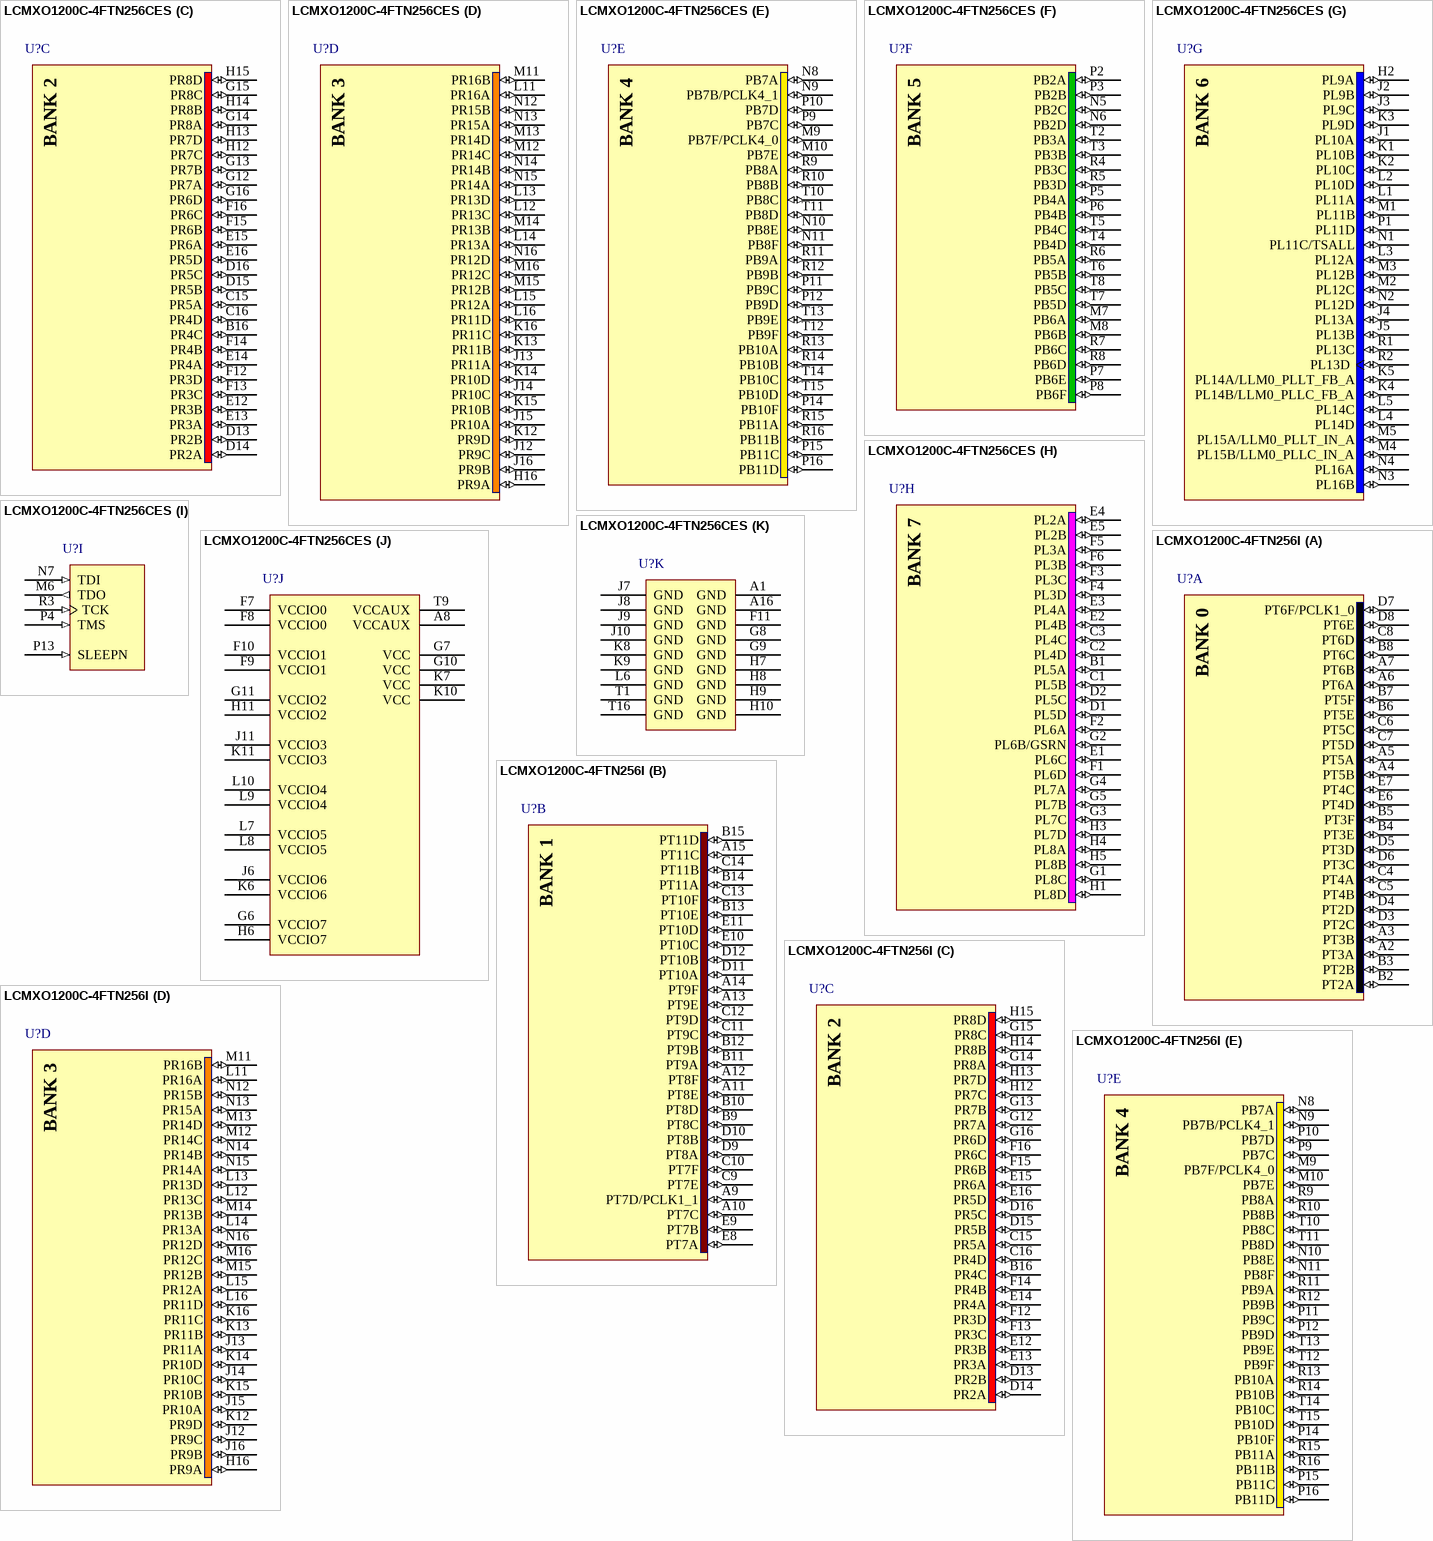
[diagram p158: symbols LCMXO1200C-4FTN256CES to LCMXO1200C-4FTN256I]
## LCMXO1200C-4FTN256CES
designator U?
MachXO 1200 Crossover PLD, 1.8V/2.5V/3.3V, 211 User I/Os, 256-Pins ftBGA, Speed Grade-4, Commercial Grade, Pb-Free, Engineering Sample
footprint ftBGA256 (BGA, 256-Leads, Body 17x17mm, Pitch 1mm)
3D model MachXO1200-ftBGA256 (256-Ball Fine Thin Ball Grid Array (ftBGA256))
signal-integrity model LCMXO1200C_FT256 (MachXO)
part A pins: A2 PT3A (io), A3 PT3B (io), A4 PT5B (io), A5 PT5A (io), A6 PT6A (io), A7 PT6B (io), B2 PT2A (io), B3 PT2B (io), B4 PT3E (io), B5 PT3F (io), B6 PT5E (io), B7 PT5F (io), B8 PT6C (io), C4 PT4A (io), C5 PT4B (io), C6 PT5C (io), C7 PT5D (io), C8 PT6D (io), D3 PT2C (io), D4 PT2D (io), D5 PT3D (io), D6 PT3C (io), D7 PT6F/PCLK1_0 (io), D8 PT6E (io), E6 PT4D (io), E7 PT4C (io)
part B pins: A9 PT7D/PCLK1_1 (io), A10 PT7C (io), A11 PT8E (io), A12 PT8F (io), A13 PT9E (io), A14 PT9F (io), A15 PT11C (io), B9 PT8C (io), B10 PT8D (io), B11 PT9A (io), B12 PT9B (io), B13 PT10E (io), B14 PT11A (io), B15 PT11D (io), C9 PT7E (io), C10 PT7F (io), C11 PT9C (io), C12 PT9D (io), C13 PT10F (io), C14 PT11B (io), D9 PT8A (io), D10 PT8B (io), D11 PT10A (io), D12 PT10B (io), E8 PT7A (io), E9 PT7B (io), E10 PT10C (io), E11 PT10D (io)
part C pins: B16 PR4C (io), C15 PR5A (io), C16 PR4D (io), D13 PR2B (io), D14 PR2A (io), D15 PR5B (io), D16 PR5C (io), E12 PR3B (io), E13 PR3A (io), E14 PR4A (io), E15 PR6A (io), E16 PR5D (io), F12 PR3D (io), F13 PR3C (io), F14 PR4B (io), F15 PR6B (io), F16 PR6C (io), G12 PR7A (io), G13 PR7B (io), G14 PR8A (io), G15 PR8C (io), G16 PR6D (io), H12 PR7C (io), H13 PR7D (io), H14 PR8B (io), H15 PR8D (io)
part D pins: H16 PR9A (io), J12 PR9C (io), J13 PR11A (io), J14 PR10C (io), J15 PR10A (io), J16 PR9B (io), K12 PR9D (io), K13 PR11B (io), K14 PR10D (io), K15 PR10B (io), K16 PR11C (io), L11 PR16A (io), L12 PR13C (io), L13 PR13D (io), L14 PR13A (io), L15 PR12A (io), L16 PR11D (io), M11 PR16B (io), M12 PR14C (io), M13 PR14D (io), M14 PR13B (io), M15 PR12B (io), M16 PR12C (io), N12 PR15B (io), N13 PR15A (io), N14 PR14B (io), N15 PR14A (io), N16 PR12D (io)
part E pins: M9 PB7F/PCLK4_0 (io), M10 PB7E (io), N8 PB7A (io), N9 PB7B/PCLK4_1 (io), N10 PB8E (io), N11 PB8F (io), P9 PB7C (io), P10 PB7D (io), P11 PB9C (io), P12 PB9D (io), P14 PB10F (io), P15 PB11C (io), P16 PB11D (io), R9 PB8A (io), R10 PB8B (io), R11 PB9A (io), R12 PB9B (io), R13 PB10A (io), R14 PB10B (io), R15 PB11A (io), R16 PB11B (io), T10 PB8C (io), T11 PB8D (io), T12 PB9F (io), T13 PB9E (io), T14 PB10C (io), T15 PB10D (io)
part F pins: M7 PB6A (io), M8 PB6B (io), N5 PB2C (io), N6 PB2D (io), P2 PB2A (io), P3 PB2B (io), P5 PB4A (io), P6 PB4B (io), P7 PB6E (io), P8 PB6F (io), R4 PB3C (io), R5 PB3D (io), R6 PB5A (io), R7 PB6C (io), R8 PB6D (io), T2 PB3A (io), T3 PB3B (io), T4 PB4D (io), T5 PB4C (io), T6 PB5B (io), T7 PB5D (io), T8 PB5C (io)
part G pins: H2 PL9A (io), J1 PL10A (io), J2 PL9B (io), J3 PL9C (io), J4 PL13A (io), J5 PL13B (io), K1 PL10B (io), K2 PL10C (io), K3 PL9D (io), K4 PL14B/LLM0_PLLC_FB_A (io), K5 PL14A/LLM0_PLLT_FB_A (io), L1 PL11A (io), L2 PL10D (io), L3 PL12A (io), L4 PL14D (io), L5 PL14C (io), M1 PL11B (io), M2 PL12C (io), M3 PL12B (io), M4 PL15B/LLM0_PLLC_IN_A (io), M5 PL15A/LLM0_PLLT_IN_A (io), N1 PL11C/TSALL (io), N2 PL12D (io), N3 PL16B (io), N4 PL16A (io), P1 PL11D (io), R1 PL13C (io), R2 PL13D (io)
part H pins: B1 PL5A (io), C1 PL5B (io), C2 PL4D (io), C3 PL4C (io), D1 PL5D (io), D2 PL5C (io), E1 PL6C (io), E2 PL4B (io), E3 PL4A (io), E4 PL2A (io), E5 PL2B (io), F1 PL6D (io), F2 PL6A (io), F3 PL3C (io), F4 PL3D (io), F5 PL3A (io), F6 PL3B (io), G1 PL8C (io), G2 PL6B/GSRN (io), G3 PL7C (io), G4 PL7A (io), G5 PL7B (io), H1 PL8D (io), H3 PL7D (io), H4 PL8A (io), H5 PL8B (io)
part I pins: M6 TDO (out) "Powered by VCCIO5", N7 TDI (in) "Powered by VCCIO5", P4 TMS (in) "Powered by VCCIO5", P13 SLEEPN (in) "Powered by VCCIO4", R3 TCK (in) "Powered by VCCIO5"
part J pins: A8 VCCAUX (power), F7 VCCIO0 (power), F8 VCCIO0 (power), F9 VCCIO1 (power), F10 VCCIO1 (power), G6 VCCIO7 (power), G7 VCC (power), G10 VCC (power), G11 VCCIO2 (power), H6 VCCIO7 (power), H11 VCCIO2 (power), J6 VCCIO6 (power), J11 VCCIO3 (power), K6 VCCIO6 (power), K7 VCC (power), K10 VCC (power), K11 VCCIO3 (power), L7 VCCIO5 (power), L8 VCCIO5 (power), L9 VCCIO4 (power), L10 VCCIO4 (power), T9 VCCAUX (power)
part K pins: A1 GND (power), A16 GND (power), F11 GND (power), G8 GND (power), G9 GND (power), H7 GND (power), H8 GND (power), H9 GND (power), H10 GND (power), J7 GND (power), J8 GND (power), J9 GND (power), J10 GND (power), K8 GND (power), K9 GND (power), L6 GND (power), T1 GND (power), T16 GND (power)


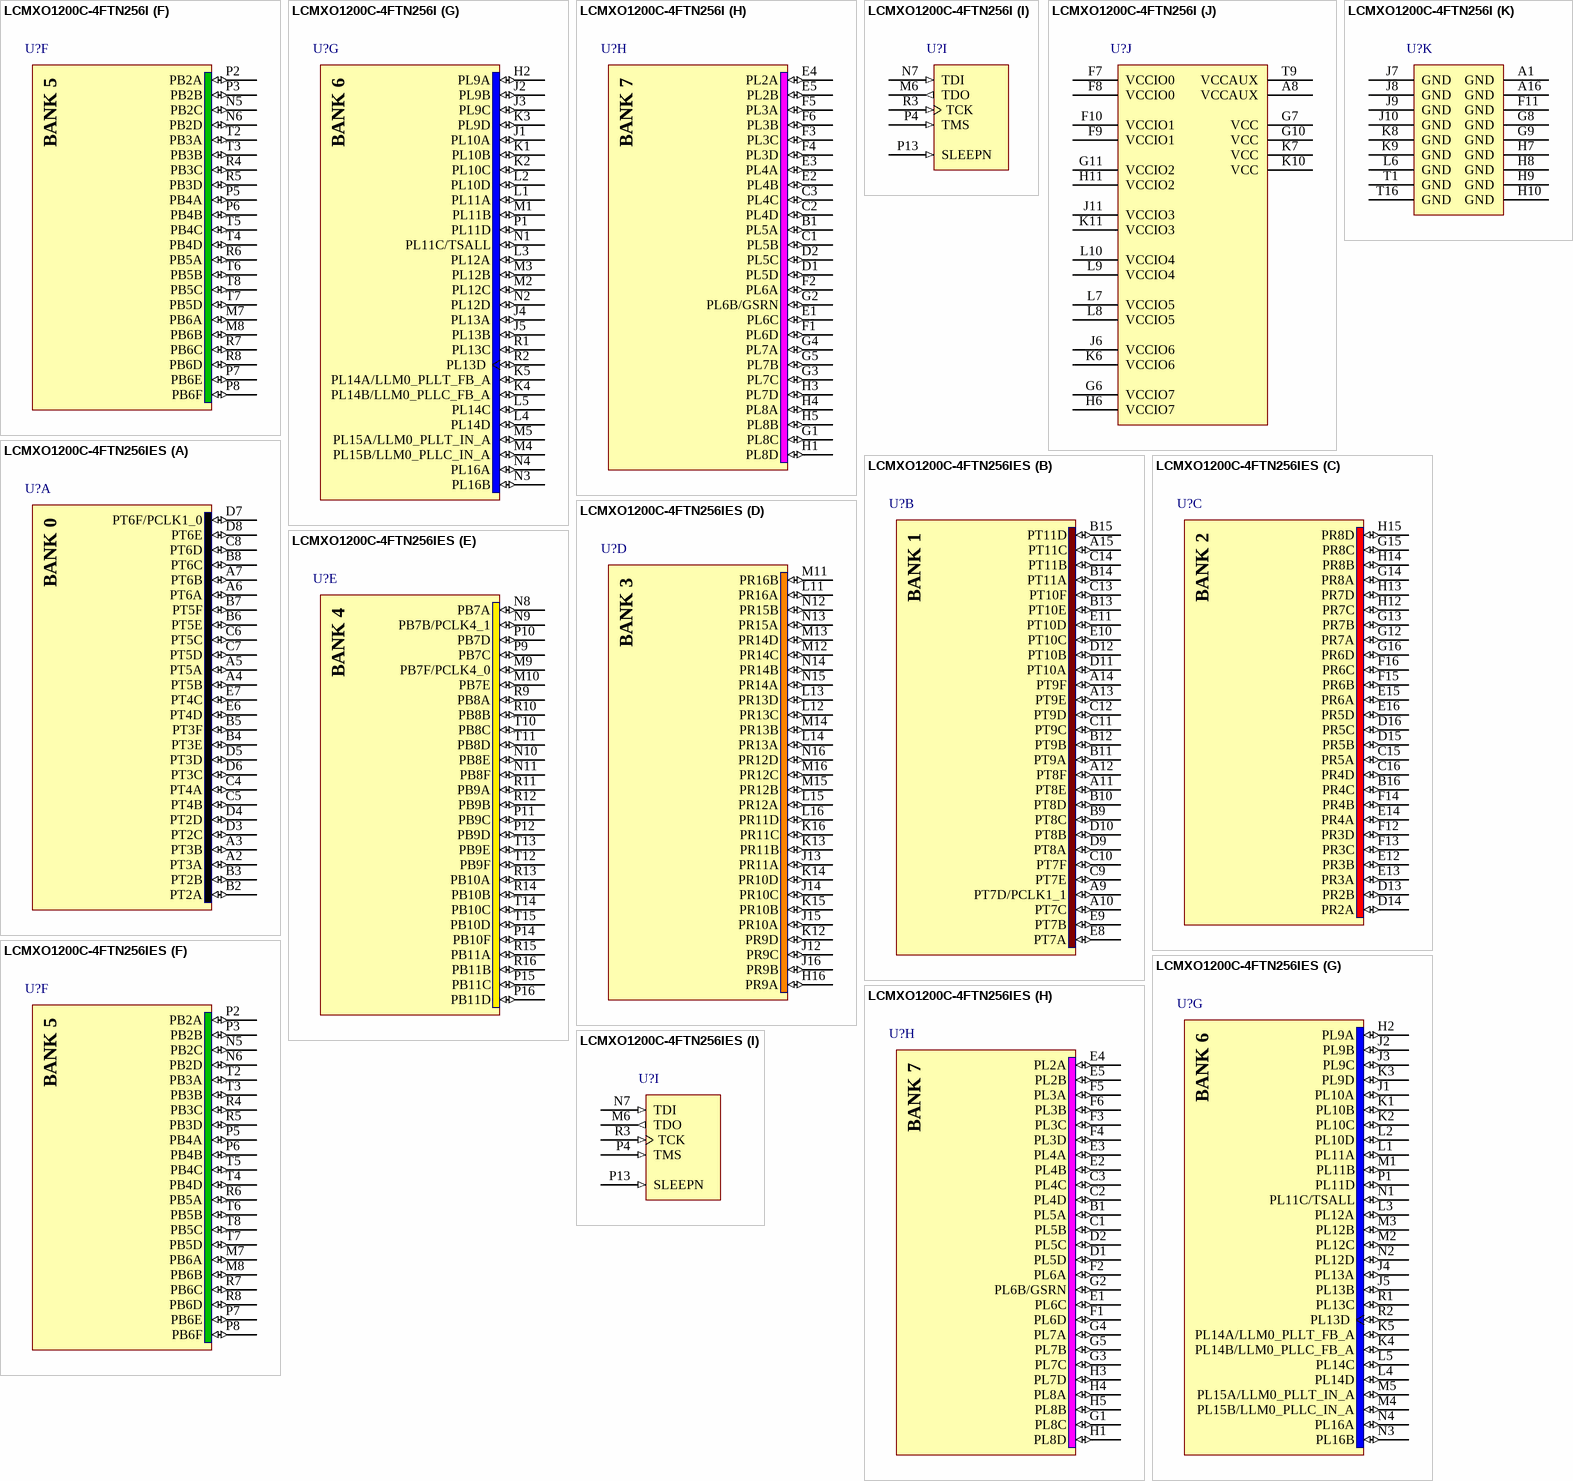
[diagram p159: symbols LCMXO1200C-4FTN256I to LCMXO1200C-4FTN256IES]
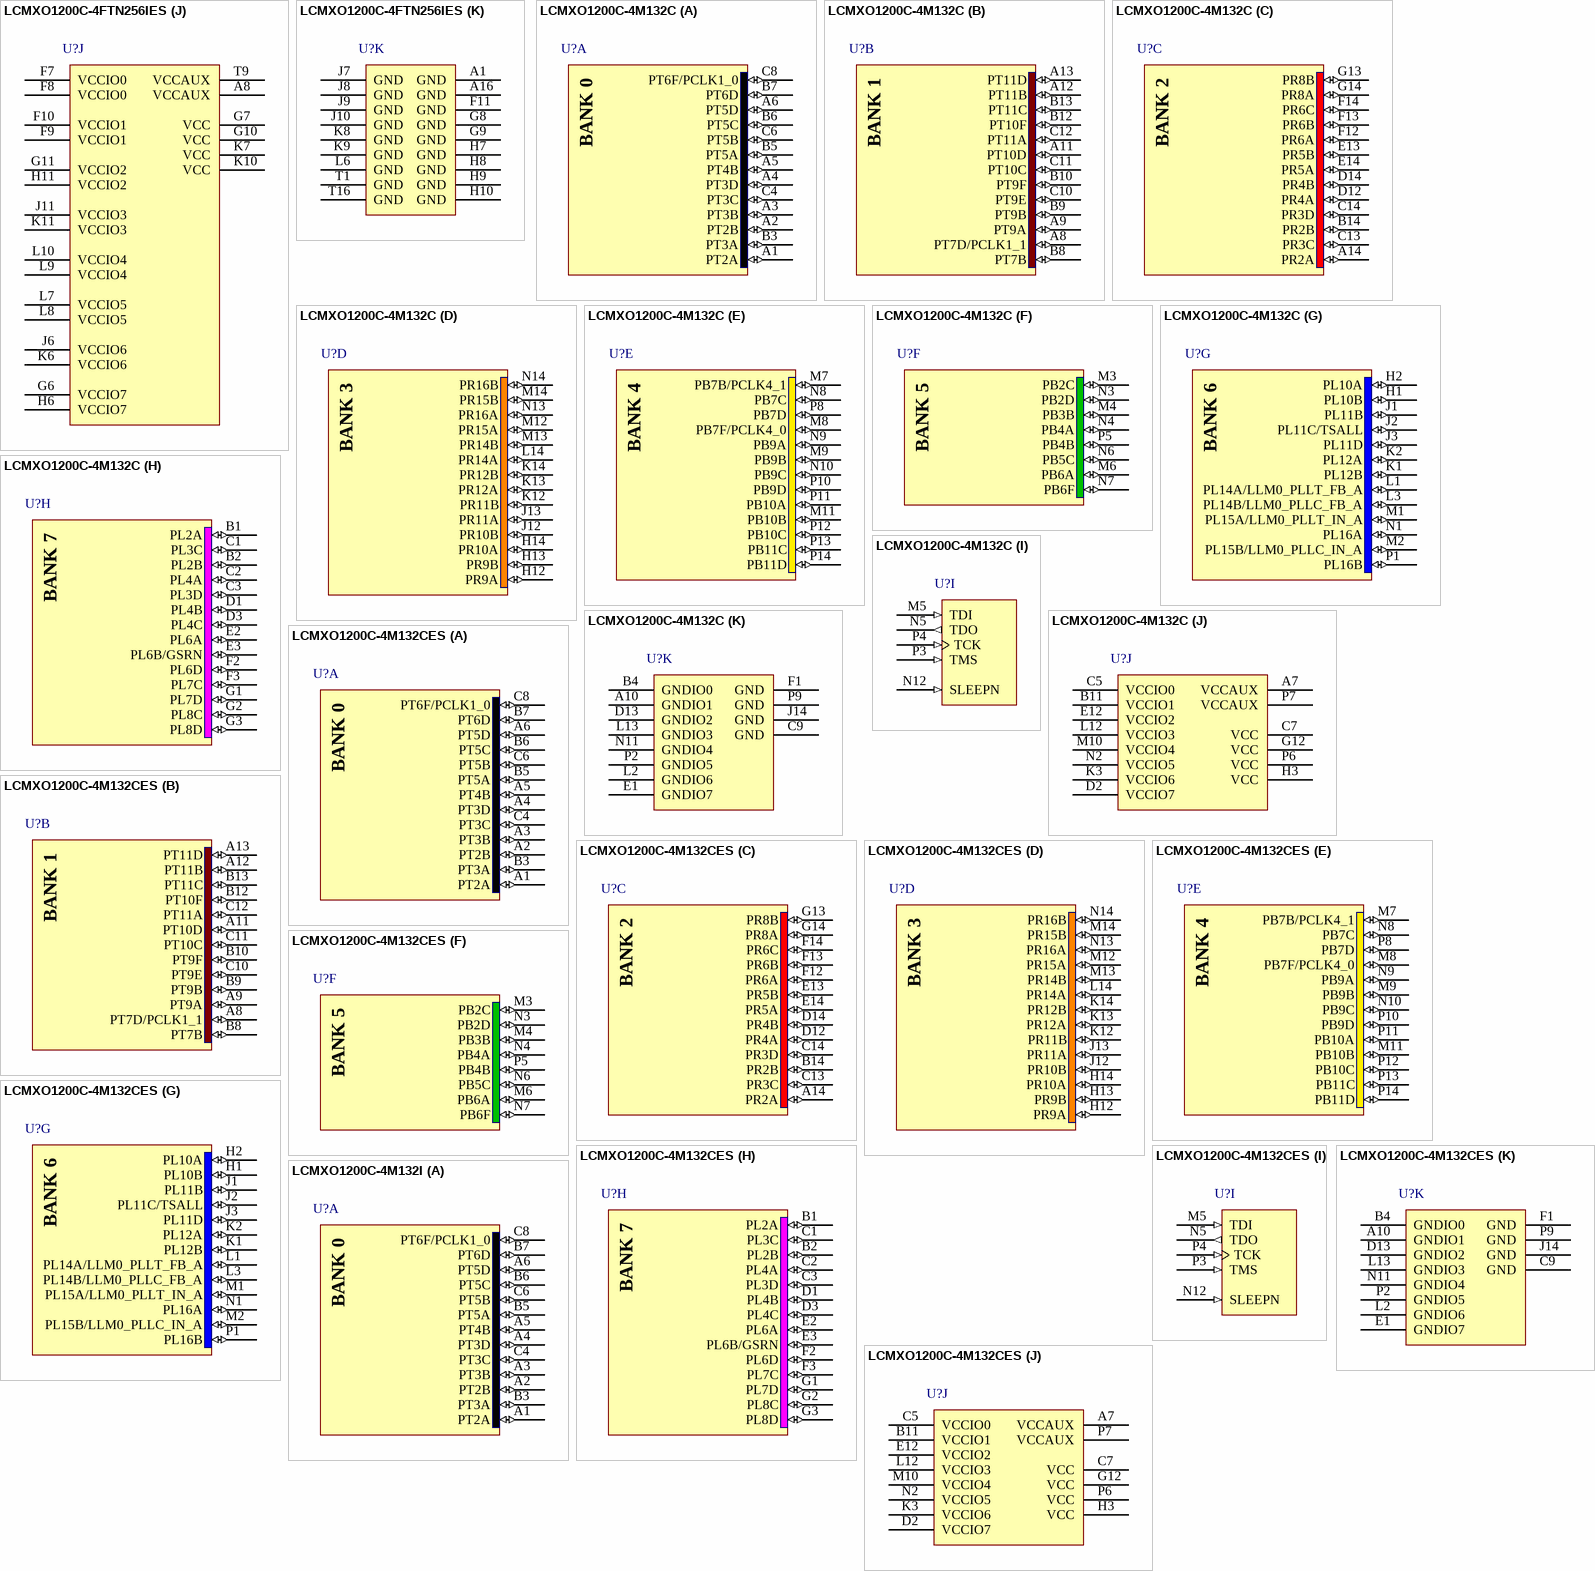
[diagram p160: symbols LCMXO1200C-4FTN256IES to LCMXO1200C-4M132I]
## LCMXO1200C-4FTN256I
designator U?
MachXO 1200 Crossover PLD, 1.8V/2.5V/3.3V, 211 User I/Os, 256-Pins ftBGA, Speed Grade-4, Industrial Grade, Pb-Free
footprint ftBGA256 (BGA, 256-Leads, Body 17x17mm, Pitch 1mm)
3D model MachXO1200-ftBGA256 (256-Ball Fine Thin Ball Grid Array (ftBGA256))
signal-integrity model LCMXO1200C_FT256 (MachXO)
part A pins: A2 PT3A (io), A3 PT3B (io), A4 PT5B (io), A5 PT5A (io), A6 PT6A (io), A7 PT6B (io), B2 PT2A (io), B3 PT2B (io), B4 PT3E (io), B5 PT3F (io), B6 PT5E (io), B7 PT5F (io), B8 PT6C (io), C4 PT4A (io), C5 PT4B (io), C6 PT5C (io), C7 PT5D (io), C8 PT6D (io), D3 PT2C (io), D4 PT2D (io), D5 PT3D (io), D6 PT3C (io), D7 PT6F/PCLK1_0 (io), D8 PT6E (io), E6 PT4D (io), E7 PT4C (io)
part B pins: A9 PT7D/PCLK1_1 (io), A10 PT7C (io), A11 PT8E (io), A12 PT8F (io), A13 PT9E (io), A14 PT9F (io), A15 PT11C (io), B9 PT8C (io), B10 PT8D (io), B11 PT9A (io), B12 PT9B (io), B13 PT10E (io), B14 PT11A (io), B15 PT11D (io), C9 PT7E (io), C10 PT7F (io), C11 PT9C (io), C12 PT9D (io), C13 PT10F (io), C14 PT11B (io), D9 PT8A (io), D10 PT8B (io), D11 PT10A (io), D12 PT10B (io), E8 PT7A (io), E9 PT7B (io), E10 PT10C (io), E11 PT10D (io)
part C pins: B16 PR4C (io), C15 PR5A (io), C16 PR4D (io), D13 PR2B (io), D14 PR2A (io), D15 PR5B (io), D16 PR5C (io), E12 PR3B (io), E13 PR3A (io), E14 PR4A (io), E15 PR6A (io), E16 PR5D (io), F12 PR3D (io), F13 PR3C (io), F14 PR4B (io), F15 PR6B (io), F16 PR6C (io), G12 PR7A (io), G13 PR7B (io), G14 PR8A (io), G15 PR8C (io), G16 PR6D (io), H12 PR7C (io), H13 PR7D (io), H14 PR8B (io), H15 PR8D (io)
part D pins: H16 PR9A (io), J12 PR9C (io), J13 PR11A (io), J14 PR10C (io), J15 PR10A (io), J16 PR9B (io), K12 PR9D (io), K13 PR11B (io), K14 PR10D (io), K15 PR10B (io), K16 PR11C (io), L11 PR16A (io), L12 PR13C (io), L13 PR13D (io), L14 PR13A (io), L15 PR12A (io), L16 PR11D (io), M11 PR16B (io), M12 PR14C (io), M13 PR14D (io), M14 PR13B (io), M15 PR12B (io), M16 PR12C (io), N12 PR15B (io), N13 PR15A (io), N14 PR14B (io), N15 PR14A (io), N16 PR12D (io)
part E pins: M9 PB7F/PCLK4_0 (io), M10 PB7E (io), N8 PB7A (io), N9 PB7B/PCLK4_1 (io), N10 PB8E (io), N11 PB8F (io), P9 PB7C (io), P10 PB7D (io), P11 PB9C (io), P12 PB9D (io), P14 PB10F (io), P15 PB11C (io), P16 PB11D (io), R9 PB8A (io), R10 PB8B (io), R11 PB9A (io), R12 PB9B (io), R13 PB10A (io), R14 PB10B (io), R15 PB11A (io), R16 PB11B (io), T10 PB8C (io), T11 PB8D (io), T12 PB9F (io), T13 PB9E (io), T14 PB10C (io), T15 PB10D (io)
part F pins: M7 PB6A (io), M8 PB6B (io), N5 PB2C (io), N6 PB2D (io), P2 PB2A (io), P3 PB2B (io), P5 PB4A (io), P6 PB4B (io), P7 PB6E (io), P8 PB6F (io), R4 PB3C (io), R5 PB3D (io), R6 PB5A (io), R7 PB6C (io), R8 PB6D (io), T2 PB3A (io), T3 PB3B (io), T4 PB4D (io), T5 PB4C (io), T6 PB5B (io), T7 PB5D (io), T8 PB5C (io)
part G pins: H2 PL9A (io), J1 PL10A (io), J2 PL9B (io), J3 PL9C (io), J4 PL13A (io), J5 PL13B (io), K1 PL10B (io), K2 PL10C (io), K3 PL9D (io), K4 PL14B/LLM0_PLLC_FB_A (io), K5 PL14A/LLM0_PLLT_FB_A (io), L1 PL11A (io), L2 PL10D (io), L3 PL12A (io), L4 PL14D (io), L5 PL14C (io), M1 PL11B (io), M2 PL12C (io), M3 PL12B (io), M4 PL15B/LLM0_PLLC_IN_A (io), M5 PL15A/LLM0_PLLT_IN_A (io), N1 PL11C/TSALL (io), N2 PL12D (io), N3 PL16B (io), N4 PL16A (io), P1 PL11D (io), R1 PL13C (io), R2 PL13D (io)
part H pins: B1 PL5A (io), C1 PL5B (io), C2 PL4D (io), C3 PL4C (io), D1 PL5D (io), D2 PL5C (io), E1 PL6C (io), E2 PL4B (io), E3 PL4A (io), E4 PL2A (io), E5 PL2B (io), F1 PL6D (io), F2 PL6A (io), F3 PL3C (io), F4 PL3D (io), F5 PL3A (io), F6 PL3B (io), G1 PL8C (io), G2 PL6B/GSRN (io), G3 PL7C (io), G4 PL7A (io), G5 PL7B (io), H1 PL8D (io), H3 PL7D (io), H4 PL8A (io), H5 PL8B (io)
part I pins: M6 TDO (out) "Powered by VCCIO5", N7 TDI (in) "Powered by VCCIO5", P4 TMS (in) "Powered by VCCIO5", P13 SLEEPN (in) "Powered by VCCIO4", R3 TCK (in) "Powered by VCCIO5"
part J pins: A8 VCCAUX (power), F7 VCCIO0 (power), F8 VCCIO0 (power), F9 VCCIO1 (power), F10 VCCIO1 (power), G6 VCCIO7 (power), G7 VCC (power), G10 VCC (power), G11 VCCIO2 (power), H6 VCCIO7 (power), H11 VCCIO2 (power), J6 VCCIO6 (power), J11 VCCIO3 (power), K6 VCCIO6 (power), K7 VCC (power), K10 VCC (power), K11 VCCIO3 (power), L7 VCCIO5 (power), L8 VCCIO5 (power), L9 VCCIO4 (power), L10 VCCIO4 (power), T9 VCCAUX (power)
part K pins: A1 GND (power), A16 GND (power), F11 GND (power), G8 GND (power), G9 GND (power), H7 GND (power), H8 GND (power), H9 GND (power), H10 GND (power), J7 GND (power), J8 GND (power), J9 GND (power), J10 GND (power), K8 GND (power), K9 GND (power), L6 GND (power), T1 GND (power), T16 GND (power)

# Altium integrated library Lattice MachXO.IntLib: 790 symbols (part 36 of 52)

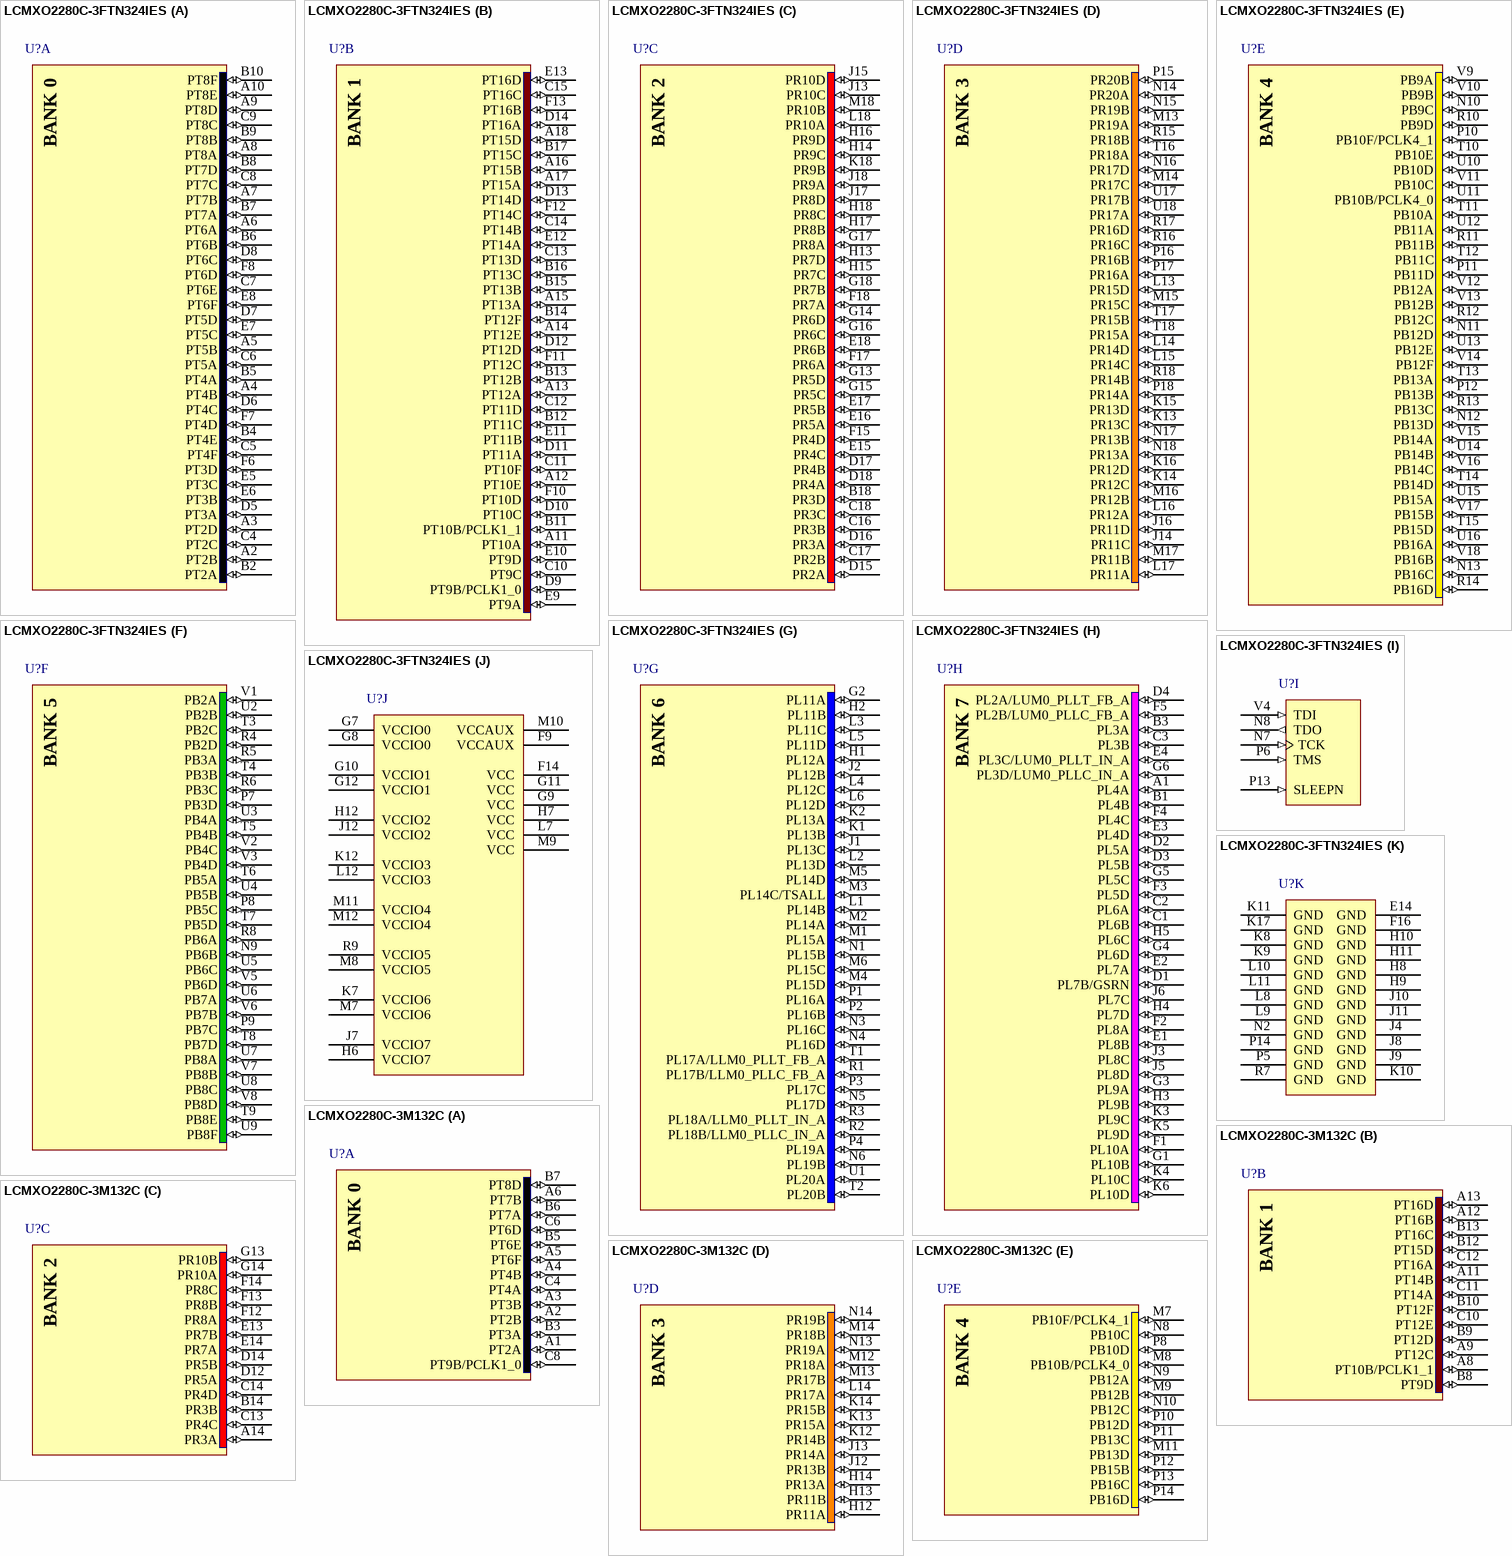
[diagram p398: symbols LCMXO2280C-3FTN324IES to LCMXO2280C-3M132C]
## LCMXO2280C-3FTN324IES
designator U?
MachXO 2280 Crossover PLD, 1.8V/2.5V/3.3V, 271 User I/Os, 324-Pins ftBGA, Speed Grade-3, Industrial Grade, Pb-Free, Engineering Sample
footprint ftBGA324 (BGA, 324-Leads, Body 19x19mm, Pitch 1mm)
3D model MachXO2280-ftBGA324 (324-Ball Fine Thin Ball Grid Array (ftBGA324))
signal-integrity model LCMXO2280C_FT324 (MachXO)
part A pins: A2 PT2B (io), A3 PT2D (io), A4 PT4B (io), A5 PT5B (io), A6 PT6A (io), A7 PT7B (io), A8 PT8A (io), A9 PT8D (io), A10 PT8E (io), B2 PT2A (io), B4 PT4E (io), B5 PT4A (io), B6 PT6B (io), B7 PT7A (io), B8 PT7D (io), B9 PT8B (io), B10 PT8F (io), C4 PT2C (io), C5 PT4F (io), C6 PT5A (io), C7 PT6E (io), C8 PT7C (io), C9 PT8C (io), D5 PT3A (io), D6 PT4C (io), D7 PT5D (io), D8 PT6C (io), E5 PT3C (io), E6 PT3B (io), E7 PT5C (io), E8 PT6F (io), F6 PT3D (io), F7 PT4D (io), F8 PT6D (io)
part B pins: A11 PT10A (io), A12 PT10E (io), A13 PT12A (io), A14 PT12E (io), A15 PT13A (io), A16 PT15B (io), A17 PT15A (io), A18 PT15D (io), B11 PT10B/PCLK1_1 (io), B12 PT11C (io), B13 PT12B (io), B14 PT12F (io), B15 PT13B (io), B16 PT13C (io), B17 PT15C (io), C10 PT9C (io), C11 PT10F (io), C12 PT11D (io), C13 PT13D (io), C14 PT14B (io), C15 PT16C (io), D9 PT9B/PCLK1_0 (io), D10 PT10C (io), D11 PT11A (io), D12 PT12D (io), D13 PT14D (io), D14 PT16A (io), E9 PT9A (io), E10 PT9D (io), E11 PT11B (io), E12 PT14A (io), E13 PT16D (io), F10 PT10D (io), F11 PT12C (io), F12 PT14C (io), F13 PT16B (io)
part C pins: B18 PR3D (io), C16 PR3B (io), C17 PR2B (io), C18 PR3C (io), D15 PR2A (io), D16 PR3A (io), D17 PR4B (io), D18 PR4A (io), E15 PR4C (io), E16 PR5A (io), E17 PR5B (io), E18 PR6B (io), F15 PR4D (io), F17 PR6A (io), F18 PR7A (io), G13 PR5D (io), G14 PR6D (io), G15 PR5C (io), G16 PR6C (io), G17 PR8A (io), G18 PR7B (io), H13 PR7D (io), H14 PR9C (io), H15 PR7C (io), H16 PR9D (io), H17 PR8B (io), H18 PR8C (io), J13 PR10C (io), J15 PR10D (io), J17 PR8D (io), J18 PR9A (io), K18 PR9B (io), L18 PR10A (io), M18 PR10B (io)
part D pins: J14 PR11C (io), J16 PR11D (io), K13 PR13C (io), K14 PR12C (io), K15 PR13D (io), K16 PR12D (io), L13 PR15D (io), L14 PR14D (io), L15 PR14C (io), L16 PR12A (io), L17 PR11A (io), M13 PR19A (io), M14 PR17C (io), M15 PR15C (io), M16 PR12B (io), M17 PR11B (io), N14 PR20A (io), N15 PR19B (io), N16 PR17D (io), N17 PR13B (io), N18 PR13A (io), P15 PR20B (io), P16 PR16B (io), P17 PR16A (io), P18 PR14A (io), R15 PR18B (io), R16 PR16C (io), R17 PR16D (io), R18 PR14B (io), T16 PR18A (io), T17 PR15B (io), T18 PR15A (io), U17 PR17B (io), U18 PR17A (io)
part E pins: N10 PB9C (io), N11 PB12D (io), N12 PB13D (io), N13 PB16C (io), P10 PB10F/PCLK4_1 (io), P11 PB11D (io), P12 PB13B (io), R10 PB9D (io), R11 PB11B (io), R12 PB12C (io), R13 PB13C (io), R14 PB16D (io), T10 PB10E (io), T11 PB10A (io), T12 PB11C (io), T13 PB13A (io), T14 PB14D (io), T15 PB15D (io), U10 PB10D (io), U11 PB10B/PCLK4_0 (io), U12 PB11A (io), U13 PB12E (io), U14 PB14B (io), U15 PB15A (io), U16 PB16A (io), V9 PB9A (io), V10 PB9B (io), V11 PB10C (io), V12 PB12A (io), V13 PB12B (io), V14 PB12F (io), V15 PB14A (io), V16 PB14C (io), V17 PB15B (io), V18 PB16B (io)
part F pins: N9 PB6B (io), P7 PB3D (io), P8 PB5C (io), P9 PB7C (io), R4 PB2D (io), R5 PB3A (io), R6 PB3C (io), R8 PB6A (io), T3 PB2C (io), T4 PB3B (io), T5 PB4B (io), T6 PB5A (io), T7 PB5D (io), T8 PB7D (io), T9 PB8E (io), U2 PB2B (io), U3 PB4A (io), U4 PB5B (io), U5 PB6C (io), U6 PB7A (io), U7 PB8A (io), U8 PB8C (io), U9 PB8F (io), V1 PB2A (io), V2 PB4C (io), V3 PB4D (io), V5 PB6D (io), V6 PB7B (io), V7 PB8B (io), V8 PB8D (io)
part G pins: G2 PL11A (io), H1 PL12A (io), H2 PL11B (io), J1 PL13C (io), J2 PL12B (io), K1 PL13B (io), K2 PL13A (io), L1 PL14B (io), L2 PL13D (io), L3 PL11C (io), L4 PL12C (io), L5 PL11D (io), L6 PL12D (io), M1 PL15A (io), M2 PL14A (io), M3 PL14C/TSALL (io), M4 PL15D (io), M5 PL14D (io), M6 PL15C (io), N1 PL15B (io), N3 PL16C (io), N4 PL16D (io), N5 PL17D (io), N6 PL19B (io), P1 PL16A (io), P2 PL16B (io), P3 PL17C (io), P4 PL19A (io), R1 PL17B/LLM0_PLLC_FB_A (io), R2 PL18B/LLM0_PLLC_IN_A (io), R3 PL18A/LLM0_PLLT_IN_A (io), T1 PL17A/LLM0_PLLT_FB_A (io), T2 PL20B (io), U1 PL20A (io)
part H pins: A1 PL4A (io), B1 PL4B (io), B3 PL3A (io), C1 PL6B (io), C2 PL6A (io), C3 PL3B (io), D1 PL7B/GSRN (io), D2 PL5A (io), D3 PL5B (io), D4 PL2A/LUM0_PLLT_FB_A (io), E1 PL8B (io), E2 PL7A (io), E3 PL4D (io), E4 PL3C/LUM0_PLLT_IN_A (io), F1 PL10A (io), F2 PL8A (io), F3 PL5D (io), F4 PL4C (io), F5 PL2B/LUM0_PLLC_FB_A (io), G1 PL10B (io), G3 PL9A (io), G4 PL6D (io), G5 PL5C (io), G6 PL3D/LUM0_PLLC_IN_A (io), H3 PL9B (io), H4 PL7D (io), H5 PL6C (io), J3 PL8C (io), J5 PL8D (io), J6 PL7C (io), K3 PL9C (io), K4 PL10C (io), K5 PL9D (io), K6 PL10D (io)
part I pins: N7 TCK (in) "Powered by VCCIO5", N8 TDO (out) "Powered by VCCIO5", P6 TMS (in) "Powered by VCCIO5", P13 SLEEPN (in) "Powered by VCCIO4", V4 TDI (in) "Powered by VCCIO5"
part J pins: F9 VCCAUX (power), F14 VCC (power), G7 VCCIO0 (power), G8 VCCIO0 (power), G9 VCC (power), G10 VCCIO1 (power), G11 VCC (power), G12 VCCIO1 (power), H6 VCCIO7 (power), H7 VCC (power), H12 VCCIO2 (power), J7 VCCIO7 (power), J12 VCCIO2 (power), K7 VCCIO6 (power), K12 VCCIO3 (power), L7 VCC (power), L12 VCCIO3 (power), M7 VCCIO6 (power), M8 VCCIO5 (power), M9 VCC (power), M10 VCCAUX (power), M11 VCCIO4 (power), M12 VCCIO4 (power), R9 VCCIO5 (power)
part K pins: E14 GND (power), F16 GND (power), H8 GND (power), H9 GND (power), H10 GND (power), H11 GND (power), J4 GND (power), J8 GND (power), J9 GND (power), J10 GND (power), J11 GND (power), K8 GND (power), K9 GND (power), K10 GND (power), K11 GND (power), K17 GND (power), L8 GND (power), L9 GND (power), L10 GND (power), L11 GND (power), N2 GND (power), P5 GND (power), P14 GND (power), R7 GND (power)


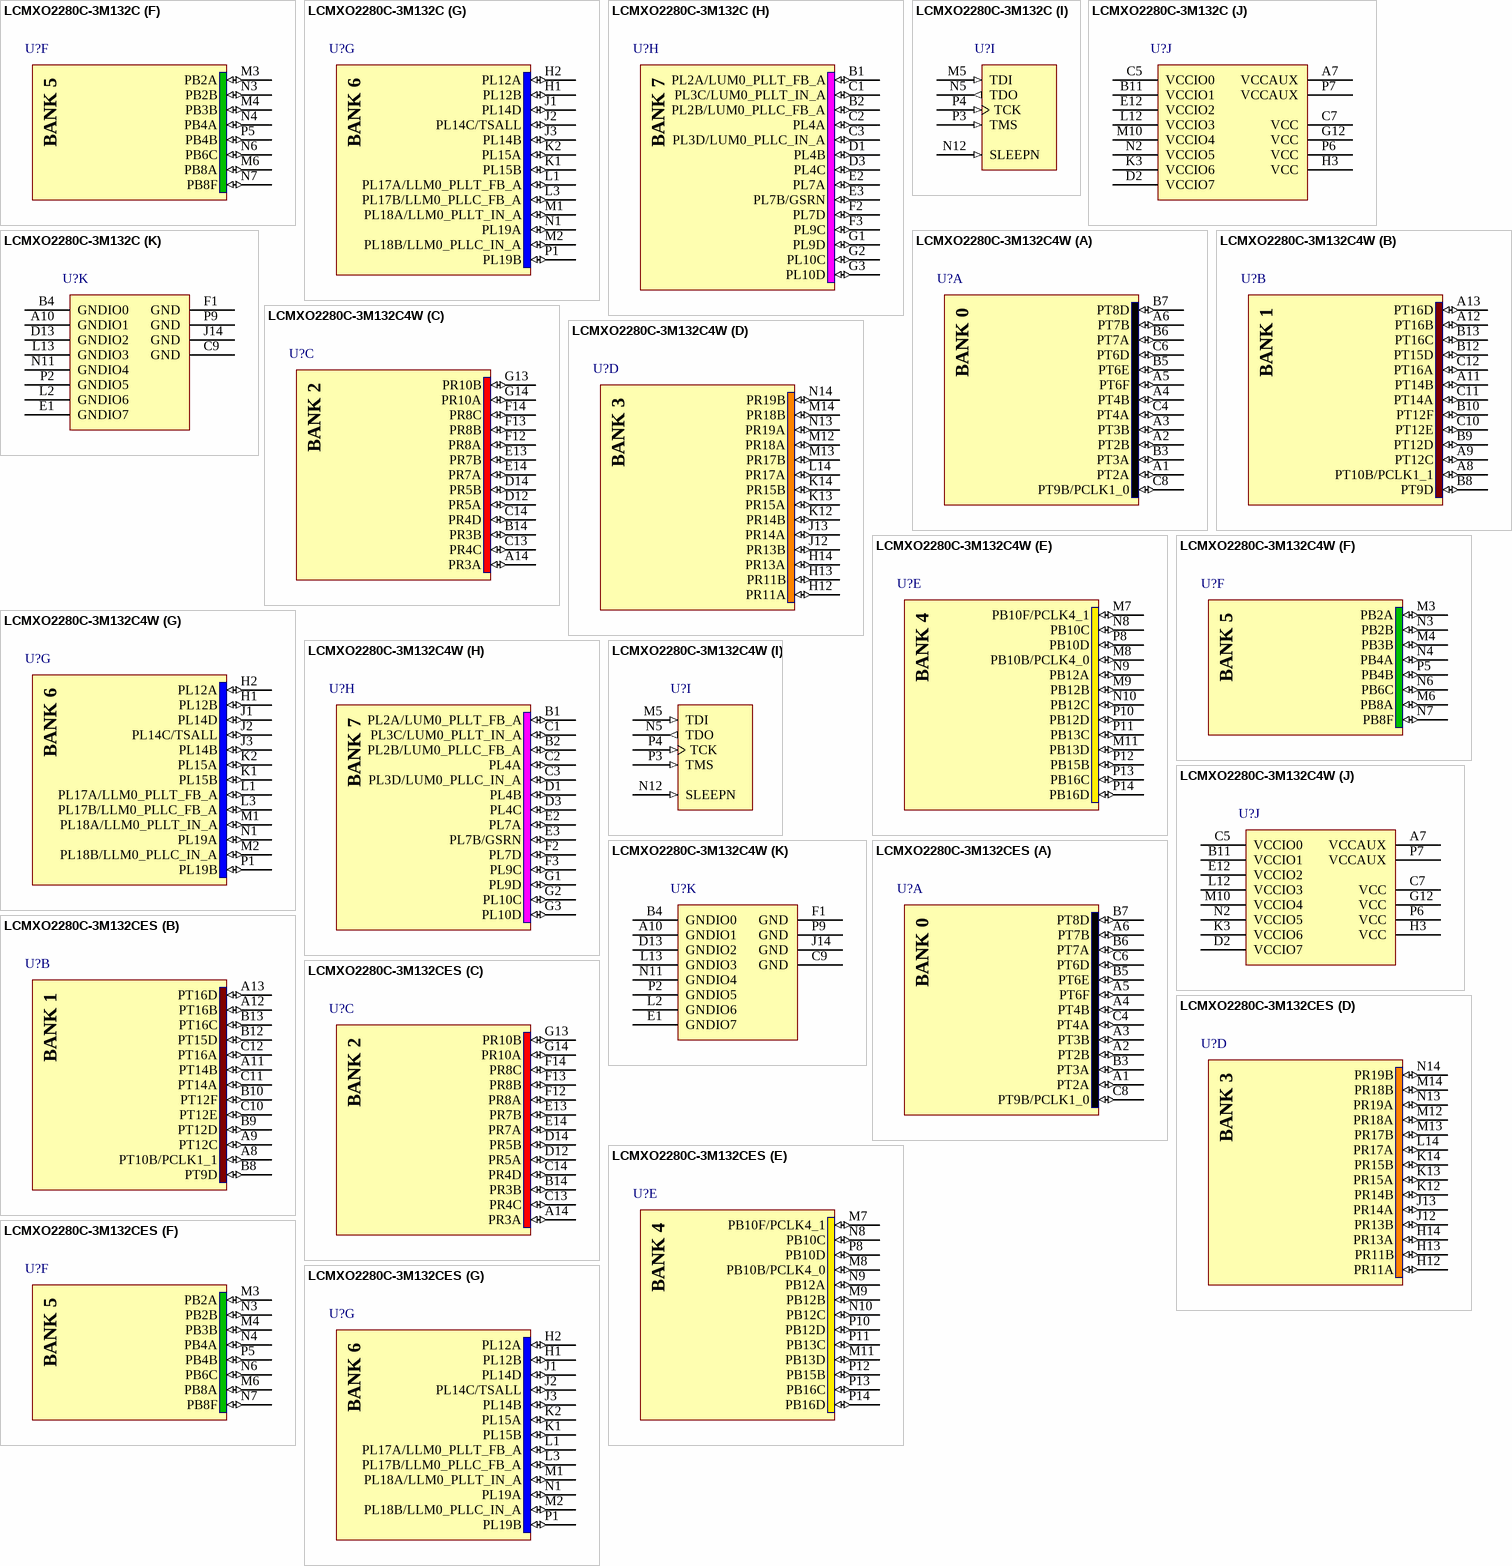
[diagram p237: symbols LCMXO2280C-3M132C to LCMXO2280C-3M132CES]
## LCMXO2280C-3M132C
designator U?
MachXO 2280 Crossover PLD, 1.8V/2.5V/3.3V, 101 User I/Os, 132-Pins csBGA, Speed Grade-3, Commercial Grade
footprint csBGA132 (BGA, 132-Leads, Body 8x8mm, Pitch 0.5mm)
3D model MachXO2280-csBGA132 (132-Ball Chip Scale Ball Grid Array (csBGA132))
signal-integrity model LCMXO2280C_M132 (MachXO)
part A pins: A1 PT2A (io), A2 PT2B (io), A3 PT3B (io), A4 PT4B (io), A5 PT6F (io), A6 PT7B (io), B3 PT3A (io), B5 PT6E (io), B6 PT7A (io), B7 PT8D (io), C4 PT4A (io), C6 PT6D (io), C8 PT9B/PCLK1_0 (io)
part B pins: A8 PT10B/PCLK1_1 (io), A9 PT12C (io), A11 PT14B (io), A12 PT16B (io), A13 PT16D (io), B8 PT9D (io), B9 PT12D (io), B10 PT12F (io), B12 PT15D (io), B13 PT16C (io), C10 PT12E (io), C11 PT14A (io), C12 PT16A (io)
part C pins: A14 PR3A (io), B14 PR3B (io), C13 PR4C (io), C14 PR4D (io), D12 PR5A (io), D14 PR5B (io), E13 PR7B (io), E14 PR7A (io), F12 PR8A (io), F13 PR8B (io), F14 PR8C (io), G13 PR10B (io), G14 PR10A (io)
part D pins: H12 PR11A (io), H13 PR11B (io), H14 PR13A (io), J12 PR13B (io), J13 PR14A (io), K12 PR14B (io), K13 PR15A (io), K14 PR15B (io), L14 PR17A (io), M12 PR18A (io), M13 PR17B (io), M14 PR18B (io), N13 PR19A (io), N14 PR19B (io)
part E pins: M7 PB10F/PCLK4_1 (io), M8 PB10B/PCLK4_0 (io), M9 PB12B (io), M11 PB13D (io), N8 PB10C (io), N9 PB12A (io), N10 PB12C (io), P8 PB10D (io), P10 PB12D (io), P11 PB13C (io), P12 PB15B (io), P13 PB16C (io), P14 PB16D (io)
part F pins: M3 PB2A (io), M4 PB3B (io), M6 PB8A (io), N3 PB2B (io), N4 PB4A (io), N6 PB6C (io), N7 PB8F (io), P5 PB4B (io)
part G pins: H1 PL12B (io), H2 PL12A (io), J1 PL14D (io), J2 PL14C/TSALL (io), J3 PL14B (io), K1 PL15B (io), K2 PL15A (io), L1 PL17A/LLM0_PLLT_FB_A (io), L3 PL17B/LLM0_PLLC_FB_A (io), M1 PL18A/LLM0_PLLT_IN_A (io), M2 PL18B/LLM0_PLLC_IN_A (io), N1 PL19A (io), P1 PL19B (io)
part H pins: B1 PL2A/LUM0_PLLT_FB_A (io), B2 PL2B/LUM0_PLLC_FB_A (io), C1 PL3C/LUM0_PLLT_IN_A (io), C2 PL4A (io), C3 PL3D/LUM0_PLLC_IN_A (io), D1 PL4B (io), D3 PL4C (io), E2 PL7A (io), E3 PL7B/GSRN (io), F2 PL7D (io), F3 PL9C (io), G1 PL9D (io), G2 PL10C (io), G3 PL10D (io)
part I pins: M5 TDI (in) "Powered by VCCIO5", N5 TDO (out) "Powered by VCCIO5", N12 SLEEPN (in) "Powered by VCCIO4", P3 TMS (in) "Powered by VCCIO5", P4 TCK (in) "Powered by VCCIO5"
part J pins: A7 VCCAUX (power), B11 VCCIO1 (power), C5 VCCIO0 (power), C7 VCC (power), D2 VCCIO7 (power), E12 VCCIO2 (power), G12 VCC (power), H3 VCC (power), K3 VCCIO6 (power), L12 VCCIO3 (power), M10 VCCIO4 (power), N2 VCCIO5 (power), P6 VCC (power), P7 VCCAUX (power)
part K pins: A10 GNDIO1 (power), B4 GNDIO0 (power), C9 GND (power), D13 GNDIO2 (power), E1 GNDIO7 (power), F1 GND (power), J14 GND (power), L2 GNDIO6 (power), L13 GNDIO3 (power), N11 GNDIO4 (power), P2 GNDIO5 (power), P9 GND (power)

## LCMXO2280C-3M132C4W
designator U?
MachXO 2280 Crossover PLD, 1.8V/2.5V/3.3V, 101 User I/Os, 132-Pins csBGA, Speed Grade-3, Commercial Grade
footprint csBGA132 (BGA, 132-Leads, Body 8x8mm, Pitch 0.5mm)
3D model MachXO2280-csBGA132 (132-Ball Chip Scale Ball Grid Array (csBGA132))
signal-integrity model LCMXO2280C_M132 (MachXO)
part A pins: A1 PT2A (io), A2 PT2B (io), A3 PT3B (io), A4 PT4B (io), A5 PT6F (io), A6 PT7B (io), B3 PT3A (io), B5 PT6E (io), B6 PT7A (io), B7 PT8D (io), C4 PT4A (io), C6 PT6D (io), C8 PT9B/PCLK1_0 (io)
part B pins: A8 PT10B/PCLK1_1 (io), A9 PT12C (io), A11 PT14B (io), A12 PT16B (io), A13 PT16D (io), B8 PT9D (io), B9 PT12D (io), B10 PT12F (io), B12 PT15D (io), B13 PT16C (io), C10 PT12E (io), C11 PT14A (io), C12 PT16A (io)
part C pins: A14 PR3A (io), B14 PR3B (io), C13 PR4C (io), C14 PR4D (io), D12 PR5A (io), D14 PR5B (io), E13 PR7B (io), E14 PR7A (io), F12 PR8A (io), F13 PR8B (io), F14 PR8C (io), G13 PR10B (io), G14 PR10A (io)
part D pins: H12 PR11A (io), H13 PR11B (io), H14 PR13A (io), J12 PR13B (io), J13 PR14A (io), K12 PR14B (io), K13 PR15A (io), K14 PR15B (io), L14 PR17A (io), M12 PR18A (io), M13 PR17B (io), M14 PR18B (io), N13 PR19A (io), N14 PR19B (io)
part E pins: M7 PB10F/PCLK4_1 (io), M8 PB10B/PCLK4_0 (io), M9 PB12B (io), M11 PB13D (io), N8 PB10C (io), N9 PB12A (io), N10 PB12C (io), P8 PB10D (io), P10 PB12D (io), P11 PB13C (io), P12 PB15B (io), P13 PB16C (io), P14 PB16D (io)
part F pins: M3 PB2A (io), M4 PB3B (io), M6 PB8A (io), N3 PB2B (io), N4 PB4A (io), N6 PB6C (io), N7 PB8F (io), P5 PB4B (io)
part G pins: H1 PL12B (io), H2 PL12A (io), J1 PL14D (io), J2 PL14C/TSALL (io), J3 PL14B (io), K1 PL15B (io), K2 PL15A (io), L1 PL17A/LLM0_PLLT_FB_A (io), L3 PL17B/LLM0_PLLC_FB_A (io), M1 PL18A/LLM0_PLLT_IN_A (io), M2 PL18B/LLM0_PLLC_IN_A (io), N1 PL19A (io), P1 PL19B (io)
part H pins: B1 PL2A/LUM0_PLLT_FB_A (io), B2 PL2B/LUM0_PLLC_FB_A (io), C1 PL3C/LUM0_PLLT_IN_A (io), C2 PL4A (io), C3 PL3D/LUM0_PLLC_IN_A (io), D1 PL4B (io), D3 PL4C (io), E2 PL7A (io), E3 PL7B/GSRN (io), F2 PL7D (io), F3 PL9C (io), G1 PL9D (io), G2 PL10C (io), G3 PL10D (io)
part I pins: M5 TDI (in) "Powered by VCCIO5", N5 TDO (out) "Powered by VCCIO5", N12 SLEEPN (in) "Powered by VCCIO4", P3 TMS (in) "Powered by VCCIO5", P4 TCK (in) "Powered by VCCIO5"
part J pins: A7 VCCAUX (power), B11 VCCIO1 (power), C5 VCCIO0 (power), C7 VCC (power), D2 VCCIO7 (power), E12 VCCIO2 (power), G12 VCC (power), H3 VCC (power), K3 VCCIO6 (power), L12 VCCIO3 (power), M10 VCCIO4 (power), N2 VCCIO5 (power), P6 VCC (power), P7 VCCAUX (power)
part K pins: A10 GNDIO1 (power), B4 GNDIO0 (power), C9 GND (power), D13 GNDIO2 (power), E1 GNDIO7 (power), F1 GND (power), J14 GND (power), L2 GNDIO6 (power), L13 GNDIO3 (power), N11 GNDIO4 (power), P2 GNDIO5 (power), P9 GND (power)


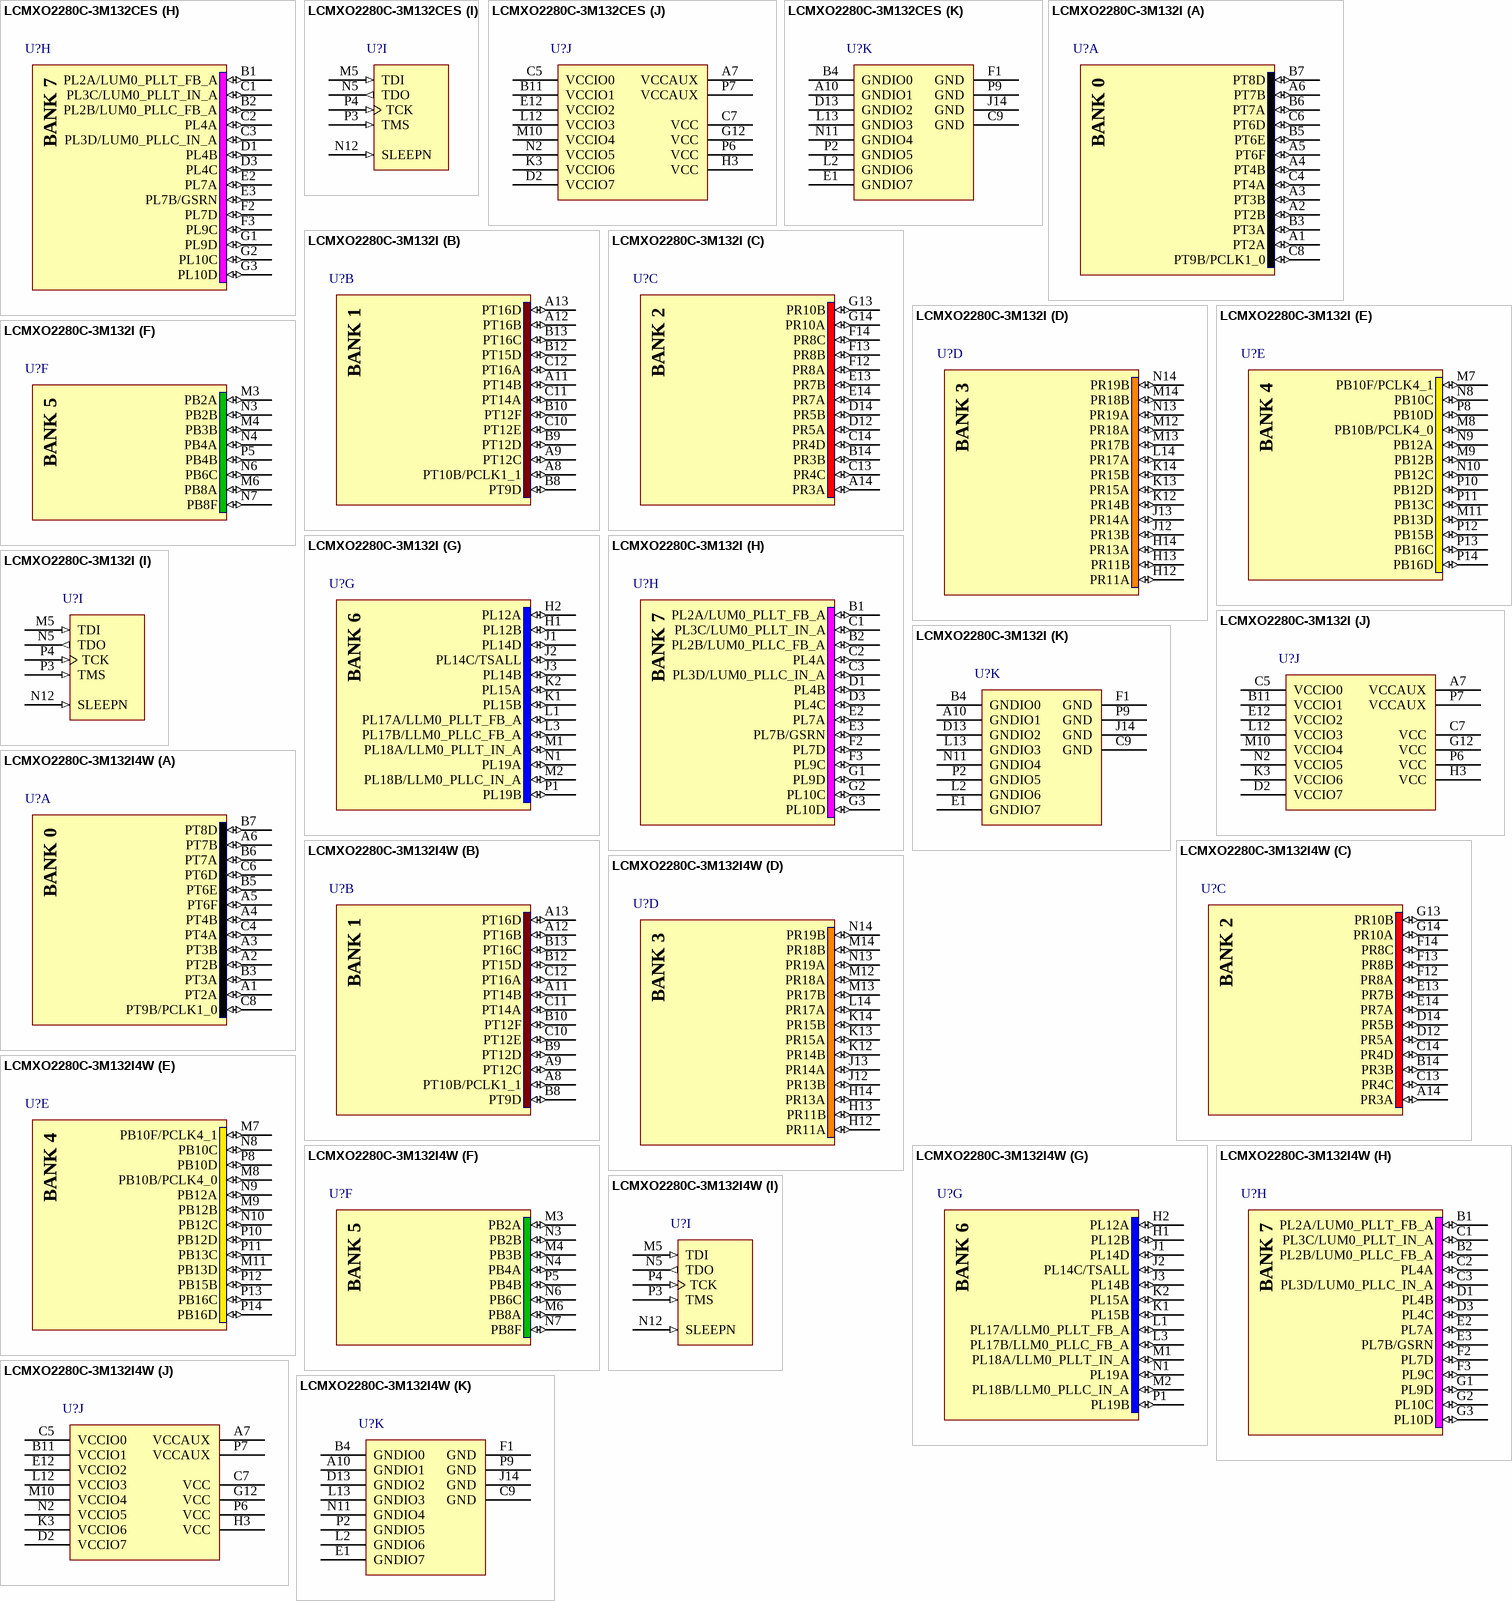
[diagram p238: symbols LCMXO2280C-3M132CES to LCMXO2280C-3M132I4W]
## LCMXO2280C-3M132CES
designator U?
MachXO 2280 Crossover PLD, 1.8V/2.5V/3.3V, 101 User I/Os, 132-Pins csBGA, Speed Grade-3, Commercial Grade, Engineering Sample
footprint csBGA132 (BGA, 132-Leads, Body 8x8mm, Pitch 0.5mm)
3D model MachXO2280-csBGA132 (132-Ball Chip Scale Ball Grid Array (csBGA132))
signal-integrity model LCMXO2280C_M132 (MachXO)
part A pins: A1 PT2A (io), A2 PT2B (io), A3 PT3B (io), A4 PT4B (io), A5 PT6F (io), A6 PT7B (io), B3 PT3A (io), B5 PT6E (io), B6 PT7A (io), B7 PT8D (io), C4 PT4A (io), C6 PT6D (io), C8 PT9B/PCLK1_0 (io)
part B pins: A8 PT10B/PCLK1_1 (io), A9 PT12C (io), A11 PT14B (io), A12 PT16B (io), A13 PT16D (io), B8 PT9D (io), B9 PT12D (io), B10 PT12F (io), B12 PT15D (io), B13 PT16C (io), C10 PT12E (io), C11 PT14A (io), C12 PT16A (io)
part C pins: A14 PR3A (io), B14 PR3B (io), C13 PR4C (io), C14 PR4D (io), D12 PR5A (io), D14 PR5B (io), E13 PR7B (io), E14 PR7A (io), F12 PR8A (io), F13 PR8B (io), F14 PR8C (io), G13 PR10B (io), G14 PR10A (io)
part D pins: H12 PR11A (io), H13 PR11B (io), H14 PR13A (io), J12 PR13B (io), J13 PR14A (io), K12 PR14B (io), K13 PR15A (io), K14 PR15B (io), L14 PR17A (io), M12 PR18A (io), M13 PR17B (io), M14 PR18B (io), N13 PR19A (io), N14 PR19B (io)
part E pins: M7 PB10F/PCLK4_1 (io), M8 PB10B/PCLK4_0 (io), M9 PB12B (io), M11 PB13D (io), N8 PB10C (io), N9 PB12A (io), N10 PB12C (io), P8 PB10D (io), P10 PB12D (io), P11 PB13C (io), P12 PB15B (io), P13 PB16C (io), P14 PB16D (io)
part F pins: M3 PB2A (io), M4 PB3B (io), M6 PB8A (io), N3 PB2B (io), N4 PB4A (io), N6 PB6C (io), N7 PB8F (io), P5 PB4B (io)
part G pins: H1 PL12B (io), H2 PL12A (io), J1 PL14D (io), J2 PL14C/TSALL (io), J3 PL14B (io), K1 PL15B (io), K2 PL15A (io), L1 PL17A/LLM0_PLLT_FB_A (io), L3 PL17B/LLM0_PLLC_FB_A (io), M1 PL18A/LLM0_PLLT_IN_A (io), M2 PL18B/LLM0_PLLC_IN_A (io), N1 PL19A (io), P1 PL19B (io)
part H pins: B1 PL2A/LUM0_PLLT_FB_A (io), B2 PL2B/LUM0_PLLC_FB_A (io), C1 PL3C/LUM0_PLLT_IN_A (io), C2 PL4A (io), C3 PL3D/LUM0_PLLC_IN_A (io), D1 PL4B (io), D3 PL4C (io), E2 PL7A (io), E3 PL7B/GSRN (io), F2 PL7D (io), F3 PL9C (io), G1 PL9D (io), G2 PL10C (io), G3 PL10D (io)
part I pins: M5 TDI (in) "Powered by VCCIO5", N5 TDO (out) "Powered by VCCIO5", N12 SLEEPN (in) "Powered by VCCIO4", P3 TMS (in) "Powered by VCCIO5", P4 TCK (in) "Powered by VCCIO5"
part J pins: A7 VCCAUX (power), B11 VCCIO1 (power), C5 VCCIO0 (power), C7 VCC (power), D2 VCCIO7 (power), E12 VCCIO2 (power), G12 VCC (power), H3 VCC (power), K3 VCCIO6 (power), L12 VCCIO3 (power), M10 VCCIO4 (power), N2 VCCIO5 (power), P6 VCC (power), P7 VCCAUX (power)
part K pins: A10 GNDIO1 (power), B4 GNDIO0 (power), C9 GND (power), D13 GNDIO2 (power), E1 GNDIO7 (power), F1 GND (power), J14 GND (power), L2 GNDIO6 (power), L13 GNDIO3 (power), N11 GNDIO4 (power), P2 GNDIO5 (power), P9 GND (power)

## LCMXO2280C-3M132I
designator U?
MachXO 2280 Crossover PLD, 1.8V/2.5V/3.3V, 101 User I/Os, 132-Pins csBGA, Speed Grade-3, Industrial Grade
footprint csBGA132 (BGA, 132-Leads, Body 8x8mm, Pitch 0.5mm)
3D model MachXO2280-csBGA132 (132-Ball Chip Scale Ball Grid Array (csBGA132))
signal-integrity model LCMXO2280C_M132 (MachXO)
part A pins: A1 PT2A (io), A2 PT2B (io), A3 PT3B (io), A4 PT4B (io), A5 PT6F (io), A6 PT7B (io), B3 PT3A (io), B5 PT6E (io), B6 PT7A (io), B7 PT8D (io), C4 PT4A (io), C6 PT6D (io), C8 PT9B/PCLK1_0 (io)
part B pins: A8 PT10B/PCLK1_1 (io), A9 PT12C (io), A11 PT14B (io), A12 PT16B (io), A13 PT16D (io), B8 PT9D (io), B9 PT12D (io), B10 PT12F (io), B12 PT15D (io), B13 PT16C (io), C10 PT12E (io), C11 PT14A (io), C12 PT16A (io)
part C pins: A14 PR3A (io), B14 PR3B (io), C13 PR4C (io), C14 PR4D (io), D12 PR5A (io), D14 PR5B (io), E13 PR7B (io), E14 PR7A (io), F12 PR8A (io), F13 PR8B (io), F14 PR8C (io), G13 PR10B (io), G14 PR10A (io)
part D pins: H12 PR11A (io), H13 PR11B (io), H14 PR13A (io), J12 PR13B (io), J13 PR14A (io), K12 PR14B (io), K13 PR15A (io), K14 PR15B (io), L14 PR17A (io), M12 PR18A (io), M13 PR17B (io), M14 PR18B (io), N13 PR19A (io), N14 PR19B (io)
part E pins: M7 PB10F/PCLK4_1 (io), M8 PB10B/PCLK4_0 (io), M9 PB12B (io), M11 PB13D (io), N8 PB10C (io), N9 PB12A (io), N10 PB12C (io), P8 PB10D (io), P10 PB12D (io), P11 PB13C (io), P12 PB15B (io), P13 PB16C (io), P14 PB16D (io)
part F pins: M3 PB2A (io), M4 PB3B (io), M6 PB8A (io), N3 PB2B (io), N4 PB4A (io), N6 PB6C (io), N7 PB8F (io), P5 PB4B (io)
part G pins: H1 PL12B (io), H2 PL12A (io), J1 PL14D (io), J2 PL14C/TSALL (io), J3 PL14B (io), K1 PL15B (io), K2 PL15A (io), L1 PL17A/LLM0_PLLT_FB_A (io), L3 PL17B/LLM0_PLLC_FB_A (io), M1 PL18A/LLM0_PLLT_IN_A (io), M2 PL18B/LLM0_PLLC_IN_A (io), N1 PL19A (io), P1 PL19B (io)
part H pins: B1 PL2A/LUM0_PLLT_FB_A (io), B2 PL2B/LUM0_PLLC_FB_A (io), C1 PL3C/LUM0_PLLT_IN_A (io), C2 PL4A (io), C3 PL3D/LUM0_PLLC_IN_A (io), D1 PL4B (io), D3 PL4C (io), E2 PL7A (io), E3 PL7B/GSRN (io), F2 PL7D (io), F3 PL9C (io), G1 PL9D (io), G2 PL10C (io), G3 PL10D (io)
part I pins: M5 TDI (in) "Powered by VCCIO5", N5 TDO (out) "Powered by VCCIO5", N12 SLEEPN (in) "Powered by VCCIO4", P3 TMS (in) "Powered by VCCIO5", P4 TCK (in) "Powered by VCCIO5"
part J pins: A7 VCCAUX (power), B11 VCCIO1 (power), C5 VCCIO0 (power), C7 VCC (power), D2 VCCIO7 (power), E12 VCCIO2 (power), G12 VCC (power), H3 VCC (power), K3 VCCIO6 (power), L12 VCCIO3 (power), M10 VCCIO4 (power), N2 VCCIO5 (power), P6 VCC (power), P7 VCCAUX (power)
part K pins: A10 GNDIO1 (power), B4 GNDIO0 (power), C9 GND (power), D13 GNDIO2 (power), E1 GNDIO7 (power), F1 GND (power), J14 GND (power), L2 GNDIO6 (power), L13 GNDIO3 (power), N11 GNDIO4 (power), P2 GNDIO5 (power), P9 GND (power)

## LCMXO2280C-3M132I4W
designator U?
MachXO 2280 Crossover PLD, 1.8V/2.5V/3.3V, 101 User I/Os, 132-Pins csBGA, Speed Grade-3, Industrial Grade
footprint csBGA132 (BGA, 132-Leads, Body 8x8mm, Pitch 0.5mm)
3D model MachXO2280-csBGA132 (132-Ball Chip Scale Ball Grid Array (csBGA132))
signal-integrity model LCMXO2280C_M132 (MachXO)
part A pins: A1 PT2A (io), A2 PT2B (io), A3 PT3B (io), A4 PT4B (io), A5 PT6F (io), A6 PT7B (io), B3 PT3A (io), B5 PT6E (io), B6 PT7A (io), B7 PT8D (io), C4 PT4A (io), C6 PT6D (io), C8 PT9B/PCLK1_0 (io)
part B pins: A8 PT10B/PCLK1_1 (io), A9 PT12C (io), A11 PT14B (io), A12 PT16B (io), A13 PT16D (io), B8 PT9D (io), B9 PT12D (io), B10 PT12F (io), B12 PT15D (io), B13 PT16C (io), C10 PT12E (io), C11 PT14A (io), C12 PT16A (io)
part C pins: A14 PR3A (io), B14 PR3B (io), C13 PR4C (io), C14 PR4D (io), D12 PR5A (io), D14 PR5B (io), E13 PR7B (io), E14 PR7A (io), F12 PR8A (io), F13 PR8B (io), F14 PR8C (io), G13 PR10B (io), G14 PR10A (io)
part D pins: H12 PR11A (io), H13 PR11B (io), H14 PR13A (io), J12 PR13B (io), J13 PR14A (io), K12 PR14B (io), K13 PR15A (io), K14 PR15B (io), L14 PR17A (io), M12 PR18A (io), M13 PR17B (io), M14 PR18B (io), N13 PR19A (io), N14 PR19B (io)
part E pins: M7 PB10F/PCLK4_1 (io), M8 PB10B/PCLK4_0 (io), M9 PB12B (io), M11 PB13D (io), N8 PB10C (io), N9 PB12A (io), N10 PB12C (io), P8 PB10D (io), P10 PB12D (io), P11 PB13C (io), P12 PB15B (io), P13 PB16C (io), P14 PB16D (io)
part F pins: M3 PB2A (io), M4 PB3B (io), M6 PB8A (io), N3 PB2B (io), N4 PB4A (io), N6 PB6C (io), N7 PB8F (io), P5 PB4B (io)
part G pins: H1 PL12B (io), H2 PL12A (io), J1 PL14D (io), J2 PL14C/TSALL (io), J3 PL14B (io), K1 PL15B (io), K2 PL15A (io), L1 PL17A/LLM0_PLLT_FB_A (io), L3 PL17B/LLM0_PLLC_FB_A (io), M1 PL18A/LLM0_PLLT_IN_A (io), M2 PL18B/LLM0_PLLC_IN_A (io), N1 PL19A (io), P1 PL19B (io)
part H pins: B1 PL2A/LUM0_PLLT_FB_A (io), B2 PL2B/LUM0_PLLC_FB_A (io), C1 PL3C/LUM0_PLLT_IN_A (io), C2 PL4A (io), C3 PL3D/LUM0_PLLC_IN_A (io), D1 PL4B (io), D3 PL4C (io), E2 PL7A (io), E3 PL7B/GSRN (io), F2 PL7D (io), F3 PL9C (io), G1 PL9D (io), G2 PL10C (io), G3 PL10D (io)
part I pins: M5 TDI (in) "Powered by VCCIO5", N5 TDO (out) "Powered by VCCIO5", N12 SLEEPN (in) "Powered by VCCIO4", P3 TMS (in) "Powered by VCCIO5", P4 TCK (in) "Powered by VCCIO5"
part J pins: A7 VCCAUX (power), B11 VCCIO1 (power), C5 VCCIO0 (power), C7 VCC (power), D2 VCCIO7 (power), E12 VCCIO2 (power), G12 VCC (power), H3 VCC (power), K3 VCCIO6 (power), L12 VCCIO3 (power), M10 VCCIO4 (power), N2 VCCIO5 (power), P6 VCC (power), P7 VCCAUX (power)
part K pins: A10 GNDIO1 (power), B4 GNDIO0 (power), C9 GND (power), D13 GNDIO2 (power), E1 GNDIO7 (power), F1 GND (power), J14 GND (power), L2 GNDIO6 (power), L13 GNDIO3 (power), N11 GNDIO4 (power), P2 GNDIO5 (power), P9 GND (power)


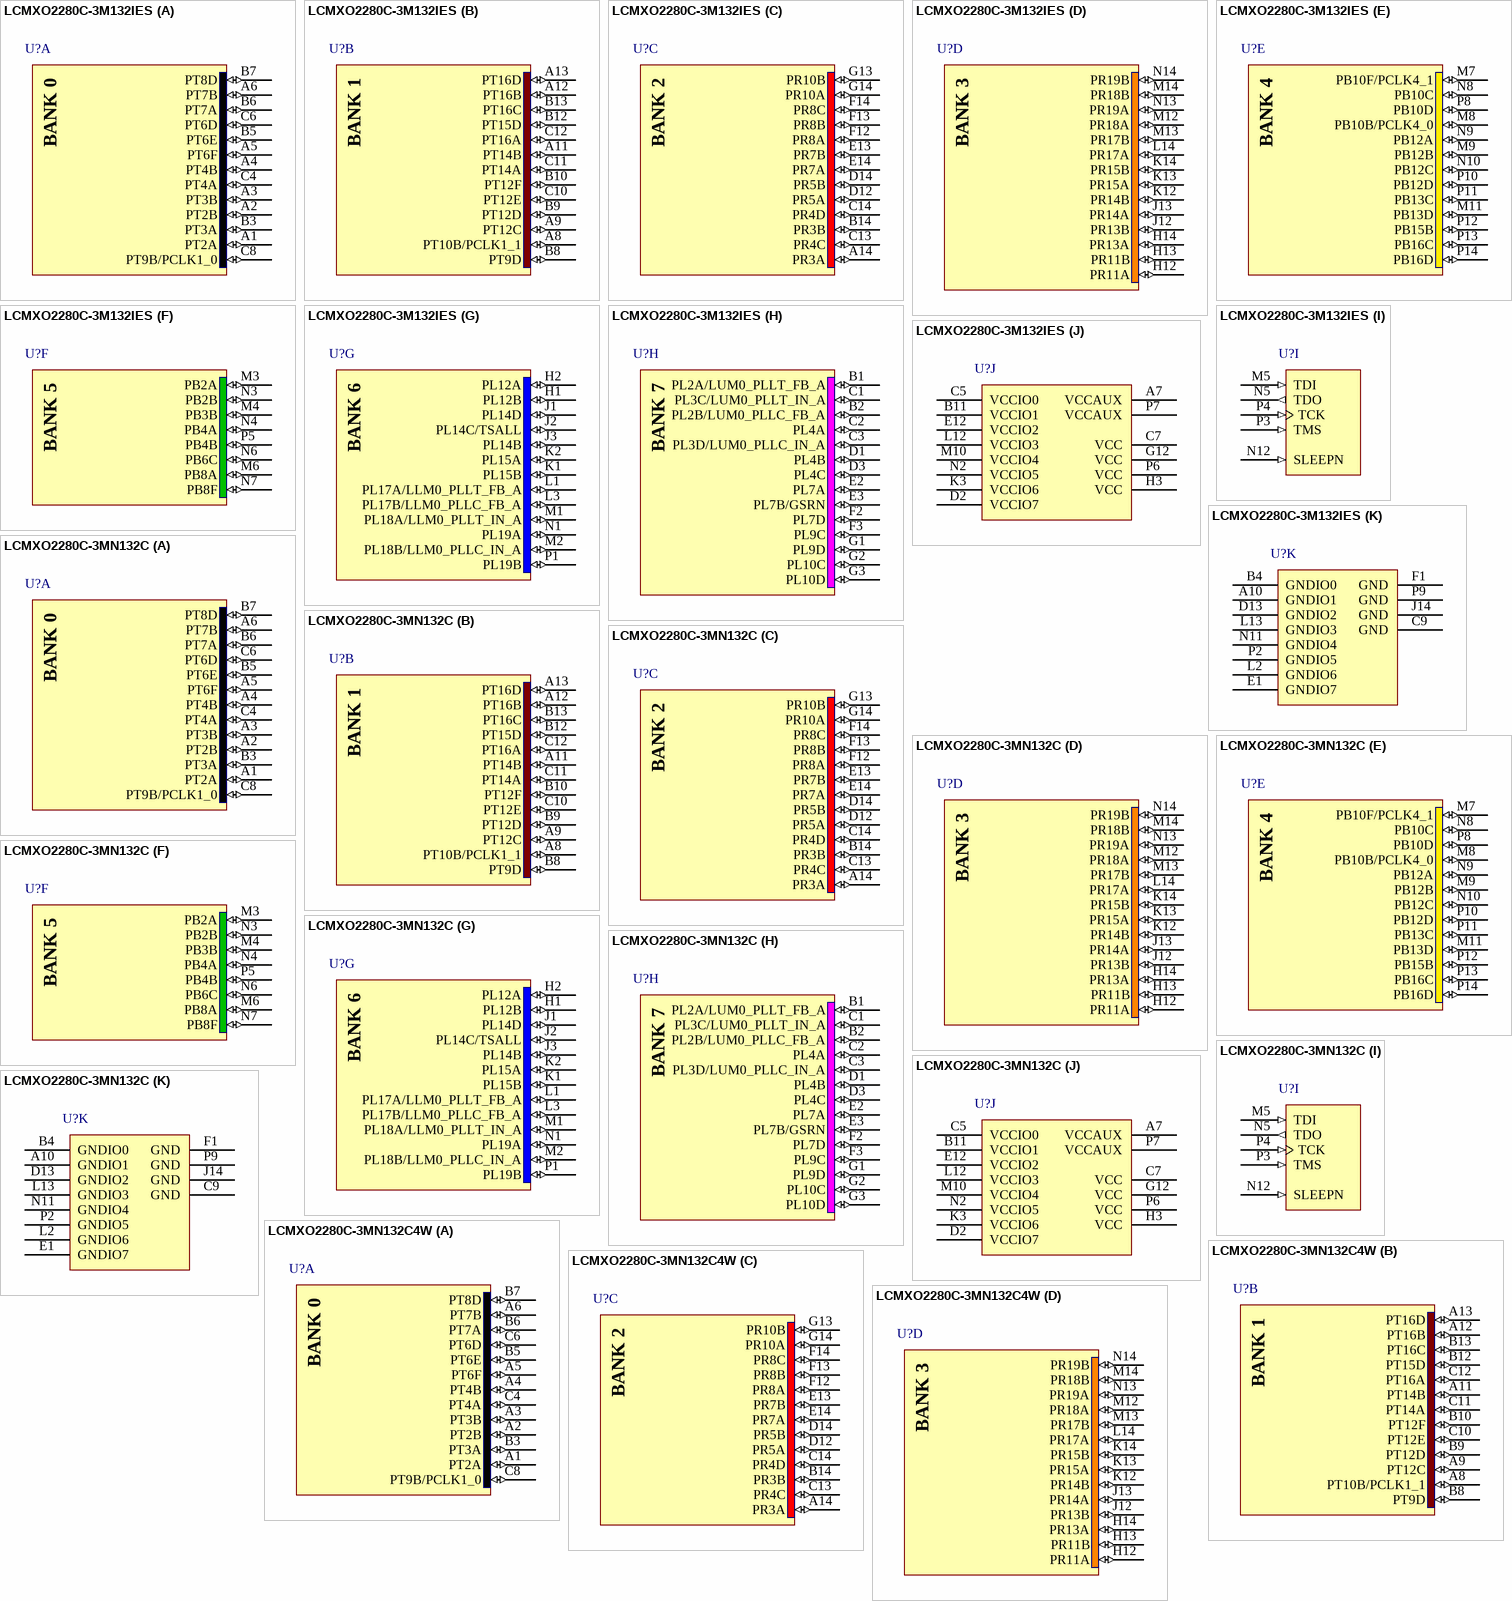
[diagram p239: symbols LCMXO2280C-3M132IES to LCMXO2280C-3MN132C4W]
## LCMXO2280C-3M132IES
designator U?
MachXO 2280 Crossover PLD, 1.8V/2.5V/3.3V, 101 User I/Os, 132-Pins csBGA, Speed Grade-3, Industrial Grade, Engineering Sample
footprint csBGA132 (BGA, 132-Leads, Body 8x8mm, Pitch 0.5mm)
3D model MachXO2280-csBGA132 (132-Ball Chip Scale Ball Grid Array (csBGA132))
signal-integrity model LCMXO2280C_M132 (MachXO)
part A pins: A1 PT2A (io), A2 PT2B (io), A3 PT3B (io), A4 PT4B (io), A5 PT6F (io), A6 PT7B (io), B3 PT3A (io), B5 PT6E (io), B6 PT7A (io), B7 PT8D (io), C4 PT4A (io), C6 PT6D (io), C8 PT9B/PCLK1_0 (io)
part B pins: A8 PT10B/PCLK1_1 (io), A9 PT12C (io), A11 PT14B (io), A12 PT16B (io), A13 PT16D (io), B8 PT9D (io), B9 PT12D (io), B10 PT12F (io), B12 PT15D (io), B13 PT16C (io), C10 PT12E (io), C11 PT14A (io), C12 PT16A (io)
part C pins: A14 PR3A (io), B14 PR3B (io), C13 PR4C (io), C14 PR4D (io), D12 PR5A (io), D14 PR5B (io), E13 PR7B (io), E14 PR7A (io), F12 PR8A (io), F13 PR8B (io), F14 PR8C (io), G13 PR10B (io), G14 PR10A (io)
part D pins: H12 PR11A (io), H13 PR11B (io), H14 PR13A (io), J12 PR13B (io), J13 PR14A (io), K12 PR14B (io), K13 PR15A (io), K14 PR15B (io), L14 PR17A (io), M12 PR18A (io), M13 PR17B (io), M14 PR18B (io), N13 PR19A (io), N14 PR19B (io)
part E pins: M7 PB10F/PCLK4_1 (io), M8 PB10B/PCLK4_0 (io), M9 PB12B (io), M11 PB13D (io), N8 PB10C (io), N9 PB12A (io), N10 PB12C (io), P8 PB10D (io), P10 PB12D (io), P11 PB13C (io), P12 PB15B (io), P13 PB16C (io), P14 PB16D (io)
part F pins: M3 PB2A (io), M4 PB3B (io), M6 PB8A (io), N3 PB2B (io), N4 PB4A (io), N6 PB6C (io), N7 PB8F (io), P5 PB4B (io)
part G pins: H1 PL12B (io), H2 PL12A (io), J1 PL14D (io), J2 PL14C/TSALL (io), J3 PL14B (io), K1 PL15B (io), K2 PL15A (io), L1 PL17A/LLM0_PLLT_FB_A (io), L3 PL17B/LLM0_PLLC_FB_A (io), M1 PL18A/LLM0_PLLT_IN_A (io), M2 PL18B/LLM0_PLLC_IN_A (io), N1 PL19A (io), P1 PL19B (io)
part H pins: B1 PL2A/LUM0_PLLT_FB_A (io), B2 PL2B/LUM0_PLLC_FB_A (io), C1 PL3C/LUM0_PLLT_IN_A (io), C2 PL4A (io), C3 PL3D/LUM0_PLLC_IN_A (io), D1 PL4B (io), D3 PL4C (io), E2 PL7A (io), E3 PL7B/GSRN (io), F2 PL7D (io), F3 PL9C (io), G1 PL9D (io), G2 PL10C (io), G3 PL10D (io)
part I pins: M5 TDI (in) "Powered by VCCIO5", N5 TDO (out) "Powered by VCCIO5", N12 SLEEPN (in) "Powered by VCCIO4", P3 TMS (in) "Powered by VCCIO5", P4 TCK (in) "Powered by VCCIO5"
part J pins: A7 VCCAUX (power), B11 VCCIO1 (power), C5 VCCIO0 (power), C7 VCC (power), D2 VCCIO7 (power), E12 VCCIO2 (power), G12 VCC (power), H3 VCC (power), K3 VCCIO6 (power), L12 VCCIO3 (power), M10 VCCIO4 (power), N2 VCCIO5 (power), P6 VCC (power), P7 VCCAUX (power)
part K pins: A10 GNDIO1 (power), B4 GNDIO0 (power), C9 GND (power), D13 GNDIO2 (power), E1 GNDIO7 (power), F1 GND (power), J14 GND (power), L2 GNDIO6 (power), L13 GNDIO3 (power), N11 GNDIO4 (power), P2 GNDIO5 (power), P9 GND (power)

## LCMXO2280C-3MN132C
designator U?
MachXO 2280 Crossover PLD, 1.8V/2.5V/3.3V, 101 User I/Os, 132-Pins csBGA, Speed Grade-3, Commercial Grade, Pb-Free
footprint csBGA132 (BGA, 132-Leads, Body 8x8mm, Pitch 0.5mm)
3D model MachXO2280-csBGA132 (132-Ball Chip Scale Ball Grid Array (csBGA132))
signal-integrity model LCMXO2280C_M132 (MachXO)
part A pins: A1 PT2A (io), A2 PT2B (io), A3 PT3B (io), A4 PT4B (io), A5 PT6F (io), A6 PT7B (io), B3 PT3A (io), B5 PT6E (io), B6 PT7A (io), B7 PT8D (io), C4 PT4A (io), C6 PT6D (io), C8 PT9B/PCLK1_0 (io)
part B pins: A8 PT10B/PCLK1_1 (io), A9 PT12C (io), A11 PT14B (io), A12 PT16B (io), A13 PT16D (io), B8 PT9D (io), B9 PT12D (io), B10 PT12F (io), B12 PT15D (io), B13 PT16C (io), C10 PT12E (io), C11 PT14A (io), C12 PT16A (io)
part C pins: A14 PR3A (io), B14 PR3B (io), C13 PR4C (io), C14 PR4D (io), D12 PR5A (io), D14 PR5B (io), E13 PR7B (io), E14 PR7A (io), F12 PR8A (io), F13 PR8B (io), F14 PR8C (io), G13 PR10B (io), G14 PR10A (io)
part D pins: H12 PR11A (io), H13 PR11B (io), H14 PR13A (io), J12 PR13B (io), J13 PR14A (io), K12 PR14B (io), K13 PR15A (io), K14 PR15B (io), L14 PR17A (io), M12 PR18A (io), M13 PR17B (io), M14 PR18B (io), N13 PR19A (io), N14 PR19B (io)
part E pins: M7 PB10F/PCLK4_1 (io), M8 PB10B/PCLK4_0 (io), M9 PB12B (io), M11 PB13D (io), N8 PB10C (io), N9 PB12A (io), N10 PB12C (io), P8 PB10D (io), P10 PB12D (io), P11 PB13C (io), P12 PB15B (io), P13 PB16C (io), P14 PB16D (io)
part F pins: M3 PB2A (io), M4 PB3B (io), M6 PB8A (io), N3 PB2B (io), N4 PB4A (io), N6 PB6C (io), N7 PB8F (io), P5 PB4B (io)
part G pins: H1 PL12B (io), H2 PL12A (io), J1 PL14D (io), J2 PL14C/TSALL (io), J3 PL14B (io), K1 PL15B (io), K2 PL15A (io), L1 PL17A/LLM0_PLLT_FB_A (io), L3 PL17B/LLM0_PLLC_FB_A (io), M1 PL18A/LLM0_PLLT_IN_A (io), M2 PL18B/LLM0_PLLC_IN_A (io), N1 PL19A (io), P1 PL19B (io)
part H pins: B1 PL2A/LUM0_PLLT_FB_A (io), B2 PL2B/LUM0_PLLC_FB_A (io), C1 PL3C/LUM0_PLLT_IN_A (io), C2 PL4A (io), C3 PL3D/LUM0_PLLC_IN_A (io), D1 PL4B (io), D3 PL4C (io), E2 PL7A (io), E3 PL7B/GSRN (io), F2 PL7D (io), F3 PL9C (io), G1 PL9D (io), G2 PL10C (io), G3 PL10D (io)
part I pins: M5 TDI (in) "Powered by VCCIO5", N5 TDO (out) "Powered by VCCIO5", N12 SLEEPN (in) "Powered by VCCIO4", P3 TMS (in) "Powered by VCCIO5", P4 TCK (in) "Powered by VCCIO5"
part J pins: A7 VCCAUX (power), B11 VCCIO1 (power), C5 VCCIO0 (power), C7 VCC (power), D2 VCCIO7 (power), E12 VCCIO2 (power), G12 VCC (power), H3 VCC (power), K3 VCCIO6 (power), L12 VCCIO3 (power), M10 VCCIO4 (power), N2 VCCIO5 (power), P6 VCC (power), P7 VCCAUX (power)
part K pins: A10 GNDIO1 (power), B4 GNDIO0 (power), C9 GND (power), D13 GNDIO2 (power), E1 GNDIO7 (power), F1 GND (power), J14 GND (power), L2 GNDIO6 (power), L13 GNDIO3 (power), N11 GNDIO4 (power), P2 GNDIO5 (power), P9 GND (power)


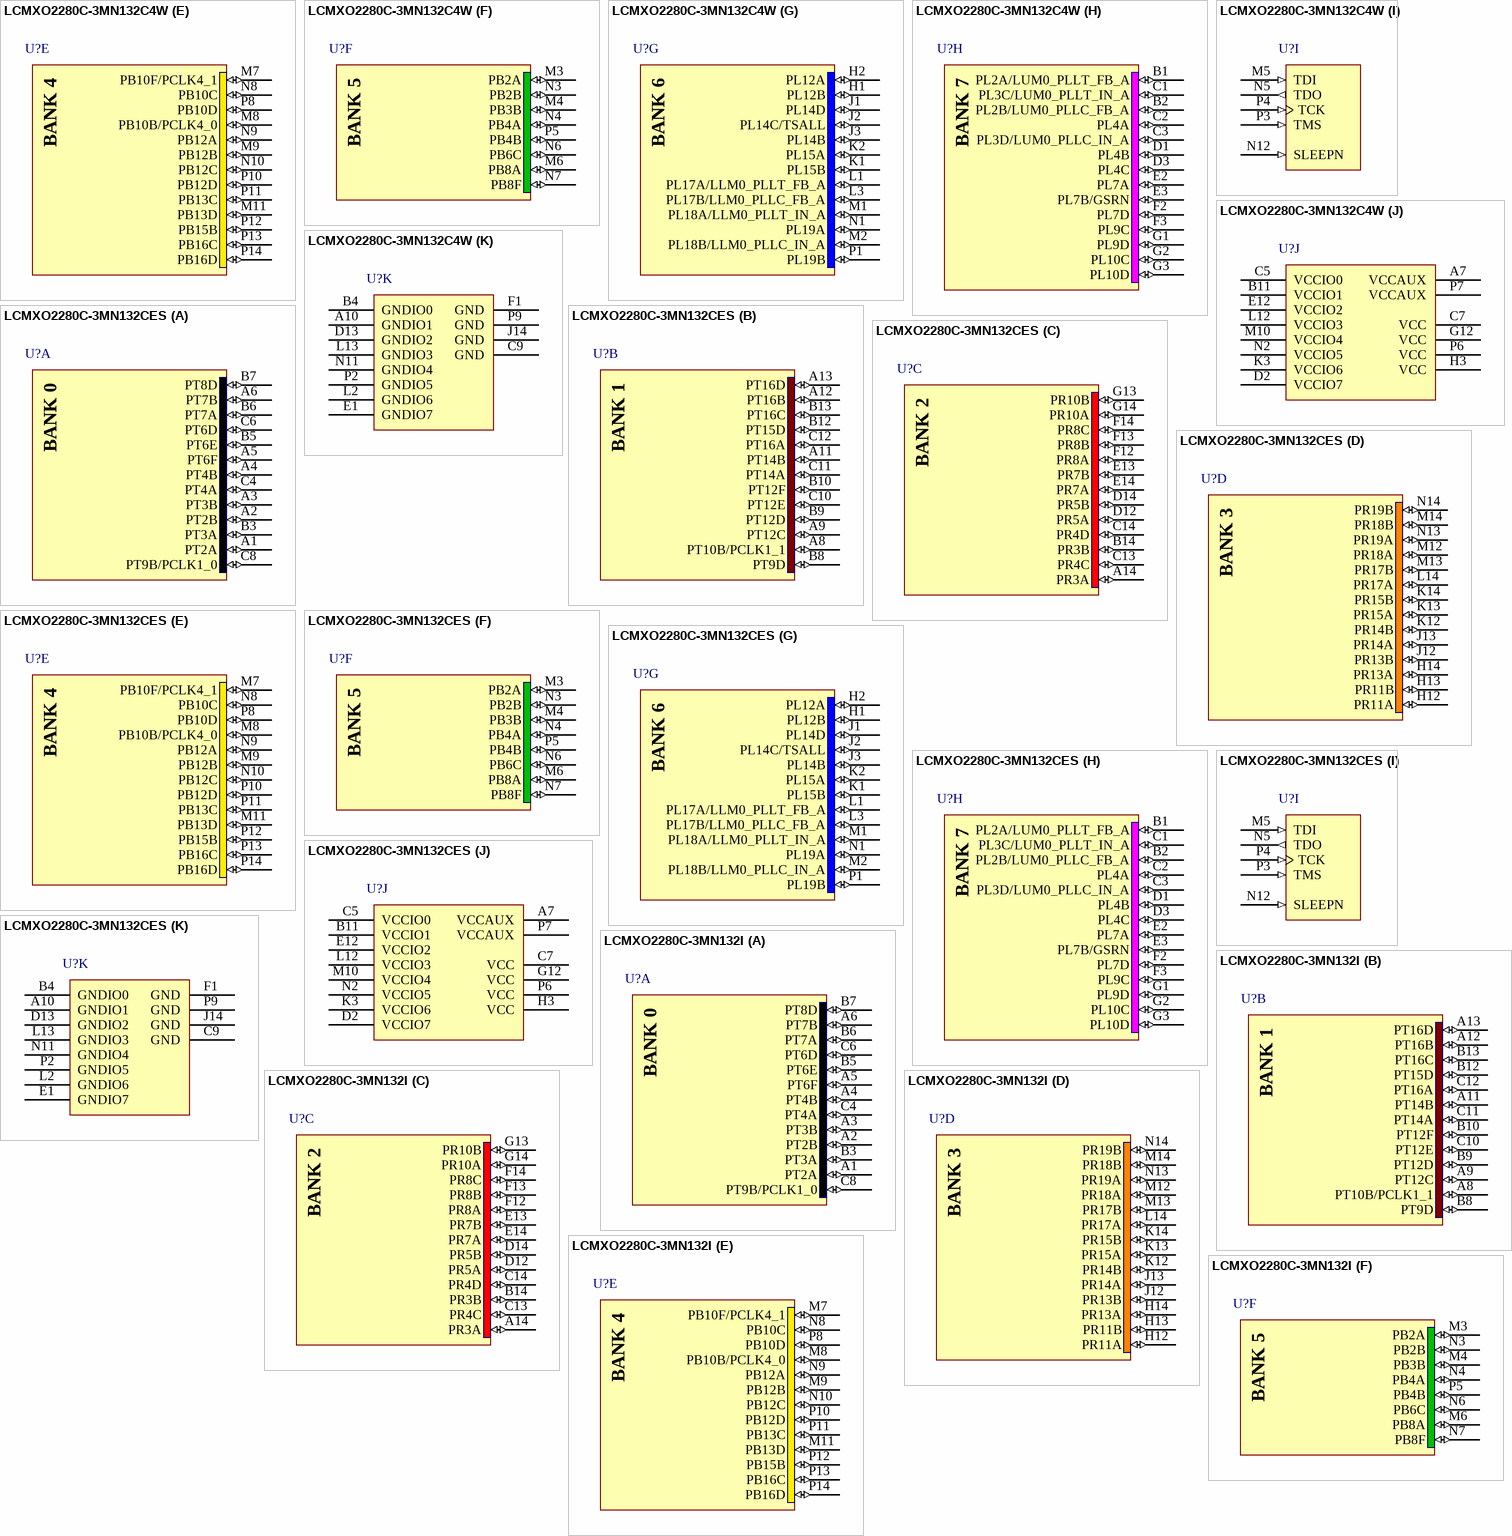
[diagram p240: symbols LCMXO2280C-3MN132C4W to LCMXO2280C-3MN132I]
## LCMXO2280C-3MN132C4W
designator U?
MachXO 2280 Crossover PLD, 1.8V/2.5V/3.3V, 101 User I/Os, 132-Pins csBGA, Speed Grade-3, Commercial Grade, Pb-Free
footprint csBGA132 (BGA, 132-Leads, Body 8x8mm, Pitch 0.5mm)
3D model MachXO2280-csBGA132 (132-Ball Chip Scale Ball Grid Array (csBGA132))
signal-integrity model LCMXO2280C_M132 (MachXO)
part A pins: A1 PT2A (io), A2 PT2B (io), A3 PT3B (io), A4 PT4B (io), A5 PT6F (io), A6 PT7B (io), B3 PT3A (io), B5 PT6E (io), B6 PT7A (io), B7 PT8D (io), C4 PT4A (io), C6 PT6D (io), C8 PT9B/PCLK1_0 (io)
part B pins: A8 PT10B/PCLK1_1 (io), A9 PT12C (io), A11 PT14B (io), A12 PT16B (io), A13 PT16D (io), B8 PT9D (io), B9 PT12D (io), B10 PT12F (io), B12 PT15D (io), B13 PT16C (io), C10 PT12E (io), C11 PT14A (io), C12 PT16A (io)
part C pins: A14 PR3A (io), B14 PR3B (io), C13 PR4C (io), C14 PR4D (io), D12 PR5A (io), D14 PR5B (io), E13 PR7B (io), E14 PR7A (io), F12 PR8A (io), F13 PR8B (io), F14 PR8C (io), G13 PR10B (io), G14 PR10A (io)
part D pins: H12 PR11A (io), H13 PR11B (io), H14 PR13A (io), J12 PR13B (io), J13 PR14A (io), K12 PR14B (io), K13 PR15A (io), K14 PR15B (io), L14 PR17A (io), M12 PR18A (io), M13 PR17B (io), M14 PR18B (io), N13 PR19A (io), N14 PR19B (io)
part E pins: M7 PB10F/PCLK4_1 (io), M8 PB10B/PCLK4_0 (io), M9 PB12B (io), M11 PB13D (io), N8 PB10C (io), N9 PB12A (io), N10 PB12C (io), P8 PB10D (io), P10 PB12D (io), P11 PB13C (io), P12 PB15B (io), P13 PB16C (io), P14 PB16D (io)
part F pins: M3 PB2A (io), M4 PB3B (io), M6 PB8A (io), N3 PB2B (io), N4 PB4A (io), N6 PB6C (io), N7 PB8F (io), P5 PB4B (io)
part G pins: H1 PL12B (io), H2 PL12A (io), J1 PL14D (io), J2 PL14C/TSALL (io), J3 PL14B (io), K1 PL15B (io), K2 PL15A (io), L1 PL17A/LLM0_PLLT_FB_A (io), L3 PL17B/LLM0_PLLC_FB_A (io), M1 PL18A/LLM0_PLLT_IN_A (io), M2 PL18B/LLM0_PLLC_IN_A (io), N1 PL19A (io), P1 PL19B (io)
part H pins: B1 PL2A/LUM0_PLLT_FB_A (io), B2 PL2B/LUM0_PLLC_FB_A (io), C1 PL3C/LUM0_PLLT_IN_A (io), C2 PL4A (io), C3 PL3D/LUM0_PLLC_IN_A (io), D1 PL4B (io), D3 PL4C (io), E2 PL7A (io), E3 PL7B/GSRN (io), F2 PL7D (io), F3 PL9C (io), G1 PL9D (io), G2 PL10C (io), G3 PL10D (io)
part I pins: M5 TDI (in) "Powered by VCCIO5", N5 TDO (out) "Powered by VCCIO5", N12 SLEEPN (in) "Powered by VCCIO4", P3 TMS (in) "Powered by VCCIO5", P4 TCK (in) "Powered by VCCIO5"
part J pins: A7 VCCAUX (power), B11 VCCIO1 (power), C5 VCCIO0 (power), C7 VCC (power), D2 VCCIO7 (power), E12 VCCIO2 (power), G12 VCC (power), H3 VCC (power), K3 VCCIO6 (power), L12 VCCIO3 (power), M10 VCCIO4 (power), N2 VCCIO5 (power), P6 VCC (power), P7 VCCAUX (power)
part K pins: A10 GNDIO1 (power), B4 GNDIO0 (power), C9 GND (power), D13 GNDIO2 (power), E1 GNDIO7 (power), F1 GND (power), J14 GND (power), L2 GNDIO6 (power), L13 GNDIO3 (power), N11 GNDIO4 (power), P2 GNDIO5 (power), P9 GND (power)

## LCMXO2280C-3MN132CES
designator U?
MachXO 2280 Crossover PLD, 1.8V/2.5V/3.3V, 101 User I/Os, 132-Pins csBGA, Speed Grade-3, Commercial Grade, Pb-Free, Engineering Sample
footprint csBGA132 (BGA, 132-Leads, Body 8x8mm, Pitch 0.5mm)
3D model MachXO2280-csBGA132 (132-Ball Chip Scale Ball Grid Array (csBGA132))
signal-integrity model LCMXO2280C_M132 (MachXO)
part A pins: A1 PT2A (io), A2 PT2B (io), A3 PT3B (io), A4 PT4B (io), A5 PT6F (io), A6 PT7B (io), B3 PT3A (io), B5 PT6E (io), B6 PT7A (io), B7 PT8D (io), C4 PT4A (io), C6 PT6D (io), C8 PT9B/PCLK1_0 (io)
part B pins: A8 PT10B/PCLK1_1 (io), A9 PT12C (io), A11 PT14B (io), A12 PT16B (io), A13 PT16D (io), B8 PT9D (io), B9 PT12D (io), B10 PT12F (io), B12 PT15D (io), B13 PT16C (io), C10 PT12E (io), C11 PT14A (io), C12 PT16A (io)
part C pins: A14 PR3A (io), B14 PR3B (io), C13 PR4C (io), C14 PR4D (io), D12 PR5A (io), D14 PR5B (io), E13 PR7B (io), E14 PR7A (io), F12 PR8A (io), F13 PR8B (io), F14 PR8C (io), G13 PR10B (io), G14 PR10A (io)
part D pins: H12 PR11A (io), H13 PR11B (io), H14 PR13A (io), J12 PR13B (io), J13 PR14A (io), K12 PR14B (io), K13 PR15A (io), K14 PR15B (io), L14 PR17A (io), M12 PR18A (io), M13 PR17B (io), M14 PR18B (io), N13 PR19A (io), N14 PR19B (io)
part E pins: M7 PB10F/PCLK4_1 (io), M8 PB10B/PCLK4_0 (io), M9 PB12B (io), M11 PB13D (io), N8 PB10C (io), N9 PB12A (io), N10 PB12C (io), P8 PB10D (io), P10 PB12D (io), P11 PB13C (io), P12 PB15B (io), P13 PB16C (io), P14 PB16D (io)
part F pins: M3 PB2A (io), M4 PB3B (io), M6 PB8A (io), N3 PB2B (io), N4 PB4A (io), N6 PB6C (io), N7 PB8F (io), P5 PB4B (io)
part G pins: H1 PL12B (io), H2 PL12A (io), J1 PL14D (io), J2 PL14C/TSALL (io), J3 PL14B (io), K1 PL15B (io), K2 PL15A (io), L1 PL17A/LLM0_PLLT_FB_A (io), L3 PL17B/LLM0_PLLC_FB_A (io), M1 PL18A/LLM0_PLLT_IN_A (io), M2 PL18B/LLM0_PLLC_IN_A (io), N1 PL19A (io), P1 PL19B (io)
part H pins: B1 PL2A/LUM0_PLLT_FB_A (io), B2 PL2B/LUM0_PLLC_FB_A (io), C1 PL3C/LUM0_PLLT_IN_A (io), C2 PL4A (io), C3 PL3D/LUM0_PLLC_IN_A (io), D1 PL4B (io), D3 PL4C (io), E2 PL7A (io), E3 PL7B/GSRN (io), F2 PL7D (io), F3 PL9C (io), G1 PL9D (io), G2 PL10C (io), G3 PL10D (io)
part I pins: M5 TDI (in) "Powered by VCCIO5", N5 TDO (out) "Powered by VCCIO5", N12 SLEEPN (in) "Powered by VCCIO4", P3 TMS (in) "Powered by VCCIO5", P4 TCK (in) "Powered by VCCIO5"
part J pins: A7 VCCAUX (power), B11 VCCIO1 (power), C5 VCCIO0 (power), C7 VCC (power), D2 VCCIO7 (power), E12 VCCIO2 (power), G12 VCC (power), H3 VCC (power), K3 VCCIO6 (power), L12 VCCIO3 (power), M10 VCCIO4 (power), N2 VCCIO5 (power), P6 VCC (power), P7 VCCAUX (power)
part K pins: A10 GNDIO1 (power), B4 GNDIO0 (power), C9 GND (power), D13 GNDIO2 (power), E1 GNDIO7 (power), F1 GND (power), J14 GND (power), L2 GNDIO6 (power), L13 GNDIO3 (power), N11 GNDIO4 (power), P2 GNDIO5 (power), P9 GND (power)


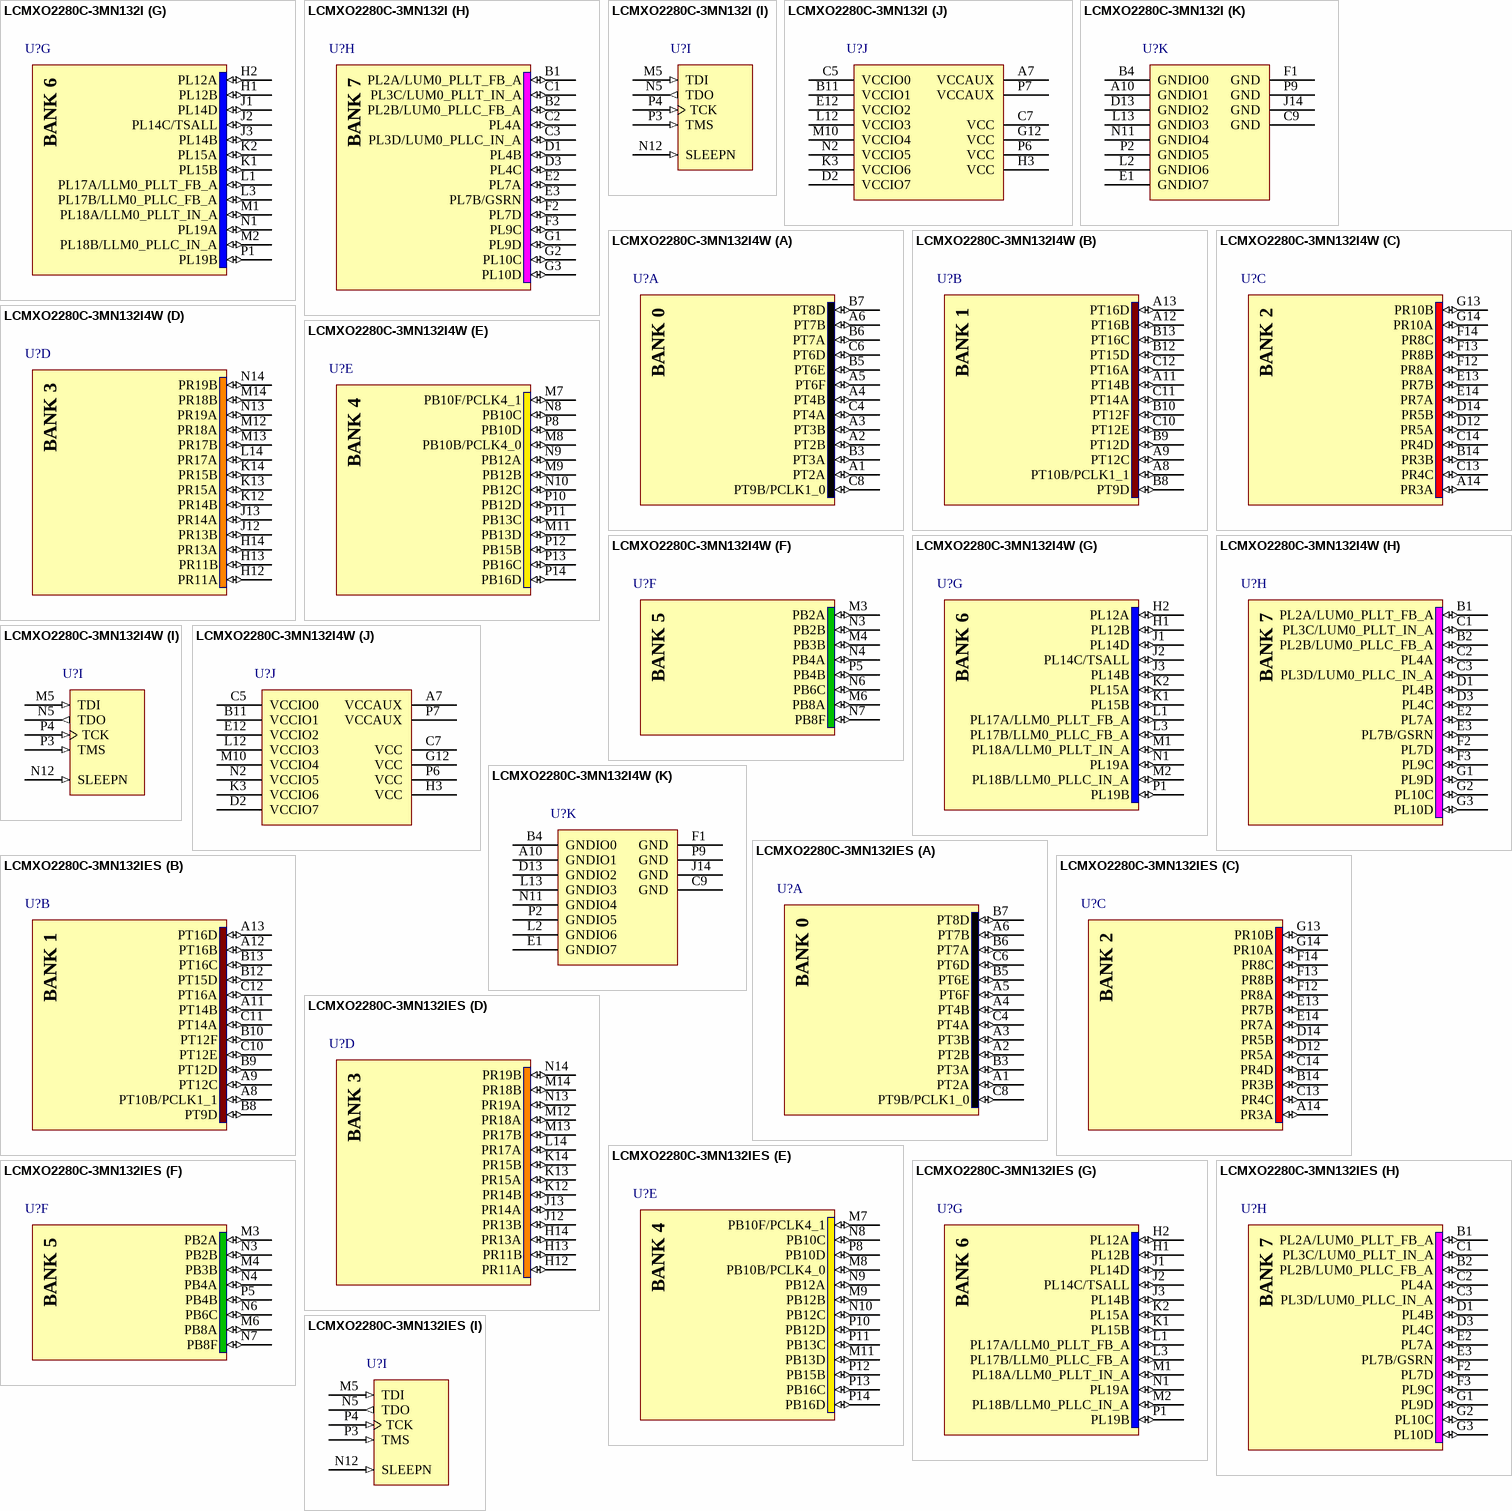
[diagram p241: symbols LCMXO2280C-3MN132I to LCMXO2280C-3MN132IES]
## LCMXO2280C-3MN132I
designator U?
MachXO 2280 Crossover PLD, 1.8V/2.5V/3.3V, 101 User I/Os, 132-Pins csBGA, Speed Grade-3, Industrial Grade, Pb-Free
footprint csBGA132 (BGA, 132-Leads, Body 8x8mm, Pitch 0.5mm)
3D model MachXO2280-csBGA132 (132-Ball Chip Scale Ball Grid Array (csBGA132))
signal-integrity model LCMXO2280C_M132 (MachXO)
part A pins: A1 PT2A (io), A2 PT2B (io), A3 PT3B (io), A4 PT4B (io), A5 PT6F (io), A6 PT7B (io), B3 PT3A (io), B5 PT6E (io), B6 PT7A (io), B7 PT8D (io), C4 PT4A (io), C6 PT6D (io), C8 PT9B/PCLK1_0 (io)
part B pins: A8 PT10B/PCLK1_1 (io), A9 PT12C (io), A11 PT14B (io), A12 PT16B (io), A13 PT16D (io), B8 PT9D (io), B9 PT12D (io), B10 PT12F (io), B12 PT15D (io), B13 PT16C (io), C10 PT12E (io), C11 PT14A (io), C12 PT16A (io)
part C pins: A14 PR3A (io), B14 PR3B (io), C13 PR4C (io), C14 PR4D (io), D12 PR5A (io), D14 PR5B (io), E13 PR7B (io), E14 PR7A (io), F12 PR8A (io), F13 PR8B (io), F14 PR8C (io), G13 PR10B (io), G14 PR10A (io)
part D pins: H12 PR11A (io), H13 PR11B (io), H14 PR13A (io), J12 PR13B (io), J13 PR14A (io), K12 PR14B (io), K13 PR15A (io), K14 PR15B (io), L14 PR17A (io), M12 PR18A (io), M13 PR17B (io), M14 PR18B (io), N13 PR19A (io), N14 PR19B (io)
part E pins: M7 PB10F/PCLK4_1 (io), M8 PB10B/PCLK4_0 (io), M9 PB12B (io), M11 PB13D (io), N8 PB10C (io), N9 PB12A (io), N10 PB12C (io), P8 PB10D (io), P10 PB12D (io), P11 PB13C (io), P12 PB15B (io), P13 PB16C (io), P14 PB16D (io)
part F pins: M3 PB2A (io), M4 PB3B (io), M6 PB8A (io), N3 PB2B (io), N4 PB4A (io), N6 PB6C (io), N7 PB8F (io), P5 PB4B (io)
part G pins: H1 PL12B (io), H2 PL12A (io), J1 PL14D (io), J2 PL14C/TSALL (io), J3 PL14B (io), K1 PL15B (io), K2 PL15A (io), L1 PL17A/LLM0_PLLT_FB_A (io), L3 PL17B/LLM0_PLLC_FB_A (io), M1 PL18A/LLM0_PLLT_IN_A (io), M2 PL18B/LLM0_PLLC_IN_A (io), N1 PL19A (io), P1 PL19B (io)
part H pins: B1 PL2A/LUM0_PLLT_FB_A (io), B2 PL2B/LUM0_PLLC_FB_A (io), C1 PL3C/LUM0_PLLT_IN_A (io), C2 PL4A (io), C3 PL3D/LUM0_PLLC_IN_A (io), D1 PL4B (io), D3 PL4C (io), E2 PL7A (io), E3 PL7B/GSRN (io), F2 PL7D (io), F3 PL9C (io), G1 PL9D (io), G2 PL10C (io), G3 PL10D (io)
part I pins: M5 TDI (in) "Powered by VCCIO5", N5 TDO (out) "Powered by VCCIO5", N12 SLEEPN (in) "Powered by VCCIO4", P3 TMS (in) "Powered by VCCIO5", P4 TCK (in) "Powered by VCCIO5"
part J pins: A7 VCCAUX (power), B11 VCCIO1 (power), C5 VCCIO0 (power), C7 VCC (power), D2 VCCIO7 (power), E12 VCCIO2 (power), G12 VCC (power), H3 VCC (power), K3 VCCIO6 (power), L12 VCCIO3 (power), M10 VCCIO4 (power), N2 VCCIO5 (power), P6 VCC (power), P7 VCCAUX (power)
part K pins: A10 GNDIO1 (power), B4 GNDIO0 (power), C9 GND (power), D13 GNDIO2 (power), E1 GNDIO7 (power), F1 GND (power), J14 GND (power), L2 GNDIO6 (power), L13 GNDIO3 (power), N11 GNDIO4 (power), P2 GNDIO5 (power), P9 GND (power)

## LCMXO2280C-3MN132I4W
designator U?
MachXO 2280 Crossover PLD, 1.8V/2.5V/3.3V, 101 User I/Os, 132-Pins csBGA, Speed Grade-3, Industrial Grade, Pb-Free
footprint csBGA132 (BGA, 132-Leads, Body 8x8mm, Pitch 0.5mm)
3D model MachXO2280-csBGA132 (132-Ball Chip Scale Ball Grid Array (csBGA132))
signal-integrity model LCMXO2280C_M132 (MachXO)
part A pins: A1 PT2A (io), A2 PT2B (io), A3 PT3B (io), A4 PT4B (io), A5 PT6F (io), A6 PT7B (io), B3 PT3A (io), B5 PT6E (io), B6 PT7A (io), B7 PT8D (io), C4 PT4A (io), C6 PT6D (io), C8 PT9B/PCLK1_0 (io)
part B pins: A8 PT10B/PCLK1_1 (io), A9 PT12C (io), A11 PT14B (io), A12 PT16B (io), A13 PT16D (io), B8 PT9D (io), B9 PT12D (io), B10 PT12F (io), B12 PT15D (io), B13 PT16C (io), C10 PT12E (io), C11 PT14A (io), C12 PT16A (io)
part C pins: A14 PR3A (io), B14 PR3B (io), C13 PR4C (io), C14 PR4D (io), D12 PR5A (io), D14 PR5B (io), E13 PR7B (io), E14 PR7A (io), F12 PR8A (io), F13 PR8B (io), F14 PR8C (io), G13 PR10B (io), G14 PR10A (io)
part D pins: H12 PR11A (io), H13 PR11B (io), H14 PR13A (io), J12 PR13B (io), J13 PR14A (io), K12 PR14B (io), K13 PR15A (io), K14 PR15B (io), L14 PR17A (io), M12 PR18A (io), M13 PR17B (io), M14 PR18B (io), N13 PR19A (io), N14 PR19B (io)
part E pins: M7 PB10F/PCLK4_1 (io), M8 PB10B/PCLK4_0 (io), M9 PB12B (io), M11 PB13D (io), N8 PB10C (io), N9 PB12A (io), N10 PB12C (io), P8 PB10D (io), P10 PB12D (io), P11 PB13C (io), P12 PB15B (io), P13 PB16C (io), P14 PB16D (io)
part F pins: M3 PB2A (io), M4 PB3B (io), M6 PB8A (io), N3 PB2B (io), N4 PB4A (io), N6 PB6C (io), N7 PB8F (io), P5 PB4B (io)
part G pins: H1 PL12B (io), H2 PL12A (io), J1 PL14D (io), J2 PL14C/TSALL (io), J3 PL14B (io), K1 PL15B (io), K2 PL15A (io), L1 PL17A/LLM0_PLLT_FB_A (io), L3 PL17B/LLM0_PLLC_FB_A (io), M1 PL18A/LLM0_PLLT_IN_A (io), M2 PL18B/LLM0_PLLC_IN_A (io), N1 PL19A (io), P1 PL19B (io)
part H pins: B1 PL2A/LUM0_PLLT_FB_A (io), B2 PL2B/LUM0_PLLC_FB_A (io), C1 PL3C/LUM0_PLLT_IN_A (io), C2 PL4A (io), C3 PL3D/LUM0_PLLC_IN_A (io), D1 PL4B (io), D3 PL4C (io), E2 PL7A (io), E3 PL7B/GSRN (io), F2 PL7D (io), F3 PL9C (io), G1 PL9D (io), G2 PL10C (io), G3 PL10D (io)
part I pins: M5 TDI (in) "Powered by VCCIO5", N5 TDO (out) "Powered by VCCIO5", N12 SLEEPN (in) "Powered by VCCIO4", P3 TMS (in) "Powered by VCCIO5", P4 TCK (in) "Powered by VCCIO5"
part J pins: A7 VCCAUX (power), B11 VCCIO1 (power), C5 VCCIO0 (power), C7 VCC (power), D2 VCCIO7 (power), E12 VCCIO2 (power), G12 VCC (power), H3 VCC (power), K3 VCCIO6 (power), L12 VCCIO3 (power), M10 VCCIO4 (power), N2 VCCIO5 (power), P6 VCC (power), P7 VCCAUX (power)
part K pins: A10 GNDIO1 (power), B4 GNDIO0 (power), C9 GND (power), D13 GNDIO2 (power), E1 GNDIO7 (power), F1 GND (power), J14 GND (power), L2 GNDIO6 (power), L13 GNDIO3 (power), N11 GNDIO4 (power), P2 GNDIO5 (power), P9 GND (power)


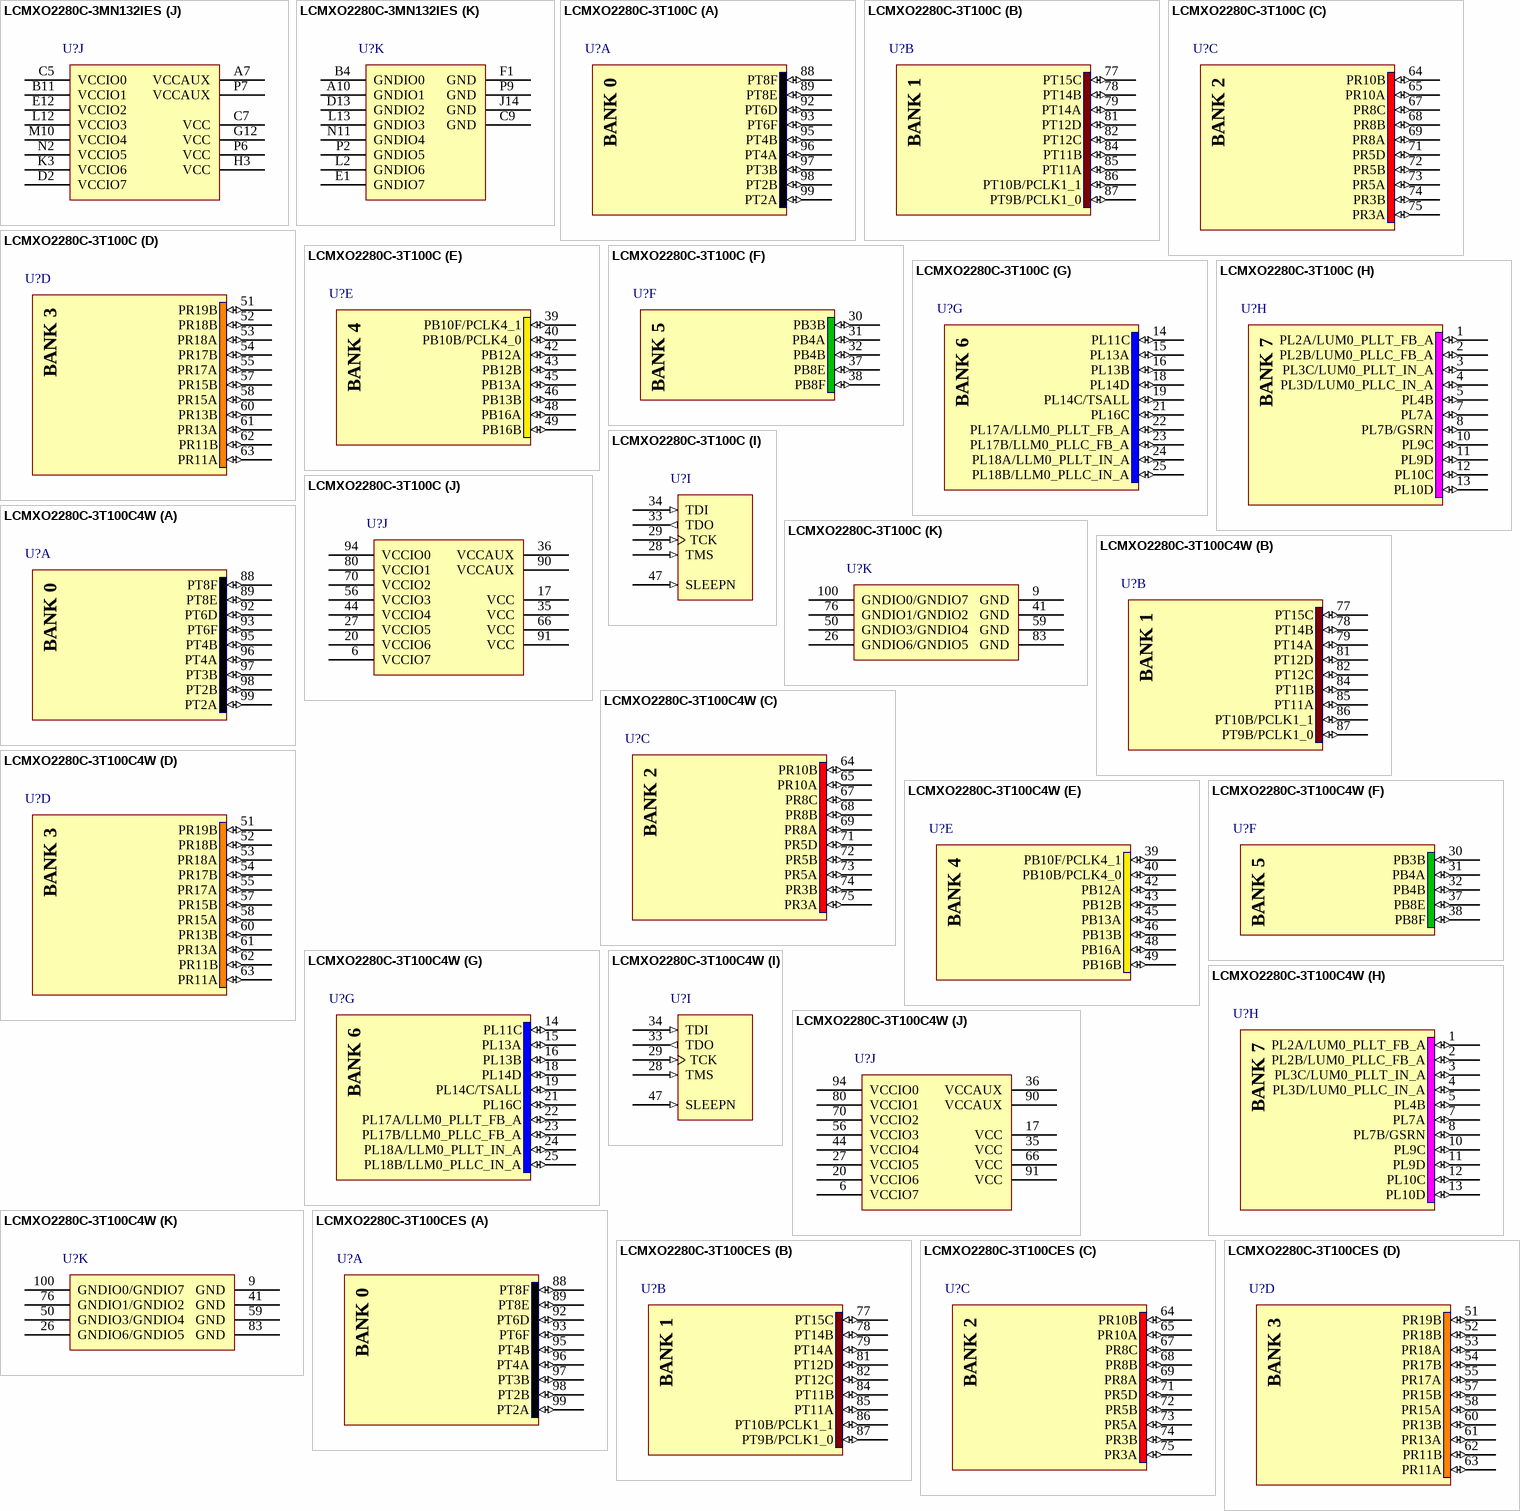
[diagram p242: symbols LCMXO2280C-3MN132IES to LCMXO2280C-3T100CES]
## LCMXO2280C-3MN132IES
designator U?
MachXO 2280 Crossover PLD, 1.8V/2.5V/3.3V, 101 User I/Os, 132-Pins csBGA, Speed Grade-3, Industrial Grade, Pb-Free, Engineering Sample
footprint csBGA132 (BGA, 132-Leads, Body 8x8mm, Pitch 0.5mm)
3D model MachXO2280-csBGA132 (132-Ball Chip Scale Ball Grid Array (csBGA132))
signal-integrity model LCMXO2280C_M132 (MachXO)
part A pins: A1 PT2A (io), A2 PT2B (io), A3 PT3B (io), A4 PT4B (io), A5 PT6F (io), A6 PT7B (io), B3 PT3A (io), B5 PT6E (io), B6 PT7A (io), B7 PT8D (io), C4 PT4A (io), C6 PT6D (io), C8 PT9B/PCLK1_0 (io)
part B pins: A8 PT10B/PCLK1_1 (io), A9 PT12C (io), A11 PT14B (io), A12 PT16B (io), A13 PT16D (io), B8 PT9D (io), B9 PT12D (io), B10 PT12F (io), B12 PT15D (io), B13 PT16C (io), C10 PT12E (io), C11 PT14A (io), C12 PT16A (io)
part C pins: A14 PR3A (io), B14 PR3B (io), C13 PR4C (io), C14 PR4D (io), D12 PR5A (io), D14 PR5B (io), E13 PR7B (io), E14 PR7A (io), F12 PR8A (io), F13 PR8B (io), F14 PR8C (io), G13 PR10B (io), G14 PR10A (io)
part D pins: H12 PR11A (io), H13 PR11B (io), H14 PR13A (io), J12 PR13B (io), J13 PR14A (io), K12 PR14B (io), K13 PR15A (io), K14 PR15B (io), L14 PR17A (io), M12 PR18A (io), M13 PR17B (io), M14 PR18B (io), N13 PR19A (io), N14 PR19B (io)
part E pins: M7 PB10F/PCLK4_1 (io), M8 PB10B/PCLK4_0 (io), M9 PB12B (io), M11 PB13D (io), N8 PB10C (io), N9 PB12A (io), N10 PB12C (io), P8 PB10D (io), P10 PB12D (io), P11 PB13C (io), P12 PB15B (io), P13 PB16C (io), P14 PB16D (io)
part F pins: M3 PB2A (io), M4 PB3B (io), M6 PB8A (io), N3 PB2B (io), N4 PB4A (io), N6 PB6C (io), N7 PB8F (io), P5 PB4B (io)
part G pins: H1 PL12B (io), H2 PL12A (io), J1 PL14D (io), J2 PL14C/TSALL (io), J3 PL14B (io), K1 PL15B (io), K2 PL15A (io), L1 PL17A/LLM0_PLLT_FB_A (io), L3 PL17B/LLM0_PLLC_FB_A (io), M1 PL18A/LLM0_PLLT_IN_A (io), M2 PL18B/LLM0_PLLC_IN_A (io), N1 PL19A (io), P1 PL19B (io)
part H pins: B1 PL2A/LUM0_PLLT_FB_A (io), B2 PL2B/LUM0_PLLC_FB_A (io), C1 PL3C/LUM0_PLLT_IN_A (io), C2 PL4A (io), C3 PL3D/LUM0_PLLC_IN_A (io), D1 PL4B (io), D3 PL4C (io), E2 PL7A (io), E3 PL7B/GSRN (io), F2 PL7D (io), F3 PL9C (io), G1 PL9D (io), G2 PL10C (io), G3 PL10D (io)
part I pins: M5 TDI (in) "Powered by VCCIO5", N5 TDO (out) "Powered by VCCIO5", N12 SLEEPN (in) "Powered by VCCIO4", P3 TMS (in) "Powered by VCCIO5", P4 TCK (in) "Powered by VCCIO5"
part J pins: A7 VCCAUX (power), B11 VCCIO1 (power), C5 VCCIO0 (power), C7 VCC (power), D2 VCCIO7 (power), E12 VCCIO2 (power), G12 VCC (power), H3 VCC (power), K3 VCCIO6 (power), L12 VCCIO3 (power), M10 VCCIO4 (power), N2 VCCIO5 (power), P6 VCC (power), P7 VCCAUX (power)
part K pins: A10 GNDIO1 (power), B4 GNDIO0 (power), C9 GND (power), D13 GNDIO2 (power), E1 GNDIO7 (power), F1 GND (power), J14 GND (power), L2 GNDIO6 (power), L13 GNDIO3 (power), N11 GNDIO4 (power), P2 GNDIO5 (power), P9 GND (power)

## LCMXO2280C-3T100C
designator U?
MachXO 2280 Crossover PLD, 1.8V/2.5V/3.3V, 73 User I/Os, 100-Pins TQFP, Speed Grade-3, Commercial Grade
footprint TQFP100_N (Thin QFP, 100-Leads, Body 14x14mm, Pitch 0.5mm, IPC Medium Density)
footprint TQFP100_L (Thin QFP, 100-Leads, Body 14x14mm, Pitch 0.5mm, IPC High Density)
footprint TQFP100_M (Thin QFP, 100-Leads, Body 14x14mm, Pitch 0.5mm, IPC Low Density)
3D model MachXO2280-TQFP100 (100-Pin Thin Quad Flat Pack (TQFP100))
signal-integrity model LCMXO2280C_T100 (MachXO)
part A pins: 88 PT8F (io), 89 PT8E (io), 92 PT6D (io), 93 PT6F (io), 95 PT4B (io), 96 PT4A (io), 97 PT3B (io), 98 PT2B (io), 99 PT2A (io)
part B pins: 77 PT15C (io), 78 PT14B (io), 79 PT14A (io), 81 PT12D (io), 82 PT12C (io), 84 PT11B (io), 85 PT11A (io), 86 PT10B/PCLK1_1 (io), 87 PT9B/PCLK1_0 (io)
part C pins: 64 PR10B (io), 65 PR10A (io), 67 PR8C (io), 68 PR8B (io), 69 PR8A (io), 71 PR5D (io), 72 PR5B (io), 73 PR5A (io), 74 PR3B (io), 75 PR3A (io)
part D pins: 51 PR19B (io), 52 PR18B (io), 53 PR18A (io), 54 PR17B (io), 55 PR17A (io), 57 PR15B (io), 58 PR15A (io), 60 PR13B (io), 61 PR13A (io), 62 PR11B (io), 63 PR11A (io)
part E pins: 39 PB10F/PCLK4_1 (io), 40 PB10B/PCLK4_0 (io), 42 PB12A (io), 43 PB12B (io), 45 PB13A (io), 46 PB13B (io), 48 PB16A (io), 49 PB16B (io)
part F pins: 30 PB3B (io), 31 PB4A (io), 32 PB4B (io), 37 PB8E (io), 38 PB8F (io)
part G pins: 14 PL11C (io), 15 PL13A (io), 16 PL13B (io), 18 PL14D (io), 19 PL14C/TSALL (io), 21 PL16C (io), 22 PL17A/LLM0_PLLT_FB_A (io), 23 PL17B/LLM0_PLLC_FB_A (io), 24 PL18A/LLM0_PLLT_IN_A (io), 25 PL18B/LLM0_PLLC_IN_A (io)
part H pins: 1 PL2A/LUM0_PLLT_FB_A (io), 2 PL2B/LUM0_PLLC_FB_A (io), 3 PL3C/LUM0_PLLT_IN_A (io), 4 PL3D/LUM0_PLLC_IN_A (io), 5 PL4B (io), 7 PL7A (io), 8 PL7B/GSRN (io), 10 PL9C (io), 11 PL9D (io), 12 PL10C (io), 13 PL10D (io)
part I pins: 28 TMS (in) "Powered by VCCIO5", 29 TCK (in) "Powered by VCCIO5", 33 TDO (out) "Powered by VCCIO5", 34 TDI (in) "Powered by VCCIO5", 47 SLEEPN (in) "Powered by VCCIO4"
part J pins: 6 VCCIO7 (power), 17 VCC (power), 20 VCCIO6 (power), 27 VCCIO5 (power), 35 VCC (power), 36 VCCAUX (power), 44 VCCIO4 (power), 56 VCCIO3 (power), 66 VCC (power), 70 VCCIO2 (power), 80 VCCIO1 (power), 90 VCCAUX (power), 91 VCC (power), 94 VCCIO0 (power)
part K pins: 9 GND (power), 26 GNDIO6/GNDIO5 (power) "Double Bonded pin", 41 GND (power), 50 GNDIO3/GNDIO4 (power) "Double Bonded pin", 59 GND (power), 76 GNDIO1/GNDIO2 (power) "Double Bonded pin", 83 GND (power), 100 GNDIO0/GNDIO7 (power) "Double Bonded pin"

## LCMXO2280C-3T100C4W
designator U?
MachXO 2280 Crossover PLD, 1.8V/2.5V/3.3V, 73 User I/Os, 100-Pins TQFP, Speed Grade-3, Commercial Grade
footprint TQFP100_N (Thin QFP, 100-Leads, Body 14x14mm, Pitch 0.5mm, IPC Medium Density)
footprint TQFP100_L (Thin QFP, 100-Leads, Body 14x14mm, Pitch 0.5mm, IPC High Density)
footprint TQFP100_M (Thin QFP, 100-Leads, Body 14x14mm, Pitch 0.5mm, IPC Low Density)
3D model MachXO2280-TQFP100 (100-Pin Thin Quad Flat Pack (TQFP100))
signal-integrity model LCMXO2280C_T100 (MachXO)
part A pins: 88 PT8F (io), 89 PT8E (io), 92 PT6D (io), 93 PT6F (io), 95 PT4B (io), 96 PT4A (io), 97 PT3B (io), 98 PT2B (io), 99 PT2A (io)
part B pins: 77 PT15C (io), 78 PT14B (io), 79 PT14A (io), 81 PT12D (io), 82 PT12C (io), 84 PT11B (io), 85 PT11A (io), 86 PT10B/PCLK1_1 (io), 87 PT9B/PCLK1_0 (io)
part C pins: 64 PR10B (io), 65 PR10A (io), 67 PR8C (io), 68 PR8B (io), 69 PR8A (io), 71 PR5D (io), 72 PR5B (io), 73 PR5A (io), 74 PR3B (io), 75 PR3A (io)
part D pins: 51 PR19B (io), 52 PR18B (io), 53 PR18A (io), 54 PR17B (io), 55 PR17A (io), 57 PR15B (io), 58 PR15A (io), 60 PR13B (io), 61 PR13A (io), 62 PR11B (io), 63 PR11A (io)
part E pins: 39 PB10F/PCLK4_1 (io), 40 PB10B/PCLK4_0 (io), 42 PB12A (io), 43 PB12B (io), 45 PB13A (io), 46 PB13B (io), 48 PB16A (io), 49 PB16B (io)
part F pins: 30 PB3B (io), 31 PB4A (io), 32 PB4B (io), 37 PB8E (io), 38 PB8F (io)
part G pins: 14 PL11C (io), 15 PL13A (io), 16 PL13B (io), 18 PL14D (io), 19 PL14C/TSALL (io), 21 PL16C (io), 22 PL17A/LLM0_PLLT_FB_A (io), 23 PL17B/LLM0_PLLC_FB_A (io), 24 PL18A/LLM0_PLLT_IN_A (io), 25 PL18B/LLM0_PLLC_IN_A (io)
part H pins: 1 PL2A/LUM0_PLLT_FB_A (io), 2 PL2B/LUM0_PLLC_FB_A (io), 3 PL3C/LUM0_PLLT_IN_A (io), 4 PL3D/LUM0_PLLC_IN_A (io), 5 PL4B (io), 7 PL7A (io), 8 PL7B/GSRN (io), 10 PL9C (io), 11 PL9D (io), 12 PL10C (io), 13 PL10D (io)
part I pins: 28 TMS (in) "Powered by VCCIO5", 29 TCK (in) "Powered by VCCIO5", 33 TDO (out) "Powered by VCCIO5", 34 TDI (in) "Powered by VCCIO5", 47 SLEEPN (in) "Powered by VCCIO4"
part J pins: 6 VCCIO7 (power), 17 VCC (power), 20 VCCIO6 (power), 27 VCCIO5 (power), 35 VCC (power), 36 VCCAUX (power), 44 VCCIO4 (power), 56 VCCIO3 (power), 66 VCC (power), 70 VCCIO2 (power), 80 VCCIO1 (power), 90 VCCAUX (power), 91 VCC (power), 94 VCCIO0 (power)
part K pins: 9 GND (power), 26 GNDIO6/GNDIO5 (power) "Double Bonded pin", 41 GND (power), 50 GNDIO3/GNDIO4 (power) "Double Bonded pin", 59 GND (power), 76 GNDIO1/GNDIO2 (power) "Double Bonded pin", 83 GND (power), 100 GNDIO0/GNDIO7 (power) "Double Bonded pin"


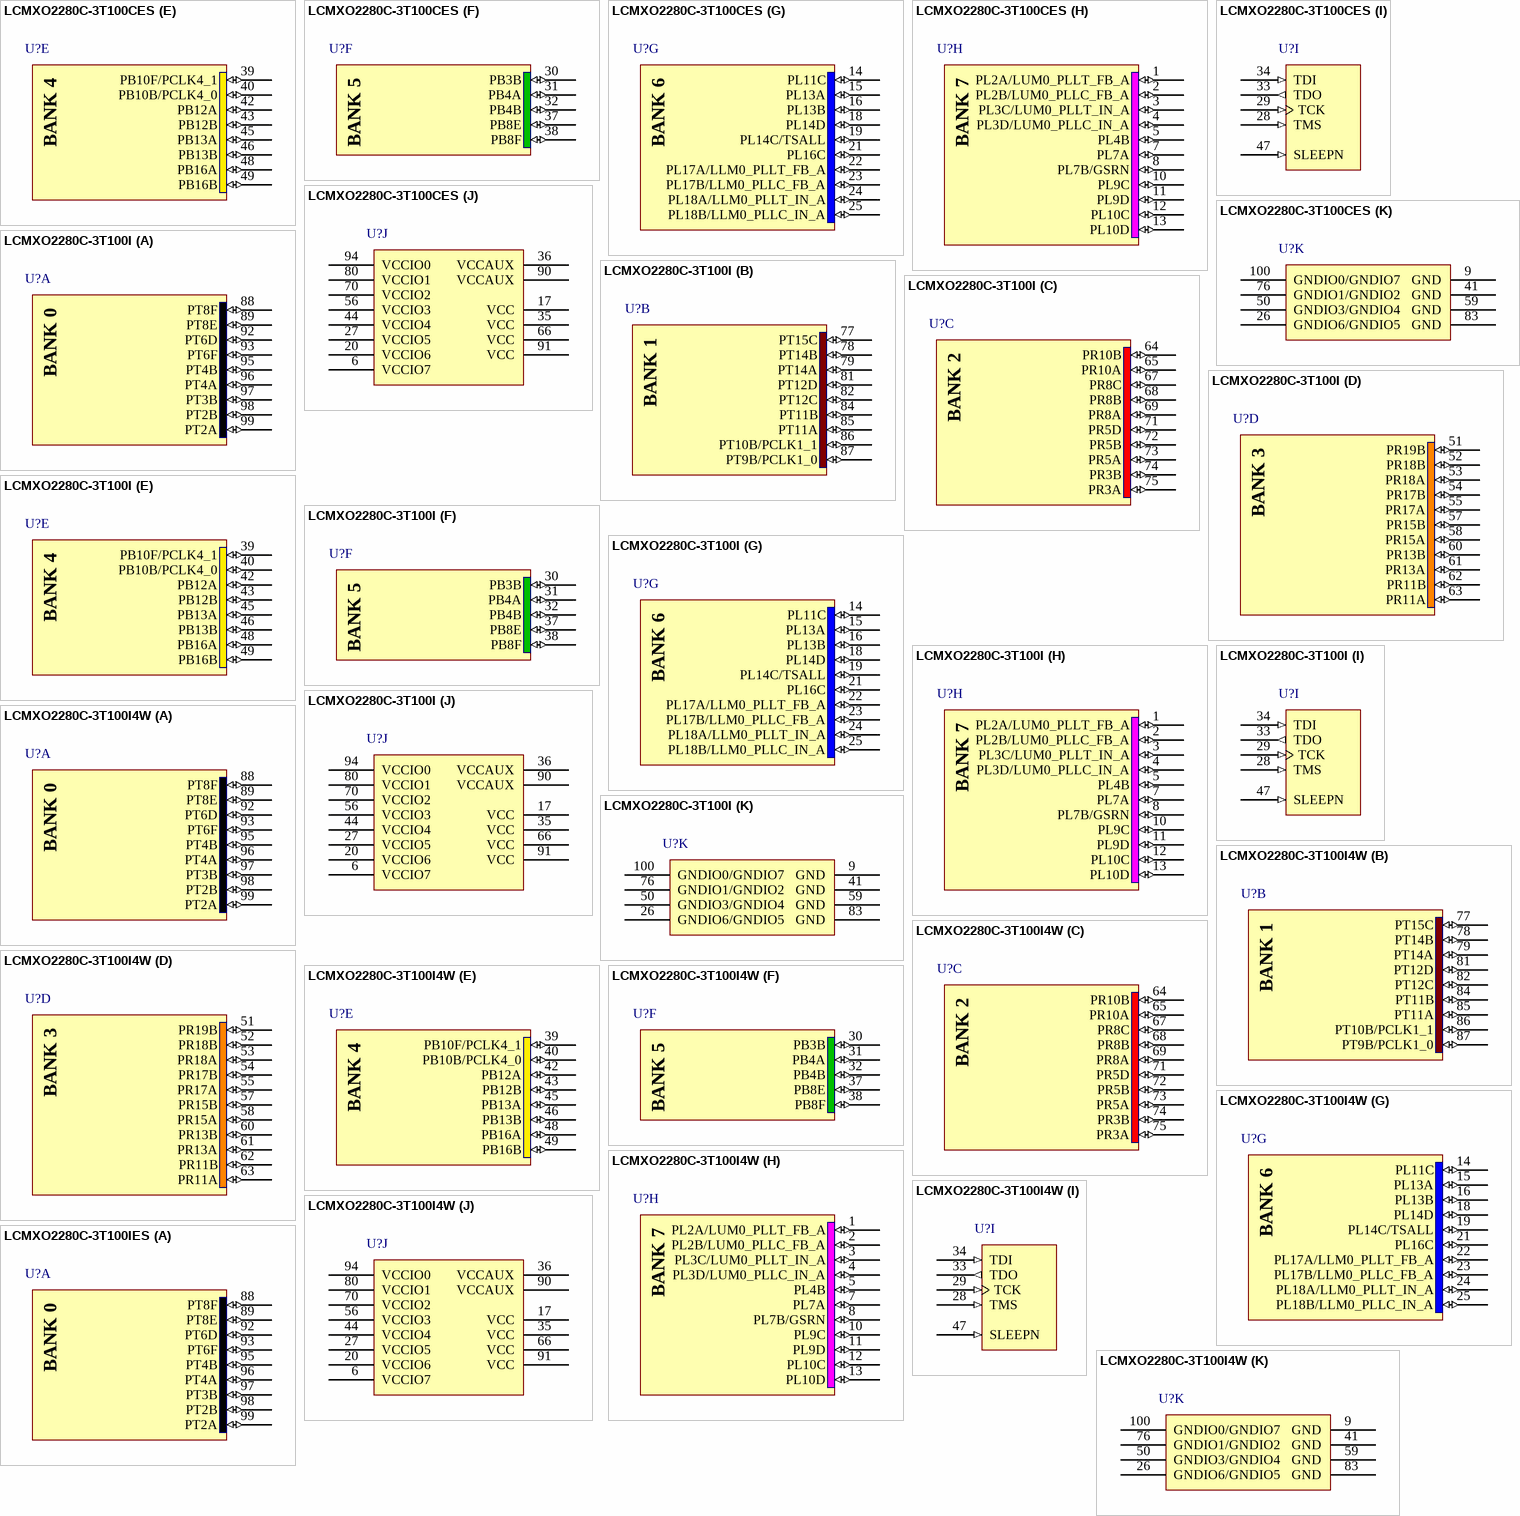
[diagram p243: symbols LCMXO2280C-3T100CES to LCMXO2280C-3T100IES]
## LCMXO2280C-3T100CES
designator U?
MachXO 2280 Crossover PLD, 1.8V/2.5V/3.3V, 73 User I/Os, 100-Pins TQFP, Speed Grade-3, Commercial Grade, Engineering Sample
footprint TQFP100_N (Thin QFP, 100-Leads, Body 14x14mm, Pitch 0.5mm, IPC Medium Density)
footprint TQFP100_L (Thin QFP, 100-Leads, Body 14x14mm, Pitch 0.5mm, IPC High Density)
footprint TQFP100_M (Thin QFP, 100-Leads, Body 14x14mm, Pitch 0.5mm, IPC Low Density)
3D model MachXO2280-TQFP100 (100-Pin Thin Quad Flat Pack (TQFP100))
signal-integrity model LCMXO2280C_T100 (MachXO)
part A pins: 88 PT8F (io), 89 PT8E (io), 92 PT6D (io), 93 PT6F (io), 95 PT4B (io), 96 PT4A (io), 97 PT3B (io), 98 PT2B (io), 99 PT2A (io)
part B pins: 77 PT15C (io), 78 PT14B (io), 79 PT14A (io), 81 PT12D (io), 82 PT12C (io), 84 PT11B (io), 85 PT11A (io), 86 PT10B/PCLK1_1 (io), 87 PT9B/PCLK1_0 (io)
part C pins: 64 PR10B (io), 65 PR10A (io), 67 PR8C (io), 68 PR8B (io), 69 PR8A (io), 71 PR5D (io), 72 PR5B (io), 73 PR5A (io), 74 PR3B (io), 75 PR3A (io)
part D pins: 51 PR19B (io), 52 PR18B (io), 53 PR18A (io), 54 PR17B (io), 55 PR17A (io), 57 PR15B (io), 58 PR15A (io), 60 PR13B (io), 61 PR13A (io), 62 PR11B (io), 63 PR11A (io)
part E pins: 39 PB10F/PCLK4_1 (io), 40 PB10B/PCLK4_0 (io), 42 PB12A (io), 43 PB12B (io), 45 PB13A (io), 46 PB13B (io), 48 PB16A (io), 49 PB16B (io)
part F pins: 30 PB3B (io), 31 PB4A (io), 32 PB4B (io), 37 PB8E (io), 38 PB8F (io)
part G pins: 14 PL11C (io), 15 PL13A (io), 16 PL13B (io), 18 PL14D (io), 19 PL14C/TSALL (io), 21 PL16C (io), 22 PL17A/LLM0_PLLT_FB_A (io), 23 PL17B/LLM0_PLLC_FB_A (io), 24 PL18A/LLM0_PLLT_IN_A (io), 25 PL18B/LLM0_PLLC_IN_A (io)
part H pins: 1 PL2A/LUM0_PLLT_FB_A (io), 2 PL2B/LUM0_PLLC_FB_A (io), 3 PL3C/LUM0_PLLT_IN_A (io), 4 PL3D/LUM0_PLLC_IN_A (io), 5 PL4B (io), 7 PL7A (io), 8 PL7B/GSRN (io), 10 PL9C (io), 11 PL9D (io), 12 PL10C (io), 13 PL10D (io)
part I pins: 28 TMS (in) "Powered by VCCIO5", 29 TCK (in) "Powered by VCCIO5", 33 TDO (out) "Powered by VCCIO5", 34 TDI (in) "Powered by VCCIO5", 47 SLEEPN (in) "Powered by VCCIO4"
part J pins: 6 VCCIO7 (power), 17 VCC (power), 20 VCCIO6 (power), 27 VCCIO5 (power), 35 VCC (power), 36 VCCAUX (power), 44 VCCIO4 (power), 56 VCCIO3 (power), 66 VCC (power), 70 VCCIO2 (power), 80 VCCIO1 (power), 90 VCCAUX (power), 91 VCC (power), 94 VCCIO0 (power)
part K pins: 9 GND (power), 26 GNDIO6/GNDIO5 (power) "Double Bonded pin", 41 GND (power), 50 GNDIO3/GNDIO4 (power) "Double Bonded pin", 59 GND (power), 76 GNDIO1/GNDIO2 (power) "Double Bonded pin", 83 GND (power), 100 GNDIO0/GNDIO7 (power) "Double Bonded pin"

## LCMXO2280C-3T100I
designator U?
MachXO 2280 Crossover PLD, 1.8V/2.5V/3.3V, 73 User I/Os, 100-Pins TQFP, Speed Grade-3, Industrial Grade
footprint TQFP100_N (Thin QFP, 100-Leads, Body 14x14mm, Pitch 0.5mm, IPC Medium Density)
footprint TQFP100_L (Thin QFP, 100-Leads, Body 14x14mm, Pitch 0.5mm, IPC High Density)
footprint TQFP100_M (Thin QFP, 100-Leads, Body 14x14mm, Pitch 0.5mm, IPC Low Density)
3D model MachXO2280-TQFP100 (100-Pin Thin Quad Flat Pack (TQFP100))
signal-integrity model LCMXO2280C_T100 (MachXO)
part A pins: 88 PT8F (io), 89 PT8E (io), 92 PT6D (io), 93 PT6F (io), 95 PT4B (io), 96 PT4A (io), 97 PT3B (io), 98 PT2B (io), 99 PT2A (io)
part B pins: 77 PT15C (io), 78 PT14B (io), 79 PT14A (io), 81 PT12D (io), 82 PT12C (io), 84 PT11B (io), 85 PT11A (io), 86 PT10B/PCLK1_1 (io), 87 PT9B/PCLK1_0 (io)
part C pins: 64 PR10B (io), 65 PR10A (io), 67 PR8C (io), 68 PR8B (io), 69 PR8A (io), 71 PR5D (io), 72 PR5B (io), 73 PR5A (io), 74 PR3B (io), 75 PR3A (io)
part D pins: 51 PR19B (io), 52 PR18B (io), 53 PR18A (io), 54 PR17B (io), 55 PR17A (io), 57 PR15B (io), 58 PR15A (io), 60 PR13B (io), 61 PR13A (io), 62 PR11B (io), 63 PR11A (io)
part E pins: 39 PB10F/PCLK4_1 (io), 40 PB10B/PCLK4_0 (io), 42 PB12A (io), 43 PB12B (io), 45 PB13A (io), 46 PB13B (io), 48 PB16A (io), 49 PB16B (io)
part F pins: 30 PB3B (io), 31 PB4A (io), 32 PB4B (io), 37 PB8E (io), 38 PB8F (io)
part G pins: 14 PL11C (io), 15 PL13A (io), 16 PL13B (io), 18 PL14D (io), 19 PL14C/TSALL (io), 21 PL16C (io), 22 PL17A/LLM0_PLLT_FB_A (io), 23 PL17B/LLM0_PLLC_FB_A (io), 24 PL18A/LLM0_PLLT_IN_A (io), 25 PL18B/LLM0_PLLC_IN_A (io)
part H pins: 1 PL2A/LUM0_PLLT_FB_A (io), 2 PL2B/LUM0_PLLC_FB_A (io), 3 PL3C/LUM0_PLLT_IN_A (io), 4 PL3D/LUM0_PLLC_IN_A (io), 5 PL4B (io), 7 PL7A (io), 8 PL7B/GSRN (io), 10 PL9C (io), 11 PL9D (io), 12 PL10C (io), 13 PL10D (io)
part I pins: 28 TMS (in) "Powered by VCCIO5", 29 TCK (in) "Powered by VCCIO5", 33 TDO (out) "Powered by VCCIO5", 34 TDI (in) "Powered by VCCIO5", 47 SLEEPN (in) "Powered by VCCIO4"
part J pins: 6 VCCIO7 (power), 17 VCC (power), 20 VCCIO6 (power), 27 VCCIO5 (power), 35 VCC (power), 36 VCCAUX (power), 44 VCCIO4 (power), 56 VCCIO3 (power), 66 VCC (power), 70 VCCIO2 (power), 80 VCCIO1 (power), 90 VCCAUX (power), 91 VCC (power), 94 VCCIO0 (power)
part K pins: 9 GND (power), 26 GNDIO6/GNDIO5 (power) "Double Bonded pin", 41 GND (power), 50 GNDIO3/GNDIO4 (power) "Double Bonded pin", 59 GND (power), 76 GNDIO1/GNDIO2 (power) "Double Bonded pin", 83 GND (power), 100 GNDIO0/GNDIO7 (power) "Double Bonded pin"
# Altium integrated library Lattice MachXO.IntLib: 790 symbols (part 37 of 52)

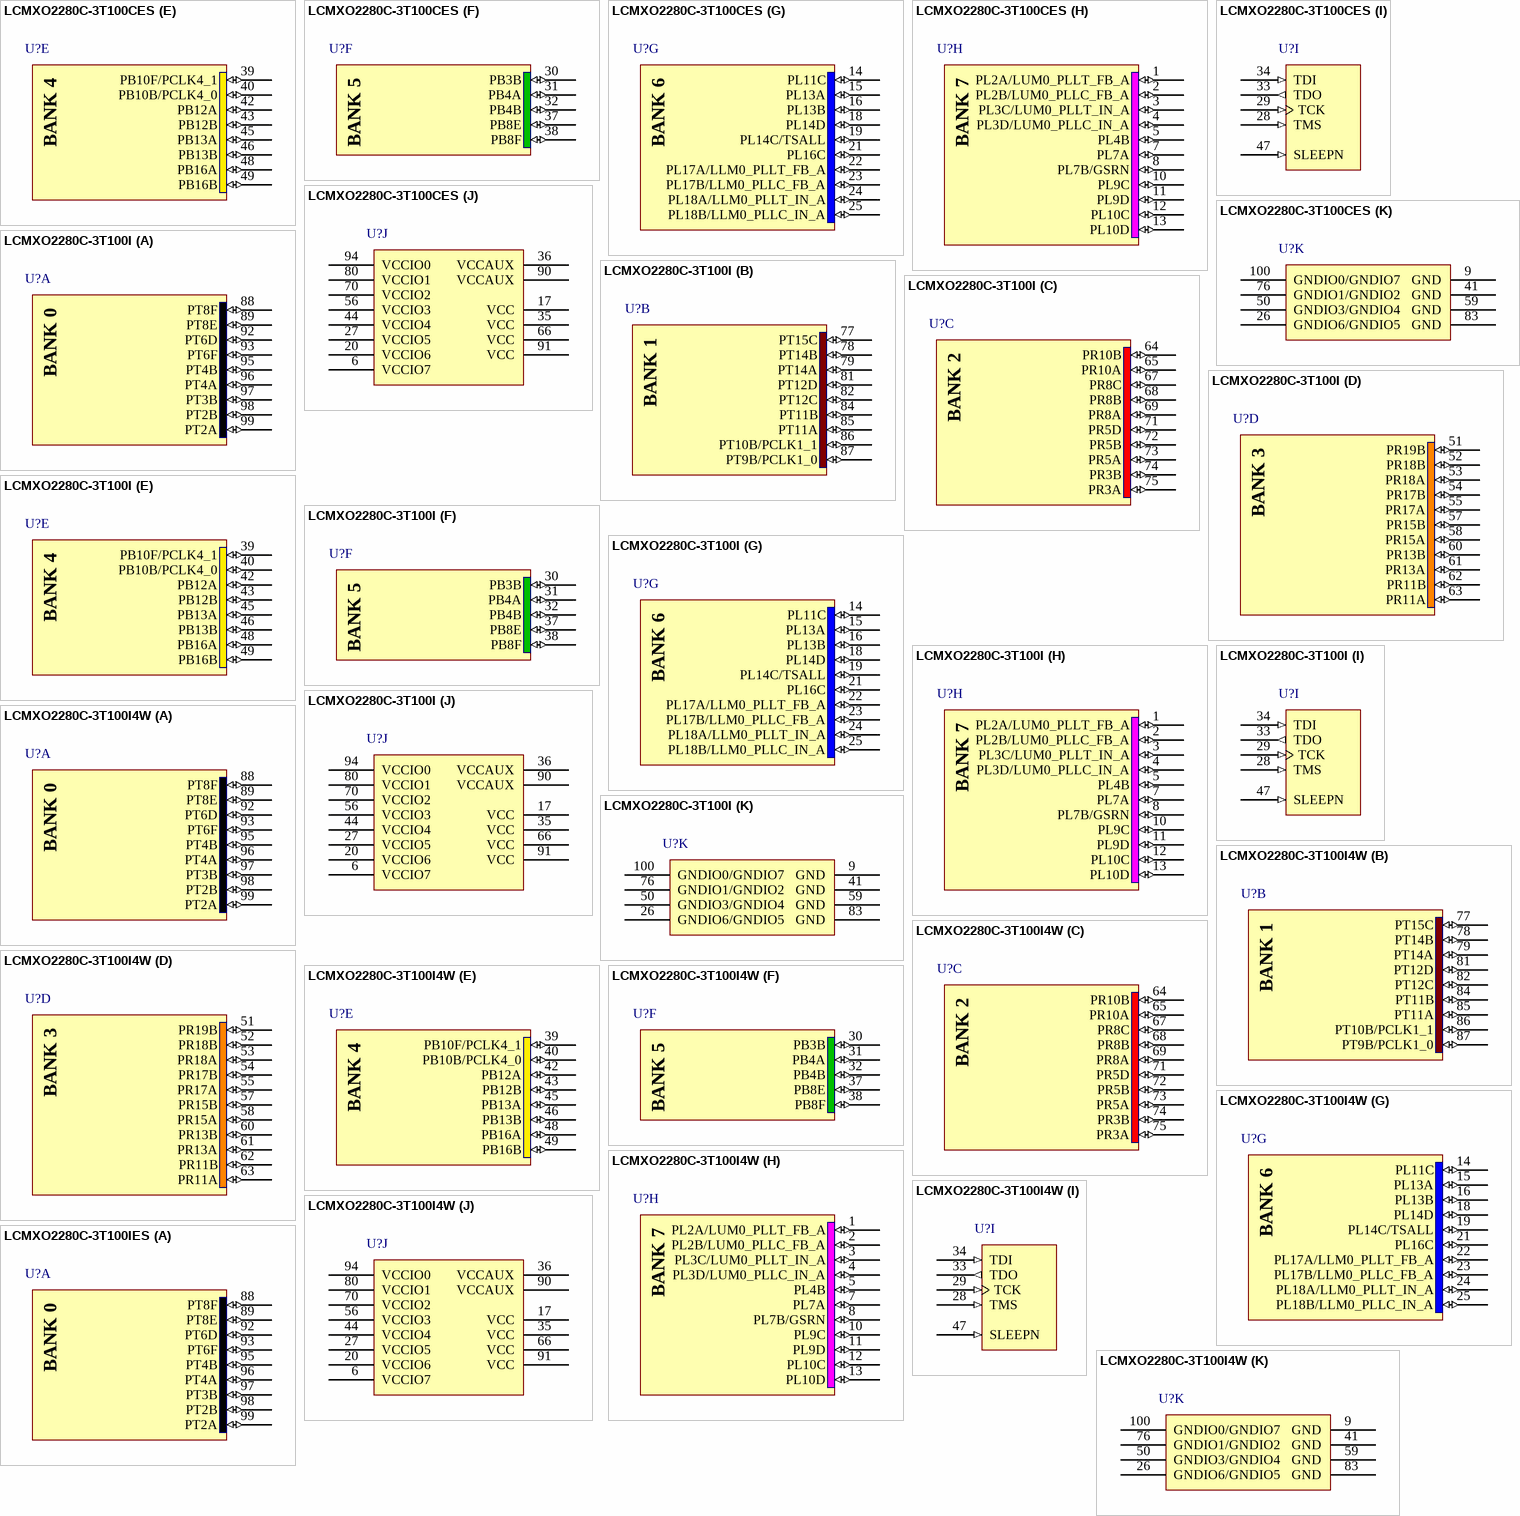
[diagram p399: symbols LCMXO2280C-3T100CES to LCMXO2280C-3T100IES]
## LCMXO2280C-3T100I4W
designator U?
MachXO 2280 Crossover PLD, 1.8V/2.5V/3.3V, 73 User I/Os, 100-Pins TQFP, Speed Grade-3, Industrial Grade
footprint TQFP100_N (Thin QFP, 100-Leads, Body 14x14mm, Pitch 0.5mm, IPC Medium Density)
footprint TQFP100_L (Thin QFP, 100-Leads, Body 14x14mm, Pitch 0.5mm, IPC High Density)
footprint TQFP100_M (Thin QFP, 100-Leads, Body 14x14mm, Pitch 0.5mm, IPC Low Density)
3D model MachXO2280-TQFP100 (100-Pin Thin Quad Flat Pack (TQFP100))
signal-integrity model LCMXO2280C_T100 (MachXO)
part A pins: 88 PT8F (io), 89 PT8E (io), 92 PT6D (io), 93 PT6F (io), 95 PT4B (io), 96 PT4A (io), 97 PT3B (io), 98 PT2B (io), 99 PT2A (io)
part B pins: 77 PT15C (io), 78 PT14B (io), 79 PT14A (io), 81 PT12D (io), 82 PT12C (io), 84 PT11B (io), 85 PT11A (io), 86 PT10B/PCLK1_1 (io), 87 PT9B/PCLK1_0 (io)
part C pins: 64 PR10B (io), 65 PR10A (io), 67 PR8C (io), 68 PR8B (io), 69 PR8A (io), 71 PR5D (io), 72 PR5B (io), 73 PR5A (io), 74 PR3B (io), 75 PR3A (io)
part D pins: 51 PR19B (io), 52 PR18B (io), 53 PR18A (io), 54 PR17B (io), 55 PR17A (io), 57 PR15B (io), 58 PR15A (io), 60 PR13B (io), 61 PR13A (io), 62 PR11B (io), 63 PR11A (io)
part E pins: 39 PB10F/PCLK4_1 (io), 40 PB10B/PCLK4_0 (io), 42 PB12A (io), 43 PB12B (io), 45 PB13A (io), 46 PB13B (io), 48 PB16A (io), 49 PB16B (io)
part F pins: 30 PB3B (io), 31 PB4A (io), 32 PB4B (io), 37 PB8E (io), 38 PB8F (io)
part G pins: 14 PL11C (io), 15 PL13A (io), 16 PL13B (io), 18 PL14D (io), 19 PL14C/TSALL (io), 21 PL16C (io), 22 PL17A/LLM0_PLLT_FB_A (io), 23 PL17B/LLM0_PLLC_FB_A (io), 24 PL18A/LLM0_PLLT_IN_A (io), 25 PL18B/LLM0_PLLC_IN_A (io)
part H pins: 1 PL2A/LUM0_PLLT_FB_A (io), 2 PL2B/LUM0_PLLC_FB_A (io), 3 PL3C/LUM0_PLLT_IN_A (io), 4 PL3D/LUM0_PLLC_IN_A (io), 5 PL4B (io), 7 PL7A (io), 8 PL7B/GSRN (io), 10 PL9C (io), 11 PL9D (io), 12 PL10C (io), 13 PL10D (io)
part I pins: 28 TMS (in) "Powered by VCCIO5", 29 TCK (in) "Powered by VCCIO5", 33 TDO (out) "Powered by VCCIO5", 34 TDI (in) "Powered by VCCIO5", 47 SLEEPN (in) "Powered by VCCIO4"
part J pins: 6 VCCIO7 (power), 17 VCC (power), 20 VCCIO6 (power), 27 VCCIO5 (power), 35 VCC (power), 36 VCCAUX (power), 44 VCCIO4 (power), 56 VCCIO3 (power), 66 VCC (power), 70 VCCIO2 (power), 80 VCCIO1 (power), 90 VCCAUX (power), 91 VCC (power), 94 VCCIO0 (power)
part K pins: 9 GND (power), 26 GNDIO6/GNDIO5 (power) "Double Bonded pin", 41 GND (power), 50 GNDIO3/GNDIO4 (power) "Double Bonded pin", 59 GND (power), 76 GNDIO1/GNDIO2 (power) "Double Bonded pin", 83 GND (power), 100 GNDIO0/GNDIO7 (power) "Double Bonded pin"


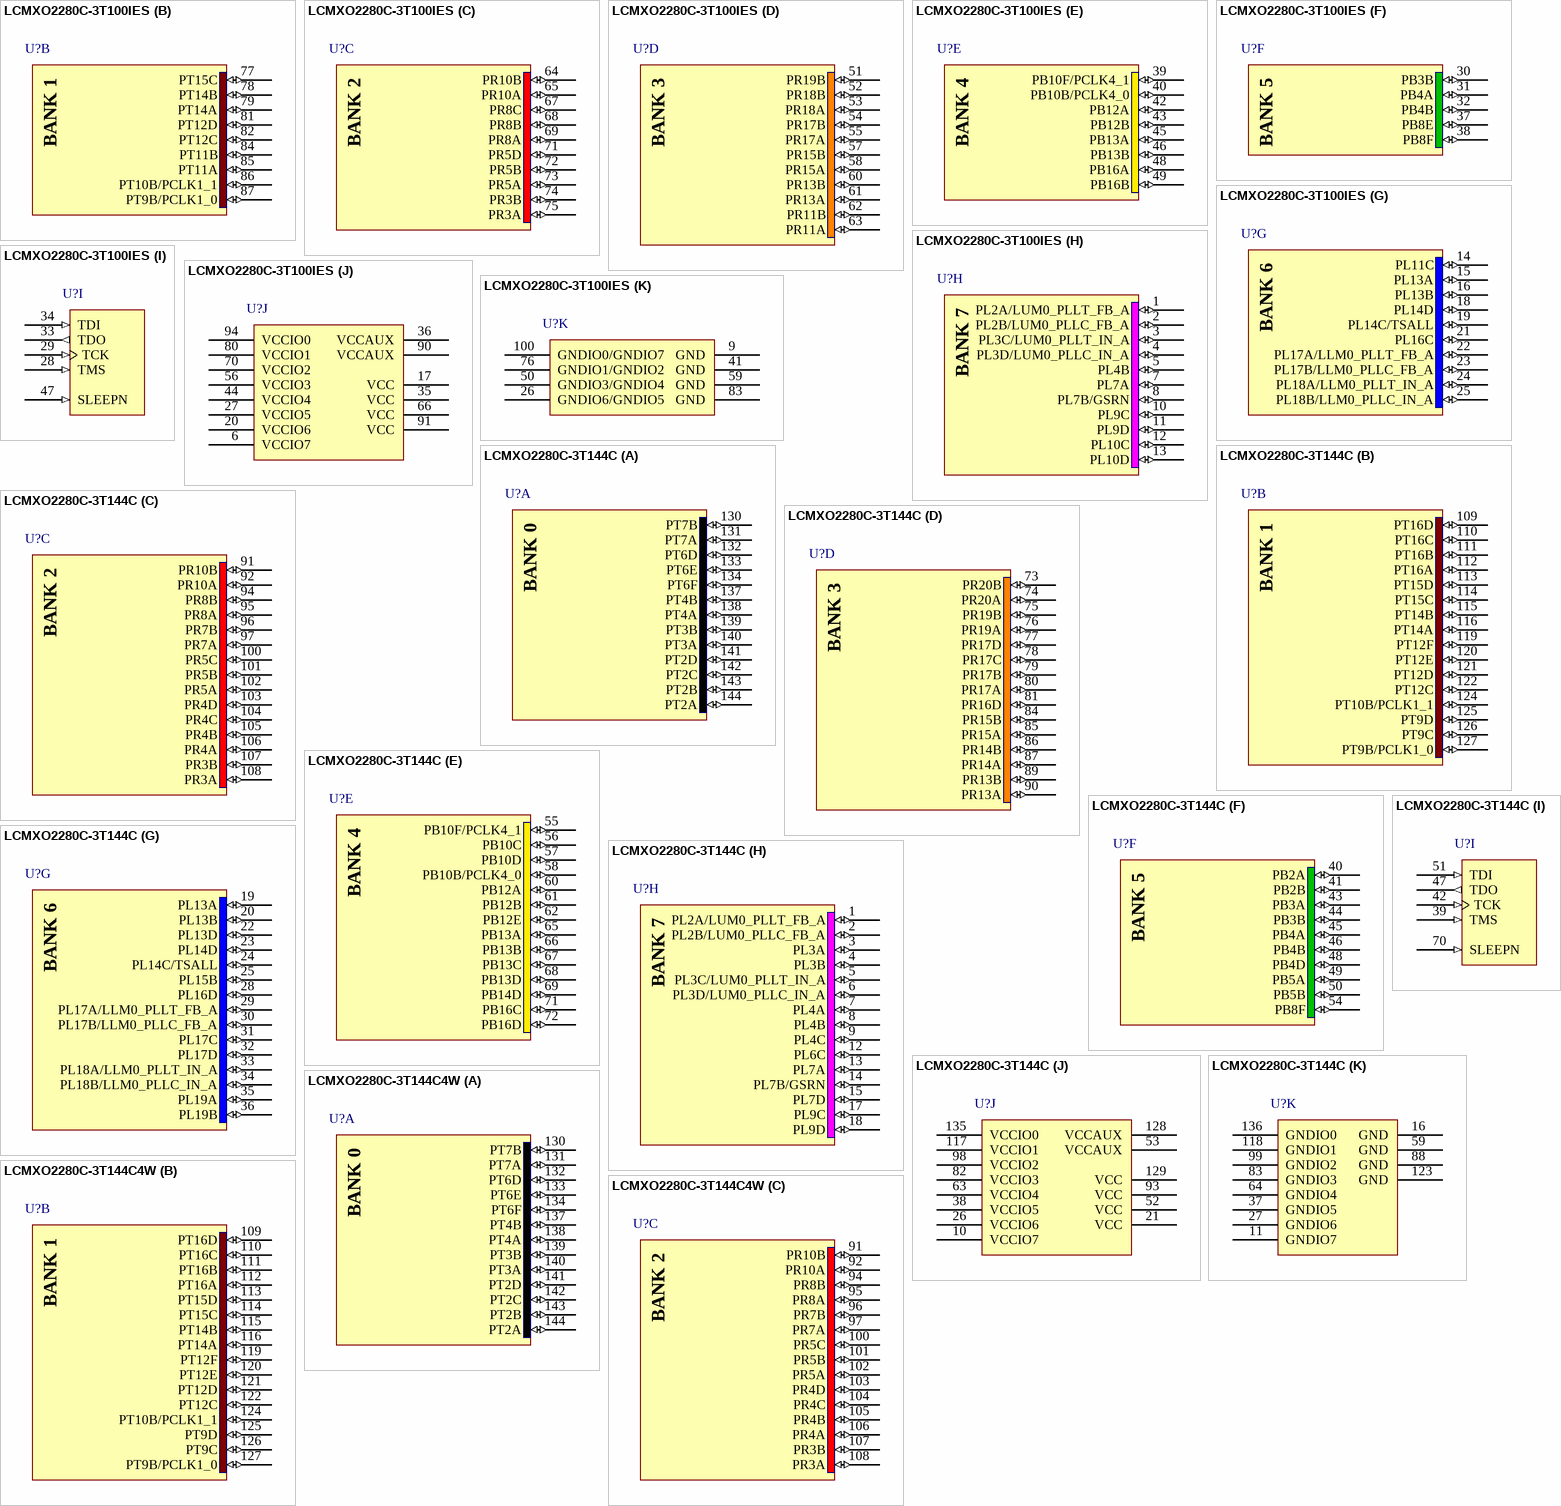
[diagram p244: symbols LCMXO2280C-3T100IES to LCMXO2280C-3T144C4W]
## LCMXO2280C-3T100IES
designator U?
MachXO 2280 Crossover PLD, 1.8V/2.5V/3.3V, 73 User I/Os, 100-Pins TQFP, Speed Grade-3, Industrial Grade, Engineering Sample
footprint TQFP100_N (Thin QFP, 100-Leads, Body 14x14mm, Pitch 0.5mm, IPC Medium Density)
footprint TQFP100_L (Thin QFP, 100-Leads, Body 14x14mm, Pitch 0.5mm, IPC High Density)
footprint TQFP100_M (Thin QFP, 100-Leads, Body 14x14mm, Pitch 0.5mm, IPC Low Density)
3D model MachXO2280-TQFP100 (100-Pin Thin Quad Flat Pack (TQFP100))
signal-integrity model LCMXO2280C_T100 (MachXO)
part A pins: 88 PT8F (io), 89 PT8E (io), 92 PT6D (io), 93 PT6F (io), 95 PT4B (io), 96 PT4A (io), 97 PT3B (io), 98 PT2B (io), 99 PT2A (io)
part B pins: 77 PT15C (io), 78 PT14B (io), 79 PT14A (io), 81 PT12D (io), 82 PT12C (io), 84 PT11B (io), 85 PT11A (io), 86 PT10B/PCLK1_1 (io), 87 PT9B/PCLK1_0 (io)
part C pins: 64 PR10B (io), 65 PR10A (io), 67 PR8C (io), 68 PR8B (io), 69 PR8A (io), 71 PR5D (io), 72 PR5B (io), 73 PR5A (io), 74 PR3B (io), 75 PR3A (io)
part D pins: 51 PR19B (io), 52 PR18B (io), 53 PR18A (io), 54 PR17B (io), 55 PR17A (io), 57 PR15B (io), 58 PR15A (io), 60 PR13B (io), 61 PR13A (io), 62 PR11B (io), 63 PR11A (io)
part E pins: 39 PB10F/PCLK4_1 (io), 40 PB10B/PCLK4_0 (io), 42 PB12A (io), 43 PB12B (io), 45 PB13A (io), 46 PB13B (io), 48 PB16A (io), 49 PB16B (io)
part F pins: 30 PB3B (io), 31 PB4A (io), 32 PB4B (io), 37 PB8E (io), 38 PB8F (io)
part G pins: 14 PL11C (io), 15 PL13A (io), 16 PL13B (io), 18 PL14D (io), 19 PL14C/TSALL (io), 21 PL16C (io), 22 PL17A/LLM0_PLLT_FB_A (io), 23 PL17B/LLM0_PLLC_FB_A (io), 24 PL18A/LLM0_PLLT_IN_A (io), 25 PL18B/LLM0_PLLC_IN_A (io)
part H pins: 1 PL2A/LUM0_PLLT_FB_A (io), 2 PL2B/LUM0_PLLC_FB_A (io), 3 PL3C/LUM0_PLLT_IN_A (io), 4 PL3D/LUM0_PLLC_IN_A (io), 5 PL4B (io), 7 PL7A (io), 8 PL7B/GSRN (io), 10 PL9C (io), 11 PL9D (io), 12 PL10C (io), 13 PL10D (io)
part I pins: 28 TMS (in) "Powered by VCCIO5", 29 TCK (in) "Powered by VCCIO5", 33 TDO (out) "Powered by VCCIO5", 34 TDI (in) "Powered by VCCIO5", 47 SLEEPN (in) "Powered by VCCIO4"
part J pins: 6 VCCIO7 (power), 17 VCC (power), 20 VCCIO6 (power), 27 VCCIO5 (power), 35 VCC (power), 36 VCCAUX (power), 44 VCCIO4 (power), 56 VCCIO3 (power), 66 VCC (power), 70 VCCIO2 (power), 80 VCCIO1 (power), 90 VCCAUX (power), 91 VCC (power), 94 VCCIO0 (power)
part K pins: 9 GND (power), 26 GNDIO6/GNDIO5 (power) "Double Bonded pin", 41 GND (power), 50 GNDIO3/GNDIO4 (power) "Double Bonded pin", 59 GND (power), 76 GNDIO1/GNDIO2 (power) "Double Bonded pin", 83 GND (power), 100 GNDIO0/GNDIO7 (power) "Double Bonded pin"

## LCMXO2280C-3T144C
designator U?
MachXO 2280 Crossover PLD, 1.8V/2.5V/3.3V, 113 User I/Os, 144-Pins TQFP, Speed Grade-3, Commercial Grade
footprint TQFP144_N (Thin QFP, 144-Leads, Body 20x20mm, Pitch 0.5mm, IPC Medium Density)
footprint TQFP144_L (Thin QFP, 144-Leads, Body 20x20mm, Pitch 0.5mm, IPC High Density)
footprint TQFP144_M (Thin QFP, 144-Leads, Body 20x20mm, Pitch 0.5mm, IPC Low Density)
3D model MachXO2280-TQFP144 (144-Pin Thin Quad Flat Pack (TQFP144))
signal-integrity model LCMXO2280C_T144 (MachXO)
part A pins: 130 PT7B (io), 131 PT7A (io), 132 PT6D (io), 133 PT6E (io), 134 PT6F (io), 137 PT4B (io), 138 PT4A (io), 139 PT3B (io), 140 PT3A (io), 141 PT2D (io), 142 PT2C (io), 143 PT2B (io), 144 PT2A (io)
part B pins: 109 PT16D (io), 110 PT16C (io), 111 PT16B (io), 112 PT16A (io), 113 PT15D (io), 114 PT15C (io), 115 PT14B (io), 116 PT14A (io), 119 PT12F (io), 120 PT12E (io), 121 PT12D (io), 122 PT12C (io), 124 PT10B/PCLK1_1 (io), 125 PT9D (io), 126 PT9C (io), 127 PT9B/PCLK1_0 (io)
part C pins: 91 PR10B (io), 92 PR10A (io), 94 PR8B (io), 95 PR8A (io), 96 PR7B (io), 97 PR7A (io), 100 PR5C (io), 101 PR5B (io), 102 PR5A (io), 103 PR4D (io), 104 PR4C (io), 105 PR4B (io), 106 PR4A (io), 107 PR3B (io), 108 PR3A (io)
part D pins: 73 PR20B (io), 74 PR20A (io), 75 PR19B (io), 76 PR19A (io), 77 PR17D (io), 78 PR17C (io), 79 PR17B (io), 80 PR17A (io), 81 PR16D (io), 84 PR15B (io), 85 PR15A (io), 86 PR14B (io), 87 PR14A (io), 89 PR13B (io), 90 PR13A (io)
part E pins: 55 PB10F/PCLK4_1 (io), 56 PB10C (io), 57 PB10D (io), 58 PB10B/PCLK4_0 (io), 60 PB12A (io), 61 PB12B (io), 62 PB12E (io), 65 PB13A (io), 66 PB13B (io), 67 PB13C (io), 68 PB13D (io), 69 PB14D (io), 71 PB16C (io), 72 PB16D (io)
part F pins: 40 PB2A (io), 41 PB2B (io), 43 PB3A (io), 44 PB3B (io), 45 PB4A (io), 46 PB4B (io), 48 PB4D (io), 49 PB5A (io), 50 PB5B (io), 54 PB8F (io)
part G pins: 19 PL13A (io), 20 PL13B (io), 22 PL13D (io), 23 PL14D (io), 24 PL14C/TSALL (io), 25 PL15B (io), 28 PL16D (io), 29 PL17A/LLM0_PLLT_FB_A (io), 30 PL17B/LLM0_PLLC_FB_A (io), 31 PL17C (io), 32 PL17D (io), 33 PL18A/LLM0_PLLT_IN_A (io), 34 PL18B/LLM0_PLLC_IN_A (io), 35 PL19A (io), 36 PL19B (io)
part H pins: 1 PL2A/LUM0_PLLT_FB_A (io), 2 PL2B/LUM0_PLLC_FB_A (io), 3 PL3A (io), 4 PL3B (io), 5 PL3C/LUM0_PLLT_IN_A (io), 6 PL3D/LUM0_PLLC_IN_A (io), 7 PL4A (io), 8 PL4B (io), 9 PL4C (io), 12 PL6C (io), 13 PL7A (io), 14 PL7B/GSRN (io), 15 PL7D (io), 17 PL9C (io), 18 PL9D (io)
part I pins: 39 TMS (in) "Powered by VCCIO5", 42 TCK (in) "Powered by VCCIO5", 47 TDO (out) "Powered by VCCIO5", 51 TDI (in) "Powered by VCCIO5", 70 SLEEPN (in) "Powered by VCCIO4"
part J pins: 10 VCCIO7 (power), 21 VCC (power), 26 VCCIO6 (power), 38 VCCIO5 (power), 52 VCC (power), 53 VCCAUX (power), 63 VCCIO4 (power), 82 VCCIO3 (power), 93 VCC (power), 98 VCCIO2 (power), 117 VCCIO1 (power), 128 VCCAUX (power), 129 VCC (power), 135 VCCIO0 (power)
part K pins: 11 GNDIO7 (power), 16 GND (power), 27 GNDIO6 (power), 37 GNDIO5 (power), 59 GND (power), 64 GNDIO4 (power), 83 GNDIO3 (power), 88 GND (power), 99 GNDIO2 (power), 118 GNDIO1 (power), 123 GND (power), 136 GNDIO0 (power)


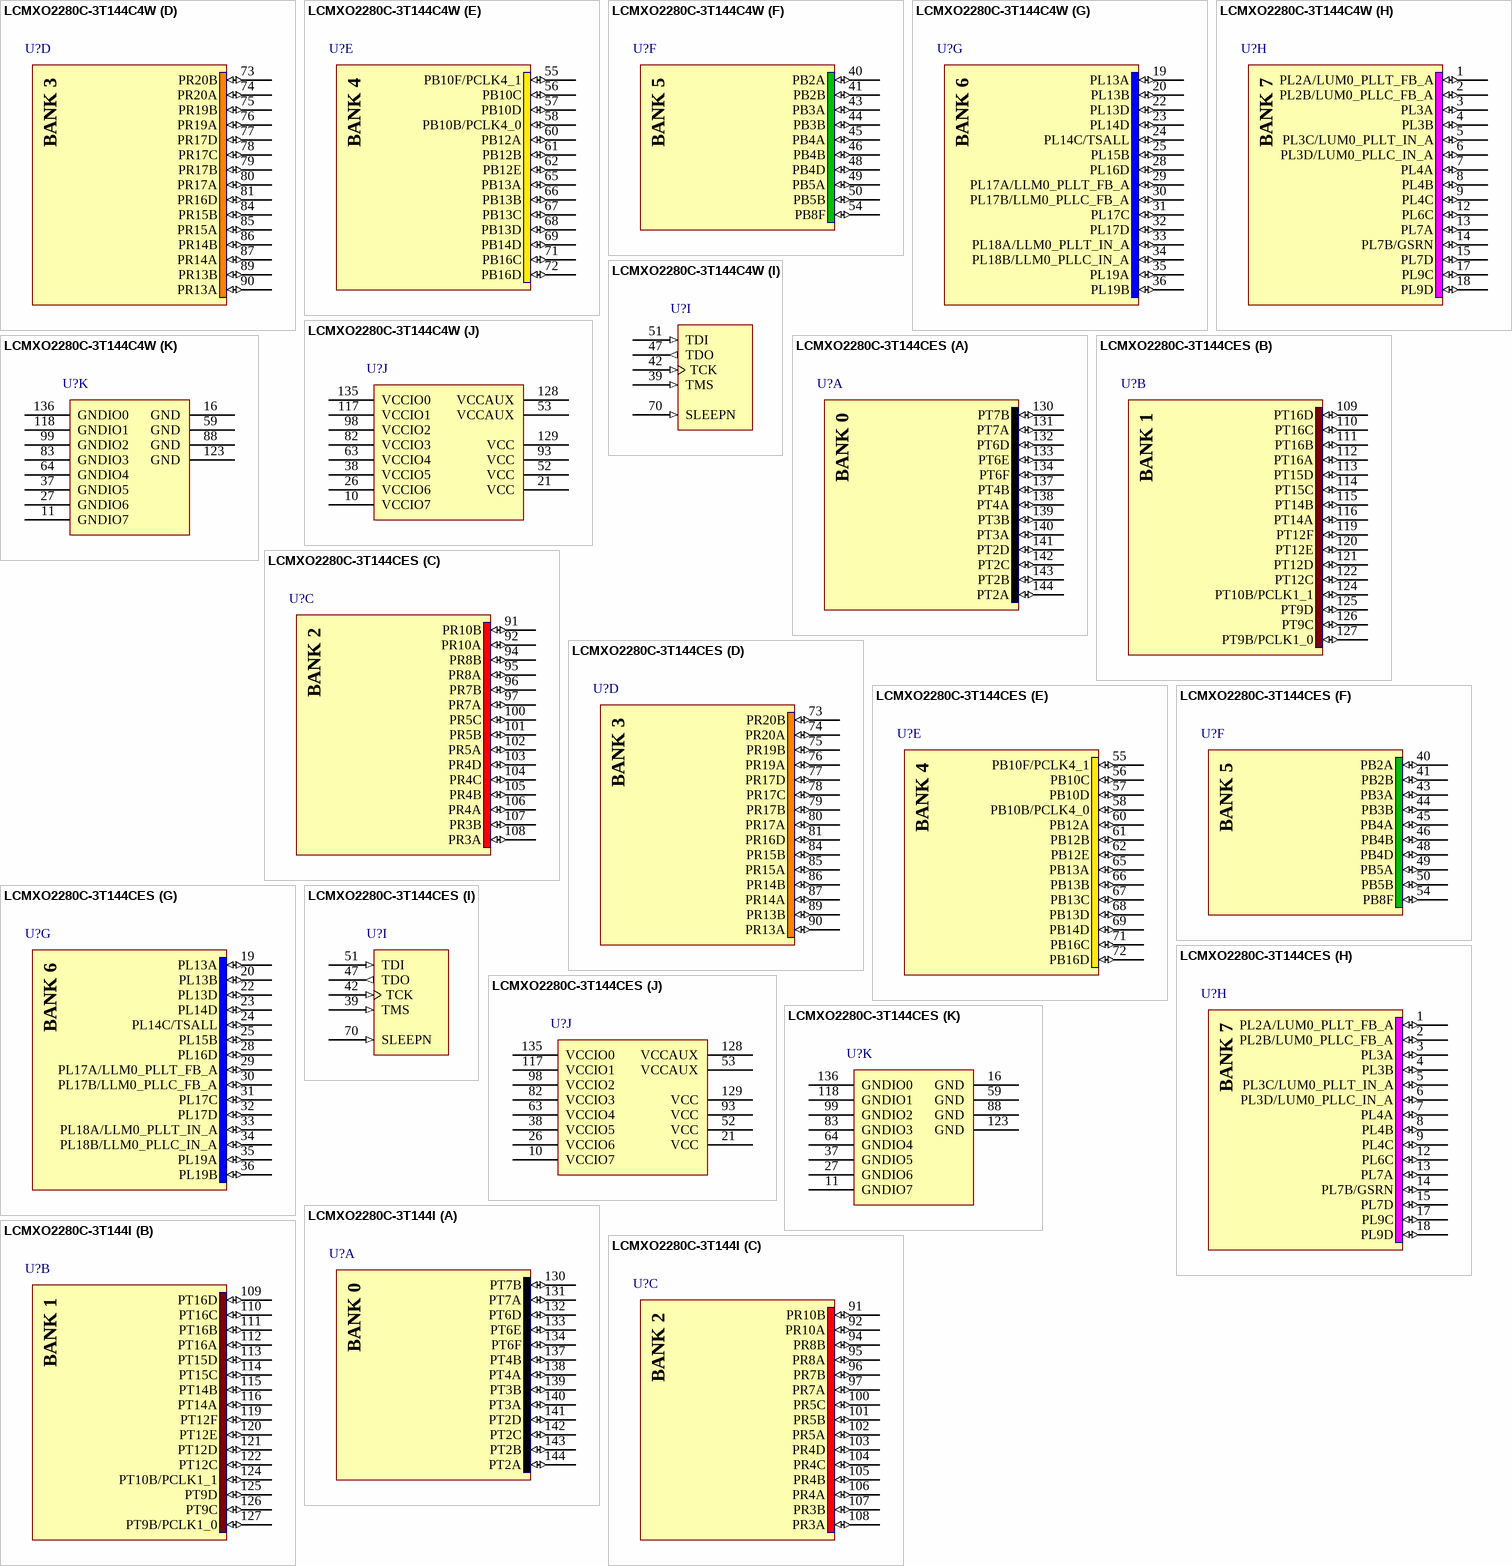
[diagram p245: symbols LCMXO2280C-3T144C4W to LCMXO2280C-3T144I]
## LCMXO2280C-3T144C4W
designator U?
MachXO 2280 Crossover PLD, 1.8V/2.5V/3.3V, 113 User I/Os, 144-Pins TQFP, Speed Grade-3, Commercial Grade
footprint TQFP144_N (Thin QFP, 144-Leads, Body 20x20mm, Pitch 0.5mm, IPC Medium Density)
footprint TQFP144_L (Thin QFP, 144-Leads, Body 20x20mm, Pitch 0.5mm, IPC High Density)
footprint TQFP144_M (Thin QFP, 144-Leads, Body 20x20mm, Pitch 0.5mm, IPC Low Density)
3D model MachXO2280-TQFP144 (144-Pin Thin Quad Flat Pack (TQFP144))
signal-integrity model LCMXO2280C_T144 (MachXO)
part A pins: 130 PT7B (io), 131 PT7A (io), 132 PT6D (io), 133 PT6E (io), 134 PT6F (io), 137 PT4B (io), 138 PT4A (io), 139 PT3B (io), 140 PT3A (io), 141 PT2D (io), 142 PT2C (io), 143 PT2B (io), 144 PT2A (io)
part B pins: 109 PT16D (io), 110 PT16C (io), 111 PT16B (io), 112 PT16A (io), 113 PT15D (io), 114 PT15C (io), 115 PT14B (io), 116 PT14A (io), 119 PT12F (io), 120 PT12E (io), 121 PT12D (io), 122 PT12C (io), 124 PT10B/PCLK1_1 (io), 125 PT9D (io), 126 PT9C (io), 127 PT9B/PCLK1_0 (io)
part C pins: 91 PR10B (io), 92 PR10A (io), 94 PR8B (io), 95 PR8A (io), 96 PR7B (io), 97 PR7A (io), 100 PR5C (io), 101 PR5B (io), 102 PR5A (io), 103 PR4D (io), 104 PR4C (io), 105 PR4B (io), 106 PR4A (io), 107 PR3B (io), 108 PR3A (io)
part D pins: 73 PR20B (io), 74 PR20A (io), 75 PR19B (io), 76 PR19A (io), 77 PR17D (io), 78 PR17C (io), 79 PR17B (io), 80 PR17A (io), 81 PR16D (io), 84 PR15B (io), 85 PR15A (io), 86 PR14B (io), 87 PR14A (io), 89 PR13B (io), 90 PR13A (io)
part E pins: 55 PB10F/PCLK4_1 (io), 56 PB10C (io), 57 PB10D (io), 58 PB10B/PCLK4_0 (io), 60 PB12A (io), 61 PB12B (io), 62 PB12E (io), 65 PB13A (io), 66 PB13B (io), 67 PB13C (io), 68 PB13D (io), 69 PB14D (io), 71 PB16C (io), 72 PB16D (io)
part F pins: 40 PB2A (io), 41 PB2B (io), 43 PB3A (io), 44 PB3B (io), 45 PB4A (io), 46 PB4B (io), 48 PB4D (io), 49 PB5A (io), 50 PB5B (io), 54 PB8F (io)
part G pins: 19 PL13A (io), 20 PL13B (io), 22 PL13D (io), 23 PL14D (io), 24 PL14C/TSALL (io), 25 PL15B (io), 28 PL16D (io), 29 PL17A/LLM0_PLLT_FB_A (io), 30 PL17B/LLM0_PLLC_FB_A (io), 31 PL17C (io), 32 PL17D (io), 33 PL18A/LLM0_PLLT_IN_A (io), 34 PL18B/LLM0_PLLC_IN_A (io), 35 PL19A (io), 36 PL19B (io)
part H pins: 1 PL2A/LUM0_PLLT_FB_A (io), 2 PL2B/LUM0_PLLC_FB_A (io), 3 PL3A (io), 4 PL3B (io), 5 PL3C/LUM0_PLLT_IN_A (io), 6 PL3D/LUM0_PLLC_IN_A (io), 7 PL4A (io), 8 PL4B (io), 9 PL4C (io), 12 PL6C (io), 13 PL7A (io), 14 PL7B/GSRN (io), 15 PL7D (io), 17 PL9C (io), 18 PL9D (io)
part I pins: 39 TMS (in) "Powered by VCCIO5", 42 TCK (in) "Powered by VCCIO5", 47 TDO (out) "Powered by VCCIO5", 51 TDI (in) "Powered by VCCIO5", 70 SLEEPN (in) "Powered by VCCIO4"
part J pins: 10 VCCIO7 (power), 21 VCC (power), 26 VCCIO6 (power), 38 VCCIO5 (power), 52 VCC (power), 53 VCCAUX (power), 63 VCCIO4 (power), 82 VCCIO3 (power), 93 VCC (power), 98 VCCIO2 (power), 117 VCCIO1 (power), 128 VCCAUX (power), 129 VCC (power), 135 VCCIO0 (power)
part K pins: 11 GNDIO7 (power), 16 GND (power), 27 GNDIO6 (power), 37 GNDIO5 (power), 59 GND (power), 64 GNDIO4 (power), 83 GNDIO3 (power), 88 GND (power), 99 GNDIO2 (power), 118 GNDIO1 (power), 123 GND (power), 136 GNDIO0 (power)

## LCMXO2280C-3T144CES
designator U?
MachXO 2280 Crossover PLD, 1.8V/2.5V/3.3V, 113 User I/Os, 144-Pins TQFP, Speed Grade-3, Commercial Grade, Engineering Sample
footprint TQFP144_N (Thin QFP, 144-Leads, Body 20x20mm, Pitch 0.5mm, IPC Medium Density)
footprint TQFP144_L (Thin QFP, 144-Leads, Body 20x20mm, Pitch 0.5mm, IPC High Density)
footprint TQFP144_M (Thin QFP, 144-Leads, Body 20x20mm, Pitch 0.5mm, IPC Low Density)
3D model MachXO2280-TQFP144 (144-Pin Thin Quad Flat Pack (TQFP144))
signal-integrity model LCMXO2280C_T144 (MachXO)
part A pins: 130 PT7B (io), 131 PT7A (io), 132 PT6D (io), 133 PT6E (io), 134 PT6F (io), 137 PT4B (io), 138 PT4A (io), 139 PT3B (io), 140 PT3A (io), 141 PT2D (io), 142 PT2C (io), 143 PT2B (io), 144 PT2A (io)
part B pins: 109 PT16D (io), 110 PT16C (io), 111 PT16B (io), 112 PT16A (io), 113 PT15D (io), 114 PT15C (io), 115 PT14B (io), 116 PT14A (io), 119 PT12F (io), 120 PT12E (io), 121 PT12D (io), 122 PT12C (io), 124 PT10B/PCLK1_1 (io), 125 PT9D (io), 126 PT9C (io), 127 PT9B/PCLK1_0 (io)
part C pins: 91 PR10B (io), 92 PR10A (io), 94 PR8B (io), 95 PR8A (io), 96 PR7B (io), 97 PR7A (io), 100 PR5C (io), 101 PR5B (io), 102 PR5A (io), 103 PR4D (io), 104 PR4C (io), 105 PR4B (io), 106 PR4A (io), 107 PR3B (io), 108 PR3A (io)
part D pins: 73 PR20B (io), 74 PR20A (io), 75 PR19B (io), 76 PR19A (io), 77 PR17D (io), 78 PR17C (io), 79 PR17B (io), 80 PR17A (io), 81 PR16D (io), 84 PR15B (io), 85 PR15A (io), 86 PR14B (io), 87 PR14A (io), 89 PR13B (io), 90 PR13A (io)
part E pins: 55 PB10F/PCLK4_1 (io), 56 PB10C (io), 57 PB10D (io), 58 PB10B/PCLK4_0 (io), 60 PB12A (io), 61 PB12B (io), 62 PB12E (io), 65 PB13A (io), 66 PB13B (io), 67 PB13C (io), 68 PB13D (io), 69 PB14D (io), 71 PB16C (io), 72 PB16D (io)
part F pins: 40 PB2A (io), 41 PB2B (io), 43 PB3A (io), 44 PB3B (io), 45 PB4A (io), 46 PB4B (io), 48 PB4D (io), 49 PB5A (io), 50 PB5B (io), 54 PB8F (io)
part G pins: 19 PL13A (io), 20 PL13B (io), 22 PL13D (io), 23 PL14D (io), 24 PL14C/TSALL (io), 25 PL15B (io), 28 PL16D (io), 29 PL17A/LLM0_PLLT_FB_A (io), 30 PL17B/LLM0_PLLC_FB_A (io), 31 PL17C (io), 32 PL17D (io), 33 PL18A/LLM0_PLLT_IN_A (io), 34 PL18B/LLM0_PLLC_IN_A (io), 35 PL19A (io), 36 PL19B (io)
part H pins: 1 PL2A/LUM0_PLLT_FB_A (io), 2 PL2B/LUM0_PLLC_FB_A (io), 3 PL3A (io), 4 PL3B (io), 5 PL3C/LUM0_PLLT_IN_A (io), 6 PL3D/LUM0_PLLC_IN_A (io), 7 PL4A (io), 8 PL4B (io), 9 PL4C (io), 12 PL6C (io), 13 PL7A (io), 14 PL7B/GSRN (io), 15 PL7D (io), 17 PL9C (io), 18 PL9D (io)
part I pins: 39 TMS (in) "Powered by VCCIO5", 42 TCK (in) "Powered by VCCIO5", 47 TDO (out) "Powered by VCCIO5", 51 TDI (in) "Powered by VCCIO5", 70 SLEEPN (in) "Powered by VCCIO4"
part J pins: 10 VCCIO7 (power), 21 VCC (power), 26 VCCIO6 (power), 38 VCCIO5 (power), 52 VCC (power), 53 VCCAUX (power), 63 VCCIO4 (power), 82 VCCIO3 (power), 93 VCC (power), 98 VCCIO2 (power), 117 VCCIO1 (power), 128 VCCAUX (power), 129 VCC (power), 135 VCCIO0 (power)
part K pins: 11 GNDIO7 (power), 16 GND (power), 27 GNDIO6 (power), 37 GNDIO5 (power), 59 GND (power), 64 GNDIO4 (power), 83 GNDIO3 (power), 88 GND (power), 99 GNDIO2 (power), 118 GNDIO1 (power), 123 GND (power), 136 GNDIO0 (power)


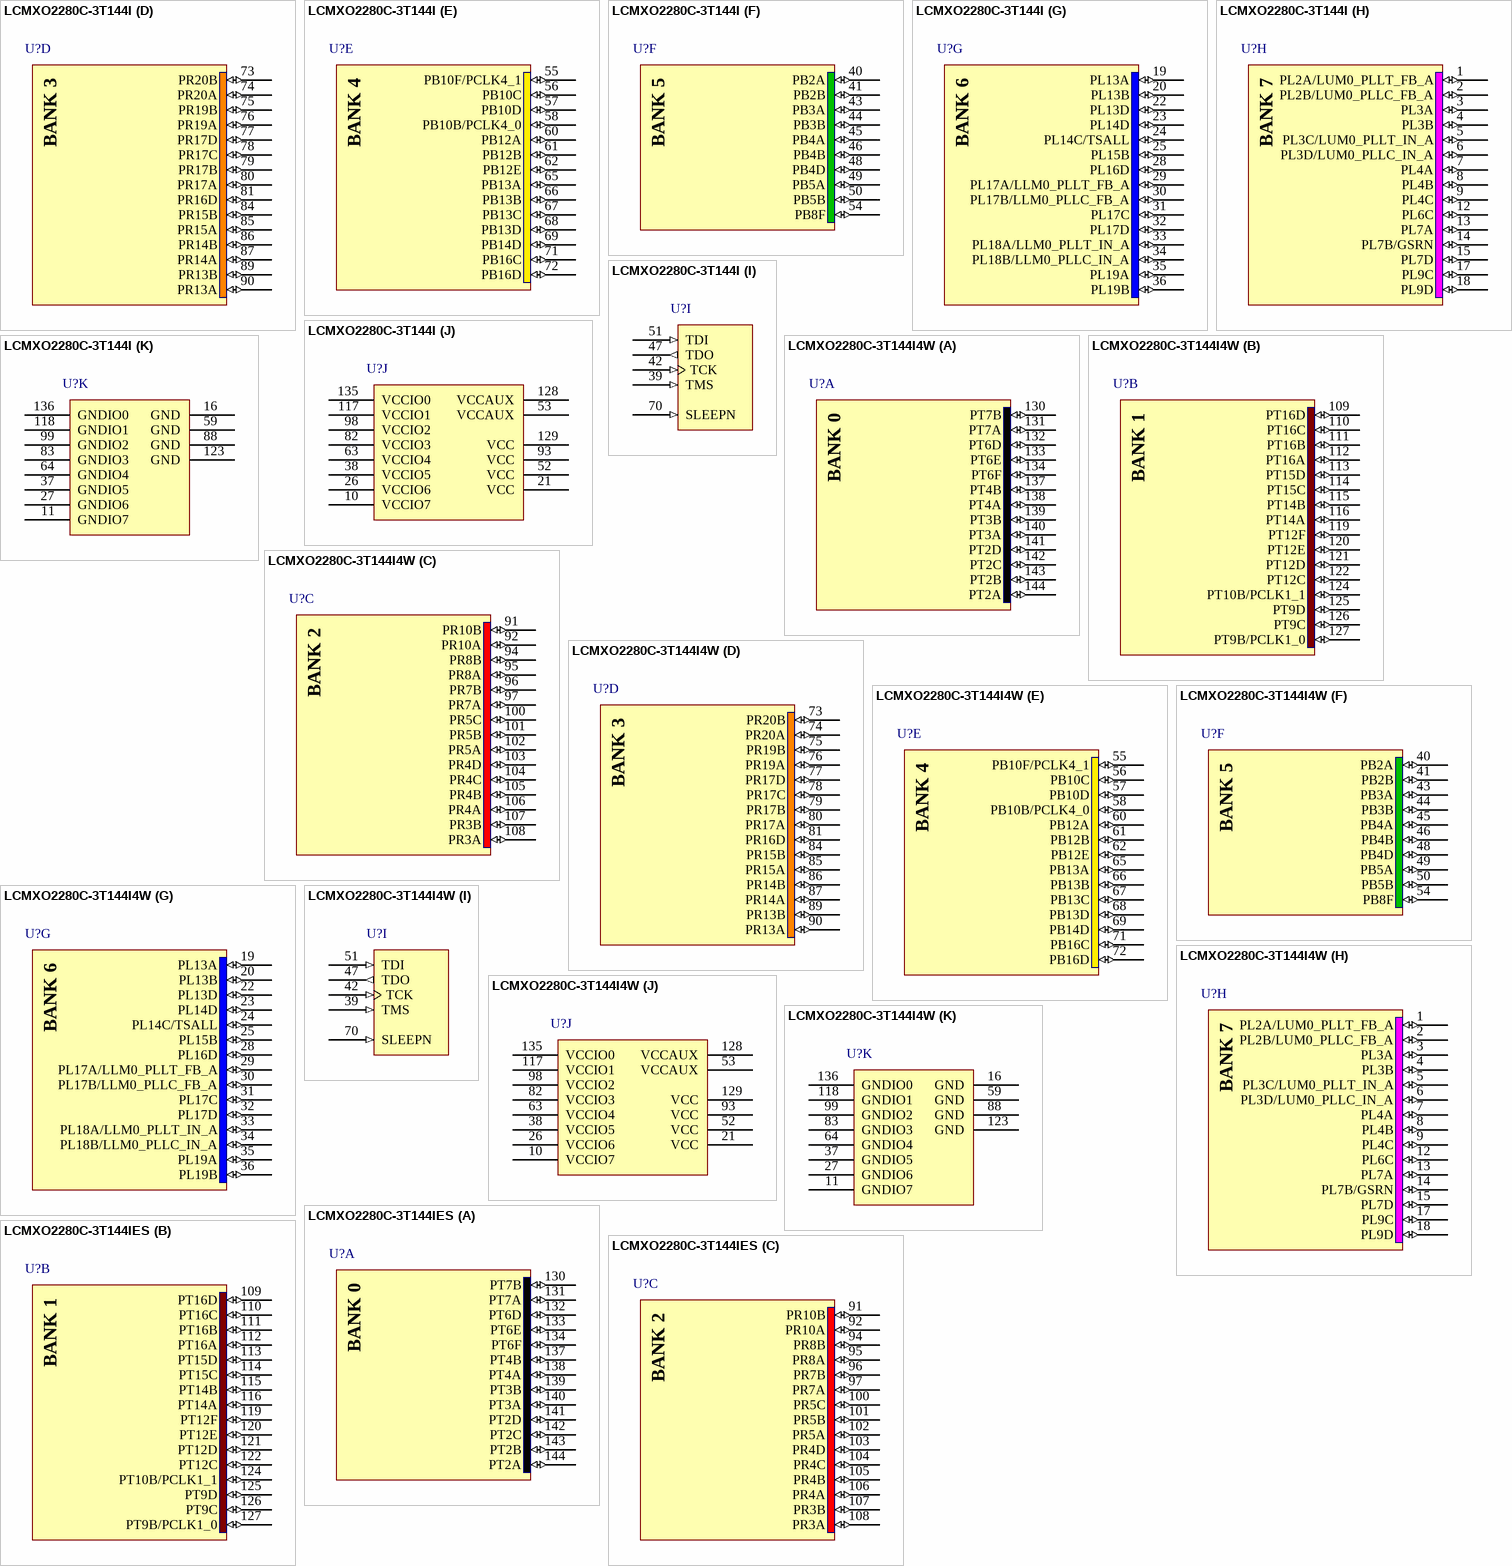
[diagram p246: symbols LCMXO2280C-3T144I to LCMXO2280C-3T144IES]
## LCMXO2280C-3T144I
designator U?
MachXO 2280 Crossover PLD, 1.8V/2.5V/3.3V, 113 User I/Os, 144-Pins TQFP, Speed Grade-3, Industrial Grade
footprint TQFP144_N (Thin QFP, 144-Leads, Body 20x20mm, Pitch 0.5mm, IPC Medium Density)
footprint TQFP144_L (Thin QFP, 144-Leads, Body 20x20mm, Pitch 0.5mm, IPC High Density)
footprint TQFP144_M (Thin QFP, 144-Leads, Body 20x20mm, Pitch 0.5mm, IPC Low Density)
3D model MachXO2280-TQFP144 (144-Pin Thin Quad Flat Pack (TQFP144))
signal-integrity model LCMXO2280C_T144 (MachXO)
part A pins: 130 PT7B (io), 131 PT7A (io), 132 PT6D (io), 133 PT6E (io), 134 PT6F (io), 137 PT4B (io), 138 PT4A (io), 139 PT3B (io), 140 PT3A (io), 141 PT2D (io), 142 PT2C (io), 143 PT2B (io), 144 PT2A (io)
part B pins: 109 PT16D (io), 110 PT16C (io), 111 PT16B (io), 112 PT16A (io), 113 PT15D (io), 114 PT15C (io), 115 PT14B (io), 116 PT14A (io), 119 PT12F (io), 120 PT12E (io), 121 PT12D (io), 122 PT12C (io), 124 PT10B/PCLK1_1 (io), 125 PT9D (io), 126 PT9C (io), 127 PT9B/PCLK1_0 (io)
part C pins: 91 PR10B (io), 92 PR10A (io), 94 PR8B (io), 95 PR8A (io), 96 PR7B (io), 97 PR7A (io), 100 PR5C (io), 101 PR5B (io), 102 PR5A (io), 103 PR4D (io), 104 PR4C (io), 105 PR4B (io), 106 PR4A (io), 107 PR3B (io), 108 PR3A (io)
part D pins: 73 PR20B (io), 74 PR20A (io), 75 PR19B (io), 76 PR19A (io), 77 PR17D (io), 78 PR17C (io), 79 PR17B (io), 80 PR17A (io), 81 PR16D (io), 84 PR15B (io), 85 PR15A (io), 86 PR14B (io), 87 PR14A (io), 89 PR13B (io), 90 PR13A (io)
part E pins: 55 PB10F/PCLK4_1 (io), 56 PB10C (io), 57 PB10D (io), 58 PB10B/PCLK4_0 (io), 60 PB12A (io), 61 PB12B (io), 62 PB12E (io), 65 PB13A (io), 66 PB13B (io), 67 PB13C (io), 68 PB13D (io), 69 PB14D (io), 71 PB16C (io), 72 PB16D (io)
part F pins: 40 PB2A (io), 41 PB2B (io), 43 PB3A (io), 44 PB3B (io), 45 PB4A (io), 46 PB4B (io), 48 PB4D (io), 49 PB5A (io), 50 PB5B (io), 54 PB8F (io)
part G pins: 19 PL13A (io), 20 PL13B (io), 22 PL13D (io), 23 PL14D (io), 24 PL14C/TSALL (io), 25 PL15B (io), 28 PL16D (io), 29 PL17A/LLM0_PLLT_FB_A (io), 30 PL17B/LLM0_PLLC_FB_A (io), 31 PL17C (io), 32 PL17D (io), 33 PL18A/LLM0_PLLT_IN_A (io), 34 PL18B/LLM0_PLLC_IN_A (io), 35 PL19A (io), 36 PL19B (io)
part H pins: 1 PL2A/LUM0_PLLT_FB_A (io), 2 PL2B/LUM0_PLLC_FB_A (io), 3 PL3A (io), 4 PL3B (io), 5 PL3C/LUM0_PLLT_IN_A (io), 6 PL3D/LUM0_PLLC_IN_A (io), 7 PL4A (io), 8 PL4B (io), 9 PL4C (io), 12 PL6C (io), 13 PL7A (io), 14 PL7B/GSRN (io), 15 PL7D (io), 17 PL9C (io), 18 PL9D (io)
part I pins: 39 TMS (in) "Powered by VCCIO5", 42 TCK (in) "Powered by VCCIO5", 47 TDO (out) "Powered by VCCIO5", 51 TDI (in) "Powered by VCCIO5", 70 SLEEPN (in) "Powered by VCCIO4"
part J pins: 10 VCCIO7 (power), 21 VCC (power), 26 VCCIO6 (power), 38 VCCIO5 (power), 52 VCC (power), 53 VCCAUX (power), 63 VCCIO4 (power), 82 VCCIO3 (power), 93 VCC (power), 98 VCCIO2 (power), 117 VCCIO1 (power), 128 VCCAUX (power), 129 VCC (power), 135 VCCIO0 (power)
part K pins: 11 GNDIO7 (power), 16 GND (power), 27 GNDIO6 (power), 37 GNDIO5 (power), 59 GND (power), 64 GNDIO4 (power), 83 GNDIO3 (power), 88 GND (power), 99 GNDIO2 (power), 118 GNDIO1 (power), 123 GND (power), 136 GNDIO0 (power)

## LCMXO2280C-3T144I4W
designator U?
MachXO 2280 Crossover PLD, 1.8V/2.5V/3.3V, 113 User I/Os, 144-Pins TQFP, Speed Grade-3, Industrial Grade
footprint TQFP144_N (Thin QFP, 144-Leads, Body 20x20mm, Pitch 0.5mm, IPC Medium Density)
footprint TQFP144_L (Thin QFP, 144-Leads, Body 20x20mm, Pitch 0.5mm, IPC High Density)
footprint TQFP144_M (Thin QFP, 144-Leads, Body 20x20mm, Pitch 0.5mm, IPC Low Density)
3D model MachXO2280-TQFP144 (144-Pin Thin Quad Flat Pack (TQFP144))
signal-integrity model LCMXO2280C_T144 (MachXO)
part A pins: 130 PT7B (io), 131 PT7A (io), 132 PT6D (io), 133 PT6E (io), 134 PT6F (io), 137 PT4B (io), 138 PT4A (io), 139 PT3B (io), 140 PT3A (io), 141 PT2D (io), 142 PT2C (io), 143 PT2B (io), 144 PT2A (io)
part B pins: 109 PT16D (io), 110 PT16C (io), 111 PT16B (io), 112 PT16A (io), 113 PT15D (io), 114 PT15C (io), 115 PT14B (io), 116 PT14A (io), 119 PT12F (io), 120 PT12E (io), 121 PT12D (io), 122 PT12C (io), 124 PT10B/PCLK1_1 (io), 125 PT9D (io), 126 PT9C (io), 127 PT9B/PCLK1_0 (io)
part C pins: 91 PR10B (io), 92 PR10A (io), 94 PR8B (io), 95 PR8A (io), 96 PR7B (io), 97 PR7A (io), 100 PR5C (io), 101 PR5B (io), 102 PR5A (io), 103 PR4D (io), 104 PR4C (io), 105 PR4B (io), 106 PR4A (io), 107 PR3B (io), 108 PR3A (io)
part D pins: 73 PR20B (io), 74 PR20A (io), 75 PR19B (io), 76 PR19A (io), 77 PR17D (io), 78 PR17C (io), 79 PR17B (io), 80 PR17A (io), 81 PR16D (io), 84 PR15B (io), 85 PR15A (io), 86 PR14B (io), 87 PR14A (io), 89 PR13B (io), 90 PR13A (io)
part E pins: 55 PB10F/PCLK4_1 (io), 56 PB10C (io), 57 PB10D (io), 58 PB10B/PCLK4_0 (io), 60 PB12A (io), 61 PB12B (io), 62 PB12E (io), 65 PB13A (io), 66 PB13B (io), 67 PB13C (io), 68 PB13D (io), 69 PB14D (io), 71 PB16C (io), 72 PB16D (io)
part F pins: 40 PB2A (io), 41 PB2B (io), 43 PB3A (io), 44 PB3B (io), 45 PB4A (io), 46 PB4B (io), 48 PB4D (io), 49 PB5A (io), 50 PB5B (io), 54 PB8F (io)
part G pins: 19 PL13A (io), 20 PL13B (io), 22 PL13D (io), 23 PL14D (io), 24 PL14C/TSALL (io), 25 PL15B (io), 28 PL16D (io), 29 PL17A/LLM0_PLLT_FB_A (io), 30 PL17B/LLM0_PLLC_FB_A (io), 31 PL17C (io), 32 PL17D (io), 33 PL18A/LLM0_PLLT_IN_A (io), 34 PL18B/LLM0_PLLC_IN_A (io), 35 PL19A (io), 36 PL19B (io)
part H pins: 1 PL2A/LUM0_PLLT_FB_A (io), 2 PL2B/LUM0_PLLC_FB_A (io), 3 PL3A (io), 4 PL3B (io), 5 PL3C/LUM0_PLLT_IN_A (io), 6 PL3D/LUM0_PLLC_IN_A (io), 7 PL4A (io), 8 PL4B (io), 9 PL4C (io), 12 PL6C (io), 13 PL7A (io), 14 PL7B/GSRN (io), 15 PL7D (io), 17 PL9C (io), 18 PL9D (io)
part I pins: 39 TMS (in) "Powered by VCCIO5", 42 TCK (in) "Powered by VCCIO5", 47 TDO (out) "Powered by VCCIO5", 51 TDI (in) "Powered by VCCIO5", 70 SLEEPN (in) "Powered by VCCIO4"
part J pins: 10 VCCIO7 (power), 21 VCC (power), 26 VCCIO6 (power), 38 VCCIO5 (power), 52 VCC (power), 53 VCCAUX (power), 63 VCCIO4 (power), 82 VCCIO3 (power), 93 VCC (power), 98 VCCIO2 (power), 117 VCCIO1 (power), 128 VCCAUX (power), 129 VCC (power), 135 VCCIO0 (power)
part K pins: 11 GNDIO7 (power), 16 GND (power), 27 GNDIO6 (power), 37 GNDIO5 (power), 59 GND (power), 64 GNDIO4 (power), 83 GNDIO3 (power), 88 GND (power), 99 GNDIO2 (power), 118 GNDIO1 (power), 123 GND (power), 136 GNDIO0 (power)


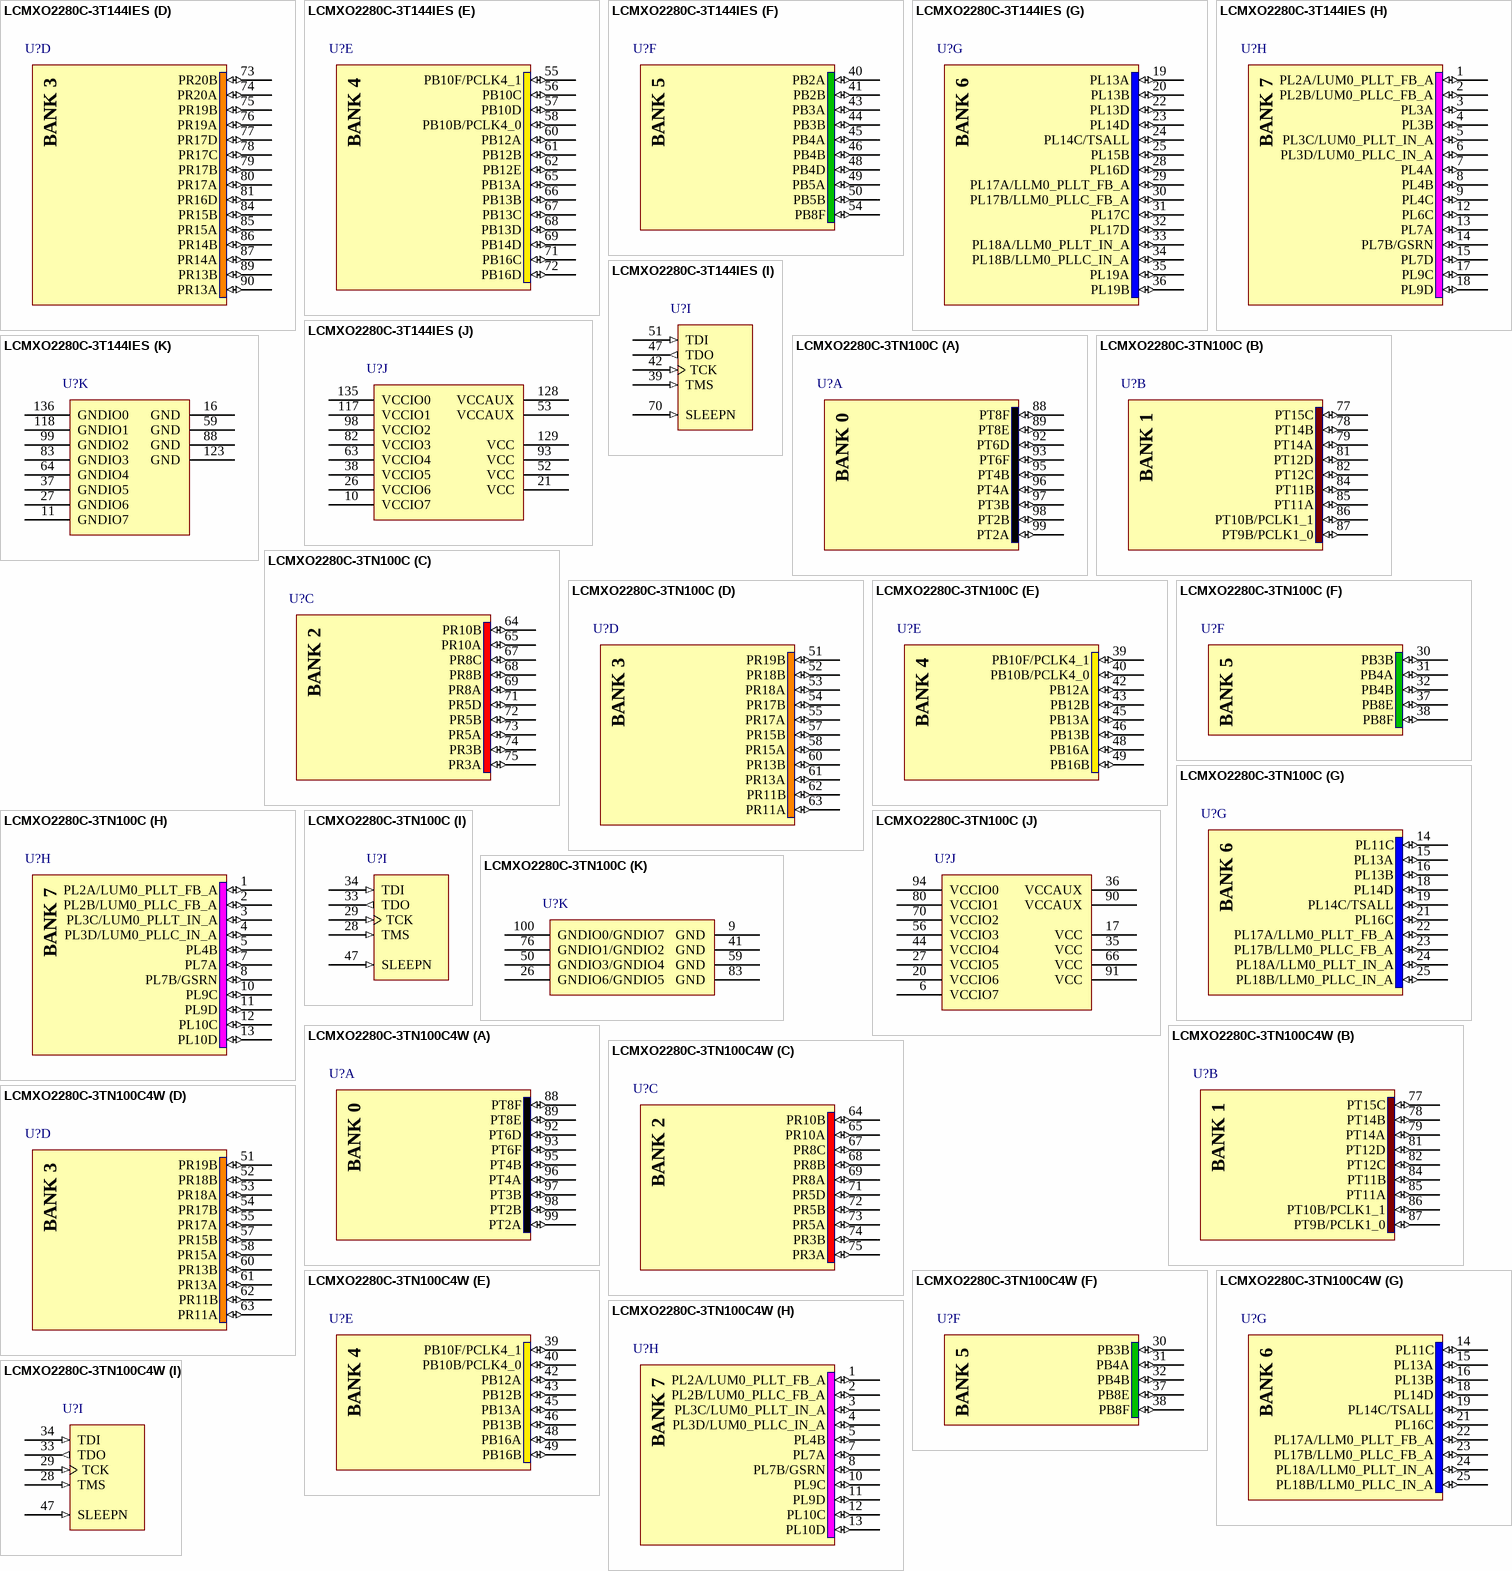
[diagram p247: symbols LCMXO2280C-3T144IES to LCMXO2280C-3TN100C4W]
## LCMXO2280C-3T144IES
designator U?
MachXO 2280 Crossover PLD, 1.8V/2.5V/3.3V, 113 User I/Os, 144-Pins TQFP, Speed Grade-3, Industrial Grade, Engineering Sample
footprint TQFP144_N (Thin QFP, 144-Leads, Body 20x20mm, Pitch 0.5mm, IPC Medium Density)
footprint TQFP144_L (Thin QFP, 144-Leads, Body 20x20mm, Pitch 0.5mm, IPC High Density)
footprint TQFP144_M (Thin QFP, 144-Leads, Body 20x20mm, Pitch 0.5mm, IPC Low Density)
3D model MachXO2280-TQFP144 (144-Pin Thin Quad Flat Pack (TQFP144))
signal-integrity model LCMXO2280C_T144 (MachXO)
part A pins: 130 PT7B (io), 131 PT7A (io), 132 PT6D (io), 133 PT6E (io), 134 PT6F (io), 137 PT4B (io), 138 PT4A (io), 139 PT3B (io), 140 PT3A (io), 141 PT2D (io), 142 PT2C (io), 143 PT2B (io), 144 PT2A (io)
part B pins: 109 PT16D (io), 110 PT16C (io), 111 PT16B (io), 112 PT16A (io), 113 PT15D (io), 114 PT15C (io), 115 PT14B (io), 116 PT14A (io), 119 PT12F (io), 120 PT12E (io), 121 PT12D (io), 122 PT12C (io), 124 PT10B/PCLK1_1 (io), 125 PT9D (io), 126 PT9C (io), 127 PT9B/PCLK1_0 (io)
part C pins: 91 PR10B (io), 92 PR10A (io), 94 PR8B (io), 95 PR8A (io), 96 PR7B (io), 97 PR7A (io), 100 PR5C (io), 101 PR5B (io), 102 PR5A (io), 103 PR4D (io), 104 PR4C (io), 105 PR4B (io), 106 PR4A (io), 107 PR3B (io), 108 PR3A (io)
part D pins: 73 PR20B (io), 74 PR20A (io), 75 PR19B (io), 76 PR19A (io), 77 PR17D (io), 78 PR17C (io), 79 PR17B (io), 80 PR17A (io), 81 PR16D (io), 84 PR15B (io), 85 PR15A (io), 86 PR14B (io), 87 PR14A (io), 89 PR13B (io), 90 PR13A (io)
part E pins: 55 PB10F/PCLK4_1 (io), 56 PB10C (io), 57 PB10D (io), 58 PB10B/PCLK4_0 (io), 60 PB12A (io), 61 PB12B (io), 62 PB12E (io), 65 PB13A (io), 66 PB13B (io), 67 PB13C (io), 68 PB13D (io), 69 PB14D (io), 71 PB16C (io), 72 PB16D (io)
part F pins: 40 PB2A (io), 41 PB2B (io), 43 PB3A (io), 44 PB3B (io), 45 PB4A (io), 46 PB4B (io), 48 PB4D (io), 49 PB5A (io), 50 PB5B (io), 54 PB8F (io)
part G pins: 19 PL13A (io), 20 PL13B (io), 22 PL13D (io), 23 PL14D (io), 24 PL14C/TSALL (io), 25 PL15B (io), 28 PL16D (io), 29 PL17A/LLM0_PLLT_FB_A (io), 30 PL17B/LLM0_PLLC_FB_A (io), 31 PL17C (io), 32 PL17D (io), 33 PL18A/LLM0_PLLT_IN_A (io), 34 PL18B/LLM0_PLLC_IN_A (io), 35 PL19A (io), 36 PL19B (io)
part H pins: 1 PL2A/LUM0_PLLT_FB_A (io), 2 PL2B/LUM0_PLLC_FB_A (io), 3 PL3A (io), 4 PL3B (io), 5 PL3C/LUM0_PLLT_IN_A (io), 6 PL3D/LUM0_PLLC_IN_A (io), 7 PL4A (io), 8 PL4B (io), 9 PL4C (io), 12 PL6C (io), 13 PL7A (io), 14 PL7B/GSRN (io), 15 PL7D (io), 17 PL9C (io), 18 PL9D (io)
part I pins: 39 TMS (in) "Powered by VCCIO5", 42 TCK (in) "Powered by VCCIO5", 47 TDO (out) "Powered by VCCIO5", 51 TDI (in) "Powered by VCCIO5", 70 SLEEPN (in) "Powered by VCCIO4"
part J pins: 10 VCCIO7 (power), 21 VCC (power), 26 VCCIO6 (power), 38 VCCIO5 (power), 52 VCC (power), 53 VCCAUX (power), 63 VCCIO4 (power), 82 VCCIO3 (power), 93 VCC (power), 98 VCCIO2 (power), 117 VCCIO1 (power), 128 VCCAUX (power), 129 VCC (power), 135 VCCIO0 (power)
part K pins: 11 GNDIO7 (power), 16 GND (power), 27 GNDIO6 (power), 37 GNDIO5 (power), 59 GND (power), 64 GNDIO4 (power), 83 GNDIO3 (power), 88 GND (power), 99 GNDIO2 (power), 118 GNDIO1 (power), 123 GND (power), 136 GNDIO0 (power)

## LCMXO2280C-3TN100C
designator U?
MachXO 2280 Crossover PLD, 1.8V/2.5V/3.3V, 73 User I/Os, 100-Pins TQFP, Speed Grade-3, Commercial Grade, Pb-Free
footprint TQFP100_N (Thin QFP, 100-Leads, Body 14x14mm, Pitch 0.5mm, IPC Medium Density)
footprint TQFP100_L (Thin QFP, 100-Leads, Body 14x14mm, Pitch 0.5mm, IPC High Density)
footprint TQFP100_M (Thin QFP, 100-Leads, Body 14x14mm, Pitch 0.5mm, IPC Low Density)
3D model MachXO2280-TQFP100 (100-Pin Thin Quad Flat Pack (TQFP100))
signal-integrity model LCMXO2280C_T100 (MachXO)
part A pins: 88 PT8F (io), 89 PT8E (io), 92 PT6D (io), 93 PT6F (io), 95 PT4B (io), 96 PT4A (io), 97 PT3B (io), 98 PT2B (io), 99 PT2A (io)
part B pins: 77 PT15C (io), 78 PT14B (io), 79 PT14A (io), 81 PT12D (io), 82 PT12C (io), 84 PT11B (io), 85 PT11A (io), 86 PT10B/PCLK1_1 (io), 87 PT9B/PCLK1_0 (io)
part C pins: 64 PR10B (io), 65 PR10A (io), 67 PR8C (io), 68 PR8B (io), 69 PR8A (io), 71 PR5D (io), 72 PR5B (io), 73 PR5A (io), 74 PR3B (io), 75 PR3A (io)
part D pins: 51 PR19B (io), 52 PR18B (io), 53 PR18A (io), 54 PR17B (io), 55 PR17A (io), 57 PR15B (io), 58 PR15A (io), 60 PR13B (io), 61 PR13A (io), 62 PR11B (io), 63 PR11A (io)
part E pins: 39 PB10F/PCLK4_1 (io), 40 PB10B/PCLK4_0 (io), 42 PB12A (io), 43 PB12B (io), 45 PB13A (io), 46 PB13B (io), 48 PB16A (io), 49 PB16B (io)
part F pins: 30 PB3B (io), 31 PB4A (io), 32 PB4B (io), 37 PB8E (io), 38 PB8F (io)
part G pins: 14 PL11C (io), 15 PL13A (io), 16 PL13B (io), 18 PL14D (io), 19 PL14C/TSALL (io), 21 PL16C (io), 22 PL17A/LLM0_PLLT_FB_A (io), 23 PL17B/LLM0_PLLC_FB_A (io), 24 PL18A/LLM0_PLLT_IN_A (io), 25 PL18B/LLM0_PLLC_IN_A (io)
part H pins: 1 PL2A/LUM0_PLLT_FB_A (io), 2 PL2B/LUM0_PLLC_FB_A (io), 3 PL3C/LUM0_PLLT_IN_A (io), 4 PL3D/LUM0_PLLC_IN_A (io), 5 PL4B (io), 7 PL7A (io), 8 PL7B/GSRN (io), 10 PL9C (io), 11 PL9D (io), 12 PL10C (io), 13 PL10D (io)
part I pins: 28 TMS (in) "Powered by VCCIO5", 29 TCK (in) "Powered by VCCIO5", 33 TDO (out) "Powered by VCCIO5", 34 TDI (in) "Powered by VCCIO5", 47 SLEEPN (in) "Powered by VCCIO4"
part J pins: 6 VCCIO7 (power), 17 VCC (power), 20 VCCIO6 (power), 27 VCCIO5 (power), 35 VCC (power), 36 VCCAUX (power), 44 VCCIO4 (power), 56 VCCIO3 (power), 66 VCC (power), 70 VCCIO2 (power), 80 VCCIO1 (power), 90 VCCAUX (power), 91 VCC (power), 94 VCCIO0 (power)
part K pins: 9 GND (power), 26 GNDIO6/GNDIO5 (power) "Double Bonded pin", 41 GND (power), 50 GNDIO3/GNDIO4 (power) "Double Bonded pin", 59 GND (power), 76 GNDIO1/GNDIO2 (power) "Double Bonded pin", 83 GND (power), 100 GNDIO0/GNDIO7 (power) "Double Bonded pin"


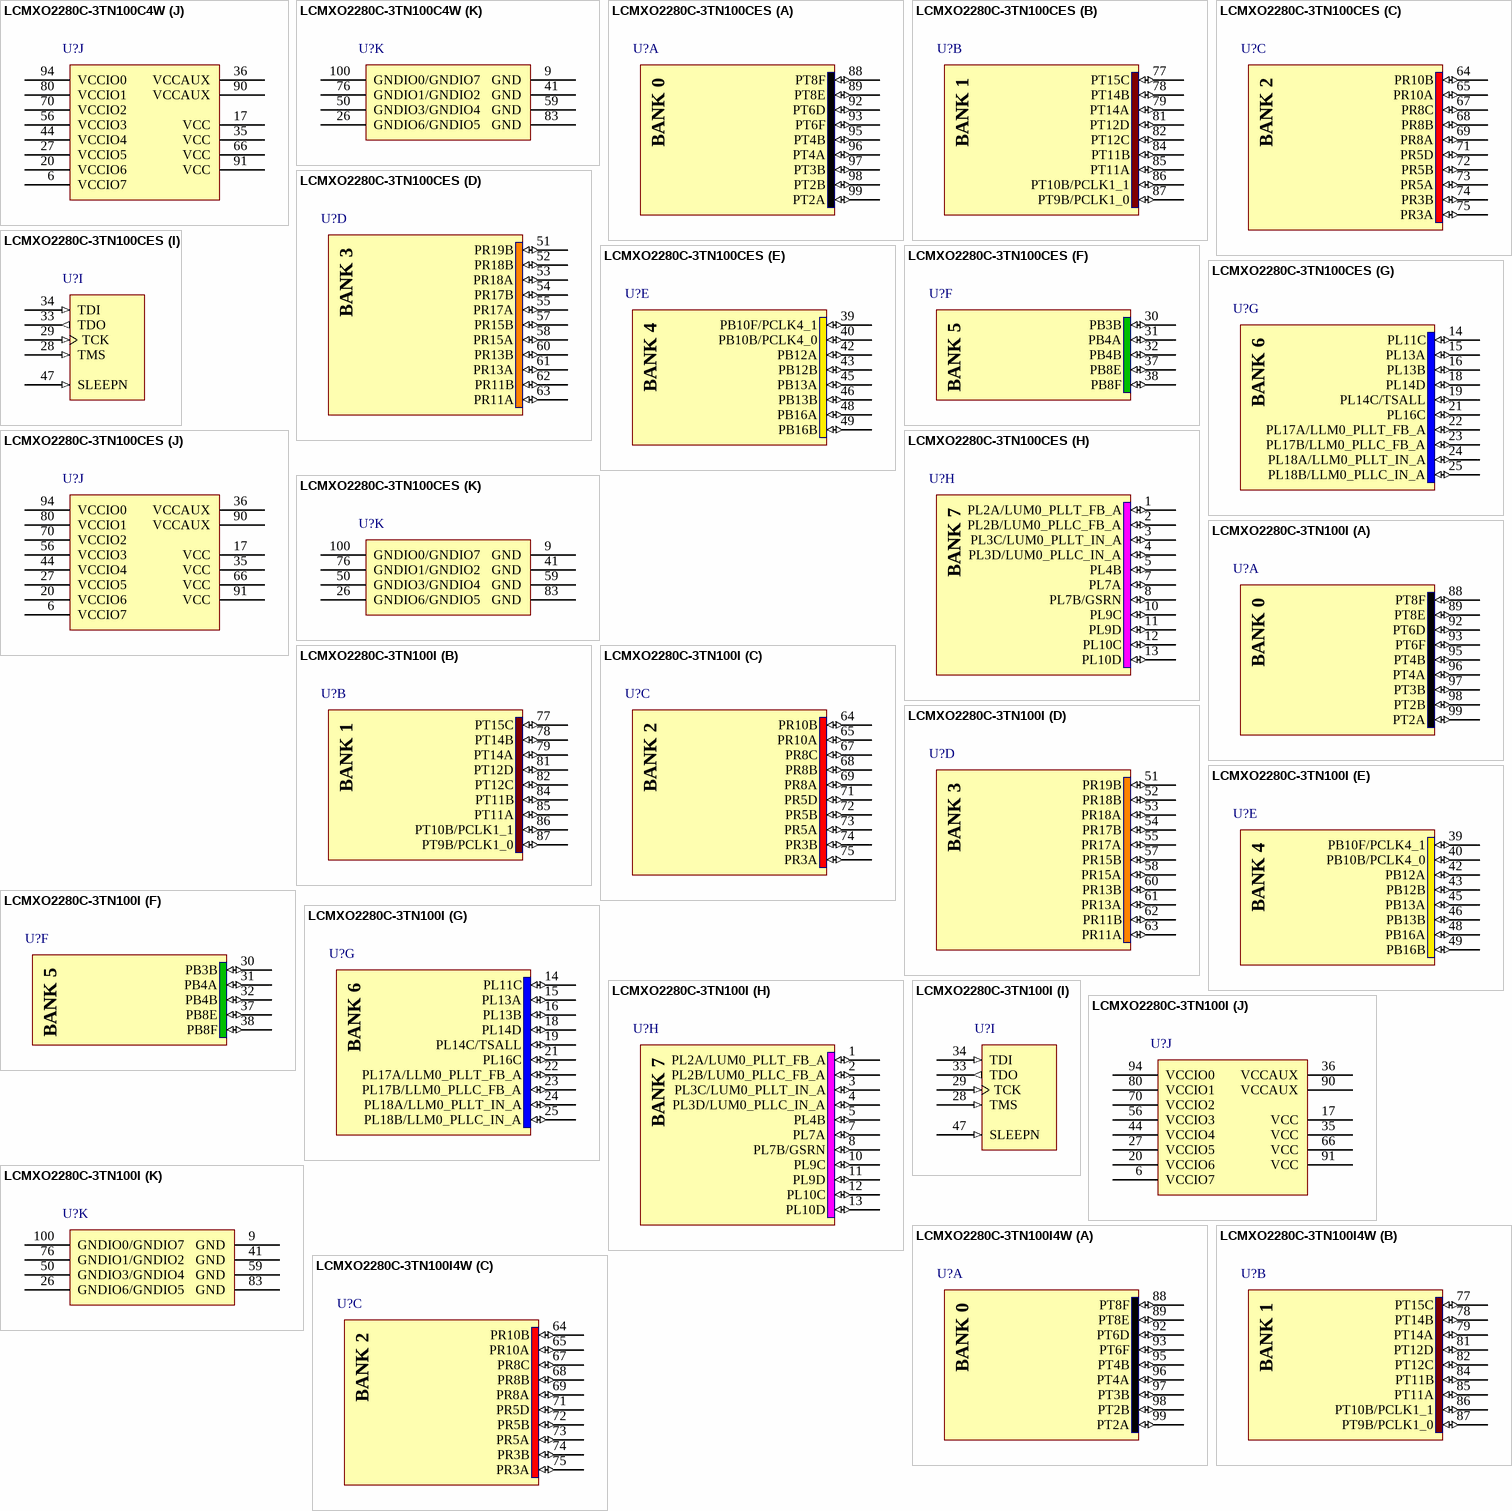
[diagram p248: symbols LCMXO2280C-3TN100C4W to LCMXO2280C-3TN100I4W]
## LCMXO2280C-3TN100C4W
designator U?
MachXO 2280 Crossover PLD, 1.8V/2.5V/3.3V, 73 User I/Os, 100-Pins TQFP, Speed Grade-3, Commercial Grade, Pb-Free
footprint TQFP100_N (Thin QFP, 100-Leads, Body 14x14mm, Pitch 0.5mm, IPC Medium Density)
footprint TQFP100_L (Thin QFP, 100-Leads, Body 14x14mm, Pitch 0.5mm, IPC High Density)
footprint TQFP100_M (Thin QFP, 100-Leads, Body 14x14mm, Pitch 0.5mm, IPC Low Density)
3D model MachXO2280-TQFP100 (100-Pin Thin Quad Flat Pack (TQFP100))
signal-integrity model LCMXO2280C_T100 (MachXO)
part A pins: 88 PT8F (io), 89 PT8E (io), 92 PT6D (io), 93 PT6F (io), 95 PT4B (io), 96 PT4A (io), 97 PT3B (io), 98 PT2B (io), 99 PT2A (io)
part B pins: 77 PT15C (io), 78 PT14B (io), 79 PT14A (io), 81 PT12D (io), 82 PT12C (io), 84 PT11B (io), 85 PT11A (io), 86 PT10B/PCLK1_1 (io), 87 PT9B/PCLK1_0 (io)
part C pins: 64 PR10B (io), 65 PR10A (io), 67 PR8C (io), 68 PR8B (io), 69 PR8A (io), 71 PR5D (io), 72 PR5B (io), 73 PR5A (io), 74 PR3B (io), 75 PR3A (io)
part D pins: 51 PR19B (io), 52 PR18B (io), 53 PR18A (io), 54 PR17B (io), 55 PR17A (io), 57 PR15B (io), 58 PR15A (io), 60 PR13B (io), 61 PR13A (io), 62 PR11B (io), 63 PR11A (io)
part E pins: 39 PB10F/PCLK4_1 (io), 40 PB10B/PCLK4_0 (io), 42 PB12A (io), 43 PB12B (io), 45 PB13A (io), 46 PB13B (io), 48 PB16A (io), 49 PB16B (io)
part F pins: 30 PB3B (io), 31 PB4A (io), 32 PB4B (io), 37 PB8E (io), 38 PB8F (io)
part G pins: 14 PL11C (io), 15 PL13A (io), 16 PL13B (io), 18 PL14D (io), 19 PL14C/TSALL (io), 21 PL16C (io), 22 PL17A/LLM0_PLLT_FB_A (io), 23 PL17B/LLM0_PLLC_FB_A (io), 24 PL18A/LLM0_PLLT_IN_A (io), 25 PL18B/LLM0_PLLC_IN_A (io)
part H pins: 1 PL2A/LUM0_PLLT_FB_A (io), 2 PL2B/LUM0_PLLC_FB_A (io), 3 PL3C/LUM0_PLLT_IN_A (io), 4 PL3D/LUM0_PLLC_IN_A (io), 5 PL4B (io), 7 PL7A (io), 8 PL7B/GSRN (io), 10 PL9C (io), 11 PL9D (io), 12 PL10C (io), 13 PL10D (io)
part I pins: 28 TMS (in) "Powered by VCCIO5", 29 TCK (in) "Powered by VCCIO5", 33 TDO (out) "Powered by VCCIO5", 34 TDI (in) "Powered by VCCIO5", 47 SLEEPN (in) "Powered by VCCIO4"
part J pins: 6 VCCIO7 (power), 17 VCC (power), 20 VCCIO6 (power), 27 VCCIO5 (power), 35 VCC (power), 36 VCCAUX (power), 44 VCCIO4 (power), 56 VCCIO3 (power), 66 VCC (power), 70 VCCIO2 (power), 80 VCCIO1 (power), 90 VCCAUX (power), 91 VCC (power), 94 VCCIO0 (power)
part K pins: 9 GND (power), 26 GNDIO6/GNDIO5 (power) "Double Bonded pin", 41 GND (power), 50 GNDIO3/GNDIO4 (power) "Double Bonded pin", 59 GND (power), 76 GNDIO1/GNDIO2 (power) "Double Bonded pin", 83 GND (power), 100 GNDIO0/GNDIO7 (power) "Double Bonded pin"

## LCMXO2280C-3TN100CES
designator U?
MachXO 2280 Crossover PLD, 1.8V/2.5V/3.3V, 73 User I/Os, 100-Pins TQFP, Speed Grade-3, Commercial Grade, Pb-Free, Engineering Sample
footprint TQFP100_N (Thin QFP, 100-Leads, Body 14x14mm, Pitch 0.5mm, IPC Medium Density)
footprint TQFP100_L (Thin QFP, 100-Leads, Body 14x14mm, Pitch 0.5mm, IPC High Density)
footprint TQFP100_M (Thin QFP, 100-Leads, Body 14x14mm, Pitch 0.5mm, IPC Low Density)
3D model MachXO2280-TQFP100 (100-Pin Thin Quad Flat Pack (TQFP100))
signal-integrity model LCMXO2280C_T100 (MachXO)
part A pins: 88 PT8F (io), 89 PT8E (io), 92 PT6D (io), 93 PT6F (io), 95 PT4B (io), 96 PT4A (io), 97 PT3B (io), 98 PT2B (io), 99 PT2A (io)
part B pins: 77 PT15C (io), 78 PT14B (io), 79 PT14A (io), 81 PT12D (io), 82 PT12C (io), 84 PT11B (io), 85 PT11A (io), 86 PT10B/PCLK1_1 (io), 87 PT9B/PCLK1_0 (io)
part C pins: 64 PR10B (io), 65 PR10A (io), 67 PR8C (io), 68 PR8B (io), 69 PR8A (io), 71 PR5D (io), 72 PR5B (io), 73 PR5A (io), 74 PR3B (io), 75 PR3A (io)
part D pins: 51 PR19B (io), 52 PR18B (io), 53 PR18A (io), 54 PR17B (io), 55 PR17A (io), 57 PR15B (io), 58 PR15A (io), 60 PR13B (io), 61 PR13A (io), 62 PR11B (io), 63 PR11A (io)
part E pins: 39 PB10F/PCLK4_1 (io), 40 PB10B/PCLK4_0 (io), 42 PB12A (io), 43 PB12B (io), 45 PB13A (io), 46 PB13B (io), 48 PB16A (io), 49 PB16B (io)
part F pins: 30 PB3B (io), 31 PB4A (io), 32 PB4B (io), 37 PB8E (io), 38 PB8F (io)
part G pins: 14 PL11C (io), 15 PL13A (io), 16 PL13B (io), 18 PL14D (io), 19 PL14C/TSALL (io), 21 PL16C (io), 22 PL17A/LLM0_PLLT_FB_A (io), 23 PL17B/LLM0_PLLC_FB_A (io), 24 PL18A/LLM0_PLLT_IN_A (io), 25 PL18B/LLM0_PLLC_IN_A (io)
part H pins: 1 PL2A/LUM0_PLLT_FB_A (io), 2 PL2B/LUM0_PLLC_FB_A (io), 3 PL3C/LUM0_PLLT_IN_A (io), 4 PL3D/LUM0_PLLC_IN_A (io), 5 PL4B (io), 7 PL7A (io), 8 PL7B/GSRN (io), 10 PL9C (io), 11 PL9D (io), 12 PL10C (io), 13 PL10D (io)
part I pins: 28 TMS (in) "Powered by VCCIO5", 29 TCK (in) "Powered by VCCIO5", 33 TDO (out) "Powered by VCCIO5", 34 TDI (in) "Powered by VCCIO5", 47 SLEEPN (in) "Powered by VCCIO4"
part J pins: 6 VCCIO7 (power), 17 VCC (power), 20 VCCIO6 (power), 27 VCCIO5 (power), 35 VCC (power), 36 VCCAUX (power), 44 VCCIO4 (power), 56 VCCIO3 (power), 66 VCC (power), 70 VCCIO2 (power), 80 VCCIO1 (power), 90 VCCAUX (power), 91 VCC (power), 94 VCCIO0 (power)
part K pins: 9 GND (power), 26 GNDIO6/GNDIO5 (power) "Double Bonded pin", 41 GND (power), 50 GNDIO3/GNDIO4 (power) "Double Bonded pin", 59 GND (power), 76 GNDIO1/GNDIO2 (power) "Double Bonded pin", 83 GND (power), 100 GNDIO0/GNDIO7 (power) "Double Bonded pin"

## LCMXO2280C-3TN100I
designator U?
MachXO 2280 Crossover PLD, 1.8V/2.5V/3.3V, 73 User I/Os, 100-Pins TQFP, Speed Grade-3, Industrial Grade, Pb-Free
footprint TQFP100_N (Thin QFP, 100-Leads, Body 14x14mm, Pitch 0.5mm, IPC Medium Density)
footprint TQFP100_L (Thin QFP, 100-Leads, Body 14x14mm, Pitch 0.5mm, IPC High Density)
footprint TQFP100_M (Thin QFP, 100-Leads, Body 14x14mm, Pitch 0.5mm, IPC Low Density)
3D model MachXO2280-TQFP100 (100-Pin Thin Quad Flat Pack (TQFP100))
signal-integrity model LCMXO2280C_T100 (MachXO)
part A pins: 88 PT8F (io), 89 PT8E (io), 92 PT6D (io), 93 PT6F (io), 95 PT4B (io), 96 PT4A (io), 97 PT3B (io), 98 PT2B (io), 99 PT2A (io)
part B pins: 77 PT15C (io), 78 PT14B (io), 79 PT14A (io), 81 PT12D (io), 82 PT12C (io), 84 PT11B (io), 85 PT11A (io), 86 PT10B/PCLK1_1 (io), 87 PT9B/PCLK1_0 (io)
part C pins: 64 PR10B (io), 65 PR10A (io), 67 PR8C (io), 68 PR8B (io), 69 PR8A (io), 71 PR5D (io), 72 PR5B (io), 73 PR5A (io), 74 PR3B (io), 75 PR3A (io)
part D pins: 51 PR19B (io), 52 PR18B (io), 53 PR18A (io), 54 PR17B (io), 55 PR17A (io), 57 PR15B (io), 58 PR15A (io), 60 PR13B (io), 61 PR13A (io), 62 PR11B (io), 63 PR11A (io)
part E pins: 39 PB10F/PCLK4_1 (io), 40 PB10B/PCLK4_0 (io), 42 PB12A (io), 43 PB12B (io), 45 PB13A (io), 46 PB13B (io), 48 PB16A (io), 49 PB16B (io)
part F pins: 30 PB3B (io), 31 PB4A (io), 32 PB4B (io), 37 PB8E (io), 38 PB8F (io)
part G pins: 14 PL11C (io), 15 PL13A (io), 16 PL13B (io), 18 PL14D (io), 19 PL14C/TSALL (io), 21 PL16C (io), 22 PL17A/LLM0_PLLT_FB_A (io), 23 PL17B/LLM0_PLLC_FB_A (io), 24 PL18A/LLM0_PLLT_IN_A (io), 25 PL18B/LLM0_PLLC_IN_A (io)
part H pins: 1 PL2A/LUM0_PLLT_FB_A (io), 2 PL2B/LUM0_PLLC_FB_A (io), 3 PL3C/LUM0_PLLT_IN_A (io), 4 PL3D/LUM0_PLLC_IN_A (io), 5 PL4B (io), 7 PL7A (io), 8 PL7B/GSRN (io), 10 PL9C (io), 11 PL9D (io), 12 PL10C (io), 13 PL10D (io)
part I pins: 28 TMS (in) "Powered by VCCIO5", 29 TCK (in) "Powered by VCCIO5", 33 TDO (out) "Powered by VCCIO5", 34 TDI (in) "Powered by VCCIO5", 47 SLEEPN (in) "Powered by VCCIO4"
part J pins: 6 VCCIO7 (power), 17 VCC (power), 20 VCCIO6 (power), 27 VCCIO5 (power), 35 VCC (power), 36 VCCAUX (power), 44 VCCIO4 (power), 56 VCCIO3 (power), 66 VCC (power), 70 VCCIO2 (power), 80 VCCIO1 (power), 90 VCCAUX (power), 91 VCC (power), 94 VCCIO0 (power)
part K pins: 9 GND (power), 26 GNDIO6/GNDIO5 (power) "Double Bonded pin", 41 GND (power), 50 GNDIO3/GNDIO4 (power) "Double Bonded pin", 59 GND (power), 76 GNDIO1/GNDIO2 (power) "Double Bonded pin", 83 GND (power), 100 GNDIO0/GNDIO7 (power) "Double Bonded pin"


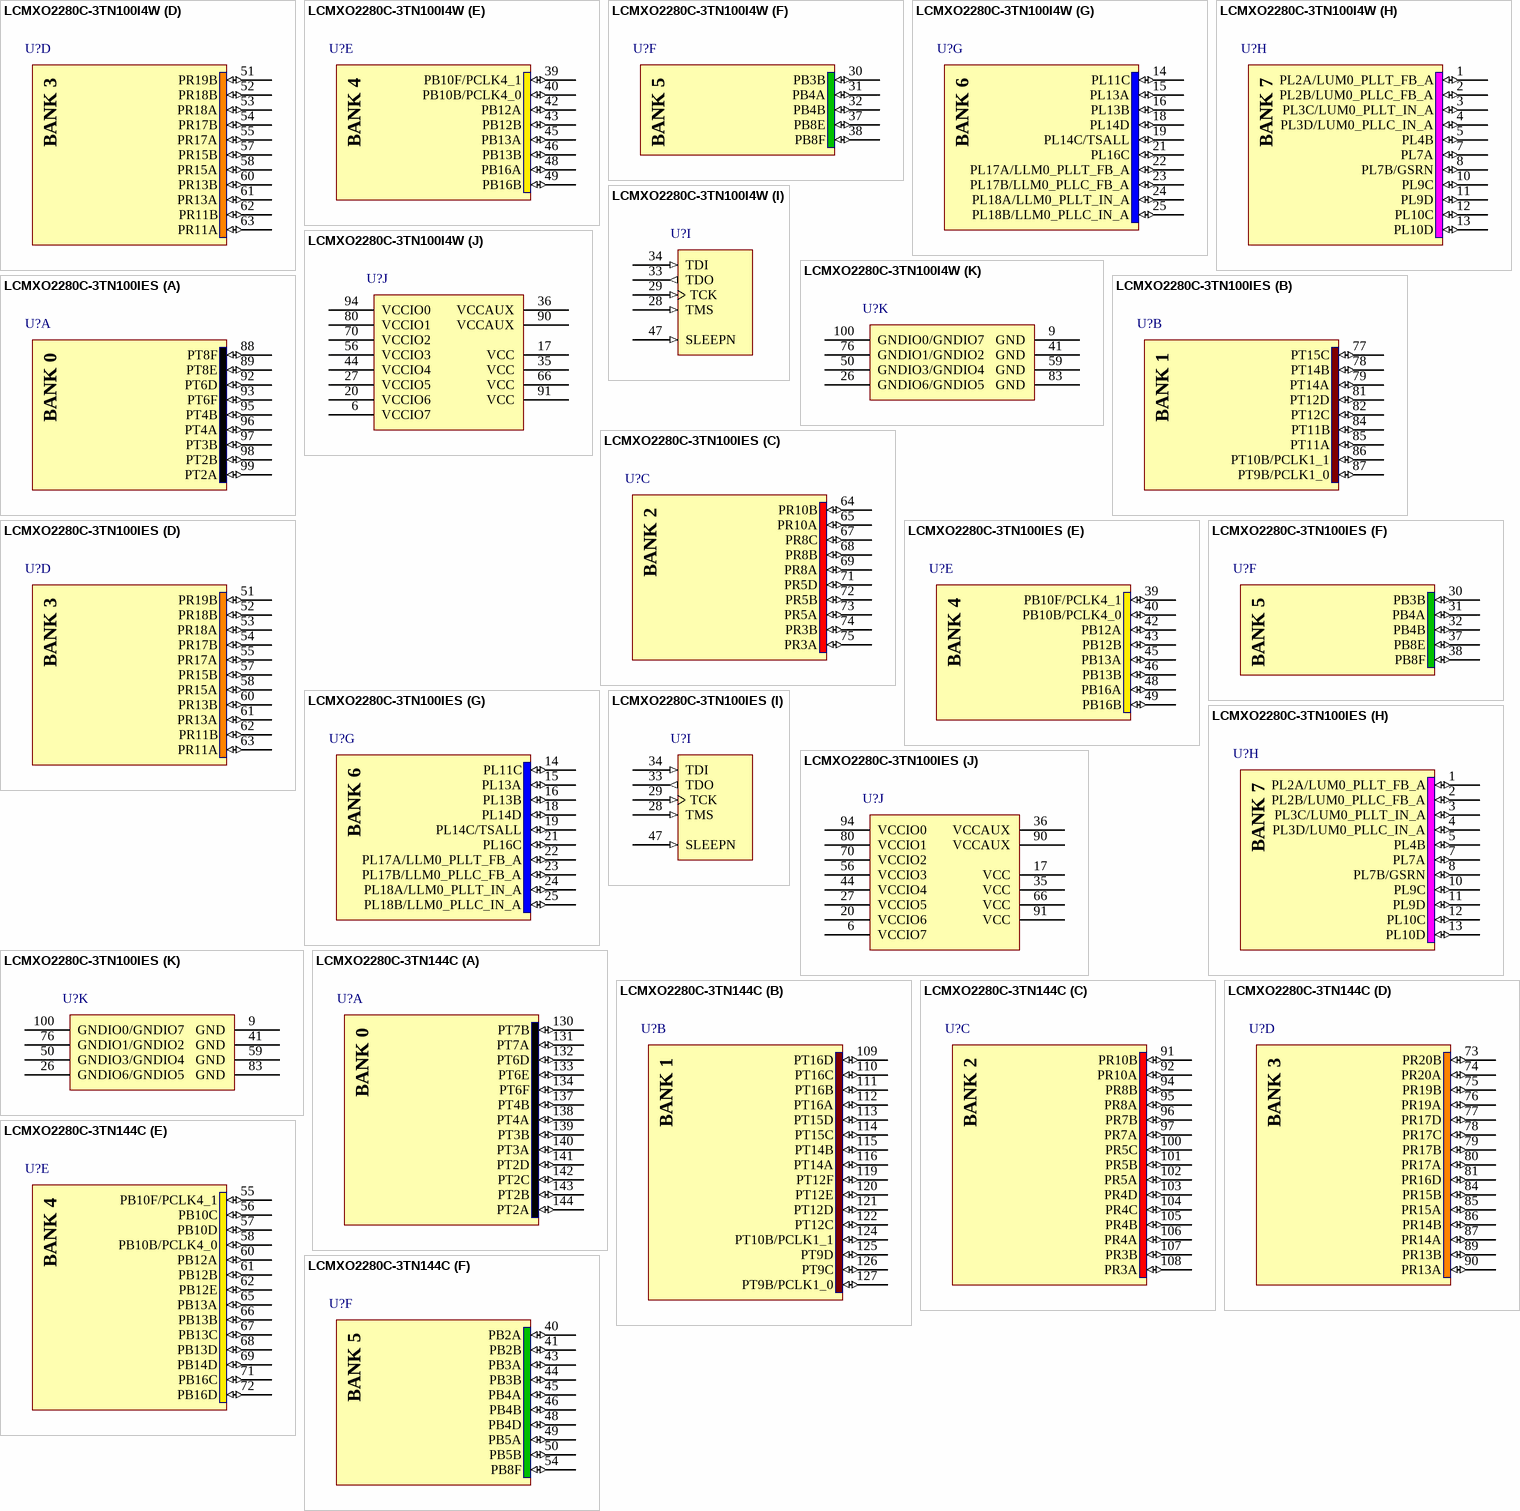
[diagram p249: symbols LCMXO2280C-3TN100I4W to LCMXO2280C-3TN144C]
## LCMXO2280C-3TN100I4W
designator U?
MachXO 2280 Crossover PLD, 1.8V/2.5V/3.3V, 73 User I/Os, 100-Pins TQFP, Speed Grade-3, Industrial Grade, Pb-Free
footprint TQFP100_N (Thin QFP, 100-Leads, Body 14x14mm, Pitch 0.5mm, IPC Medium Density)
footprint TQFP100_L (Thin QFP, 100-Leads, Body 14x14mm, Pitch 0.5mm, IPC High Density)
footprint TQFP100_M (Thin QFP, 100-Leads, Body 14x14mm, Pitch 0.5mm, IPC Low Density)
3D model MachXO2280-TQFP100 (100-Pin Thin Quad Flat Pack (TQFP100))
signal-integrity model LCMXO2280C_T100 (MachXO)
part A pins: 88 PT8F (io), 89 PT8E (io), 92 PT6D (io), 93 PT6F (io), 95 PT4B (io), 96 PT4A (io), 97 PT3B (io), 98 PT2B (io), 99 PT2A (io)
part B pins: 77 PT15C (io), 78 PT14B (io), 79 PT14A (io), 81 PT12D (io), 82 PT12C (io), 84 PT11B (io), 85 PT11A (io), 86 PT10B/PCLK1_1 (io), 87 PT9B/PCLK1_0 (io)
part C pins: 64 PR10B (io), 65 PR10A (io), 67 PR8C (io), 68 PR8B (io), 69 PR8A (io), 71 PR5D (io), 72 PR5B (io), 73 PR5A (io), 74 PR3B (io), 75 PR3A (io)
part D pins: 51 PR19B (io), 52 PR18B (io), 53 PR18A (io), 54 PR17B (io), 55 PR17A (io), 57 PR15B (io), 58 PR15A (io), 60 PR13B (io), 61 PR13A (io), 62 PR11B (io), 63 PR11A (io)
part E pins: 39 PB10F/PCLK4_1 (io), 40 PB10B/PCLK4_0 (io), 42 PB12A (io), 43 PB12B (io), 45 PB13A (io), 46 PB13B (io), 48 PB16A (io), 49 PB16B (io)
part F pins: 30 PB3B (io), 31 PB4A (io), 32 PB4B (io), 37 PB8E (io), 38 PB8F (io)
part G pins: 14 PL11C (io), 15 PL13A (io), 16 PL13B (io), 18 PL14D (io), 19 PL14C/TSALL (io), 21 PL16C (io), 22 PL17A/LLM0_PLLT_FB_A (io), 23 PL17B/LLM0_PLLC_FB_A (io), 24 PL18A/LLM0_PLLT_IN_A (io), 25 PL18B/LLM0_PLLC_IN_A (io)
part H pins: 1 PL2A/LUM0_PLLT_FB_A (io), 2 PL2B/LUM0_PLLC_FB_A (io), 3 PL3C/LUM0_PLLT_IN_A (io), 4 PL3D/LUM0_PLLC_IN_A (io), 5 PL4B (io), 7 PL7A (io), 8 PL7B/GSRN (io), 10 PL9C (io), 11 PL9D (io), 12 PL10C (io), 13 PL10D (io)
part I pins: 28 TMS (in) "Powered by VCCIO5", 29 TCK (in) "Powered by VCCIO5", 33 TDO (out) "Powered by VCCIO5", 34 TDI (in) "Powered by VCCIO5", 47 SLEEPN (in) "Powered by VCCIO4"
part J pins: 6 VCCIO7 (power), 17 VCC (power), 20 VCCIO6 (power), 27 VCCIO5 (power), 35 VCC (power), 36 VCCAUX (power), 44 VCCIO4 (power), 56 VCCIO3 (power), 66 VCC (power), 70 VCCIO2 (power), 80 VCCIO1 (power), 90 VCCAUX (power), 91 VCC (power), 94 VCCIO0 (power)
part K pins: 9 GND (power), 26 GNDIO6/GNDIO5 (power) "Double Bonded pin", 41 GND (power), 50 GNDIO3/GNDIO4 (power) "Double Bonded pin", 59 GND (power), 76 GNDIO1/GNDIO2 (power) "Double Bonded pin", 83 GND (power), 100 GNDIO0/GNDIO7 (power) "Double Bonded pin"

## LCMXO2280C-3TN100IES
designator U?
MachXO 2280 Crossover PLD, 1.8V/2.5V/3.3V, 73 User I/Os, 100-Pins TQFP, Speed Grade-3, Industrial Grade, Pb-Free, Engineering Sample
footprint TQFP100_N (Thin QFP, 100-Leads, Body 14x14mm, Pitch 0.5mm, IPC Medium Density)
footprint TQFP100_L (Thin QFP, 100-Leads, Body 14x14mm, Pitch 0.5mm, IPC High Density)
footprint TQFP100_M (Thin QFP, 100-Leads, Body 14x14mm, Pitch 0.5mm, IPC Low Density)
3D model MachXO2280-TQFP100 (100-Pin Thin Quad Flat Pack (TQFP100))
signal-integrity model LCMXO2280C_T100 (MachXO)
part A pins: 88 PT8F (io), 89 PT8E (io), 92 PT6D (io), 93 PT6F (io), 95 PT4B (io), 96 PT4A (io), 97 PT3B (io), 98 PT2B (io), 99 PT2A (io)
part B pins: 77 PT15C (io), 78 PT14B (io), 79 PT14A (io), 81 PT12D (io), 82 PT12C (io), 84 PT11B (io), 85 PT11A (io), 86 PT10B/PCLK1_1 (io), 87 PT9B/PCLK1_0 (io)
part C pins: 64 PR10B (io), 65 PR10A (io), 67 PR8C (io), 68 PR8B (io), 69 PR8A (io), 71 PR5D (io), 72 PR5B (io), 73 PR5A (io), 74 PR3B (io), 75 PR3A (io)
part D pins: 51 PR19B (io), 52 PR18B (io), 53 PR18A (io), 54 PR17B (io), 55 PR17A (io), 57 PR15B (io), 58 PR15A (io), 60 PR13B (io), 61 PR13A (io), 62 PR11B (io), 63 PR11A (io)
part E pins: 39 PB10F/PCLK4_1 (io), 40 PB10B/PCLK4_0 (io), 42 PB12A (io), 43 PB12B (io), 45 PB13A (io), 46 PB13B (io), 48 PB16A (io), 49 PB16B (io)
part F pins: 30 PB3B (io), 31 PB4A (io), 32 PB4B (io), 37 PB8E (io), 38 PB8F (io)
part G pins: 14 PL11C (io), 15 PL13A (io), 16 PL13B (io), 18 PL14D (io), 19 PL14C/TSALL (io), 21 PL16C (io), 22 PL17A/LLM0_PLLT_FB_A (io), 23 PL17B/LLM0_PLLC_FB_A (io), 24 PL18A/LLM0_PLLT_IN_A (io), 25 PL18B/LLM0_PLLC_IN_A (io)
part H pins: 1 PL2A/LUM0_PLLT_FB_A (io), 2 PL2B/LUM0_PLLC_FB_A (io), 3 PL3C/LUM0_PLLT_IN_A (io), 4 PL3D/LUM0_PLLC_IN_A (io), 5 PL4B (io), 7 PL7A (io), 8 PL7B/GSRN (io), 10 PL9C (io), 11 PL9D (io), 12 PL10C (io), 13 PL10D (io)
part I pins: 28 TMS (in) "Powered by VCCIO5", 29 TCK (in) "Powered by VCCIO5", 33 TDO (out) "Powered by VCCIO5", 34 TDI (in) "Powered by VCCIO5", 47 SLEEPN (in) "Powered by VCCIO4"
part J pins: 6 VCCIO7 (power), 17 VCC (power), 20 VCCIO6 (power), 27 VCCIO5 (power), 35 VCC (power), 36 VCCAUX (power), 44 VCCIO4 (power), 56 VCCIO3 (power), 66 VCC (power), 70 VCCIO2 (power), 80 VCCIO1 (power), 90 VCCAUX (power), 91 VCC (power), 94 VCCIO0 (power)
part K pins: 9 GND (power), 26 GNDIO6/GNDIO5 (power) "Double Bonded pin", 41 GND (power), 50 GNDIO3/GNDIO4 (power) "Double Bonded pin", 59 GND (power), 76 GNDIO1/GNDIO2 (power) "Double Bonded pin", 83 GND (power), 100 GNDIO0/GNDIO7 (power) "Double Bonded pin"


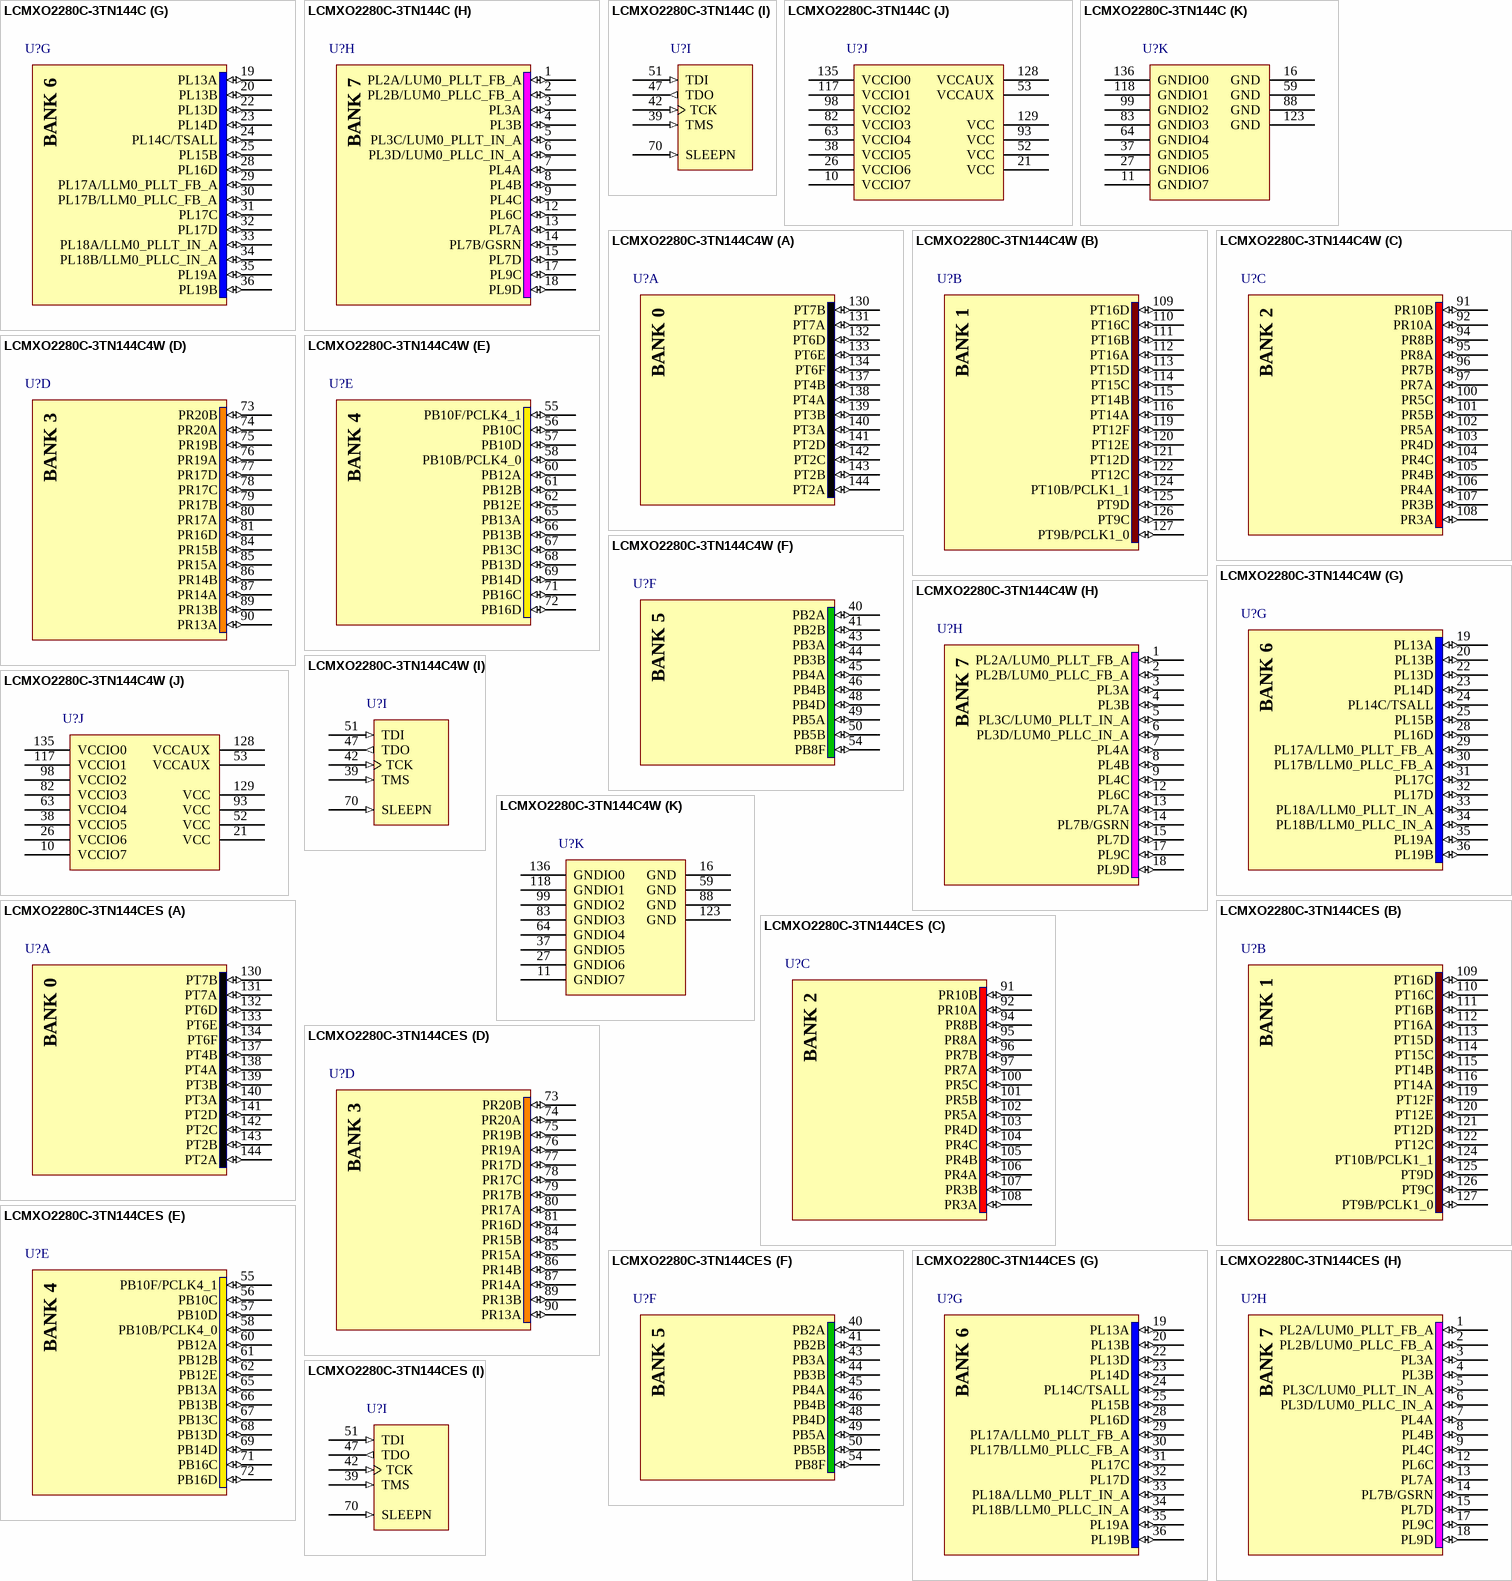
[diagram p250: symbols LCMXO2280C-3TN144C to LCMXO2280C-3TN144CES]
## LCMXO2280C-3TN144C
designator U?
MachXO 2280 Crossover PLD, 1.8V/2.5V/3.3V, 113 User I/Os, 144-Pins TQFP, Speed Grade-3, Commercial Grade, Pb-Free
footprint TQFP144_N (Thin QFP, 144-Leads, Body 20x20mm, Pitch 0.5mm, IPC Medium Density)
footprint TQFP144_L (Thin QFP, 144-Leads, Body 20x20mm, Pitch 0.5mm, IPC High Density)
footprint TQFP144_M (Thin QFP, 144-Leads, Body 20x20mm, Pitch 0.5mm, IPC Low Density)
3D model MachXO2280-TQFP144 (144-Pin Thin Quad Flat Pack (TQFP144))
signal-integrity model LCMXO2280C_T144 (MachXO)
part A pins: 130 PT7B (io), 131 PT7A (io), 132 PT6D (io), 133 PT6E (io), 134 PT6F (io), 137 PT4B (io), 138 PT4A (io), 139 PT3B (io), 140 PT3A (io), 141 PT2D (io), 142 PT2C (io), 143 PT2B (io), 144 PT2A (io)
part B pins: 109 PT16D (io), 110 PT16C (io), 111 PT16B (io), 112 PT16A (io), 113 PT15D (io), 114 PT15C (io), 115 PT14B (io), 116 PT14A (io), 119 PT12F (io), 120 PT12E (io), 121 PT12D (io), 122 PT12C (io), 124 PT10B/PCLK1_1 (io), 125 PT9D (io), 126 PT9C (io), 127 PT9B/PCLK1_0 (io)
part C pins: 91 PR10B (io), 92 PR10A (io), 94 PR8B (io), 95 PR8A (io), 96 PR7B (io), 97 PR7A (io), 100 PR5C (io), 101 PR5B (io), 102 PR5A (io), 103 PR4D (io), 104 PR4C (io), 105 PR4B (io), 106 PR4A (io), 107 PR3B (io), 108 PR3A (io)
part D pins: 73 PR20B (io), 74 PR20A (io), 75 PR19B (io), 76 PR19A (io), 77 PR17D (io), 78 PR17C (io), 79 PR17B (io), 80 PR17A (io), 81 PR16D (io), 84 PR15B (io), 85 PR15A (io), 86 PR14B (io), 87 PR14A (io), 89 PR13B (io), 90 PR13A (io)
part E pins: 55 PB10F/PCLK4_1 (io), 56 PB10C (io), 57 PB10D (io), 58 PB10B/PCLK4_0 (io), 60 PB12A (io), 61 PB12B (io), 62 PB12E (io), 65 PB13A (io), 66 PB13B (io), 67 PB13C (io), 68 PB13D (io), 69 PB14D (io), 71 PB16C (io), 72 PB16D (io)
part F pins: 40 PB2A (io), 41 PB2B (io), 43 PB3A (io), 44 PB3B (io), 45 PB4A (io), 46 PB4B (io), 48 PB4D (io), 49 PB5A (io), 50 PB5B (io), 54 PB8F (io)
part G pins: 19 PL13A (io), 20 PL13B (io), 22 PL13D (io), 23 PL14D (io), 24 PL14C/TSALL (io), 25 PL15B (io), 28 PL16D (io), 29 PL17A/LLM0_PLLT_FB_A (io), 30 PL17B/LLM0_PLLC_FB_A (io), 31 PL17C (io), 32 PL17D (io), 33 PL18A/LLM0_PLLT_IN_A (io), 34 PL18B/LLM0_PLLC_IN_A (io), 35 PL19A (io), 36 PL19B (io)
part H pins: 1 PL2A/LUM0_PLLT_FB_A (io), 2 PL2B/LUM0_PLLC_FB_A (io), 3 PL3A (io), 4 PL3B (io), 5 PL3C/LUM0_PLLT_IN_A (io), 6 PL3D/LUM0_PLLC_IN_A (io), 7 PL4A (io), 8 PL4B (io), 9 PL4C (io), 12 PL6C (io), 13 PL7A (io), 14 PL7B/GSRN (io), 15 PL7D (io), 17 PL9C (io), 18 PL9D (io)
part I pins: 39 TMS (in) "Powered by VCCIO5", 42 TCK (in) "Powered by VCCIO5", 47 TDO (out) "Powered by VCCIO5", 51 TDI (in) "Powered by VCCIO5", 70 SLEEPN (in) "Powered by VCCIO4"
part J pins: 10 VCCIO7 (power), 21 VCC (power), 26 VCCIO6 (power), 38 VCCIO5 (power), 52 VCC (power), 53 VCCAUX (power), 63 VCCIO4 (power), 82 VCCIO3 (power), 93 VCC (power), 98 VCCIO2 (power), 117 VCCIO1 (power), 128 VCCAUX (power), 129 VCC (power), 135 VCCIO0 (power)
part K pins: 11 GNDIO7 (power), 16 GND (power), 27 GNDIO6 (power), 37 GNDIO5 (power), 59 GND (power), 64 GNDIO4 (power), 83 GNDIO3 (power), 88 GND (power), 99 GNDIO2 (power), 118 GNDIO1 (power), 123 GND (power), 136 GNDIO0 (power)

## LCMXO2280C-3TN144C4W
designator U?
MachXO 2280 Crossover PLD, 1.8V/2.5V/3.3V, 113 User I/Os, 144-Pins TQFP, Speed Grade-3, Commercial Grade, Pb-Free
footprint TQFP144_N (Thin QFP, 144-Leads, Body 20x20mm, Pitch 0.5mm, IPC Medium Density)
footprint TQFP144_L (Thin QFP, 144-Leads, Body 20x20mm, Pitch 0.5mm, IPC High Density)
footprint TQFP144_M (Thin QFP, 144-Leads, Body 20x20mm, Pitch 0.5mm, IPC Low Density)
3D model MachXO2280-TQFP144 (144-Pin Thin Quad Flat Pack (TQFP144))
signal-integrity model LCMXO2280C_T144 (MachXO)
part A pins: 130 PT7B (io), 131 PT7A (io), 132 PT6D (io), 133 PT6E (io), 134 PT6F (io), 137 PT4B (io), 138 PT4A (io), 139 PT3B (io), 140 PT3A (io), 141 PT2D (io), 142 PT2C (io), 143 PT2B (io), 144 PT2A (io)
part B pins: 109 PT16D (io), 110 PT16C (io), 111 PT16B (io), 112 PT16A (io), 113 PT15D (io), 114 PT15C (io), 115 PT14B (io), 116 PT14A (io), 119 PT12F (io), 120 PT12E (io), 121 PT12D (io), 122 PT12C (io), 124 PT10B/PCLK1_1 (io), 125 PT9D (io), 126 PT9C (io), 127 PT9B/PCLK1_0 (io)
part C pins: 91 PR10B (io), 92 PR10A (io), 94 PR8B (io), 95 PR8A (io), 96 PR7B (io), 97 PR7A (io), 100 PR5C (io), 101 PR5B (io), 102 PR5A (io), 103 PR4D (io), 104 PR4C (io), 105 PR4B (io), 106 PR4A (io), 107 PR3B (io), 108 PR3A (io)
part D pins: 73 PR20B (io), 74 PR20A (io), 75 PR19B (io), 76 PR19A (io), 77 PR17D (io), 78 PR17C (io), 79 PR17B (io), 80 PR17A (io), 81 PR16D (io), 84 PR15B (io), 85 PR15A (io), 86 PR14B (io), 87 PR14A (io), 89 PR13B (io), 90 PR13A (io)
part E pins: 55 PB10F/PCLK4_1 (io), 56 PB10C (io), 57 PB10D (io), 58 PB10B/PCLK4_0 (io), 60 PB12A (io), 61 PB12B (io), 62 PB12E (io), 65 PB13A (io), 66 PB13B (io), 67 PB13C (io), 68 PB13D (io), 69 PB14D (io), 71 PB16C (io), 72 PB16D (io)
part F pins: 40 PB2A (io), 41 PB2B (io), 43 PB3A (io), 44 PB3B (io), 45 PB4A (io), 46 PB4B (io), 48 PB4D (io), 49 PB5A (io), 50 PB5B (io), 54 PB8F (io)
part G pins: 19 PL13A (io), 20 PL13B (io), 22 PL13D (io), 23 PL14D (io), 24 PL14C/TSALL (io), 25 PL15B (io), 28 PL16D (io), 29 PL17A/LLM0_PLLT_FB_A (io), 30 PL17B/LLM0_PLLC_FB_A (io), 31 PL17C (io), 32 PL17D (io), 33 PL18A/LLM0_PLLT_IN_A (io), 34 PL18B/LLM0_PLLC_IN_A (io), 35 PL19A (io), 36 PL19B (io)
part H pins: 1 PL2A/LUM0_PLLT_FB_A (io), 2 PL2B/LUM0_PLLC_FB_A (io), 3 PL3A (io), 4 PL3B (io), 5 PL3C/LUM0_PLLT_IN_A (io), 6 PL3D/LUM0_PLLC_IN_A (io), 7 PL4A (io), 8 PL4B (io), 9 PL4C (io), 12 PL6C (io), 13 PL7A (io), 14 PL7B/GSRN (io), 15 PL7D (io), 17 PL9C (io), 18 PL9D (io)
part I pins: 39 TMS (in) "Powered by VCCIO5", 42 TCK (in) "Powered by VCCIO5", 47 TDO (out) "Powered by VCCIO5", 51 TDI (in) "Powered by VCCIO5", 70 SLEEPN (in) "Powered by VCCIO4"
part J pins: 10 VCCIO7 (power), 21 VCC (power), 26 VCCIO6 (power), 38 VCCIO5 (power), 52 VCC (power), 53 VCCAUX (power), 63 VCCIO4 (power), 82 VCCIO3 (power), 93 VCC (power), 98 VCCIO2 (power), 117 VCCIO1 (power), 128 VCCAUX (power), 129 VCC (power), 135 VCCIO0 (power)
part K pins: 11 GNDIO7 (power), 16 GND (power), 27 GNDIO6 (power), 37 GNDIO5 (power), 59 GND (power), 64 GNDIO4 (power), 83 GNDIO3 (power), 88 GND (power), 99 GNDIO2 (power), 118 GNDIO1 (power), 123 GND (power), 136 GNDIO0 (power)


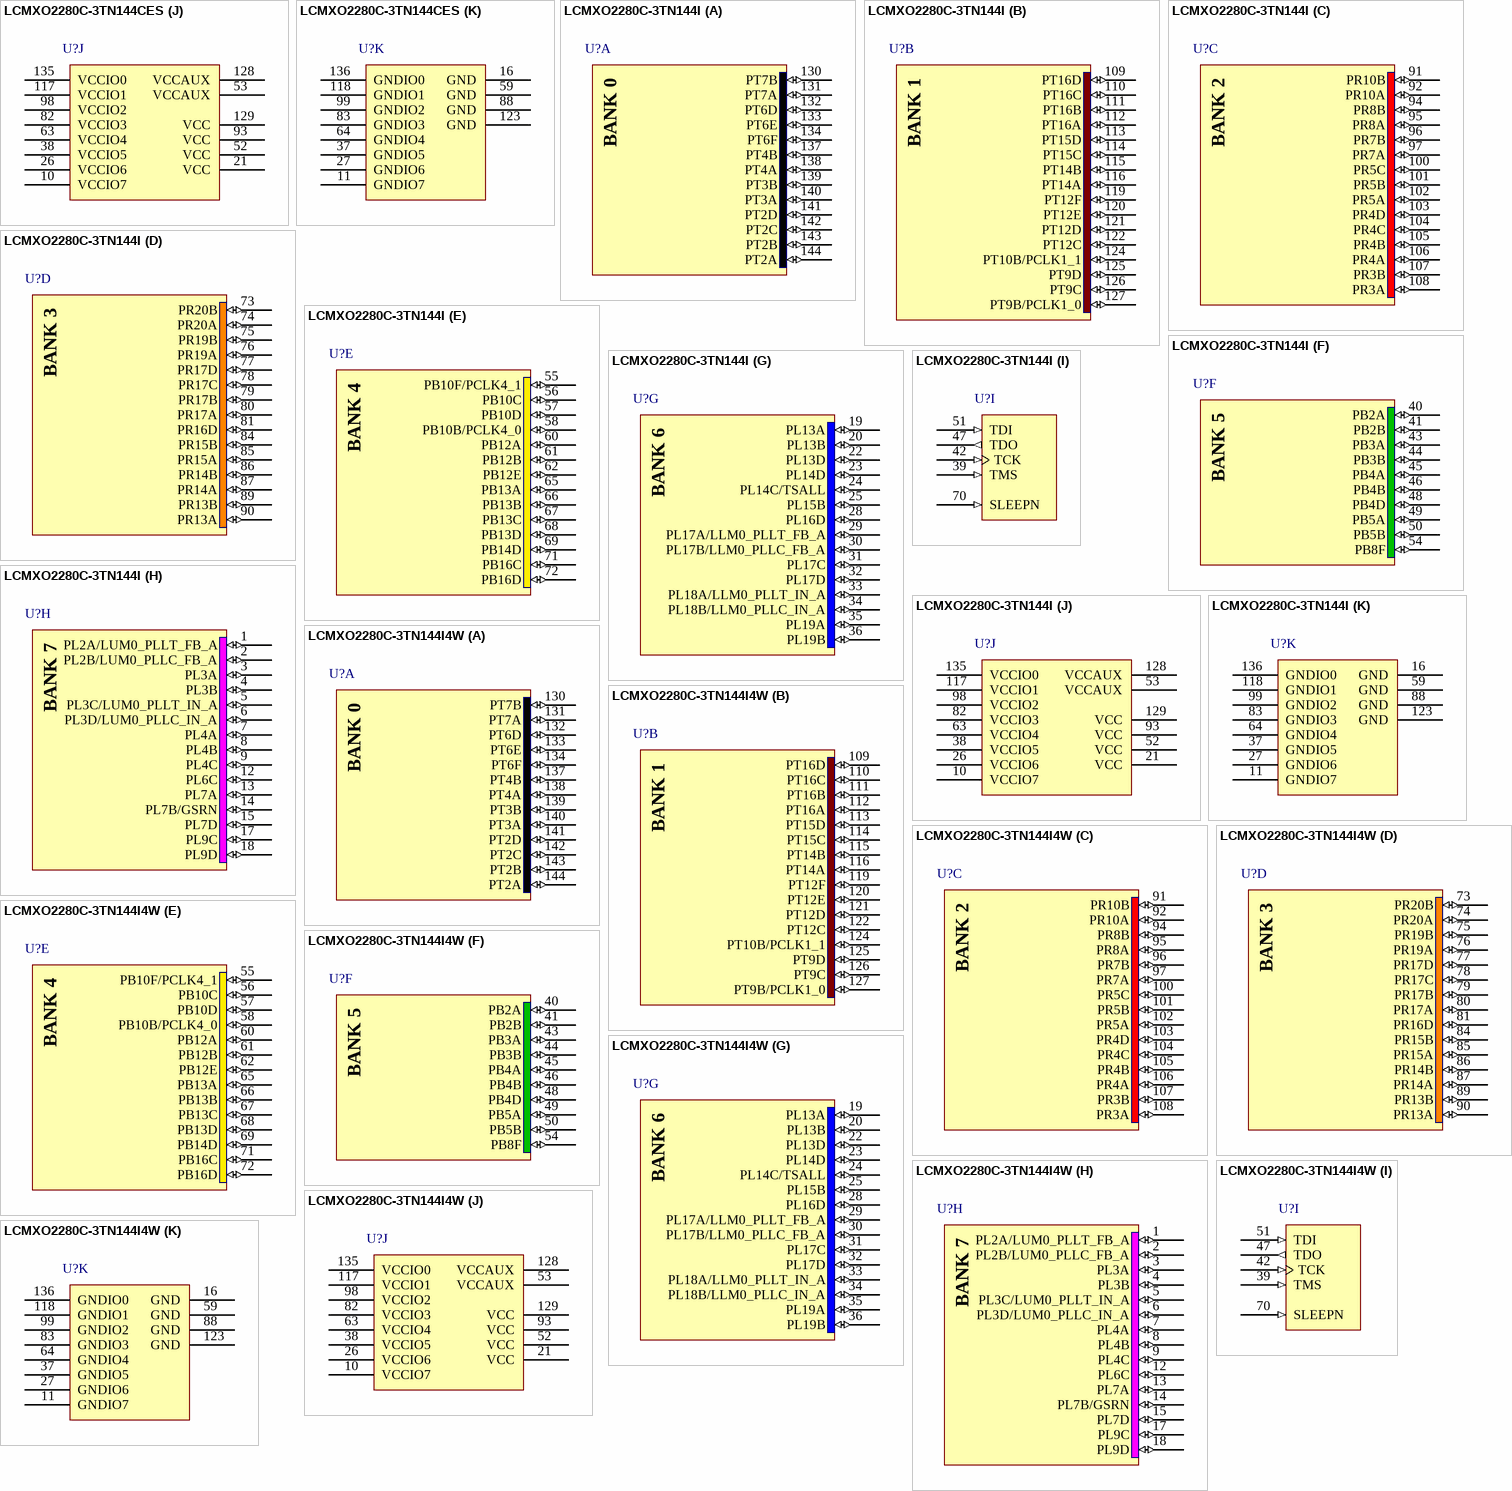
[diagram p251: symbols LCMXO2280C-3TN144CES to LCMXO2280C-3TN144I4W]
## LCMXO2280C-3TN144CES
designator U?
MachXO 2280 Crossover PLD, 1.8V/2.5V/3.3V, 113 User I/Os, 144-Pins TQFP, Speed Grade-3, Commercial Grade, Pb-Free, Engineering Sample
footprint TQFP144_N (Thin QFP, 144-Leads, Body 20x20mm, Pitch 0.5mm, IPC Medium Density)
footprint TQFP144_L (Thin QFP, 144-Leads, Body 20x20mm, Pitch 0.5mm, IPC High Density)
footprint TQFP144_M (Thin QFP, 144-Leads, Body 20x20mm, Pitch 0.5mm, IPC Low Density)
3D model MachXO2280-TQFP144 (144-Pin Thin Quad Flat Pack (TQFP144))
signal-integrity model LCMXO2280C_T144 (MachXO)
part A pins: 130 PT7B (io), 131 PT7A (io), 132 PT6D (io), 133 PT6E (io), 134 PT6F (io), 137 PT4B (io), 138 PT4A (io), 139 PT3B (io), 140 PT3A (io), 141 PT2D (io), 142 PT2C (io), 143 PT2B (io), 144 PT2A (io)
part B pins: 109 PT16D (io), 110 PT16C (io), 111 PT16B (io), 112 PT16A (io), 113 PT15D (io), 114 PT15C (io), 115 PT14B (io), 116 PT14A (io), 119 PT12F (io), 120 PT12E (io), 121 PT12D (io), 122 PT12C (io), 124 PT10B/PCLK1_1 (io), 125 PT9D (io), 126 PT9C (io), 127 PT9B/PCLK1_0 (io)
part C pins: 91 PR10B (io), 92 PR10A (io), 94 PR8B (io), 95 PR8A (io), 96 PR7B (io), 97 PR7A (io), 100 PR5C (io), 101 PR5B (io), 102 PR5A (io), 103 PR4D (io), 104 PR4C (io), 105 PR4B (io), 106 PR4A (io), 107 PR3B (io), 108 PR3A (io)
part D pins: 73 PR20B (io), 74 PR20A (io), 75 PR19B (io), 76 PR19A (io), 77 PR17D (io), 78 PR17C (io), 79 PR17B (io), 80 PR17A (io), 81 PR16D (io), 84 PR15B (io), 85 PR15A (io), 86 PR14B (io), 87 PR14A (io), 89 PR13B (io), 90 PR13A (io)
part E pins: 55 PB10F/PCLK4_1 (io), 56 PB10C (io), 57 PB10D (io), 58 PB10B/PCLK4_0 (io), 60 PB12A (io), 61 PB12B (io), 62 PB12E (io), 65 PB13A (io), 66 PB13B (io), 67 PB13C (io), 68 PB13D (io), 69 PB14D (io), 71 PB16C (io), 72 PB16D (io)
part F pins: 40 PB2A (io), 41 PB2B (io), 43 PB3A (io), 44 PB3B (io), 45 PB4A (io), 46 PB4B (io), 48 PB4D (io), 49 PB5A (io), 50 PB5B (io), 54 PB8F (io)
part G pins: 19 PL13A (io), 20 PL13B (io), 22 PL13D (io), 23 PL14D (io), 24 PL14C/TSALL (io), 25 PL15B (io), 28 PL16D (io), 29 PL17A/LLM0_PLLT_FB_A (io), 30 PL17B/LLM0_PLLC_FB_A (io), 31 PL17C (io), 32 PL17D (io), 33 PL18A/LLM0_PLLT_IN_A (io), 34 PL18B/LLM0_PLLC_IN_A (io), 35 PL19A (io), 36 PL19B (io)
part H pins: 1 PL2A/LUM0_PLLT_FB_A (io), 2 PL2B/LUM0_PLLC_FB_A (io), 3 PL3A (io), 4 PL3B (io), 5 PL3C/LUM0_PLLT_IN_A (io), 6 PL3D/LUM0_PLLC_IN_A (io), 7 PL4A (io), 8 PL4B (io), 9 PL4C (io), 12 PL6C (io), 13 PL7A (io), 14 PL7B/GSRN (io), 15 PL7D (io), 17 PL9C (io), 18 PL9D (io)
part I pins: 39 TMS (in) "Powered by VCCIO5", 42 TCK (in) "Powered by VCCIO5", 47 TDO (out) "Powered by VCCIO5", 51 TDI (in) "Powered by VCCIO5", 70 SLEEPN (in) "Powered by VCCIO4"
part J pins: 10 VCCIO7 (power), 21 VCC (power), 26 VCCIO6 (power), 38 VCCIO5 (power), 52 VCC (power), 53 VCCAUX (power), 63 VCCIO4 (power), 82 VCCIO3 (power), 93 VCC (power), 98 VCCIO2 (power), 117 VCCIO1 (power), 128 VCCAUX (power), 129 VCC (power), 135 VCCIO0 (power)
part K pins: 11 GNDIO7 (power), 16 GND (power), 27 GNDIO6 (power), 37 GNDIO5 (power), 59 GND (power), 64 GNDIO4 (power), 83 GNDIO3 (power), 88 GND (power), 99 GNDIO2 (power), 118 GNDIO1 (power), 123 GND (power), 136 GNDIO0 (power)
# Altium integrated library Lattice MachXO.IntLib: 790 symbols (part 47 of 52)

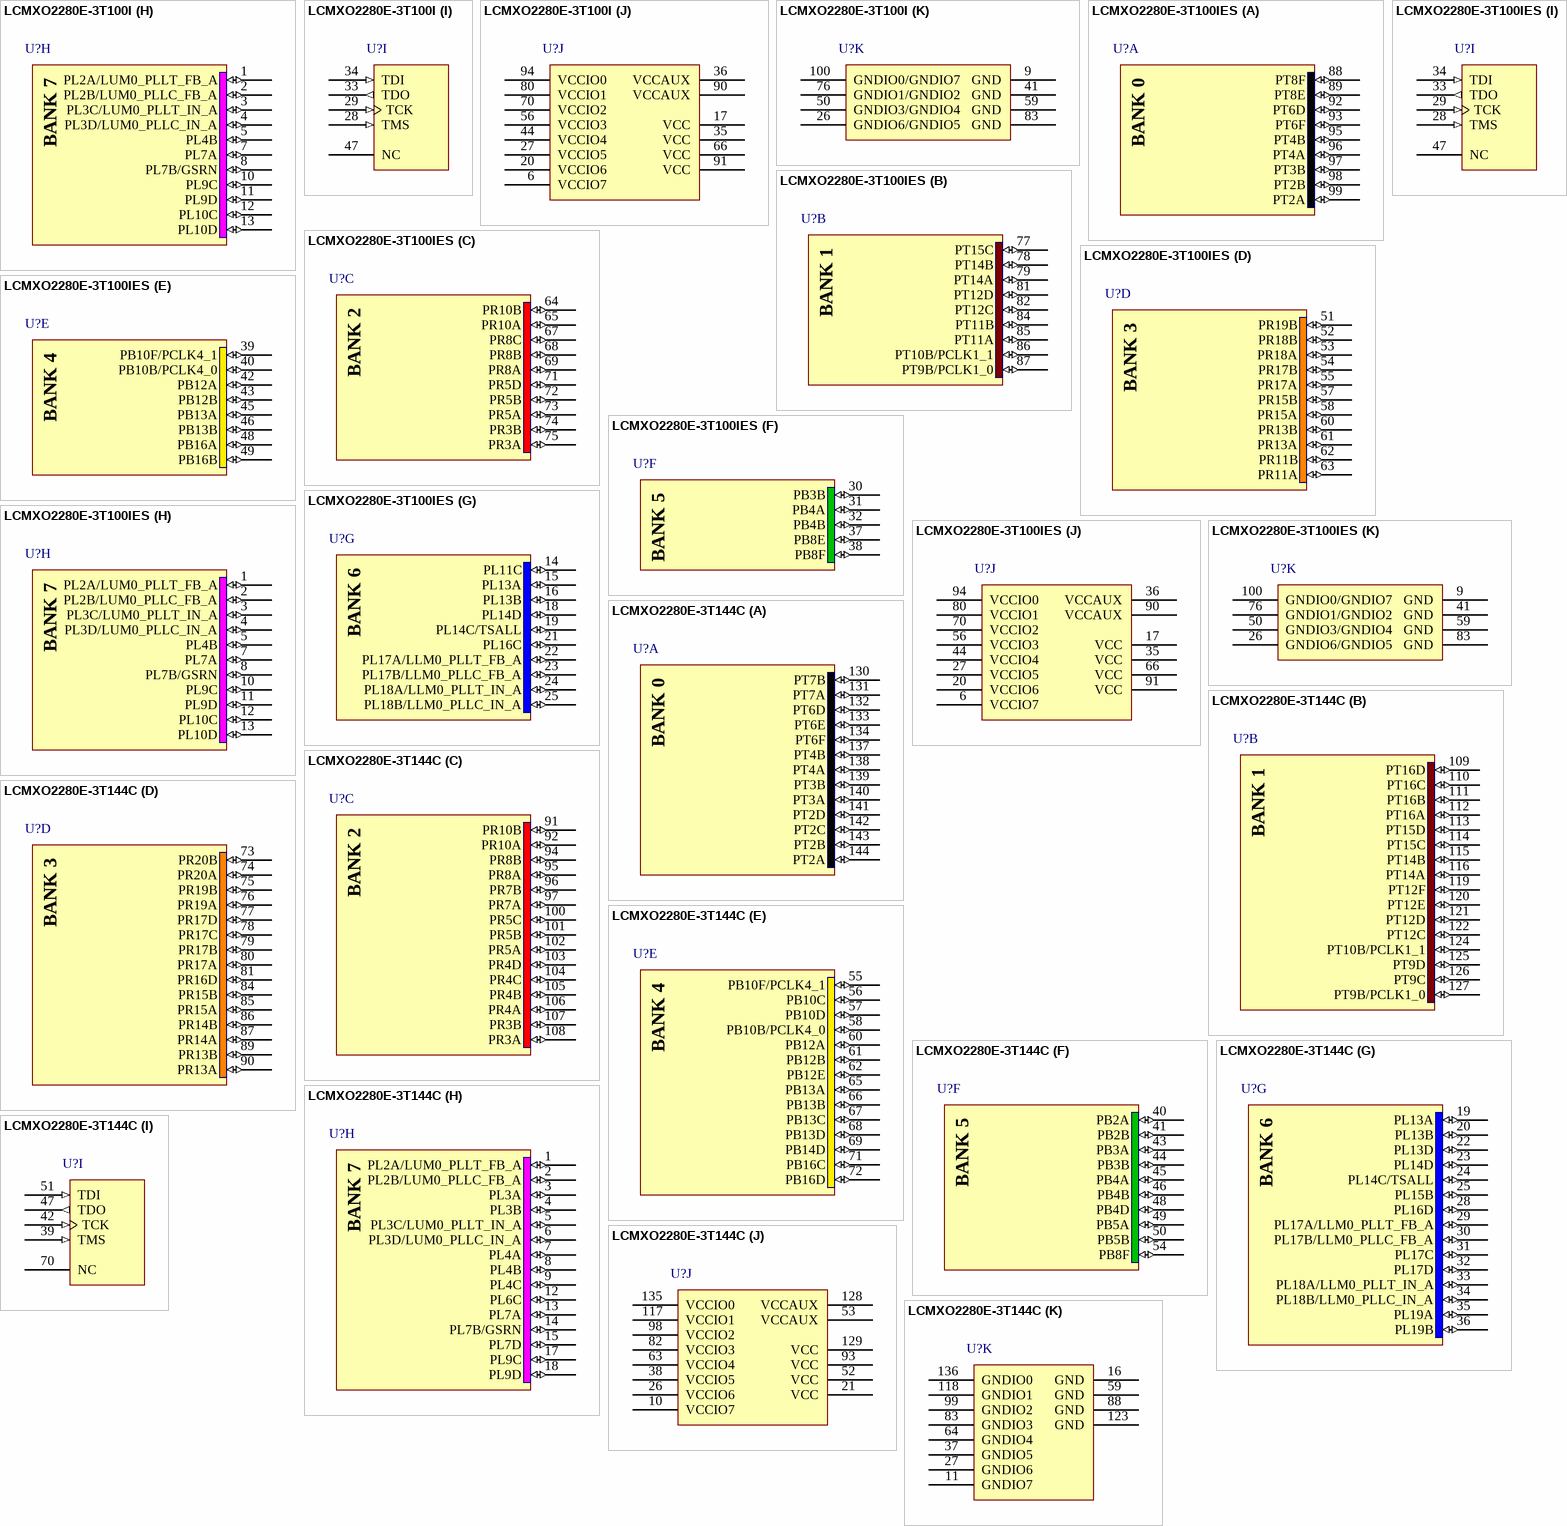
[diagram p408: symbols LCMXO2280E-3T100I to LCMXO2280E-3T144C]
## LCMXO2280E-3T144C
designator U?
MachXO 2280 Crossover PLD, 1.2V, 113 User I/Os, 144-Pins TQFP, Speed Grade-3, Commercial Grade
footprint TQFP144_N (Thin QFP, 144-Leads, Body 20x20mm, Pitch 0.5mm, IPC Medium Density)
footprint TQFP144_L (Thin QFP, 144-Leads, Body 20x20mm, Pitch 0.5mm, IPC High Density)
footprint TQFP144_M (Thin QFP, 144-Leads, Body 20x20mm, Pitch 0.5mm, IPC Low Density)
3D model MachXO2280-TQFP144 (144-Pin Thin Quad Flat Pack (TQFP144))
signal-integrity model LCMXO2280E_T144 (MachXO)
part A pins: 130 PT7B (io), 131 PT7A (io), 132 PT6D (io), 133 PT6E (io), 134 PT6F (io), 137 PT4B (io), 138 PT4A (io), 139 PT3B (io), 140 PT3A (io), 141 PT2D (io), 142 PT2C (io), 143 PT2B (io), 144 PT2A (io)
part B pins: 109 PT16D (io), 110 PT16C (io), 111 PT16B (io), 112 PT16A (io), 113 PT15D (io), 114 PT15C (io), 115 PT14B (io), 116 PT14A (io), 119 PT12F (io), 120 PT12E (io), 121 PT12D (io), 122 PT12C (io), 124 PT10B/PCLK1_1 (io), 125 PT9D (io), 126 PT9C (io), 127 PT9B/PCLK1_0 (io)
part C pins: 91 PR10B (io), 92 PR10A (io), 94 PR8B (io), 95 PR8A (io), 96 PR7B (io), 97 PR7A (io), 100 PR5C (io), 101 PR5B (io), 102 PR5A (io), 103 PR4D (io), 104 PR4C (io), 105 PR4B (io), 106 PR4A (io), 107 PR3B (io), 108 PR3A (io)
part D pins: 73 PR20B (io), 74 PR20A (io), 75 PR19B (io), 76 PR19A (io), 77 PR17D (io), 78 PR17C (io), 79 PR17B (io), 80 PR17A (io), 81 PR16D (io), 84 PR15B (io), 85 PR15A (io), 86 PR14B (io), 87 PR14A (io), 89 PR13B (io), 90 PR13A (io)
part E pins: 55 PB10F/PCLK4_1 (io), 56 PB10C (io), 57 PB10D (io), 58 PB10B/PCLK4_0 (io), 60 PB12A (io), 61 PB12B (io), 62 PB12E (io), 65 PB13A (io), 66 PB13B (io), 67 PB13C (io), 68 PB13D (io), 69 PB14D (io), 71 PB16C (io), 72 PB16D (io)
part F pins: 40 PB2A (io), 41 PB2B (io), 43 PB3A (io), 44 PB3B (io), 45 PB4A (io), 46 PB4B (io), 48 PB4D (io), 49 PB5A (io), 50 PB5B (io), 54 PB8F (io)
part G pins: 19 PL13A (io), 20 PL13B (io), 22 PL13D (io), 23 PL14D (io), 24 PL14C/TSALL (io), 25 PL15B (io), 28 PL16D (io), 29 PL17A/LLM0_PLLT_FB_A (io), 30 PL17B/LLM0_PLLC_FB_A (io), 31 PL17C (io), 32 PL17D (io), 33 PL18A/LLM0_PLLT_IN_A (io), 34 PL18B/LLM0_PLLC_IN_A (io), 35 PL19A (io), 36 PL19B (io)
part H pins: 1 PL2A/LUM0_PLLT_FB_A (io), 2 PL2B/LUM0_PLLC_FB_A (io), 3 PL3A (io), 4 PL3B (io), 5 PL3C/LUM0_PLLT_IN_A (io), 6 PL3D/LUM0_PLLC_IN_A (io), 7 PL4A (io), 8 PL4B (io), 9 PL4C (io), 12 PL6C (io), 13 PL7A (io), 14 PL7B/GSRN (io), 15 PL7D (io), 17 PL9C (io), 18 PL9D (io)
part I pins: 39 TMS (in) "Powered by VCCIO5", 42 TCK (in) "Powered by VCCIO5", 47 TDO (out) "Powered by VCCIO5", 51 TDI (in) "Powered by VCCIO5", 70 NC
part J pins: 10 VCCIO7 (power), 21 VCC (power), 26 VCCIO6 (power), 38 VCCIO5 (power), 52 VCC (power), 53 VCCAUX (power), 63 VCCIO4 (power), 82 VCCIO3 (power), 93 VCC (power), 98 VCCIO2 (power), 117 VCCIO1 (power), 128 VCCAUX (power), 129 VCC (power), 135 VCCIO0 (power)
part K pins: 11 GNDIO7 (power), 16 GND (power), 27 GNDIO6 (power), 37 GNDIO5 (power), 59 GND (power), 64 GNDIO4 (power), 83 GNDIO3 (power), 88 GND (power), 99 GNDIO2 (power), 118 GNDIO1 (power), 123 GND (power), 136 GNDIO0 (power)


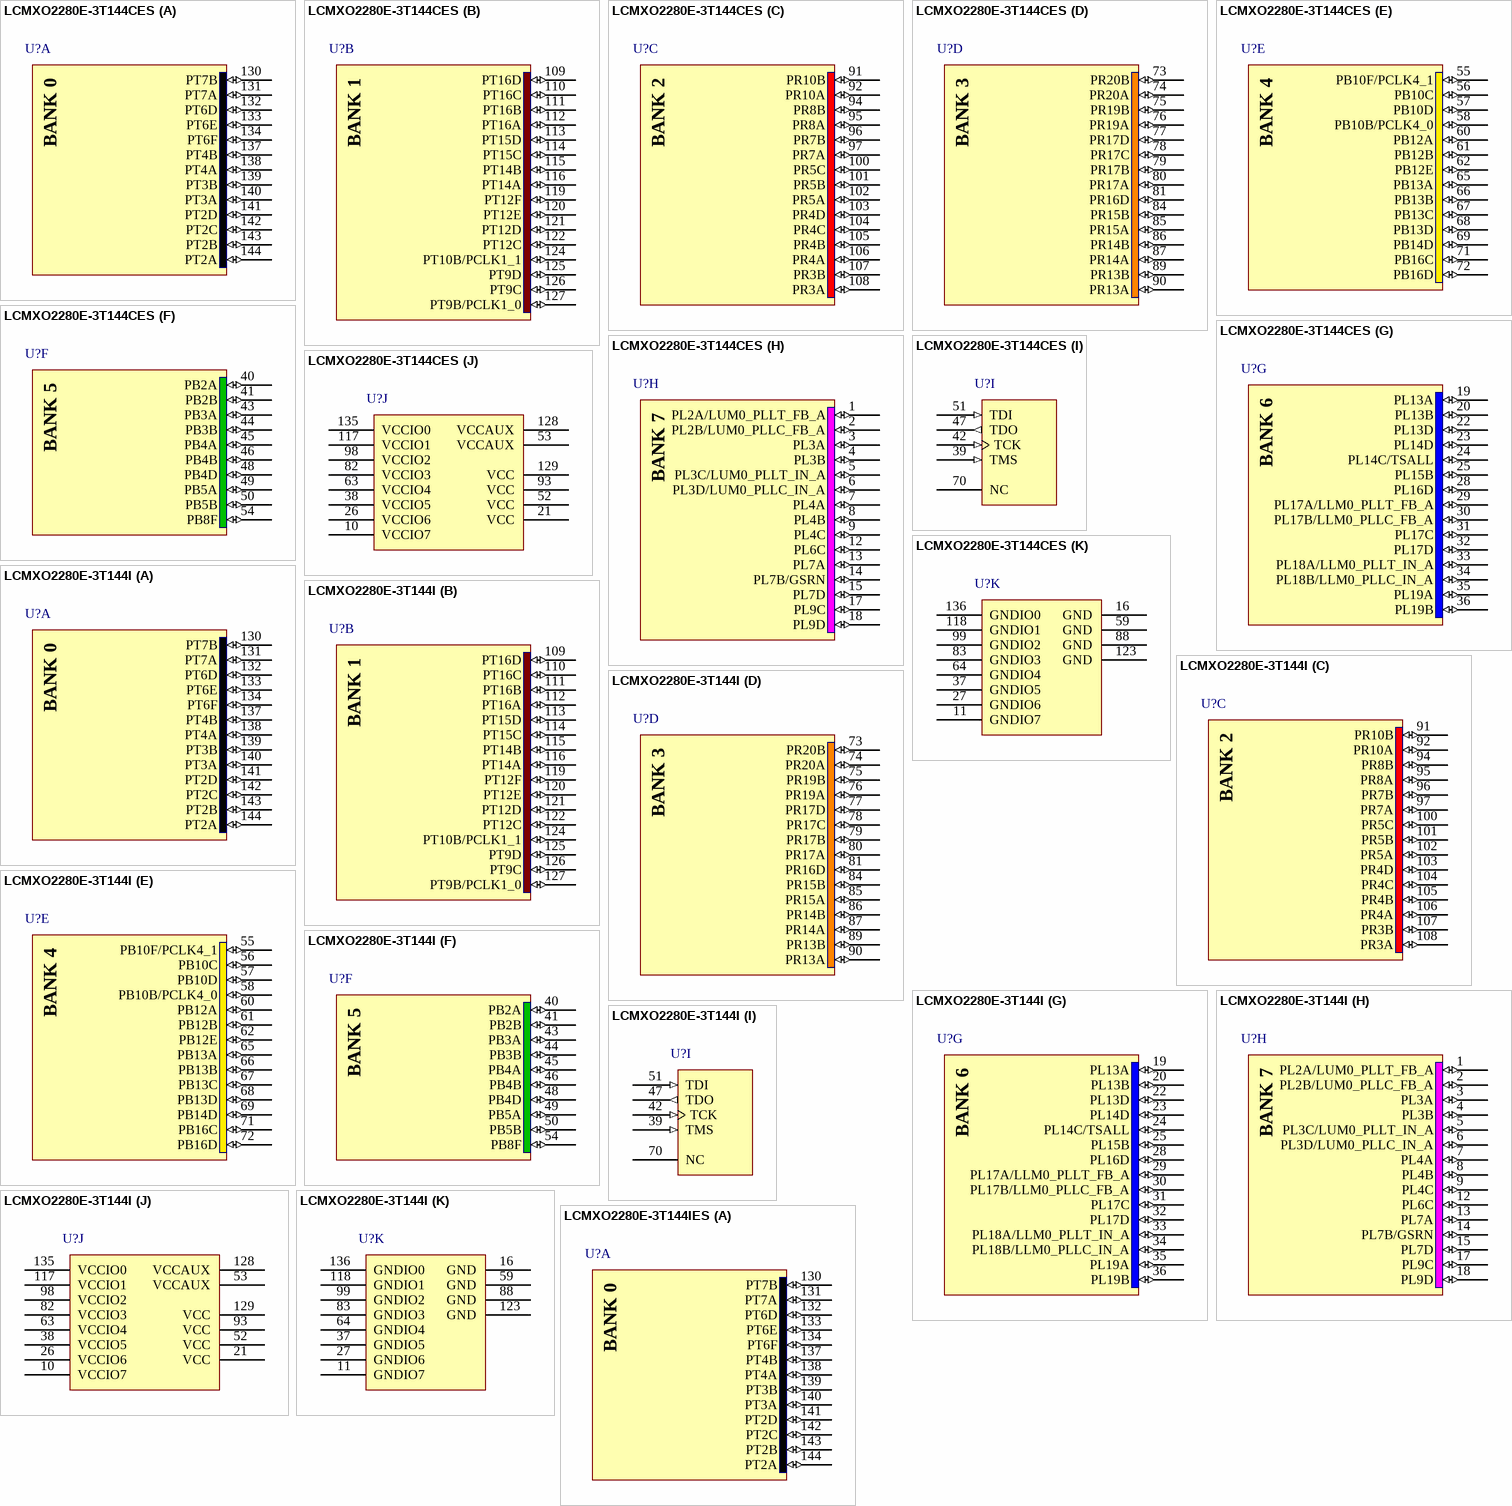
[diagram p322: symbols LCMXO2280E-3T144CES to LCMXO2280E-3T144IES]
## LCMXO2280E-3T144CES
designator U?
MachXO 2280 Crossover PLD, 1.2V, 113 User I/Os, 144-Pins TQFP, Speed Grade-3, Commercial Grade, Engineering Sample
footprint TQFP144_N (Thin QFP, 144-Leads, Body 20x20mm, Pitch 0.5mm, IPC Medium Density)
footprint TQFP144_L (Thin QFP, 144-Leads, Body 20x20mm, Pitch 0.5mm, IPC High Density)
footprint TQFP144_M (Thin QFP, 144-Leads, Body 20x20mm, Pitch 0.5mm, IPC Low Density)
3D model MachXO2280-TQFP144 (144-Pin Thin Quad Flat Pack (TQFP144))
signal-integrity model LCMXO2280E_T144 (MachXO)
part A pins: 130 PT7B (io), 131 PT7A (io), 132 PT6D (io), 133 PT6E (io), 134 PT6F (io), 137 PT4B (io), 138 PT4A (io), 139 PT3B (io), 140 PT3A (io), 141 PT2D (io), 142 PT2C (io), 143 PT2B (io), 144 PT2A (io)
part B pins: 109 PT16D (io), 110 PT16C (io), 111 PT16B (io), 112 PT16A (io), 113 PT15D (io), 114 PT15C (io), 115 PT14B (io), 116 PT14A (io), 119 PT12F (io), 120 PT12E (io), 121 PT12D (io), 122 PT12C (io), 124 PT10B/PCLK1_1 (io), 125 PT9D (io), 126 PT9C (io), 127 PT9B/PCLK1_0 (io)
part C pins: 91 PR10B (io), 92 PR10A (io), 94 PR8B (io), 95 PR8A (io), 96 PR7B (io), 97 PR7A (io), 100 PR5C (io), 101 PR5B (io), 102 PR5A (io), 103 PR4D (io), 104 PR4C (io), 105 PR4B (io), 106 PR4A (io), 107 PR3B (io), 108 PR3A (io)
part D pins: 73 PR20B (io), 74 PR20A (io), 75 PR19B (io), 76 PR19A (io), 77 PR17D (io), 78 PR17C (io), 79 PR17B (io), 80 PR17A (io), 81 PR16D (io), 84 PR15B (io), 85 PR15A (io), 86 PR14B (io), 87 PR14A (io), 89 PR13B (io), 90 PR13A (io)
part E pins: 55 PB10F/PCLK4_1 (io), 56 PB10C (io), 57 PB10D (io), 58 PB10B/PCLK4_0 (io), 60 PB12A (io), 61 PB12B (io), 62 PB12E (io), 65 PB13A (io), 66 PB13B (io), 67 PB13C (io), 68 PB13D (io), 69 PB14D (io), 71 PB16C (io), 72 PB16D (io)
part F pins: 40 PB2A (io), 41 PB2B (io), 43 PB3A (io), 44 PB3B (io), 45 PB4A (io), 46 PB4B (io), 48 PB4D (io), 49 PB5A (io), 50 PB5B (io), 54 PB8F (io)
part G pins: 19 PL13A (io), 20 PL13B (io), 22 PL13D (io), 23 PL14D (io), 24 PL14C/TSALL (io), 25 PL15B (io), 28 PL16D (io), 29 PL17A/LLM0_PLLT_FB_A (io), 30 PL17B/LLM0_PLLC_FB_A (io), 31 PL17C (io), 32 PL17D (io), 33 PL18A/LLM0_PLLT_IN_A (io), 34 PL18B/LLM0_PLLC_IN_A (io), 35 PL19A (io), 36 PL19B (io)
part H pins: 1 PL2A/LUM0_PLLT_FB_A (io), 2 PL2B/LUM0_PLLC_FB_A (io), 3 PL3A (io), 4 PL3B (io), 5 PL3C/LUM0_PLLT_IN_A (io), 6 PL3D/LUM0_PLLC_IN_A (io), 7 PL4A (io), 8 PL4B (io), 9 PL4C (io), 12 PL6C (io), 13 PL7A (io), 14 PL7B/GSRN (io), 15 PL7D (io), 17 PL9C (io), 18 PL9D (io)
part I pins: 39 TMS (in) "Powered by VCCIO5", 42 TCK (in) "Powered by VCCIO5", 47 TDO (out) "Powered by VCCIO5", 51 TDI (in) "Powered by VCCIO5", 70 NC
part J pins: 10 VCCIO7 (power), 21 VCC (power), 26 VCCIO6 (power), 38 VCCIO5 (power), 52 VCC (power), 53 VCCAUX (power), 63 VCCIO4 (power), 82 VCCIO3 (power), 93 VCC (power), 98 VCCIO2 (power), 117 VCCIO1 (power), 128 VCCAUX (power), 129 VCC (power), 135 VCCIO0 (power)
part K pins: 11 GNDIO7 (power), 16 GND (power), 27 GNDIO6 (power), 37 GNDIO5 (power), 59 GND (power), 64 GNDIO4 (power), 83 GNDIO3 (power), 88 GND (power), 99 GNDIO2 (power), 118 GNDIO1 (power), 123 GND (power), 136 GNDIO0 (power)

## LCMXO2280E-3T144I
designator U?
MachXO 2280 Crossover PLD, 1.2V, 113 User I/Os, 144-Pins TQFP, Speed Grade-3, Industrial Grade
footprint TQFP144_N (Thin QFP, 144-Leads, Body 20x20mm, Pitch 0.5mm, IPC Medium Density)
footprint TQFP144_L (Thin QFP, 144-Leads, Body 20x20mm, Pitch 0.5mm, IPC High Density)
footprint TQFP144_M (Thin QFP, 144-Leads, Body 20x20mm, Pitch 0.5mm, IPC Low Density)
3D model MachXO2280-TQFP144 (144-Pin Thin Quad Flat Pack (TQFP144))
signal-integrity model LCMXO2280E_T144 (MachXO)
part A pins: 130 PT7B (io), 131 PT7A (io), 132 PT6D (io), 133 PT6E (io), 134 PT6F (io), 137 PT4B (io), 138 PT4A (io), 139 PT3B (io), 140 PT3A (io), 141 PT2D (io), 142 PT2C (io), 143 PT2B (io), 144 PT2A (io)
part B pins: 109 PT16D (io), 110 PT16C (io), 111 PT16B (io), 112 PT16A (io), 113 PT15D (io), 114 PT15C (io), 115 PT14B (io), 116 PT14A (io), 119 PT12F (io), 120 PT12E (io), 121 PT12D (io), 122 PT12C (io), 124 PT10B/PCLK1_1 (io), 125 PT9D (io), 126 PT9C (io), 127 PT9B/PCLK1_0 (io)
part C pins: 91 PR10B (io), 92 PR10A (io), 94 PR8B (io), 95 PR8A (io), 96 PR7B (io), 97 PR7A (io), 100 PR5C (io), 101 PR5B (io), 102 PR5A (io), 103 PR4D (io), 104 PR4C (io), 105 PR4B (io), 106 PR4A (io), 107 PR3B (io), 108 PR3A (io)
part D pins: 73 PR20B (io), 74 PR20A (io), 75 PR19B (io), 76 PR19A (io), 77 PR17D (io), 78 PR17C (io), 79 PR17B (io), 80 PR17A (io), 81 PR16D (io), 84 PR15B (io), 85 PR15A (io), 86 PR14B (io), 87 PR14A (io), 89 PR13B (io), 90 PR13A (io)
part E pins: 55 PB10F/PCLK4_1 (io), 56 PB10C (io), 57 PB10D (io), 58 PB10B/PCLK4_0 (io), 60 PB12A (io), 61 PB12B (io), 62 PB12E (io), 65 PB13A (io), 66 PB13B (io), 67 PB13C (io), 68 PB13D (io), 69 PB14D (io), 71 PB16C (io), 72 PB16D (io)
part F pins: 40 PB2A (io), 41 PB2B (io), 43 PB3A (io), 44 PB3B (io), 45 PB4A (io), 46 PB4B (io), 48 PB4D (io), 49 PB5A (io), 50 PB5B (io), 54 PB8F (io)
part G pins: 19 PL13A (io), 20 PL13B (io), 22 PL13D (io), 23 PL14D (io), 24 PL14C/TSALL (io), 25 PL15B (io), 28 PL16D (io), 29 PL17A/LLM0_PLLT_FB_A (io), 30 PL17B/LLM0_PLLC_FB_A (io), 31 PL17C (io), 32 PL17D (io), 33 PL18A/LLM0_PLLT_IN_A (io), 34 PL18B/LLM0_PLLC_IN_A (io), 35 PL19A (io), 36 PL19B (io)
part H pins: 1 PL2A/LUM0_PLLT_FB_A (io), 2 PL2B/LUM0_PLLC_FB_A (io), 3 PL3A (io), 4 PL3B (io), 5 PL3C/LUM0_PLLT_IN_A (io), 6 PL3D/LUM0_PLLC_IN_A (io), 7 PL4A (io), 8 PL4B (io), 9 PL4C (io), 12 PL6C (io), 13 PL7A (io), 14 PL7B/GSRN (io), 15 PL7D (io), 17 PL9C (io), 18 PL9D (io)
part I pins: 39 TMS (in) "Powered by VCCIO5", 42 TCK (in) "Powered by VCCIO5", 47 TDO (out) "Powered by VCCIO5", 51 TDI (in) "Powered by VCCIO5", 70 NC
part J pins: 10 VCCIO7 (power), 21 VCC (power), 26 VCCIO6 (power), 38 VCCIO5 (power), 52 VCC (power), 53 VCCAUX (power), 63 VCCIO4 (power), 82 VCCIO3 (power), 93 VCC (power), 98 VCCIO2 (power), 117 VCCIO1 (power), 128 VCCAUX (power), 129 VCC (power), 135 VCCIO0 (power)
part K pins: 11 GNDIO7 (power), 16 GND (power), 27 GNDIO6 (power), 37 GNDIO5 (power), 59 GND (power), 64 GNDIO4 (power), 83 GNDIO3 (power), 88 GND (power), 99 GNDIO2 (power), 118 GNDIO1 (power), 123 GND (power), 136 GNDIO0 (power)


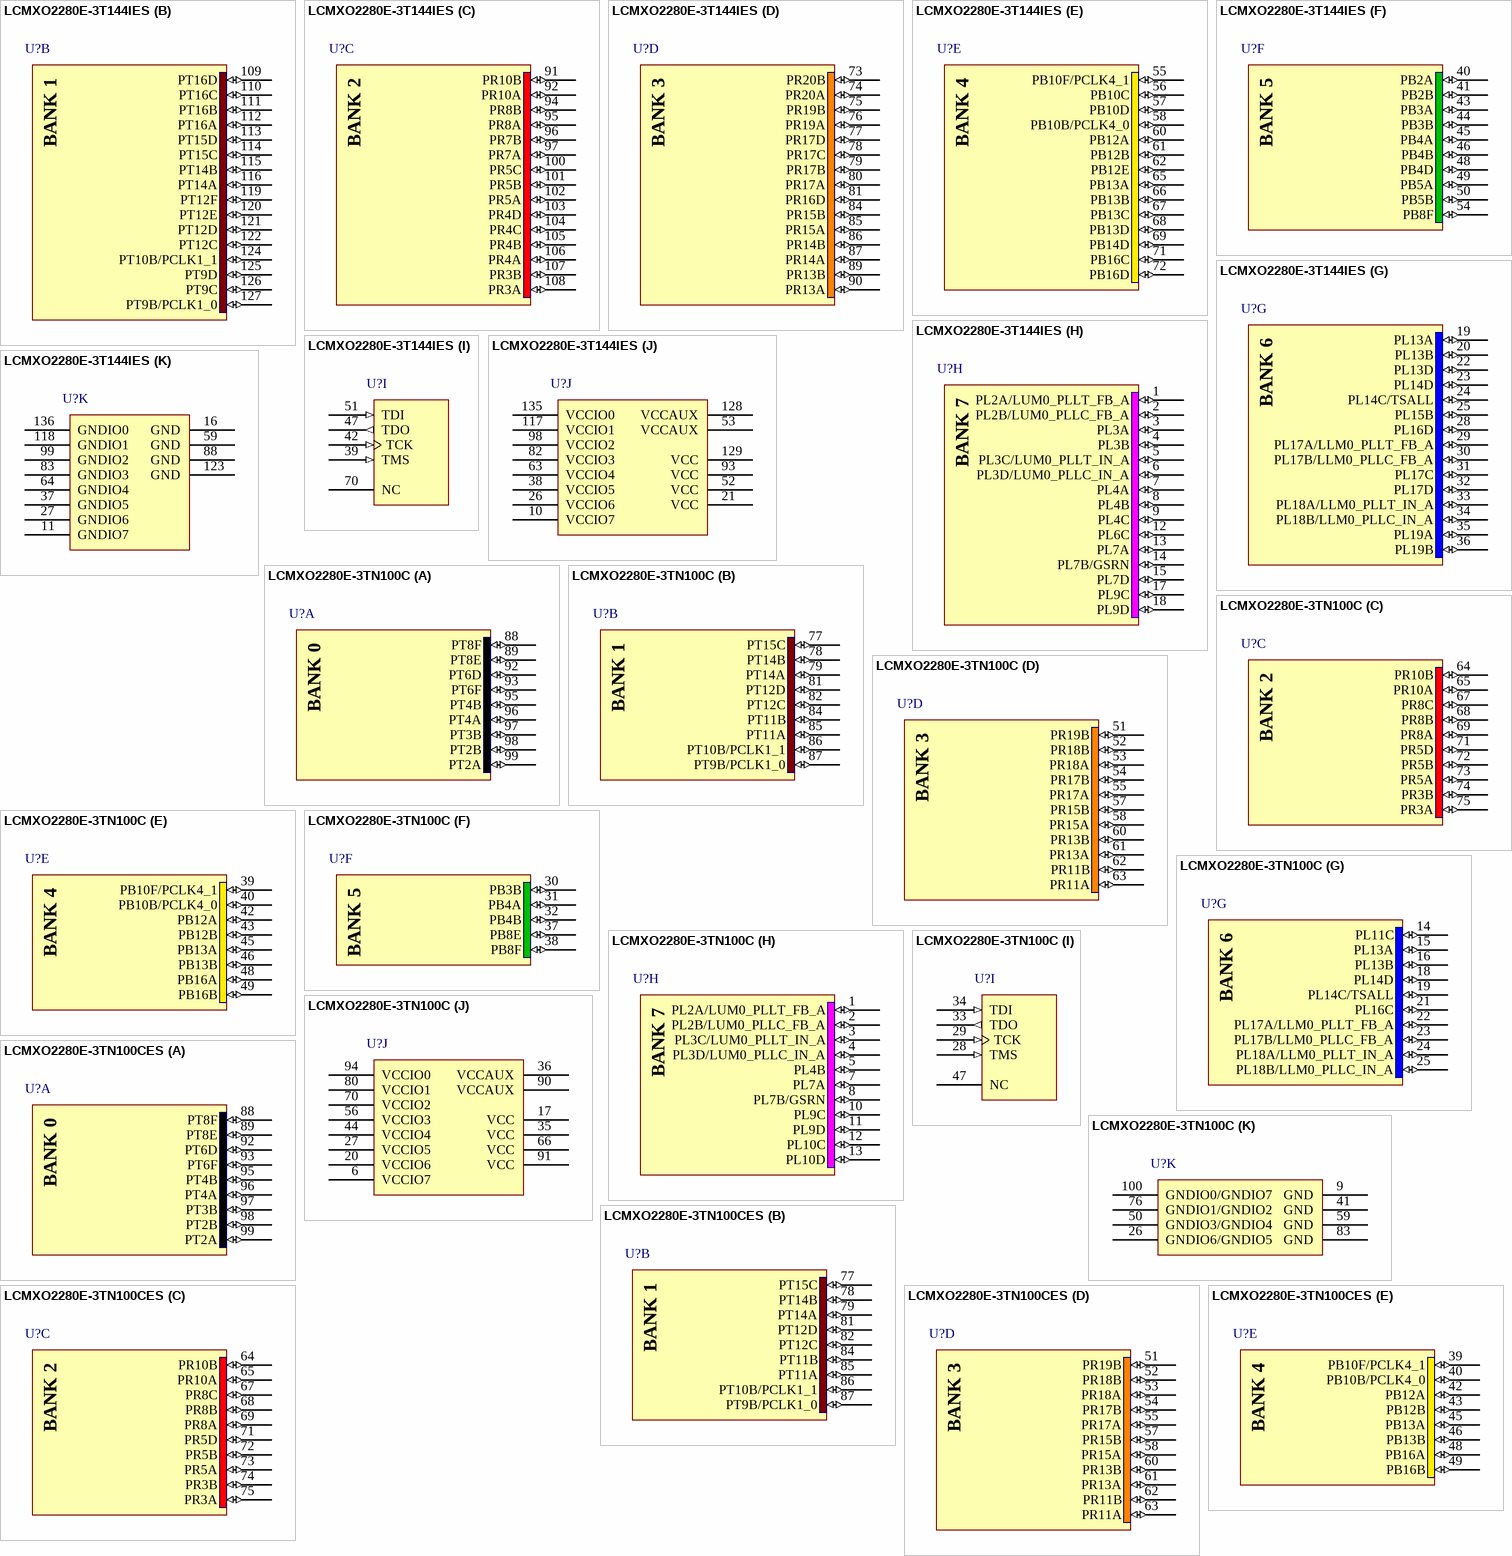
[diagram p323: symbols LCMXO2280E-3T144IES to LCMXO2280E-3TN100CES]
## LCMXO2280E-3T144IES
designator U?
MachXO 2280 Crossover PLD, 1.2V, 113 User I/Os, 144-Pins TQFP, Speed Grade-3, Industrial Grade, Engineering Sample
footprint TQFP144_N (Thin QFP, 144-Leads, Body 20x20mm, Pitch 0.5mm, IPC Medium Density)
footprint TQFP144_L (Thin QFP, 144-Leads, Body 20x20mm, Pitch 0.5mm, IPC High Density)
footprint TQFP144_M (Thin QFP, 144-Leads, Body 20x20mm, Pitch 0.5mm, IPC Low Density)
3D model MachXO2280-TQFP144 (144-Pin Thin Quad Flat Pack (TQFP144))
signal-integrity model LCMXO2280E_T144 (MachXO)
part A pins: 130 PT7B (io), 131 PT7A (io), 132 PT6D (io), 133 PT6E (io), 134 PT6F (io), 137 PT4B (io), 138 PT4A (io), 139 PT3B (io), 140 PT3A (io), 141 PT2D (io), 142 PT2C (io), 143 PT2B (io), 144 PT2A (io)
part B pins: 109 PT16D (io), 110 PT16C (io), 111 PT16B (io), 112 PT16A (io), 113 PT15D (io), 114 PT15C (io), 115 PT14B (io), 116 PT14A (io), 119 PT12F (io), 120 PT12E (io), 121 PT12D (io), 122 PT12C (io), 124 PT10B/PCLK1_1 (io), 125 PT9D (io), 126 PT9C (io), 127 PT9B/PCLK1_0 (io)
part C pins: 91 PR10B (io), 92 PR10A (io), 94 PR8B (io), 95 PR8A (io), 96 PR7B (io), 97 PR7A (io), 100 PR5C (io), 101 PR5B (io), 102 PR5A (io), 103 PR4D (io), 104 PR4C (io), 105 PR4B (io), 106 PR4A (io), 107 PR3B (io), 108 PR3A (io)
part D pins: 73 PR20B (io), 74 PR20A (io), 75 PR19B (io), 76 PR19A (io), 77 PR17D (io), 78 PR17C (io), 79 PR17B (io), 80 PR17A (io), 81 PR16D (io), 84 PR15B (io), 85 PR15A (io), 86 PR14B (io), 87 PR14A (io), 89 PR13B (io), 90 PR13A (io)
part E pins: 55 PB10F/PCLK4_1 (io), 56 PB10C (io), 57 PB10D (io), 58 PB10B/PCLK4_0 (io), 60 PB12A (io), 61 PB12B (io), 62 PB12E (io), 65 PB13A (io), 66 PB13B (io), 67 PB13C (io), 68 PB13D (io), 69 PB14D (io), 71 PB16C (io), 72 PB16D (io)
part F pins: 40 PB2A (io), 41 PB2B (io), 43 PB3A (io), 44 PB3B (io), 45 PB4A (io), 46 PB4B (io), 48 PB4D (io), 49 PB5A (io), 50 PB5B (io), 54 PB8F (io)
part G pins: 19 PL13A (io), 20 PL13B (io), 22 PL13D (io), 23 PL14D (io), 24 PL14C/TSALL (io), 25 PL15B (io), 28 PL16D (io), 29 PL17A/LLM0_PLLT_FB_A (io), 30 PL17B/LLM0_PLLC_FB_A (io), 31 PL17C (io), 32 PL17D (io), 33 PL18A/LLM0_PLLT_IN_A (io), 34 PL18B/LLM0_PLLC_IN_A (io), 35 PL19A (io), 36 PL19B (io)
part H pins: 1 PL2A/LUM0_PLLT_FB_A (io), 2 PL2B/LUM0_PLLC_FB_A (io), 3 PL3A (io), 4 PL3B (io), 5 PL3C/LUM0_PLLT_IN_A (io), 6 PL3D/LUM0_PLLC_IN_A (io), 7 PL4A (io), 8 PL4B (io), 9 PL4C (io), 12 PL6C (io), 13 PL7A (io), 14 PL7B/GSRN (io), 15 PL7D (io), 17 PL9C (io), 18 PL9D (io)
part I pins: 39 TMS (in) "Powered by VCCIO5", 42 TCK (in) "Powered by VCCIO5", 47 TDO (out) "Powered by VCCIO5", 51 TDI (in) "Powered by VCCIO5", 70 NC
part J pins: 10 VCCIO7 (power), 21 VCC (power), 26 VCCIO6 (power), 38 VCCIO5 (power), 52 VCC (power), 53 VCCAUX (power), 63 VCCIO4 (power), 82 VCCIO3 (power), 93 VCC (power), 98 VCCIO2 (power), 117 VCCIO1 (power), 128 VCCAUX (power), 129 VCC (power), 135 VCCIO0 (power)
part K pins: 11 GNDIO7 (power), 16 GND (power), 27 GNDIO6 (power), 37 GNDIO5 (power), 59 GND (power), 64 GNDIO4 (power), 83 GNDIO3 (power), 88 GND (power), 99 GNDIO2 (power), 118 GNDIO1 (power), 123 GND (power), 136 GNDIO0 (power)

## LCMXO2280E-3TN100C
designator U?
MachXO 2280 Crossover PLD, 1.2V, 73 User I/Os, 100-Pins TQFP, Speed Grade-3, Commercial Grade, Pb-Free
footprint TQFP100_N (Thin QFP, 100-Leads, Body 14x14mm, Pitch 0.5mm, IPC Medium Density)
footprint TQFP100_L (Thin QFP, 100-Leads, Body 14x14mm, Pitch 0.5mm, IPC High Density)
footprint TQFP100_M (Thin QFP, 100-Leads, Body 14x14mm, Pitch 0.5mm, IPC Low Density)
3D model MachXO2280-TQFP100 (100-Pin Thin Quad Flat Pack (TQFP100))
signal-integrity model LCMXO2280E_T100 (MachXO)
part A pins: 88 PT8F (io), 89 PT8E (io), 92 PT6D (io), 93 PT6F (io), 95 PT4B (io), 96 PT4A (io), 97 PT3B (io), 98 PT2B (io), 99 PT2A (io)
part B pins: 77 PT15C (io), 78 PT14B (io), 79 PT14A (io), 81 PT12D (io), 82 PT12C (io), 84 PT11B (io), 85 PT11A (io), 86 PT10B/PCLK1_1 (io), 87 PT9B/PCLK1_0 (io)
part C pins: 64 PR10B (io), 65 PR10A (io), 67 PR8C (io), 68 PR8B (io), 69 PR8A (io), 71 PR5D (io), 72 PR5B (io), 73 PR5A (io), 74 PR3B (io), 75 PR3A (io)
part D pins: 51 PR19B (io), 52 PR18B (io), 53 PR18A (io), 54 PR17B (io), 55 PR17A (io), 57 PR15B (io), 58 PR15A (io), 60 PR13B (io), 61 PR13A (io), 62 PR11B (io), 63 PR11A (io)
part E pins: 39 PB10F/PCLK4_1 (io), 40 PB10B/PCLK4_0 (io), 42 PB12A (io), 43 PB12B (io), 45 PB13A (io), 46 PB13B (io), 48 PB16A (io), 49 PB16B (io)
part F pins: 30 PB3B (io), 31 PB4A (io), 32 PB4B (io), 37 PB8E (io), 38 PB8F (io)
part G pins: 14 PL11C (io), 15 PL13A (io), 16 PL13B (io), 18 PL14D (io), 19 PL14C/TSALL (io), 21 PL16C (io), 22 PL17A/LLM0_PLLT_FB_A (io), 23 PL17B/LLM0_PLLC_FB_A (io), 24 PL18A/LLM0_PLLT_IN_A (io), 25 PL18B/LLM0_PLLC_IN_A (io)
part H pins: 1 PL2A/LUM0_PLLT_FB_A (io), 2 PL2B/LUM0_PLLC_FB_A (io), 3 PL3C/LUM0_PLLT_IN_A (io), 4 PL3D/LUM0_PLLC_IN_A (io), 5 PL4B (io), 7 PL7A (io), 8 PL7B/GSRN (io), 10 PL9C (io), 11 PL9D (io), 12 PL10C (io), 13 PL10D (io)
part I pins: 28 TMS (in) "Powered by VCCIO5", 29 TCK (in) "Powered by VCCIO5", 33 TDO (out) "Powered by VCCIO5", 34 TDI (in) "Powered by VCCIO5", 47 NC
part J pins: 6 VCCIO7 (power), 17 VCC (power), 20 VCCIO6 (power), 27 VCCIO5 (power), 35 VCC (power), 36 VCCAUX (power), 44 VCCIO4 (power), 56 VCCIO3 (power), 66 VCC (power), 70 VCCIO2 (power), 80 VCCIO1 (power), 90 VCCAUX (power), 91 VCC (power), 94 VCCIO0 (power)
part K pins: 9 GND (power), 26 GNDIO6/GNDIO5 (power) "Double Bonded pin", 41 GND (power), 50 GNDIO3/GNDIO4 (power) "Double Bonded pin", 59 GND (power), 76 GNDIO1/GNDIO2 (power) "Double Bonded pin", 83 GND (power), 100 GNDIO0/GNDIO7 (power) "Double Bonded pin"


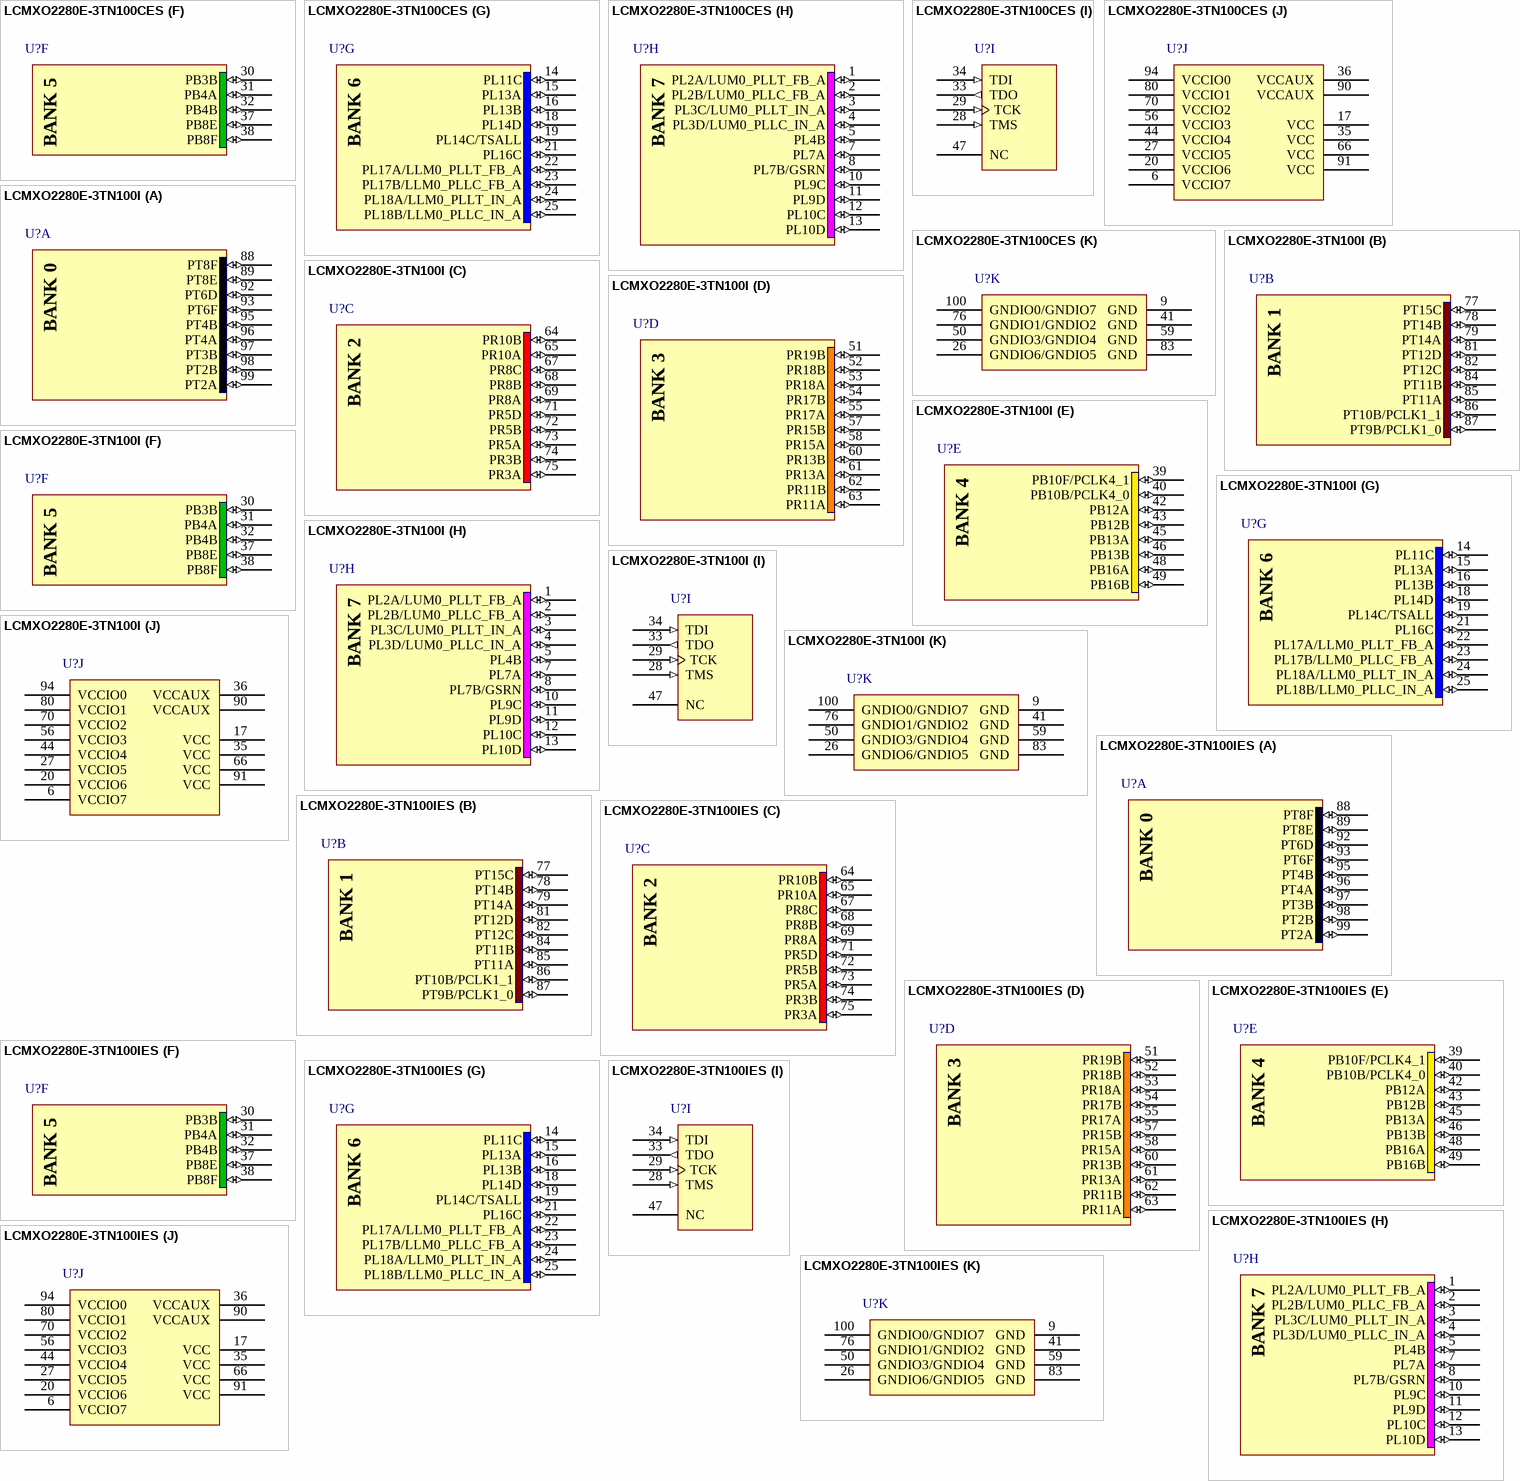
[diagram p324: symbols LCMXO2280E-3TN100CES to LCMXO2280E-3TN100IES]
## LCMXO2280E-3TN100CES
designator U?
MachXO 2280 Crossover PLD, 1.2V, 73 User I/Os, 100-Pins TQFP, Speed Grade-3, Commercial Grade, Pb-Free, Engineering Sample
footprint TQFP100_N (Thin QFP, 100-Leads, Body 14x14mm, Pitch 0.5mm, IPC Medium Density)
footprint TQFP100_L (Thin QFP, 100-Leads, Body 14x14mm, Pitch 0.5mm, IPC High Density)
footprint TQFP100_M (Thin QFP, 100-Leads, Body 14x14mm, Pitch 0.5mm, IPC Low Density)
3D model MachXO2280-TQFP100 (100-Pin Thin Quad Flat Pack (TQFP100))
signal-integrity model LCMXO2280E_T100 (MachXO)
part A pins: 88 PT8F (io), 89 PT8E (io), 92 PT6D (io), 93 PT6F (io), 95 PT4B (io), 96 PT4A (io), 97 PT3B (io), 98 PT2B (io), 99 PT2A (io)
part B pins: 77 PT15C (io), 78 PT14B (io), 79 PT14A (io), 81 PT12D (io), 82 PT12C (io), 84 PT11B (io), 85 PT11A (io), 86 PT10B/PCLK1_1 (io), 87 PT9B/PCLK1_0 (io)
part C pins: 64 PR10B (io), 65 PR10A (io), 67 PR8C (io), 68 PR8B (io), 69 PR8A (io), 71 PR5D (io), 72 PR5B (io), 73 PR5A (io), 74 PR3B (io), 75 PR3A (io)
part D pins: 51 PR19B (io), 52 PR18B (io), 53 PR18A (io), 54 PR17B (io), 55 PR17A (io), 57 PR15B (io), 58 PR15A (io), 60 PR13B (io), 61 PR13A (io), 62 PR11B (io), 63 PR11A (io)
part E pins: 39 PB10F/PCLK4_1 (io), 40 PB10B/PCLK4_0 (io), 42 PB12A (io), 43 PB12B (io), 45 PB13A (io), 46 PB13B (io), 48 PB16A (io), 49 PB16B (io)
part F pins: 30 PB3B (io), 31 PB4A (io), 32 PB4B (io), 37 PB8E (io), 38 PB8F (io)
part G pins: 14 PL11C (io), 15 PL13A (io), 16 PL13B (io), 18 PL14D (io), 19 PL14C/TSALL (io), 21 PL16C (io), 22 PL17A/LLM0_PLLT_FB_A (io), 23 PL17B/LLM0_PLLC_FB_A (io), 24 PL18A/LLM0_PLLT_IN_A (io), 25 PL18B/LLM0_PLLC_IN_A (io)
part H pins: 1 PL2A/LUM0_PLLT_FB_A (io), 2 PL2B/LUM0_PLLC_FB_A (io), 3 PL3C/LUM0_PLLT_IN_A (io), 4 PL3D/LUM0_PLLC_IN_A (io), 5 PL4B (io), 7 PL7A (io), 8 PL7B/GSRN (io), 10 PL9C (io), 11 PL9D (io), 12 PL10C (io), 13 PL10D (io)
part I pins: 28 TMS (in) "Powered by VCCIO5", 29 TCK (in) "Powered by VCCIO5", 33 TDO (out) "Powered by VCCIO5", 34 TDI (in) "Powered by VCCIO5", 47 NC
part J pins: 6 VCCIO7 (power), 17 VCC (power), 20 VCCIO6 (power), 27 VCCIO5 (power), 35 VCC (power), 36 VCCAUX (power), 44 VCCIO4 (power), 56 VCCIO3 (power), 66 VCC (power), 70 VCCIO2 (power), 80 VCCIO1 (power), 90 VCCAUX (power), 91 VCC (power), 94 VCCIO0 (power)
part K pins: 9 GND (power), 26 GNDIO6/GNDIO5 (power) "Double Bonded pin", 41 GND (power), 50 GNDIO3/GNDIO4 (power) "Double Bonded pin", 59 GND (power), 76 GNDIO1/GNDIO2 (power) "Double Bonded pin", 83 GND (power), 100 GNDIO0/GNDIO7 (power) "Double Bonded pin"

## LCMXO2280E-3TN100I
designator U?
MachXO 2280 Crossover PLD, 1.2V, 73 User I/Os, 100-Pins TQFP, Speed Grade-3, Industrial Grade, Pb-Free
footprint TQFP100_N (Thin QFP, 100-Leads, Body 14x14mm, Pitch 0.5mm, IPC Medium Density)
footprint TQFP100_L (Thin QFP, 100-Leads, Body 14x14mm, Pitch 0.5mm, IPC High Density)
footprint TQFP100_M (Thin QFP, 100-Leads, Body 14x14mm, Pitch 0.5mm, IPC Low Density)
3D model MachXO2280-TQFP100 (100-Pin Thin Quad Flat Pack (TQFP100))
signal-integrity model LCMXO2280E_T100 (MachXO)
part A pins: 88 PT8F (io), 89 PT8E (io), 92 PT6D (io), 93 PT6F (io), 95 PT4B (io), 96 PT4A (io), 97 PT3B (io), 98 PT2B (io), 99 PT2A (io)
part B pins: 77 PT15C (io), 78 PT14B (io), 79 PT14A (io), 81 PT12D (io), 82 PT12C (io), 84 PT11B (io), 85 PT11A (io), 86 PT10B/PCLK1_1 (io), 87 PT9B/PCLK1_0 (io)
part C pins: 64 PR10B (io), 65 PR10A (io), 67 PR8C (io), 68 PR8B (io), 69 PR8A (io), 71 PR5D (io), 72 PR5B (io), 73 PR5A (io), 74 PR3B (io), 75 PR3A (io)
part D pins: 51 PR19B (io), 52 PR18B (io), 53 PR18A (io), 54 PR17B (io), 55 PR17A (io), 57 PR15B (io), 58 PR15A (io), 60 PR13B (io), 61 PR13A (io), 62 PR11B (io), 63 PR11A (io)
part E pins: 39 PB10F/PCLK4_1 (io), 40 PB10B/PCLK4_0 (io), 42 PB12A (io), 43 PB12B (io), 45 PB13A (io), 46 PB13B (io), 48 PB16A (io), 49 PB16B (io)
part F pins: 30 PB3B (io), 31 PB4A (io), 32 PB4B (io), 37 PB8E (io), 38 PB8F (io)
part G pins: 14 PL11C (io), 15 PL13A (io), 16 PL13B (io), 18 PL14D (io), 19 PL14C/TSALL (io), 21 PL16C (io), 22 PL17A/LLM0_PLLT_FB_A (io), 23 PL17B/LLM0_PLLC_FB_A (io), 24 PL18A/LLM0_PLLT_IN_A (io), 25 PL18B/LLM0_PLLC_IN_A (io)
part H pins: 1 PL2A/LUM0_PLLT_FB_A (io), 2 PL2B/LUM0_PLLC_FB_A (io), 3 PL3C/LUM0_PLLT_IN_A (io), 4 PL3D/LUM0_PLLC_IN_A (io), 5 PL4B (io), 7 PL7A (io), 8 PL7B/GSRN (io), 10 PL9C (io), 11 PL9D (io), 12 PL10C (io), 13 PL10D (io)
part I pins: 28 TMS (in) "Powered by VCCIO5", 29 TCK (in) "Powered by VCCIO5", 33 TDO (out) "Powered by VCCIO5", 34 TDI (in) "Powered by VCCIO5", 47 NC
part J pins: 6 VCCIO7 (power), 17 VCC (power), 20 VCCIO6 (power), 27 VCCIO5 (power), 35 VCC (power), 36 VCCAUX (power), 44 VCCIO4 (power), 56 VCCIO3 (power), 66 VCC (power), 70 VCCIO2 (power), 80 VCCIO1 (power), 90 VCCAUX (power), 91 VCC (power), 94 VCCIO0 (power)
part K pins: 9 GND (power), 26 GNDIO6/GNDIO5 (power) "Double Bonded pin", 41 GND (power), 50 GNDIO3/GNDIO4 (power) "Double Bonded pin", 59 GND (power), 76 GNDIO1/GNDIO2 (power) "Double Bonded pin", 83 GND (power), 100 GNDIO0/GNDIO7 (power) "Double Bonded pin"

## LCMXO2280E-3TN100IES
designator U?
MachXO 2280 Crossover PLD, 1.2V, 73 User I/Os, 100-Pins TQFP, Speed Grade-3, Industrial Grade, Pb-Free, Engineering Sample
footprint TQFP100_N (Thin QFP, 100-Leads, Body 14x14mm, Pitch 0.5mm, IPC Medium Density)
footprint TQFP100_L (Thin QFP, 100-Leads, Body 14x14mm, Pitch 0.5mm, IPC High Density)
footprint TQFP100_M (Thin QFP, 100-Leads, Body 14x14mm, Pitch 0.5mm, IPC Low Density)
3D model MachXO2280-TQFP100 (100-Pin Thin Quad Flat Pack (TQFP100))
signal-integrity model LCMXO2280E_T100 (MachXO)
part A pins: 88 PT8F (io), 89 PT8E (io), 92 PT6D (io), 93 PT6F (io), 95 PT4B (io), 96 PT4A (io), 97 PT3B (io), 98 PT2B (io), 99 PT2A (io)
part B pins: 77 PT15C (io), 78 PT14B (io), 79 PT14A (io), 81 PT12D (io), 82 PT12C (io), 84 PT11B (io), 85 PT11A (io), 86 PT10B/PCLK1_1 (io), 87 PT9B/PCLK1_0 (io)
part C pins: 64 PR10B (io), 65 PR10A (io), 67 PR8C (io), 68 PR8B (io), 69 PR8A (io), 71 PR5D (io), 72 PR5B (io), 73 PR5A (io), 74 PR3B (io), 75 PR3A (io)
part D pins: 51 PR19B (io), 52 PR18B (io), 53 PR18A (io), 54 PR17B (io), 55 PR17A (io), 57 PR15B (io), 58 PR15A (io), 60 PR13B (io), 61 PR13A (io), 62 PR11B (io), 63 PR11A (io)
part E pins: 39 PB10F/PCLK4_1 (io), 40 PB10B/PCLK4_0 (io), 42 PB12A (io), 43 PB12B (io), 45 PB13A (io), 46 PB13B (io), 48 PB16A (io), 49 PB16B (io)
part F pins: 30 PB3B (io), 31 PB4A (io), 32 PB4B (io), 37 PB8E (io), 38 PB8F (io)
part G pins: 14 PL11C (io), 15 PL13A (io), 16 PL13B (io), 18 PL14D (io), 19 PL14C/TSALL (io), 21 PL16C (io), 22 PL17A/LLM0_PLLT_FB_A (io), 23 PL17B/LLM0_PLLC_FB_A (io), 24 PL18A/LLM0_PLLT_IN_A (io), 25 PL18B/LLM0_PLLC_IN_A (io)
part H pins: 1 PL2A/LUM0_PLLT_FB_A (io), 2 PL2B/LUM0_PLLC_FB_A (io), 3 PL3C/LUM0_PLLT_IN_A (io), 4 PL3D/LUM0_PLLC_IN_A (io), 5 PL4B (io), 7 PL7A (io), 8 PL7B/GSRN (io), 10 PL9C (io), 11 PL9D (io), 12 PL10C (io), 13 PL10D (io)
part I pins: 28 TMS (in) "Powered by VCCIO5", 29 TCK (in) "Powered by VCCIO5", 33 TDO (out) "Powered by VCCIO5", 34 TDI (in) "Powered by VCCIO5", 47 NC
part J pins: 6 VCCIO7 (power), 17 VCC (power), 20 VCCIO6 (power), 27 VCCIO5 (power), 35 VCC (power), 36 VCCAUX (power), 44 VCCIO4 (power), 56 VCCIO3 (power), 66 VCC (power), 70 VCCIO2 (power), 80 VCCIO1 (power), 90 VCCAUX (power), 91 VCC (power), 94 VCCIO0 (power)
part K pins: 9 GND (power), 26 GNDIO6/GNDIO5 (power) "Double Bonded pin", 41 GND (power), 50 GNDIO3/GNDIO4 (power) "Double Bonded pin", 59 GND (power), 76 GNDIO1/GNDIO2 (power) "Double Bonded pin", 83 GND (power), 100 GNDIO0/GNDIO7 (power) "Double Bonded pin"


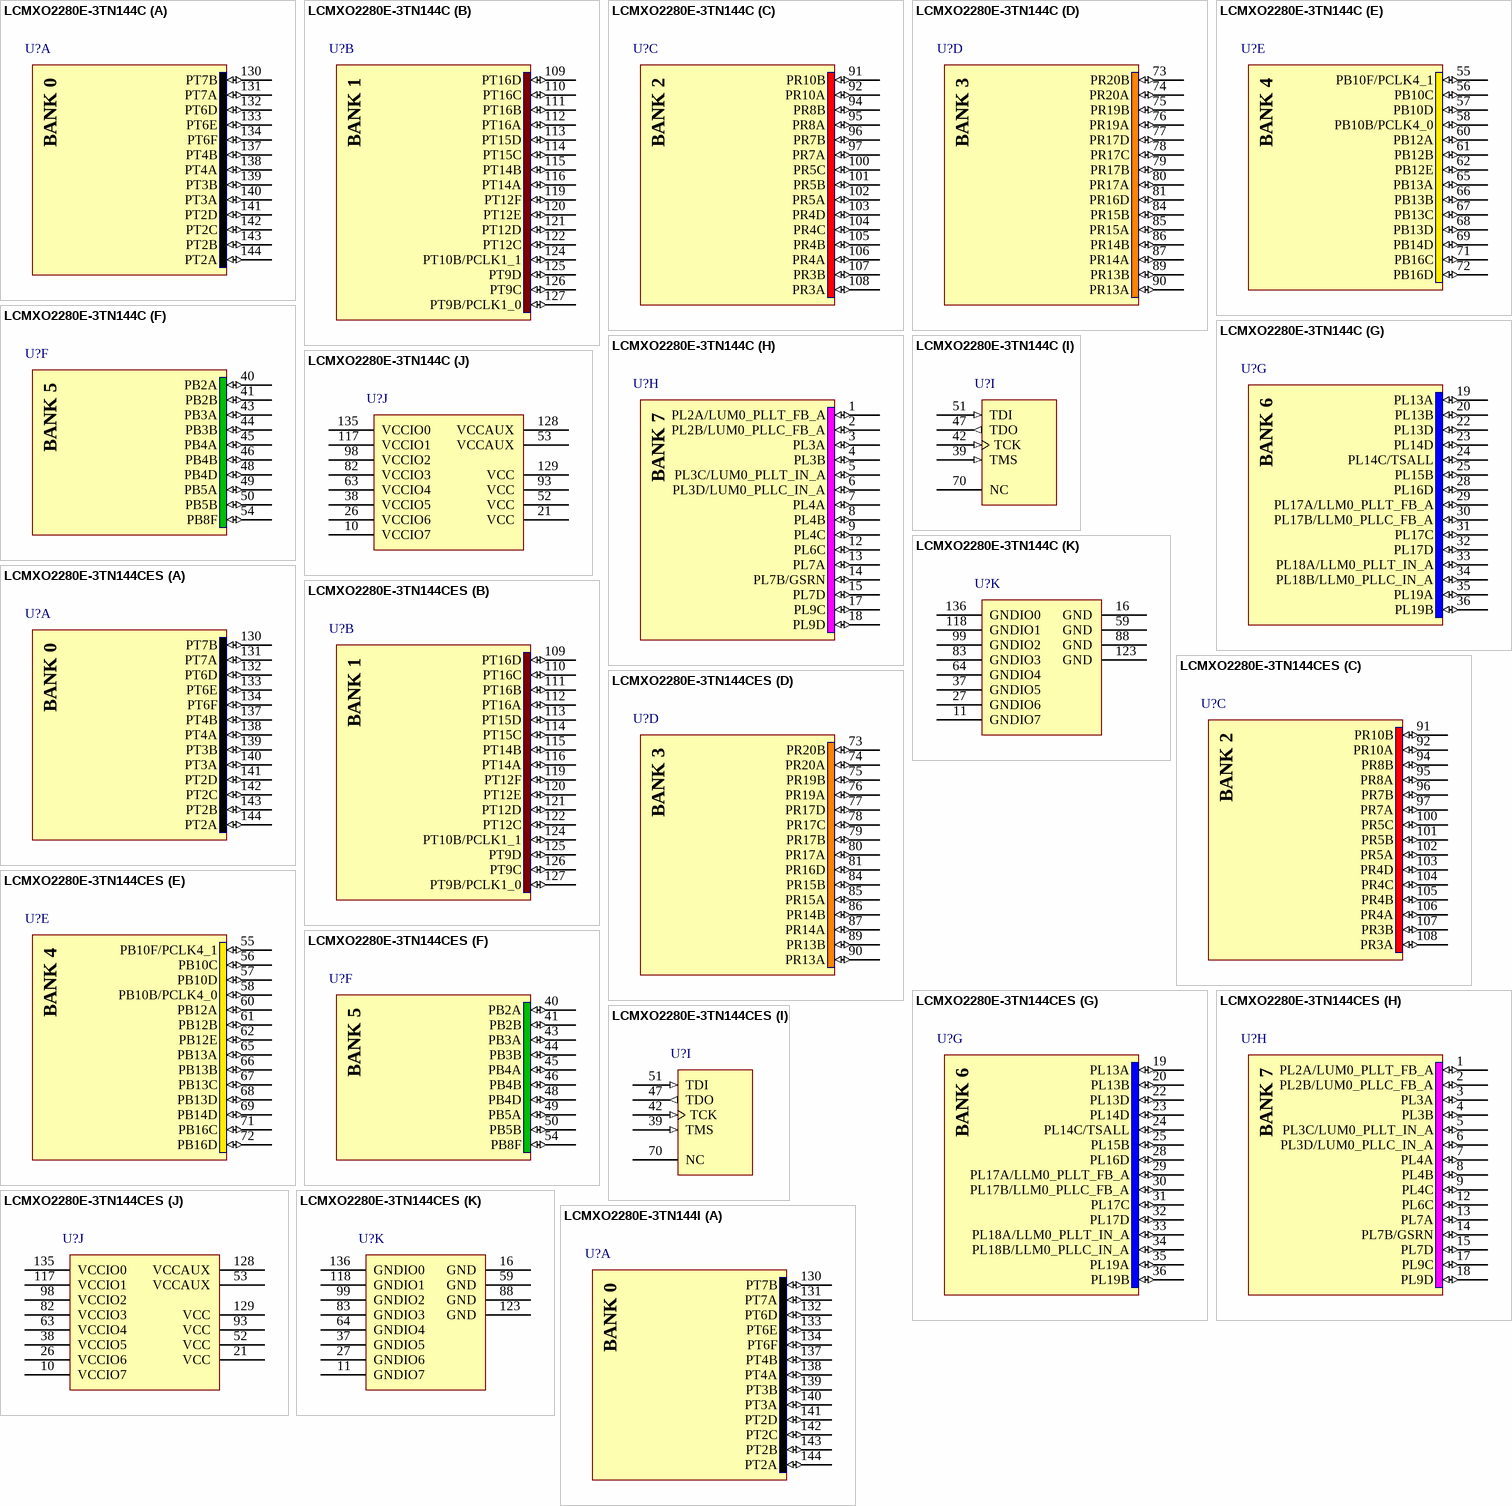
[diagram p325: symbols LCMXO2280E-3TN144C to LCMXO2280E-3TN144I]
## LCMXO2280E-3TN144C
designator U?
MachXO 2280 Crossover PLD, 1.2V, 113 User I/Os, 144-Pins TQFP, Speed Grade-3, Commercial Grade, Pb-Free
footprint TQFP144_N (Thin QFP, 144-Leads, Body 20x20mm, Pitch 0.5mm, IPC Medium Density)
footprint TQFP144_L (Thin QFP, 144-Leads, Body 20x20mm, Pitch 0.5mm, IPC High Density)
footprint TQFP144_M (Thin QFP, 144-Leads, Body 20x20mm, Pitch 0.5mm, IPC Low Density)
3D model MachXO2280-TQFP144 (144-Pin Thin Quad Flat Pack (TQFP144))
signal-integrity model LCMXO2280E_T144 (MachXO)
part A pins: 130 PT7B (io), 131 PT7A (io), 132 PT6D (io), 133 PT6E (io), 134 PT6F (io), 137 PT4B (io), 138 PT4A (io), 139 PT3B (io), 140 PT3A (io), 141 PT2D (io), 142 PT2C (io), 143 PT2B (io), 144 PT2A (io)
part B pins: 109 PT16D (io), 110 PT16C (io), 111 PT16B (io), 112 PT16A (io), 113 PT15D (io), 114 PT15C (io), 115 PT14B (io), 116 PT14A (io), 119 PT12F (io), 120 PT12E (io), 121 PT12D (io), 122 PT12C (io), 124 PT10B/PCLK1_1 (io), 125 PT9D (io), 126 PT9C (io), 127 PT9B/PCLK1_0 (io)
part C pins: 91 PR10B (io), 92 PR10A (io), 94 PR8B (io), 95 PR8A (io), 96 PR7B (io), 97 PR7A (io), 100 PR5C (io), 101 PR5B (io), 102 PR5A (io), 103 PR4D (io), 104 PR4C (io), 105 PR4B (io), 106 PR4A (io), 107 PR3B (io), 108 PR3A (io)
part D pins: 73 PR20B (io), 74 PR20A (io), 75 PR19B (io), 76 PR19A (io), 77 PR17D (io), 78 PR17C (io), 79 PR17B (io), 80 PR17A (io), 81 PR16D (io), 84 PR15B (io), 85 PR15A (io), 86 PR14B (io), 87 PR14A (io), 89 PR13B (io), 90 PR13A (io)
part E pins: 55 PB10F/PCLK4_1 (io), 56 PB10C (io), 57 PB10D (io), 58 PB10B/PCLK4_0 (io), 60 PB12A (io), 61 PB12B (io), 62 PB12E (io), 65 PB13A (io), 66 PB13B (io), 67 PB13C (io), 68 PB13D (io), 69 PB14D (io), 71 PB16C (io), 72 PB16D (io)
part F pins: 40 PB2A (io), 41 PB2B (io), 43 PB3A (io), 44 PB3B (io), 45 PB4A (io), 46 PB4B (io), 48 PB4D (io), 49 PB5A (io), 50 PB5B (io), 54 PB8F (io)
part G pins: 19 PL13A (io), 20 PL13B (io), 22 PL13D (io), 23 PL14D (io), 24 PL14C/TSALL (io), 25 PL15B (io), 28 PL16D (io), 29 PL17A/LLM0_PLLT_FB_A (io), 30 PL17B/LLM0_PLLC_FB_A (io), 31 PL17C (io), 32 PL17D (io), 33 PL18A/LLM0_PLLT_IN_A (io), 34 PL18B/LLM0_PLLC_IN_A (io), 35 PL19A (io), 36 PL19B (io)
part H pins: 1 PL2A/LUM0_PLLT_FB_A (io), 2 PL2B/LUM0_PLLC_FB_A (io), 3 PL3A (io), 4 PL3B (io), 5 PL3C/LUM0_PLLT_IN_A (io), 6 PL3D/LUM0_PLLC_IN_A (io), 7 PL4A (io), 8 PL4B (io), 9 PL4C (io), 12 PL6C (io), 13 PL7A (io), 14 PL7B/GSRN (io), 15 PL7D (io), 17 PL9C (io), 18 PL9D (io)
part I pins: 39 TMS (in) "Powered by VCCIO5", 42 TCK (in) "Powered by VCCIO5", 47 TDO (out) "Powered by VCCIO5", 51 TDI (in) "Powered by VCCIO5", 70 NC
part J pins: 10 VCCIO7 (power), 21 VCC (power), 26 VCCIO6 (power), 38 VCCIO5 (power), 52 VCC (power), 53 VCCAUX (power), 63 VCCIO4 (power), 82 VCCIO3 (power), 93 VCC (power), 98 VCCIO2 (power), 117 VCCIO1 (power), 128 VCCAUX (power), 129 VCC (power), 135 VCCIO0 (power)
part K pins: 11 GNDIO7 (power), 16 GND (power), 27 GNDIO6 (power), 37 GNDIO5 (power), 59 GND (power), 64 GNDIO4 (power), 83 GNDIO3 (power), 88 GND (power), 99 GNDIO2 (power), 118 GNDIO1 (power), 123 GND (power), 136 GNDIO0 (power)

## LCMXO2280E-3TN144CES
designator U?
MachXO 2280 Crossover PLD, 1.2V, 113 User I/Os, 144-Pins TQFP, Speed Grade-3, Commercial Grade, Pb-Free, Engineering Sample
footprint TQFP144_N (Thin QFP, 144-Leads, Body 20x20mm, Pitch 0.5mm, IPC Medium Density)
footprint TQFP144_L (Thin QFP, 144-Leads, Body 20x20mm, Pitch 0.5mm, IPC High Density)
footprint TQFP144_M (Thin QFP, 144-Leads, Body 20x20mm, Pitch 0.5mm, IPC Low Density)
3D model MachXO2280-TQFP144 (144-Pin Thin Quad Flat Pack (TQFP144))
signal-integrity model LCMXO2280E_T144 (MachXO)
part A pins: 130 PT7B (io), 131 PT7A (io), 132 PT6D (io), 133 PT6E (io), 134 PT6F (io), 137 PT4B (io), 138 PT4A (io), 139 PT3B (io), 140 PT3A (io), 141 PT2D (io), 142 PT2C (io), 143 PT2B (io), 144 PT2A (io)
part B pins: 109 PT16D (io), 110 PT16C (io), 111 PT16B (io), 112 PT16A (io), 113 PT15D (io), 114 PT15C (io), 115 PT14B (io), 116 PT14A (io), 119 PT12F (io), 120 PT12E (io), 121 PT12D (io), 122 PT12C (io), 124 PT10B/PCLK1_1 (io), 125 PT9D (io), 126 PT9C (io), 127 PT9B/PCLK1_0 (io)
part C pins: 91 PR10B (io), 92 PR10A (io), 94 PR8B (io), 95 PR8A (io), 96 PR7B (io), 97 PR7A (io), 100 PR5C (io), 101 PR5B (io), 102 PR5A (io), 103 PR4D (io), 104 PR4C (io), 105 PR4B (io), 106 PR4A (io), 107 PR3B (io), 108 PR3A (io)
part D pins: 73 PR20B (io), 74 PR20A (io), 75 PR19B (io), 76 PR19A (io), 77 PR17D (io), 78 PR17C (io), 79 PR17B (io), 80 PR17A (io), 81 PR16D (io), 84 PR15B (io), 85 PR15A (io), 86 PR14B (io), 87 PR14A (io), 89 PR13B (io), 90 PR13A (io)
part E pins: 55 PB10F/PCLK4_1 (io), 56 PB10C (io), 57 PB10D (io), 58 PB10B/PCLK4_0 (io), 60 PB12A (io), 61 PB12B (io), 62 PB12E (io), 65 PB13A (io), 66 PB13B (io), 67 PB13C (io), 68 PB13D (io), 69 PB14D (io), 71 PB16C (io), 72 PB16D (io)
part F pins: 40 PB2A (io), 41 PB2B (io), 43 PB3A (io), 44 PB3B (io), 45 PB4A (io), 46 PB4B (io), 48 PB4D (io), 49 PB5A (io), 50 PB5B (io), 54 PB8F (io)
part G pins: 19 PL13A (io), 20 PL13B (io), 22 PL13D (io), 23 PL14D (io), 24 PL14C/TSALL (io), 25 PL15B (io), 28 PL16D (io), 29 PL17A/LLM0_PLLT_FB_A (io), 30 PL17B/LLM0_PLLC_FB_A (io), 31 PL17C (io), 32 PL17D (io), 33 PL18A/LLM0_PLLT_IN_A (io), 34 PL18B/LLM0_PLLC_IN_A (io), 35 PL19A (io), 36 PL19B (io)
part H pins: 1 PL2A/LUM0_PLLT_FB_A (io), 2 PL2B/LUM0_PLLC_FB_A (io), 3 PL3A (io), 4 PL3B (io), 5 PL3C/LUM0_PLLT_IN_A (io), 6 PL3D/LUM0_PLLC_IN_A (io), 7 PL4A (io), 8 PL4B (io), 9 PL4C (io), 12 PL6C (io), 13 PL7A (io), 14 PL7B/GSRN (io), 15 PL7D (io), 17 PL9C (io), 18 PL9D (io)
part I pins: 39 TMS (in) "Powered by VCCIO5", 42 TCK (in) "Powered by VCCIO5", 47 TDO (out) "Powered by VCCIO5", 51 TDI (in) "Powered by VCCIO5", 70 NC
part J pins: 10 VCCIO7 (power), 21 VCC (power), 26 VCCIO6 (power), 38 VCCIO5 (power), 52 VCC (power), 53 VCCAUX (power), 63 VCCIO4 (power), 82 VCCIO3 (power), 93 VCC (power), 98 VCCIO2 (power), 117 VCCIO1 (power), 128 VCCAUX (power), 129 VCC (power), 135 VCCIO0 (power)
part K pins: 11 GNDIO7 (power), 16 GND (power), 27 GNDIO6 (power), 37 GNDIO5 (power), 59 GND (power), 64 GNDIO4 (power), 83 GNDIO3 (power), 88 GND (power), 99 GNDIO2 (power), 118 GNDIO1 (power), 123 GND (power), 136 GNDIO0 (power)


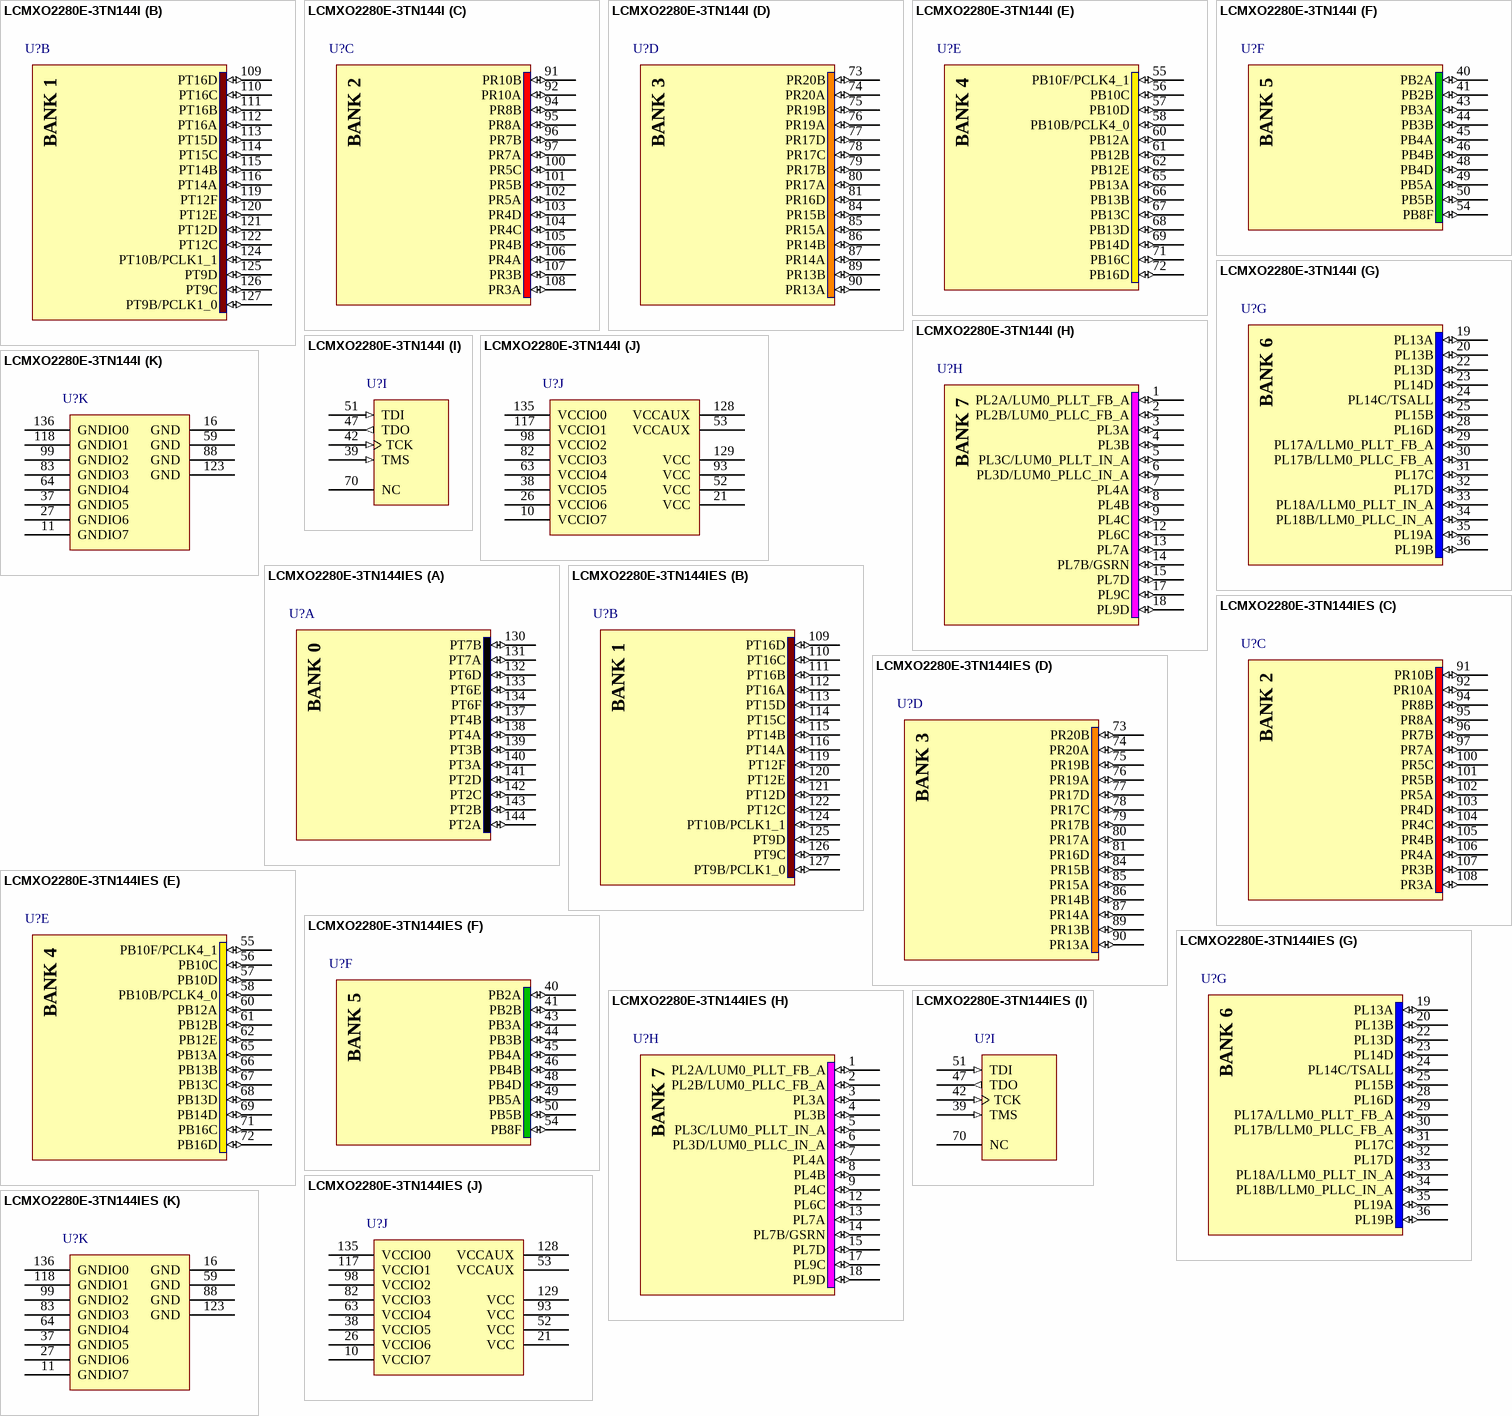
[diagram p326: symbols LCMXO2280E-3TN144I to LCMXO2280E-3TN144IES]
## LCMXO2280E-3TN144I
designator U?
MachXO 2280 Crossover PLD, 1.2V, 113 User I/Os, 144-Pins TQFP, Speed Grade-3, Industrial Grade, Pb-Free
footprint TQFP144_N (Thin QFP, 144-Leads, Body 20x20mm, Pitch 0.5mm, IPC Medium Density)
footprint TQFP144_L (Thin QFP, 144-Leads, Body 20x20mm, Pitch 0.5mm, IPC High Density)
footprint TQFP144_M (Thin QFP, 144-Leads, Body 20x20mm, Pitch 0.5mm, IPC Low Density)
3D model MachXO2280-TQFP144 (144-Pin Thin Quad Flat Pack (TQFP144))
signal-integrity model LCMXO2280E_T144 (MachXO)
part A pins: 130 PT7B (io), 131 PT7A (io), 132 PT6D (io), 133 PT6E (io), 134 PT6F (io), 137 PT4B (io), 138 PT4A (io), 139 PT3B (io), 140 PT3A (io), 141 PT2D (io), 142 PT2C (io), 143 PT2B (io), 144 PT2A (io)
part B pins: 109 PT16D (io), 110 PT16C (io), 111 PT16B (io), 112 PT16A (io), 113 PT15D (io), 114 PT15C (io), 115 PT14B (io), 116 PT14A (io), 119 PT12F (io), 120 PT12E (io), 121 PT12D (io), 122 PT12C (io), 124 PT10B/PCLK1_1 (io), 125 PT9D (io), 126 PT9C (io), 127 PT9B/PCLK1_0 (io)
part C pins: 91 PR10B (io), 92 PR10A (io), 94 PR8B (io), 95 PR8A (io), 96 PR7B (io), 97 PR7A (io), 100 PR5C (io), 101 PR5B (io), 102 PR5A (io), 103 PR4D (io), 104 PR4C (io), 105 PR4B (io), 106 PR4A (io), 107 PR3B (io), 108 PR3A (io)
part D pins: 73 PR20B (io), 74 PR20A (io), 75 PR19B (io), 76 PR19A (io), 77 PR17D (io), 78 PR17C (io), 79 PR17B (io), 80 PR17A (io), 81 PR16D (io), 84 PR15B (io), 85 PR15A (io), 86 PR14B (io), 87 PR14A (io), 89 PR13B (io), 90 PR13A (io)
part E pins: 55 PB10F/PCLK4_1 (io), 56 PB10C (io), 57 PB10D (io), 58 PB10B/PCLK4_0 (io), 60 PB12A (io), 61 PB12B (io), 62 PB12E (io), 65 PB13A (io), 66 PB13B (io), 67 PB13C (io), 68 PB13D (io), 69 PB14D (io), 71 PB16C (io), 72 PB16D (io)
part F pins: 40 PB2A (io), 41 PB2B (io), 43 PB3A (io), 44 PB3B (io), 45 PB4A (io), 46 PB4B (io), 48 PB4D (io), 49 PB5A (io), 50 PB5B (io), 54 PB8F (io)
part G pins: 19 PL13A (io), 20 PL13B (io), 22 PL13D (io), 23 PL14D (io), 24 PL14C/TSALL (io), 25 PL15B (io), 28 PL16D (io), 29 PL17A/LLM0_PLLT_FB_A (io), 30 PL17B/LLM0_PLLC_FB_A (io), 31 PL17C (io), 32 PL17D (io), 33 PL18A/LLM0_PLLT_IN_A (io), 34 PL18B/LLM0_PLLC_IN_A (io), 35 PL19A (io), 36 PL19B (io)
part H pins: 1 PL2A/LUM0_PLLT_FB_A (io), 2 PL2B/LUM0_PLLC_FB_A (io), 3 PL3A (io), 4 PL3B (io), 5 PL3C/LUM0_PLLT_IN_A (io), 6 PL3D/LUM0_PLLC_IN_A (io), 7 PL4A (io), 8 PL4B (io), 9 PL4C (io), 12 PL6C (io), 13 PL7A (io), 14 PL7B/GSRN (io), 15 PL7D (io), 17 PL9C (io), 18 PL9D (io)
part I pins: 39 TMS (in) "Powered by VCCIO5", 42 TCK (in) "Powered by VCCIO5", 47 TDO (out) "Powered by VCCIO5", 51 TDI (in) "Powered by VCCIO5", 70 NC
part J pins: 10 VCCIO7 (power), 21 VCC (power), 26 VCCIO6 (power), 38 VCCIO5 (power), 52 VCC (power), 53 VCCAUX (power), 63 VCCIO4 (power), 82 VCCIO3 (power), 93 VCC (power), 98 VCCIO2 (power), 117 VCCIO1 (power), 128 VCCAUX (power), 129 VCC (power), 135 VCCIO0 (power)
part K pins: 11 GNDIO7 (power), 16 GND (power), 27 GNDIO6 (power), 37 GNDIO5 (power), 59 GND (power), 64 GNDIO4 (power), 83 GNDIO3 (power), 88 GND (power), 99 GNDIO2 (power), 118 GNDIO1 (power), 123 GND (power), 136 GNDIO0 (power)

## LCMXO2280E-3TN144IES
designator U?
MachXO 2280 Crossover PLD, 1.2V, 113 User I/Os, 144-Pins TQFP, Speed Grade-3, Industrial Grade, Pb-Free, Engineering Sample
footprint TQFP144_N (Thin QFP, 144-Leads, Body 20x20mm, Pitch 0.5mm, IPC Medium Density)
footprint TQFP144_L (Thin QFP, 144-Leads, Body 20x20mm, Pitch 0.5mm, IPC High Density)
footprint TQFP144_M (Thin QFP, 144-Leads, Body 20x20mm, Pitch 0.5mm, IPC Low Density)
3D model MachXO2280-TQFP144 (144-Pin Thin Quad Flat Pack (TQFP144))
signal-integrity model LCMXO2280E_T144 (MachXO)
part A pins: 130 PT7B (io), 131 PT7A (io), 132 PT6D (io), 133 PT6E (io), 134 PT6F (io), 137 PT4B (io), 138 PT4A (io), 139 PT3B (io), 140 PT3A (io), 141 PT2D (io), 142 PT2C (io), 143 PT2B (io), 144 PT2A (io)
part B pins: 109 PT16D (io), 110 PT16C (io), 111 PT16B (io), 112 PT16A (io), 113 PT15D (io), 114 PT15C (io), 115 PT14B (io), 116 PT14A (io), 119 PT12F (io), 120 PT12E (io), 121 PT12D (io), 122 PT12C (io), 124 PT10B/PCLK1_1 (io), 125 PT9D (io), 126 PT9C (io), 127 PT9B/PCLK1_0 (io)
part C pins: 91 PR10B (io), 92 PR10A (io), 94 PR8B (io), 95 PR8A (io), 96 PR7B (io), 97 PR7A (io), 100 PR5C (io), 101 PR5B (io), 102 PR5A (io), 103 PR4D (io), 104 PR4C (io), 105 PR4B (io), 106 PR4A (io), 107 PR3B (io), 108 PR3A (io)
part D pins: 73 PR20B (io), 74 PR20A (io), 75 PR19B (io), 76 PR19A (io), 77 PR17D (io), 78 PR17C (io), 79 PR17B (io), 80 PR17A (io), 81 PR16D (io), 84 PR15B (io), 85 PR15A (io), 86 PR14B (io), 87 PR14A (io), 89 PR13B (io), 90 PR13A (io)
part E pins: 55 PB10F/PCLK4_1 (io), 56 PB10C (io), 57 PB10D (io), 58 PB10B/PCLK4_0 (io), 60 PB12A (io), 61 PB12B (io), 62 PB12E (io), 65 PB13A (io), 66 PB13B (io), 67 PB13C (io), 68 PB13D (io), 69 PB14D (io), 71 PB16C (io), 72 PB16D (io)
part F pins: 40 PB2A (io), 41 PB2B (io), 43 PB3A (io), 44 PB3B (io), 45 PB4A (io), 46 PB4B (io), 48 PB4D (io), 49 PB5A (io), 50 PB5B (io), 54 PB8F (io)
part G pins: 19 PL13A (io), 20 PL13B (io), 22 PL13D (io), 23 PL14D (io), 24 PL14C/TSALL (io), 25 PL15B (io), 28 PL16D (io), 29 PL17A/LLM0_PLLT_FB_A (io), 30 PL17B/LLM0_PLLC_FB_A (io), 31 PL17C (io), 32 PL17D (io), 33 PL18A/LLM0_PLLT_IN_A (io), 34 PL18B/LLM0_PLLC_IN_A (io), 35 PL19A (io), 36 PL19B (io)
part H pins: 1 PL2A/LUM0_PLLT_FB_A (io), 2 PL2B/LUM0_PLLC_FB_A (io), 3 PL3A (io), 4 PL3B (io), 5 PL3C/LUM0_PLLT_IN_A (io), 6 PL3D/LUM0_PLLC_IN_A (io), 7 PL4A (io), 8 PL4B (io), 9 PL4C (io), 12 PL6C (io), 13 PL7A (io), 14 PL7B/GSRN (io), 15 PL7D (io), 17 PL9C (io), 18 PL9D (io)
part I pins: 39 TMS (in) "Powered by VCCIO5", 42 TCK (in) "Powered by VCCIO5", 47 TDO (out) "Powered by VCCIO5", 51 TDI (in) "Powered by VCCIO5", 70 NC
part J pins: 10 VCCIO7 (power), 21 VCC (power), 26 VCCIO6 (power), 38 VCCIO5 (power), 52 VCC (power), 53 VCCAUX (power), 63 VCCIO4 (power), 82 VCCIO3 (power), 93 VCC (power), 98 VCCIO2 (power), 117 VCCIO1 (power), 128 VCCAUX (power), 129 VCC (power), 135 VCCIO0 (power)
part K pins: 11 GNDIO7 (power), 16 GND (power), 27 GNDIO6 (power), 37 GNDIO5 (power), 59 GND (power), 64 GNDIO4 (power), 83 GNDIO3 (power), 88 GND (power), 99 GNDIO2 (power), 118 GNDIO1 (power), 123 GND (power), 136 GNDIO0 (power)


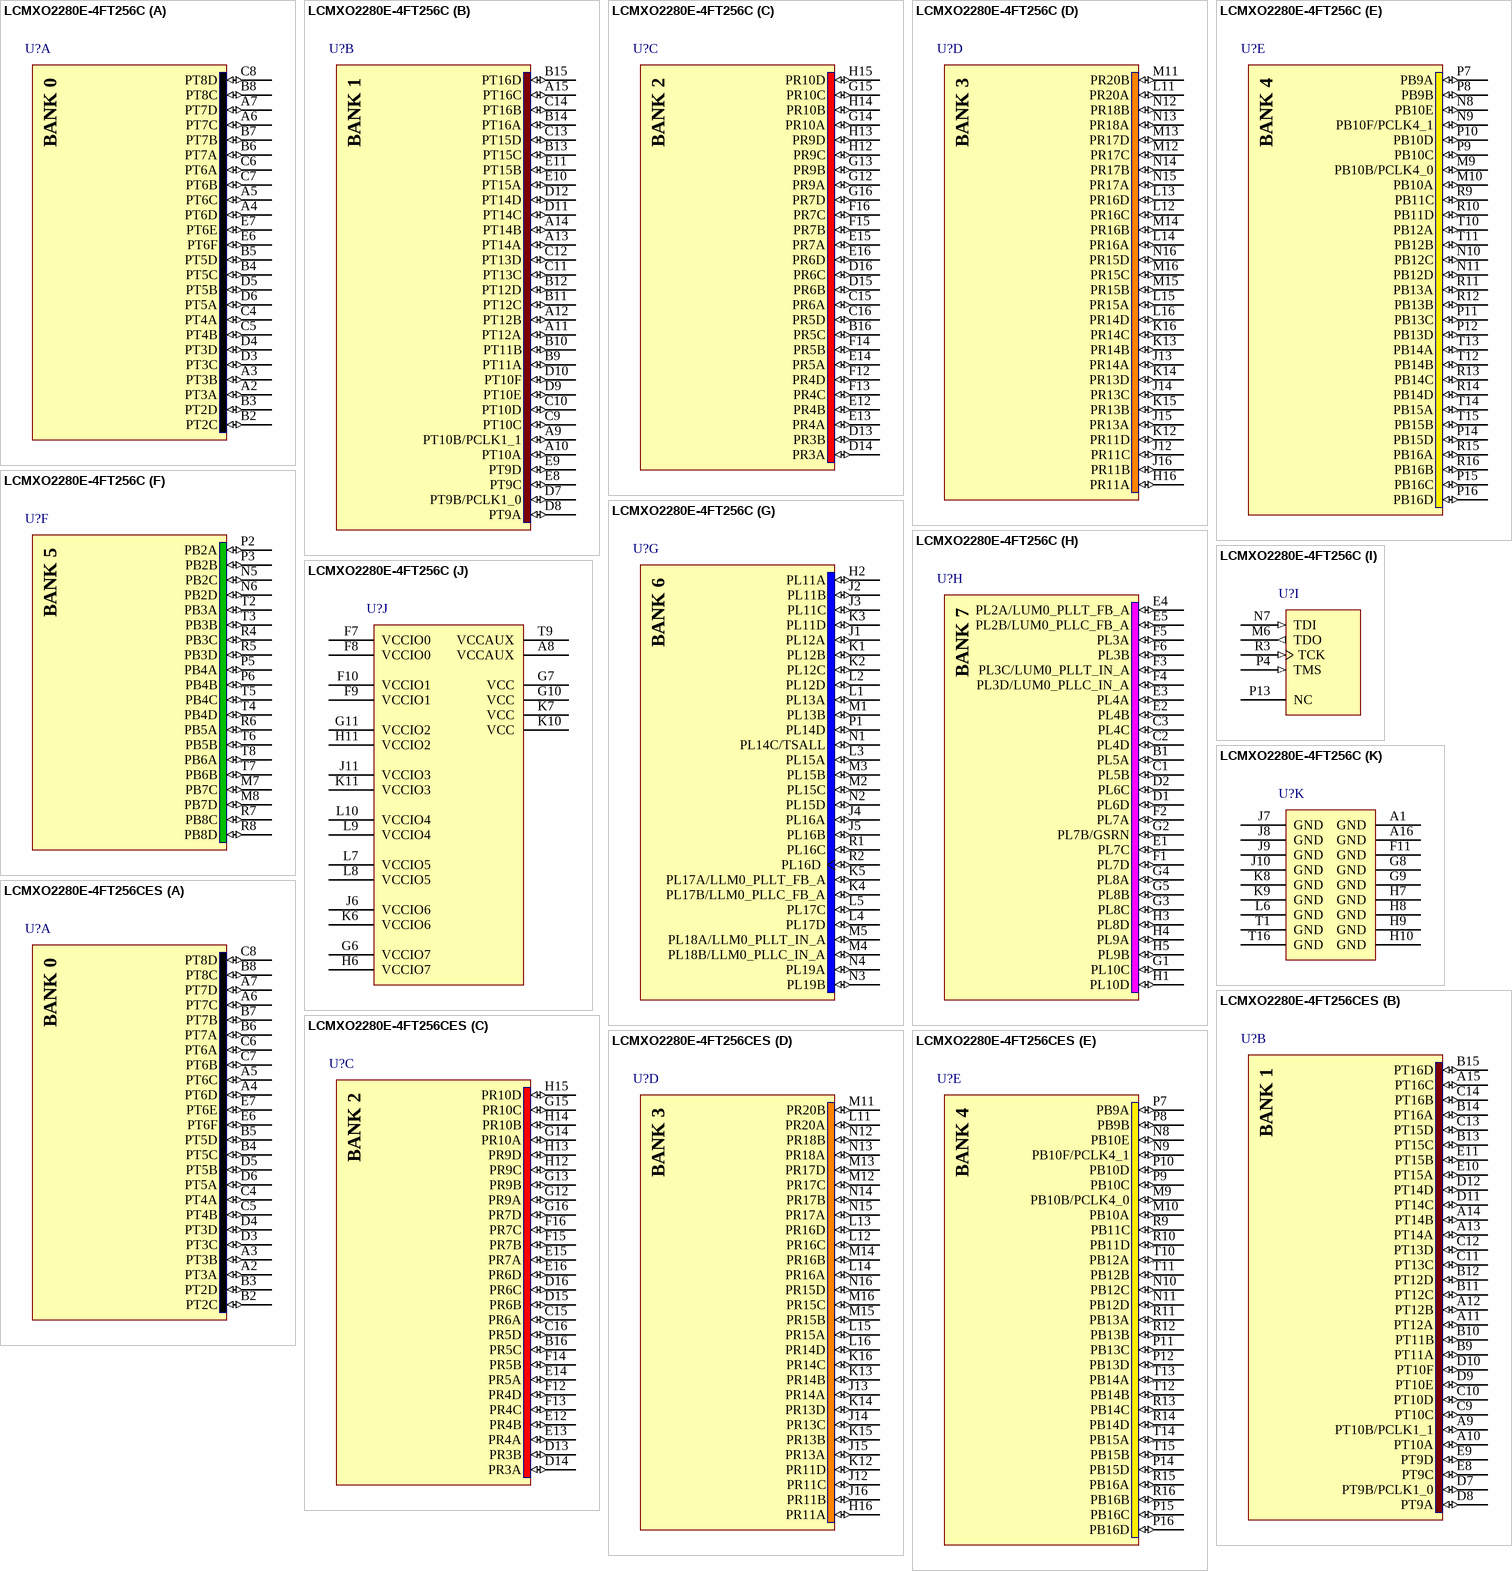
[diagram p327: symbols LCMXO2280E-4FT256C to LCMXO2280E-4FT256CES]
## LCMXO2280E-4FT256C
designator U?
MachXO 2280 Crossover PLD, 1.2V, 211 User I/Os, 256-Pins ftBGA, Speed Grade-4, Commercial Grade
footprint ftBGA256 (BGA, 256-Leads, Body 17x17mm, Pitch 1mm)
3D model MachXO2280-ftBGA256 (256-Ball Fine Thin Ball Grid Array (ftBGA256))
signal-integrity model LCMXO2280E_FT256 (MachXO)
part A pins: A2 PT3A (io), A3 PT3B (io), A4 PT6D (io), A5 PT6C (io), A6 PT7C (io), A7 PT7D (io), B2 PT2C (io), B3 PT2D (io), B4 PT5C (io), B5 PT5D (io), B6 PT7A (io), B7 PT7B (io), B8 PT8C (io), C4 PT4A (io), C5 PT4B (io), C6 PT6A (io), C7 PT6B (io), C8 PT8D (io), D3 PT3C (io), D4 PT3D (io), D5 PT5B (io), D6 PT5A (io), E6 PT6F (io), E7 PT6E (io)
part B pins: A9 PT10B/PCLK1_1 (io), A10 PT10A (io), A11 PT12A (io), A12 PT12B (io), A13 PT14A (io), A14 PT14B (io), A15 PT16C (io), B9 PT11A (io), B10 PT11B (io), B11 PT12C (io), B12 PT12D (io), B13 PT15C (io), B14 PT16A (io), B15 PT16D (io), C9 PT10C (io), C10 PT10D (io), C11 PT13C (io), C12 PT13D (io), C13 PT15D (io), C14 PT16B (io), D7 PT9B/PCLK1_0 (io), D8 PT9A (io), D9 PT10E (io), D10 PT10F (io), D11 PT14C (io), D12 PT14D (io), E8 PT9C (io), E9 PT9D (io), E10 PT15A (io), E11 PT15B (io)
part C pins: B16 PR5C (io), C15 PR6A (io), C16 PR5D (io), D13 PR3B (io), D14 PR3A (io), D15 PR6B (io), D16 PR6C (io), E12 PR4B (io), E13 PR4A (io), E14 PR5A (io), E15 PR7A (io), E16 PR6D (io), F12 PR4D (io), F13 PR4C (io), F14 PR5B (io), F15 PR7B (io), F16 PR7C (io), G12 PR9A (io), G13 PR9B (io), G14 PR10A (io), G15 PR10C (io), G16 PR7D (io), H12 PR9C (io), H13 PR9D (io), H14 PR10B (io), H15 PR10D (io)
part D pins: H16 PR11A (io), J12 PR11C (io), J13 PR14A (io), J14 PR13C (io), J15 PR13A (io), J16 PR11B (io), K12 PR11D (io), K13 PR14B (io), K14 PR13D (io), K15 PR13B (io), K16 PR14C (io), L11 PR20A (io), L12 PR16C (io), L13 PR16D (io), L14 PR16A (io), L15 PR15A (io), L16 PR14D (io), M11 PR20B (io), M12 PR17C (io), M13 PR17D (io), M14 PR16B (io), M15 PR15B (io), M16 PR15C (io), N12 PR18B (io), N13 PR18A (io), N14 PR17B (io), N15 PR17A (io), N16 PR15D (io)
part E pins: M9 PB10B/PCLK4_0 (io), M10 PB10A (io), N8 PB10E (io), N9 PB10F/PCLK4_1 (io), N10 PB12C (io), N11 PB12D (io), P7 PB9A (io), P8 PB9B (io), P9 PB10C (io), P10 PB10D (io), P11 PB13C (io), P12 PB13D (io), P14 PB15D (io), P15 PB16C (io), P16 PB16D (io), R9 PB11C (io), R10 PB11D (io), R11 PB13A (io), R12 PB13B (io), R13 PB14C (io), R14 PB14D (io), R15 PB16A (io), R16 PB16B (io), T10 PB12A (io), T11 PB12B (io), T12 PB14B (io), T13 PB14A (io), T14 PB15A (io), T15 PB15B (io)
part F pins: M7 PB7C (io), M8 PB7D (io), N5 PB2C (io), N6 PB2D (io), P2 PB2A (io), P3 PB2B (io), P5 PB4A (io), P6 PB4B (io), R4 PB3C (io), R5 PB3D (io), R6 PB5A (io), R7 PB8C (io), R8 PB8D (io), T2 PB3A (io), T3 PB3B (io), T4 PB4D (io), T5 PB4C (io), T6 PB5B (io), T7 PB6B (io), T8 PB6A (io)
part G pins: H2 PL11A (io), J1 PL12A (io), J2 PL11B (io), J3 PL11C (io), J4 PL16A (io), J5 PL16B (io), K1 PL12B (io), K2 PL12C (io), K3 PL11D (io), K4 PL17B/LLM0_PLLC_FB_A (io), K5 PL17A/LLM0_PLLT_FB_A (io), L1 PL13A (io), L2 PL12D (io), L3 PL15A (io), L4 PL17D (io), L5 PL17C (io), M1 PL13B (io), M2 PL15C (io), M3 PL15B (io), M4 PL18B/LLM0_PLLC_IN_A (io), M5 PL18A/LLM0_PLLT_IN_A (io), N1 PL14C/TSALL (io), N2 PL15D (io), N3 PL19B (io), N4 PL19A (io), P1 PL14D (io), R1 PL16C (io), R2 PL16D (io)
part H pins: B1 PL5A (io), C1 PL5B (io), C2 PL4D (io), C3 PL4C (io), D1 PL6D (io), D2 PL6C (io), E1 PL7C (io), E2 PL4B (io), E3 PL4A (io), E4 PL2A/LUM0_PLLT_FB_A (io), E5 PL2B/LUM0_PLLC_FB_A (io), F1 PL7D (io), F2 PL7A (io), F3 PL3C/LUM0_PLLT_IN_A (io), F4 PL3D/LUM0_PLLC_IN_A (io), F5 PL3A (io), F6 PL3B (io), G1 PL10C (io), G2 PL7B/GSRN (io), G3 PL8C (io), G4 PL8A (io), G5 PL8B (io), H1 PL10D (io), H3 PL8D (io), H4 PL9A (io), H5 PL9B (io)
part I pins: M6 TDO (out) "Powered by VCCIO5", N7 TDI (in) "Powered by VCCIO5", P4 TMS (in) "Powered by VCCIO5", P13 NC, R3 TCK (in) "Powered by VCCIO5"
part J pins: A8 VCCAUX (power), F7 VCCIO0 (power), F8 VCCIO0 (power), F9 VCCIO1 (power), F10 VCCIO1 (power), G6 VCCIO7 (power), G7 VCC (power), G10 VCC (power), G11 VCCIO2 (power), H6 VCCIO7 (power), H11 VCCIO2 (power), J6 VCCIO6 (power), J11 VCCIO3 (power), K6 VCCIO6 (power), K7 VCC (power), K10 VCC (power), K11 VCCIO3 (power), L7 VCCIO5 (power), L8 VCCIO5 (power), L9 VCCIO4 (power), L10 VCCIO4 (power), T9 VCCAUX (power)
part K pins: A1 GND (power), A16 GND (power), F11 GND (power), G8 GND (power), G9 GND (power), H7 GND (power), H8 GND (power), H9 GND (power), H10 GND (power), J7 GND (power), J8 GND (power), J9 GND (power), J10 GND (power), K8 GND (power), K9 GND (power), L6 GND (power), T1 GND (power), T16 GND (power)


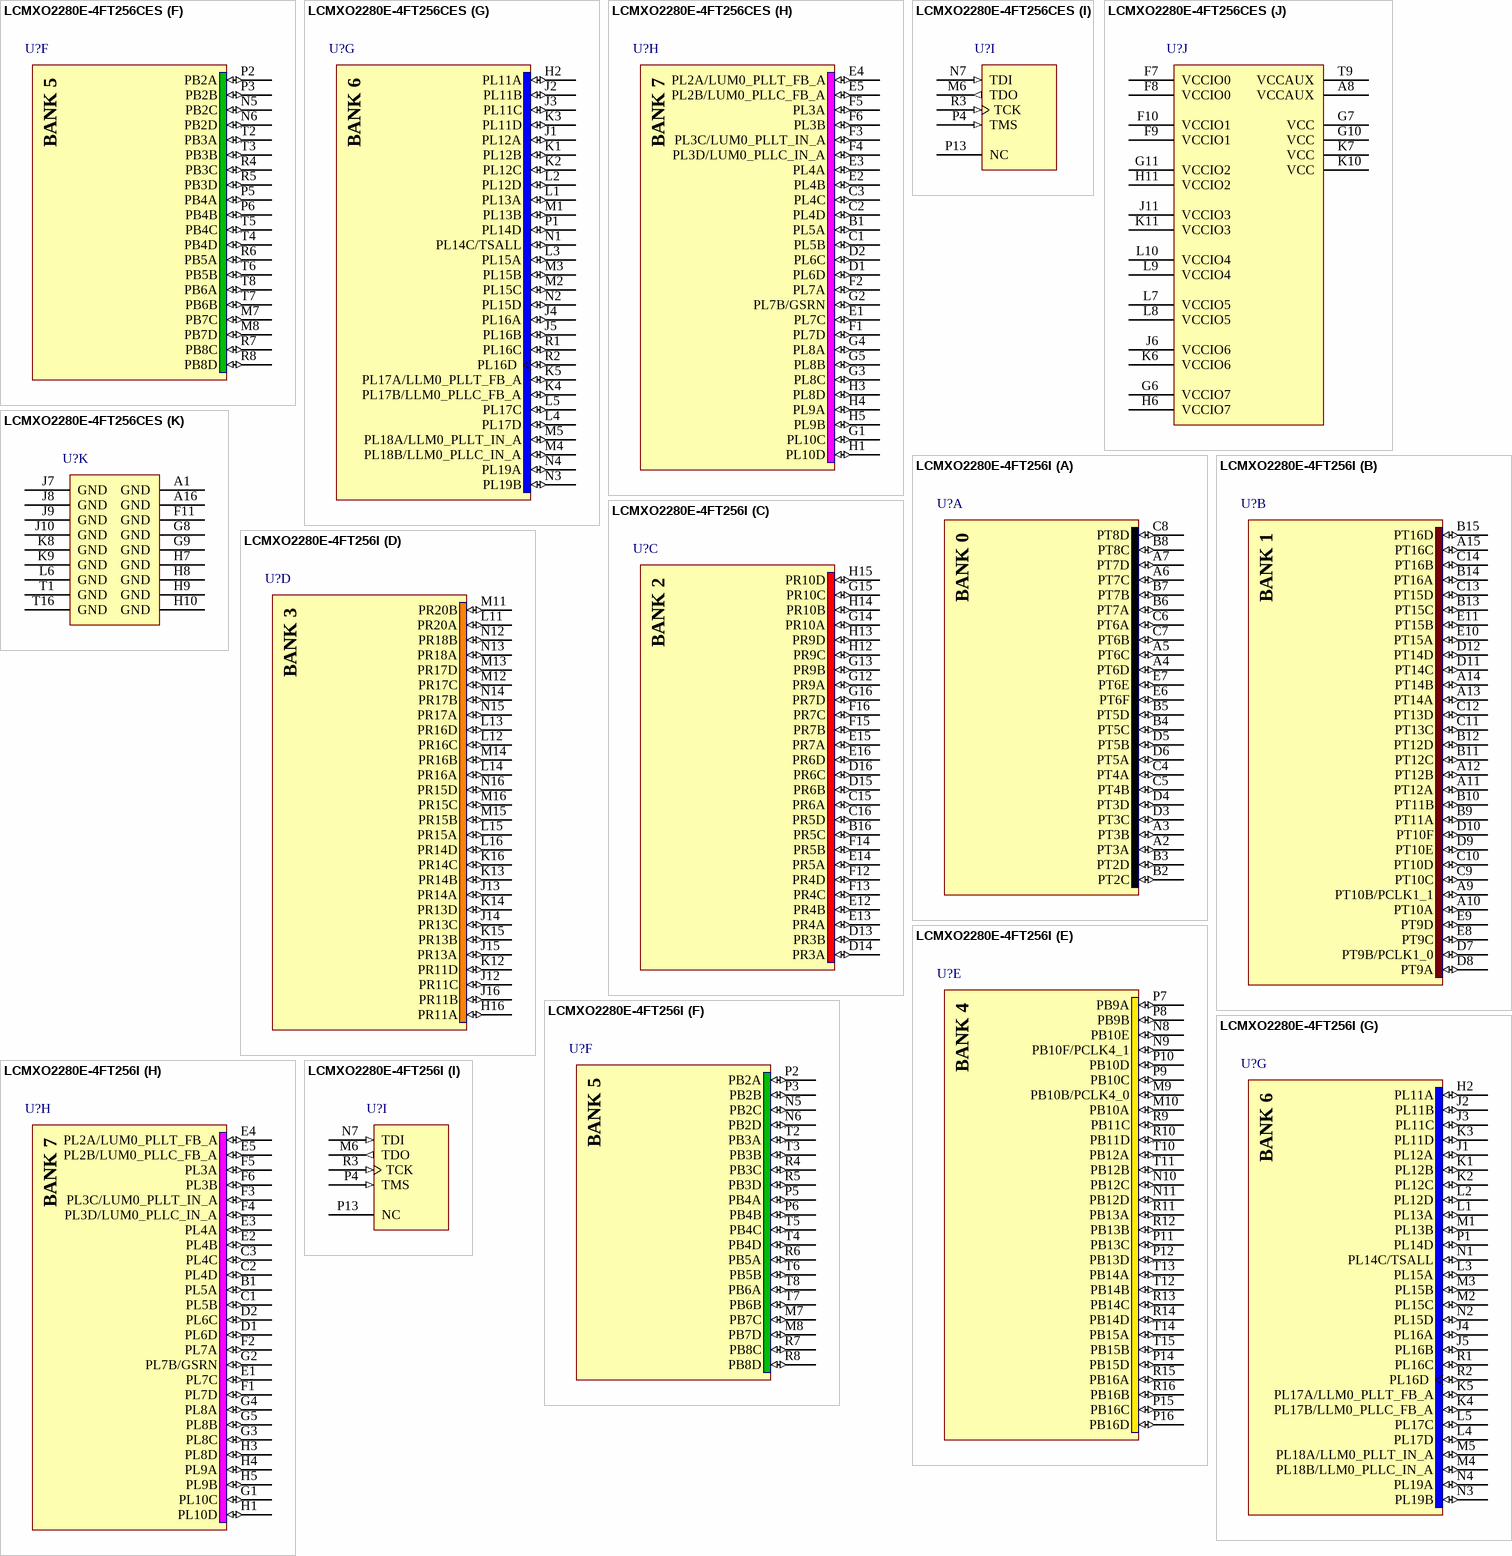
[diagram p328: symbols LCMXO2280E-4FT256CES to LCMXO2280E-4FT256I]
## LCMXO2280E-4FT256CES
designator U?
MachXO 2280 Crossover PLD, 1.2V, 211 User I/Os, 256-Pins ftBGA, Speed Grade-4, Commercial Grade, Engineering Sample
footprint ftBGA256 (BGA, 256-Leads, Body 17x17mm, Pitch 1mm)
3D model MachXO2280-ftBGA256 (256-Ball Fine Thin Ball Grid Array (ftBGA256))
signal-integrity model LCMXO2280E_FT256 (MachXO)
part A pins: A2 PT3A (io), A3 PT3B (io), A4 PT6D (io), A5 PT6C (io), A6 PT7C (io), A7 PT7D (io), B2 PT2C (io), B3 PT2D (io), B4 PT5C (io), B5 PT5D (io), B6 PT7A (io), B7 PT7B (io), B8 PT8C (io), C4 PT4A (io), C5 PT4B (io), C6 PT6A (io), C7 PT6B (io), C8 PT8D (io), D3 PT3C (io), D4 PT3D (io), D5 PT5B (io), D6 PT5A (io), E6 PT6F (io), E7 PT6E (io)
part B pins: A9 PT10B/PCLK1_1 (io), A10 PT10A (io), A11 PT12A (io), A12 PT12B (io), A13 PT14A (io), A14 PT14B (io), A15 PT16C (io), B9 PT11A (io), B10 PT11B (io), B11 PT12C (io), B12 PT12D (io), B13 PT15C (io), B14 PT16A (io), B15 PT16D (io), C9 PT10C (io), C10 PT10D (io), C11 PT13C (io), C12 PT13D (io), C13 PT15D (io), C14 PT16B (io), D7 PT9B/PCLK1_0 (io), D8 PT9A (io), D9 PT10E (io), D10 PT10F (io), D11 PT14C (io), D12 PT14D (io), E8 PT9C (io), E9 PT9D (io), E10 PT15A (io), E11 PT15B (io)
part C pins: B16 PR5C (io), C15 PR6A (io), C16 PR5D (io), D13 PR3B (io), D14 PR3A (io), D15 PR6B (io), D16 PR6C (io), E12 PR4B (io), E13 PR4A (io), E14 PR5A (io), E15 PR7A (io), E16 PR6D (io), F12 PR4D (io), F13 PR4C (io), F14 PR5B (io), F15 PR7B (io), F16 PR7C (io), G12 PR9A (io), G13 PR9B (io), G14 PR10A (io), G15 PR10C (io), G16 PR7D (io), H12 PR9C (io), H13 PR9D (io), H14 PR10B (io), H15 PR10D (io)
part D pins: H16 PR11A (io), J12 PR11C (io), J13 PR14A (io), J14 PR13C (io), J15 PR13A (io), J16 PR11B (io), K12 PR11D (io), K13 PR14B (io), K14 PR13D (io), K15 PR13B (io), K16 PR14C (io), L11 PR20A (io), L12 PR16C (io), L13 PR16D (io), L14 PR16A (io), L15 PR15A (io), L16 PR14D (io), M11 PR20B (io), M12 PR17C (io), M13 PR17D (io), M14 PR16B (io), M15 PR15B (io), M16 PR15C (io), N12 PR18B (io), N13 PR18A (io), N14 PR17B (io), N15 PR17A (io), N16 PR15D (io)
part E pins: M9 PB10B/PCLK4_0 (io), M10 PB10A (io), N8 PB10E (io), N9 PB10F/PCLK4_1 (io), N10 PB12C (io), N11 PB12D (io), P7 PB9A (io), P8 PB9B (io), P9 PB10C (io), P10 PB10D (io), P11 PB13C (io), P12 PB13D (io), P14 PB15D (io), P15 PB16C (io), P16 PB16D (io), R9 PB11C (io), R10 PB11D (io), R11 PB13A (io), R12 PB13B (io), R13 PB14C (io), R14 PB14D (io), R15 PB16A (io), R16 PB16B (io), T10 PB12A (io), T11 PB12B (io), T12 PB14B (io), T13 PB14A (io), T14 PB15A (io), T15 PB15B (io)
part F pins: M7 PB7C (io), M8 PB7D (io), N5 PB2C (io), N6 PB2D (io), P2 PB2A (io), P3 PB2B (io), P5 PB4A (io), P6 PB4B (io), R4 PB3C (io), R5 PB3D (io), R6 PB5A (io), R7 PB8C (io), R8 PB8D (io), T2 PB3A (io), T3 PB3B (io), T4 PB4D (io), T5 PB4C (io), T6 PB5B (io), T7 PB6B (io), T8 PB6A (io)
part G pins: H2 PL11A (io), J1 PL12A (io), J2 PL11B (io), J3 PL11C (io), J4 PL16A (io), J5 PL16B (io), K1 PL12B (io), K2 PL12C (io), K3 PL11D (io), K4 PL17B/LLM0_PLLC_FB_A (io), K5 PL17A/LLM0_PLLT_FB_A (io), L1 PL13A (io), L2 PL12D (io), L3 PL15A (io), L4 PL17D (io), L5 PL17C (io), M1 PL13B (io), M2 PL15C (io), M3 PL15B (io), M4 PL18B/LLM0_PLLC_IN_A (io), M5 PL18A/LLM0_PLLT_IN_A (io), N1 PL14C/TSALL (io), N2 PL15D (io), N3 PL19B (io), N4 PL19A (io), P1 PL14D (io), R1 PL16C (io), R2 PL16D (io)
part H pins: B1 PL5A (io), C1 PL5B (io), C2 PL4D (io), C3 PL4C (io), D1 PL6D (io), D2 PL6C (io), E1 PL7C (io), E2 PL4B (io), E3 PL4A (io), E4 PL2A/LUM0_PLLT_FB_A (io), E5 PL2B/LUM0_PLLC_FB_A (io), F1 PL7D (io), F2 PL7A (io), F3 PL3C/LUM0_PLLT_IN_A (io), F4 PL3D/LUM0_PLLC_IN_A (io), F5 PL3A (io), F6 PL3B (io), G1 PL10C (io), G2 PL7B/GSRN (io), G3 PL8C (io), G4 PL8A (io), G5 PL8B (io), H1 PL10D (io), H3 PL8D (io), H4 PL9A (io), H5 PL9B (io)
part I pins: M6 TDO (out) "Powered by VCCIO5", N7 TDI (in) "Powered by VCCIO5", P4 TMS (in) "Powered by VCCIO5", P13 NC, R3 TCK (in) "Powered by VCCIO5"
part J pins: A8 VCCAUX (power), F7 VCCIO0 (power), F8 VCCIO0 (power), F9 VCCIO1 (power), F10 VCCIO1 (power), G6 VCCIO7 (power), G7 VCC (power), G10 VCC (power), G11 VCCIO2 (power), H6 VCCIO7 (power), H11 VCCIO2 (power), J6 VCCIO6 (power), J11 VCCIO3 (power), K6 VCCIO6 (power), K7 VCC (power), K10 VCC (power), K11 VCCIO3 (power), L7 VCCIO5 (power), L8 VCCIO5 (power), L9 VCCIO4 (power), L10 VCCIO4 (power), T9 VCCAUX (power)
part K pins: A1 GND (power), A16 GND (power), F11 GND (power), G8 GND (power), G9 GND (power), H7 GND (power), H8 GND (power), H9 GND (power), H10 GND (power), J7 GND (power), J8 GND (power), J9 GND (power), J10 GND (power), K8 GND (power), K9 GND (power), L6 GND (power), T1 GND (power), T16 GND (power)


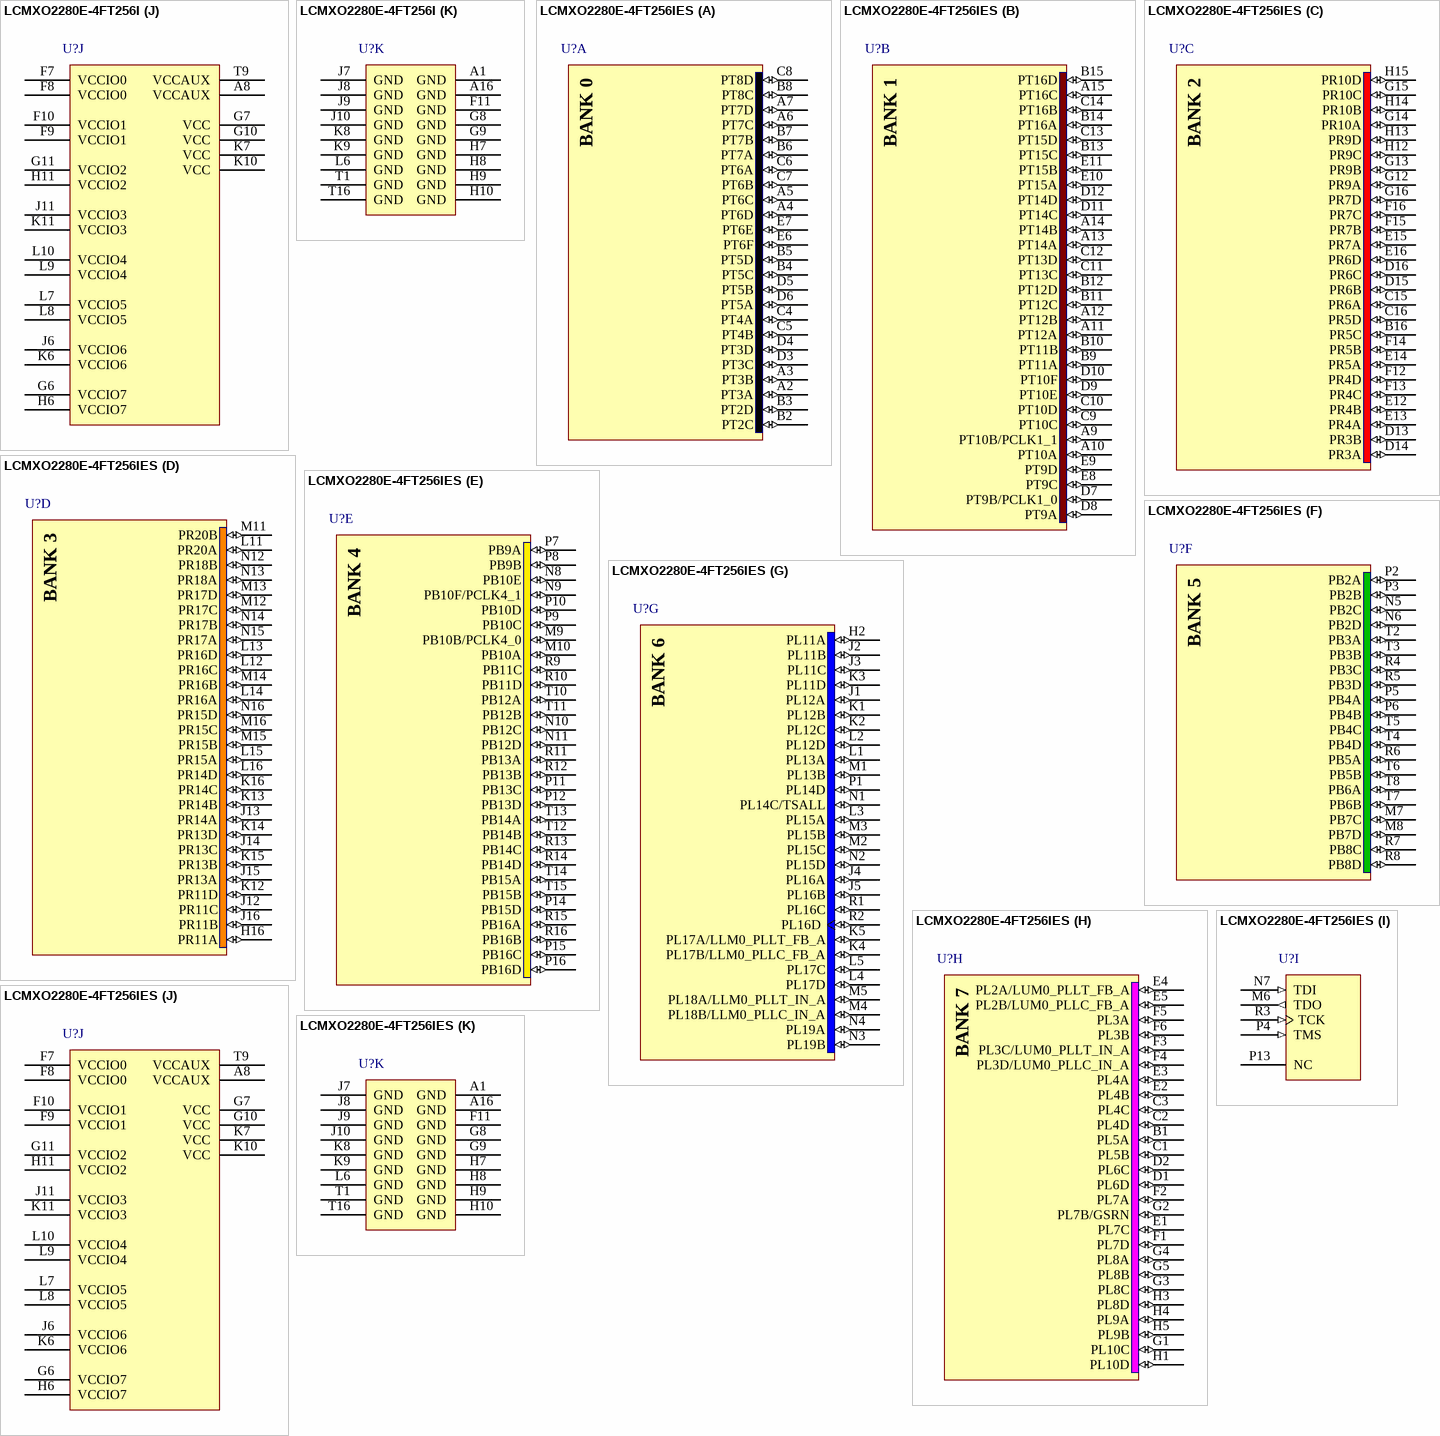
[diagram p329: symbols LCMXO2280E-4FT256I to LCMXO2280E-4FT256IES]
## LCMXO2280E-4FT256I
designator U?
MachXO 2280 Crossover PLD, 1.2V, 211 User I/Os, 256-Pins ftBGA, Speed Grade-4, Industrial Grade
footprint ftBGA256 (BGA, 256-Leads, Body 17x17mm, Pitch 1mm)
3D model MachXO2280-ftBGA256 (256-Ball Fine Thin Ball Grid Array (ftBGA256))
signal-integrity model LCMXO2280E_FT256 (MachXO)
part A pins: A2 PT3A (io), A3 PT3B (io), A4 PT6D (io), A5 PT6C (io), A6 PT7C (io), A7 PT7D (io), B2 PT2C (io), B3 PT2D (io), B4 PT5C (io), B5 PT5D (io), B6 PT7A (io), B7 PT7B (io), B8 PT8C (io), C4 PT4A (io), C5 PT4B (io), C6 PT6A (io), C7 PT6B (io), C8 PT8D (io), D3 PT3C (io), D4 PT3D (io), D5 PT5B (io), D6 PT5A (io), E6 PT6F (io), E7 PT6E (io)
part B pins: A9 PT10B/PCLK1_1 (io), A10 PT10A (io), A11 PT12A (io), A12 PT12B (io), A13 PT14A (io), A14 PT14B (io), A15 PT16C (io), B9 PT11A (io), B10 PT11B (io), B11 PT12C (io), B12 PT12D (io), B13 PT15C (io), B14 PT16A (io), B15 PT16D (io), C9 PT10C (io), C10 PT10D (io), C11 PT13C (io), C12 PT13D (io), C13 PT15D (io), C14 PT16B (io), D7 PT9B/PCLK1_0 (io), D8 PT9A (io), D9 PT10E (io), D10 PT10F (io), D11 PT14C (io), D12 PT14D (io), E8 PT9C (io), E9 PT9D (io), E10 PT15A (io), E11 PT15B (io)
part C pins: B16 PR5C (io), C15 PR6A (io), C16 PR5D (io), D13 PR3B (io), D14 PR3A (io), D15 PR6B (io), D16 PR6C (io), E12 PR4B (io), E13 PR4A (io), E14 PR5A (io), E15 PR7A (io), E16 PR6D (io), F12 PR4D (io), F13 PR4C (io), F14 PR5B (io), F15 PR7B (io), F16 PR7C (io), G12 PR9A (io), G13 PR9B (io), G14 PR10A (io), G15 PR10C (io), G16 PR7D (io), H12 PR9C (io), H13 PR9D (io), H14 PR10B (io), H15 PR10D (io)
part D pins: H16 PR11A (io), J12 PR11C (io), J13 PR14A (io), J14 PR13C (io), J15 PR13A (io), J16 PR11B (io), K12 PR11D (io), K13 PR14B (io), K14 PR13D (io), K15 PR13B (io), K16 PR14C (io), L11 PR20A (io), L12 PR16C (io), L13 PR16D (io), L14 PR16A (io), L15 PR15A (io), L16 PR14D (io), M11 PR20B (io), M12 PR17C (io), M13 PR17D (io), M14 PR16B (io), M15 PR15B (io), M16 PR15C (io), N12 PR18B (io), N13 PR18A (io), N14 PR17B (io), N15 PR17A (io), N16 PR15D (io)
part E pins: M9 PB10B/PCLK4_0 (io), M10 PB10A (io), N8 PB10E (io), N9 PB10F/PCLK4_1 (io), N10 PB12C (io), N11 PB12D (io), P7 PB9A (io), P8 PB9B (io), P9 PB10C (io), P10 PB10D (io), P11 PB13C (io), P12 PB13D (io), P14 PB15D (io), P15 PB16C (io), P16 PB16D (io), R9 PB11C (io), R10 PB11D (io), R11 PB13A (io), R12 PB13B (io), R13 PB14C (io), R14 PB14D (io), R15 PB16A (io), R16 PB16B (io), T10 PB12A (io), T11 PB12B (io), T12 PB14B (io), T13 PB14A (io), T14 PB15A (io), T15 PB15B (io)
part F pins: M7 PB7C (io), M8 PB7D (io), N5 PB2C (io), N6 PB2D (io), P2 PB2A (io), P3 PB2B (io), P5 PB4A (io), P6 PB4B (io), R4 PB3C (io), R5 PB3D (io), R6 PB5A (io), R7 PB8C (io), R8 PB8D (io), T2 PB3A (io), T3 PB3B (io), T4 PB4D (io), T5 PB4C (io), T6 PB5B (io), T7 PB6B (io), T8 PB6A (io)
part G pins: H2 PL11A (io), J1 PL12A (io), J2 PL11B (io), J3 PL11C (io), J4 PL16A (io), J5 PL16B (io), K1 PL12B (io), K2 PL12C (io), K3 PL11D (io), K4 PL17B/LLM0_PLLC_FB_A (io), K5 PL17A/LLM0_PLLT_FB_A (io), L1 PL13A (io), L2 PL12D (io), L3 PL15A (io), L4 PL17D (io), L5 PL17C (io), M1 PL13B (io), M2 PL15C (io), M3 PL15B (io), M4 PL18B/LLM0_PLLC_IN_A (io), M5 PL18A/LLM0_PLLT_IN_A (io), N1 PL14C/TSALL (io), N2 PL15D (io), N3 PL19B (io), N4 PL19A (io), P1 PL14D (io), R1 PL16C (io), R2 PL16D (io)
part H pins: B1 PL5A (io), C1 PL5B (io), C2 PL4D (io), C3 PL4C (io), D1 PL6D (io), D2 PL6C (io), E1 PL7C (io), E2 PL4B (io), E3 PL4A (io), E4 PL2A/LUM0_PLLT_FB_A (io), E5 PL2B/LUM0_PLLC_FB_A (io), F1 PL7D (io), F2 PL7A (io), F3 PL3C/LUM0_PLLT_IN_A (io), F4 PL3D/LUM0_PLLC_IN_A (io), F5 PL3A (io), F6 PL3B (io), G1 PL10C (io), G2 PL7B/GSRN (io), G3 PL8C (io), G4 PL8A (io), G5 PL8B (io), H1 PL10D (io), H3 PL8D (io), H4 PL9A (io), H5 PL9B (io)
part I pins: M6 TDO (out) "Powered by VCCIO5", N7 TDI (in) "Powered by VCCIO5", P4 TMS (in) "Powered by VCCIO5", P13 NC, R3 TCK (in) "Powered by VCCIO5"
part J pins: A8 VCCAUX (power), F7 VCCIO0 (power), F8 VCCIO0 (power), F9 VCCIO1 (power), F10 VCCIO1 (power), G6 VCCIO7 (power), G7 VCC (power), G10 VCC (power), G11 VCCIO2 (power), H6 VCCIO7 (power), H11 VCCIO2 (power), J6 VCCIO6 (power), J11 VCCIO3 (power), K6 VCCIO6 (power), K7 VCC (power), K10 VCC (power), K11 VCCIO3 (power), L7 VCCIO5 (power), L8 VCCIO5 (power), L9 VCCIO4 (power), L10 VCCIO4 (power), T9 VCCAUX (power)
part K pins: A1 GND (power), A16 GND (power), F11 GND (power), G8 GND (power), G9 GND (power), H7 GND (power), H8 GND (power), H9 GND (power), H10 GND (power), J7 GND (power), J8 GND (power), J9 GND (power), J10 GND (power), K8 GND (power), K9 GND (power), L6 GND (power), T1 GND (power), T16 GND (power)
